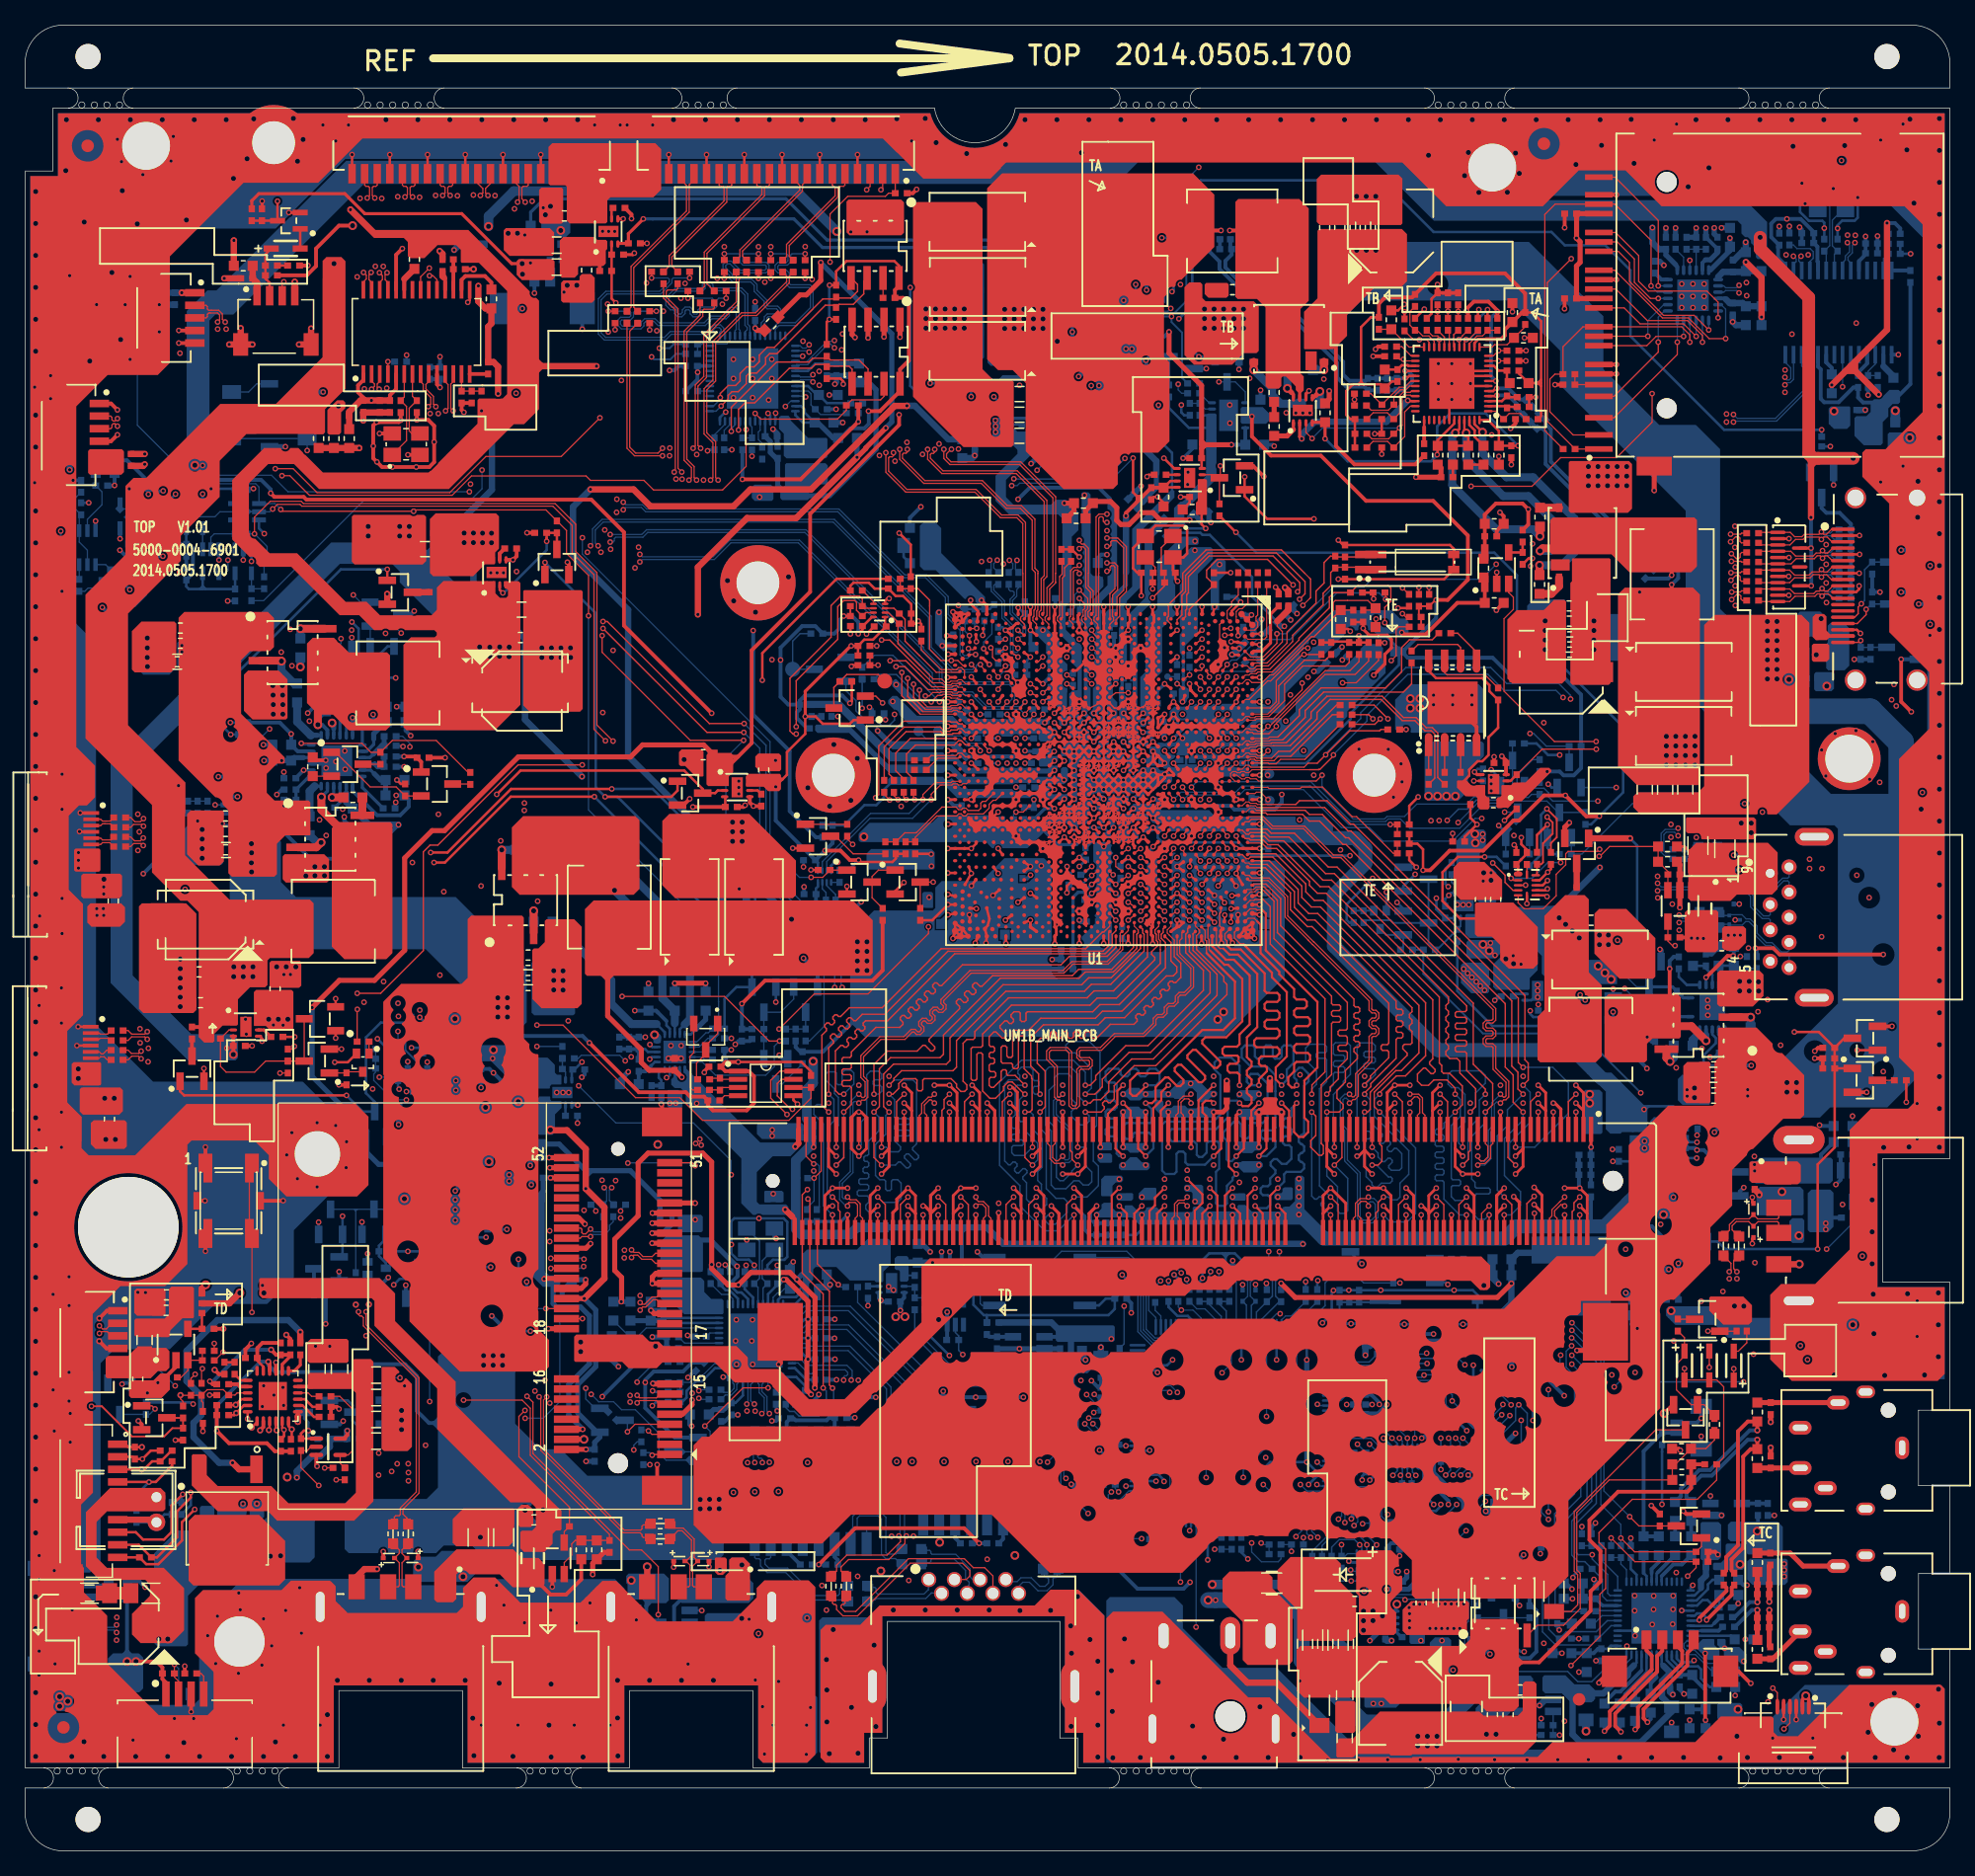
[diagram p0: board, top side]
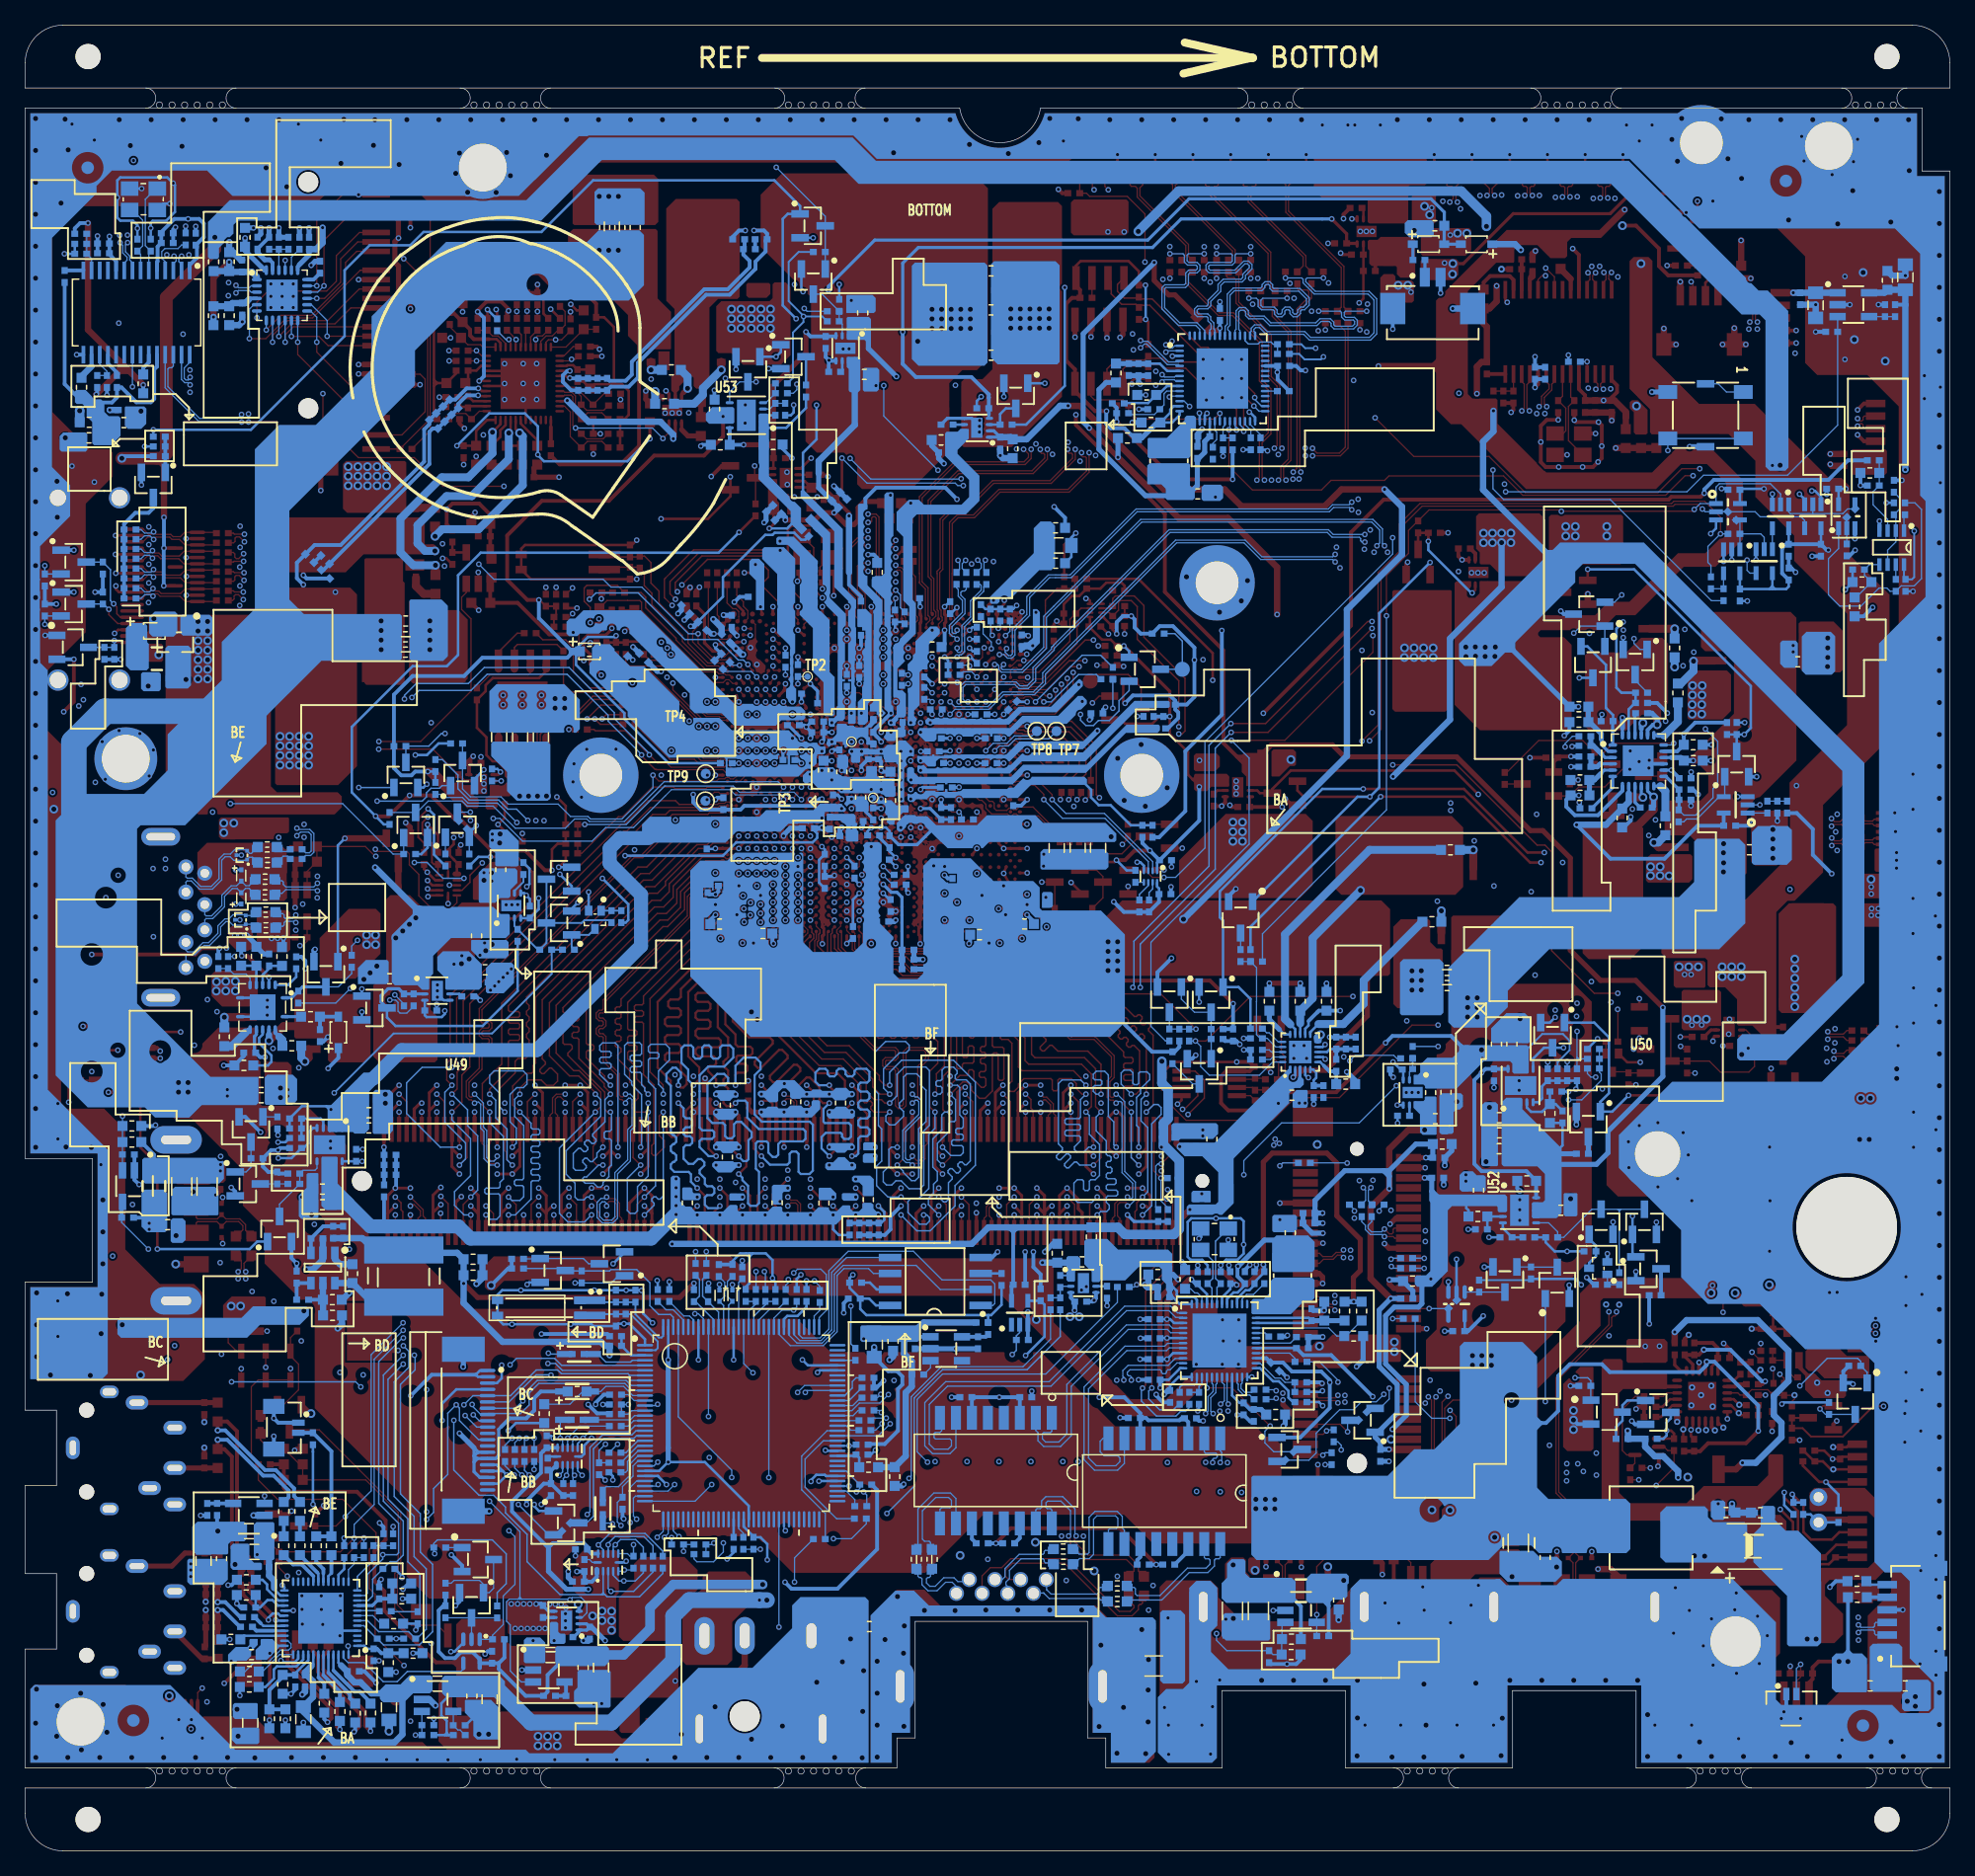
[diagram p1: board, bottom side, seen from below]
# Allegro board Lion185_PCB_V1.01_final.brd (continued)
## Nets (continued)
COMPA: U25.18(COMP)
CORE_PWROK: R387.2 U1.B7(PMC_CORE_PWROK)
CS_WAKE: R85.2 R326.1 R652.1 U1.L1(GPIO_S5_33) U27.4(A3)
CS_WAKE_EC: R652.2 U27.8(B3) U28.119(CRX0/GPC0)
DBG_UART3_RXD: Q103.2(S) U1.BC16(GPIO_S0_SC_61)
DBG_UART3_TXD: Q102.2(S) U1.BD14(GPIO_S0_SC_57)
DDI0_HPD: Q1.3(D) R12.1 U1.D27(DDI0_HPD)
DDI1_DATA: R13.2 R16.2 U1.P30(DDI1_DDCDATA)
DDI1_HPD: Q2.3(D) R11.1 U1.K30(DDI1_HPD)
DDR3_DRAM_PWROK: Q39.3(D) R439.2 R449.2 R450.2 U1.AD42(DRAM_VDD_S4_PWROK)
DDR3_VCCA_PWROK: Q47.3(D) R7.2 U1.AB42(DRAM_CORE_PWROK)
DDR3_VCCA_PWROK_3P3: Q46.1(G) R10.1 U40.4(Y)
DDR3L_DRAMRST#: CN3.30(RESET#) U1.P41(D\R\A\M\0\_\D\R\A\M\R\S\T\)
DDR3L_EVENT: R581.1 U28.68(ADC2/GPI2)
DDR3L_VREF: C1.1 R6.1 R9.2 U1.AF44(DRAM_VREF)
DDR_STBY: R384.2 R433.1 R434.1 R435.1 U43.17(S3)
DELAY_ALL_SYS_PWRGD: R8.2 R388.2 U37.4(Y) U39.1(A) U40.2(B)
DP_HPD: C617.2 CN18.1 Q2.1(G) R15.2 U10.11(HPD)
DRVH1: Q35.8 R429.1
DRVH2: Q34.8 R430.2
DRVL1: Q35.3 R432.1
DRVL2: Q34.3 R431.2
EC_BLEN: R749.1 U28.35(RTS1/GPE5)
EC_DELAY_ALL_SYS_PWRGD: R388.1 R713.1 U28.88(PS2DAT1/RTS0#/GPF3)
EC_MUTE#: R269.2 U24.1(A) U28.28(PWM2/GPA2)
EDID_SCL: R170.1 U10.29(DDC_SCL) U12.6(SCL)
EDID_SDA: R171.1 U10.30(DDC_SDA) U12.5(SDA)
EDP_AUXN: C523.2 C524.2 U1.AK2(DDI1_AUXN)
EDP_AUXN_CONN: C523.1 CN18.17 R615.2
EDP_AUXP: C525.2 C526.2 U1.AK3(DDI1_AUXP)
EDP_AUXP_CONN: C525.1 CN18.18 R162.2
EDP_BKLCTL: Q7.1(G) R178.1 U1.M30(DDI1_BKLTCTL)
EDP_BKLCTL_3P3: Q90.3(D) R152.1 R710.2 R751.2
EDP_BKLEN: Q16.1(G) R164.1 U1.J30(DDI1_BKLTEN)
EDP_BKLEN_3P3: Q17.3(D) R661.2 R748.1 U63.1(A)
EDP_BKLEN_OUT: R308.1 R639.2 R749.2 U63.4(Y)
EDP_TXN0: C138.1 C140.1 U1.AG1(DDI1_TXN_0)
EDP_TXN0_CONN: C138.2 CN18.5 R607.2
EDP_TXN1: C143.1 C144.1 U1.AF2(DDI1_TXN_1)
EDP_TXN1_CONN: C143.2 CN18.8 R609.2
EDP_TXN2: C155.2 U1.AD2(DDI1_TXN_2)
EDP_TXN2_CONN: C155.1 CN18.11 R611.2
EDP_TXN3: C520.2 U1.AC1(DDI1_TXN_3)
EDP_TXN3_CONN: C520.1 CN18.14 R613.2
EDP_TXP0: C141.1 C142.1 U1.AG3(DDI1_TXP_0)
EDP_TXP0_CONN: C141.2 CN18.6 R608.2
EDP_TXP1: C153.2 C154.2 U1.AF3(DDI1_TXP_1)
EDP_TXP1_CONN: C153.1 CN18.9 R610.2
EDP_TXP2: C157.2 U1.AD3(DDI1_TXP_2)
EDP_TXP2_CONN: C157.1 CN18.12 R612.2
EDP_TXP3: C522.2 U1.AC3(DDI1_TXP_3)
EDP_TXP3_CONN: C522.1 CN18.15 R614.2
EDP_VDDEN: R136.1 R137.1 U1.N30(DDI1_VDDEN) U8.3(ON)
EECS: R213.2 U17.30(EECS)
EEDI: R210.2 U17.32(EEDI)
EEDO: U17.31(LED3/EEDO)
EESK: U17.37(LED1/EESK)
EMC_THERM#: R132.1 U7.4(T\H\E\R\M\)
ENBLT: R639.1 U10.23(ENBLT)
ENLDO: Q98.2(S) R465.2 R491.1 R665.2 U42.13(EN0)
ENPVCC/I2C_ADDR: R184.1 U10.33(ENPVCC/I2C_ADDR)
ENSWREG: R214.2 R215.1 U17.33(ENSWREG)
ENTRIP1: Q42.2(S) R425.2 U42.1(ENTRIP1)
ENTRIP2: R426.1 U42.6(ENTRIP2)
EVDD10: C210.2 C211.1 R220.1 U17.21(EVDD10)
FAN_BACK: CN4.2 D3.P R134.2 R135.2
FAN_PWMIN: CN4.3 R320.1 U28.24(PWM0/GPA0)
FAN_VCC: C131.2 CN4.1 FB1.1
FLASH_TXE: Q100.1(G) R712.2
FMISO: U28.103(FMISO) U30.2(SO/SIO1)
FMOSI: U28.102(FMOSI) U30.5(SI/SIO0)
FSCE#: U28.101(FSCE#) U30.1(CS#)
FSCK: U28.105(FSCK) U30.6(SCLK)
GA20_EC: Q63.3(D) R81.2 R317.2 U28.126(GA20/GPB5)
GF_IMAX: R544.2 R551.1 U56.24(GF-IMAX)
GFX_PWM: U56.34(GPWM) U57.2(PWM)
GFX_PWRGD: R458.1 R531.2 U56.23(GPGOOD)
GL834L_3V3: C700.1 C701.1 C705.1 C710.2 FB4.1 FB20.2 R801.1 U95.1(DVDD) U95.19(DVDD33_1) U95.23(DVDD33)
GL850_AVDD: C573.2 C574.2 C575.2 C576.2 C577.2 C582.2 FB15.1 U77.1(AVDD) U77.5(AVDD_1) U77.10(AVDD_2)
GL850_AVDD1: C609.2 C610.2 C611.2 C612.2 C613.2 C614.2 FB18.1 U83.1(AVDD) U83.5(AVDD_1) U83.10(AVDD_2)
GL850G_RST#: C578.2 R692.2 R698.2 U77.13(RESET#)
GL850G_RST#_1: C606.2 R721.2 R735.2 U83.13(RESET#)
GL850G_X1: C579.2 U77.6(X1) X7.1
GL850G_X2: C580.2 U77.7(X2) X7.3
GPO: R226.2 U17.38(GPO/SMBALERT)
H_PROCHOT#: C294.1 Q62.2(S) R578.1 R580.2 U1.C24(P\R\O\C\H\O\T\) U29.4(Y)
H_RCIN#: D11.P R321.1 R653.2 U26.9(B2)
HD: R72.1 U3.7(NC(DQ3)) U75.7(RESET#/SIO3)
HDA_BITCLK: C257.2 R49.2 U23.6(BCLK)
HDA_RST#: R47.2 R272.1 R275.2 U23.11(RESETB)
HDA_SDATAIN0: C260.2 R262.2 U1.BG19(HDA_SDI0)
HDA_SDATAOUT: C261.2 R50.2 U23.5(SDATA-OUT)
HDA_SYNC: C259.2 R48.2 U23.10(SYNC)
HDMI_CTRLCLK: Q9.2(S) R202.2 U1.C28(DDI0_DDCCLK)
HDMI_CTRLDATA: Q10.2(S) R14.1 R203.2 U1.C26(DDI0_DDCDATA)
HDMI_HPD: C185.2 CN8.19 D6.3(D3) Q1.1(G) R199.2
HOME#: CN13.2 CN19.2 R437.2 U28.83(EGCS#/GPE2)
HP_OUT_L: C583.1 R241.1 R680.2 R711.1
HP_OUT_R: C584.1 R238.1 R699.2 R719.1
HSON: C208.2 U17.23(HSON)
HSOP: C209.2 U17.22(HSOP)
HUB2_USB_PN1: FIL12.4(GND) R381.1 U83.27(DM1)
HUB2_USB_PN2: U83.2(DM2) U95.2(DM)
HUB2_USB_PN3: CN22.2 U83.8(DM3)
HUB2_USB_PP1: FIL12.1(UNB) R568.1 U83.28(DP1)
HUB2_USB_PP2: U83.3(DP2) U95.3(DP)
HUB2_USB_PP3: CN22.3 U83.9(DP3)
HUB_USB_PN1: FIL14.4(GND) R564.1 U77.27(DM1)
HUB_USB_PN2: FIL13.2(DUMMY2) R382.1 U77.8(DM3)
HUB_USB_PN3: J3.2 U77.2(DM2)
HUB_USB_PN4: CN17.3 U77.11(DM4)
HUB_USB_PP1: FIL14.1(UNB) R566.1 U77.28(DP1)
HUB_USB_PP2: FIL13.3(DUMMY3) R575.1 U77.9(DP3)
HUB_USB_PP3: J3.3 U77.3(DP2)
HUB_USB_PP4: CN17.2 U77.12(DP4)
I2C_CLK0: R190.2 R299.2 U28.110(SMCLK0/GPB3)
I2C_CLK1: D27.N R296.2 U28.115(SMCLK1/GPC1)
I2C_CLK2: R302.2 R672.2 U28.117(SMCLK2/PECI/GPF6)
I2C_CLK2_LVDS: R187.2 R190.1 U10.25(CSCL/MSCL) U13.6(SCL)
I2C_CLK2_THEM: R672.1 U7.8(SMCLK)
I2C_DATA0: R191.2 R300.2 U28.111(SMDAT0/GPB4)
I2C_DATA1: D28.N R297.2 U28.116(SMDAT1/GPC2)
I2C_DATA2: R315.2 R673.2 U28.118(SMDAT2/PECIRQT#/GPF7)
I2C_DATA2_LVDS: R188.2 R191.1 U10.24(CSDA/MSDA) U13.5(SDA)
I2C_DATA2_THEM: R673.1 U7.7(SMDATA)
IINA0: J5.1 R342.1 R641.2 U25.22(ISEN1)
IINA1: J5.2 R342.2 R359.2 R643.2 U25.23(ISEN2)
IINA2: J5.3 R349.1 R359.1 U25.24(ISEN3)
IINA3: J5.4 R349.2 R355.2 U25.1(ISEN4)
IINA4: CN6.2 J5.7 R336.1 R355.1 U25.3(ISEN5)
IINA5: J5.8 R336.2 R350.2 U25.4(ISEN6)
IINA6: J5.9 R341.1 R350.1 R681.2 U25.5(ISEN7)
IINA7: J5.10 R341.2 R642.2 U25.6(ISEN8)
ISETA: R626.2 U25.8(ISET)
ISOLATEB: R217.1 R219.1 U17.26(ISOLATEB)
IT8928_VSS: R331.1 U28.104(DSR0#/GPG6/FIOO3)
KBC_FAN_SPEED: C130.2 Q5.3(OUT) R133.2 R323.1
L_OUT+: CN20.4(P4) R285.1
L_OUT-: CN20.3(P3) R286.1
LAN_CMT: R408.2 U61.11(CMT)
LAN_CMT1: R596.2 U62.11(CMT)
LAN_CT: R409.2 U61.14(CT3)
LAN_CT1: R577.2 U62.14(CT3)
LAN_N1: C271.1 C272.2 C338.2 C461.1 R408.1 R409.1 R577.1 R596.1
LAN_TX0N: FIL1.4(GND) R604.2 U61.9(TX-)
LAN_TX0P: FIL1.1(UNB) R603.2 U61.10(TX+)
LAN_TX1N: FIL2.1(UNB) R618.2 U61.15(RX-)
LAN_TX1P: FIL2.4(GND) R617.2 U61.16(RX+)
LAN_TX2N: FIL3.4(GND) R622.2 U62.9(TX-)
LAN_TX2P: FIL3.1(UNB) R620.2 U62.10(TX+)
LAN_TX3N: FIL4.1(UNB) R624.2 U62.15(RX-)
LAN_TX3P: FIL4.4(GND) R623.2 U62.16(RX+)
LAN_VDDEN_EC: R593.1 U28.29(PWM3/GPA3)
LAN_VDDEN_SOC: R208.1 U1.M2(GPIO_S5_36)
LANWAKEB: R216.1 U17.28(LANWAKEB)
LAO_CLKN: CN16.18 R615.1 U10.47(TCK0N)
LAO_CLKP: CN16.19 R162.1 U10.46(TCK0P)
LAO_DATAN0: CN16.6 R607.1 U10.54(TA0N)
LAO_DATAN1: CN16.9 R609.1 U10.52(TB0N)
LAO_DATAN2: CN16.12 R611.1 U10.49(TC0N)
LAO_DATAN3: CN16.15 R613.1 U10.44(TD0N)
LAO_DATAP0: CN16.7 R608.1 U10.53(TA0P)
LAO_DATAP1: CN16.10 R610.1 U10.51(TB0P)
LAO_DATAP2: CN16.13 R612.1 U10.48(TC0P)
LAO_DATAP3: CN16.16 R614.1 U10.43(TD0P)
LCD_VCC: C136.2 C137.1 C942.2 CN16.1 CN16.2 CN16.3 CN16.4 CN18.20 U8.7(VOUT2) U8.8(VOUT1)
LDO2-CAP: C246.2 U23.39(LDO2-CAP)
LED_ON: CN18.2 U28.34(PWM7/GPA7/RIG1)
LHF: CN13.4 R163.1
LL1: C369.2 L6.2 Q35.5 Q35.6 Q35.7 U42.20(LL1)
LL2: C370.1 L7.1 Q34.5 Q34.6 Q34.7 U42.11(LL2)
LPC_AD0: CN14.8 U1.BH16(ILB_LPC_AD_00) U28.10(LAD0/GPM0)
LPC_AD1: CN14.7 U1.BJ17(ILB_LPC_AD_11) U28.9(LAD1/GPM1)
LPC_AD2: CN14.6 U1.BJ13(ILB_LPC_AD_22) U28.8(LAD2/GPM2)
LPC_AD3: CN14.5 U1.BG14(ILB_LPC_AD_33) U28.7(LAD3/GPM3)
LPC_CLK_EC: CN14.10 R101.1 R102.1 U28.13(LPCCLK/GPM4)
LPC_CLKRUN#: R307.2 U1.BG16(I\L\B\_\L\P\C\_\C\L\K\R\U\N\)
LPC_FRAME#: CN14.9 U1.BG17(I\L\B\_\L\P\C\_\F\R\A\M\E\) U28.6(LFRAME#/GPM5)
LPC_SERIRQ: R648.1 U1.BG13(ILB_LPC_SERIRQ) U26.2(A1)
LPC_SERIRQ_EC: CN14.12 R648.2 U26.10(B1) U28.5(SERIRQ/GPM6)
LPCPD#: R656.2 U27.7(B4) U28.17(LPCPD#/GPE6)
M_A_A0: CN3.98(A0) U1.K45(DRAM0_MA_00)
M_A_A1: CN3.97(A1) U1.H47(DRAM0_MA_11)
M_A_A2: CN3.96(A2) U1.L41(DRAM0_MA_22)
M_A_A3: CN3.95(A3) U1.H44(DRAM0_MA_33)
M_A_A4: CN3.92(A4) U1.H50(DRAM0_MA_44)
M_A_A5: CN3.91(A5) U1.G53(DRAM0_MA_55)
M_A_A6: CN3.90(A6) U1.H49(DRAM0_MA_66)
M_A_A7: CN3.86(A7) U1.D50(DRAM0_MA_77)
M_A_A8: CN3.89(A8) U1.G52(DRAM0_MA_88)
M_A_A9: CN3.85(A9) U1.E52(DRAM0_MA_99)
M_A_A10: CN3.107(A10/AP) U1.K48(DRAM0_MA_1010)
M_A_A11: CN3.84(A11) U1.E51(DRAM0_MA_1111)
M_A_A12: CN3.83(A12/BC#) U1.F47(DRAM0_MA_1212)
M_A_A13: CN3.119(A13) U1.J51(DRAM0_MA_1313)
M_A_A14: CN3.80(A14) U1.B49(DRAM0_MA_1414)
M_A_A15: CN3.78(A15) U1.B50(DRAM0_MA_1515)
M_A_BS0: CN3.109(BA0) U1.K47(DRAM0_BS_00)
M_A_BS1: CN3.108(BA1) U1.K44(DRAM0_BS_11)
M_A_BS2: CN3.79(BA2) U1.D52(DRAM0_BS_22)
M_A_CAS#: CN3.115(CAS#) U1.M44(D\R\A\M\0\_\C\A\S\)
M_A_DM0: CN3.11(DM0) U1.G36(DRAM0_DM_00)
M_A_DM1: CN3.28(DM1) U1.B36(DRAM0_DM_11)
M_A_DM2: CN3.46(DM2) U1.F38(DRAM0_DM_22)
M_A_DM3: CN3.63(DM3) U1.B42(DRAM0_DM_33)
M_A_DM4: CN3.136(DM4) U1.P51(DRAM0_DM_44)
M_A_DM5: CN3.153(DM5) U1.V42(DRAM0_DM_55)
M_A_DM6: CN3.170(DM6) U1.Y50(DRAM0_DM_66)
M_A_DM7: CN3.187(DM7) U1.Y52(DRAM0_DM_77)
M_A_DQ0: CN3.5(DQ0) U1.M36(DRAM0_DQ_00)
M_A_DQ1: CN3.7(DQ1) U1.J36(DRAM0_DQ_11)
M_A_DQ2: CN3.15(DQ2) U1.P40(DRAM0_DQ_22)
M_A_DQ3: CN3.17(DQ3) U1.M40(DRAM0_DQ_33)
M_A_DQ4: CN3.4(DQ4) U1.P36(DRAM0_DQ_44)
M_A_DQ5: CN3.6(DQ5) U1.N36(DRAM0_DQ_55)
M_A_DQ6: CN3.16(DQ6) U1.K40(DRAM0_DQ_66)
M_A_DQ7: CN3.18(DQ7) U1.K42(DRAM0_DQ_77)
M_A_DQ8: CN3.21(DQ8) U1.B32(DRAM0_DQ_88)
M_A_DQ9: CN3.23(DQ9) U1.C32(DRAM0_DQ09_C32)
M_A_DQ10: CN3.33(DQ10) U1.C36(DRAM0_DQ_1010)
M_A_DQ11: CN3.35(DQ11) U1.A37(DRAM0_DQ_1111)
M_A_DQ12: CN3.22(DQ12) U1.C33(DRAM0_DQ_1212)
M_A_DQ13: CN3.24(DQ13) U1.A33(DRAM0_DQ_1313)
M_A_DQ14: CN3.34(DQ14) U1.C37(DRAM0_DQ_1414)
M_A_DQ15: CN3.36(DQ15) U1.B38(DRAM0_DQ_1515)
M_A_DQ16: CN3.39(DQ16) U1.F36(DRAM0_DQ_1616)
M_A_DQ17: CN3.41(DQ17) U1.G38(DRAM0_DQ_1717)
M_A_DQ18: CN3.51(DQ18) U1.F42(DRAM0_DQ_1818)
M_A_DQ19: CN3.53(DQ19) U1.J42(DRAM0_DQ_1919)
M_A_DQ20: CN3.40(DQ20) U1.G40(DRAM0_DQ_2020)
M_A_DQ21: CN3.42(DQ21) U1.C38(DRAM0_DQ_2121)
M_A_DQ22: CN3.50(DQ22) U1.G44(DRAM0_DQ_2222)
M_A_DQ23: CN3.52(DQ23) U1.D42(DRAM0_DQ_2323)
M_A_DQ24: CN3.57(DQ24) U1.A41(DRAM0_DQ_2424)
M_A_DQ25: CN3.59(DQ25) U1.C41(DRAM0_DQ_2525)
M_A_DQ26: CN3.67(DQ26) U1.A45(DRAM0_DQ_2626)
M_A_DQ27: CN3.69(DQ27) U1.B46(DRAM0_DQ_2727)
M_A_DQ28: CN3.56(DQ28) U1.C40(DRAM0_DQ_2828)
M_A_DQ29: CN3.58(DQ29) U1.B40(DRAM0_DQ_2929)
M_A_DQ30: CN3.68(DQ30) U1.B48(DRAM0_DQ_3030)
M_A_DQ31: CN3.70(DQ31) U1.B47(DRAM0_DQ_3131)
M_A_DQ32: CN3.129(DQ32) U1.K52(DRAM0_DQ_3232)
M_A_DQ33: CN3.131(DQ33) U1.K51(DRAM0_DQ_3333)
M_A_DQ34: CN3.141(DQ34) U1.T52(DRAM0_DQ_3434)
M_A_DQ35: CN3.143(DQ35) U1.T51(DRAM0_DQ_3535)
M_A_DQ36: CN3.130(DQ36) U1.L51(DRAM0_DQ_3636)
M_A_DQ37: CN3.132(DQ37) U1.L53(DRAM0_DQ_3737)
M_A_DQ38: CN3.140(DQ38) U1.R51(DRAM0_DQ_3838)
M_A_DQ39: CN3.142(DQ39) U1.R53(DRAM0_DQ_3939)
M_A_DQ40: CN3.147(DQ40) U1.T47(DRAM0_DQ_4040)
M_A_DQ41: CN3.149(DQ41) U1.T45(DRAM0_DQ_4141)
M_A_DQ42: CN3.157(DQ42) U1.Y40(DRAM0_DQ_4242)
M_A_DQ43: CN3.159(DQ43) U1.V41(DRAM0_DQ_4343)
M_A_DQ44: CN3.146(DQ44) U1.T48(DRAM0_DQ_4444)
M_A_DQ45: CN3.148(DQ45) U1.T50(DRAM0_DQ_4545)
M_A_DQ46: CN3.158(DQ46) U1.Y42(DRAM0_DQ_4646)
M_A_DQ47: CN3.160(DQ47) U1.AB40(DRAM0_DQ_4747)
M_A_DQ48: CN3.163(DQ48) U1.V45(DRAM0_DQ_4848)
M_A_DQ49: CN3.165(DQ49) U1.V47(DRAM0_DQ_4949)
M_A_DQ50: CN3.175(DQ50) U1.AD48(DRAM0_DQ_5050)
M_A_DQ51: CN3.177(DQ51) U1.AD50(DRAM0_DQ_5151)
M_A_DQ52: CN3.164(DQ52) U1.V48(DRAM0_DQ_5252)
M_A_DQ53: CN3.166(DQ53) U1.V50(DRAM0_DQ_5353)
M_A_DQ54: CN3.174(DQ54) U1.AB44(DRAM0_DQ_5454)
M_A_DQ55: CN3.176(DQ55) U1.Y45(DRAM0_DQ_5555)
M_A_DQ56: CN3.181(DQ56) U1.V52(DRAM0_DQ_5656)
M_A_DQ57: CN3.183(DQ57) U1.W51(DRAM0_DQ_5757)
M_A_DQ58: CN3.191(DQ58) U1.AC53(DRAM0_DQ_5858)
M_A_DQ59: CN3.193(DQ59) U1.AC51(DRAM0_DQ_5959)
M_A_DQ60: CN3.180(DQ60) U1.W53(DRAM0_DQ_6060)
M_A_DQ61: CN3.182(DQ61) U1.Y51(DRAM0_DQ_6161)
M_A_DQ62: CN3.192(DQ62) U1.AD52(DRAM0_DQ_6262)
M_A_DQ63: CN3.194(DQ63) U1.AD51(DRAM0_DQ_6363)
M_A_DQS0: CN3.12(DQS0) U1.J38(DRAM0_DQSP_00)
M_A_DQS1: CN3.29(DQS1) U1.C35(DRAM0_DQSP_11)
M_A_DQS2: CN3.47(DQS2) U1.D40(DRAM0_DQSP_22)
M_A_DQS3: CN3.64(DQS3) U1.B44(DRAM0_DQSP_33)
M_A_DQS4: CN3.137(DQS4) U1.N53(DRAM0_DQSP_44)
M_A_DQS5: CN3.154(DQS5) U1.T42(DRAM0_DQSP_55)
M_A_DQS6: CN3.171(DQS6) U1.Y47(DRAM0_DQSP_66)
M_A_DQS7: CN3.188(DQS7) U1.AB52(DRAM0_DQSP_77)
M_A_DQS#0: CN3.10(DQS#0) U1.K38(DRAM0_DQSN_00)
M_A_DQS#1: CN3.27(DQS#1) U1.B34(DRAM0_DQSN_11)
M_A_DQS#2: CN3.45(DQS#2) U1.F40(DRAM0_DQSN_22)
M_A_DQS#3: CN3.62(DQS#3) U1.C43(DRAM0_DQSN_33)
M_A_DQS#4: CN3.135(DQS#4) U1.M52(DRAM0_DQSN_44)
M_A_DQS#5: CN3.152(DQS#5) U1.T44(DRAM0_DQSN_55)
M_A_DQS#6: CN3.169(DQS#6) U1.Y48(DRAM0_DQSN_66)
M_A_DQS#7: CN3.186(DQS#7) U1.AA51(DRAM0_DQSN_77)
M_A_RAS#: CN3.110(RAS#) U1.M45(D\R\A\M\0\_\R\A\S\)
M_A_WE#: CN3.113(WE#) U1.H51(D\R\A\M\0\_\W\E\)
M_CKE0: CN3.73(CKE0) U1.C47(DRAM0_CKE_00)
M_CKE1: CN3.74(CKE1) U1.F44(DRAM0_CKE_22)
M_CLK_DDR0: CN3.101(CK0) U1.M50(DRAM0_CKP_0)
M_CLK_DDR1: CN3.102(CK1) U1.P50(DRAM0_CKP_2)
M_CLK_DDR#0: CN3.103(CK0#) U1.M48(DRAM0_CKN_0)
M_CLK_DDR#1: CN3.104(CK1#) U1.P48(DRAM0_CKN_2)
M_CS#0: CN3.114(S0#) U1.P44(D\R\A\M\0\_\C\S\_\0\)
M_CS#1: CN3.121(S1#) U1.P45(D\R\A\M\0\_\C\S\_\2\)
M_ODT0: CN3.116(ODT0) U1.T41(DRAM0_ODT_0)
M_ODT1: CN3.120(ODT1) U1.P42(DRAM0_ODT_2)
MDI0+: U17.1(MDIP0) U61.7(TD+)
MDI0-: U17.2(MDIN0) U61.8(TD-)
MDI1+: U17.4(MDIP1) U61.1(RD+)
MDI1-: U17.5(MDIN1) U61.2(RD-)
MDI2+: U17.7(MDIP2(NC)) U62.7(TD+)
MDI2-: U17.8(MDIN2(NC)) U62.8(TD-)
MDI3+: U17.10(MDIP3(NC)) U62.1(RD+)
MDI3-: U17.11(MDIN3(NC)) U62.2(RD-)
MDSI_DDCDATA: R31.1 R32.2 U1.A29(GPIO_S0_NC13)
MIC1L-VREFO: R246.2 U23.31(MIC1-VREFO-L)
MIC1R-VREFO: R244.2 U23.30(MIC1-VREFO-R)
MIC2-VREFO: R249.1 U23.29(MIC2-VREFO)
MIC_SEL_DET: J7.4 Q97.1(G) R256.1 R267.1 R322.2
MIC_SEL_SPDIF: Q97.3(D) R685.2 R717.2 U23.48(SPDIF-OUT/GPIO2)
MS_BS: CN30.M2(BS) U95.11(MS_BS)
MS_CLK: CN30.M8(SCLK) U95.6(SB0)
MS_D0: CN30.M4(DIO/D0) U95.9(SB4)
MS_D2: CN30.M5(DATA2) U95.8(SB3)
MS_D3: CN30.M7(DATA3) U95.7(SB1)
MS_INS: CN30.M6(INS) U95.5(MS_INS)
NFC_HRT: CN11.5 R20.2
OUT_CLK+: C181.2 CN8.10 R193.2 U14.10(D3+)
OUT_CLK-: C182.2 CN8.12 R192.2 U14.12(D3-)
OUT_D0+: C179.2 CN8.7 R195.2 U14.7(D2+)
OUT_D0-: C180.2 CN8.9 R194.2 U14.9(D2-)
OUT_D1+: C177.2 CN8.4 R197.2 U14.4(D1+)
OUT_D1-: C178.2 CN8.6 R196.2 U14.6(D1-)
OUT_D2+: C175.2 CN8.1 R200.2 U14.1(DO+)
OUT_D2-: C176.2 CN8.3 R198.2 U14.3(DO-)
OVPA: R351.2 R354.1 R619.2 R883.2 U25.7(OVP)
PCIE_LAN_WAKE#: R63.1 R216.2 U1.F26(P\M\C\_\W\A\K\E\_\P\C\I\E\_\0\)
PCIE_RXN0_LAN: C208.1 U1.AT13(PCIE_RXN_0)
PCIE_RXN1_WLAN: CN12.23(PER_N0) U1.AT9(PCIE_RXN_1)
PCIE_RXP0_LAN: C209.1 U1.AT14(PCIE_RXP_0)
PCIE_RXP1_WLAN: CN12.25(PER_P0) U1.AT10(PCIE_RXP_1)
PCIE_TXN0_LAN: C5.1 U17.18(HSIN)
PCIE_TXN1_WLAN: C3.1 CN12.31(PET_N0)
PCIE_TXP0_LAN: C4.1 U17.17(HSIP)
PCIE_TXP1_WLAN: C6.1 CN12.33(PET_P0)
PCIE_WIFI_WAKE#: R80.2 R636.1 U1.B16(GPIO_S5_1)
PD#: U23.47(PDB) U24.4(Y)
PERSTB: R218.1 U17.25(PERSTB)
PM_BATLOW#: R311.1 R335.1 R638.1 U1.K26(P\M\C\_\B\A\T\L\O\W\)
PM_RSMRST#: Q69.2(S) R67.1 R332.1 R714.2 U1.B10(P\M\C\_\R\S\M\R\S\T\)
PM_SLP_S0IX#: Q77.1(G) R329.1 R383.2 R385.2 R433.2 R502.2 U6.7(B4) U37.1(A) U38.2(B)
PM_SLP_S3#: Q48.1(G) R435.2 R497.2 R501.2 U6.9(B2) U28.70(ADC4/GPI4)
PM_SLP_S4#: Q38.1(G) R440.1 U6.8(B3) U28.69(ADC3/GPI3)
PMC_ACPRESENT: Q3.3(D) R83.2 U1.D20(PMC_ACPRESENT)
PMC_PLTRST: U1.F20(P\M\C\_\P\L\T\R\S\T\) U6.2(A1)
PMC_PWRBTN#: R654.1 R709.2 U1.J26(P\M\C\_\P\W\R\B\T\N\) U26.4(A3)
PMC_PWRBTN#_EC: R654.2 U26.8(B3) U28.18(RI1#/GPD0)
PMC_RSTBTN: R56.1 R57.1 R58.2 R653.1 U1.BG9(P\M\C\_\R\S\T\B\T\N\) U26.3(A2)
PMC_SLP_S0IX: U1.F18(P\M\C\_\S\L\P\_\S\0\I\X\) U6.5(A4)
PMC_SLP_S3: U1.D22(P\M\C\_\S\L\P\_\S\3\) U6.3(A2)
PMC_SLP_S4: U1.F22(P\M\C\_\S\L\P\_\S\4\) U6.4(A3)
PMC_SUS_STAT#: R656.1 U1.G18(P\M\C\_\S\U\S\_\S\T\A\T\) U27.5(A4)
PMC_SUSPWRDNACK: Q88.1(G) R76.1 R317.1 U1.D26(PMC_SUSPWRDNACK)
POWSW#: CN5.6 CN34.1 D33.N D34.N R903.1 SW4.3 SW4.4
PROCHOT#_EC: R340.2 R347.2 U28.76(TACH2/HDIO2/GPJ0) U29.2(A)
PS_LATCH#: D33.P Q78.1(G) R103.2 R898.1 R901.1
PSELF: R696.2 R697.1 U77.17(PSELF)
PSELF_1: R739.2 R740.1 U83.17(PSELF)
PSMS: R800.1 U95.20(GPIO0)
PWM IN: CN18.3 R165.1 R176.2 R182.1 R356.2 R751.1 U25.21(PWM)
PWR_LED_WHITE: CN5.4 CN34.3 U28.56(KSO16/SMOSI/GPC3)
PWR_SW: C704.1 C708.1 C709.1 CN30.M9(VCC) CN30.S4(VDD) U95.24(PMOS)
PWRONLATCHG: C585.1 C600.2 Q65.4(G) R103.1 R899.1 R901.2
R_OUT+: CN20.1(P1) R284.1
R_OUT-: CN20.2(P2) R283.1
REGOUT: L4.1 U17.36(REGOUT)
RESERVED_F1: U1.F1(RESERVED_F1)
REXT: R161.2 U10.26(REXT)
RLV_AMP: R159.2 U10.27(RLV_AMP)
RLV_CFG: R186.1 R189.2 U10.22(RLV_CFG)
RLV_LNK: R185.1 U10.21(RLV_LNK/GPIO0) U13.7(WP/WC#)
RSET: R209.2 U17.46(RSET)
RSMRST#_EC: Q69.3(D) R332.2 U28.19(L80HLAT/BAO/GPE0)
RSTZ: C707.1 R801.2 R802.2 U95.22(RSTZ)
RTA: R958.2 U25.9(RT)
RUNTIME_SCI#_EC: D10.P R319.1 R655.2 U26.7(B4)
S0IX#_DISCHARGE: Q76.1(G) Q77.3(D) Q80.1(G) R504.2
S3_DISCHARGE: C539.1 Q36.1(G) Q48.3(D) Q51.1(G) Q53.1(G) Q54.1(G) Q74.1(G) Q75.1(G) Q81.1(G) Q82.1(G) Q83.1(G) Q84.1(G) Q86.1(G) R562.1 R574.2
S4_DISCHARGE: Q38.3(D) Q39.1(G) Q61.1(G) R448.1 R451.2
SA0_DIM0: CN3.197(SA0) R121.1 R122.1
SA1_DIM0: CN3.201(SA1) R123.1
SATA_LED#: R36.1 U1.AY12(S\A\T\A\_\L\E\D\)
SATA_RXN0: R160.1 U1.AV16(SATA_RXN_0)
SATA_RXN1: C159.1 U1.BA16(SATA_RXN_1)
SATA_RXP0: R168.1 U1.AU16(SATA_RXP_0)
SATA_RXP1: C163.1 U1.AY16(SATA_RXP_1)
SATA_TXN0: C165.1 U1.BG7(SATA_TXN_0)
SATA_TXN1: C274.1 U1.BF10(SATA_TXN_1)
SATA_TXP0: C156.1 U1.BF6(SATA_TXP_0)
SATA_TXP1: C273.1 U1.BD10(SATA_TXP1)
SCL_CONN: CN8.15 Q9.3(D) R204.2
SD_CDZ: CN30.CD R803.2 U95.21(SD_CDZ)
SD_CLK: CN30.S5(CLK) U95.14(SD_CLK)
SD_CMD: CN30.S2(CMD) U95.15(SD_CMD)
SD_D0: CN30.S7(DAT0) U95.13(SB9)
SD_D1: CN30.S8(DAT1) U95.12(SB8)
SD_D2: CN30.S9(DAT2) U95.17(SB13)
SD_D3: CN30.S1(CD/DAT3) R803.1 U95.16(SB12)
SD_WP/MS_D1: CN30.M3(DATA1) CN30.WP1 R804.1 U95.10(SB5)
SDA_CONN: CN8.16 Q10.3(D) R205.2
SECURITY_FLASH: R52.1 R54.2 U1.BC30(LPE_I2S2_DATAOUT)
SEL: CN11.6 R18.2
SELA: R352.2 R353.2 U25.17(SEL)
SKIPSEL: R456.2 R486.2 U42.14(SKIPSEL)
SLEWA: R543.2 R550.1 U56.22(SLEWA)
SMB_CLK_S2: CN3.202(SCL) R280.2 R631.2 R632.2 U65.6(B2)
SMB_DATA_S2: CN3.200(SDA) R281.2 R630.2 R633.2 U65.7(B1)
SMBCLK: R632.1 U17.14(SMBCLK(NC))
SMBDATA: R223.1 R633.1 U17.15(SMBDATA(NC))
SMC_ONOFF#: D34.P R701.2 R704.2
SMC_SHUTDOWN#: Q89.1(G) R301.2 R900.2 U71.2(B)
SOC_EXTSMI#: R647.1 U1.C15(GPIO_S5_7) U27.2(A1)
SOC_EXTSMI#_EC: D9.P R318.1 R647.2 U27.10(B1)
SOC_FLASHEN: R79.1 R674.1 U5.3(ON)
SOC_ICS5_CLK_TOUCH: R684.2 U74.6(B2)
SOC_ICS5_DATA_TOUCH: R683.2 U74.7(B1)
SOC_RUNTIME_SCI: R655.1 U1.BA12(SATA_GP0) U26.5(A4)
SOC_SMB_CLK: R108.2 U1.BH10(PCU_SMB_CLK) U65.3(A2)
SOC_SMB_DATA: R106.2 U1.BG12(PCU_SMB_DATA) U65.2(A1)
SOC_WAKE_SCI: R314.1 R651.1 U1.B18(GPIO_S5_0) U27.3(A2)
SPI_CLK: R75.1 U3.6(CLK) U75.6(SCLK)
SPI_CS0#: R70.2 U3.1(CS#) U75.1(CS#)
SPI_SI: R74.2 U3.5(DI(DQ0)) U75.5(SI/SIO0)
SPI_SO: R73.1 U3.2(DO(DQ1)) U75.2(SO/SIO1)
SPK_L+: R285.2 U23.42(SPK-OUT-L+)
SPK_L-: R286.2 U23.43(SPK-OUT-L-)
SPK_R+: R284.2 U23.45(SPK-OUT-R+)
SPK_R-: R283.2 U23.44(SPK-OUT-R-)
SPKR: R600.2 U1.BH12(ILB_8254_SPKR)
SVID_ALERT#: R517.2 R523.1 R586.2
SVID_CLK: R518.2 R522.1 R588.2
SVID_DATA: R516.2 R525.1 R587.2
TBCLK: R310.2 U28.85(PS2CLK0/TMB0/GPF0/CEC)
TBDATA: R316.2 U28.86(PS2DAT0/TMB1/GPF1)
TEMP_ALERT#: R130.2 R337.1 U7.6(A\L\E\R\T\)
TLV3492_REF: R727.2 R728.1 U79.2(-INA) U79.6(-INB)
TMDS_CLKN: C182.1 U1.AP2(DDI0_TXN_3)
TMDS_CLKP: C181.1 U1.AP3(DDI0_TXP_3)
TMDS_DATAN0: C180.1 U1.AR1(DDI0_TXN_2)
TMDS_DATAN1: C178.1 U1.AT3(DDI0_TXN_1)
TMDS_DATAN2: C176.1 U1.AV2(DDI0_TXN_0)
TMDS_DATAP0: C179.1 U1.AR3(DDI0_TXP_2)
TMDS_DATAP1: C177.1 U1.AT2(DDI0_TXP_1)
TMDS_DATAP2: C175.1 U1.AV3(DDI0_TXP_0)
TONSEL: R427.2 R428.2 U42.4(TONSEL)
TOUCH_INT: R585.1 U1.AU32(SIO_PWM_00)
TOUCHEN_SOC: R149.1 U1.N3(GPIO_S5_37)
TP_EN_EC: R629.2 U28.57(KSO17/SMISO/GPC5)
TP_VCC: C301.1 C303.2 CN17.5 CN17.6 FB12.1 U9.1(VOUT)
TXN0_LVDS: C140.2 U10.5(DRX0N)
TXN1_LVDS: C144.2 U10.8(DRX1N)
TXP0_LVDS: C142.2 U10.4(DRX0P)
TXP1_LVDS: C154.1 U10.7(DRX1P)
USB3_PWRON: R366.2 U28.31(PWM5/GPA5) U31.4(EN)
USB3_RX0_N: FIL6.4(GND) R362.1 U1.E3(USB3_RXN0)
USB3_RX0_P: FIL6.1(UNB) R364.1 U1.D4(USB3_RXP0)
USB3_TX0_N: C314.2 U1.K7(USB3_TXN0)
USB3_TX0_P: C315.2 U1.K6(USB3_TXP0)
USB_BTN: CN12.36(USB_D-) R718.1
USB_BTP: CN12.38(USB_D+) R746.1
USB_NFCN: CN11.3 R745.1
USB_NFCP: CN11.2 R747.1
USB_OC0#: C313.1 R89.1 R363.1 R365.2 U1.C20(U\S\B\_\O\C\_\0\0\) U31.3(OCB)
USB_OC1#: R90.1 U1.B20(U\S\B\_\O\C\_\1\1\)
USB_OC1#_HUB: C318.1 R369.1 R370.2 U55.3(OCB) U77.21(OVCUR1#)
USB_OC1#_HUB 2: C330.1 R372.1 R374.2 U41.3(OCB) U83.21(OVCUR1#)
USB_OC2#_HUB: C325.1 R373.1 R379.2 U59.3(OCB) U77.19(OVCUR2#)
USB_P1ON: R371.2 R592.2 U55.4(EN)
USB_P2ON: R380.2 R606.2 U59.4(EN)
USB_P3ON: R375.2 R591.2 U41.4(EN)
USB_PLL_MON: R93.2 TP2.1 U1.M13(USB_PLL_MON)
USB_PN0: FIL5.1(UNB) R360.1 U1.K16(USB_DN0)
USB_PN1: R718.2 R745.2 U1.G14(USB_DN1)
USB_PN2: U1.J12(USB_DN2) U77.25(DM0)
USB_PN3: U1.H10(USB_DN3) U83.25(DM0)
USB_PP0: FIL5.4(GND) R361.1 U1.M16(USB_DP0)
USB_PP1: R746.2 R747.2 U1.J14(USB_DP1)
USB_PP2: U1.K12(USB_DP2) U77.26(DP0)
USB_PP3: U1.K10(USB_DP3) U83.26(DP0)
V_DAC: C494.2 C495.2 C496.2 C527.2 U61.3(CT1) U61.6(CT2) U62.3(CT1) U62.6(CT2)
VCLK: C377.1 C378.1 U42.18(VCLK)
VCORE_CIMON: C448.1 R505.1 U56.3(CIMON)
VCORE_COMP: C449.1 R507.2 U56.10(CCOMP)
VCORE_CSP1: C462.2 C463.1 C464.1 R511.2 R512.2 R515.2 U56.4(CCSP1)
VCORE_GIMON: C475.1 R534.1 U56.30(GIMON)
VCORE_GSNS: R509.1 U1.N28(CORE_VSS_SENSE_N28) U56.12(CGFB)
VCORE_OCP_I: R505.2 R506.1 U56.2(COCP-I)
VCORE_PWRGD: R493.1 R537.1 U56.17(CPGOOD)
VCORE_SKIP#: R548.2 R555.1 U56.35(CSKIP#)
VCORE_THERM: R545.2 R552.2 U56.1(CTHERM)
VCORE_VRON: C596.2 R450.1 R497.1 U56.16(VR_ON)
VCORE_VSNS: R508.1 U1.P28(CORE_VCC_SENSE_P28) U56.11(CVFB)
VFB1: R421.1 R423.2 U42.2(VFB1)
VFB2: R422.1 R424.1 U42.5(VFB2)
VGFX_COMP: C474.2 R533.1 U56.27(GCOMP)
VGFX_CSP: C476.1 C477.2 C478.1 R532.2 R535.2 R536.2 U56.29(GCSP)
VGFX_GSNS: R529.2 U56.25(GGFB)
VGFX_OCP_I: R534.2 R538.1 U56.31(GOCP-I)
VGFX_SKIP#: R547.2 R554.1 U56.33(GSKIP#_1) U57.3(SKIP#)
VGFX_THERM: R546.2 R553.2 U56.32(GTHERM)
VGFX_VSNS: R530.1 U1.BB8(UNCORE_VNN_SENSE) U56.26(GVFB)
VR_ALW_EN: Q85.1(G) R665.1 U71.4(Y)
VR_HOT#: Q62.3(D) R528.2 R578.2 U56.21(VR_HOT#)
VREF: C442.2 R486.1 U42.3(VREF)
VREF_CA0: C106.2 C107.2 CN3.126(VREF_CA) R125.1 R126.2
VREF_DQ0: C103.2 C104.2 CN3.1(VREF_DQ) R120.1 R124.2
VREFA: C992.2 R353.1 R616.2 U25.14(VREF)
VREG3: C368.2 C540.1 R427.1 U42.8(VREG3) U71.5(VCC)
VREG5: C375.1 C380.1 D24.1(X1) R428.1 R456.1 R662.2 U42.17(VREG5)
VSM_VTT_PWRGD: R439.1 R510.2 U43.20(PGOOD)
VSPI_KBC: C293.1 R334.1 R339.1 R345.2 R346.2 R658.1 U30.8(VCC)
VTT_PWRGD: R716.2 U79.1(OUTA)
WAKE_SCI_EC: R324.1 R651.2 U27.9(B2)
WIFI_3P3_RST#: Q67.3(D) R637.2 U58.1(A)
WIFI_PCIE_RST: Q68.1(G) R62.1 U1.J20(GPIO_S514_J20)
WIFI_PERST#: CN12.22(PERST#) R589.1 U58.4(Y)
WIFI_PWRON: R599.2 U28.112(RING#/PWRFAIL#/CK32KOUT/LPCRST#)
WIFI_VDDEN_SOC: R598.1 U1.P3(GPIO_S5_41)
WIRELESS_ON: R279.2 U28.33(GINT/CTS0#/GPD5)
WP2: CN30.WP2 R804.2 R805.2
WP#: R71.1 U3.3(WP#(DQ2)) U75.3(WP#/SIO2)
WRST#: C288.2 R333.1 SW1.3 SW1.4 SW2.1 SW2.3 U28.14(WRST#)
X1: C616.2 U83.6(X1) X8.1
X2: C615.2 U83.7(X2) X8.3
XTAL1: C187.1 U17.43(CKXTAL1) X4.1
XTAL2: C186.1 U17.44(CKXTAL2) X4.3
XTAL25M_IN: C8.2 R59.1 U1.AH12(ICLK_OSCIN) X1.1
XTAL25M_OUT: C7.2 R59.2 U1.AH10(ICLK_OSCOUT) X1.3
N320321985: CN12.7(CLKREQ#) Q66.3(D) R635.2
N320322150: CN12.20(W_DISABLE#) R279.1
N320322222: CN12.30(SMB_CLK) R280.1
N320322224: CN12.32(SMB_DATA) R281.1
N322237366: CN12.51(RSVD12) R282.2
N332287606: Q64.3(D) R634.2 U17.16(CLKREQB)
N332918772: CN12.5(RSVD2) R278.2
N333289105: Q40.8 R463.2
N333289487: C404.2 D26.N R459.2
N333289642: Q40.3 R467.2
N333289792: Q49.3(D) R457.2 R733.2 U47.1(EN_PSV)
N333289805: C404.1 L9.1 Q40.5 Q40.6 Q40.7 R460.2 U47.12(LL)
N333289822: R467.1 U47.9(DRVL)
N333289926: R468.1 R470.2 U47.5(VFB)
N333289950: R460.1 U47.2(TON)
N333290075: R463.1 U47.13(DRVH)
N333290111: R464.1 U47.11(TRIP)
N333290147: R462.1 R466.2 U47.6(PGOOD)
N339398220: R312.1 U28.22(LPCRST#/GPD2)
N339398632: D10.N R319.2 U28.23(ECSCI#/GPD3)
N339398739: D11.N R321.2 U28.4(KBRST#/GPB6)
N339399039: R337.2 U28.67(ADC1/GPI1)
N339399233: D7.N R304.1 R700.1 U28.11(VCC)
N339399553: C291.1 R344.1 U28.2(CK32KE/GPJ7) X5.2 X6.4
N339399628: R292.1 U28.122(VSS6)
N339399677: R325.1 U28.48(TACH1A/TMA1/GPD7)
N339399812: R346.1 U30.3(WP#/ACC)
N339399833: R345.1 U30.7(HOLD#)
N339399994: R323.2 U28.47(TACH0A/GPD6)
N339400152: R324.2 U28.16(PWUREQ#/GPC7/BBO)
N339400173: D9.N R318.2 U28.15(ECSMI#/GPD4)
N339400590: R301.1 U28.82(EGAD/GPE1)
N339579908: Q8.1(G) R201.2 R501.1 R502.1
N342323491: C314.1 FIL7.4(GND) R367.1
N342323527: FIL6.2(DUMMY2) J2.6(STDA_SSRX+) R364.2 U32.2(D-)
N342323548: FIL7.2(DUMMY2) J2.9(STDA_SSTX+) R368.2 U33.2(D-)
N342323565: D12.N FIL5.2(DUMMY2) J2.2(D_MINUS) R360.2
N342323571: FIL6.3(DUMMY3) J2.5(STDA_SSRX-) R362.2 U32.1(D+)
N342323607: C315.1 FIL7.1(UNB) R368.1
N342323609: D13.N FIL5.3(DUMMY3) J2.3(D_PLUS) R361.2
N342323907: FIL7.3(DUMMY3) J2.8(STDA_SSTX-) R367.2 U33.1(D+)
N344053358: R307.1 U28.93(CLKRUN#/GPH0/ID0)
N347061519: C289.1 R343.2 R344.2 U28.128(CK32K/GPJ6) X5.1 X6.1
N350298939: R441.1 U43.14(DRVH)
N350298979: R443.1 U43.11(DRVL)
N350299117: R436.1 U43.19(MODE)
N350299126: C393.1 R444.1 U43.5(VTTREF)
N350299527: R442.2 U43.15(VBST)
N350299529: C394.2 R445.1 R446.2 R447.2 U43.8(REFIN)
N350299649: R440.2 U43.16(S5)
N350299667: C386.2 R442.1
N350299694: C386.1 L8.1 Q37.5 Q37.6 Q37.7 U43.13(SW)
N350299721: C392.2 R445.2 U43.6(VREF)
N350299729: R438.2 U43.18(TRIP)
N350299756: Q36.3(D) R434.2
N350945194: Q8.3(D) R192.1 R193.1 R194.1 R195.1 R196.1 R197.1 R198.1 R200.1
N369066236: R701.1 R702.1 U28.107(DTR1#/SBUSY/GPG1/ID7/FDIO2)
N369071729: R322.1 U28.98(HMISO/GPH5/ID5)
N370323697: R1.2 U1.AH42(ICLK_DRAM_TERMN)
N370323746: R2.2 U1.AF42(ICLK_DRAM_TERMN_AF42)
N370323875: R4.1 U1.AD44(DRAM_RCOMP_00)
N370323891: R3.1 U1.AF45(DRAM_RCOMP_11)
N370323945: R5.1 U1.AD45(DRAM_RCOMP_22)
N370344518: R23.1 U1.AH3(VSS_AH3)
N370344521: R25.1 U1.AH2(VSS_AH2)
N370344943: R26.1 U1.AW1(VGA_IREF)
N370350025: R19.2 U1.AK12(DDI0_RCOMP_P)
N370350028: R19.1 U1.AK13(D\D\I\0\_\R\C\O\M\P\)
N370350254: R22.2 U1.AM3(VSS_AM3)
N370350257: R24.2 U1.AM2(VSS_AM2)
N370394982: R33.2 U1.BB10(ICLK_SATA_TERMP)
N370394985: R35.2 U1.BC10(ICLK_SATA_TERMN)
N370395195: R37.2 U1.AT18(SATA_RCOMP_N_AT18)
N370395197: R37.1 U1.AU18(SATA_RCOMP_P_AU18)
N370395763: R45.1 U1.AY18(MMC1_RCOMP)
N370395851: R55.1 U1.BF26(SD3_RCOMP)
N370396853: R46.2 U1.BF20(HDA_LPE_RCOMP)
N370397174: R47.1 U1.BG22(H\D\A\_\R\S\T\)
N370397581: Q13.3(D) R270.2 R272.2 U24.2(B)
N370397628: Q14.1(G) R275.1
N370397693: Q13.1(G) Q14.3(D) R271.2
N370398430: R48.1 U1.BH20(HDA_SYNC)
N370398495: R49.1 U1.BJ21(HDA_CLK)
N370398555: R50.1 U1.BG20(HDA_SDO)
N370398936: R44.2 U1.AP14(PCIE_RCOMP_P_AP14_AP14)
N370398938: R44.1 U1.AP13(PCIE_RCOMP_N_AP13_AP13)
N370399144: C4.2 U1.AY7(PCIE_TXP_0)
N370399202: C6.2 U1.AV6(PCIE_TXP_1)
N370399343: C5.2 U1.AY6(PCIE_TXN_0)
N370399448: C3.2 U1.AV4(PCIE_TXN_1)
N370401528: R38.1 U1.BB7(VSS_BB7)
N370401530: R40.1 U1.BB5(VSS_BB5)
N370482122: R43.1 U1.BE3(P\C\I\E\_\C\L\K\R\E\Q\_\3\)
N370482125: R42.1 U1.BG5(P\C\I\E\_\C\L\K\R\E\Q\_\2\)
N370489010: D3.N Q5.1(IN)
N370489012: C132.1 R135.1
N370495932: R86.1 U1.M12(USB3_REXT0)
N370496363: R91.1 R94.2 U1.BC12(GPIO_S0_SC_56)
N370535741: R87.1 U1.D10(ICLK_USB_TERMN_D10)
N370535744: R88.1 U1.F10(ICLK_USB_TERMN)
N370535989: R92.2 U1.C7(USB_RCOMPI) U1.D6(USB_RCOMPO)
N370536167: R95.2 U1.B4(USB_HSIC0_DATA)
N370536170: R96.2 U1.B5(USB_HSIC0_STROBE)
N370536206: R97.2 U1.E2(USB_HSIC1_DATA)
N370536208: R98.2 U1.D2(USB_HSIC1_STROBE)
N370536412: R99.2 U1.A7(USB_HSIC_RCOMP)
N370536484: R100.1 U1.BF18(LPC_RCOMP)
N370539794: TP3.1 U1.AF30(TP_CORE_V1P05_S4)
N370539817: TP4.1 U1.AA22(TP2_CORE_VCC_S0IX)
N370571694: R118.2 U1.AC32(CORE_V1P0_S3_AC32) U1.Y32(CORE_V1P0_S3_Y32)
N370574162: C56.1 R111.2 R112.2 U1.AM32(HDA_LPE_V1P5V1P8_S3_AM32)
N370574202: C57.1 R649.1 R650.1 U1.AM27(LPC_V1P8V3P3_S3_AM27)
N370574265: C73.1 D31.N R731.2 U1.N20(USB_V1P8_G3_N20) U1.U24(UNCORE_V1P8_G3_U24) U1.U25(PMU_V1P8_G3_U25) U1.V25(PCU_V1P8_G3_V25)
N370574283: C64.2 R114.1 R115.2 U1.AD16(VSS_AD16) U1.AD18(VSS_AD18)
N370574303: C74.1 R293.2 R671.2 U1.V18(USB_HSIC_V1P2_G3_V18)
N370668728: R329.2 U28.124(TMRI1/GPC6)
N370706058: C290.1 U28.12(VCORE)
N370732942: R101.2 U1.BG15(ILB_LPC_CLK_00)
N370732965: R102.2 U1.BH14(ILB_LPC_CLK_11)
N370733760: R298.2 U26.12(OE)
N370758959: R313.2 U27.12(OE)
N370761700: Q4.1(B) Q4.3(C) R127.2
N370761781: C129.2 R128.1 U7.3(DN)
N370761791: Q4.2(E) R128.2
N370761793: C129.1 R127.1 U7.2(DP)
N370766504: R109.2 U1.BG11(P\C\U\_\S\M\B\_\A\L\E\R\T\)
N370820727: R520.1 U56.47(CDH1)
N370827950: C468.1 L14.1 Q41.7(S1/D2) R511.1 R524.2 U56.45(CSW1)
N370828403: R521.2 U56.46(CBST1)
N370828574: C468.2 R521.1
N370828861: Q41.1(GATE1) R520.2
N370828884: Q41.6(G2) R526.2
N370829798: R526.1 U56.44(CDL1)
N370832810: C473.2 R524.1
N370840080: R512.1 R519.2
N370843819: R527.2 U56.37(VBAT)
N370879306: R522.2 U56.18(VCLK)
N370879343: R523.2 U56.19(ALERT#)
N370879346: R525.2 U56.20(VDIO)
N370880811: C465.2 R513.2 U56.15(V3R3)
N370904548: Q37.3 R443.2
N370904936: Q37.8 R441.2
N370908739: C428.2 U51.6(CT)
N370911201: C440.2 U54.6(CT)
N370914127: Q74.3(D) R474.2 R476.1 U49.6(ENB)
N370985600: Q100.3(D) R54.1
N371005282: TP1.1 U1.B30(GPIO_S0_NC12)
N371025596: R262.1 U23.8(SDA TA-IN)
N371025625: C254.1 C255.2 FB10.2 U23.1(DVDD)
N371025642: C237.1 R245.1
N371025675: C236.2 U23.20(MIC1-R(PORT-B-R))
N371025681: C253.2 U23.7(LDO3-CAP)
N371025772: C237.2 U23.19(MIC1-L(PORT-B-L))
N371025837: R251.2 R256.2 U23.13(SENSE A)
N371025969: C242.2 R243.1 U22.4(SS)
N371026280: C225.2 U20.6(CT)
N371026303: R252.1 U23.15(JDREF)
N371026305: C245.1 U23.37(CBP)
N371026324: C231.1 U23.34(CPVEE)
N371026326: C245.2 U23.35(CBN)
N371026438: C227.2 R236.1 U19.4(SS)
N371026457: C235.1 U23.27(LDO1-CAP)
N371026615: R238.2 U23.33(HPOUT-R(PORT-I-R))
N371026619: R241.2 U23.32(HPOUT-L(PORT-I-L))
N371026698: C228.2 R235.1 U21.4(SS)
N371027408: C236.1 R242.1
N371074716: Q62.1(G) R579.2
N371076465: CN3.198(EVENT#) R581.2
N371123920: C511.2 U16.6(CT)
N371123996: R208.2 R212.1 R593.2 U16.3(ON)
N371156292: C514.2 U60.6(CT)
N371156339: R595.1 R598.2 R599.1 U60.3(ON)
N371163469: C517.2 U23.12(PCBEEP)
N371163479: C517.1 R600.1 R601.2
N371165243: R105.2 U1.BG24(SIO_I2C1_DATA)
N371165245: R107.2 U1.BH24(SIO_I2C1_CLK)
N371165394: U1.BH28(SIO_I2C5_DATA) U74.2(A1)
N371165399: U1.BG28(SIO_I2C5_CLK) U74.3(A2)
N371193330: D5.P F2.1
N371340666: R17.1 U65.5(OE)
N371377879: CN12.1(WAKE#) R636.2
N371395696: Q67.1(G) Q68.3(D) R590.2
N371414444: Q52.3(D) R479.1 U53.6(ENB)
N371416452: R494.2 R496.1 U53.4(FB)
N371417145: R484.1 R495.2 U53.5(POK)
N371418676: R487.1 R489.1 U52.4(FB)
N371418689: R488.2 R490.1 U52.5(POK)
N371440242: R387.1 R713.2 U39.4(Y)
N371449799: C409.2 U46.6(CT)
N371449990: C416.2 U48.6(CT)
N371450050: Q79.3(D) Q80.3(D) R471.2 R561.2 R645.1 U48.3(ON)
N371541226: C369.1 U42.22(VBST1)
N371541419: R432.2 U42.19(DRVL1)
N371543859: R429.2 U42.21(DRVH1)
N371546994: R430.1 U42.10(DRVH2)
N371547056: R431.1 U42.12(DRVL2)
N371548461: C370.2 U42.9(VBST2)
N371555765: C378.2 D25.3(D3)
N371555769: C381.1 D24.2(X2) D25.1(X1)
N371555881: C377.2 D24.3(D3)
N371592399: C413.1 R461.1 U47.4(V5FILT)
N371594383: R459.1 U47.14(VBST)
N371598766: C400.2 U45.6(CT)
N371598824: Q75.3(D) R472.2 U45.3(ON)
N371600351: Q70.3(DRAIN) Q71.1(G) R376.1
N371600404: Q70.1(GATE) R247.2 R378.1
N371602762: Q72.3(D) Q73.1(G) R500.1
N371602779: Q72.1(G) R377.1
N371622208: Q25.3(DRAIN) Q79.1(G) R469.1
N371622225: Q25.1(GATE) R561.1 R644.1
N371631055: C398.2 U44.6(CT)
N371631113: Q76.3(D) R453.1 R454.2 R510.1 U44.3(ON)
N371631654: C447.2 U68.6(CT)
N371634130: Q44.3(DRAIN) Q45.1(G) R558.1
N371634202: Q44.1(GATE) R557.1
N371637080: C535.2 U69.6(CT)
N371637134: Q54.3(D) R383.1 R559.1 U69.3(ON)
N371697900: R328.1 U28.20(L80LLAT/GPE7)
N371698348: R335.2 U28.21(RI2#/GPD1)
N371705444: R657.1 U70.3(S\H\D\N\)
N371706163: R658.2 R712.1 U28.106(GPG0/FSCE1#/SSCE1#)
N371707559: R659.1 U28.113(VSS5)
N371729099: R717.1 U28.109(TXD/SOUT0/GPB1)
N371748554: Q53.3(D) R567.1
N371748828: Q51.3(D) R565.1
N371749875: Q57.3(D) R571.1
N371749956: Q56.3(D) R570.1
N371750028: Q58.3(D) R572.1
N371750040: Q55.3(D) R569.1
N371750942: Q59.3(D) R573.1
N371751422: R664.2 U71.1(A)
N371776174: Q61.3(D) R576.1
N371829343: C484.2 R541.1
N371829347: C480.1 L15.1 Q87.7(S1/D2) R532.1 R541.2 U57.7(SW)
N371829553: R535.1 R539.2
N371829623: R540.2 U57.1(BST)
N371829625: C480.2 R540.1
N371829670: Q87.1(GATE1) R667.2
N371829672: R667.1 U57.8(DRVH)
N371829674: Q87.6(G2) R666.2
N371829676: R666.1 U57.5(DRVL)
N371898761: R248.1 U28.84(EGCLK/GPE3)
N371988566: R129.2 U1.D14(TAP_TCK)
N371988594: R82.2 U6.12(OE)
N371988759: R131.2 U1.G12(T\A\P\_\T\R\S\T\)
N371988761: R582.2 U1.F14(TAP_TMS)
N371988880: R602.2 U1.A17(GPIO_S5_3)
N371988894: R583.2 U1.F12(TAP_TDI)
N371988916: R584.2 U1.G16(TAP_TDO)
N371989057: R64.1 U1.J24(GPIO_S517_J24)
N371989083: R586.1 U1.B24(S\V\I\D\_\A\L\E\R\T\)
N371989085: R587.1 U1.A25(SVID_DATA)
N371989087: R588.1 U1.C25(SVID_CLK)
N371989209: CN2.1 R66.2
N371989219: D2.P R66.1
N371989286: R78.1 U1.N26(GPIO_RCOMP)
N371989315: R70.1 U1.C23(P\C\U\_\S\P\I\_\C\S\_\0\0\)
N371989320: R73.2 U1.B22(PCU_SPI_MISO)
N371989334: R74.1 U1.A21(PCU_SPI_MOSI)
N371989349: R75.2 U1.C22(PCU_SPI_CLK)
N371989367: C14.2 R69.1 U1.A9(ILB_RTC_X2) X2.2 X3.4
N371989481: C11.2 R69.2 U1.C9(ILB_RTC_X1) X2.1 X3.1
N371989608: C13.2 U1.B8(ILB_RTC_EXTPAD)
N371989658: C10.1 R65.1 U1.C11(I\L\B\_\R\T\C\_\T\E\S\T\)
N371989798: R61.2 U1.AD14(ICLK_ICOMP)
N371989857: R60.2 U1.AD13(ICLK_RCOMP)
N371989882: C12.2 R68.2 U1.C12(I\L\B\_\R\T\C\_\R\S\T\)
N371989956: C18.2 U5.6(CT)
N371989976: R110.2 U1.C18(GPIO_S5_2)
N372041038: Q46.3(D) Q47.1(G) R34.1
N372057452: R674.2 U28.77(HDIO3/GPJ1)
N372200006: C549.2 R358.2 U73.4(SS)
N372204615: Q43.3(D) R675.1
N372317662: R682.1 U74.5(OE)
N372349941: Q63.1(G) Q88.3(D) R327.2
N372453757: C249.2 U23.17(MIC2-L(PORT-F-L))
N372453760: C250.2 U23.18(MIC2-R(PORT-F-R))
N372521203: C568.1 R686.2 R708.2 U76.5(IN)
N372521362: R686.1 R687.1 U76.4(EN)
N372521718: C569.1 L16.1 L17.1 U76.6(LX)
N372521761: C569.2 U76.1(BS)
N372522371: C570.2 R688.1 R689.1 U76.3(FB)
N372575543: R690.2 U77.4(RREF)
N372575558: R691.2 U77.14(TEST/SCL)
N372575569: R693.1 U77.23(V5)
N372575577: R694.1 U77.18(PGANG)
N372575582: FB14.2 U77.16(DVDD)
N372638863: R704.1 U28.125(PWRSW/GPE4)
N373120965: TP7.1 U1.BF22(SD3_1P8EN)
N373120968: TP8.1 U1.BD22(S\D\3\_\P\W\R\E\N\)
N373145543: TP9.1 U1.G24(PMC_SUSCLK0_G24)
N373255127: C765.2 R725.1 R726.2 U79.5(+INB)
N373255137: C764.2 R722.2 R723.1 U79.3(+INA)
N373255139: R724.1 U79.7(OUTB)
N373290376: Q102.3(D) R729.1 TP5.1
N373290440: Q103.3(D) R730.1 TP6.1
N373510936: R737.2 U83.4(RREF)
N373510985: R736.2 U83.14(TEST/SCL)
N373510994: R742.1 U83.23(V5)
N373510998: R741.1 U83.18(PGANG)
N373511003: FB17.2 U83.16(DVDD)
N373511700: R664.1 R959.1 R960.2
N373512216: C620.2 R743.1 U84.4(SS)
N373528412: C390.1 J7.6 R668.1
N373528416: C389.1 J7.5 R669.1
N373529044: C509.1 J4.5 R680.1
N373529046: C508.1 J4.6 R699.1
N373530772: C159.2 CN24.5
N373530781: C273.2 CN24.2
N373530783: C274.2 CN24.3
N373530802: C163.2 CN24.6
N373530908: CN26.5 R160.2
N373530914: C156.2 CN26.2
N373530916: C165.2 CN26.3
N373530977: CN26.6 R168.2
N373531475: SW4.1 SW4.5
N373532752: C605.2 D14.N F1.1 FB23.2 FB24.2 FB25.2 FB34.1 FB35.1 FB36.2
N373532763: F1.2 FB36.1 J13.4
N373533145: Q89.3(D) R898.2
N373533207: Q78.3(D) R902.1
N373533422: D15.N R904.2
N373533528: C845.2 R744.1
N373549786: Q95.2(S) R478.2 R481.2 R485.2 R499.2 R646.2 R707.2 U25.11(ISW)
N373549823: D38.P D41.P L31.2 Q95.3(D)
N373549839: R616.1 U25.20(STATUS)
N373549953: R308.2 U25.10(ENA)
N373550017: Q95.1(G) R605.2
N373550037: R455.1 U25.19(SSTCMP)
N373550058: R605.1 U25.13(LDR)
N373550150: C296.1 C297.2 R621.2
N373550502: C727.2 R455.2
N373557456: CN27.2 D49.N FIL14.3(DUMMY3) R564.2
N373557462: CN27.3 D48.N FIL14.2(DUMMY2) R566.2
N373557631: CN15.2 D44.N FIL12.3(DUMMY3) R381.2
N373557637: CN15.3 D45.N FIL12.2(DUMMY2) R568.2
N373557823: CN28.3 D46.N FIL13.4(GND) R575.2
N373557825: CN28.2 D47.N FIL13.1(UNB) R382.2
N373561034: R169.1 U12.7(WP/WC#)
N373561252: R152.2 R153.2 U10.45(PWMI)
N373561265: R166.1 U10.20(TESTMODE)
N373561472: L3.2 U10.15(SW_OUT) U10.16(SW_OUT-1)
N373564935: R591.1 U28.81(DAC5/RIG0#/GPJ5)
N373564955: R592.1 U28.79(DAC3/GPJ3/TACH1B)
N373564977: R606.1 U28.80(DAC4/DCD0#/GPJ4)
N373748142: CN9.2 FIL4.3(DUMMY3) R623.1
N373748155: CN9.4 FIL3.3(DUMMY3) R622.1
N373748171: CN9.3 FIL2.2(DUMMY2) R618.1
N373748197: CN9.8 FIL1.2(DUMMY2) R603.1
N373748211: CN9.7 FIL1.3(DUMMY3) R604.1
N373748290: CN9.6 FIL2.3(DUMMY3) R617.1
N373748367: CN9.5 FIL3.2(DUMMY2) R620.1
N373748377: CN9.1 FIL4.2(DUMMY2) R624.1
N373765744: CN22.5 CN22.6 R625.1 R627.1
N373783458: C275.1 C304.1 FB12.2 R389.2 R628.1 R660.1 U9.5(VIN)
N373783506: R149.2 R629.1 R1114.2 U9.3(EN/ENB)
N373783519: C305.2 R389.1 U9.4(SS)
N373800615: CN11.1 R391.1 R392.1
N373937554: C133.1 R136.2 R761.1 R762.1 U8.1(VIN1) U8.2(VIN2)
N373937575: C135.2 U8.6(CT)
N374034613: Q16.3(D) Q17.1(G) R703.2
N374035248: Q7.3(D) Q90.1(G) R750.2

Pads without a net: CN3 77 122 125; CN8 13 14; CN12 3 8 10 12 14 16 17 19 42 44 45 46 47 49; CN14 11 13 20; J4 2; J7 2; MARK1 1; MARK2 1; MARK3 1; MARK4 1; MARK5 1; MARK6 1; MARK7 1; MARK8 1; R95 1; R96 1; R97 1; R98 1; R105 1; R107 1; R166 2; R444 2; R585 2; U1 A13 AB2 AB3 AB7 AB9 AB12 AB13 AB14 AD4 AD6 AD9 AD10 AD12 AD40 AD41 AF13 AF14 AF40 AF41 AF48 AF50 AF51 AF52 AG51 AG53 AH13 AH14 AH40 AH44 AH52 AJ51 AK4 AK6 AK7 AK9 AK40 AK42 AK45 AK47 AK48 AK50 AK51 AK52 AL1 AL3 AL51 AL53 AM4 AM6 AM9 AM10 AM13 AM14 AM41 AM42 AM45 AM47 AM48 AM50 AM52 AP4 AP6 AP7 AP9 AP10 AP12 AP41 AP42 AP44 AP45 AP47 AP48 AP50 AP51 AP52 AR51 AR53 AT6 AT7 AT20 AT22 AT26 AT28 AT32 AT34 AT36 AT40 AT41 AT42 AT44 AT45 AT48 AT50 AT51 AU20 AU22 AU26 AU28 AU34 AU36 AU53 AV9 AV10 AV20 AV22 AV26 AV28 AV32 AV34 AV36 AV40 AV44 AV45 AV48 AV50 AV52 AW41 AW51 AW53 AY2 AY14 AY20 AY24 AY26 AY28 AY30 AY34 AY38 AY40 AY42 AY44 AY45 AY47 AY48 AY51 AY52 B12 B14 B26 B28 BA1 BA3 BA18 BA20 BA24 BA26 BA28 BA34 BA36 BA38 BA42 BA51 BB3 BB4 BB44 BB47 BB49 BB50 BB51 BC1 BC2 BC14 BC18 BC24 BC36 BC38 BC40 BC44 BC52 BC53 BD2 BD5 BD12 BD16 BD18 BD20 BD26 BD28 BD32 BD34 BD36 BD38 BD40 BD42 BD44 BD47 BE46 BE51 BE52 BF2 BF14 BF27 BF28 BF32 BF34 BF40 BF42 BF48 BF50 BF52 BG18 BG21 BG23 BG25 BG26 BG27 BG29 BG30 BG32 BG33 BG35 BG36 BG37 BG38 BG40 BG41 BG43 BG47 BH4 BH5 BH6 BH7 BH8 BH18 BH22 BH26 BH30 BH32 BH34 BH36 BH38 BH40 BH42 BH44 BH46 BH47 BH48 BH49 BH50 BJ9 BJ25 BJ29 BJ33 BJ37 BJ41 BJ45 C13 C16 C17 C19 C21 C27 C29 C30 D18 D28 D32 D34 D48 E46 F16 F28 F32 F34 G2 G30 H3 H4 H5 H7 H8 J3 J18 J28 J34 K2 K3 K18 K20 K24 K28 K34 L3 M3 M4 M6 M7 M9 M10 M18 M20 M22 M24 M32 N24 N32 N34 P2 P6 P7 P10 P12 P14 P34 R1 R3 T2 T3 T4 T6 T7 T9 T10 T12 T13 T14 V2 V3 V4 V6 V9 V10 V13 V14 W1 W3 Y2 Y3 Y4 Y6 Y12 Y13; U10 31 32 34 35 36 37 39 40 41 42 55 56; U14 14; U17 40; U23 2 3 14 16 21 22 23 24; U25 12; U28 36 37 38 39 40 41 42 43 44 45 46 51 52 53 54 55 58 59 60 61 62 63 64 65 66 72 73 89 90 94 95 96 99 100 108 123; U29 1; U56 36 38 39 40 41; U61 4 5 12 13; U62 4 5 12 13; U70 4; U77 20 22; U83 11 12 19 20 22

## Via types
v1: diameter 0.7, hole 0.4, TOP to BOTTOM, 679 vias
v2: diameter 0.45, hole 0.25, TOP to BOTTOM, 2712 vias
v3: diameter 0.5, hole 0.25, TOP to BOTTOM, 39 vias
v4: diameter 0.55, hole 0.25, TOP to BOTTOM, 1 via

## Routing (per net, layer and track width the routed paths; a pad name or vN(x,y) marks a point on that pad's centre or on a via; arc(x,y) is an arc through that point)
3.3V_IN: length 40.2
  TOP w0.305: U77.24 29.49,126.94 v2(29.98,127.43)
  TOP w0.508: v2(26.56,111.57) 26.56,111.57 FB15.2 C581.2 R695.1 ; R694.2 33.18,127.01 v2(32.94,127.24) ; v2(36.03,124.46) 36.03,123.23 36.59,122.67 FB14.1 37.06,121.47 36.81,121.21 R691.1 37.23,118.41 37.6,118.04 v2(37.6,115.89)
  LAY3 w0.305: v2(29.98,127.43) 32.75,127.43 v2(32.94,127.24)
  LAY3 w0.508: v2(26.56,111.57) 26.56,111.05 28.16,109.45 32.14,109.45 37.6,114.91 v2(37.6,115.89) ; v2(36.03,124.46) 33.25,127.24 v2(32.94,127.24)
3.3V_IN_1: length 21
  BOTTOM w0.305: U83.24 142.52,118.04 142.74,117.82 142.74,115.48 143.01,115.21 144.16,115.21 145.34,116.39 R741.2 145.71,115.58 146.1,115.19 148.06,115.19 FB17.1 148.86,115.65 149.86,116.65 R736.1
+V1.0A: length 84.1
  TOP w0.203: U1.U22 v2(89.66,88.2) U1.V22 ; U1.C3 v2(96.42,96.65) ; U1.Y19 v2(88.87,88.96) ; v2(95.86,96.17) U1.C5 U1.B6
  TOP w0.305: v2(133.62,69.47) 135.33,71.18 v2(135.78,71.18)
  LAY3 w0.508: v2(125.18,78.21) 125.81,78.84 125.81,89.77 122.48,93.1 120.9,93.1 117.49,96.51 110.99,96.51 109.95,97.54 109.35,97.54 108.13,98.76 104.75,98.76 103.82,97.84 101.42,97.84 100.82,97.23 100.26,97.23 v2(100.1,97.39)
  LAY4 w0.305: v1(123.54,72.61) 123.68,72.61 125.55,70.73 132.36,70.73 v2(133.62,69.47)
  BOTTOM w0.203: 99.48,97.76 99.48,97.8 97.53,99.75 97.53,101.29 94.16,104.66 93.59,104.66 93.42,104.83 91.86,104.83 91.31,104.28 90.98,104.28 R293.1 ; v2(133.62,69.47) U47.3
  BOTTOM w0.254: C65.1 C68.1 ; C65.1 89.52,88.35 v2(89.66,88.2) ; C65.1 88.87,88.96 v2(88.87,88.96)
  BOTTOM w0.305: v2(135.78,71.18) 135.83,71.23 R468.2
  BOTTOM w0.406: C88.1 96.83,97.06 v2(96.42,96.65) ; C87.1 100.16,98.33 v2(100.6,97.89) ; 99.48,97.76 C86.1 99.85,97.39 v2(100.1,97.39)
  BOTTOM w0.508: 121.95,74.97 v1(121.95,74.2) ; 121.95,74.97 v2(125.18,78.21) ; 121.95,74.97 121.91,74.94 121.63,74.94
  vias: v1(122.46,73.69) v1(122.99,73.16)
+V1.0S: length 106.1
  TOP w0.203: U1.M14 v2(92,91.38) ; U1.AM18 v2(82.6,89.72) U1.AK18 ; v2(94.55,98.94) U1.G1 ; v2(81.82,88.96) U1.AN19 ; v2(81.82,88.96) U1.AN21 ; v2(81.82,88.96) U1.AM21 ; U1.Y18 v2(88.88,90.48) ; 115.36,74.15 114.07,74.15 112.67,75.54 112.67,77.83 113.89,79.05 v2(116.02,79.05) ; U1.V32 v2(89.66,83.65) ; U1.AF16 v2(84.96,90.48) U1.AF18 ; U1.AN18 v2(81.05,89.72) ; R516.1 111.8,123.43 111.8,122.26 R528.1 ; U1.AN25 v2(81.82,86.69) ; v2(90.58,90.39) U1.U18 U1.U19 90.45,89.82 v2(90.58,90.39)
  TOP w0.254: U1.BJ6 v2(72.9,95.84)
  TOP w0.305: R518.1 R517.1 R516.1 112.28,124.57 v2(112.27,124.57)
  LAY3 w0.305: v2(80.9,97.08) 80.9,98.65 80.06,99.49 77.59,99.49 76.89,98.79 75.14,98.79 74.37,99.56 73.7,99.56 v2(72.65,98.5)
  LAY4 w0.305: v2(132.9,56.92) 132.76,57.06 119.87,57.06 118.47,58.46 118.47,70.41 ; v2(112.27,124.57) v2(91.84,124.57)
  BOTTOM w0.203: R580.1 116.97,79.05 v2(116.02,79.05)
  BOTTOM w0.305: v2(132.9,56.92) 132.95,56.96 R377.2 ; v2(89.66,83.65) 89.86,83.65 90.4,83.11 95.83,83.11 96.13,82.81 C49.2 99.31,82.81 99.89,83.39 v2(99.89,84.01) ; 86.21,106.86 86.21,107.56 85.35,108.41 79.85,108.41 v2(78.93,107.49)
  vias: v1(117.71,70.94) v1(118.32,70.56) v2(67.77,89.07) v2(68.97,91.41) v2(69.24,92.75) v2(92.98,103.43) v2(93,104.16) v2(94.95,102.3) v2(100.21,89.85) v2(118.29,71.19) v2(118.91,70.52)
+V1.0SX: length 151.5
  TOP w0.203: U1.AG21 v2(84.96,88.2) U1.AF21 ; U1.AF36 v2(84.96,81.39) ; U1.AD35 v2(85.74,81.38) U1.AF35 ; v2(88.88,87.45) U1.Y24 ; v2(88.88,87.45) U1.V24 ; v2(88.88,87.45) U1.Y22 ; U1.AK21 v2(82.6,88.96) U1.AK19 ; U1.AJ18 v2(84.17,90.48) ; U1.AN30 v2(81.82,84.41) U1.AN29 ; U1.AM16 v2(81.82,90.48)
  TOP w0.229: v2(88.09,81.38) 87.72,81 U1.AA36 ; v2(88.09,81.38) 88.32,81.16 88.48,81 U1.Y36 ; v2(88.09,81.38) 88.32,81.6 88.48,81.76 U1.Y35
  TOP w0.254: 83.38,81.38 U1.AK35 ; 83.38,81.38 v2(83.39,81.38) 83.77,81 U1.AJ36 ; 83.38,81.38 U1.AK36
  LAY3 w0.305: v2(35.4,108.7) 26.76,108.7 25.49,109.96 20.66,109.96 20.04,110.58 17.86,110.58 16.86,109.57 16.86,108.92 11.64,103.71 10.95,103.71 v2(6.14,98.89)
  LAY4 w0.089: 83.14,85.55 83.69,85.55
  LAY4 w0.127: 83,86.37 83,87.61 83,87.74 ; 82.21,86.37 82.21,87.74
  LAY4 w0.305: 84.11,109.47 84.35,109.22 ; 84.11,109.47 84.11,109.47 ; 84.11,109.47 84.11,109.01 ; v2(82.6,88.96) 83.32,89.68 83.32,90.78 82.62,91.48 ; 84.11,109.47 84.64,109.47 ; 84.11,109.47 76.3,117.28 71.78,117.28 71.03,116.53 71.03,115.08 68.5,112.55 64.22,112.55 60.15,116.61 49.37,116.61 48.47,117.51 47.24,117.51 38.43,108.7 v2(35.4,108.7)
  LAY4 w0.508: v2(88.09,81.38) 88.09,81.38 88.09,81.11 87.57,80.59 84.7,80.59 83.93,81.37 83.4,81.37 v2(83.39,81.38) ; 110.02,81.14 110.02,80.75 ; 110.02,81.14 110.02,81.18 ; 110.02,81.14 109.44,80.56 ; 110.02,81.18 110.61,80.59 ; 110.02,81.18 110.02,84.3 110.57,84.85 110.57,87.54 109.78,88.33 106.77,88.33 105.94,89.16 ; 105.94,89.16 105.05,89.16 ; 105.94,89.16 105.52,89.58 ; 105.94,89.16 105.94,90.06
  BOTTOM w0.203: C62.1 86.03,81.09 v2(85.74,81.38) 84.97,81.38 v2(84.96,81.39) 84.58,81.39 84.29,81.1 C58.1
  BOTTOM w0.254: C79.1 81.66,84.57 v2(81.82,84.41) ; 80.9,81.22 82.09,80.02 83.58,80.02 C58.1
  BOTTOM w0.305: v2(6.14,98.89) 6.84,98.18 R725.2 ; C80.1 88.76,87.56 v2(88.88,87.45) ; v2(84.96,88.2) 84.96,88.28 85.57,88.9 C67.1 85.57,89.08 v2(84.17,90.48)
  BOTTOM w0.406: v2(88.09,81.38) 88.24,81.24 C60.1 ; v2(68.39,89.96) 68.27,90.08 C69.1
  vias: v1(66.67,80.65) v1(115.94,77.79) v1(116.53,77.19) v2(84.21,107.82) v2(115.9,77.13) v2(116.53,77.79)
+V1.2A: length 9.6
  TOP w0.203: C553.1 93.52,105.5 v2(93.85,105.17)
  BOTTOM w0.203: U53.1 92.51,113.17 90.93,114.75 R573.2 ; v2(93.85,105.17) 92.43,105.17 91.97,105.63 ; U53.3 R494.1
+V1.2S: length 108.4
  TOP w0.102: R557.2 26.39,66.91 v2(26.41,66.93)
  TOP w0.203: U54.7 91.57,108.94 91.03,108.94 90.53,108.44 ; 88.37,107.75 88.07,108.04 v2(88.07,110.77) ; 88.37,107.75 88.61,107.51 ; 88.37,107.75 88.37,107.27 ; 88.37,107.75 88.78,107.75 88.81,107.71 ; C552.1 90.53,108.44 ; 90.53,108.44 91.57,108.44 U54.8
  TOP w0.305: C552.1 C434.2 87.51,106.41 v2(87.51,106.17)
  LAY3 w0.102: v2(26.41,66.93) 27.09,66.93 27.5,67.33 27.5,68.83 28.78,70.12 30.75,70.12 39.68,79.05 v2(39.68,82.75)
  LAY4 w0.102: v2(39.68,82.75) 40.12,83.19 40.12,89.89 55.87,105.64 55.87,107.34 56.44,107.91 57.97,107.91 58.63,108.58 v2(78.43,108.58)
  BOTTOM w0.102: v2(88.07,110.77) 86.08,108.78 79.06,108.78 78.87,108.58 78.42,108.58 v2(78.43,108.58)
  BOTTOM w0.305: 87.51,101.68 87.51,100.7 86.55,99.75 R114.2
  BOTTOM w0.508: 87.51,101.68 v2(87.51,106.17)
+V1.05S: length 69.5
  TOP w0.203: U1.AF33 v2(84.96,82.14) ; v2(84.96,82.14) U1.AG33 ; v2(84.96,82.14) U1.AG35 ; v2(89.66,82.14) U1.V33 ; v2(89.66,82.14) U1.U33 ; v2(89.66,82.14) U1.U35 ; U1.AA33 v2(88.09,82.9) ; R567.2 v2(149.54,59.54)
  LAY4 w0.203: v2(128.69,58.96) 148.96,58.96 v2(149.54,59.54)
  BOTTOM w0.203: 129.06,59.22 131,59.22 C563.1 R473.1 ; 129.06,59.22 128.73,58.88 ; 129.06,59.22 128.68,59.22
  BOTTOM w1.118: 125.33,61.42 123.07,63.69 112.32,63.69 104.04,71.96 104.04,76.04 106.54,78.54 106.54,79.73 105.72,80.54 103.44,80.54
+V1.5S: length 259.1
  TOP w0.406: CN12.48 v2(41.76,53.53) ; CN12.6 v2(44.32,33.53) ; v2(41.26,45.48) 41.3,45.53 CN12.28
  LAY3 w0.406: v2(41.26,45.48) 37.3,41.53 35.33,41.53 33.81,40.02 25.78,40.02 v2(23.89,41.91)
  LAY4 w0.203: v2(57.87,97.05) 51.44,97.05 42.76,88.37 42.76,73.32 43.49,72.58 43.49,67.28 42.58,66.36 42.58,61.77 41.81,61 41.81,58.48 42.58,57.72 42.58,52.26 41.13,50.81 41.13,45.61 v2(41.26,45.48)
  LAY4 w0.406: v2(23.89,41.91) 23.65,41.67 23.65,39.2 23.06,38.61 23.06,32.94 20.01,29.89 20.01,27.56 32.79,14.78 48.99,14.78 53.19,18.98 53.19,22.17 57.93,26.92 63.39,26.92 65.65,29.18 80.82,29.18 82.98,27.01 82.98,25 89.14,18.85 92.94,18.85 93.92,17.86 93.92,15.55 95.02,14.44 104.62,14.44 v2(106.9,16.72)
  BOTTOM w0.203: R487.2 38.26,50.94 38.44,51.12 38.44,51.5
  BOTTOM w0.254: R240.2 109.46,16.93 108.97,17.43 U20.1 108.97,17.56 108.36,17.56 C229.2 108.38,18.06 108.97,18.06 U20.2
  BOTTOM w0.305: R565.2 23.9,41.92 v2(23.89,41.91) ; v2(57.87,97.05) 57.87,90.36 60.77,87.46 60.77,82.69 62.85,80.61 R111.1
  BOTTOM w0.406: v2(44.32,33.53) 43.21,34.64 43.21,37.09 44.85,38.73 44.85,42.56 44.16,43.25 42.24,43.25 41.97,43.52 C266.1 ; v2(41.76,53.53) C267.2 41.19,52.46 ; 41.19,51.75 41.19,52.46 ; 41.19,52.46 41.17,52.46 40.64,51.93 ; v2(106.9,16.72) 107.98,17.8 C229.2
+V1.5S_AUDIO: length 35.6
  LAY3 w0.305: v2(122.37,10.31) 120.73,11.96 v2(120.73,16.51) 120.73,18.58 v2(122.96,20.82)
  LAY4 w0.305: v2(120.73,16.51) 118.93,18.3 111.54,18.3 110.95,17.72 v2(110.95,16.72) ; v2(122.37,10.31) 122.81,10.75 131.97,10.75 v2(132.32,10.4)
  BOTTOM w0.305: v2(132.32,10.4) 132.31,10.4 FB9.2 ; v2(122.96,20.82) 122.51,21.27 R260.2
+V1.8A: length 397.6
  TOP w0.152: v2(112.16,99.49) 112.11,99.49 R583.1 R582.1 110.79,98.3 R584.1 R62.2
  TOP w0.203: R89.2 R110.1 105.18,96.18 103.89,96.18 R602.1 R80.1 ; R89.2 v2(106.03,96.64) ; R89.2 R90.2 ; U6.1 118.68,78.31 C20.1 118.9,78.81 118.9,78.82 119.38,79.3 R82.1 119.38,79.61 118.93,80.06 v2(118.93,80.59) ; U1.AA18 v2(87.32,90.48)
  TOP w0.305: v2(69.47,114.21) 69.47,113.4 62.4,106.33 62.4,100.13 57.75,95.47 57.75,88.1 56.67,87.02 ; v2(97.52,114.08) 97.52,112.49 99.04,110.97 102.99,110.97 106.6,107.37 111.93,107.37 114.68,104.61 114.68,101.09 113.08,99.49 v2(112.16,99.49) ; 56.67,87.02 56.27,87.02 ; 56.67,87.02 56.11,86.46
  TOP w0.406: 54.56,86.91 54.56,87.33 53.94,87.96 49.08,87.96 48.12,87 39.2,87 33.34,81.14 32.35,81.14 30.17,78.96 30.17,71.63 27.77,69.23 24.97,69.23 v2(22.81,67.07)
  LAY3 w0.305: v2(146.58,75.81) 146.58,63.16 145.86,62.44 145.86,58.07 144.66,56.87 144.66,52.68 143.86,51.88 143.86,42.92 v2(141.12,40.18) 130.59,29.64 129.39,29.64 125.15,25.41 125.15,23.32 124.68,22.85 109.77,22.85 v2(109.14,22.21)
  LAY4 w0.305: v2(113.14,27.55) 113.14,27.45 114.07,26.52 118.75,26.52 132.41,40.18 v2(141.12,40.18) ; v2(146.58,75.81) 146.58,81.5 144.3,83.79 129.82,83.79 126.61,80.59 v2(118.93,80.59) 119.69,81.35 119.69,84.54 v2(120.99,85.84) ; v2(69.47,114.21) 69.47,116.74 70.48,117.75 81.09,117.75 83.86,114.98 v2(90.09,114.98) 90.99,114.08 v2(97.52,114.08)
  BOTTOM w0.203: v2(106.03,96.64) 106.13,96.54 108.26,96.54 D31.P ; v2(120.99,85.84) R638.2 R63.2 ; 109.44,95.35 109.21,95.11 109.21,94.32 105.37,90.49 105.37,90.02 101.85,86.5 R76.2 ; R480.1 C564.1 30.79,56.11 31.04,55.85 ; v2(90.09,114.98) 90.09,112.26 91.17,111.18 91.17,107.89
  BOTTOM w0.305: C286.1 111.2,30.24 ; C286.1 110.25,28.26 R314.2 R326.2 ; C286.1 111.77,29.21 113.14,27.84 v2(113.14,27.55) ; 111.2,30.24 U27.1 ; 111.2,30.24 111.25,30.28 R313.1 ; 109.44,95.35 108.94,95.35 R731.1 ; 109.44,95.35 109.91,94.89 116.66,94.89 118.11,93.44 122.2,93.44 123.69,91.95 R83.1 123.69,86.11 123.11,85.54 122.29,85.54 121.99,85.84 v2(120.99,85.84) ; 109.44,95.35 D31.P 109.52,95.39 112.16,98.04 v2(112.16,99.49) ; v2(109.14,22.21) R298.1 108.54,21.41 C284.1 107.94,21.41 107.55,21.8 U26.1
  BOTTOM w0.406: v2(22.81,67.07) 22.81,61.59 27.18,57.23 27.18,55.52 28.09,54.6 30.97,54.6 ; R572.2 30.95,55.44
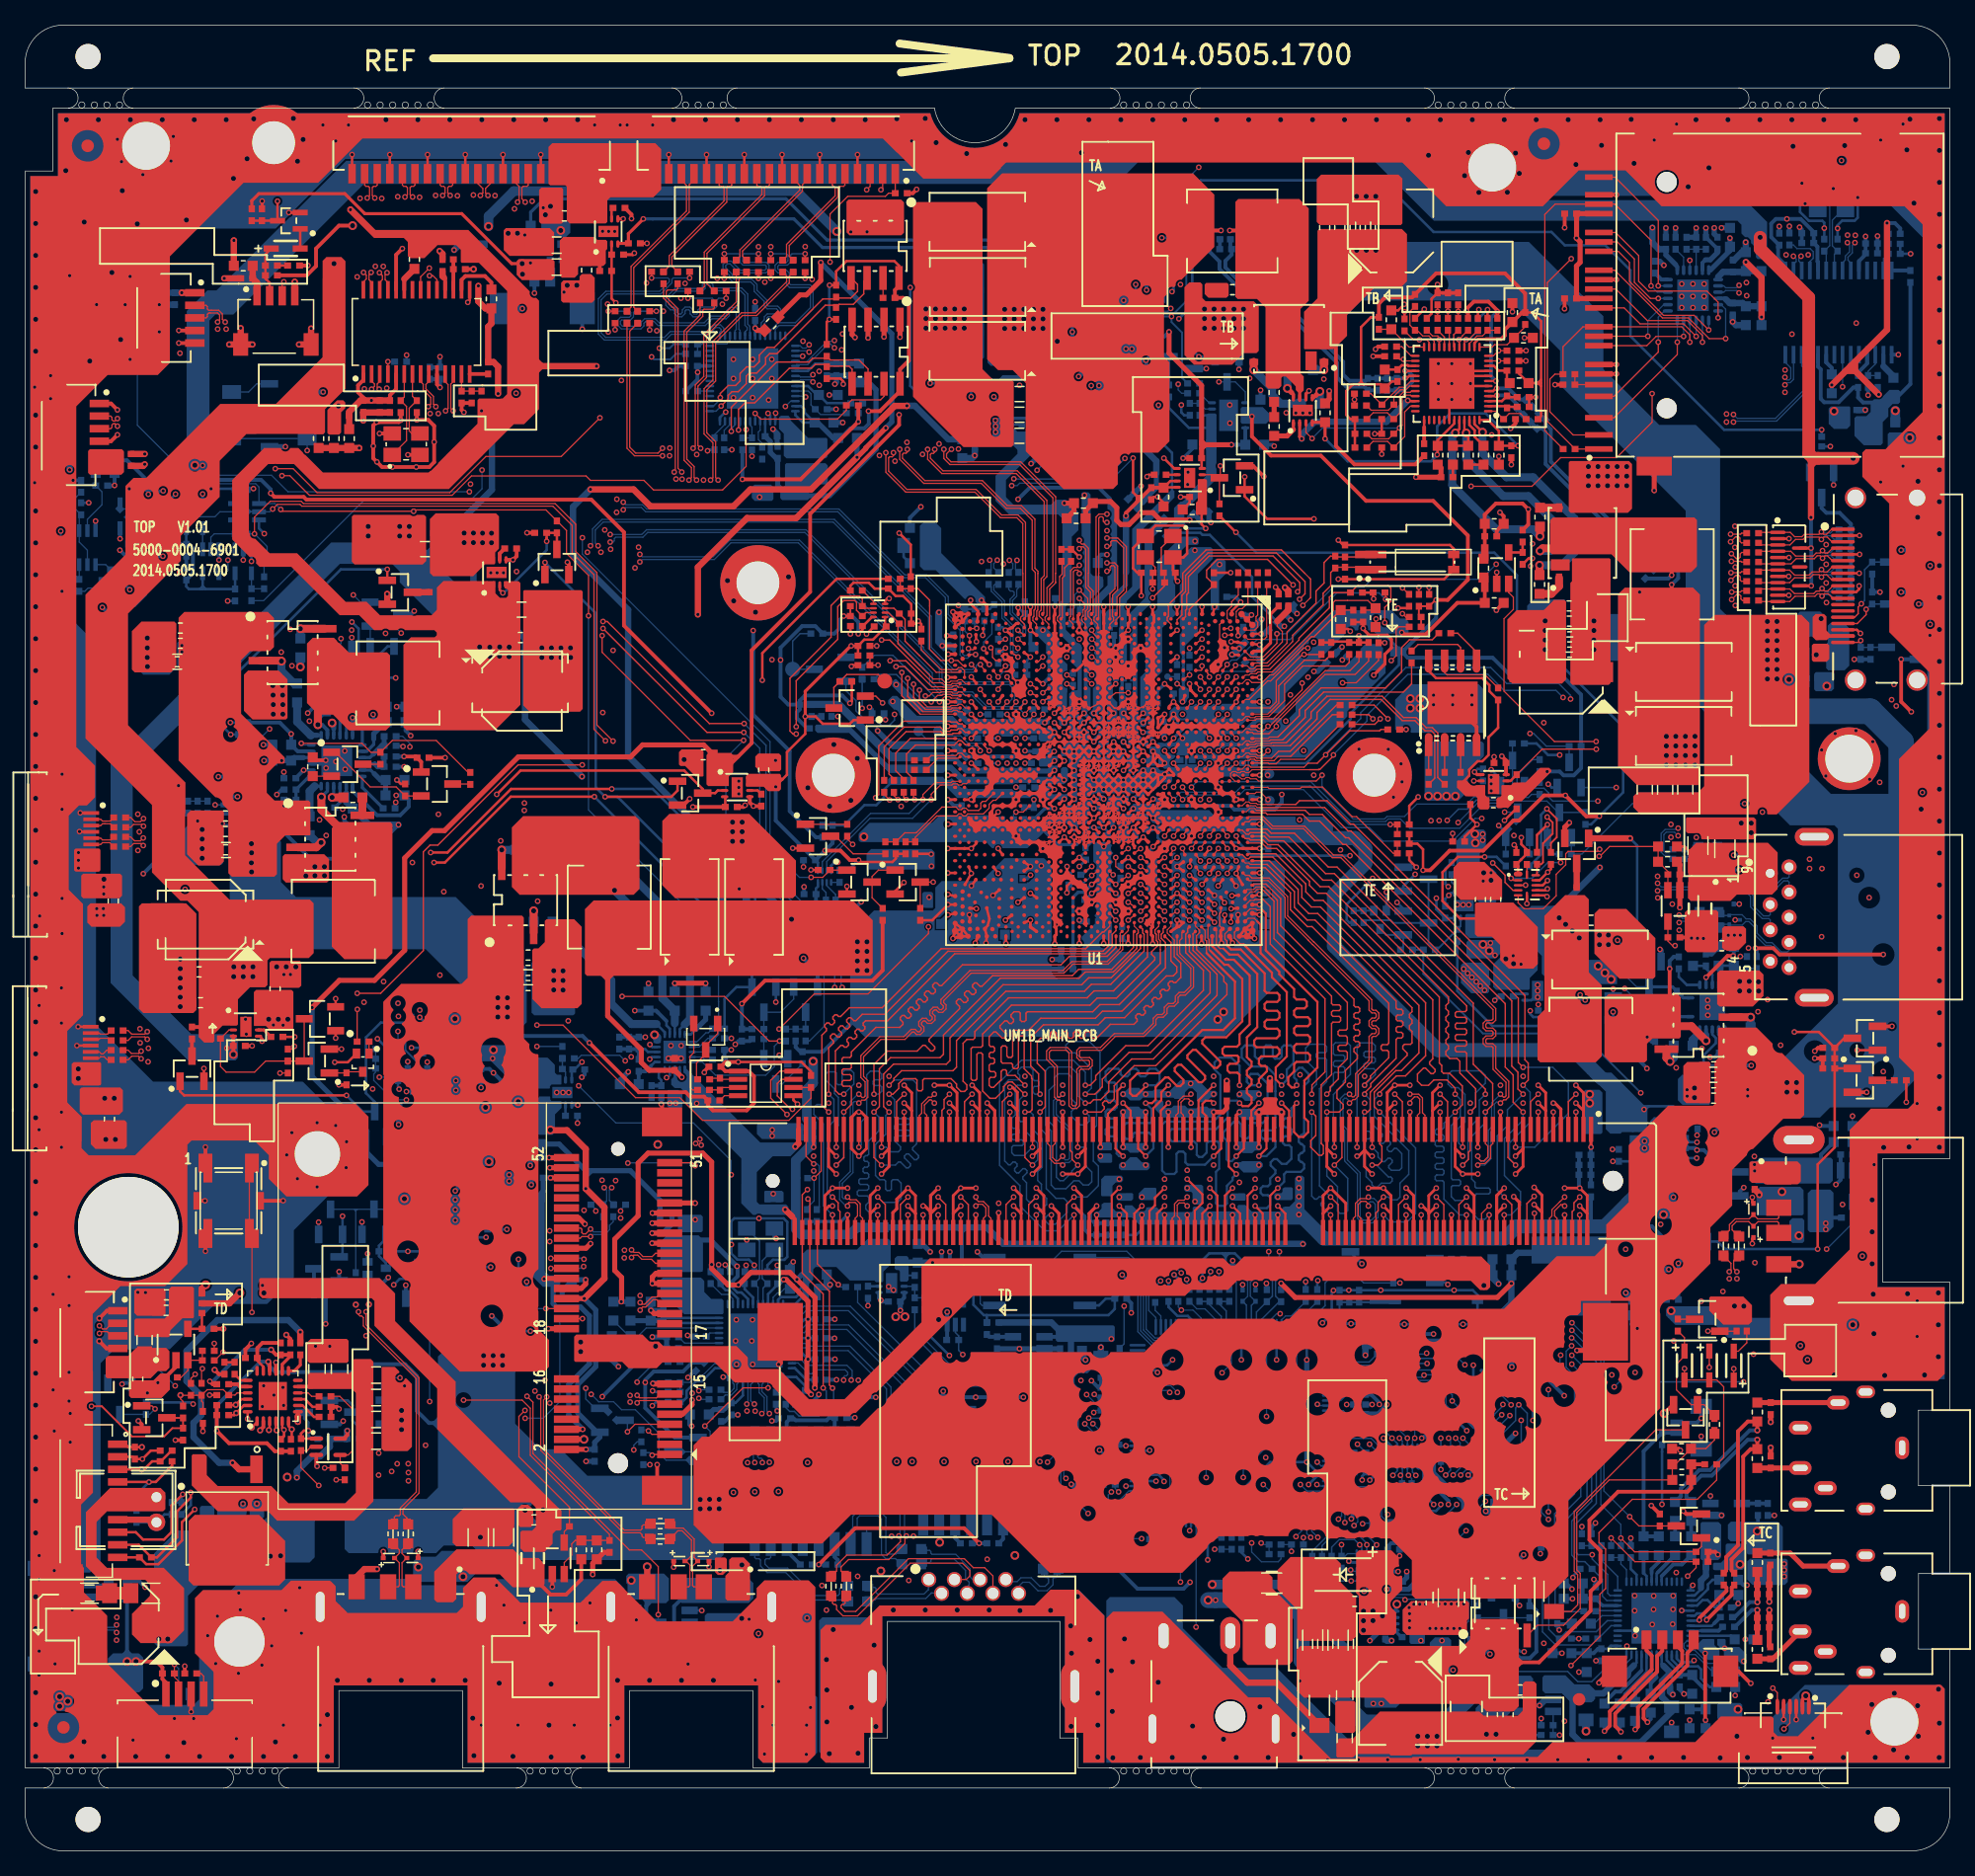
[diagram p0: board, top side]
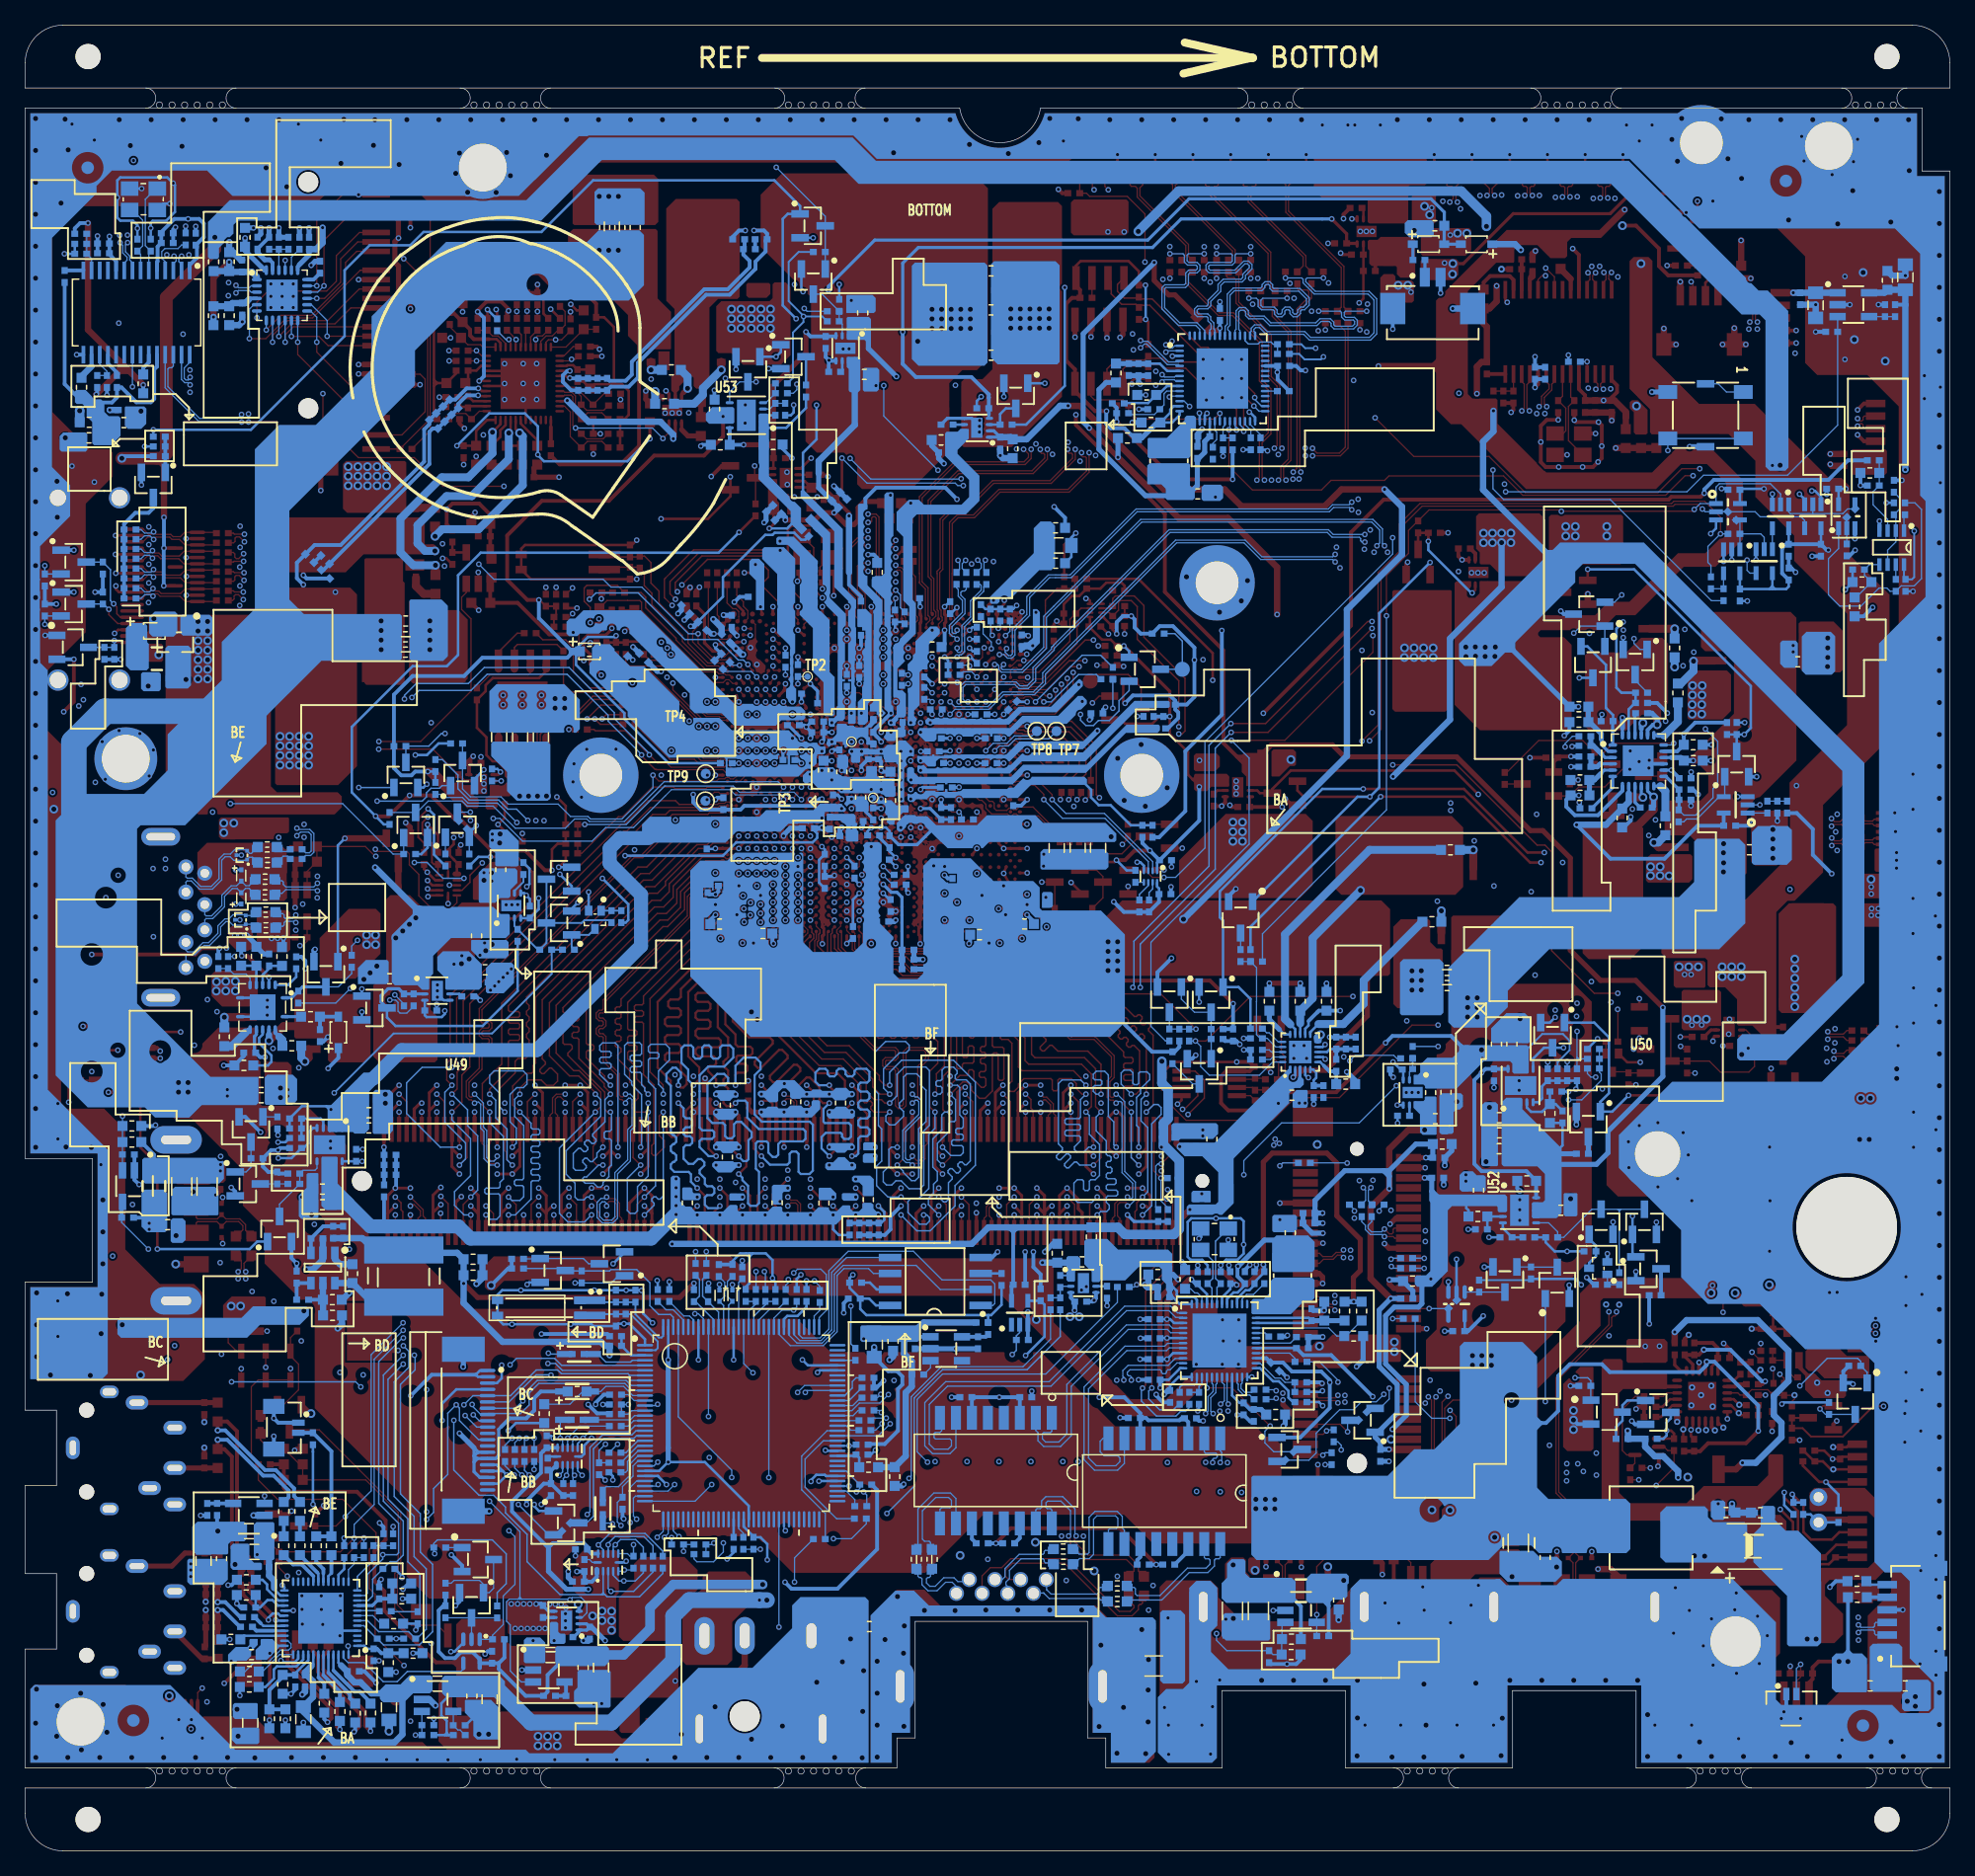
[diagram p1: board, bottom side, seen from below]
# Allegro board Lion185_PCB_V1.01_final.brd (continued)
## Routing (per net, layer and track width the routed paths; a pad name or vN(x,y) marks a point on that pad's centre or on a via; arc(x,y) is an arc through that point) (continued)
+V1.8A_SPI: length 15.8
  TOP w0.203: R71.2 114.79,85.51 114.79,85.98 115.46,86.66 115.83,86.66 116.33,87.16 116.33,88.56 117.09,89.32 R72.2 116.39,92.23 116.39,92.7 115.83,93.27 112.15,93.27 111.57,93.85 U3.8
+V1.8A_SPI_KBC: length 2.2
  BOTTOM w0.305: U70.5 C521.2 76.64,40.88 R339.2
+V1.8S: length 332.3
  TOP w0.203: R51.2 R52.2 69.21,78.91 68.94,78.64 66.4,78.64 v2(66.25,78.79) ; v2(81.82,82.9) U1.AN32 U1.AM30 ; v2(111.12,77.99) 111.12,79.65 110.67,80.1 R31.2 R13.1 ; 60.14,85.21 59.97,85.38 ; 60.14,85.21 60.19,85.21 ; 60.14,85.21 C422.2 ; R36.2 66.7,96.33 67.39,96.33 C302.1 68.35,97.46 U65.1 ; R36.2 v2(65.66,95.83) ; R36.2 R91.2 ; 60.19,85.21 60.19,85.21 60.56,85.58 60.56,87.38 62.01,88.83 v2(62.01,90.22) 62.82,90.22 63.4,89.64 65.57,89.64 65.86,89.94 Q102.1 ; 60.19,85.21 59.96,84.98 ; R17.2 65.6,100.61 65.85,100.86 67.06,100.86 67.53,100.39 R57.2 69.2,99.8 69.79,99.8 70.44,99.15 R108.1 R106.1 70.79,97.6 v2(71,97.81) 71.24,97.57 R109.1 ; U1.U38 v2(89.66,79.86) ; v2(96.25,104.86) R492.2
  TOP w0.254: v2(62.01,90.22) 62.01,92.22 65.62,95.83 v2(65.66,95.83)
  TOP w0.305: v2(63.59,79.55) 64.81,79.55 65.57,78.79 v2(66.25,78.79) ; v2(125.14,82.29) 125.13,82.28 124.1,82.28 v2(122.44,83.94) 120.74,83.94 118.74,81.94 118.3,81.94 115.91,79.54 113.24,79.54 111.68,77.99 v2(111.12,77.99)
  LAY3 w0.203: v2(146.04,47.3) 146.03,47.31 146.03,55.47 148.84,58.28 148.84,82.2 v2(150.82,84.17) 151.46,84.82 151.46,93.94 150.52,94.88 v2(150.52,99.16)
  LAY3 w0.254: v2(71,97.81) 69.94,96.75 67.5,96.75 66.58,95.83 v2(65.66,95.83) ; v2(81.82,82.9) 82.67,82.9 84.75,80.82 85.55,80.82 86.2,80.17 89.36,80.17 v2(89.66,79.86)
  LAY3 w0.305: v2(104.56,79.61) 104.57,79.62 105.74,79.62 106.48,78.88 110.66,78.88 111.12,78.42 v2(111.12,77.99)
  LAY4 w0.203: v2(146.04,47.3) 140.15,47.3 137.89,45.04 133.94,45.04 128.83,39.93 126.8,39.93 119.65,32.78 115.23,32.78 v2(114.6,33.42) ; v2(125.14,82.29) 127.31,82.29 129.2,84.17 v2(150.82,84.17) ; v2(121.99,87.16) 122.44,86.7 v2(122.44,83.94)
  LAY4 w0.254: v2(81.82,82.9) 77.71,78.79 v2(66.25,78.79) ; v2(71,97.81) 72.24,99.05 v2(74.19,99.05)
  LAY4 w0.305: v2(89.66,79.86) 89.66,80.59 90.87,81.79 94.96,81.79 95.82,82.65 102.19,82.65 104.56,80.28 v2(104.56,79.61)
  BOTTOM w0.203: v2(74.19,99.05) 74.47,98.76 R42.2 R41.2 R43.2 76.67,98.76 R39.2 ; v2(96.25,104.86) 97.87,103.24 116.79,103.24 118.59,101.44 118.59,95.11 119.48,94.22 122.19,94.22 127.03,89.38 127.03,84.18 v2(125.14,82.29) 124.49,81.64 R11.2 ; C51.1 89.89,77 89.89,78.81 C52.1 89.43,79.63 v2(89.66,79.86) ; v2(66.25,78.79) 65.44,77.98 R682.2 ; Q103.1 65.24,95.41 v2(65.66,95.83) ; R12.2 120.14,88.07 121.06,87.16 v2(121.99,87.16) ; R700.2 113.99,34.02 v2(114.6,33.42) ; U74.1 63.02,78.59 C566.1
  BOTTOM w0.254: v2(81.82,82.9) 81.05,82.9 C53.1 C54.1
  BOTTOM w0.305: R112.1 64.19,80.15 v2(63.59,79.55) C566.1 59.67,81.94 v2(59.67,84.62) ; R202.1 R203.1 v2(150.52,99.16) ; R650.2 R117.2 v2(62.01,90.22)
+V1.35_CRT: length 1.3
  TOP w0.254: U1.BD1 76.45,99.04 v2(76.02,99.46)
+V1.35S: length 120.2
  TOP w0.203: U1.AG18 v2(84.17,89.72) U1.AJ19
  TOP w0.406: R452.1 83.38,106.56 R676.1 v2(82.6,107.19)
  LAY3 w0.305: v2(46.74,95.47) 45.01,93.75 36.23,93.75 32.27,97.71 29.53,97.71 v2(28.65,96.83) ; v2(82.6,107.19) 82.34,106.92 71.23,106.92 v2(71.2,106.89)
  LAY4 w0.305: v2(71.2,106.89) 58.15,106.89 v2(46.74,95.47) ; v2(28.87,45.6) 28.68,45.79 28.68,58.78 29.04,59.14 29.04,62.08 28.5,62.62 28.5,68.4 29,68.89 29,70.08 28.17,70.91 28.17,96.35 v2(28.65,96.83)
  BOTTOM w0.305: R119.1 70.33,106.02 v2(71.2,106.89) ; R378.2 28.3,45.03 v2(28.87,45.6)
+V3.3A: length 852.7
  TOP w0.152: U6.11 120.18,77.7 C21.1 120.51,78.46 120.66,78.61 120.66,80.13 121.42,80.89 121.42,81.79 v2(120.99,82.22) ; U56.7 v2(116.91,116.9)
  TOP w0.203: v2(58.6,93.1) 58.6,95.25 64.51,101.16 R56.2 ; v2(56.69,62.74) 61.71,62.74 62.47,61.98 R130.1 ; R531.1 v2(109.65,122.41)
  TOP w0.254: CN34.5 141.29,12.07 v1(141.55,12.33) 141.79,12.09 CN34.6
  TOP w0.305: R34.2 68.16,70.03 67.35,69.21 58.81,69.21 v2(56.98,67.37) ; R570.2 13.96,65.52 ; v2(44.86,64.26) 48.79,60.33 52.52,60.33 52.86,59.99 53.96,59.99 R132.2 54.27,59.29 54.67,58.89 57.36,58.89 57.93,59.46 57.93,61.6 57.52,62.01 U7.1 55.66,62.01 C128.1 55.68,62.74 v2(56.69,62.74) ; R558.2 24.96,60.92 v2(24.96,60.92) ; R358.1 119.49,105.49 v2(119.49,106.7) 119.03,107.15 116.91,107.15 116.03,106.27 C560.2 C561.1 U73.5 ; v2(137.55,71.79) 138.97,71.79 139.47,71.29 v2(147.71,71.29) ; R537.2 114.7,122.36 v2(114.57,122.48) 114.57,122.63 115.16,123.21 116.33,123.21 117.03,122.5 v2(117.03,122.4) R513.1
  LAY3 w0.203: v2(2.83,104.96) 5.06,107.19 v2(5.06,107.21) 7.16,107.21 v2(8.27,108.33)
  LAY3 w0.305: v2(56.69,62.74) 56.98,63.03 v2(56.98,67.37) ; 104.05,18.44 100.21,22.28 93.52,22.28 v2(92.6,21.36) ; v2(9.66,103.46) 10.63,104.43 11.58,104.43 14.78,107.62 v2(14.78,108.33) ; v2(12.19,84.72) 13.36,84.72 18.41,89.77 21.74,89.77 v2(22.46,90.49) ; v2(29.5,83.94) 28.49,84.95 14.73,84.95 12.22,82.44 12.22,74.67 v1(16.58,70.31) ; v2(24.96,60.92) 23.49,60.92 16.58,67.83 v1(16.58,69.53)
  LAY3 w0.406: v2(108.23,20.8) 107.44,20.01 105.63,20.01 104.05,18.44 ; v2(147.71,71.29) 147.71,82.31 149.34,83.94 149.34,91.99 v2(148.56,92.77)
  LAY3 w0.508: v1(141.55,12.33) 140.36,12.33 138.23,10.2 134.99,10.2 133.15,8.36 114.14,8.36 104.05,18.44 ; v1(72.62,42.25) 83.31,42.25 v2(85.51,40.05) ; v2(147.71,71.29) v2(147.71,61.98) 147.71,58 145.58,55.87 145.58,50.97 145.29,50.68 v1(145.29,41.84) ; v2(34.1,127.32) 33.18,128.24 23.81,128.24 22.89,127.32 15.01,127.32 11.33,123.64 11.33,111.21 8.45,108.33 v2(8.27,108.33)
  LAY3 w0.762: v1(141.55,12.33) 144.52,15.3 144.52,19.04 142.68,20.88 142.68,25.49 144.64,27.45 144.64,30.8 142.56,32.89 142.56,39.12 v1(145.29,41.84)
  LAY4 w0.305: 120.2,88.56 120.55,88.56 ; v2(114.57,122.48) 114.57,122.66 114.07,123.16 110.56,123.16 109.81,122.41 v2(109.65,122.41) 98.35,122.41 97.51,123.25 92.35,123.25 v2(91.13,122.03) ; v2(120.99,82.22) 120.74,82.22 120.41,82.54 120.41,83.49 121.7,84.78 121.7,86.18 120.2,87.68 120.2,88.2 ; v2(132.9,55.73) 133.09,55.73 133.38,56.03 133.38,57.12 132.78,57.73 129.05,57.73 128.21,58.56 128.21,60.07 v2(128.43,60.28) ; v2(116.91,116.9) 117.07,116.9 119.49,114.48 v2(119.49,106.7) ; v2(58.6,93.1) 54.86,89.36 54.86,73.82 56.98,71.71 v2(56.98,67.37)
  LAY4 w0.406: v2(128.43,60.28) 129.53,61.38 134.45,61.38 136.08,63.01 141.28,63.01 142.31,61.98 v2(147.71,61.98) ; 120.55,88.56 121.11,88.56 123.3,90.75 146.54,90.75 v2(148.56,92.77) ; 120.55,88.56 120.2,88.91 ; 120.55,88.56 120.2,88.2 120.2,88.91 ; 120.2,88.91 120.16,88.95 120.16,93.46 122.03,95.33 122.03,104.95 120.28,106.7 v2(119.49,106.7)
  LAY4 w1.016: v1(24.55,126.23) 24.55,131.67 26.41,133.54 62.52,133.54 65.12,130.94 93.35,130.94 95.31,132.89 108.23,132.89 111.04,130.08 120.47,130.08 121.16,130.78 134.98,130.78 137.7,133.5 145.26,133.5 148.95,129.8 148.95,121.53 149.81,120.67 v1(149.81,112.38)
  BOTTOM w0.152: C424.1 32.4,64.96 30.76,64.96 30.22,64.43 30.22,63.68 31.18,62.72 R483.1 ; v2(91.13,122.03) 91.13,122.08 92.3,123.25 92.3,126.37 91.51,127.16 R504.1 ; v2(91.13,122.03) 91.13,121.59 91.96,120.75 91.96,117.15 R495.1 ; v2(91.13,122.03) 89.63,122.03 89.25,121.65 R454.1 ; v2(5.06,107.21) 5.06,107.21 5.05,107.21 ; R469.2 R471.1 111.14,69.75 115.89,65 123.71,65 v2(128.43,60.28) ; U79.8 3.65,101.25 C726.2 3.01,101.12 2.83,101.3 v2(2.83,104.96) ; R212.2 70.07,45.76
  BOTTOM w0.203: U39.5 C331.1 14.34,100.35 ; U40.5 14.11,100.58 ; 14.11,100.58 14.11,100.56 ; 14.11,100.58 14.34,100.35 ; R488.1 R498.1 32.13,48.39 31.41,47.68 v2(30.43,47.68) R376.2 ; 14.11,100.35 14.11,100.56 ; 14.11,100.35 13.9,100.35 ; 14.11,100.35 14.34,100.35 ; 14.11,100.56 13.9,100.35 ; v2(5.06,107.21) 5.05,107.21 R728.2 ; 13.9,100.35 13.01,100.35 12.81,100.56 C332.1 ; v2(8.27,108.33) 8.28,108.33 C324.1 U34.5 ; U38.5 C329.1 ; U36.5 10.24,103.92 C321.1 ; U58.5 C505.1 ; U37.5 C326.1 16.61,108.33 v2(14.78,108.33)
  BOTTOM w0.305: U27.11 C287.1 111.81,31.79 111.82,31.79 112,31.61 112,30.08 114.3,27.78 114.3,27 111.4,24.09 111.4,24.13 111.05,24.47 108.59,24.47 108.31,24.19 C285.1 107.97,23.64 U26.11 ; v2(29.5,83.94) R424.2 30.49,83.61 30.49,83.04 29.81,82.36 27.97,82.36 26.03,84.31 U42.7 ; v2(22.46,90.49) 23.27,91.29 R390.2 ; 38.32,63.94 38.78,63.94 ; 38.78,63.94 38.52,63.68 ; 38.78,63.94 38.87,64.03 ; R474.1 132.84,53.87 R503.1 133.67,53.99 134.1,54.42 R500.2 133.44,55.73 v2(132.9,55.73) 132.74,55.89 R477.1 ; v2(9.66,103.46) 9.79,103.46 C321.1 C329.1 13.02,103.92 13.33,103.6 13.33,101.6 C332.1 ; v2(117.03,122.4) 117.01,122.4 116.53,121.93 116.53,117.28 v2(116.91,116.9) ; R670.1 84.39,38.15 83.69,38.15 83.27,37.73 83.27,37.08 83.62,36.74 83.62,33.41 84.68,32.35 85.95,32.35 R340.1 ; v1(115.96,44.97) 114.61,46.32 R81.1 R327.1 ; R448.2 C767.1 v2(56.98,67.37) ; R338.1 85.28,28.7 85.28,23.99 88.43,20.84 92.08,20.84 v2(92.6,21.36) ; R462.2 137.64,71.7 v2(137.55,71.79) ; 38.87,64.03 38.87,63.56 ; 38.87,64.03 39.65,64.81 44.31,64.81 v2(44.86,64.26) ; v2(37.1,42.54) 38.3,41.33 C505.1
  BOTTOM w0.406: v2(108.23,20.8) 109.97,20.8 111.4,22.23 111.4,24.09
  BOTTOM w0.508: v2(72.13,46.78) C188.1 69.79,46.78 ; D1.P 34.57,127.78 v2(34.1,127.32) ; R670.1 85.51,39.27 v2(85.51,40.05)
  vias: v1(17.34,70.31) v1(17.34,69.53) v1(18.11,70.31) v1(18.1,69.53) v1(37.23,63.7) v1(44.16,40.47) v1(44.16,39.7) v1(50.12,40.13) v1(130.84,42.95) v2(37.16,63.02)
+V3.3A_KBC: length 155.5
  TOP w0.406: v2(118.15,45.13) 117.03,44.01 100.96,44.01 v2(99.84,45.14)
  LAY3 w0.508: v2(106.54,39.42) 106.54,39.45 106.14,39.05 v2(101.88,39.05) v2(99.48,39.05) v2(96.68,39.05) v2(91.22,39.05) 88.01,39.05 v2(86.34,40.72)
  LAY4 w0.203: v2(101.88,30.92) 105.15,27.65 110.85,27.65 111.38,27.12 112.22,27.12 112.53,27.44 v2(112.53,27.55)
  LAY4 w0.305: v2(106.54,39.42) 107.08,38.89 v2(107.08,35.5) ; v2(98.67,45.14) v2(99.84,45.14)
  LAY4 w0.33: v2(93.59,45.54) 94.61,44.53 98.06,44.53 v2(98.67,45.14)
  BOTTOM w0.203: 95.43,47.26 95.43,47.26 95.69,47.52 ; 95.43,47.26 95.43,47.52 ; 95.43,47.26 95.43,45.14 95.72,44.84 R300.1 ; 95.43,47.26 95.17,47.52 ; 95.43,47.52 95.17,47.52 ; 95.43,47.52 95.69,47.52 ; v2(96.68,39.05) U28.114 ; v2(99.48,39.05) U28.121 ; v2(91.22,39.05) 90.78,38.61 U28.92 ; R299.1 93.36,45.26 93.59,45.49 v2(93.59,45.54) 93.59,46.98 94.12,47.52 95.17,47.52 ; U28.26 102.6,30.21 101.89,30.93 v2(101.88,30.92) 98.96,30.92 95.48,27.44 U28.50 ; 95.69,47.52 96.16,47.52 96.78,46.9 R296.1 ; Q69.1 112.15,27.03 112.53,27.41 v2(112.53,27.55) ; U28.127 v2(101.88,39.05)
  BOTTOM w0.305: R302.1 98.71,45.1 v2(98.67,45.14) ; R333.2 v2(107.08,35.5) ; R315.1 v2(99.84,45.14) ; U70.1 82.26,40.88 ; R297.1 97.85,46.63 R296.1
  BOTTOM w0.406: v2(101.88,30.92) 101.88,32.04 101.88,32.04 v2(101.88,39.05)
  BOTTOM w0.508: C570.1 R689.2 126.21,48.72 125.27,47.79 L17.2 L16.2 118.66,47.56 C572.2 C571.2 v2(118.15,45.13) 118.15,43.57 115.06,40.49 107.23,40.49 106.91,40.16 R290.1 v2(106.54,39.42) ; FB13.1 83.89,30.51 C282.2 83,31.4 83,36.45 82.52,36.93 R657.2 82.52,38.92 83.13,39.53 83.13,40.67 ; R334.2 81.58,42.02 82.28,41.32
+V3.3A_RTC: length 240.5
  TOP w0.203: U1.P22 v2(91.29,88.48) ; v2(106.36,97.23) R65.2 R68.1
  TOP w0.254: v2(107.2,93.51) 108.09,94.4 108.09,95.16 108.61,95.68 108.61,96.35 108.28,96.68 106.85,96.68 106.36,97.17 v2(106.36,97.23)
  LAY3 w0.254: v2(130.01,49.83) 129.63,50.22 129.63,51.11 130.56,52.04 130.56,60.48 129.65,61.39 129.65,68.26 127.39,70.52 127.39,72.7 124.89,75.2 120.84,75.2 120.47,75.57 120.47,88.8 120.72,89.06 v2(120.72,89.72) 120.73,89.72 116.94,93.51 v2(107.2,93.51)
  LAY4 w0.254: v2(91.29,88.48) 91.29,88.5 92.43,89.63 96.52,89.63 96.92,90.04 98.95,90.04 99.68,90.76 99.68,94.06 102.2,96.58 103.94,96.58 104.87,97.51 106.08,97.51 v2(106.36,97.23)
  LAY4 w0.305: v2(89.14,124.13) 89.82,123.45 91.81,123.45 92.03,123.68 114.37,123.68 115.07,122.99 115.07,122.28 118.32,119.02 118.32,118.3 122.61,114.02 122.61,94.87 120.72,92.99 v2(120.72,89.72) ; v2(130.01,49.83) 126.01,45.83 115.69,45.83 111.96,42.09 v2(111.96,41.1)
  BOTTOM w0.254: D1.N 40.19,127.78 D2.N 40.2,129.24 C9.2 40.19,130.32 41.25,131.39 60.48,131.39 63.76,128.11 85.46,128.11 89.14,124.42 v2(89.14,124.13) ; C597.2 92.34,89.53 v2(91.29,88.48)
  BOTTOM w0.305: v2(111.96,41.1) 106.71,41.1 R291.1
+V3.3A_SOC: length 11
  TOP w0.203: U1.P18 v2(91.29,90.39) U1.N18 ; U1.N22 v2(91.29,87.49)
  TOP w0.305: v2(109.43,96.9) 109.59,96.75 111.34,96.75 113.85,99.25 C548.2 U73.1
+V3.3A_WIFI: length 57.1
  TOP w0.406: CN12.2 v2(44.58,31.93) ; CN12.52 41.66,55.13 v2(41.66,55.13) ; v2(44.45,43.93) CN12.24 ; CN12.39 v2(49.85,49.93) ; CN12.41 v2(49.86,50.73)
  TOP w0.508: v2(44.45,43.93) 46.05,45.53 46.05,51.18 v2(44.56,52.67) 44.56,52.67 44.56,55.81 43.07,57.31 41.78,57.31 v1(41.75,57.34)
  BOTTOM w0.406: 44.56,53.65 44.56,54.09 ; 44.56,53.65 45,54.09 ; 44.56,53.65 44.56,52.67 v2(44.56,52.67) ; 44.56,54.09 45,54.09 ; 44.56,54.09 42.45,56.21 C263.1 C264.2 v2(41.66,55.13) ; 45,54.09 48.11,54.09 50.47,51.73 C269.2 49.87,50.72 v2(49.86,50.73) ; C268.2 v2(44.45,43.93) 45.36,43.01 45.36,38.51 43.94,37.09 43.94,34.81 45.46,33.29 Q66.1 45.68,32.9 45.27,32.49 C265.2 v2(44.58,31.93) ; v2(49.85,49.93) C270.2
  BOTTOM w0.508: C270.2 50.47,49.93 C269.2
+V3.3AVCC: length 2.6
  BOTTOM w0.203: U28.74 87.05,31.41 C283.1 86.7,31.26 FB13.2
+V3.3S: length 561.3
  TOP w0.152: v2(120.97,82.87) 121.75,82.09 121.75,80.61 121.29,80.14 R84.2 ; v2(65.07,98.21) R630.1 R631.1
  TOP w0.203: v2(65.56,91.27) 65.71,91.41 R729.2 ; v2(66.23,96.79) 66.55,97.12 C519.1 66.6,97.41 67.32,98.13 U65.8 ; U1.AN24 v2(81.8,87.44)
  TOP w0.254: U14.13 v2(141.98,100.61) ; U14.15 v2(141.97,103.61) ; v2(62.68,55.96) CN3.199 ; v1(39.51,126.24) 38.68,126.24 34.71,130.21 27,130.21 25.4,131.8 18.58,131.8 18.01,131.23 R133.1
  TOP w0.305: v2(25.61,33.41) 25.61,33.07 25.33,32.79 U63.5 ; v1(8.81,15.06) 10.44,15.06 10.91,14.59 R437.1 10.91,13.66 11.19,13.38 CN13.1 ; v2(11.94,32.66) 11.94,32.67 R710.1 ; v2(149.93,90.59) 149.13,91.4 v2(149.13,94.77) ; v2(39.89,104.83) 39.89,104.82 R559.2
  TOP w0.406: v2(63.25,126.33) 63.25,124.89 62.1,123.74 61.59,123.74 FB16.1 ; v2(68.41,113.16) 66.83,111.58 66.83,111.53 v2(66.13,110.83)
  TOP w0.508: R625.2 9.38,110.15 v2(9.5,110.28) ; v2(66.13,110.83) 61.3,106 57.39,106 53.48,102.09 v2(53.48,98.33) ; 141.97,110.18 142.53,110.75 ; 141.97,110.18 v2(141.97,106.05) ; 141.97,110.18 141.97,110.56 142.15,110.75 ; v1(17.06,44.37) 16.24,43.54 R628.2
  TOP w1.016: v1(137.92,128.33) 137.92,127.4 141.78,123.54 141.78,111.12 142.15,110.75 v1(145.31,110.75)
  LAY3 w0.203: v2(81.8,87.44) 80.47,87.44 80.05,87.02 69.22,87.02 67.31,88.93 67.31,89.98 67.68,90.35 67.68,91.16 67.4,91.44 65.73,91.44 v2(65.56,91.27)
  LAY3 w0.305: v2(41.7,48.46) 39.81,48.46 32.31,40.96 v2(27.09,40.96)
  LAY3 w0.406: v2(122.35,36.2) 122.35,35.96 119.6,33.21 v2(118.47,33.21) ; v2(149.13,103.45) v2(149.13,100.11) v2(149.13,94.77)
  LAY3 w0.508: v2(101.57,48.26) 102.55,49.24 119.22,49.24 124.45,44.01 124.45,38.3 v2(122.35,36.2)
  LAY4 w0.305: v2(120.97,82.87) 122.54,82.87 129.29,89.62 148.96,89.62 v2(149.93,90.59) ; v2(49.87,36.59) 49.73,36.73 45.61,36.73 43.29,39.04 43.29,46.87 v2(41.7,48.46)
  LAY4 w0.406: v2(141.97,106.05) 146.53,106.05 v2(149.13,103.45)
  LAY4 w0.762: v1(20.83,29.72) 20.83,29.72 20.83,27.92 31.35,17.41 49.99,17.41 52.4,19.82 52.4,22.36 57.9,27.85 63.26,27.85 65.36,29.95 81.02,29.95 83.69,27.28 83.69,25.41 88.98,20.12 92.75,20.12 93.81,21.18 v1(94.37,21.18)
  BOTTOM w0.152: R590.1 33.4,45.39 R637.1
  BOTTOM w0.203: R750.1 13.23,35.66 v2(13.35,35.53) ; v2(120.97,82.87) 120.5,82.4 120.5,79.24 R579.1 ; U74.8 63.02,76.69 62.86,76.53 62.86,76.09 C567.1 ; v2(49.87,36.59) 49.96,36.5 R217.2 ; R590.1 29.77,45.49 v2(29.3,45.02) ; 117.16,37.86 117.16,37.89 116.85,38.2 CN14.1 ; CN14.2 117,37.7 117.16,37.86
  BOTTOM w0.254: 115.16,33.72 115.36,33.52 115.36,31.44 115.6,31.2 CN14.15 117.04,31.2 ; 117.04,31.2 117.11,31.2 117.32,31.41 ; 117.04,31.2 117.32,30.92 ; CN14.18 116.86,29.7 117.32,30.16 117.32,30.92 ; 116.97,31.7 117.32,32.05 117.32,31.41 ; 116.97,31.7 CN14.14 ; 116.97,31.7 117.03,31.7 117.32,31.41 ; 117.32,31.41 117.32,30.92 ; C506.1 v2(81.8,87.44)
  BOTTOM w0.305: v2(141.97,106.05) 141.97,106.05 v2(141.97,103.61) 141.98,103.59 v2(141.98,100.61) ; v2(62.68,55.96) 62.52,56.12 62.52,56.17 ; 8.1,15.87 R20.1 ; 8.1,15.87 v1(8.1,15.06) ; 8.1,15.87 7.64,15.4 ; 8.1,15.87 8.11,15.87 8.48,15.5 ; R116.2 61.57,90.77 61.34,90.54 61.34,90.1 62.17,89.27 R649.2 ; R116.2 61.57,91.47 61.99,91.89 64.94,91.89 v2(65.56,91.27) ; R116.2 60.66,91.16 60.05,91.78 v2(60.05,94.71) 60.05,95.69 61.76,97.4 62.81,97.4 R730.2 64.32,96.81 64.8,97.29 64.8,97.93 v2(65.07,98.21) 65.74,98.21 66.23,97.72 v2(66.23,96.79) ; 74.46,49.21 74.46,49.21 74.84,49.58 ; 74.46,49.21 74.46,49.54 74.42,49.58 ; 74.46,49.21 74.08,49.58 ; 74.46,49.21 C292.2 74.59,44.89 U29.5 ; v1(145.31,110.75) 145.14,110.92 R201.1 ; U22.5 111.47,13.99 111.47,12.65 R243.2 113.21,12.33 115.35,14.46 115.35,14.92 ; D7.P 112.01,36.53 112.54,36 112.54,35.02 113.16,34.4 114.48,34.4 115.16,33.72 ; R271.1 119.59,19.49 R270.1 119.75,19.49 120.13,19.11 120.13,15.84 119.62,15.33 118.84,15.33 118.38,15.79 117.42,15.79 116.87,15.24 U24.5 116.87,14.92 C262.2 115.88,14.92 115.35,14.92 ; 117.16,37.86 117.16,37.86 120.68,37.86 v2(122.35,36.2) ; D6.2 v2(149.13,94.77) ; R269.1 114.9,15.37 115.35,14.92 ; v2(66.46,75.48) 65.66,74.67 R684.1 R683.1 62.87,75.46 C567.1 ; Q9.1 v2(149.13,103.45) ; Q10.1 v2(149.13,100.11)
  BOTTOM w0.406: FB3.2 66.13,112.36 v2(66.13,110.83) ; v2(68.41,113.16) 68.89,113.64 68.89,120.65 63.25,126.3 v2(63.25,126.33) ; 117.32,32.05 v2(118.47,33.21)
  BOTTOM w0.508: v2(21.6,29.68) 21.6,30.2 22.78,31.38 23.46,31.38 24.22,32.15 R661.1 25.58,32.77 R703.1 25.58,33.39 v2(25.61,33.41) ; R207.1 76.43,49.58 77.74,48.27 101.56,48.27 v2(101.57,48.26)
  BOTTOM w0.762: R207.1 66.14,49.58 65.57,49.02 61.68,49.02 61.25,49.45 R121.2 61.25,54.9 62.52,56.17 C102.2 C101.2 62.52,57.86 62.14,58.23 62.14,60.56 62.64,61.06 v1(62.64,62.8) ; v1(94.37,21.18) 101.47,21.18 103.33,19.32 103.33,17.68 105.43,15.58 C238.2
  vias: v1(13.49,110.2) v1(19.36,66.14) v1(20.12,66.14) v1(20.88,66.14) v1(39.54,125.39) v2(14.11,110.18) v2(19.73,65.68) v2(20.5,65.67) v2(40.17,126.29)
+V3.3S_AUDIO: length 46.5
  TOP w0.305: R685.1 129.94,26.79 v2(129.27,27.46) ; v2(133.55,15.71) 133.55,10.43 v2(133.58,10.4)
  LAY3 w0.305: v2(123,20.05) 123,16.56 v2(122.16,15.72)
  LAY4 w0.203: v2(123,20.05) 123.9,20.94 123.9,23.7 127.66,27.46 v2(129.27,27.46)
  LAY4 w0.406: v2(133.55,15.71) 133.54,15.72 122.21,15.72
  LAY4 w0.508: v2(112.62,16.72) 112.62,16.72 114.32,15.02 121.47,15.02 v2(122.16,15.72) 122.21,15.72
  BOTTOM w0.203: 133.03,16.31 U23.36
  BOTTOM w0.305: FB8.2 133.59,10.39 v2(133.58,10.4) ; v2(122.16,15.72) FB10.1 ; R258.2 v2(123,20.05)
+V5_AVDD: length 5.5
  TOP w0.305: R268.2 R267.2 134.34,23.78 v2(134.56,23.56)
  BOTTOM w0.102: U23.26 132.44,20.31
  BOTTOM w0.203: 133.21,20.91 133.21,20.81 132.71,20.31 132.44,20.31
  BOTTOM w0.508: 133.61,23.44 C239.2 133.61,21.89 133.21,21.49 133.21,20.91
+V5_PVDD: length 23.1
  BOTTOM w0.203: 130.23,14.71 130.09,14.85 U23.41 ; U23.46 128.09,14.96 127.89,14.76
  BOTTOM w0.508: 127.89,14.76 127.41,14.28 C251.2 127.39,13.97 126.82,13.41 126.34,13.41 125.46,12.53 124.19,12.53 ; 130.23,14.71 130.75,14.2 C247.2 130.62,13.99 130.12,13.48 130.12,12.24 C252.1 130.88,11.08 128.44,8.63 123.64,8.63 123.01,9.25 123.01,12.05
+V5A: length 448.6
  TOP w0.203: C429.2 55.65,83.78 U51.4 ; C441.2 93.52,109.99 93.57,109.94 U54.4
  TOP w0.254: v2(49.14,129.79) 47.95,128.61 C134.2 47.95,127.84 47.17,127.84 U8.4
  TOP w0.305: R562.2 142.52,63.87 v2(142.26,63.6) ; v2(118.14,110.25) 118.14,110.8 R514.2 ; R366.1 132.05,72.65 ; v1(16.55,63.33) C500.2 16.55,64.79 U68.4 ; C429.2 v2(53.08,83.02) ; v2(117.38,87.06) 117.72,86.72 C19.2 117.72,85.61 U5.4
  TOP w0.406: 93.52,112.08 93.52,116.53 90.93,119.12 v2(90.93,120.8) ; 93.52,112.08 93.77,111.83 ; 93.52,112.08 93.52,111.85 ; v2(95.89,111.83) 93.77,111.83 ; 93.77,111.83 93.77,111.79 93.52,111.54 ; 93.77,111.83 93.54,111.83 93.52,111.85 ; 93.52,111.54 C441.2 ; 93.52,111.54 93.52,111.85
  TOP w0.508: 145.47,118.44 145.1,118.07 ; 145.47,118.44 145.47,117.7 ; 145.47,118.44 148.01,120.98 v2(148.01,129.46) ; 145.1,118.07 145.26,117.91 145.26,117.91 145.47,117.7 ; 145.1,118.07 144.74,117.7 ; 145.47,117.7 v2(147.35,115.82) ; 145.47,117.7 144.74,117.7 ; 40.57,118.55 41.04,118.08 ; 41.04,118.08 v2(45.42,118.08) ; 41.04,118.08 41,118.08 40.45,117.52 ; 144.74,117.7 v2(143.61,116.58)
  LAY3 w0.305: v2(95.89,111.83) 97.47,110.25 v2(118.14,110.25)
  LAY3 w0.406: v2(29.53,91) 26.9,91 v2(26.03,90.12)
  LAY4 w0.203: 117.66,74.78 117.66,74.78 117.42,74.78 ; 117.66,74.78 117.66,75.04 ; 117.66,74.78 117.66,74.54 ; v2(117.38,87.06) 117.38,83.68 116.42,82.72 116.42,79.78 117.66,78.54 117.66,75.04 ; 120.87,66.81 120.87,71.33 117.66,74.54 ; v2(112.18,75.77) 113.16,74.78 117.4,74.78 ; 117.66,75.04 117.4,74.78 ; 117.42,74.78 117.4,74.78 ; 117.42,74.78 117.66,74.54
  LAY4 w0.305: v2(48.18,63.15) 48.46,63.43 v2(48.46,66.82) ; v2(119.64,66.81) 120.87,66.81 125.46,62.23 v2(128.92,62.23) ; v2(133.93,63.13) 135.44,64.63 141.23,64.63 v2(142.26,63.6)
  LAY4 w0.406: v2(128.92,62.23) 130.34,63.65 131.73,63.65 132.25,63.13 v2(133.93,63.13) ; v2(90.93,120.8) v2(83.24,120.8)
  LAY4 w0.508: v2(45.42,118.08) 47.6,120.26 59.58,120.26 60.31,120.99 64.03,120.99 64.7,121.66 69.89,121.66 71.55,120 80.89,120 81.7,120.8 v2(83.24,120.8) ; v2(25.86,130.52) 25.85,130.52 25.85,131.61 26.52,132.27 61.26,132.27 63.94,129.6 67.97,129.6 68.38,129.19 93.52,129.19 93.96,129.64 109.26,129.64 109.85,129.05 120.93,129.05 121.61,129.72 136.08,129.72 137.96,131.6 144.56,131.6 146.7,129.46 v2(148.01,129.46)
  LAY4 w1.016: v1(48.19,21.51) 47.51,22.18 46.1,22.18 v1(41.17,27.11)
  BOTTOM w0.203: U45.4 76.4,113.98 76.4,114.21 ; U48.4 112.89,74.18 C417.2 112.18,74.89 v2(112.18,75.77) ; v2(126.21,54.84) 126.69,54.84 C562.1 U49.10 ; v2(119.64,66.81) 119.64,66.56 119.89,66.31 121.09,66.31 121.23,66.46 C410.2 121.23,66.83 U46.4 ; U43.12 51.24,65.38 50.98,65.64 50.98,65.99
  BOTTOM w0.254: C411.1 134.77,63.57 134.77,64.77 134.62,64.93 U47.10 ; U42.24 26.03,89.31 ; v2(83.24,120.8) 83.24,126.27 82,127.52 63.38,127.52 61.11,129.79 49.9,129.79 v2(49.14,129.79)
  BOTTOM w0.305: v2(147.35,115.82) 147.27,115.9 R739.1 ; v2(128.92,62.23) 128.92,62.25 128.1,63.07 D26.P ; C510.2 69.88,43.99 U16.4 ; 49.38,19.82 49.38,19.48 ; 49.38,19.48 49.64,19.74 ; 49.38,19.48 R375.1 ; R371.1 143.54,50.36 ; v2(95.89,111.83) 95.89,111.83 C436.1 U53.10 ; v2(133.93,63.13) 134.33,63.13 C411.1 ; R461.2 132.47,71.99 132.47,72.59 v2(132.47,72.59) ; v2(90.93,120.8) 90.57,120.45 C401.2 89.36,120.45 88.6,120.45 U44.4 ; v2(48.46,66.82) 48.56,66.82 48.57,66.82 C388.2 50.16,66.82 50.3,66.68 50.3,66.68 50.98,65.99 ; R721.1 149.06,129.03 148.63,129.46 v2(148.01,129.46) ; 76.4,114.21 C402.2 76.4,115.58 76.4,115.83 77.78,117.21 82.2,117.21 83.24,118.25 v2(83.24,120.8) ; R742.2 v2(143.61,116.58) ; U50.10 C565.1 36.91,62.19 v2(37.23,61.88) 37.8,61.3 37.8,54.64 37.22,54.06 33.66,54.06 C431.1 32.89,51.95 U52.10
  BOTTOM w0.406: 32.12,103.26 31.88,103.03 ; 32.12,103.26 31.46,103.26 ; 32.12,103.26 32.12,102.61 ; v2(29.53,91) 29.53,91 R423.1 34.75,95.51 ; 34.98,95.74 34.75,95.51 ; 34.75,95.51 35.76,95.51 ; 34.75,95.51 34.75,96.24 34.75,96.24 ; 26.03,89.31 v2(26.03,90.12) ; C510.2 69.57,42.98 v2(69.57,42.97)
  BOTTOM w0.508: v2(36.28,114.53) 36.28,112.9 37.11,112.07 37.11,108.25 32.12,103.26
  vias: v1(18.98,44.37) v1(36.13,95.74) v1(36.17,95) v1(36.94,95.73) v1(36.94,94.99) v1(37.72,95.75) v1(37.71,95.01) v1(38.48,95.74) v1(38.47,94.98) v1(50.29,56.18) v1(69.21,42.47) v1(69.94,42.48) v2(16.03,63.84) v2(18.87,44.97) v2(53.3,56.26) v2(53.63,56.6) v2(53.74,56.13) v2(132.94,72.58) v2(133.41,72.56) v2(143.14,49.91) v2(143.14,49.42)
+V5S: length 422.2
  TOP w0.305: v1(26.03,129.26) 24.95,129.26 23.12,127.43 23.12,126.03 22.39,125.3 R134.1
  TOP w0.508: v2(16.6,128.08) 16.59,128.07 FB1.2 ; R627.2 v2(9.5,111.1) ; v1(14.35,45.02) 14.05,44.71 R660.2
  LAY3 w0.305: v2(56.14,64.62) 56.25,64.73 56.25,69.1 57.89,70.74 57.89,81.81 56.25,83.45 56.25,91.62 v2(59.37,94.73)
  LAY3 w0.508: v2(16.6,128.08) 16.68,128.16 22.28,128.16 23.37,129.26 v1(26.03,129.26) ; v1(137.69,25.43) 129.15,25.43 126.05,22.33 111.19,22.33 109.04,20.18 v1(109.04,19.62)
  LAY3 w0.635: 138.78,115.42 138.78,100.25 140.21,98.82 v1(140.21,93.16)
  LAY3 w0.762: 138.78,115.42 135.89,118.31 128.76,118.31 119.97,127.1 110.68,127.1 108.94,128.84 97.27,128.84 95.77,127.34 65.97,127.34 v1(64.52,128.8)
  LAY4 w0.305: v2(44.27,85.44) 43.68,86.02 43.68,87.09 51.33,94.73 v2(59.37,94.73) ; v2(84.76,37.39) 84.76,37.83 83.84,38.75 68.24,38.75 67.04,39.95 52.95,39.95 51.61,41.29 51.61,42.12 47.11,46.62 45.91,46.62 43.28,49.25 43.28,57.96 44.86,59.55 44.86,62.14 v2(44.26,62.74)
  LAY4 w0.406: v2(44.27,85.44) 44.26,85.44 v2(44.26,62.74)
  LAY4 w0.635: v1(109.04,19.62) 107.82,19.62 107.5,19.94 v2(94.63,19.94)
  BOTTOM w0.203: 119.49,9.37 119.49,10.34 119.92,10.77 119.92,11.73 119.22,12.43 ; 119.49,9.37 119.49,9.36 ; 119.49,9.37 119.33,9.21 ; R237.2 119.65,9.21 ; 119.65,9.21 119.49,9.36 ; 119.65,9.21 119.49,9.21 ; 119.49,9.36 119.49,9.21 ; 119.33,9.21 118.97,9.21 R236.2 ; 119.33,9.21 119.49,9.21 ; v2(44.26,62.74) 43.67,62.14 C513.2 43.45,62.06 U60.4
  BOTTOM w0.305: R384.1 v2(56.14,64.62) ; R743.2 3.54,122.97 3.54,122.96 ; v2(7.53,103.44) 7.98,102.99 R386.1 ; v1(109.04,19.62) 108.97,19.54 U20.4 ; R235.2 137.74,25.89 ; v2(84.76,37.39) 85.31,36.84 R310.1 R316.1
  BOTTOM w0.508: U84.5 5.19,123.92 C619.1 C618.2 3.54,122.96 3.54,109.84 v2(3.54,109.84) ; v2(44.27,85.44) 39.73,89.97 39.73,96.41 35.63,100.51 v1(35.63,104.05)
  BOTTOM w0.762: v1(64.52,128.8) 61.31,132 38.84,132 36.84,130 v1(36.84,129.2)
  BOTTOM w1.27: v1(94.04,19.94) v2(94.63,19.94) 100.21,19.94 101.48,18.67 101.48,15.12 106.39,10.2 112.81,10.2 115.66,13.05
  BOTTOM w1.524: 115.66,13.05 C222.2
  vias: v1(2.74,12.26) v1(2.74,11.5) v1(3.39,11.9) v1(6.26,77.28) v1(6.32,59.85) v1(7.08,59.85) v1(34.89,104.8) v1(34.89,104.04) v1(35.63,104.81) v1(36.36,104.8) v1(36.36,104.04) v1(37.07,104.8) v1(37.07,104.03) v1(38.39,128.64) v1(39.14,128.65) v2(6.25,76.66) v2(6.25,76.1) v2(39.72,128.51)
+V5S_CAM: length 4.6
  TOP w0.508: J3.1 12.45,123.92 v2(12.45,123.92)
  BOTTOM w0.508: U84.1 C622.2 C621.2 v2(12.45,123.92)
+V5S_HDMI: length 7.6
  LAY4 w0.305: v2(147.44,100.11) 144.88,100.11 v1(142.77,98)
  BOTTOM w0.305: v2(147.44,100.11) 147.44,100.11 R205.1 R204.1
+V15A: length 1.5
  TOP w0.102: D25.2 22.86,85.47 C379.1
AGND: length 19.1
  TOP w0.305: v2(131.82,27.02) 132.05,26.79 Q97.2
  TOP w0.406: v3(138.65,19.16) R719.2 C584.2 138.65,16.3 C508.2 ; C509.2 138.65,22.65 C583.2 R711.2 v3(138.65,19.81) ; C389.2 v3(138.76,34.1) ; C390.2 v3(138.76,32.07)
  BOTTOM w0.203: U23.38 131.29,15.28 131.57,15 132.53,15 v2(132.67,15.15) ; U23.25 132.39,20.95 v2(132.57,21.12) ; C246.1 v2(135.93,12.36)
  BOTTOM w0.305: C230.2 v2(136.17,19.67) 136.17,19.67 135.86,19.36 C232.1 ; CN21.1 132.88,34.05 v2(133.23,34.4) CN21.E1 ; CN21.E2 v2(133.23,32.97) ; C243.1 131.52,12.83 v2(131.87,12.48) 131.88,12.49 C244.2 ; R252.2 v2(127.64,24.88)
  vias: v1(136.16,11.26) v1(136.32,22.78) v2(131.25,22.13)
AVDD2: length 7.5
  BOTTOM w0.203: U23.40 130.49,15.16 131.52,14.13 C243.2
  BOTTOM w0.305: FB9.1 FB8.1 133.59,12.79 132.52,13.85 C244.1 132.52,14 131.53,14 C243.2
AVDD33: length 3.7
  BOTTOM w0.305: 135.21,123.39 135.13,123.47 U95.4
  BOTTOM w0.508: FB20.1 138.03,122.84 C703.1 136.53,123.1 C702.2 135.5,123.1 135.21,123.39
AVDD33_REG: length 11.6
  BOTTOM w0.203: U17.35 50.96,42.38 C198.1 50.92,41.98 U17.34
  BOTTOM w0.406: R211.1 48.13,42.17 49.73,42.17 ; 49.73,42.17 C198.1 ; 49.73,42.17 C197.2
GND: length 1287.5
  TOP w0.089: 94.95,96.21 U1.F5 ; v2(81.82,81.38) 81.71,81.47 ; v2(81.82,81.38) 81.71,81.29 ; v2(81.82,81.38) 81.93,81.47 ; v2(81.82,81.38) 81.93,81.29 ; 84.25,91.1 U1.AG16 ; U1.AG16 84.25,90.92 ; U1.AG16 84.34,91.19
  TOP w0.102: U1.AN16 81.43,91.27 ; U1.AN16 81.82,91 ; U1.AN16 81.28,91.25 ; U1.AN16 81.67,91.1 ; U1.AG36 84.32,80.76 ; U1.AG36 84.32,81.24 ; U1.AG36 84.56,80.59 ; U1.AG36 84.15,81 ; 87.16,89.86 U1.AC18 ; U1.AC18 86.92,89.68 ; U1.AC18 86.53,89.96 ; U1.AC18 86.67,89.86 ; U1.AC19 86.67,89.1 ; U1.AC19 87.33,89.34 ; U1.AC19 U1.AC21 ; U1.AC19 86.5,89.34 ; U1.V16 U1.U16 ; U1.V16 89.51,91.1 ; U1.V16 89.27,91.27 ; U1.V16 89.03,91.1 ; U1.U16 89.81,90.61 ; U1.U16 90.06,91.27 ; 86.13,83.28 U1.AD32 86.13,82.86 ; 86.13,83.28 86.38,83.52 ; 86.13,83.28 85.89,83.03 ; 86.13,83.28 86.55,83.28 ; U1.AC35 87.33,81.76 ; U1.AC35 87.16,82 ; U1.AC35 86.92,82.1 ; U1.AC35 86.67,82 ; U1.AG25 84.56,86.72 U1.AG25 ; U1.AG25 84.56,85.89 ; U1.AG25 84.32,86.07 ; U1.AG25 84.15,86.31 ; U1.V19 89.51,89.58 ; U1.V19 89.69,89.34 U1.V19 ; U1.V19 89.66,89.48 ; U1.V19 89.51,89.1 ; 87.7,89 87.7,88.93 ; 87.7,88.93 U1.AA19 ; 87.7,88.93 U1.AA21 ; U1.AD21 85.72,88.58 ; U1.AD21 85.89,88.34 ; U1.AD21 86.38,88.83 ; U1.AD21 86.13,88.93 ; 89.81,88.83 U1.U21 ; U1.U21 89.67,88.73 ; U1.U21 90.06,89 ; U1.U21 90.3,88.83 ; U1.AC25 86.92,86.72 ; U1.AC25 86.67,86.07 ; U1.AC25 87.16,86.55 ; U1.AC25 86.5,86.31 ; U1.V21 88.88,88.44 U1.V21 ; U1.V21 89.51,88.83 ; U1.V21 89.66,88.73 ; U1.V21 89.03,88.34 ; 88.24,86.07 U1.Y25 ; U1.Y25 88.24,86.55 ; U1.Y25 88.1,86.16 ; U1.Y25 88.07,86.31 ; U1.AC36 87.33,81 ; U1.AC36 86.67,80.76 ; U1.AC36 86.92,80.59 ; U1.AC36 87.16,81.24 ; 89.03,81.52 U1.V35 ; U1.V35 88.88,81.62 ; U1.V35 88.86,81.76 ; U1.V35 89.03,82 ; U1.AA16 87.46,91.1 ; U1.AA16 88.12,90.86 ; U1.AA16 87.94,91.1 ; U1.AA16 87.7,91.27 ; 83.54,82 U1.AJ35 ; U1.AJ35 U1.AJ33 ; U1.AJ35 84.02,82 ; U1.AJ35 84.2,81.76 ; 86.92,82.1 U1.AC33 ; 86.92,82.1 U1.AC33 ; U1.AC33 86.5,82.52 ; U1.AC33 86.67,82.27 ; U1.AC33 86.67,82.76 ; 88.12,80.24 U1.AA38 ; U1.AA38 87.29,80.24 ; U1.AA38 87.7,80.66 ; U1.AA38 87.94,80.49 ; U1.AD33 86.13,82.1 ; U1.AD33 85.89,82.27 ; U1.AD33 85.72,82.52 ; U1.AD33 86.38,82.76 ; 85.59,83.03 U1.AF32 85.35,83.28 ; 84.02,83.79 U1.AJ30 ; U1.AJ30 84.2,84.03 ; U1.AJ30 84.02,84.28 ; U1.AJ30 84.17,84.18 ; U1.AN35 81.43,81.34 ; U1.AN35 81.01,81.76 ; U1.AN35 U1.AM35 ; U1.AN35 81.18,81.52 ; 84.02,84.55 U1.AJ29 ; U1.AJ29 84.02,85.03 ; U1.AJ29 84.17,84.94 ; U1.AJ29 84.2,84.79 ; U1.AJ16 83.37,90.86 ; U1.AJ16 83.54,90.61 ; U1.AJ16 83.54,91.1 ; U1.AJ16 84.02,91.1 ; U1.AJ33 83.54,82.27 ; U1.AJ33 84.2,82.52 ; U1.AJ33 83.37,82.52 ; 81.01,87.82 U1.AN22 ; U1.AN22 81.59,87.99 81.67,88.07 ; U1.AN22 81.26,87.65 81.18,87.58 ; U1.AN22 81.43,88.24 ; U1.AN22 81.43,87.82 ; U1.U30 90.47,84.03 ; U1.U30 90.3,83.79 ; U1.U30 90.44,84.18 ; U1.U30 90.44,83.89 ; 84.02,86.07 U1.AJ25 ; U1.AJ25 84.2,86.31 ; U1.AJ25 84.17,86.45 ; U1.AJ25 84.02,86.55 ; 83.78,82.86 U1.AJ32 83.78,83.28 ; U1.AK33 83,82.1 ; U1.AK33 83,82.93 ; U1.AK33 82.58,82.52 ; U1.AK33 83.41,82.52 ; U1.Y21 88.07,88.58 ; U1.Y21 88.24,88.83 ; U1.Y21 88.24,88.34 ; U1.Y21 88.49,88.17 ; 94.95,96.21 94.95,97.54 U1.F2 ; 86.13,86.31 85.72,86.31 ; 86.13,86.31 86.13,86.72 ; 86.13,86.31 86.13,85.89 ; 86.13,86.31 85.89,86.07 ; U1.AA19 88.12,89.34 ; U1.AA19 87.46,89.1 ; U1.AA19 87.7,89.76 ; 83.54,83.03 83.78,83.28 ; 83.78,83.28 84.02,83.52 ; 83.78,83.28 84.2,83.28 ; U1.AF25 84.93,86.31 ; U1.AF25 85.11,86.07 ; U1.AF25 85.35,86.72 ; U1.AF25 85.35,85.89 ; 86.13,89.34 86.13,88.93 86.13,88.93 ; 86.13,89.34 86.13,89.76 ; 86.13,89.34 85.89,89.1 ; 86.13,89.34 85.72,89.34 ; U1.AM35 82.63,81.76 ; U1.AM35 81.97,81.52 ; U1.AM35 82.21,81.34 ; U1.AM36 81.8,81 ; U1.AM36 81.97,81.24 ; U1.AM36 82.45,81.24 ; U1.AM36 81.97,80.76 ; 88.9,82.52 U1.Y33 ; U1.Y33 88.73,82.76 ; U1.Y33 88.49,82.1 ; U1.Y33 88.24,82.27 ; 87.46,81.52 U1.AA35 ; U1.AA35 87.46,82 ; U1.AA35 87.7,82.17 ; U1.AA35 87.94,82 ; 81.84,80.24 U1.AN38 ; U1.AN38 81.43,79.83 ; U1.AN38 81.01,80.24 ; U1.AN38 81.18,80 ; 84.2,88.58 U1.AJ21 ; U1.AJ21 83.78,88.17 ; U1.AJ21 83.37,88.58 ; U1.AJ21 83.78,89 ; U1.AC21 86.92,89 ; U1.AC21 87.16,88.83 ; U1.AC21 86.67,88.83 ; U1.AC21 87.31,88.73 ; 84.98,80.24 U1.AG38 ; U1.AG38 84.15,80.24 ; U1.AG38 84.56,80.66 ; U1.AG38 84.32,80 ; U1.Y16 88.24,91.1 U1.Y16 ; U1.Y16 88.1,90.71 ; U1.Y16 88.88,91 ; U1.Y16 88.24,90.61 ; U1.AK16 82.58,90.86 ; U1.AK16 83.24,91.1 ; U1.AK16 82.75,90.61 ; U1.AK16 83,90.44 ; 86.13,88.93 U1.AD19 ; U1.AJ38 83.37,80.24 ; U1.AJ38 84.02,80.49 ; U1.AJ38 83.54,80.49 ; U1.AJ38 83.78,80.66 ; U1.AM33 81.97,82.27 ; U1.AM33 82.63,82.52 ; U1.AM33 82.45,82.76 ; U1.AM33 82.21,82.1 ; 87.46,88.83 U1.AA21 ; U1.AA21 87.94,88.83 ; U1.AA21 88.12,88.58 ; U1.AG16 85.3,91.22 ; U1.AD25 86.13,85.89 ; U1.AJ27 84.17,85.69 ; U1.AJ27 84.2,85.55 ; U1.AJ27 84.02,85.31 ; U1.AJ27 84.02,85.79 ; 81.18,82.27 U1.AN33 ; U1.AN33 81.82,82.37 ; U1.AN33 81.67,82.27 ; U1.AN33 81.43,82.1 ; U1.U32 90.47,83.28 ; U1.U32 90.06,82.86 ; U1.U32 90.3,83.52 ; U1.U32 89.81,83.03 ; 85.35,83.28 84.96,83.42 ; 85.35,83.28 85.11,83.52 ; 85.35,83.28 85.74,83.13 ; 86.67,80.49 U1.AC38 ; U1.AC38 86.92,80.66 ; U1.AC38 87.16,80.49 ; U1.AC38 86.5,80.24 ; U1.AN36 81.18,81.24 ; U1.AN36 81.84,81 ; U1.AN36 81.43,80.59 ; U1.AN36 81.67,81.24
  TOP w0.127: U1.AN51 82,73.48 U1.AM51 81.86,74.3 ; 81.86,74.3 81.85,74.3 ; 81.86,74.3 81.85,74.31 ; U1.AC16 86.58,90.9 85.74,91.73 U1.AE14 ; U1.U51 U1.V51 89.63,74.31
  TOP w0.203: CN26.1 v2(4.21,65.54) ; U1.C45 v2(96.27,77.74) U1.C42 ; C440.1 89.33,109.44 v2(89.18,109.3) ; v2(109.14,98.84) 109.87,98.84 R129.1 ; v2(82.81,76.19) 82.81,76.73 U1.AK44 ; v2(73.35,89.44) 73.67,89.44 U1.BJ19 ; CN17.E1 v2(3.49,43.37) ; CN17.E1 v2(3.49,45.66) ; CN17.E1 v2(2.22,44.26) ; U77.15 35.34,123.31 v2(35.19,123.16) ; v2(97.73,72.56) U1.B53 ; v2(97.73,72.56) U1.B53 ; v2(97.73,72.56) U1.A52 ; v2(97.73,72.56) U1.A52 ; U1.B53 U1.A52 ; U1.B53 U1.B52 ; U1.B53 U1.C53 U1.B52 ; v2(61.02,79.74) Q100.2 ; v2(107.28,112.7) R554.2 R553.1 ; U1.J16 v2(94.14,91.38) ; U56.6 113.61,116.5 v2(113.41,116.7) ; v2(108.07,96.08) 108.07,96.08 R64.2 ; CN24.1 4.39,82.54 v2(4.38,82.55) ; U1.AJ53 v2(83.8,72.16) ; U1.G34 v2(94.85,82.62) ; v2(137.3,48.29) 137.3,48.68 D45.P ; CN26.4 v2(4.12,64.04) ; C441.1 v2(92.05,110.76) ; J5.E1 v2(3.58,34.79) ; J5.E1 v2(3.58,32.5) ; J5.E1 v2(2.31,33.39) ; U68.5 18.64,64.79 18.83,64.6 v2(18.83,64.39) ; U1.BC34 76.99,82.26 v2(77.34,82.62) ; v2(47.3,137.26) CN16.E1 v2(45.27,137.26) ; v2(61.4,59.39) 61.07,59.71 U7.5 ; 115.41,81.63 v2(115.41,81.63) ; 115.41,81.63 114.88,82.16 C16.1 ; 115.41,81.63 114.43,80.65 R709.1 ; U1.AT47 v2(79.91,76.15) ; U1.BJ2 U1.BJ3 74.03,97.4 U1.BH2 ; U1.BJ2 U1.BH1 ; U1.BJ2 U1.BH2 ; CN16.11 v2(34.99,134.91) ; CN26.E2 v2(1.11,57.35) ; CN26.E2 v2(2.89,55.95) ; CN26.E2 v2(2.89,58.75) ; R10.2 62.47,78.01 v2(62.47,78.01) ; R550.2 110.5,121.88 v2(111.22,122.61) ; U1.BH53 U1.BJ52 ; U1.BH53 U1.BH52 ; U1.BH53 U1.BG53 U1.BH52 ; U1.BJ52 U1.BH52 ; U1.BJ52 U1.BJ51 U1.BH52 ; v2(119.18,120.33) 119.31,120.33 119.31,120.33 R549.2 ; CN24.4 4.34,81.04 v2(4.32,81.06) ; CN26.E1 v2(2.89,68.63) ; CN26.E1 v2(2.89,65.83) ; CN26.E1 v2(1.11,67.23) ; U1.U5 U1.U3 ; U1.BG45 v2(75.21,77.74) U1.BG42 ; U1.B52 U1.A51 U1.A52 ; U1.B52 U1.A52 ; U1.G28 v2(94.85,84.6) ; 91.57,73.48 U1.N51 91.72,73.48 U1.M51 ; C549.1 119.52,102.79 v2(119.81,102.79) ; v2(14.66,36.25) R356.1 ; U14.2 v2(140.21,104.36) ; v2(75.16,99.46) 75.16,99.18 75.75,98.59 U1.BE1 U1.BE2 ; U1.AD47 v2(86.69,75.44) ; v2(66.88,96.78) 67.48,97.37 C302.2 ; v2(145.79,100.6) 145.79,100.35 145.55,100.11 CN8.11 ; U1.AV47 v2(78.92,75.44) ; v2(107.2,99.57) 107.15,99.62 R88.2 R67.2 ; v2(29.55,85.17) 29.87,84.85 C381.2 ; C20.2 118.54,79.84 v2(118.37,80.01) ; v2(2.93,85.63) CN24.E1 v2(2.93,82.83) ; v2(83.8,102.91) 83.2,103.51 R24.1 R22.1 ; C475.2 v2(105.67,115.42) 105.67,114.95 R538.2 ; v2(98.25,96.79) 97.63,96.79 U1.A5 ; v2(137.3,51.97) 137.3,51.59 D44.P ; U1.BF4 v2(75.62,96.17) ; Q84.2 v2(24.68,67.77) ; Q46.2 v2(65.32,76.71) ; v2(97.49,98.3) U1.B2 ; U1.B2 U1.C1 ; U1.B2 U1.A3 ; U1.AA32 v2(87.31,83.65) ; U1.E1 95.91,98.6 v2(96.63,99.31) ; U1.AV7 v2(79.91,94.95) ; C467.1 v2(117.15,110.9) ; U1.Y44 v2(87.68,76.86) ; U1.BF24 v2(75.21,87.49) ; U1.K50 v2(93.55,74.02) ; CN24.E2 v2(2.93,75.75) ; CN24.E2 v2(1.15,74.35) ; CN24.E2 v2(2.93,72.95) ; v2(75.21,79.72) 75.6,80.11 U1.BF38 ; v2(113.41,116.7) 114.01,117.3 ; v2(113.41,116.7) 113.21,116.5 U56.42 ; 114.01,117.3 U56.8 ; 114.01,117.3 114.41,117.7 U56.9 ; C10.2 107.35,97.94 v2(107.39,97.98) ; U1.AY22 v2(78.77,87.49) ; R58.1 70.4,103.88 v2(69.48,104.8) ; v2(68.68,99.6) 68.53,99.6 68.35,99.42 U65.4 ; U1.AH9 83.58,93.88 U1.AK10 ; J5.E2 v2(2.31,22.29) ; U1.P4 v2(91.57,97.08) ; v2(92.56,75.44) U1.M47 v2(91.57,76.15) U1.P47 ; U1.BH1 U1.BH2 ; U1.BH1 U1.BG1 U1.BH2 ; v2(88.72,99.82) C7.1 88.42,101.65 88.07,102 88.07,103.61 X1.2 89.86,105.39 92.06,105.39 92.37,105.09 92.37,103.17 92.07,102.87 X1.4 91.24,101.85 C8.1 91.44,101.15 v2(91.61,100.98) ; CN18.4 v2(66.17,134.91) ; U1.AM7 v2(82.81,95.66) ; R53.1 72,79.29 v2(72.02,79.27) ; U1.AF10 84.79,94.24 ; U1.BJ43 v2(73.35,77.78) ; v2(69.86,77.01) 69.15,76.31 Q47.2 ; v2(95.83,101.65) R85.1 ; Q44.2 25.65,62.72 v2(24.61,62.72) ; U1.V44 v2(88.68,77.58) ; U1.K22 v2(92.72,87.49) ; v2(109.63,123) 109.14,122.51 R551.2 ; CN17.E2 v2(3.49,38.06) ; CN17.E2 v2(3.49,35.77) ; CN17.E2 v2(2.22,36.66) ; C434.1 89.73,107.68 v2(90.03,107.68) 90.5,107.21 C552.2 ; U1.BA40 v2(77.34,79.72) ; U1.N16 91.65,91.02 v2(91.29,91.38) 90.94,91.03 U1.P16 ; R16.1 110.03,83.11 v2(110.73,83.82) ; v2(121.01,81.62) 120.18,80.79 C21.2 ; CN16.20 v2(25.99,134.91) ; v2(82.6,86.69) 82.59,86.69 U1.AM25 ; U1.BH2 74.55,97.82 ; v2(116.98,101.68) U73.2 ; CN16.8 v2(37.99,134.91) ; CN18.16 v2(54.17,134.91) ; U1.AY9 v2(77.93,94.95) ; CN8.5 v2(145.83,103.11) ; Q45.2 v2(25.14,63.76) ; CN16.E2 v2(25.7,137.26) ; CN16.E2 v2(24.69,135.99) ; CN16.E2 v2(23.67,137.26) ; U1.AE51 U1.AE50 ; U1.AV18 v2(78.77,90.39) ; v2(91.85,107.67) C439.1 92.57,107.23 C553.2 ; v2(117.6,81.95) 118.51,82.86 C17.1 ; U1.K4 v2(93.55,97.08) ; U1.BC20 76.63,88.48 ; C519.2 v2(65.6,96.78) ; U1.AM19 v2(81.82,89.72) ; CN18.7 v2(63.17,134.91) ; U1.BC42 v2(77.34,77.74) ; Q56.2 v2(14.21,62.23) ; CN18.E1 v2(70.47,135.99) ; v2(49.88,137.26) CN18.E2 v2(47.85,137.26) ; CN8.8 v2(145.79,101.61) ; U14.5 v2(140.21,102.86) ; R32.1 110.03,78.79 v2(110.59,78.23) ; U1.AT4 v2(79.91,97.08) ; v2(119.38,75.33) 119.38,75.34 U6.6 ; U1.A47 v2(98.13,76.07) ; U54.5 91.34,109.94 v2(90.52,110.76) ; U1.BJ49 v2(73.36,74.44) ; 78.83,92.37 U1.AW13 78.83,92.28 78.9,92.87 v2(78.91,92.92) ; v2(104.39,104.24) 104.77,103.86 C14.1 113.26,103.86 113.56,103.55 X3.3 X3.2 112.8,101.14 C11.1 v2(104.39,101.14) ; U1.AA1 87.81,98.24 87.81,97.74 U1.AA3 ; v2(145.89,96.83) 145.61,97.11 CN8.17 ; v2(120.08,115.61) C448.2 R506.2 ; U1.D12 v2(96.27,93.36) ; v2(98.14,93.32) U1.A11 ; R14.2 v2(109.78,89.18) ; U14.8 v2(140.19,101.36) ; v2(105.34,96.99) 105.15,97.18 C12.1 ; U1.BF12 v2(75.21,93.36) ; R555.2 v2(107.84,111.08) ; U1.BJ47 v2(73.36,76.07) ; CN16.5 v2(40.99,134.91) ; CN8.2 v2(145.82,104.61) ; CN16.17 v2(28.99,134.91) ; R509.2 v2(119.31,119.31) ; CN16.14 v2(31.99,134.91) ; U1.BF16 v2(75.21,91.38) ; CN34.2 v2(139.79,10.44) ; U1.K9 v2(93.55,94.95) ; U1.G26 v2(94.85,86.5) ; U1.AD7 v2(86.69,95.66) ; CN18.19 v2(51.17,134.91) ; U1.D30 v2(96.27,83.61) ; U1.AT12 v2(80.9,92.81) ; U1.AK14 v2(83.8,91.39) ; CN18.10 v2(60.17,134.91) ; U1.AT16 v2(80.19,91.38) ; C447.1 v2(21.43,64.74) ; U1.D24 v2(96.27,87.49) ; U14.11 v2(140.2,99.86) ; CN34.4 v2(140.79,10.44) ; U1.AF47 v2(84.79,75.44) ; C465.1 v2(116.25,122.58) ; CN18.13 v2(57.17,134.91) ; U1.J40 v2(94.14,79.72) ; R94.1 65.77,94.3 65.68,94.22 v2(65.68,94.2) ; U1.A6 v2(98.13,95.92) ; U1.P24 v2(90.58,87.49) ; U1.P13 v2(90.58,92.81)
  TOP w0.229: v2(73.35,79.72) U1.BJ39 U1.BG39 v2(75.21,79.72) ; CN3.139 80.68,55.85 ; 80.68,55.85 80.68,54.43 v2(80.08,53.83) ; 80.68,55.85 v2(80.08,55.25) ; 115.18,50.69 CN3.32 ; 115.18,50.69 v2(114.58,51.29) ; 115.18,50.69 115.18,52.11 v2(114.58,52.71) ; v2(72.28,60.89) v2(73.48,60.89) 74.08,60.29 74.08,58.87 ; U1.A43 97.56,77.78 97.74,77.78 v2(98.14,77.78) ; v2(122.38,52.71) v2(123.58,52.71) 124.18,52.11 124.18,50.69 ; U1.A35 v2(98.14,81.66) ; 111.58,50.69 CN3.44 ; 111.58,50.69 v2(112.18,51.29) ; 111.58,50.69 111.58,50.8 ; U1.A31 v2(98.14,83.61) ; U1.AE4 U1.AE3 ; v2(98.14,91.38) 97.78,91.38 U1.A15 ; 111.58,50.8 111.58,52.11 v2(112.18,52.71) ; 111.58,50.8 111.09,51.29 v2(110.98,51.29) ; v2(89.63,72.14) U1.U53 89.51,72.85 89.51,73.36 U1.U51 U1.U49 ; v2(110.08,60.89) v2(108.88,60.89) 108.85,60.89 108.28,60.31 108.28,58.87 ; v2(74.38,51.29) 73.78,50.69 ; 73.78,50.69 CN3.162 ; 73.78,50.69 73.78,52.11 v2(74.38,52.71) v2(75.58,52.71) ; U1.U3 89.73,97.72 89.73,98.26 U1.U1 v2(89.63,98.94) ; U1.AU38 U1.AV38 v2(78.77,80.71) ; v2(93.56,98.94) 93.56,98.61 U1.J1 ; U1.AN53 v2(81.85,72.14) U1.AN53 ; U1.AN53 81.97,72.85 81.97,73.37 U1.AN51 U1.AN49 ; v2(123.58,51.29) 124.18,50.69 ; 124.18,50.69 CN3.2 ; U1.A27 v2(98.14,85.55) ; 103.48,55.85 CN3.71 ; 103.48,55.85 103.48,54.43 v2(104.08,53.83) ; 103.48,55.85 v2(104.08,55.25) ; U1.AB4 v2(87.68,97.08) U1.AA3 ; U1.A23 v2(98.14,87.49) ; v2(123.28,60.89) 123.88,60.29 123.88,58.87 ; CN3.14 120.58,50.77 ; 120.58,50.77 v2(119.96,51.39) ; 120.58,50.77 120.58,52.15 119.96,52.77 v2(119.96,52.77) ; U1.D16 v2(96.27,91.38) U1.C14 ; 108.28,58.87 CN3.55 ; 108.28,58.87 108.5,59.09 108.5,59.09 v2(108.88,59.47) ; v2(103.78,51.29) 103.18,50.69 ; 103.18,50.69 CN3.72 ; 103.18,50.69 103.18,51.49 103.18,52.11 v2(103.78,52.71) 104.98,51.51 CN3.66 ; v2(64.48,53.83) 63.88,54.43 63.88,55.85 ; U1.BJ27 v2(73.35,85.55) ; v2(106.78,52.71) v2(107.98,52.71) 108.58,52.11 108.58,50.69 ; v2(112.48,60.89) 111.88,60.29 111.88,58.87 ; U1.BJ11 v2(73.3,93.32) ; 87.45,91.39 U1.AC16 87.45,91.39 ; 87.45,91.39 v2(87.68,91.39) ; U1.K32 v2(92.72,83.61) ; v2(75.28,60.89) 75.88,60.29 75.88,58.87 ; U1.AH51 84.28,74.4 U1.AH50 v2(83.8,74.73) ; U1.AM24 v2(82.6,86.69) ; v2(91.57,94.95) U1.P9 ; 92.61,92.54 U1.L13 ; 92.61,92.54 U1.L13 ; 92.61,92.54 v2(92.56,92.81) ; U1.L13 U1.K14 ; 70.78,50.69 CN3.172 ; 70.78,50.69 70.78,52.11 v2(70.18,52.71) ; 70.78,50.69 v2(70.18,51.29) ; U1.AB41 v2(87.68,79) U1.Y41 ; 75.88,58.87 CN3.155 ; 75.88,58.87 v2(75.28,59.47) ; U1.D38 v2(96.27,79.72) U1.C39 ; CN3.3 123.88,58.87 ; 123.88,58.87 v2(123.28,59.47) ; U1.C31 v2(96.27,83.61) ; v2(77.93,74.02) U1.AY50 ; U1.BA53 v2(77.97,72.16) ; v2(78.28,60.73) 78.47,60.73 78.88,60.33 78.88,58.87 ; 78.88,58.87 v2(78.28,59.47) ; 78.88,58.87 CN3.145 ; v2(115.48,53.83) v2(114.28,53.83) 113.68,54.43 113.68,55.85 ; v2(78.77,83.61) U1.AY32 ; U1.P52 91.57,73.48 v2(91.57,74.02) U1.M51 ; U1.BC28 76.84,84.87 ; v2(67.78,52.71) 67.18,52.11 67.18,50.69 ; v2(69.88,59.47) 70.48,58.87 ; 70.48,58.87 CN3.173 ; 70.48,58.87 70.48,60.29 v2(69.88,60.89) ; U1.BF30 v2(75.21,83.61) U1.BG31 ; CN3.43 111.88,58.87 ; 111.88,58.87 v2(112.48,59.47) ; 110.38,50.69 110.38,52.11 v2(109.78,52.71) ; 110.38,50.69 CN3.48 ; 110.38,50.69 v2(109.78,51.29) ; v2(80.38,52.71) 80.98,52.11 80.98,50.69 ; 106.48,55.73 CN3.61 ; 106.48,55.73 106.48,54.43 v2(107.08,53.83) ; 106.48,55.73 106.96,55.25 v2(107.08,55.25) ; 106.48,55.73 106,55.25 v2(105.88,55.25) ; 68.68,55.85 68.68,54.43 v2(68.08,53.83) ; 68.68,55.85 68.68,56.23 CN3.179 ; 68.68,55.85 v2(68.08,55.25) ; v2(83.68,55.25) 83.97,55.55 84.28,55.85 ; U1.BJ31 v2(73.35,83.61) ; v2(78.58,52.71) 79.18,52.11 79.18,50.69 ; CN3.60 v2(106.78,50.58) ; U1.AH4 v2(83.8,97.08) U1.AJ3 83.7,97.72 83.7,98.26 U1.AJ1 ; v2(105.28,58.76) CN3.65 ; v2(67.78,51.29) 67.18,50.69 ; 67.18,50.69 CN3.184 ; v2(79.91,98.94) U1.AU1 79.81,98.26 79.81,97.72 U1.AU3 v2(79.91,97.08) ; 80.98,50.69 v2(80.38,51.29) ; 80.98,50.69 CN3.138 ; CN3.144 79.18,50.69 ; 79.18,50.69 v2(78.58,51.29) ; 120.88,58.87 120.88,60.29 v2(120.28,60.89) ; 120.88,58.87 CN3.13 ; 120.88,58.87 v2(120.28,59.47) ; U1.AU51 v2(79.91,74.02) U1.AV51 ; v2(83.38,52.71) 83.98,52.11 83.98,50.69 ; U1.AY4 v2(77.93,97.08) U1.AY3 78.79,97.62 U1.AW3 ; v2(64.18,51.29) 63.9,51.29 63.58,50.96 ; 83.98,50.69 v2(83.38,51.29) ; 83.98,50.69 CN3.128 ; v2(82.48,53.83) v2(83.68,53.83) 84.28,54.43 84.28,55.85 ; U1.AM44 82.5,77.35 82.82,77.59 v2(82.82,78.29) ; U1.BJ23 73.68,87.49 v2(73.35,87.49) ; 108.58,50.69 CN3.54 ; 108.58,50.69 v2(107.98,51.29) ; U1.F7 95.04,94.56 v2(94.84,94.35) U1.G10 ; 119.08,55.85 119.08,54.43 v2(118.48,53.83) ; 119.08,55.85 v2(118.48,55.25) ; 119.08,55.85 CN3.19 ; U1.C49 95.92,74.93 v2(95.86,74.93) ; U1.N1 v2(91.57,98.94) ; 89.15,79.35 U1.U40 ; 84.28,55.85 CN3.127 ; U1.BE8 76.13,94.87 v2(76.65,94.35) ; U1.AN5 U1.AN3 81.85,97.67 81.78,97.75 81.78,98.21 81.85,98.28 U1.AN1 v2(81.85,98.94) ; 63.58,50.96 CN3.196 ; 63.58,50.96 63.58,52.11 v2(64.18,52.71) v2(65.38,52.71) ; 113.68,55.85 v2(114.28,55.25) ; 113.68,55.85 CN3.37 ; U1.BA14 v2(77.34,91.38) ; v2(75.62,74.93) U1.BG49 ; U1.A19 v2(98.14,89.44) ; 63.88,55.85 CN3.195 ; 63.88,55.85 v2(64.48,55.25) ; 74.08,58.87 v2(73.48,59.47) ; 74.08,58.87 CN3.161 ; U1.V7 v2(88.68,95.66) ; U1.BJ35 v2(73.37,81.65) ; U1.AE53 v2(85.74,72.16) ; U1.AK41 v2(83.8,79) U1.AH41 ; v2(94.14,77.74) U1.G42 ; U1.AA53 v2(87.68,72.16) ; CN3.190 v2(65.38,50.58) ; v2(94.85,88.48) 94.49,88.96 U1.G20 ; CN3.167 v2(72.28,58.76) ; U1.J53 v2(93.52,72.15) ; U1.BJ15 v2(73.35,91.38) ; U1.AM29 v2(82.6,84.41) ; 66.88,58.34 CN3.185 66.88,55.85 v2(66.28,55.25) 65.68,55.85 CN3.189 65.68,58.34 66.1,58.76 v2(66.28,58.76) 66.46,58.76 66.88,58.34
  TOP w0.254: U1.BH1 v2(73.75,98.54) U1.BJ2 ; v2(75.53,72.2) U1.BE53 ; U1.BJ52 v2(73.75,72.56) U1.BH53 ; v2(76.48,59.47) 77.08,58.87 CN3.151 ; U1.C39 97.56,79.72 U1.A39 v2(98.14,79.72) ; v2(48.43,127.07) 48.31,126.95 R137.2 ; U5.5 115.43,85.59 v2(115.22,85.8) ; v2(72.58,52.71) 71.98,52.11 71.98,50.69 ; v2(81.58,51.29) 82.18,50.69 CN3.134 ; v2(102.06,116.12) 101.82,115.88 U57.6 ; CN3.9 122.08,58.99 121.6,59.47 v2(121.48,59.47) ; v2(117.58,51.29) 116.98,50.69 ; 116.98,50.69 116.98,52.11 v2(117.58,52.71) ; 116.98,50.69 CN3.26 ; U1.AA1 87.68,98.69 v2(87.68,98.94) ; CN3.8 v2(122.38,50.58) ; U8.5 v2(47.54,129.79) ; CN3.25 v2(117.28,58.76) ; U1.A49 v2(98.13,74.44) ; CN3.178 68.98,50.75 69.29,51.07 69.29,51.82 v2(70.18,52.71) ; CN3.156 v2(75.58,50.58) ; U1.E53 95.75,72.74 v2(95.97,72.2) ; v2(118.33,52.03) 118.78,51.58 CN3.20 ; v2(71.38,51.29) 71.51,51.29 71.98,50.82 71.98,50.69 ; 71.98,50.69 CN3.168 ; 71.98,50.69 v2(72.58,51.29) ; v2(82.48,55.96) CN3.133 v2(82.48,58.76) ; v2(73.26,96.64) 73.27,96.64 U1.BJ5 ; C130.1 18.84,130.61 v2(18.84,131.21) ; Q5.2 v2(20.96,130.3) ; C134.1 v2(49.43,127.85) ; v2(85.74,98.94) 85.74,98.6 U1.AE1 U1.AE3 ; CN3.49 v2(110.08,58.76) ; CN3.150 77.38,50.73 v2(77.39,50.74) ; U1.F5 v2(95.34,95.69) ; CN3.38 v2(113.38,50.58) ; CN3.31 v2(115.48,55.96) ; U1.AT52 U1.AU51 ; U1.BJ7 v2(73.38,95.17)
  TOP w0.305: R1114.1 11.99,38.49 U9.2 ; v2(7.34,114.6) 6.83,115.11 CN22.1 ; v2(23.21,30.59) 23.14,30.65 U63.3 ; J3.E1 v2(8.34,125.22) ; v2(20.53,10) CN28.E1 v2(23.45,10) ; CN22.E1 v2(0.75,116.41) ; CN22.E1 v2(2.02,117.32) ; CN22.E1 v2(2.02,115.49) ; v2(62.12,10) CN27.E2 v2(59.46,10) ; v2(36.27,10) CN28.E2 39.17,10 v2(39.17,10) ; C128.2 53.99,62 v2(53.99,61.91) ; U25.2 18.93,33.71 18.68,33.45 v3(18.68,33.44) ; U75.E1 115.38,89.39 U3.4 ; R805.1 v2(121.61,116.61) ; C580.1 v2(31.13,113.81) 32.04,113.81 32.52,113.33 v2(32.52,112.05) 32.52,110.44 32.13,110.06 v2(31.09,110.06) v2(29.19,110.06) 28.37,110.06 v2(27.96,110.46) 27.67,110.76 v2(27.67,111.72) 27.67,113.37 v2(27.93,113.63) 28.1,113.63 28.1,113.63 29.7,113.63 v2(29.85,113.78) C579.1 ; C992.1 21.08,40.72 v3(20.76,41.04) ; v2(8.99,34.19) 9.27,33.92 Q90.2 ; v2(17.98,40.36) 17.5,39.88 R352.1 ; v4(35.64,125.79) 34.99,125.79 R697.2 ; v2(50.24,30.71) 50.24,29.07 CN12.E1 ; v2(150.4,40.91) CN15.E1 150.4,43.73 v2(150.41,43.74) ; R626.1 R958.1 24.78,35.31 v2(24.95,35.14) ; v2(46.49,10) CN27.E1 v2(43.65,10) ; C429.1 57.09,83.02 v2(57.23,83.16) ; v2(98.46,109.3) 97.61,110.15 Q83.2 ; J3.5 v2(12.22,119.92) ; v3(15.06,38.25) 15.4,37.91 C727.1 ; v2(30.43,111.03) 30.43,111.02 X7.2 ; CN30.M1 v2(126.5,118.21) ; v2(150.4,56.62) CN15.E2 v2(150.4,59.44) ; v2(137.18,13.33) 137.18,13.3 136.2,14.28 CN20.E2 ; CN17.4 6.47,39.96 v3(5.89,40.54) ; v2(50.56,59.39) 50.63,59.32 CN12.E2 ; v2(131.58,31.85) 131.45,31.98 C600.1 ; U59.2 v2(41.9,20.99) ; SW1.5 v2(14.3,51.7) ; v2(142.26,63.03) R574.1 C539.2 ; R529.1 107.55,119.63 v2(107.34,119.43) ; v2(52.83,83.67) 52.33,83.17 Q82.2 ; C428.1 v2(57.88,83.09) 57.6,83.37 U51.5 ; v2(7.34,112.62) 6.83,112.11 CN22.4 ; C617.1 70.56,131.83 v2(70.87,132.14) ; v2(23.9,86.73) 23.1,86.73 C379.2 ; Q78.2 130.98,35.48 v1(130.28,34.78) ; J3.4 v2(12.22,120.92) ; v3(5.9,42.35) 6.51,42.96 CN17.1 ; v2(122.37,122.64) 122.37,123.46 C708.2 ; v2(28.17,112.72) 28.17,112.72 X7.4 ; D47.P v2(31.24,23.82) ; v2(34.88,114.41) 34.7,114.59 C578.1 R698.1 ; C466.1 v2(118.23,122.4) ; CN13.E1 8.59,8.83 v2(8.57,8.81) ; R163.2 v2(12.69,14.69) ; D46.P v2(28.47,23.8) ; v2(43.1,102.49) 43.22,102.37 Q54.2 ; v2(48.2,129.81) 48.2,130.14 C135.1 ; C19.1 116.77,87.01 v2(116.77,87.01) ; v2(20.51,51.71) 20.51,51.7 SW1.6 ; SW2.4 14.33,49.57 SW1.2 v2(14.33,47.69) ; C380.2 v2(33.38,86.94) ; R99.1 99.65,100.25 v2(99.4,100.5) ; Q48.2 v2(148.4,65.58) ; C500.1 v2(18.04,64.02) ; CN30.S6 v2(126.5,117.46) ; C709.2 v2(122.38,129.09) ; D48.P v2(51.55,22.56) ; v2(22.48,126.08) 22.48,126.08 C132.2 ; v2(117.24,106.44) 117.53,106.15 C560.1 116.98,104.99 C561.2 ; C305.1 v3(15.75,41.52) ; R182.2 v2(14.13,33.37) ; R552.1 118.47,113.52 v2(118.08,113.13) ; v2(14.33,55.97) SW1.1 14.52,54.51 SW2.2 ; CN22.E2 v2(0.75,108.81) ; Q53.2 v2(146.39,60.33) ; C548.1 116.95,98.67 v2(116.95,98.67) ; CN13.3 v2(13.19,11.06) ; U25.15 v2(19.93,38.84) ; J3.E2 v2(8.34,118.62) ; CN13.E2 v2(16.79,8.92) ; CN5.E1 v2(138.92,8.97) ; U69.5 38.78,102.67 v2(38.78,102.67) 39.07,102.97 C535.1 ; D49.P v2(54.36,22.59) ; CN30.M10 v2(126.5,131.71) ; CN30.S3 v2(126.5,124.96) ; CN5.E2 v2(142.11,8.97)
  TOP w0.406: v2(51.13,63.03) C385.1 v2(52.15,63.03) ; v2(147.5,108.86) CN30.E2 v2(149.28,110.13) ; CN12.34 44.58,47.93 v2(44.95,48.29) ; v2(131.54,75.02) 131.54,75.03 U31.2 131.54,77.65 C313.2 131.54,78.44 R365.1 ; Q57.2 122.39,81.41 v2(122.75,81.77) ; CN12.27 v2(49.86,45.13) 49.86,45.64 50.14,45.93 CN12.29 ; CN12.21 50,42.73 v2(49.74,42.98) ; U13.1 v2(69.54,120.39) ; C469.2 112.55,109.99 C473.1 v2(110.56,109.25) ; v2(65.97,120.36) 65.73,120.6 U13.4 ; v2(149.28,137.33) CN30.E3 v2(147.5,136.06) ; v2(59.9,38.69) 60.03,38.81 CN3.E1 ; CN12.26 44.2,44.73 44.56,45.08 v2(44.56,45.42) ; v2(123.36,39.8) 124.15,39.8 CN3.E2 ; v2(103.66,116.11) 103.66,115.45 C479.1 ; v2(44.5,49.85) 44.02,50.33 CN12.40 ; v2(53.01,35.86) 53.01,35.49 52.25,34.73 CN12.9 ; C325.2 45.99,23.74 R379.1 45.12,22.87 v2(45.12,21.98) ; v2(125.11,13.37) 126.02,14.28 CN20.E1 ; CN12.15 49.95,37.13 v2(49.9,37.18) ; CN12.4 v1(44.42,32.73) ; CN30.E1 v2(129.5,108.19) ; CN12.43 53.25,51.53 v2(53.26,51.51) ; v2(129.5,136.06) CN30.E4 v2(131.28,137.33) ; CN12.35 v2(49.84,48.33) ; CN12.18 v2(41.6,41.53) ; U13.2 v2(68.27,120.4) ; CN12.50 v2(41.71,54.33) ; v2(49.84,49.13) CN12.37 ; U13.3 v2(67,120.33)
  TOP w0.508: v2(17.13,121.1) CN4.E1 ; CN4.E1 v2(18.07,119.81) ; CN4.E1 v2(16.22,119.81) ; Q55.2 28.79,99.15 28.79,99.95 v2(28.78,99.96) ; v2(27.97,22.41) 26.97,22.41 26.35,21.79 CN28.4 ; C13.1 100.41,100.21 v2(100.14,100.48) ; v2(98.95,61.44) 98.95,61.24 C120.1 ; C125.1 v2(95.52,61.24) ; CN15.4 141.02,46.65 v1(141.03,46.67) ; v2(21.77,119.81) CN4.E2 v2(22.73,121.08) ; v2(26.88,113.76) C577.1 26.89,114.39 C573.1 C574.1 ; C131.1 v2(15.82,125.06) ; v2(137.86,52.16) 137.86,52.24 C317.2 ; v2(21.43,124.79) 21.43,124.79 CN4.4 ; CN27.4 v1(49.45,22.6)
  BOTTOM w0.203: v2(59.66,114.34) 59.63,114.32 U10.17 ; U27.6 108.77,31.36 108.56,31.57 108.56,32.23 v2(107.97,32.82) ; v2(77.01,115.65) 77.35,115.31 C402.1 ; v2(106.26,46.69) 105.35,47.6 Q88.2 ; v2(123.04,21.74) 123.04,21.85 C259.1 ; v2(97.81,45.05) D28.P ; v2(1.11,15.88) 1.11,14.88 CN11.E1 ; v2(79.91,98.94) 79.51,99.35 R26.2 ; v2(89.39,31.86) 89.34,31.81 U28.75 ; v2(111.97,27.55) 111.26,28.26 C286.2 ; CN11.E1 v2(1.1,13.98) ; CN11.E1 v2(2.37,14.87) ; Q71.2 v2(26.77,50.02) ; R292.2 v2(101.79,45.26) ; CN14.19 115.4,29.2 v2(114.71,29.89) 115.02,30.2 ; U26.6 105.33,22.94 v2(105.22,23.04) ; U28.27 102.7,29.81 102.7,29.81 v2(102.03,29.13) ; v2(55.69,114.42) 55.65,114.42 55.23,114 U10.28 ; v2(132.9,56.36) 132.31,56.36 R475.1 ; v2(115.22,85.8) 115.46,86.04 C18.1 ; v2(120.28,67.31) C410.1 ; U71.3 v2(16.88,83.84) ; v2(29.45,93.29) 29.45,93.29 Q42.3 ; R55.2 v2(77.34,86.5) ; v2(94.01,23.14) 94.01,23.14 94.01,24.4 94.55,24.94 R330.2 95.1,25.01 95.88,25.78 U28.49 ; Q3.2 121.34,84.57 v2(121.07,84.83) ; v2(126.18,55.79) 126.69,55.79 C562.2 ; v2(116.54,85.98) 117.28,85.24 Q1.2 ; R1.1 82.82,77.77 v2(82.82,78.29) ; U47.8 134.87,66.34 U47.E1 134.87,67.84 U47.7 ; v2(61.8,118.87) 61.78,118.9 U10.3 ; C57.2 v2(64.61,90.22) ; v2(54.24,111.35) 54.33,111.43 R159.1 ; Q67.2 37,46.44 v2(37.01,46.43) ; v2(28,64.58) 28.81,63.78 C766.2 ; v2(119.16,15.84) 118.87,15.84 118.17,16.55 U24.3 ; v2(113.13,76.68) 112.91,76.9 112.91,78.12 C416.1 ; R239.2 v2(120.51,10.53) ; 115.02,30.2 CN14.17 ; 115.02,30.2 115.52,30.7 CN14.16 ; v2(149.88,127.02) C606.1 R735.1 ; 118.17,38.63 118.17,38.5 ; v2(30.32,118.96) 30.32,118.88 30.32,118.88 R690.1 ; v2(141.49,131) 141.99,131 X8.4 ; v2(121.01,81.62) Q2.2 121.01,79.78 121.51,79.27 R15.1 ; Q77.2 v2(90.36,128.29) ; Q76.2 91.3,124.14 v2(91.16,124.01) ; v2(53.79,19.11) 53.78,19.12 U41.2 ; v2(106.89,29.49) 107.32,29.92 R311.2 ; C616.1 v2(143.02,129.06) 143.02,129.48 142.86,129.64 141.79,129.64 141.09,130.34 141.09,132.48 v2(141.24,132.63) 141.7,133.09 145.44,133.09 145.68,132.85 v2(145.68,131.49) 145.68,129.89 145.43,129.65 144.44,129.65 144.08,129.29 v2(144.08,129.04) C615.1 ; R161.1 v2(56.18,111.43) ; v2(1.1,21.58) CN11.E2 1.11,22.48 v2(1.11,23.48) ; R189.1 v2(57.78,110.91) ; U74.4 64.07,78.35 64.35,78.63 v2(64.6,78.63) ; R425.1 27.72,90.31 v2(27.66,90.38) ; v2(18.15,108.34) 17.73,108.34 C326.2 ; U10.18 59.23,114.15 v2(59.05,114.33) ; U40.3 v2(15.41,102.67) ; U37.3 18.59,105.18 v2(19.01,104.76) ; v2(31.37,66.29) 31.8,65.87 Q50.2 ; Q80.2 v2(110.59,78.23) ; Q79.2 109.56,74.93 v2(109.06,75.43) ; R46.1 v2(77.34,88.48) ; v2(96.78,45.03) D27.P ; v2(8.31,100.3) 7.73,100.88 R726.1 C765.1 ; U23.4 128.49,17.51 U23.E1 ; v2(77.93,94.95) 77.85,94.95 R38.2 ; R422.2 v2(29.55,85.17) ; C505.2 v2(40.16,41.33) ; C331.2 v2(16.1,99.4) ; C81.2 98.17,79.68 v2(98.14,79.72) ; 117.48,10.5 117.99,9.98 C227.1 ; C565.2 v2(36.24,60.7) ; v2(9.8,107.89) 9.79,107.89 C324.2 ; Q38.2 59.68,67.51 v2(59.67,67.5) ; v2(2.93,100.17) C726.1 ; U39.3 v2(17.99,102.55) ; U46.E1 120.23,68.15 119.73,67.65 U46.5 ; D13.P v2(136.26,75.3) ; v2(83.8,97.08) 83.85,97.14 R23.2 83.24,97.74 R25.2 ; v2(59.78,34.99) 59.69,35.08 R223.2 ; Q86.2 v2(23.33,50) ; v2(83.8,79) 84.29,79.49 C58.2 ; U28.91 89.85,38.21 v2(90.01,38.05) ; v2(49.65,62.97) 49.82,63.13 U43.7 ; Q63.2 112.93,45.21 v2(113.09,45.04) ; v2(75.92,90.39) 76.54,90.39 R45.2 ; C566.2 v2(61.87,78.25) ; C596.1 115.51,121.84 v2(116.25,122.58) ; C257.1 123.42,16.88 123.43,16.88 v2(123.5,16.88) 124.06,16.88 C261.1 ; Q43.2 v2(25.96,96.49) ; R659.2 v2(95.99,46.94) ; C417.1 112.88,75.71 v2(113.17,75.99) 113.35,76.18 U48.5 ; R86.2 92.56,95.09 v2(92.56,95.66) ; U38.3 v2(14.11,107.91) ; v2(103.13,41.99) 103.87,42.73 103.87,44.44 v2(104,44.57) 104.02,44.59 R343.1 v2(105.22,44.59) C289.2 v2(107.76,44.59) v2(113.59,44.59) 115.08,44.59 115.45,44.22 X6.2 X6.3 115.45,42.33 115,41.88 v2(114.3,41.88) v2(109.64,41.88) 107.98,41.88 107.84,41.74 C291.2 105.85,41.92 v2(105.4,41.92) 104.96,41.92 103.73,40.69 U28.1 ; R663.1 v2(16.31,89.74) ; D12.P v2(136.27,78.02) ; R482.2 v2(30.31,60.39) ; v2(79.91,94.95) 79.63,94.67 R33.1 R35.1 ; v2(91.91,114.99) 91.91,114.4 92.14,114.17 R496.2 ; Q25.2 v2(108.21,76.26) ; U17.24 v2(55.49,37.68) ; v2(82.81,76.19) 82.97,76.35 R2.1 ; U33.3 v2(135.81,79.19) ; R489.2 v2(38.29,49.43) ; C253.1 C260.1 121.8,17.72 v2(121.95,17.57) ; R60.1 v2(86.69,94.95) ; C187.2 57.96,46.57 v2(57.96,46.57) 57.96,46.59 57.53,47.02 56.62,47.02 56.14,47.5 v2(56.14,48.22) 56.14,50.08 56.37,50.3 v2(58.33,50.3) 60.3,50.3 60.59,50.02 60.59,47.24 60.35,47.01 59.44,47.01 59,46.58 C186.2 ; C151.1 v2(63.92,115.79) ; Q81.2 126.24,66.72 v2(126.23,66.72) ; C283.2 85.77,31.51 v2(85.41,31.87) ; C99.1 69.84,102.91 C100.2 69.84,104.45 v2(69.48,104.8) ; U36.3 11.54,107.49 v2(11.95,107.9) ; R40.2 77.69,97.32 v2(77.93,97.08) ; R100.2 74.13,91.38 v2(73.35,91.38) ; R331.2 v2(90.89,45.33) ; 50.24,64.51 U43.10 ; v2(30.03,87.83) 29.98,87.88 C442.1 ; v2(111.02,32.82) 111.21,33.01 C287.2 ; CN14.3 115.5,37.2 115.12,37.58 v2(115.12,38.63) ; v2(87.68,72.16) 87.28,72.56 R5.2 ; v2(83.8,78.29) 84.31,78.8 C30.1 ; C85.2 79.49,86.52 v2(79.48,86.5) ; R4.2 87.07,78.38 v2(87.68,79) ; v2(50.99,61.5) 51.04,61.5 51.24,61.69 U43.4 ; U32.3 v2(135.93,74.04) ; Q75.2 v2(75.2,115.65) ; R93.1 v2(91.57,94.95) ; U60.5 v2(43.93,59.31) ; R61.1 v2(87.68,94.24) ; C285.2 v2(109.26,23.46) ; U58.3 v2(39.87,45.26) ; C514.1 v2(43.9,57.88) ; X8.2 v2(143.74,132.2)
  BOTTOM w0.254: R131.1 97.66,95.2 R87.2 98.13,95.67 v2(98.13,95.92) ; R122.2 R123.2 64.85,50.05 v2(65.38,50.58) ; v2(92.05,110.76) 92.79,111.5 C438.2 ; C79.2 78.79,84.57 v2(78.77,84.6) ; v2(79.48,87.49) 79.53,87.44 C506.2 ; U20.5 110.97,19.06 111.39,19.06 C225.1 ; C597.1 91.05,89.53 v2(90.91,89.38) ; C62.2 85.08,80.58 C58.2 ; C50.1 85.59,82.05 C41.1 ; U45.E1 77.35,113.52 77.76,113.93 U45.5 79.69,113.93 C400.1 ; v2(88.68,77.58) 88.75,77.5 C51.2 C52.2 ; v2(92.72,87.49) 92.76,87.45 R78.2 ; C83.2 91.28,91.39 v2(91.29,91.38) ; v2(90.58,88.48) 90.47,88.6 C65.2 90.48,88.96 v2(90.91,89.38) ; C68.2 90.48,89.81 v2(90.91,89.38) ; C75.1 v2(79.48,88.48) ; v2(90.58,92.81) 90.01,92.24 C84.2
  BOTTOM w0.305: v2(86.53,85.93) 86.53,86.29 85.99,86.83 C43.1 85.97,86.82 C44.1 84.96,86.62 v2(84.96,85.93) 84.85,85.82 C39.2 ; v2(112.38,19.64) 112.36,19.65 111.99,19.65 C225.1 ; v2(104.7,94.71) 105.01,95.01 C73.2 ; CN19.E1 v2(13.4,10.52) ; v2(65.96,34.45) 65.94,34.43 C496.1 ; C152.1 v2(64.46,114.65) ; Q59.2 v2(93.9,117.88) ; R447.1 R446.1 48.01,64.72 C394.1 v2(49.3,64.72) ; R601.1 124.51,25.76 124.83,26.08 v2(124.83,26.08) ; v2(5.68,122.98) 5.62,122.98 5.62,122.97 C620.1 ; R18.1 9.06,21.45 v2(9.54,20.97) ; v2(56.13,63.7) 56.13,63.7 R438.1 R436.2 ; R164.2 v2(30.16,36.98) ; C54.2 C53.2 80.18,83.6 v2(80.19,83.61) ; C401.1 89.36,118.81 v2(89.1,118.55) ; v2(13.19,11.06) 13,11.25 CN19.1 ; R740.2 146.5,115.79 146.5,115.79 v2(146.5,115.77) ; v2(24.96,46.06) 24.96,46.06 Q51.2 ; C164.1 51.96,118.1 51.61,117.74 v2(51.23,117.74) ; Q72.2 135.5,58.37 v2(134.28,57.16) ; C330.2 54.01,14.86 52.69,14.86 v2(52.69,14.86) 51.96,14.86 51.62,15.2 R374.1 ; v2(98.21,116.16) 98.21,115.43 C435.2 ; C56.2 73.83,83.13 v2(73.35,83.61) ; v2(52.66,40.99) 52.75,40.9 R210.1 ; C27.1 79.66,77.34 v2(79.92,77.6) ; CN2.2 v2(40.49,123.89) ; v2(137.21,62.46) 137.21,62.46 R464.2 135.63,63.2 C411.2 ; C28.1 97.89,76.3 v2(98.13,76.07) 98.6,76.07 C26.1 ; Q85.2 v2(15.36,85.43) ; v2(20.01,84.01) 20.4,84.4 R491.2 ; v2(98.14,83.61) 97.98,83.76 C49.1 ; v2(7.7,37.12) 7.79,37.21 Q7.2 8.47,38.13 R178.2 ; v2(32.98,118.83) 32.98,118.83 C576.1 C575.1 ; v2(63.09,36.3) 63.09,36.21 62.55,35.67 C202.2 ; R115.1 86.56,95.8 v2(86.69,95.66) ; CN2.E1 v2(44.29,121.02) ; v2(64.5,37.46) C193.2 ; C96.2 79.91,95.98 v2(79.91,97.08) ; v2(86,103.09) 85.54,103.09 85.27,102.82 C66.2 ; v2(12.26,101.69) 12.6,102.02 C332.2 C329.2 ; C97.2 83.24,88.93 C32.1 ; v2(61.87,70.99) 62.99,69.87 Q39.2 ; v2(123.58,52.71) 123.51,52.77 R124.1 123.52,53.78 C103.1 C104.1 ; C510.1 68.13,43.68 v2(68.02,43.79) 67.88,43.94 U16.5 ; v2(80.9,92.81) 81.45,93.36 C518.2 ; C262.1 116.22,15.87 v2(116.44,15.65) ; v2(73.29,42.85) U29.3 73.29,40.67 R347.1 ; U79.4 v2(5.6,105.76) ; v2(124.7,21.59) 124.86,21.43 C256.1 ; Q14.2 118.26,22.69 v2(119.12,23.54) ; v2(61.06,46.84) 60.79,46.58 R209.1 ; R687.2 131.42,46.72 v2(131.42,46.72) 131.83,47.14 Q74.2 ; v2(30.65,88.69) 30.24,89.1 R421.2 ; C206.2 v2(59.79,46.56) ; U84.2 v2(7.95,122.97) ; v2(75.7,47.64) 76.15,47.19 U30.4 ; C203.2 v2(64.38,39.1) ; Q17.2 24.19,33.92 25.02,33.92 v2(25.28,34.18) ; C290.2 107.01,36.28 107.65,35.64 v2(107.65,35.51) ; Q52.2 96.49,117.82 v2(96.49,117.82) ; C22.1 98.54,74.03 v2(98.13,74.44) ; C204.2 v2(64.36,42.28) ; v2(56.45,64.14) 56.45,64.15 56.71,64.41 C767.2 57.62,64.41 R451.1 ; R370.1 142.71,57.65 v2(142.64,57.72) ; v2(147.25,128.43) C614.1 C613.1 ; R320.2 105.51,26.46 105.42,26.36 v2(105.42,26.4) ; v2(81.85,98.94) 81.89,98.98 C98.2 ; C611.1 C612.1 141.23,128.95 v2(141.05,129.13) ; C196.2 53.2,38.16 v2(52.69,37.65) ; v2(15.67,81.7) 15.83,81.53 C540.2 ; v2(96.63,99.31) 96.21,99.73 C72.1 ; C293.2 87.93,43.56 v2(87.93,42.79) ; C231.2 v2(136.74,16.82) ; v2(59.36,34.2) 59.69,34.2 C527.1 ; v2(30.93,98.6) 30.68,98.36 Q98.3 ; R722.1 v2(7.11,108.59) 7.1,108.58 C764.1 ; C375.2 18.94,87.97 v2(18.94,87.97) ; R426.2 29.4,83.34 v2(29.46,83.39) ; v2(124.87,15.12) C255.1 ; v2(55.65,46.6) 56.04,46.21 C201.2 ; v2(83.38,51.29) 84.21,50.45 84.21,49.42 84.66,48.98 C106.1 C107.1 R126.1 ; U42.15 24.53,86.45 U42.E1 ; C185.1 R199.1 145.48,94.76 145.48,94.76 v2(145.4,94.76) ; C24.1 77.88,72.24 v2(77.97,72.16) ; v2(59.95,63.28) 60.23,63 Q61.2 ; C495.1 v2(72.98,36.56) ; R737.1 v2(140.24,129.21) ; C69.2 67.32,90.75 v2(67.12,90.95) ; Q73.2 136.3,52.43 v2(136.62,52.75) ; v2(89.1,118.55) 89.12,118.53 C398.1 ; v2(89.1,118.55) 89.05,118.5 U44.5 ; C150.1 v2(58.03,123.2) ; v2(93.52,72.15) 93.6,72.24 C23.1 ; D6.1 151.42,96.67 v2(151.42,96.67) ; U83.15 v2(148.91,118.99) ; U22.2 v2(113.51,14.38) ; CN19.E2 10.9,10.52 v2(11.86,10.52) ; Q13.2 118.47,19.84 v2(118.79,19.51) ; C294.2 72.28,45.85 72.85,46.43 v2(72.85,47.64) ; Q68.2 v2(30.26,44.99) ; C321.2 v2(10.95,102.97) ; v2(108.24,35.5) 107.54,34.79 106.61,34.79 C288.1 ; C567.2 v2(61.92,76.67) ; v2(44.25,61.53) 44.48,61.76 C513.1 ; v2(83.8,74.73) 83.82,74.71 R3.2 ; R597.2 10.66,120.81 v2(10.66,120.81) ; CN11.4 v2(3.74,19.17) ; v2(88.88,86.69) 88.89,86.7 C38.1 ; v2(99.29,111.72) 99.18,111.83 C436.2 ; C431.2 34.39,52.68 v2(34.19,52.49) ; C210.1 55.62,34.15 C211.2 v2(56.65,34.68) ; C318.2 144.31,55.38 U55.2 144.31,53.37 v2(143.94,53) ; Q70.2 v2(27.22,47.49) ; R960.1 v2(13.71,81.9) ; C494.1 v2(79.35,36.08) ; v2(73.26,96.64) 73.32,96.7 C55.1 ; v2(56.76,76.5) 57.33,75.94 Q36.2 ; X4.2 59.56,48.83 v2(59.69,48.7) ; v1(29.92,34.26) 29.6,33.94 Q16.2 ; C235.2 136.59,21.14 v2(136.87,21.14) ; v2(55.13,46.62) 55.13,46.21 C192.2 ; C191.2 57.31,46.17 v2(57.31,46.57) ; C251.1 126.02,14.28 v2(125.11,13.37) ; C368.1 25.91,81.4 25.37,81.94 v2(25.37,82.23) ; U34.3 v2(7.54,104.35) ; C207.2 v2(64.34,40.77) ; C254.2 v2(123.51,14.22) ; v2(50.56,59.39) 50.57,59.39 C393.2 ; v2(139.05,26.68) C228.1 ; v2(67,43.36) 67,43.48 67,43.49 C511.1 ; v2(49.9,37.18) 49.98,37.26 R219.2 ; X4.4 v2(57.36,48.59) ; C409.1 117.14,67.96 v2(116.83,67.65) ; C610.1 v2(139.44,129.19) ; v2(73.36,74.44) 72.81,73.9 C25.1 ; Q8.2 v2(143.76,108.63) ; C292.1 v2(73.51,47.64) ; R727.1 v2(3.81,109) ; C376.1 v2(18.99,86.71)
  BOTTOM w0.406: SW4.2 v2(23.69,116.02) ; C710.1 v2(130.43,129.07) ; v2(44.56,45.42) 43.57,45.42 C266.2 42.69,44.54 C268.1 ; CN14.E1 118.17,38.5 v2(118.18,38.49) ; C91.2 92.18,81.33 92.72,80.79 v2(92.72,80.71) ; v2(81.64,70.89) R9.1 82.35,70.89 C1.2 ; v2(83.8,74.02) 83.91,73.91 C31.1 ; v2(109.83,22.21) 109.83,21.74 C284.2 ; C269.1 51.42,49.93 C270.1 51.42,49.85 50.69,49.13 v2(49.84,49.13) ; C205.2 50.99,39.98 R213.1 49.86,40.86 v2(49.85,40.87) ; C705.2 134.27,128.59 v2(134.27,129.08) ; v2(49.55,68.99) 49.55,68.96 49.55,68.96 C388.1 ; v2(64.36,116.65) 64.49,116.79 C161.1 ; C704.2 v2(134.85,129.08) ; C92.2 C95.2 v2(88.71,108.54) ; v2(130.27,126.1) 129.94,126.42 C706.1 ; C557.2 80.94,111.76 C396.1 80.39,110.75 v2(79.96,110.33) ; C265.1 v2(44.59,30.98) ; C521.1 v2(79.04,39.93) U70.2 81.03,39.93 C507.1 ; C188.2 71.3,48.28 v2(71.94,47.64) ; R802.1 C707.2 v2(132.83,129.07) ; C63.1 v2(104.68,95.75) ; C161.1 65.26,117.33 C160.1 ; C161.1 63.73,117.33 C162.1 ; v2(102.45,93.81) 102.75,93.81 C59.1 ; v2(97.49,98.3) 97.45,98.26 C88.2 ; R800.2 v2(131.2,129.07) ; R215.2 46.64,39.03 v2(47.16,38.51) ; v2(59.45,113.07) 59.78,112.74 C172.1 59.78,111.74 C171.1 ; v2(40.15,54.51) 40.15,54.51 C264.1 39.6,55.68 C263.2 ; C413.2 134.05,71.33 R470.1 134.62,72.05 v2(135.39,72.82) ; SW4.6 v2(20.69,111.67) ; v2(83.16,29.16) 83.3,29.02 C282.1 ; C86.2 98.75,97.07 98.47,96.79 v2(98.25,96.79) ; v2(64.99,113.59) 64.95,113.59 64.95,113.6 C166.2 ; v2(94.26,105.64) 94.1,105.8 94.1,106.46 C94.2 C93.2 ; C197.1 49.73,43 v2(49.74,42.98) 50.61,42.98 C198.2 ; C87.2 100.83,98.67 v2(101.1,98.4) ; v2(47.94,61.95) 47.28,61.29 C392.1 ; v2(130.88,10.21) 130.88,10.2 C252.2 ; Q58.2 v2(29.69,57.76) ; v2(129.96,71.7) 130.04,71.61 Q49.2 ; C267.1 v2(40.24,52.97)
  BOTTOM w0.508: 63.85,44.9 63.72,45.04 C190.2 ; 63.85,44.9 v2(63.98,45.03) ; 63.85,44.9 63.78,44.83 C195.2 62.98,44.82 C194.2 ; C334.2 v2(48.59,18.36) ; C229.1 108.25,16.72 v2(108.62,16.72) ; R688.2 U76.2 129.33,47.03 130.12,46.24 v2(130.65,46.24) ; C572.1 C571.1 116.65,45.57 v2(117.13,45.09) ; v2(39.52,122.66) CN2.E2 ; v2(136.77,127.93) 136.78,127.92 C700.2 136.47,127.14 135.85,126.52 C701.2 ; 3.54,125.28 v2(3.54,125.28) ; 3.54,125.28 C618.1 ; 3.54,125.28 4.59,125.28 C619.2 ; C281.1 84.01,39.33 v2(84.29,39.04) ; v2(98.3,97.95) 97.64,97.29 R92.1 ; C703.2 136,121.34 v2(135.74,121.6) 135.74,121.61 C702.1 ; C556.2 75.28,110.76 v2(75.49,110.97) 75.49,111.48 C399.1 ; v2(146.27,114.59) 146.27,114.59 C609.1 ; C247.1 130.75,12.66 v2(130.98,12.43) ; v2(127.24,44.38) 127.79,43.83 C568.2 ; v2(120.38,11.56) 120.86,12.04 U19.2 ; C622.1 10.67,122.97 v2(10.67,122.97) C621.1 ; CN14.E2 v2(116.11,27.01) ; U21.2 v2(134.85,26.68)
  BOTTOM w0.635: v1(50.03,64.9) 50.24,64.7 50.24,64.51 ; C248.2 v1(124.08,9.52)
  BOTTOM w0.762: C608.1 148.66,114.53 v1(148.67,114.53)
  vias: v1(0.84,131.96) v1(0.84,129.42) v1(0.84,126.88) v1(0.84,124.34) v1(0.84,121.8) v1(0.84,119.26) v1(0.84,114.18) v1(0.84,111.64) v1(0.84,106.56) v1(0.84,104.02) v1(0.84,101.48) v1(0.84,98.94) v1(0.84,96.4) v1(0.84,93.86) v1(0.84,91.32) v1(0.84,88.78) v1(0.84,86.24) v1(0.84,83.7) v1(0.84,81.16) v1(0.84,78.62) v1(0.84,76.08) v1(0.84,73.54) v1(0.84,71) v1(0.84,68.46) v1(0.84,65.92) v1(0.84,63.38) v1(0.84,60.84) v1(0.84,58.3) v1(0.84,55.76) v1(0.84,53.22) v1(0.84,50.68) v1(0.84,48.14) v1(0.84,45.6) v1(0.84,43.06) v1(0.84,40.52) v1(0.84,37.98) v1(0.84,35.44) v1(0.84,32.9) v1(0.84,30.36) v1(0.84,27.82) v1(0.84,25.28) v1(0.84,20.2) v1(0.84,17.66) v1(0.84,12.58) v1(0.84,10.04) v1(0.84,7.5) v1(3.28,137.68) v1(3.23,133.63) v1(3.71,7.5) v1(4.22,62.19) v1(4.22,61.43) v1(4.67,8.68) v1(4.69,129.54) v1(5.13,118.49) v1(5.82,137.68) v1(6.25,7.5) v1(6.41,56.58) v1(6.9,125.53) v1(7.17,56.58) v1(7.59,120.19) v1(7.72,132.03) v1(8.36,137.68) v1(8.79,7.5) v1(8.91,129.39) v1(9.71,96.46) v1(9.71,95.67) v1(9.71,94.91) v1(9.72,94.18) v1(10.9,137.68) v1(11.33,7.5) v1(12.33,70.92) v1(12.33,70.16) v1(12.33,69.4) v1(12.33,68.65) v1(12.33,67.89) v1(12.33,67.14) v1(12.61,8.61) v1(12.82,129.71) v1(13.44,137.68) v1(13.87,7.5) v1(14.07,81.23) v1(14.07,80.47) v1(14.07,79.7) v1(14.07,78.94) v1(15.98,137.68) v1(16.41,7.5) v1(16.56,133.01) v1(17.64,134.58) v1(18.17,137.74) v1(18.95,7.5) v1(19.69,92.68) v1(19.71,91.92) v1(19.72,91.16) v1(19.72,90.4) v1(19.89,8.66) v1(19.99,70.31) v1(20.45,92.68) v1(20.47,91.92) v1(20.49,91.16) v1(20.49,90.4) v1(20.76,70.31) v1(21.32,137.78) v1(21.49,7.5) v1(21.52,70.31) v1(21.65,134.38) v1(22.1,136.11) v1(22.31,77.54) v1(23.03,78.27) v1(23.03,77.56) v1(23.79,78.27) v1(23.8,77.56) v1(24.03,10.83) v1(24.03,7.5) v1(24.82,13.56) v1(24.91,114.91) v1(27.27,105.33) v1(27.27,104.57) v1(27.36,13.56) v1(28.68,137.68) v1(29.77,105.33) v1(29.77,104.57) v1(29.92,35.03) v1(29.92,33.5) v1(29.9,13.56) v1(30.15,51.86) v1(30.53,105.33) v1(30.53,104.57) v1(31.22,137.68) v1(31.26,22.57) v1(32.44,13.56) v1(33.76,137.68) v1(34.16,66.18) v1(34.8,21.81) v1(34.98,13.56) v1(35.58,10.55) v1(35.67,7.57) v1(36.19,24.94) v1(36.3,137.68) v1(36.6,59.13) v1(36.87,54.81) v1(37.68,13.34) v1(38.78,7.51) v1(38.84,137.68) v1(39.2,59.58) v1(39.74,27.09) v1(41.07,95.67) v1(41.07,94.91) v1(41.38,137.68) v1(41.36,130.12) v1(41.64,10) v1(41.76,130.79) v1(41.83,95.67) v1(41.83,94.91) v1(41.81,13.26) v1(41.81,7.46) v1(42.02,70) v1(42.02,69.23) v1(42.02,68.47) v1(42.58,128.87) v1(42.59,95.67) v1(42.59,94.91) v1(42.76,69.98) v1(42.76,69.22) v1(42.76,68.46) v1(43.09,124.51) v1(43.35,95.67) v1(43.36,94.91) v1(43.85,124.51) v1(43.92,137.68) v1(44.35,7.46) v1(47.09,13.56) v1(47.09,10.57) v1(47.12,7.55) v1(49.63,13.56) v1(51.54,137.68) v1(52.17,13.56) v1(52.38,86.79) v1(54.08,137.68) v1(54.71,13.56) v1(55.23,22.31) v1(55.83,101.02) v1(56.23,81.81) v1(56.23,81.05) v1(56.23,80.29) v1(56.32,99.41) v1(56.62,137.68) v1(56.96,18.48) v1(57,81.81) v1(57,81.05) v1(57,80.29) v1(58.06,98.51) v1(59.16,137.68) v1(60.68,101.32) v1(61.7,137.68) v1(62.22,84.54) v1(63.95,83.08) v1(64.24,137.68) v1(64.29,87.99) v1(65.63,83.54) v1(66.15,86.89) v1(66.78,137.68) v1(69.29,137.75) v1(71.55,137.78) v1(71.61,122.62) v1(71.61,121.86) v1(71.61,121.1) v1(72.37,122.62) v1(72.37,121.86) v1(72.37,121.1) v1(72.42,135.86) v1(73.13,122.62) v1(73.13,121.86) v1(73.13,121.1) v1(73.89,122.62) v1(73.89,121.86) v1(73.89,121.1) v1(74.65,122.62) v1(74.65,121.86) v1(74.65,121.1) v1(74.85,134.99) v1(77.94,135.71) v1(79.48,137.68) v1(82.02,137.68) v1(83.97,135.05) v1(84.56,137.68) v1(86.35,14.33) v1(86.42,11.09) v1(86.46,7.4) v1(87.1,137.68) v1(87.39,16.85) v1(88.04,15.03) v1(88.65,7.43) v1(89.64,137.68) v1(90.07,13.41) v1(91.19,7.43) v1(92.18,137.68) v1(92.8,9.92) v1(93.75,122.62) v1(93.75,121.86) v1(93.76,121.09) v1(93.73,7.43) v1(94.51,122.62) v1(94.51,121.86) v1(94.52,121.09) v1(94.72,137.68) v1(95.27,122.62) v1(95.27,121.86) v1(95.28,121.09) v1(95.26,8.88) v1(96.09,122.61) v1(96.09,121.85) v1(96.09,121.09) v1(96.27,7.43) v1(96.85,122.61) v1(96.85,121.85) v1(96.85,121.09) v1(97.26,137.68) v1(98.16,11.46) v1(98.81,7.43) v1(99.8,137.68) v1(100.84,9.26) v1(101.35,7.43) v1(102.34,137.68) v1(104.88,137.68) v1(105.84,131.58) v1(106.39,19.06) v1(106.39,18.3) v1(106.39,17.54) v1(106.6,131.58) v1(107.14,19.07) v1(107.14,18.31) v1(107.37,131.58) v1(107.42,137.68) v1(107.9,18.68) v1(109.96,137.68) v1(110.71,9.11) v1(110.71,8.35) v1(111.47,9.11) v1(111.47,8.35) v1(111.56,134.85) v1(111.56,83.89) v1(112.27,83.88) v1(112.23,9.11) v1(112.23,8.35) v1(112.5,137.68) v1(112.98,83.88) v1(113.69,83.88) v1(114.43,133.23) v1(114.73,135.07) v1(115.04,137.68) v1(115.25,80.87) v1(115.28,80.16) v1(115.56,131.89) v1(115.89,72.09) v1(116.16,9.28) v1(116.39,71.59) v1(116.92,9.28) v1(117.58,137.68) v1(117.83,131.91) v1(118.47,135.02) v1(118.77,133.41) v1(120.12,137.68) v1(120.83,97.82) v1(120.83,97.06) v1(120.83,96.29) v1(120.83,95.53) v1(122.66,137.68) v1(123.28,134.12) v1(124.27,110.09) v1(124.27,109.33) v1(124.27,108.57) v1(124.37,60.17) v1(124.37,59.46) v1(125.03,110.09) v1(125.03,109.33) v1(125.03,108.57) v1(125.04,70.37) v1(125.15,72.83) v1(125.15,72.07) v1(125.2,137.68) v1(125.31,135.64) v1(125.58,69.83) v1(125.79,110.09) v1(125.79,109.33) v1(125.79,108.57) v1(125.86,72.83) v1(125.86,72.07) v1(126.07,69.31) v1(126.55,110.09) v1(126.55,109.33) v1(126.55,108.57) v1(126.75,7.43) v1(127.31,110.09) v1(127.31,109.33) v1(127.31,108.57) v1(127.67,137.71) v1(127.9,134.21) v1(129.29,7.43) v1(130.24,50.6) v1(131.83,7.43) v1(132.2,132.34) v1(132.7,60.67) v1(132.7,59.9) v1(132.82,137.68) v1(133.85,133.85) v1(134.74,7.39) v1(135.36,137.68) v1(135.88,43.33) v1(136.07,9.12) v1(136.29,69.15) v1(136.29,68.39) v1(136.42,81.74) v1(136.62,43.32) v1(136.91,7.43) v1(137.05,69.15) v1(137.05,68.39) v1(137.21,81.74) v1(137.21,80.97) v1(137.79,69.12) v1(137.81,68.38) v1(137.9,137.68) v1(138.5,97.77) v1(138.5,97.01) v1(138.5,96.25) v1(138.5,95.49) v1(138.5,94.73) v1(138.5,93.96) v1(138.5,93.2) v1(139.26,97.77) v1(139.26,97.01) v1(139.26,96.25) v1(139.26,95.49) v1(139.26,94.73) v1(139.26,93.96) v1(139.26,93.2) v1(139.45,7.43) v1(139.65,52.42) v1(140.44,137.68) v1(140.53,135.57) v1(141,48.93) v1(141.99,7.43) v1(142.38,95.12) v1(142.98,137.68) v1(143.22,92.64) v1(143.82,37.84) v1(144.53,7.43) v1(144.64,135.62) v1(145.52,137.68) v1(146.5,9.43) v1(146.82,51.77) v1(146.82,49.23) v1(146.82,46.69) v1(146.8,11.64) v1(146.91,44.27) v1(146.96,41.13) v1(147.07,7.43) v1(147.74,55.94) v1(147.82,37.81) v1(148.59,12.53) v1(148.53,8.03) v1(149.58,135.28) v1(149.64,44.31) v1(149.61,7.43) v1(149.75,55.98) v1(149.83,137.72) v1(150.15,131.05) v1(150.47,108.92) v1(150.44,106.06) v1(150.44,11.54) v1(150.49,9.11) v1(150.72,82.85) v1(150.99,37.84) v1(152.09,44.38) v1(152.09,41.84) v1(152.09,39.3) v1(152.17,137.78) v1(152.17,135.24) v1(152.17,132.7) v1(152.17,130.16) v1(152.17,127.62) v1(152.17,125.08) v1(152.17,122.54) v1(152.17,120) v1(152.17,117.46) v1(152.17,114.92) v1(152.17,112.38) v1(152.17,109.84) v1(152.17,107.3) v1(152.17,104.76) v1(152.17,102.22) v1(152.17,99.68) v1(152.17,97.14) v1(152.17,94.6) v1(152.17,92.06) v1(152.17,89.52) v1(152.17,86.98) v1(152.17,84.44) v1(152.17,81.9) v1(152.17,79.36) v1(152.17,76.82) v1(152.17,74.28) v1(152.17,71.74) v1(152.17,69.2) v1(152.17,66.66) v1(152.17,64.12) v1(152.17,61.58) v1(152.17,59.04) v1(152.17,55.96) v1(152.1,12.86) v1(152.17,10.15) v1(152.15,7.43) v2(4.24,79.39) v2(4.24,78.78) v2(4.24,78.16) v2(5.69,74.93) v2(5.71,74.4) v2(6.22,74.94) v2(6.24,74.4) v2(7.28,18.57) v2(7.26,16.76) v2(7.33,136.12) v2(7.66,134.34) v2(8.96,82.45) v2(8.96,79.56) v2(9.08,81.04) v2(9.13,65.38) v2(9.14,64.26) v2(9.36,133.31) v2(9.77,62.75) v2(9.8,63.83) v2(11.6,134.39) v2(11.78,136.35) v2(14.51,17.11) v2(15.14,14.89) v2(15.29,18.66) v2(15.3,121.03) v2(15.98,121.03) v2(16.96,14.12) v2(17.1,19.17) v2(17.52,66.14) v2(17.58,64.95) v2(18.82,14.77) v2(18.95,18.45) v2(19.6,16.3) v2(20.35,95.33) v2(20.57,69.69) v2(20.71,19.12) v2(20.79,55.35) v2(21.07,97.15) v2(21.09,69.7) v2(21.21,94.25) v2(21.2,57.12) v2(21.64,53.46) v2(21.82,20.93) v2(21.96,17.31) v2(22.6,89.85) v2(23.08,40.14) v2(23.21,57.91) v2(23.21,52.8) v2(23.4,81.99) v2(23.92,86.12) v2(23.93,80.76) v2(24.21,40.13) v2(24.69,57.68) v2(24.7,86.63) v2(25.24,82.85) v2(25.41,87.48) v2(25.44,86.02) v2(25.55,56.4) v2(25.52,54.34) v2(26.39,125.18) v2(26.62,131.43) v2(26.96,116.28) v2(27.84,126.02) v2(28.35,131.42) v2(28.47,126.01) v2(28.74,116.33) v2(29.62,131.55) v2(31.35,131.51) v2(32.19,114.31) v2(32.63,131.66) v2(32.84,114.31) v2(34.24,61.25) v2(34.24,60.49) v2(34.19,51.78) v2(34.19,50.99) v2(34.19,50.15) v2(34.36,131.63) v2(35.63,131.69) v2(37.01,101.65) v2(37.35,131.64) v2(37.48,21.11) v2(37.51,101.65) v2(37.81,80.33) v2(38.02,101.65) v2(38.06,19.54) v2(38.47,53.77) v2(38.47,53.26) v2(38.9,130.59) v2(39.69,18.14) v2(40.3,131.2) v2(40.52,36.57) v2(40.74,75.53) v2(41.19,130.68) v2(41.7,35.61) v2(41.79,19.14) v2(42.25,60.31) v2(42.75,60.32) v2(42.84,123.97) v2(43.21,60.31) v2(43.81,18.12) v2(44.43,50.95) v2(44.7,103.28) v2(44.9,19.71) v2(45.77,103.28) v2(45.86,53.33) v2(45.91,128.8) v2(46.08,105.06) v2(46.39,128.8) v2(46.3,123.02) v2(46.35,120.8) v2(46.54,103.52) v2(46.87,128.8) v2(46.94,53.31) v2(47.03,107.5) v2(47.02,106.45) v2(47.34,50.33) v2(47.64,47.77) v2(47.63,47.16) v2(48.09,36.22) v2(48.09,35.69) v2(48.48,102.04) v2(48.76,103.68) v2(48.89,44.16) v2(49.39,124.7) v2(50.21,120.89) v2(50.74,122.45) v2(51.24,111.57) v2(51.22,110.95) v2(51.25,59.47) v2(51.33,64.04) v2(51.74,109.1) v2(51.72,59.47) v2(52.13,123.48) v2(52.15,64.04) v2(52.22,109.09) v2(52.46,124.66) v2(53.02,36.4) v2(53.26,50.2) v2(53.38,111.05) v2(53.93,109.02) v2(55.02,125.07) v2(55.42,123.01) v2(55.58,127.58) v2(56.3,118.62) v2(56.3,117.1) v2(56.3,115.57) v2(56.3,28.51) v2(56.48,40.55) v2(56.53,42.23) v2(56.55,38.7) v2(56.73,85.08) v2(56.73,84.57) v2(56.73,84.06) v2(57.38,34.98) v2(57.43,30.88) v2(57.55,18.42) v2(57.76,40.55) v2(57.83,118.62) v2(57.83,117.1) v2(57.83,115.57) v2(57.82,42.23) v2(57.84,38.7) v2(58.03,34.97) v2(58,28.56) v2(58.04,13.58) v2(58.29,127.58) v2(58.38,107.67) v2(58.62,11.47) v2(58.77,7.7) v2(58.8,124.77) v2(59.1,115.39) v2(59.16,30.9) v2(59.27,127.58) v2(59.35,118.62) v2(59.35,117.1) v2(59.39,57.33) v2(59.39,56.85) v2(59.47,52.26) v2(59.65,86.72) v2(59.88,28.58) v2(59.9,13.47) v2(61.83,120.07) v2(62.01,127.59) v2(62.1,7.67) v2(62.2,30.89) v2(62.43,11.4) v2(62.56,124.98) v2(62.68,55.25) v2(62.69,54.08) v2(63.12,117.67) v2(63.13,116.56) v2(63.88,59.47) v2(64.97,120.64) v2(64.9,119.37) v2(65.08,59.47) v2(65.63,128.76) v2(66.28,60.89) v2(66.23,37.43) v2(66.92,128.76) v2(67.48,59.47) v2(67.91,110.98) v2(68.68,61.6) v2(68.68,59.47) v2(68.64,44.87) v2(69.03,44.6) v2(69.14,110.52) v2(69.28,30.96) v2(69.64,83.07) v2(70.09,112.02) v2(70.51,30.96) v2(71.33,111.07) v2(71.86,75.83) v2(72.05,78.32) v2(72.65,111.9) v2(73.05,30.96) v2(74.19,111.49) v2(75.59,30.96) v2(76.03,102.54) v2(77.13,113.77) v2(77.14,113.3) v2(77.15,112.84) v2(77.39,51.51) v2(77.76,102.35) v2(78.06,86.5) v2(78.13,30.96) v2(78.77,88.48) v2(78.77,86.5) v2(79.48,61.6) v2(79.48,59.47) v2(80.68,59.47) v2(80.67,30.96) v2(80.9,83.61) v2(80.9,79.71) v2(82.48,60.89) v2(82.6,81.38) v2(82.81,94.95) v2(83.39,80.62) v2(83.8,100.93) v2(83.8,96.37) v2(84.17,88.96) v2(84.96,83.65) v2(85.36,116.53) v2(85.48,55.25) v2(86,104.99) v2(86.98,53.42) v2(86.98,52) v2(87.28,60.18) v2(87.28,54.54) v2(87.33,123.31) v2(87.31,81.38) v2(87.51,119.46) v2(87.68,96.37) v2(87.68,74.73) v2(87.98,119.44) v2(88.09,85.93) v2(88.78,52) v2(88.88,88.2) v2(89.08,60.18) v2(89.08,54.54) v2(90.58,83.61) v2(90.58,79.71) v2(90.58,53.42) v2(90.58,52) v2(90.88,60.18) v2(92,90.39) v2(92.38,54.13) v2(92.38,52.71) v2(92.44,109.65) v2(92.41,108.67) v2(92.65,61.02) v2(92.99,51.64) v2(94.14,83.61) v2(94.18,53.42) v2(94.18,52) v2(94.48,61.6) v2(94.48,60.18) v2(94.48,54.54) v2(95.76,115) v2(95.77,113.55) v2(95.98,52) v2(96.28,54.54) v2(96.54,60.18) v2(96.52,53.16) v2(97.34,117.12) v2(97.78,53.42) v2(97.78,52) v2(98.08,60.18) v2(98.08,54.54) v2(98.8,91.38) v2(99.58,53.42) v2(99.58,52) v2(99.88,61.6) v2(99.88,60.18) v2(100.25,114.37) v2(100.58,91.94) v2(101.01,114.35) v2(101.08,60.18) v2(101.31,82) v2(101.34,61.72) v2(101.57,114.35) v2(101.63,87.5) v2(101.98,93.34) v2(102.13,114.35) v2(102.28,59.47) v2(102.43,96.13) v2(102.43,85.55) v2(103.24,117.05) v2(103.48,59.47) v2(103.53,7.24) v2(105.28,60.89) v2(105.98,7.25) v2(106.03,87.62) v2(106.48,61.6) v2(106.48,59.47) v2(107.17,11.71) v2(107.68,59.47) v2(107.81,11.71) v2(108.36,87.61) v2(108.31,7.25) v2(108.77,83.8) v2(109.37,86.45) v2(109.45,85.02) v2(110.02,19.35) v2(110.05,18.86) v2(110.05,18.3) v2(110.05,17.74) v2(110.4,19.62) v2(110.86,19.61) v2(110.9,7.25) v2(111.32,19.61) v2(111.67,17.69) v2(111.96,91.91) v2(111.96,91.15) v2(112.14,17.69) v2(112.34,118.28) v2(112.34,116.7) v2(112.34,115.43) v2(112.6,17.69) v2(112.88,19.64) v2(113.07,17.69) v2(113.37,19.64) v2(113.41,118.28) v2(113.41,115.43) v2(113.48,91.91) v2(113.48,91.15) v2(113.58,17.69) v2(113.68,59.47) v2(113.85,75.25) v2(113.85,19.64) v2(113.93,7.29) v2(114.05,17.69) v2(114.31,75.24) v2(114.35,70.14) v2(114.36,19.64) v2(114.66,69.8) v2(114.76,75.24) v2(114.88,59.47) v2(114.89,118.28) v2(114.89,116.7) v2(114.89,115.43) v2(115.01,91.91) v2(115.01,91.15) v2(115,69.47) v2(115.36,69.12) v2(115.68,68.78) v2(115.87,80.87) v2(115.87,80.38) v2(116.01,68.45) v2(116.08,59.47) v2(116.48,72.21) v2(116.58,112.61) v2(116.54,85.37) v2(116.54,84.86) v2(116.54,84.3) v2(116.84,71.23) v2(116.81,7.25) v2(117.28,60.89) v2(119.08,61.6) v2(119.08,59.47) v2(119.39,7.24) v2(119.67,102.18) v2(119.82,103.95) v2(120.23,68.87) v2(120.23,68.4) v2(120.23,67.89) v2(121.83,7.25) v2(124.27,7.26) v2(127.94,20.29) v2(127.94,19.1) v2(127.98,17.11) v2(128.73,56.44) v2(128.73,55.89) v2(129.34,18) v2(129.46,20.28) v2(129.45,19.2) v2(129.77,77.51) v2(129.78,75.8) v2(130.83,81.64) v2(130.83,80.61) v2(130.97,18.03) v2(131.02,51.99) v2(131,20.29) v2(130.99,19.21) v2(131.25,62.28) v2(131.49,73.23) v2(131.69,124.62) v2(131.69,123.63) v2(131.69,122.74) v2(132.11,60.53) v2(132.12,60.02) v2(132.58,124.62) v2(132.58,123.63) v2(132.58,122.74) v2(133.3,63.82) v2(133.47,124.62) v2(133.47,123.63) v2(133.47,122.74) v2(133.75,67.65) v2(133.76,67.1) v2(133.76,66.46) v2(135.1,16.11) v2(135.25,114.27) v2(135.24,113.64) v2(135.47,45.5) v2(135.88,72.82) v2(135.91,105.35) v2(135.91,103.67) v2(135.94,102.1) v2(135.93,100.6) v2(135.94,99.04) v2(136.07,45.5) v2(136.35,72.82) v2(136.62,15.08) v2(136.83,124.72) v2(136.85,123.68) v2(137.75,66.74) v2(139.83,22.82) v2(139.83,22.33) v2(139.84,21.82) v2(139.98,126.93) v2(139.9,117.78) v2(139.89,116) v2(141.74,126.93) v2(142.81,87.55) v2(142.83,78.12) v2(143.17,105.3) v2(143.17,103.89) v2(143.17,102.32) v2(143.17,100.84) v2(143.14,85.48) v2(143.19,99.28) v2(143.88,88.86) v2(144.87,128.5) v2(145.48,128.49) v2(145.54,89.09) v2(146.63,85.22) v2(146.88,88.21) v2(146.98,54.58) v3(8.96,44.42) v3(9.56,44.4) v3(9.72,36.41) v3(10.55,37.23) v3(16.98,20.51) v3(18.42,27.61) v3(18.86,35.34) v3(18.96,36.99) v3(19.77,36.25) v3(20.49,36.86) v3(20.55,35.43) v3(26.28,43.44) v3(27.32,43.46)
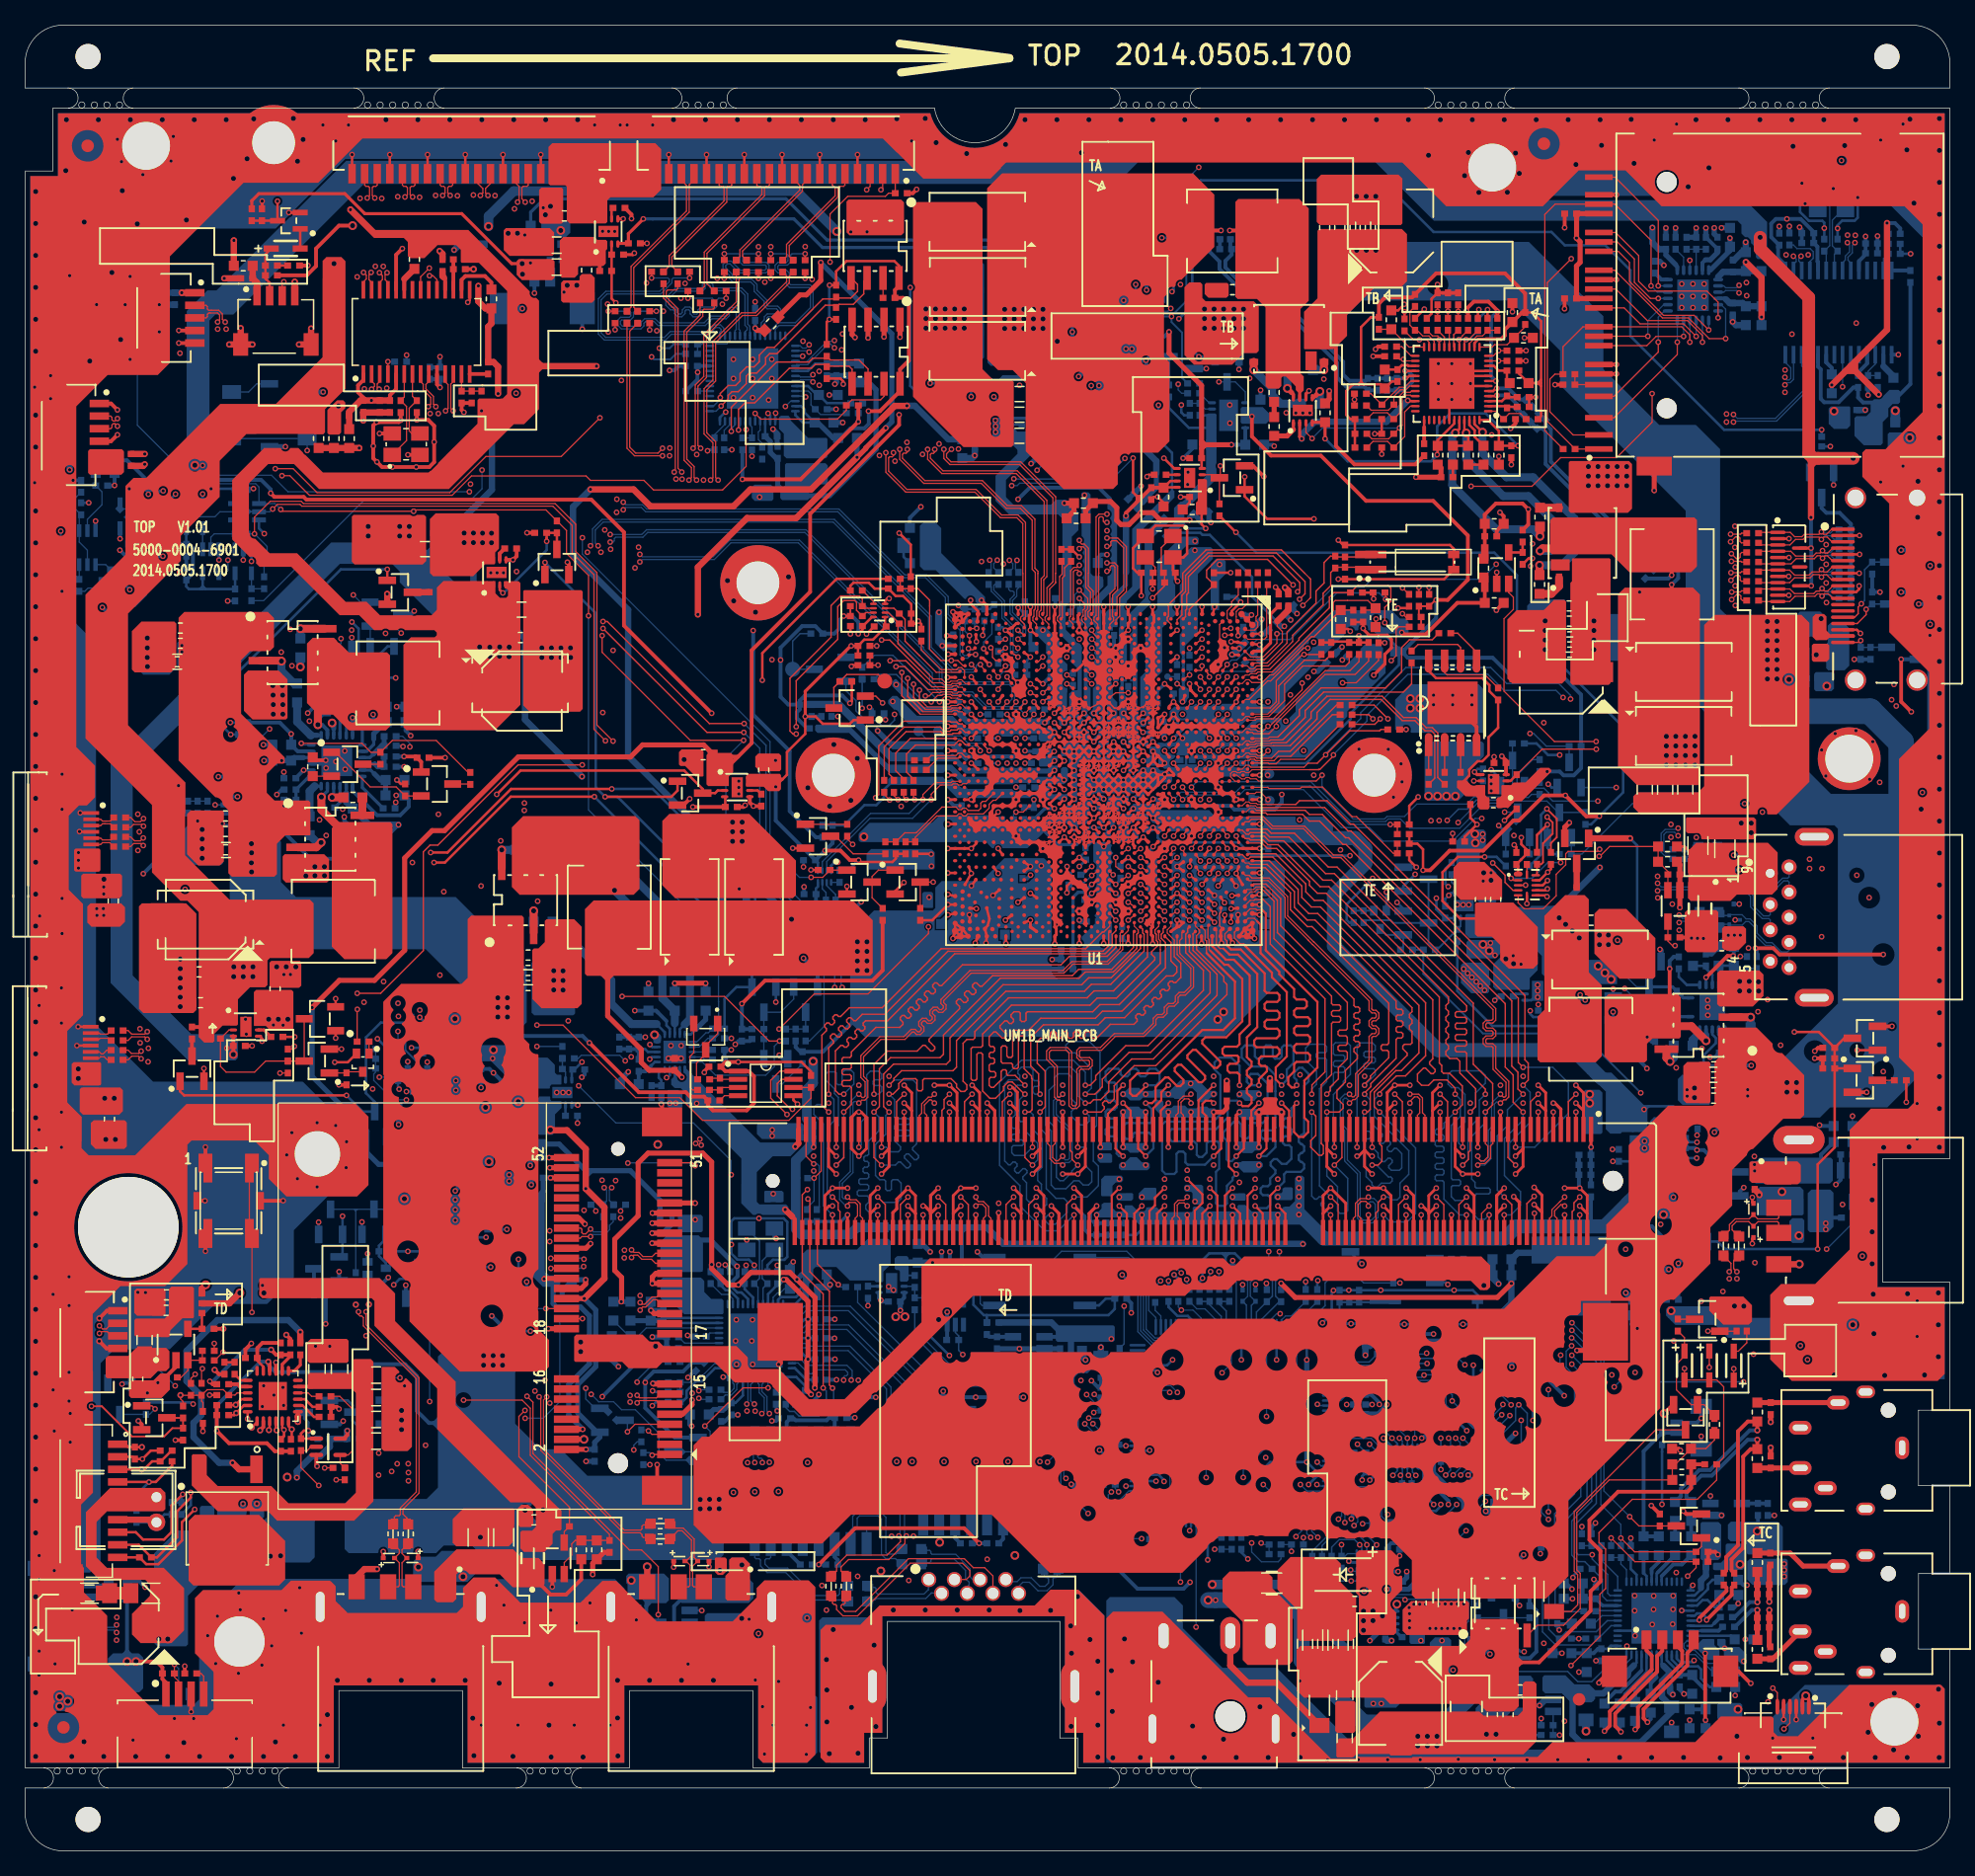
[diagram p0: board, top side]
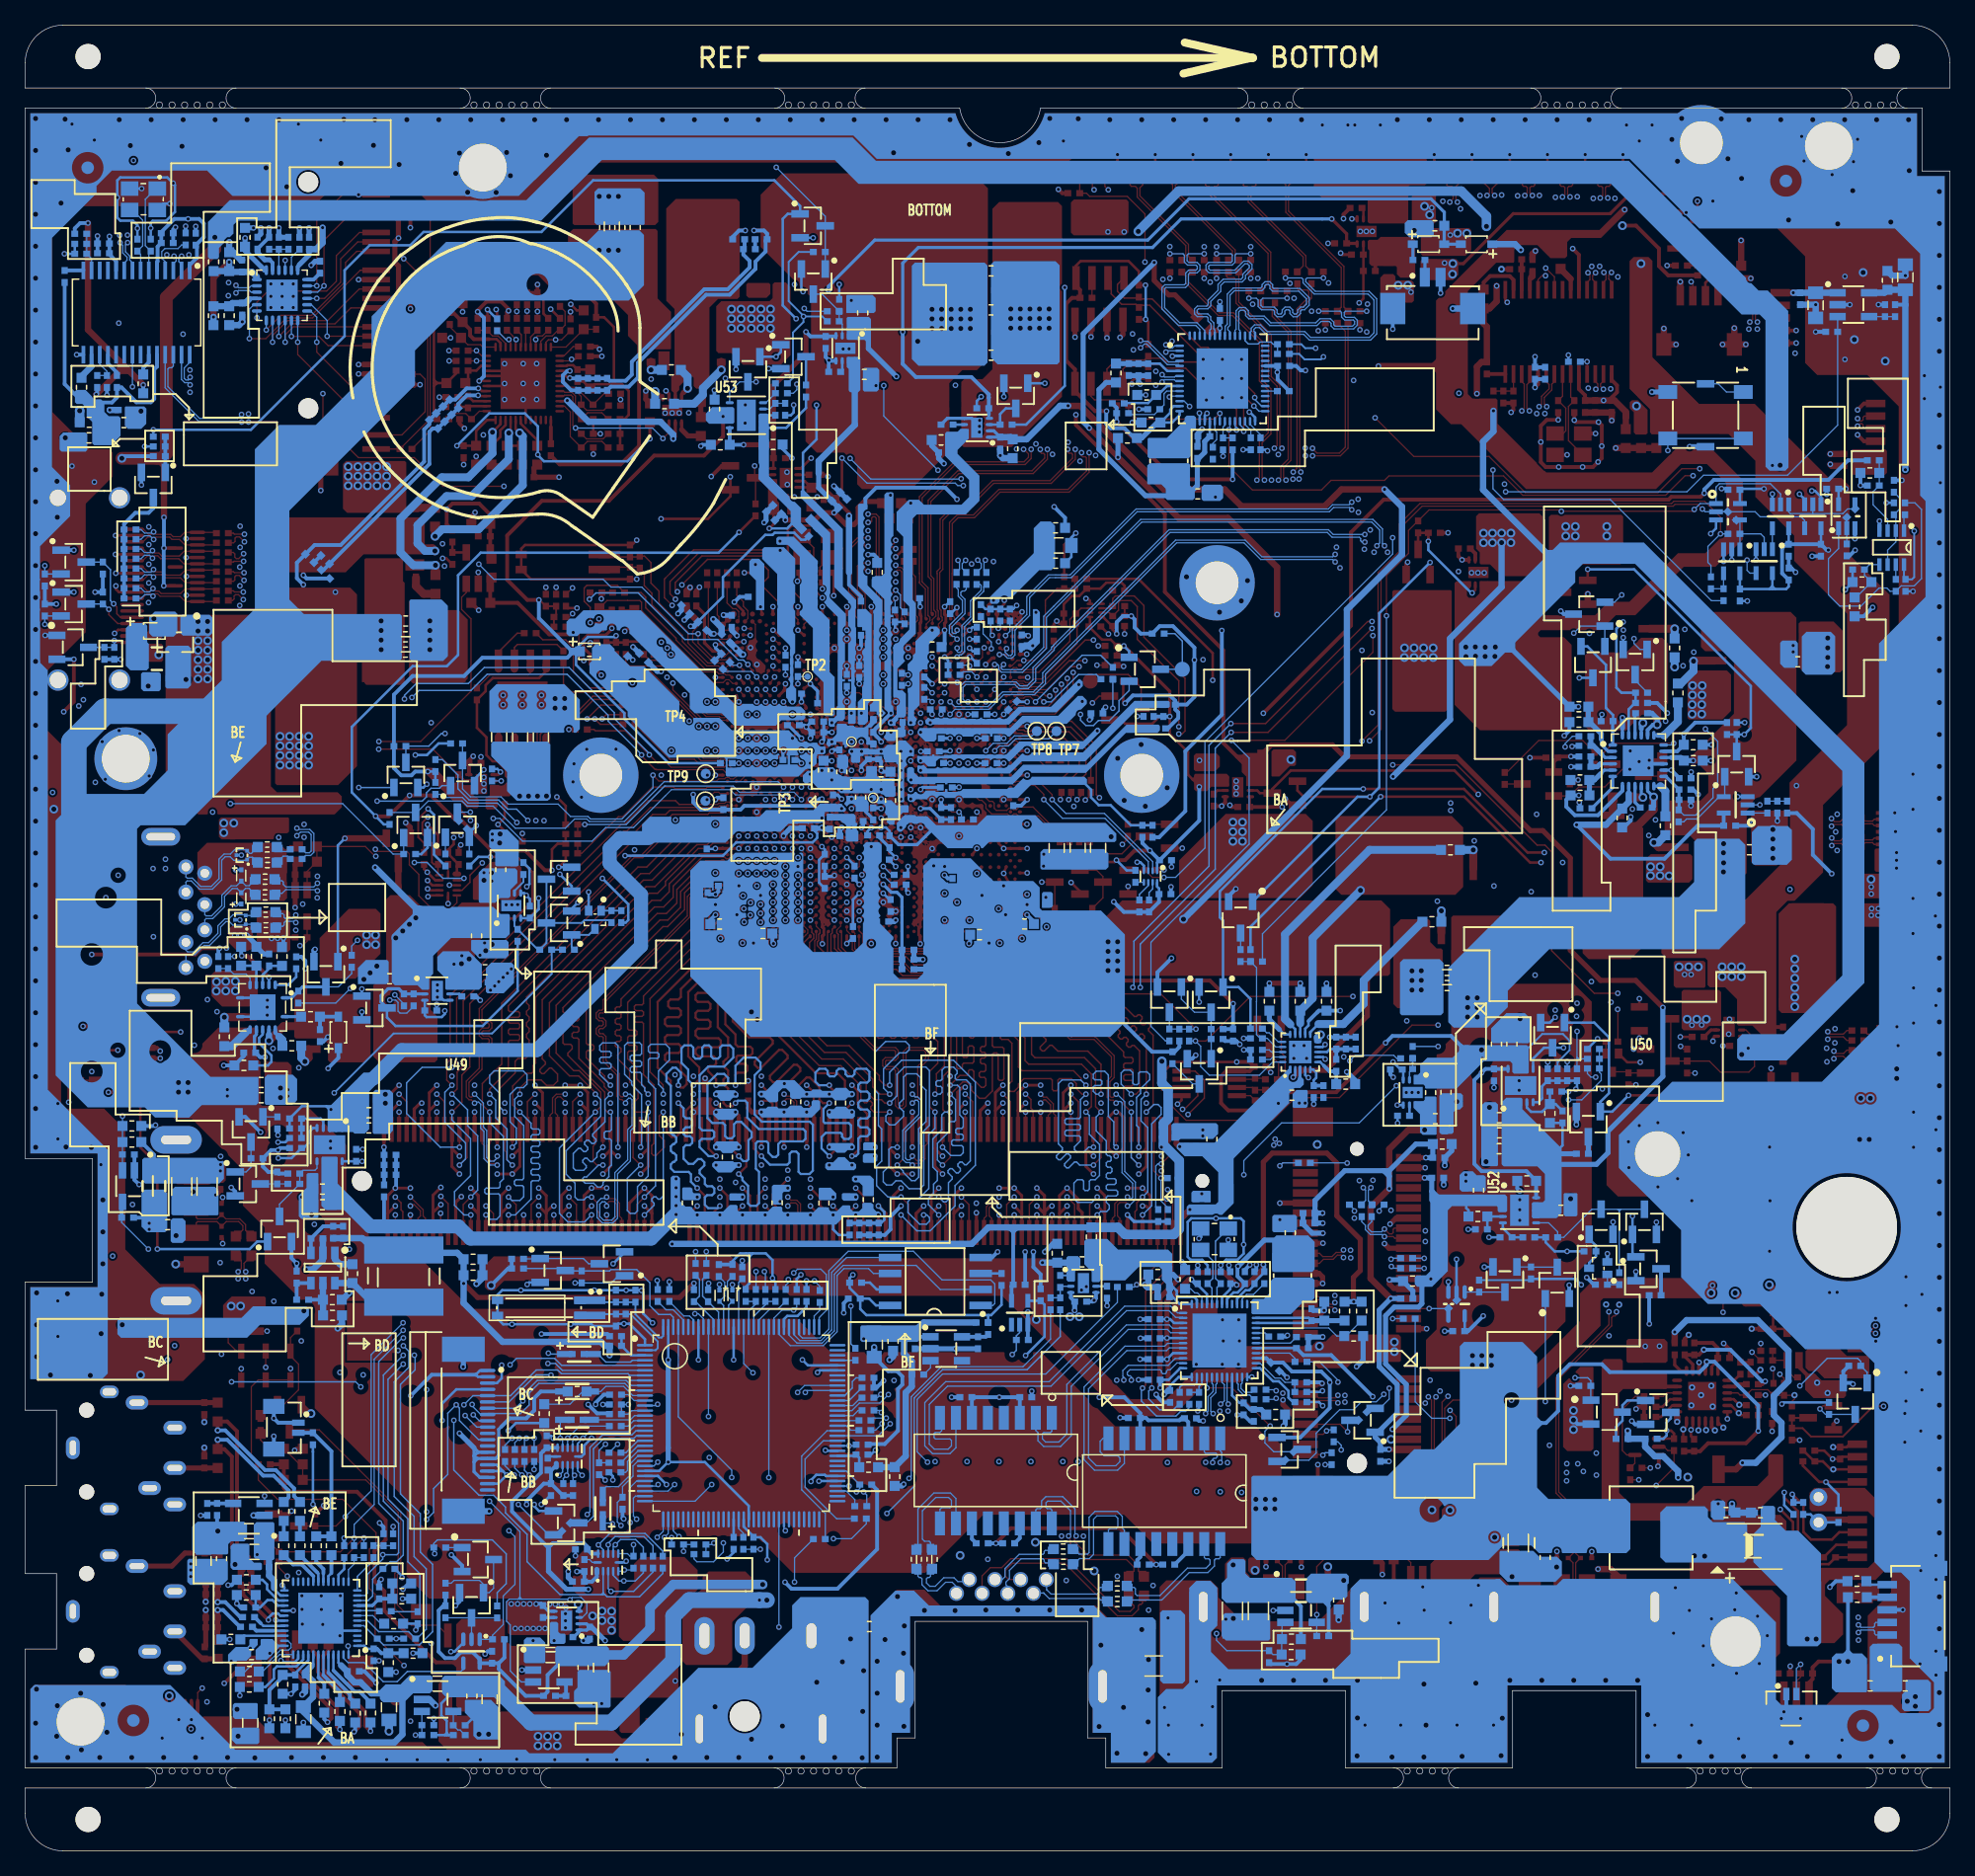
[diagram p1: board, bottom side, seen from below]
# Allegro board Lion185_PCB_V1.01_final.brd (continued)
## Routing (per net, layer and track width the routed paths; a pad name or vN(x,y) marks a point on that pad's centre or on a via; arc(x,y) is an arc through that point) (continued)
GND_EARTH:
  vias: v1(63.7,15.21) v1(63.73,12.79) v1(63.73,10.25) v1(63.92,7.73) v1(64.24,17.6) v1(65.69,11.41) v1(66.21,7.76) v1(67.49,16.36) v1(67.63,9.89) v1(68.02,22.26) v1(69.01,19.15) v1(71.55,19.15) v1(72.7,24.54) v1(74.09,19.15) v1(76.63,19.15) v1(78.68,23.5) v1(79.08,19.11) v1(81.52,19.12) v1(83.11,17.89) v1(83.18,15.72) v1(83.14,9.9) v1(83.66,20.22) v1(84.65,16.81) v1(85.27,15.08) v1(85.27,12.54) v1(85.27,10) v1(85.27,7.46) v2(63.34,21.1) v2(63.7,19.15) v2(66.18,21.83) v2(68.88,25.03) v2(70.24,21.51) v2(70.61,25.03) v2(76.48,23.19)
V1P0A_VR_PWRGD: length 198.1
  LAY3 w0.102: v2(30.47,29.43) 30.47,29.31 36.28,23.5 59.61,23.5 65.58,29.47 79.68,29.47 83.05,26.1 102.67,26.1 103.55,26.98 107.17,26.98 108.06,26.1 119.53,26.1 121.13,27.69 124.49,27.69 133.13,36.33 133.13,42.4 133.77,43.04 133.77,49.08 138,53.31 138,64 135.57,66.43 135.57,70.36 v2(136.35,71.14)
  LAY4 w0.102: v2(30.71,63.87) 30.03,63.19 30.03,61.85 30.75,61.14 30.75,60.17 v2(30.31,59.73) 31.37,58.66 31.37,30.33 v2(30.47,29.43)
  BOTTOM w0.102: v2(136.35,71.14) 136.36,71.12 R466.1 ; v2(30.31,59.73) 29.26,59.73 27.71,61.27 27.71,61.79 27.86,61.93 R732.2 R734.2 C766.1
  BOTTOM w0.203: v2(30.71,63.87) Q50.3 32.26,63.87 33.13,63.01 U50.6
V1P0S_EN: length 21.7
  BOTTOM w0.102: U46.3 121.18,68.15 121.18,68.15
  BOTTOM w0.203: R645.2 113.85,68.38 116.63,65.6 123.56,65.6 124.24,66.28 Q81.3
  BOTTOM w0.254: 121.18,68.15 R458.2 R493.2 123.3,68.56 124.16,68.56 124.71,68.01 124.71,67.51 Q81.3
V1P0SX_PWRGD: length 21.5
  BOTTOM w0.102: R716.1 2.78,107.21 2.26,106.69 2.26,101.18 2.83,100.61 3.87,100.61 R724.2 4.74,100.17 5,100.43 5.63,100.43 7.07,99 8.75,99 9.65,99.89 9.65,102.77 8.84,103.57 U34.1
V1P2A_VR_PWRGD: length 197.9
  LAY3 w0.102: v2(29.63,65.17) 30.31,65.17 31.11,64.37 40.83,64.37 44,61.2 v2(44,60.85)
  LAY4 w0.102: v2(29.63,65.17) 29.29,65.52 29.29,66.53 30.67,67.91 30.67,73.23 31.42,73.98 31.42,79.95 32.22,80.75 32.22,106.75 36.33,110.87 39.47,110.87 46.95,118.35 49.07,118.35 49.33,118.09 50.63,118.09 51.02,118.48 54.3,118.48 54.64,118.14 61.9,118.14 62.46,118.7 88,118.7 90.06,116.65 v2(91.66,116.65) ; v2(99.76,42.72) 99.09,43.39 88.82,43.39 86.32,45.89 70.97,45.89 69.22,47.64 58.85,47.64 56.12,50.36 v2(56.12,53.77)
  BOTTOM w0.102: 29.64,63.12 29.64,65.17 v2(29.63,65.17) ; 29.64,63.12 29.53,63.01 29.53,62.99 ; 29.64,63.12 29.64,63 ; 29.54,62.99 29.63,62.99 29.64,63 ; 29.54,62.99 29.53,62.99 ; 29.54,62.99 29.64,62.89 ; v2(44,60.85) 46.95,57.89 53.12,57.89 56.12,54.89 v2(56.12,53.77) ; 29.53,62.99 R734.1 ; 29.64,63 29.64,62.89 ; 29.64,62.89 R715.1 ; v2(91.66,116.65) 91.66,116.2 91.93,115.92 R484.2 ; U28.120 99.08,42.32 99.48,42.72 v2(99.76,42.72)
V1P2S_EN: length 108.8
  TOP w0.102: R560.1 21.18,63.76 v2(21.4,63.98) ; U54.3 93.57,109.44 94.34,109.44 94.58,109.2 Q83.3 ; Q83.3 95.01,109.28 v2(95.01,110.15) ; Q83.3 94.94,107.13 R492.1
  LAY3 w0.102: v2(39.69,83.33) 40.3,82.71 40.3,76.34 33.04,69.07 29.6,69.07 26.2,65.68 23.09,65.68 v2(21.4,63.98)
  LAY4 w0.102: v2(78.6,109.12) 58.89,109.12 58.44,108.67 56.4,108.67 55.55,107.83 55.55,105.78 39.69,89.92 v2(39.69,83.33) ; v2(87.42,110.74) 87.87,111.19 93.97,111.19 v2(95.01,110.15)
  BOTTOM w0.102: v2(78.6,109.12) 78.62,109.1 85.78,109.1 v2(87.42,110.74)
V1P05S_EN: length 2.2
  BOTTOM w0.102: R476.2 R503.2 Q73.3
V1P5S_VR_PWRGD: length 59.9
  TOP w0.203: v2(37.49,84.02) 39.38,85.91 52.39,85.91 53.86,84.45 Q82.3 54.85,84.12 55.06,84.33 U51.3
  LAY4 w0.203: v2(36.64,48.79) 37.48,49.63 37.48,60.58 39.98,63.08 39.98,71.72 35.71,75.99 35.71,82.24 v2(37.49,84.02)
  BOTTOM w0.203: R490.2 v2(36.64,48.79)
V1P05S_VR_PWRGD: length 157.6
  LAY3 w0.203: v2(137.46,55.23) 137.46,55.24 137.75,55.52 137.75,63.89 135.3,66.34 135.3,69.41 134.37,70.34 134.37,81.62 137.68,84.92 137.68,114.51 134.96,117.23 128.54,117.23 122.27,123.49 89.07,123.49 88.29,124.28 v2(88.29,124.58)
  LAY4 w0.203: v2(137.46,55.23) 137.46,55.24 137.32,55.1 v2(132.88,55.1) ; v2(70.36,124.34) 70.61,124.58 v2(88.29,124.58)
  BOTTOM w0.203: v2(132.88,55.1) 131.83,55.1 R477.2 130.86,55.89 130.48,56.27 130.48,57.13 130.12,57.49 U49.5 ; v2(70.36,124.34) 70.36,116.51 73.44,113.43 R472.1 ; v2(88.29,124.58) 88.29,124.58 R453.2
V1P8A_VR_PWRGD: length 205.7
  LAY3 w0.102: v2(136.99,71.8) 136.99,70.86 135.78,69.65 135.78,68.16 136.08,67.86 137.53,67.86 138.28,67.11 138.28,51.86 134.28,47.85 134.28,37.04 124.72,27.49 123.01,27.49 121.36,25.84 107.69,25.84 106.74,26.78 103.95,26.78 103.05,25.88 82.96,25.88 79.59,29.25 65.65,29.25 59.64,23.24 35.07,23.24 30,28.32 30,29.61 v2(30.47,30.08)
  LAY4 w0.102: v2(30.47,30.08) 31.17,30.78 31.17,58.24 29.73,59.67 v2(29.73,60.58) ; v2(126.59,72.42) 127.68,71.32 134.9,71.32 135.37,71.8 v2(136.99,71.8)
  BOTTOM w0.102: R733.1 127.04,71.96 v2(126.59,72.42)
  BOTTOM w0.203: U50.5 32.71,59.54 32.42,59.83 32.42,60.8 R479.2 R483.2 R714.1 R715.2 29.64,60.67 v2(29.73,60.58)
V1P35S_PWRGD: length 15.7
  BOTTOM w0.102: 26.28,50.9 26.28,51.02 26.28,51.02 ; 26.28,50.9 R247.1 ; 26.28,50.9 26.15,51.02 ; 26.28,50.9 26.41,51.02 ; 26.15,51.02 26.28,51.02 ; 26.15,51.02 Q86.3 ; 26.28,51.02 26.41,51.02 ; U52.6 31.89,49.95 31.18,49.24 R498.2 30.69,48.79 28.46,51.03 27.73,51.03 Q71.3 27.72,51.02 26.41,51.02
V3P3S_EN: length 14.1
  TOP w0.102: Q84.3 22.18,62.82 Q45.3 22.18,62.81 R560.2 19.12,62.81 18.24,61.93 15.98,61.93 15.53,62.38 R556.2 16.21,65.29 U68.3
V5_CORE: length 30.4
  TOP w0.203: U56.48 116.28,113.8 117.15,112.93 C467.2 R514.1 v2(118.68,111.75) ; U56.43 113.61,113.52 112.29,112.2 C469.1 112.29,111.08 v2(112.25,111.04)
  TOP w0.254: U57.4 102.37,113.62 103.33,113.62 C479.2 103.33,112.31 v2(103.33,112.31)
  BOTTOM w0.203: v2(103.33,112.31) 105.13,110.52 111.76,110.52 112.25,111 v2(112.25,111.04) 112.25,113.29 113.27,114.32 116.11,114.32 v2(118.68,111.75)
VBAT: length 2.9
  BOTTOM w0.203: U28.3 104.84,39.41 R290.2 R291.2
VCC1_USB3.0: length 1.6
  TOP w0.203: R363.2 131.91,79.88 132.61,79.18
VCC_8625: length 51
  TOP w0.203: v2(63.94,124.52) R171.2 64.47,125.61 65.28,126.43 69.1,126.43 69.46,126.07 U12.8 ; v2(65.03,116.65) 65.03,116.87 64.81,117.09 R188.1 ; R187.1 63.72,121.6 v2(63.93,121.8) R170.2
  TOP w0.305: v2(67.04,114.5) 67.95,114.5 69.54,116.09 U13.8 69.54,117.82 70.25,118.52 70.25,123.05 69.78,123.51 R169.2 69.14,124.14 69.46,124.46 U12.8
  LAY3 w0.203: v2(63.94,124.52) 64.07,124.64 66.12,124.64 67.6,123.16 67.6,119.21 v2(65.03,116.65)
  BOTTOM w0.203: U10.14 61.23,114.18 61.82,113.6 C166.1 61.97,114.38 61.97,114.63 61.7,114.9 U10.13 ; v2(63.93,121.8) 63.93,124.5 v2(63.94,124.52)
  BOTTOM w0.305: v2(67.04,114.5) 67.06,114.48 67.06,113.49 66.71,113.14 65.61,113.14 64.83,112.36 FB3.1
  BOTTOM w0.406: C166.1 63.01,113.6 64.24,112.36 FB3.1
VCC_USB1: length 2.5
  BOTTOM w0.305: R369.2 142.76,55.37 F4.2
  vias: v2(137.47,54.58) v2(137.48,54.07)
VCC_USB2: length 5.6
  TOP w0.305: 41.03,21.12 41.77,20.38 43,20.38 44.21,21.59 R373.2
VCC_USB3: length 3.4
  BOTTOM w0.305: 52.11,19.97 51.59,19.45 R372.2
  vias: v1(56.98,22.74)
VCCAPWROK_AND: length 1.7
  BOTTOM w0.102: U40.1 U38.4
VDD10: length 66.5
  TOP w0.406: v2(60.29,45.44) 60.5,45.44 62.23,43.71 v2(62.23,42.28) v2(62.23,40.78) v2(62.23,39.1) 62.14,39.01 62.14,36.63 v2(62.48,36.3)
  LAY3 w0.406: v2(60.29,45.44) 57.62,45.44 56.59,46.46 v2(56.59,46.49) ; v2(45.88,36.12) 45.88,34.36 47.64,32.59 51.8,32.59 v2(52.99,33.78) 53.6,33.17 59.35,33.17 v2(62.48,36.3)
  BOTTOM w0.203: U17.29 51.95,39.98 C205.1 ; U17.13 61.3,37.68 61.99,37 C202.1 ; U17.3 61.67,41.98 61.97,42.28 v2(62.23,42.28) C204.1 ; U17.9 61.75,39.58 v2(62.23,39.1) C203.1 ; C206.1 59.79,45.01 59.06,44.28 U17.45 ; U17.41 57.46,43.89 56.94,44.41 56.61,44.41 56.04,44.98 C201.1 ; U17.6 v2(62.23,40.78) 62.76,40.78 C207.1
  BOTTOM w0.305: v2(45.88,36.12) 49.18,39.43 51.39,39.43 C205.1 ; C201.1 56.63,45.7 56.63,46.46 v2(56.59,46.49) ; v2(60.29,45.44) 59.96,45.11 C206.1
  BOTTOM w0.406: v2(62.48,36.3) 62.16,36.62 C202.1 ; R220.2 52.83,34.69 52.83,33.94 v2(52.99,33.78) ; v2(56.59,46.49) 56.57,46.49 54.49,48.58 53.76,48.58
VDD12: length 20.1
  BOTTOM w0.203: U10.19 C172.2
  BOTTOM w0.406: 60.5,107.91 59.82,108.59 C171.2 59.71,110.75 59.23,111.22 59.23,112.09 C172.2 ; FB2.2 67.07,116.78 67.64,116.21 67.64,111.47 63.95,107.78 61.99,107.78
VDD18: length 1.2
  BOTTOM w0.305: C706.2 130.07,124.97 U95.18
VDD33: length 83.2
  TOP w0.406: v2(62.78,36.82) 62.78,36.92 62.79,36.94 62.79,44.01 v2(61.35,45.44) 60.8,46 57.68,46 v2(56.69,45.01) 55.87,45.01 54.57,46.31 v2(54.57,46.63) 54.57,54.78 53.86,55.49 49.52,55.49 48.73,54.7 48.73,50.5 46.87,48.64 46.87,46.15 47.41,45.6 47.41,43.7 v2(47.39,43.68)
  LAY3 w0.406: v2(49.29,37.25) 49.29,37.42 47.39,39.33 v2(47.39,43.68)
  BOTTOM w0.203: U17.12 61.18,38.38 62.1,37.46 C193.1 ; R226.1 54.5,46.01 55.28,45.23 C192.1 55.28,45 55.68,44.59 55.99,44.59 56.66,43.92 U17.39 ; U17.47 59.86,43.84 60.06,44.04 61.29,44.04 61.46,44.21 61.46,44.54 61.75,44.83 C195.1 ; C191.1 57.2,44.67 57.86,44.01 U17.42 ; U17.48 61.21,43.48 61.77,44.04 C194.1 ; U17.27 54.64,39.18
  BOTTOM w0.305: C193.1 62.77,36.94 62.78,36.94 v2(62.78,36.82) ; Q64.1 51.64,32.88 49.29,35.23 v2(49.29,37.25) 49.29,37.44 49.97,38.12 52.3,38.12 53.01,38.83 C196.1 54.34,39.18 54.64,39.18 ; R226.1 54.5,46.56 v2(54.57,46.63) ; v2(56.69,45.01) 56.78,45.09 57.18,45.09 C191.1
  BOTTOM w0.406: R211.2 v2(47.39,43.68) R214.1 ; C194.1 62.03,44.04 C195.1 ; v2(61.35,45.44) 61.74,45.84 C190.1
VDDIO_8625: length 40.1
  TOP w0.305: R185.2 66.23,113.66 v2(66.23,113.66) 61.65,109.08 v2(57.01,109.08)
  TOP w0.406: FB16.2 58.2,120.93 v2(58.03,121.1)
  LAY3 w0.305: v2(53.46,117.59) 56.97,121.1 v2(58.03,121.1) 59.18,121.1 61.3,118.98 61.3,117.28 63.35,115.22 64.67,115.22 v2(66.23,113.66)
  BOTTOM w0.203: U10.50 v2(58.03,121.1)
  BOTTOM w0.305: C150.2 58.03,121.1 v2(58.03,121.1) ; R154.2 66.24,114.78 66.24,114.34 R155.2 66.23,113.72 66.23,113.71 v2(66.23,113.66) ; 53.44,117.57 53.44,117.02 R184.2 ; 53.44,117.57 v2(53.46,117.59) ; 53.44,117.57 C164.2 U10.38 ; R186.2 v2(57.01,109.08)
VDDRX: length 5.3
  BOTTOM w0.203: C162.2 62.8,118.28 62.22,117.7 U10.6
  BOTTOM w0.406: FB2.1 C160.2 65.26,118.28 C161.2 C162.2
1P0A_ONOFF: length 141.4
  LAY3 w0.102: v2(25.11,96.41) 32.85,88.67 v2(32.85,82.44)
  LAY4 w0.102: v2(98.43,29.13) 96.69,30.87 85.2,30.87 81.86,34.21 68.05,34.21 66.81,32.97 63.22,32.97 62.37,32.12 55.51,32.12 55.08,31.69 52.32,31.69 49.5,28.86 44.38,28.86 34.65,38.6 34.65,64.79 33.45,66 33.45,75.47 32.88,76.04 32.88,82.41 v2(32.85,82.44)
  BOTTOM w0.102: v2(25.11,96.41) 25.11,96.03 24.63,95.55 Q43.1 ; v2(98.43,29.13) 99.75,27.81 103.73,27.81 U28.32
1P05_FB: length 3.9
  BOTTOM w0.203: R475.2 R473.2 C563.2 129.51,58.24 129.3,58.03 U49.4
1P8A_FB: length 4.9
  BOTTOM w0.203: R480.2 31.34,59.39 C564.2 ; R480.2 R482.1 ; R480.2 32.41,58.78 33.29,58.78 33.63,59.11 U50.4
3.3ASOC_ONOFF: length 147.1
  TOP w0.102: v2(124.88,88.23) 121.56,88.23 117.56,92.23 117.56,97.99 118.3,98.73 118.3,99.7 117.93,100.08 U73.3
  LAY3 w0.102: v2(144.47,51.4) 144.97,51.9 144.97,56.36 147.06,58.46 147.06,83.2 148.28,84.42 148.28,91.46 v2(148.37,91.55)
  LAY4 w0.102: v2(144.47,51.4) 125.62,51.4 122.45,48.24 103.87,48.24 101.16,45.53 94.15,45.53 93.72,45.96 v2(91.9,45.96) ; v2(148.37,91.55) 147.19,90.37 127.03,90.37 v2(124.88,88.23)
  BOTTOM w0.102: v2(91.9,45.96) 91.6,46.26 89.75,46.26 89.32,45.83 89.32,42.97 89.88,42.41 U28.97
3A5A_PWRGD: length 249.9
  LAY3 w0.102: v2(29.58,30.79) 29.58,28.23 34.9,22.91 48.3,22.91 49.48,21.73 58.42,21.73 65.73,29.04 79.46,29.04 82.86,25.64 89.84,25.64 90.51,24.98 93.73,24.98 94.19,25.44 103.56,25.44 103.91,25.08 121.02,25.08 123.22,27.28 125.01,27.28 134.5,36.78 134.5,47.77 138.51,51.78 v2(138.51,67.7)
  LAY4 w0.102: v2(138.51,67.7) 135.16,67.7 134.27,68.59 v2(127.15,68.59) ; v2(25.97,97.73) 26.49,97.22 26.49,69.42 27.61,68.3 27.61,65.81 27.3,65.51 27.3,62.39 v2(28.15,61.53) 28.3,61.39 28.3,59.85 27.98,59.53 27.98,41.73 28.81,40.9 28.81,31.55 v2(29.58,30.79)
  BOTTOM w0.102: R732.1 28.81,61.81 28.54,61.53 v2(28.15,61.53) ; R457.1 128.31,67.43 v2(127.15,68.59)
  BOTTOM w0.203: U42.23 25.53,90.79 25.03,91.29 R390.1 R675.2 26.1,92.11 26.51,92.51 26.51,97.2 v2(25.97,97.73)
5A_ONOFF: length 163.4
  LAY3 w0.102: v2(28.1,29.88) 28.1,28.56 34.18,22.48 48,22.48 49.25,21.23 58.49,21.23 65.87,28.61 79.3,28.61 82.71,25.21 89.26,25.21 89.97,24.49 v2(97.5,24.49) ; v2(29.89,96.85) 36.62,90.12 36.62,76.43 30.66,70.47 28.69,70.47 26.94,68.71 v2(26.94,67.49)
  LAY4 w0.102: v2(26.94,67.49) 26.81,67.36 26.81,50.71 25.34,49.24 25.34,41.45 26.51,40.28 26.51,32.34 28.1,30.76 v2(28.1,29.88)
  BOTTOM w0.102: Q42.1 27.43,95.8 27.43,97.4 Q98.1 29.34,97.41 v2(29.89,96.85) ; R702.2 99.83,23.22 99.6,22.99 98.28,22.99 97.5,23.77 v2(97.5,24.49)
8625_PD#: length 5.4
  BOTTOM w0.102: R155.1 65.17,114.23 63.23,114.23 C152.2 62.47,115 62.47,115.88 62.25,116.1 U10.10
8625_PWMO: length 122
  TOP w0.102: v2(45.69,113.97) 42.61,110.9 36.63,110.9 33.75,108.02 23.21,108.02 21.3,109.93 v2(19.88,109.93) ; v2(14.08,38.35) 14.02,38.29 R165.2
  LAY4 w0.102: v2(60.44,114.88) 57.3,114.88 56.4,113.97 v2(45.69,113.97) ; v2(19.88,109.93) 18.78,108.82 18.78,106.09 19.62,105.25 19.62,100.67 14.15,95.21 14.15,82.19 14.82,81.53 14.82,62.74 15.37,62.19 15.37,44.45 14.53,43.6 14.53,38.79 v2(14.08,38.35)
  BOTTOM w0.102: U10.12 60.86,115.3 v2(60.44,114.88)
8625_RST#: length 5
  BOTTOM w0.203: U10.9 62.23,116.5 62.94,115.79 C151.2 63.74,115.15 65.6,115.15 R154.1
+V_ADP_IN: length 225.6
  TOP w0.305: 118.92,14.99 118.52,15.39 ; 118.93,14.99 120.34,14.99 124.44,19.09 124.44,20.65 125.23,21.44 125.23,23.85 124.35,24.74 124.35,26.29 126.63,28.56 132.14,28.56 132.44,28.86 R899.2 C585.2 R903.2 ; 118.93,14.99 118.62,14.68 ; 118.92,14.99 118.39,14.99
  LAY3 w0.305: v2(9.39,77.71) 8.22,76.54 8.22,61.07 13.11,56.17 13.11,44.68 6.08,37.65 6.08,21.28 4.66,19.85 4.66,16.29 1.61,13.24 1.61,10.45 2.28,9.78 19.38,9.78 23.88,14.28 61.84,14.28 62.7,15.14 62.7,21.7 66.86,25.85 77.66,25.85 81.48,22.03 83.28,22.03 91.8,13.51 v2(101.32,13.51)
  BOTTOM w0.305: R959.2 12.17,82.54 10.89,81.26 10.89,79.22 v2(9.39,77.71)
+V_DC: length 74.6
  TOP w0.305: U25.16 19.43,38.79 v3(19.33,38.9) ; R642.1 R681.1 19.85,31.78 19.22,32.42 16.21,32.42 v2(15.23,33.39) R643.1 R641.1 ; R527.1 110.52,110.27 105.66,110.27 104.2,111.73 104.2,120.86
  BOTTOM w0.254: U42.16 22.13,86.95
  BOTTOM w0.305: 32.53,34.03 32.94,34.03 ; 32.53,34.03 32.48,34.03 ; 32.53,34.03 33.03,34.52 ; 32.48,34.03 32.1,34.03 31.14,34.99 31.14,37.77 30.21,38.7 27.66,38.7 27.03,38.07 19.9,38.07 19.33,38.64 v3(19.33,38.9) 18.71,38.9 15.23,35.42 v2(15.23,33.39) ; 32.48,34.03 32.96,33.54 ; R465.1 v2(20.58,83.11)
  BOTTOM w0.406: v2(20.4,86.71) C376.2 21.39,86.95 22.13,86.95
  BOTTOM w0.508: R708.1 127.82,41.89 v2(128.16,41.55)
  BOTTOM w2.032: 138.56,90.64 146.65,90.64 149.13,88.16 149.13,82.55
  vias: v1(17.98,80.1) v1(17.98,78.58) v1(18,79.38) v1(18,77.85) v1(36.44,39.38) v1(36.44,38.62) v1(37.2,39.38) v1(37.2,38.62) v1(37.57,67.84) v1(37.57,67.08) v1(37.57,66.32) v1(37.95,39.38) v1(37.95,38.62) v1(38.34,67.84) v1(38.34,67.08) v1(38.34,66.32) v1(53.66,27.94) v1(53.66,27.2) v1(54.41,27.96) v1(54.41,27.21) v1(55.17,27.96) v1(55.17,27.21) v1(105.85,127.3) v1(106.61,127.3) v1(107.37,127.3) v1(124.7,97.82) v1(124.7,97.06) v1(124.7,96.29) v1(124.7,95.53) v1(140.05,61.1) v1(140.05,60.34) v1(140.81,61.1) v1(140.81,60.34) v2(12.46,95.86) v2(12.46,95.35) v2(136.93,60.54) v2(136.93,60.03)
+V_LED:
  vias: v1(10.63,16.85) v1(11.34,16.85)
+VCORE: length 90
  TOP w0.203: 85.73,85.18 U1.AF27 ; 85.73,85.18 86.13,84.79 ; 85.73,85.18 U1.AF29 ; 85.73,85.18 U1.AD27 86.53,85.16 ; U1.AF27 84.97,85.17 v2(84.96,85.17) ; U1.AF27 v2(84.96,85.17) ; v2(90.59,85.62) 90.66,85.55 U1.P27 91.29,85.67 U1.P26 90.59,85.68 v2(90.59,85.62) ; v2(90.59,85.62) U1.U27 ; v2(90.59,85.62) 90.59,85.33 ; U1.Y29 88.47,84.79 v2(88.09,84.41) ; U1.Y29 v2(88.88,85.17) ; U1.Y29 88.88,84.41 ; U1.Y29 89.24,84.03 U1.V30 ; U1.Y29 88.09,85.17 ; U1.Y29 v2(88.09,84.41) ; U1.V27 89.66,85.17 ; U1.V27 v2(88.88,85.17) ; U1.V27 v2(89.66,85.93) U1.U27 ; U1.V27 v2(88.88,85.93) ; 89.66,85.17 U1.V29 ; 89.66,85.17 U1.U27 ; v2(88.88,85.17) U1.Y27 ; v2(88.88,85.17) U1.V29 ; 87.3,85.17 v2(87.3,85.17) ; 87.3,85.17 U1.AC29 ; 87.3,85.17 87.29,85.17 U1.AC27 ; v2(87.3,85.17) 86.92,84.79 U1.AC29 ; v2(87.3,85.17) 86.93,85.55 U1.AC27 ; v2(87.3,85.17) 87.68,84.79 87.69,84.79 ; v2(87.3,85.17) 87.32,85.17 U1.AA27 88.08,85.17 88.09,85.17 ; 86.53,85.16 U1.AC29 ; 86.53,85.16 U1.AC27 ; 86.53,85.16 86.13,84.79 ; 86.13,84.03 U1.AD30 ; 86.13,84.03 86.52,84.41 ; 86.13,84.03 86.12,84.03 v2(85.74,84.41) ; U1.Y27 88.09,85.17 ; U1.Y27 v2(88.88,85.93) ; U1.Y27 88.5,85.55 v2(88.88,85.93) ; 88.09,85.17 U1.AA29 ; 84.94,84.41 U1.AG29 ; 84.94,84.41 U1.AG30 ; 84.94,84.41 v2(84.96,84.41) U1.AF29 ; 88.88,84.41 89.27,84.03 89.65,84.4 ; 88.88,84.41 U1.V29 ; 88.88,84.41 U1.Y30 v2(88.09,84.41) ; 89.65,84.4 U1.U29 ; 89.65,84.4 U1.V29 ; U1.U27 U1.U29 ; 86.52,84.41 U1.AC29 ; 86.52,84.41 86.13,84.79 ; 86.52,84.41 U1.AC30 v2(87.31,84.41) ; 87.69,84.79 v2(87.31,84.41) ; 87.69,84.79 U1.AA29 ; v2(87.31,84.41) U1.AC29 ; v2(87.31,84.41) 87.69,84.03 U1.AA30 ; U1.AD29 86.12,84.79 v2(85.74,84.41) ; 86.13,84.79 v2(85.74,84.41) ; v2(85.74,84.41) 85.69,84.46 U1.AF29 ; v2(85.74,84.41) 85.36,84.79 U1.AF29 ; U1.AF29 v2(84.96,85.17) ; v2(116.98,116.31) 116.91,116.31 116.69,116.1 U56.5 ; v2(88.09,84.41) U1.AA29 ; R508.2 v2(119.3,118.5) ; 90.59,85.33 U1.U29 ; 90.59,85.33 U1.U29 ; v2(84.96,85.17) U1.AG27
  TOP w0.305: L14.2 v2(130.89,100.7)
  LAY4 w0.305: v2(119.3,118.5) 121.09,118.5 128.34,111.25 128.34,101.11 128.34,101.11 v2(128.34,100.11)
  BOTTOM w0.305: v2(130.89,100.7) 131.4,101.21 131.4,102.44 R519.1 129.99,103.85 127.91,103.85 121.28,110.48 121.28,113.05 120.87,113.46 C464.2 C463.2 C462.1 R515.1 118.8,115.42 117.91,116.31 v2(116.98,116.31)
  vias: v1(110.11,91.64) v1(110.11,90.88) v1(110.87,91.64) v1(110.87,90.88) v1(130.46,88.64) v1(130.46,87.87) v1(130.46,87.11) v1(130.46,86.35) v1(131.22,88.64) v1(131.22,87.87) v1(131.22,87.11) v1(131.22,86.35) v1(131.98,88.64) v1(131.98,87.87) v1(131.98,87.11) v1(131.98,86.35) v1(132.74,88.64) v1(132.74,87.87) v1(132.74,87.11) v1(132.74,86.35)
+VCORE_VREF: length 50.3
  TOP w0.203: 120.25,116.73 120.51,116.99 ; 120.25,116.73 120.27,116.73 ; 120.25,116.73 R507.1 118.74,117.5 C449.2 ; 120.51,116.99 120.51,121.66 119.82,122.35 R542.1 ; 120.51,116.99 120.51,116.75 ; 120.51,116.5 120.51,114.11 R545.1 ; 120.51,116.5 120.51,116.75 ; 120.51,116.5 120.27,116.73 ; C474.1 108.63,116.86 R533.2 107.75,116.64 106.38,116.64 ; 106,116.64 105.55,116.64 105.02,116.11 105.02,114.2 105.35,113.87 R546.1 R547.1 R548.1 ; 106,116.64 106.38,116.64 ; 106,116.64 106.2,116.84 ; 120.51,116.75 120.49,116.73 120.27,116.73 ; 106.38,116.64 106.2,116.82 106.2,116.84 ; U56.14 115.21,119.91 115.52,120.23 116.14,120.23 ; 106.2,116.84 106.2,121.19 106.97,121.96 R544.1
  TOP w0.305: 116.14,120.23 117.34,120.23 117.63,120.52 117.63,120.99 C466.2 118.99,122.35 R542.1 119.24,123.85 117.63,125.46 112.16,125.46 R543.1 110.25,123.55 108.11,123.55 107.61,123.05 R544.1
+VGFX: length 75.1
  TOP w0.203: U56.28 v2(109.7,117.7)
  TOP w0.229: 84.96,87.44 U1.AF22 ; 84.96,87.44 84.98,87.44 U1.AF24 ; 84.96,87.44 v2(84.96,87.44) 84.95,87.44 ; v2(83.39,86.68) 83,87.07 ; v2(83.39,86.68) 83.01,86.31 U1.AK25 ; v2(83.39,86.68) 83,86.3 v2(83.39,85.92) 83.01,85.55 U1.AK27 83.38,85.17 v2(83.39,85.17) 83.01,84.79 ; v2(83.39,86.68) 83.4,86.68 U1.AJ24 ; 83,87.07 U1.AK24 82.98,87.07 v2(82.6,87.44) ; 83,87.07 83.01,87.07 v2(83.39,87.44) ; v2(82.6,87.44) 82.61,87.44 U1.AK22 83,87.82 v2(83.39,87.44) ; v2(82.6,87.44) 82.6,87.44 U1.AM22 ; v2(83.39,87.44) 83.76,87.07 U1.AJ24 ; v2(83.39,87.44) 83.77,87.82 U1.AJ22 83.81,87.82 U1.AG24 84.94,87.44 84.95,87.44 ; U1.AJ24 84.54,87.82 U1.AG22 84.95,87.44 ; U1.AA24 87.68,87.07 U1.AC22 ; U1.AC22 86.91,87.82 v2(86.53,88.2) 86.15,87.82 U1.AD22 86.51,87.45 v2(86.51,87.44) ; U1.AC22 86.53,87.44 ; 86.53,87.44 86.54,87.44 U1.AC24 86.92,87.07 v2(87.3,87.44) ; 86.53,87.44 v2(86.51,87.44) ; 83.01,84.79 83.01,84.79 v2(83.39,84.41) 83.01,84.03 U1.AK30 83.38,83.65 ; 83.01,84.79 U1.AK29 ; U1.AD24 86.14,87.07 v2(86.51,87.44) ; 83.38,83.65 83.38,83.65 83.16,83.44 U1.AK32 ; 83.38,83.65 v2(83.39,83.65)
  TOP w0.305: R530.2 v2(107.16,118.87) ; L15.2 v2(95.06,128.87)
  LAY4 w0.305: v2(107.16,118.87) 105.97,120.06 v1(82.05,120.06)
  BOTTOM w0.305: v2(109.7,117.7) 109.91,117.7 110.25,117.36 110.25,116.81 109.6,116.16 109.04,116.16 R536.1 C477.1 C478.2 C476.2 106.45,116.45 105.02,116.45 104.3,117.17 104.3,118.33 98.87,123.76 97,123.76 94.94,125.82 94.94,126.4 94.14,127.2 94.14,128.05 R539.1 94.02,128.62 94.27,128.87 v2(95.06,128.87)
  vias: v1(77.86,122.6) v1(77.86,121.84) v1(77.86,121.08) v1(78.63,122.6) v1(78.63,121.84) v1(78.63,121.08) v1(79.39,122.6) v1(79.39,121.84) v1(79.39,121.08) v1(80.15,122.6) v1(80.15,121.84) v1(80.15,121.08) v1(80.91,122.6) v1(80.91,121.84) v1(80.91,121.08)
+VSDIO: length 0.5
  TOP w0.203: U1.AN27 v2(81.82,85.93)
+VSFR: length 55
  TOP w0.203: U1.AG19 v2(84.96,88.96) U1.AF19 ; U1.V36 v2(89.66,81.38) U1.U36 ; U1.AG32 v2(84.96,82.9) ; U1.AA25 v2(87.31,85.93) ; U1.AD36 v2(86.53,81.38)
  TOP w0.406: v2(92.57,105.84) 90.23,105.84 89.65,106.43 v2(88.69,106.43) 87.75,105.49 87.1,105.49 86.78,105.81 86.78,106.82 86.28,107.31 85.01,107.31 R676.2 84.3,106.6 R452.2
  LAY3 w0.203: v2(105.31,79.14) 105.31,79.14 v2(107.11,77.34)
  BOTTOM w0.203: v2(107.11,77.34) 105.06,75.28 105.06,74.03 105.26,73.82 R644.2 ; v2(105.31,79.14) 97.53,79.14 96.47,80.2 90.4,80.2 90.04,80.57 90.04,80.91 90.26,81.14 C91.1
  BOTTOM w0.305: v2(84.96,82.9) 85.01,82.95 C50.2 ; C90.1 86.39,81.52 v2(86.53,81.38)
  BOTTOM w0.406: C94.1 C93.1 92.57,106.04 v2(92.57,105.84) ; C89.1 89.54,81.26 v2(89.66,81.38) 89.71,81.33 C91.1 ; v2(88.69,106.43) 88.33,106.78 C92.1 89.92,108.41 89.92,109.56
  BOTTOM w0.508: 89.92,109.56 89.92,110.53 87.05,113.4 C395.2
+VSM: length 234.6
  TOP w0.107: U1.F49 95.04,74.64 94.95,74.55 94.95,73.56 U1.F52
  TOP w0.203: U1.M41 v2(91.57,78.29) U1.M42 ; U1.BB46 v2(76.94,75.99) ; U1.AM38 v2(82.6,80.62) U1.AK38 ; U1.BJ48 v2(73.36,75.26) 72.11,74.01 R7.1 ; U1.AF38 v2(85.74,79.86) U1.AD38 ; U1.D44 v2(96.26,76.75) ; U1.AV41 v2(79.91,78.29) U1.AV42 ; U1.BD49 76.66,74.12 76.51,73.58 U1.BD52 U1.BD53 v2(76.38,72.19) ; U1.BF44 v2(75.22,76.75) ; U1.H46 v2(94.54,75.99) ; U1.BG51 v2(75.06,74.45) ; v2(98.13,75.26) U1.A48 ; U1.C51 v2(96.42,74.45) ; U1.F53 v2(95.1,72.19) U1.F53
  TOP w0.229: U1.F52 95.03,73.18 U1.F53
  TOP w0.254: CN3.88 v2(95.98,50.58) ; CN3.100 v2(92.38,50.58) ; U1.Y38 v2(88.88,80.62) U1.V38 ; v2(87.28,58.76) CN3.117 v2(87.28,55.96) ; v2(96.54,58.76) 96.28,58.5 CN3.87 v2(96.28,55.96) ; v2(90.87,55.97) 90.88,55.97 CN3.105 v2(90.88,58.76) ; CN3.94 v2(94.18,50.58) ; v2(94.48,58.76) CN3.93 v2(94.48,55.96) ; CN3.76 v2(99.58,50.58) ; CN3.118 v2(86.98,50.58) ; CN3.123 v2(85.48,55.96) ; v2(98.08,55.96) CN3.81 v2(98.08,58.76) ; CN3.124 v2(85.18,50.58) ; v2(92.68,58.76) CN3.99 v2(92.68,55.96) ; CN3.106 v2(90.58,50.58) ; v2(89.08,55.96) CN3.111 v2(89.08,58.76) ; CN3.82 v2(97.78,50.58) ; v2(88.78,50.58) CN3.112 ; CN3.75 v2(99.88,58.76)
  TOP w0.381: C125.2 95.52,59.06 95.21,58.76 v2(94.48,58.76) ; 98.95,59.7 98.95,59.09 99.28,58.76 v2(99.88,58.76)
  TOP w0.406: 46.31,69.34 45.89,69.76 ; 46.31,69.34 46.31,69.41 ; 46.31,69.34 46.31,66.4 48.98,63.73 48.98,62.71 49.61,62.08 C385.2 51.65,62.08 v2(52.2,61.52) ; 46.31,69.41 46.73,69.84 ; 46.31,69.41 46.31,70.08
  TOP w0.508: v2(44.94,108.28) 48.36,108.28 49.7,106.94 56.31,106.94 57.65,108.28 62.48,108.28 69.12,114.92 70.08,114.92 v2(70.09,114.93)
  LAY3 w0.406: v2(70.09,114.93) 70.09,116.19 71.16,117.26 v2(83.74,117.26)
  LAY4 w0.305: v2(49.66,64.13) 50.47,64.13 52.35,66 57.06,66 60.92,69.86 v1(60.92,74.09)
  BOTTOM w0.203: v2(49.66,64.13) 49.86,63.93 U43.9 ; R125.2 88.32,48.98 88.78,49.43 v2(88.78,50.58) ; U43.2 52.04,61.68 v2(52.2,61.52)
  BOTTOM w0.254: U45.1 C399.2 75.99,112.93 U45.2
  BOTTOM w0.305: 65.91,66.04 63.42,63.55 R576.2 61.62,63.55 61.25,63.93 R449.1 ; R120.2 124.47,49.74 124.4,49.67 ; C24.2 v2(76.38,72.19) ; C29.2 v2(73.36,75.26) ; C27.2 v2(79.91,78.29) ; C23.2 v2(95.1,72.19) ; C28.2 v2(96.26,76.75)
  BOTTOM w0.406: 85.97,121.54 85.97,119.48 v2(83.74,117.26) ; 81.39,70.12 R6.2
  BOTTOM w0.508: C399.2 74.67,112.43 C556.1 73.39,112.26 70.73,114.93 v2(70.09,114.93) ; v1(60.92,74.09) 47.93,87.08 47.93,98.71 43.55,103.09 43.55,106.89 v2(44.94,108.28)
  BOTTOM w1.118: 127.5,51.61 125.55,49.67 118.57,49.67 117.6,48.7 103.24,48.7 101.26,50.68
  vias: v1(66.16,72.3) v1(66.16,71.54) v1(66.16,70.77) v1(66.16,70.01) v1(66.92,72.3) v1(66.92,71.54) v1(66.92,70.77) v1(66.92,70.01) v1(94.8,66.12) v1(95.27,66.72) v2(80.78,78.34) v2(101.26,53.45) v2(101.26,52.74) v2(101.26,52.03) v2(101.26,51.32) v2(101.26,50.6)
+VSM_VTT: length 96
  TOP w0.305: v2(19.52,107.97) 19.81,107.68 22.14,107.68 22.36,107.46 45.01,107.46 47.6,104.87 47.6,97.44 v2(54.57,90.47) ; CN3.204 61.18,50.24 60.98,50.44
  TOP w0.406: 61.48,56.26 CN3.203
  TOP w0.508: v2(61.22,56.01) 61.48,56.26 ; v2(60.41,51) 60.98,50.44
  LAY3 w0.305: v2(54.57,90.47) 54.57,60.64 v2(53.38,59.45)
  BOTTOM w0.305: R723.2 8.1,110.59 9.65,109.03 18.76,109.03 19.52,108.27 v2(19.52,107.97)
A_EARPHONE_SEL: length 23.8
  TOP w0.102: v2(126.07,24.89) 127.96,23 R268.1 132.83,22.52 v2(132.16,21.85)
  LAY3 w0.102: v2(132.16,21.85) 132.63,21.85 135.74,18.74 141.58,18.74 143.11,17.22 J4.3
  BOTTOM w0.102: R251.1 126.07,24.89 v2(126.07,24.89)
AC_DETECT: length 11.4
  TOP w0.508: R348.1 99.48,13.38 97.16,13.38 95.8,14.74 J13.3
AC_PRESENT: length 84.6
  LAY3 w0.127: v2(126.48,84.57) 126.48,75.95 129.44,73 129.44,70.83 132.21,68.06 132.21,67.39 134.93,64.66 134.93,52.17 131.99,49.23 131.99,41.5 v2(131.05,40.55)
  LAY4 w0.127: v2(105.91,32.34) 105.91,32.06 109.25,28.71 119.21,28.71 v2(131.05,40.55)
  BOTTOM w0.114: v2(105.91,32.34) R328.2 ; Q3.1 v2(126.48,84.57)
AC_VREF: length 3.7
  BOTTOM w0.203: C230.1 C232.2 134.33,19.36 133.74,19.94 133.34,19.94 132.91,19.51 U23.28
ADP_IN#: length 62.7
  TOP w0.102: v2(135.82,38.34) 135.82,38.34 D15.P
  LAY4 w0.102: v2(86.92,28.55) 92.74,28.55 97.86,23.42 108.68,23.42 109.03,23.07 119.19,23.07 123.76,27.65 123.76,30 131.39,37.62 135.1,37.62 v2(135.82,38.34)
  BOTTOM w0.102: U28.71 87.74,30.21 R338.2 86.65,28.82 v2(86.92,28.55)
ALL_S_PWRGD: length 2.1
  BOTTOM w0.102: R679.1 U34.2 R386.2
ALL_SX_S_PWRGD: length 6.8
  BOTTOM w0.102: 10.89,106.35 U36.2 ; 10.89,106.35 12.67,106.35 12.81,106.49 U38.1 ; 10.89,106.35 8.5,106.35 8.13,106.73 R679.2
ALL_SYS_PWRGD: length 146
  TOP w0.102: v2(46.13,88.28) 45.22,89.2 45.22,101.49 43.48,103.23 43.48,105.4 41.94,106.94 21.99,106.94 21.85,107.09 20.05,107.09 v2(19.68,106.72)
  LAY4 w0.102: v2(46.13,88.28) 44.73,86.88 44.73,65.37 45.89,64.22 45.89,58.64 45.48,58.23 45.48,51.78 46.88,50.38 46.88,47.38 53.09,41.16 64.73,41.16 65.44,40.44 83.84,40.44 87.83,36.46 v2(90.99,36.46)
  BOTTOM w0.102: v2(90.99,36.46) 90.83,36.61 U28.87 ; v2(19.68,106.72) 19.46,106.5 U37.2 R8.1 15.48,106.5 15.08,106.1 11.83,106.1 11.54,105.81 U36.4
ALW_DISCHARGE: length 264.1
  TOP w0.203: v2(28.79,101.92) 28.79,101.05 Q55.1 ; Q56.1 12.31,60.41 12.63,60.08 v2(25.54,60.08)
  TOP w0.508: Q57.1 v2(127.58,80.53)
  LAY3 w0.203: v2(132.85,80.6) 137.33,85.08 137.33,114.1 134.75,116.68 128.66,116.68 124.46,120.87 117.09,120.87 115.47,119.25 109.31,119.25 108.27,120.29 94.77,120.29 v2(93.31,118.83)
  LAY4 w0.203: v2(28.79,101.92) 31.43,104.56 31.43,106.41 36.17,111.15 39.35,111.15 46.82,118.62 49.2,118.62 49.42,118.39 50.46,118.39 51.14,119.06 59.77,119.06 61.24,120.53 64.24,120.53 64.8,121.1 69.79,121.1 71.9,118.98 93.15,118.98 v2(93.31,118.83) ; v2(127.58,80.53) 127.93,80.17 132.42,80.17 v2(132.85,80.6) ; v2(25.54,60.08) 25.62,60.16 25.62,67.84 16.34,77.12 v2(16.34,88.79)
  BOTTOM w0.203: v2(127.58,80.53) 128.14,79.97 Q49.1 ; Q52.1 v2(93.31,118.83) 92.93,119.21 Q59.1 ; R662.1 17.71,88.79 R663.2 ; v2(25.54,60.08) 26.83,58.79 Q58.1 27.79,59.57 27.09,60.26 27.09,64.7 28.27,65.87 Q50.1 ; R663.2 Q85.3 ; R663.2 v2(16.34,88.79) 15.82,89.31 15.82,92.64 25.1,101.92 v2(28.79,101.92)
AUD_MIC1_IN_L: length 23.6
  TOP w0.305: R246.1 135.22,22.28 135.22,23.37 136.16,24.31 136.16,33.37 136.94,34.15 R669.2 v3(137.7,33.44)
  BOTTOM w0.305: v3(137.7,33.44) 137.09,33.44 133.93,30.28 133.08,30.28 131.62,28.83 131.62,28.21 R245.2
AUD_MIC1_IN_R: length 20.2
  TOP w0.305: R244.1 135.65,22.3 135.65,23.18 136.57,24.1 136.57,31.36 137.16,31.95 R668.2 v3(137.7,32.69)
  BOTTOM w0.305: R242.2 132.06,28.13 132.06,28.66 133.24,29.84 134.08,29.84 136.93,32.69 v3(137.7,32.69)
AUD_MIC2_IN_L: length 11.2
  BOTTOM w0.305: CN21.2 130.13,33.25 R249.2 128.66,31.78 C249.1 128.66,25.01 129.86,25.01 C250.1
AUDIO_DVDD_IO: length 4.2
  BOTTOM w0.254: C256.2 125.4,19.51 U23.9
  BOTTOM w0.305: R260.1 R258.1 C256.2
AUDIO_POWER_ON: length 118.6
  LAY3 w0.102: v2(109.69,19.97) 109.63,19.91 109.63,17.35 117.78,9.21 v2(121.97,9.21) 124.62,11.85 v2(138.55,11.85)
  LAY4 w0.102: v2(116.09,27.8) 115.73,28.16 106.96,28.16 102.78,32.34 99.05,32.34 97.6,33.78 87.51,33.78 v2(84.98,36.3) ; v2(138.55,11.85) 139.35,12.65 139.35,22.85 v2(133.97,28.23)
  BOTTOM w0.102: 113.67,20.17 113.52,20.02 ; 113.67,20.17 113.67,20.02 113.66,20.02 ; 113.67,20.17 113.67,25.38 v2(116.09,27.8) ; 113.67,20.17 113.68,20.17 113.83,20.02 ; 113.52,20.02 113.66,20.02 ; 113.52,20.02 109.74,20.02 v2(109.69,19.97) 109.51,20.15 108.8,20.15 108.35,19.69 108.35,18.93 108.72,18.56 U20.3 ; v2(121.97,9.21) 121.92,9.21 R237.1 121.46,9.21 R239.1 121.47,9.99 U19.3 ; R248.2 85.25,36.04 v2(84.98,36.3) ; 113.66,20.02 113.83,20.02 ; U22.3 113.56,13.43 114.43,14.31 114.43,17.97 114.74,18.27 114.74,19.81 114.53,20.02 113.83,20.02 ; U21.3 v2(133.97,28.23)
AUXN_LVDS: length 21
  TOP w0.101: C524.1 v2(49.64,120.96)
  LAY3 w0.101: v2(49.64,120.96) 48.18,120.96 48.05,121.1 48.05,121.63 48.15,121.73 61.33,121.73 62.95,120.11 62.95,119.56 62.79,119.4 62.66,119.4 62.32,119.74 v2(62.32,119.78)
  BOTTOM w0.101: v2(62.32,119.78) 62.06,119.51 61.8,119.51 61.61,119.7 U10.1
AUXP_LVDS: length 21.1
  TOP w0.101: C526.1 46.89,120.97 v2(46.9,120.97)
  LAY3 w0.101: v2(62.32,119.2) 62.88,119.2 63.15,119.47 63.15,120.2 61.41,121.94 48.07,121.94 47.84,121.71 47.84,121.11 47.7,120.97 v2(46.9,120.97)
  BOTTOM w0.101: U10.2 62.22,119.3 v2(62.32,119.2)
BIOS_BOOT_SELECT: length 9.8
  TOP w0.102: U1.BA30 77.15,83.55 76.95,83.55 76.63,83.23 76.63,82.93 76.17,82.47 74.92,82.47 74.75,82.3 74.58,82.3 74.41,82.47 74.21,82.47 74.04,82.3 72.46,82.3 70.75,80.6 R53.2 R51.1
BL_ADJ: length 235.1
  TOP w0.114: v2(13.51,37.91) 13.18,37.58 R176.1
  LAY3 w0.152: v2(13.51,37.91) 13.51,39.74 14.82,41.05 19.1,41.05 21.41,38.74 22.95,38.74 28.92,32.77 32.23,32.77 39.89,25.12 58.87,25.12 65.12,31.36 81.84,31.36 82.72,30.48 102.27,30.48 v2(102.71,30.92)
  LAY3 w0.203: v2(50.42,119.51) 41.85,119.51 37.79,123.56 35.41,123.56 32.43,126.54 29.85,126.54 29.18,127.22 26.55,127.22 23.63,124.3 15.49,124.3 13.4,122.21 13.4,120.2 v2(12.3,119.11)
  LAY4 w0.203: v2(12.3,119.11) 10.39,117.19 10.39,112.68 10.38,112.68 10.38,93.19 9.91,92.72 9.91,84.97 13.39,81.5 13.39,38.03 v2(13.51,37.91)
  BOTTOM w0.114: v2(102.71,30.92) 103.02,30.61 U28.25
  BOTTOM w0.152: R153.1 51.56,119.82 51.24,119.51 v2(50.42,119.51)
BLCTL_EC: length 84.3
  TOP w0.102: v2(23.34,29.06) 21.93,30.47 R748.2 22.42,31.84 22.72,32.14 U63.2
  LAY4 w0.102: v2(23.34,29.06) 25.61,26.79 34.53,26.79 35.53,27.79 41.55,27.79 43.38,25.96 50.24,25.96 53.28,29 63.65,29 65.14,30.48 81.29,30.48 83.4,28.38 83.6,28.38 85.17,26.81 85.17,26.28 87.46,23.99 v2(94.56,23.99)
  BOTTOM w0.102: R325.2 R330.1 v2(94.56,23.99)
BT_ON: length 89.8
  LAY3 w0.102: v2(48.38,31.89) 47.64,31.89 45.37,34.16 45.37,36.74 44.96,37.15 44.96,45.81 48.53,49.38 48.53,54.08 v2(47.91,54.7)
  LAY4 w0.102: v2(101.37,29.13) 97.35,33.16 84.22,33.16 82.28,35.1 67.68,35.1 66.45,33.87 63.17,33.87 63.16,33.86 62.13,33.86 61.28,33.01 55.14,33.01 54.75,32.61 51.22,32.61 50.49,31.89 v2(48.38,31.89)
  BOTTOM w0.102: R282.1 47.93,54.72 v2(47.91,54.7) ; R278.1 48.65,32.53 48.38,32.26 v2(48.38,31.89) ; v2(101.37,29.13) 101.89,28.61 U28.30
BUF_PLT_RST#: length 305
  TOP w0.203: U6.10 120.39,77.19 v2(121.04,77.83) 121.29,78.09 R84.1
  LAY3 w0.203: v2(17.34,102.66) 18.32,103.64 33.15,103.64 33.79,103 37.81,103 v2(39.06,101.75) ; v2(134.96,44.49) 134.96,47.8 138.94,51.78 138.94,68.87 137.73,70.08 137.73,71.16 138.05,71.49 138.05,72.52 137.25,73.32 137.25,78.86 138.1,79.71 v2(138.1,82.61)
  LAY4 w0.203: 97.88,35.07 97.89,35.06 97.89,34.9 ; 97.88,35.07 97.72,35.07 ; 97.88,35.07 98.07,35.07 ; 97.89,34.9 97.89,34.89 ; 97.89,34.9 97.72,35.07 ; 97.72,35.07 87.9,35.07 86.24,36.73 80.84,36.73 79.61,37.96 67.28,37.96 66.83,38.41 61.27,38.41 60.71,37.85 56.53,37.85 54.08,35.4 v2(49.86,35.4) 49.61,35.15 45.11,35.15 40.71,39.55 40.71,43.77 39.22,45.27 v2(39.22,47.05) 39.22,54.85 40.3,55.94 40.3,61 41.23,61.93 41.23,65.83 40.8,66.27 40.8,72.58 39.06,74.31 v2(39.06,101.75) ; 98.07,35.07 99.07,35.07 100.36,33.78 113.5,33.78 114.27,34.55 115.59,34.55 116.44,33.7 119.32,33.7 v2(119.86,34.23) ; 98.07,35.07 97.89,34.89 ; v2(10.97,108.16) 15.76,103.38 16.62,103.38 v2(17.34,102.66) ; 97.89,34.89 97.89,34.09 99.11,32.88 102.9,32.88 v2(106.28,29.49) 106.28,29.47 107.34,28.42 119.57,28.42 134.96,43.81 v2(134.96,44.49) ; v2(121.04,77.83) 121.58,77.83 122.1,77.32 126.41,77.32 128.05,78.96 132.21,78.96 135.99,82.74 137.97,82.74 v2(138.1,82.61)
  BOTTOM w0.203: CN14.4 118.73,36.7 119.86,35.57 v2(119.86,34.23) ; v2(10.97,108.16) 10.72,108.16 10.24,107.69 U36.1 ; U39.2 v2(17.34,102.66) ; v2(106.28,29.49) 106.28,29.8 R312.2 ; v2(39.22,47.05) U58.2 39.22,43.82 R589.2 ; v2(49.86,35.4) 50.15,35.69 R218.2
CAM_ON: length 165.5
  LAY4 w0.102: v2(35.31,108.09) 32.62,105.4 32.62,83.7 35.06,81.26 35.06,46.84 39.39,42.51 39.39,36.05 41.31,34.13 47.82,34.13 48.93,33.02 54.58,33.02 54.97,33.41 60.74,33.41 61.62,34.29 64.86,34.29 66.08,35.51 82.69,35.51 v2(84.24,33.96)
  BOTTOM w0.102: U28.78 85.19,33.01 v2(84.24,33.96) ; v2(35.31,108.09) 20.9,108.09 19.58,109.41 12.9,109.41 8.92,113.38 R597.1 U84.3
CF_IMAX: length 4.5
  TOP w0.102: R542.2 119.24,121.22 R549.1 117.81,119.79 116.81,119.79 116.62,119.6 U56.13
CLK_LAN_OE#: length 109.4
  TOP w0.102: U1.BG3 v2(75.64,97.23)
  LAY4 w0.089: v2(75.64,97.23) 71.1,97.23
  LAY4 w0.102: v2(44.99,36.31) 44.46,36.31 42.46,38.32 42.46,43.24 39.59,46.11 39.59,54.56 40.78,55.75 40.78,60.99 41.52,61.73 41.52,65.97 41.13,66.37 41.13,72.52 41.68,73.07 41.68,88.5 51.13,97.95 60.07,97.95 63.03,100.92 66.14,100.92 69.83,97.23 71.1,97.23
  BOTTOM w0.102: R41.1 75.48,97.39 v2(75.64,97.23) ; v2(44.99,36.31) 45.59,35.72 46.78,35.72 47.41,35.08 48.51,35.08 50.37,33.21 50.37,31.65 50.95,31.07 53.39,31.07 Q64.2
CLK_PCIE_LAN_N: length 115.8
  TOP w0.101: v2(84.79,96.37) U1.AF6
  LAY3 w0.101: v2(84.79,96.37) 85.61,96.37 85.93,96.69 85.93,97.78 85.27,98.45 84.32,98.45 81.55,101.22 73.05,101.22 72.59,101.68 63.37,101.68 53.09,91.41 53.09,84.57 53.47,84.19 53.47,62.24 52.56,61.33 52.56,58.83 51.06,57.32 51.06,47.46 49.33,45.73 48.19,45.73 46.41,43.95 46.41,37.76 47.46,36.71 47.46,35.19 48.02,34.63 50.75,34.63 51.27,35.16 55.35,35.16 56.54,36.35 57.12,36.35 57.36,36.11 v2(57.36,35.54)
  BOTTOM w0.101: U17.20 57.46,35.63 v2(57.36,35.54)
CLK_PCIE_LAN_P: length 115.8
  TOP w0.101: v2(84.79,97.08) 84.79,96.97 85.18,96.54 U1.AF4
  LAY3 w0.101: v2(57.97,35.54) 57.9,35.54 57.57,35.87 57.57,36.19 57.21,36.55 56.46,36.55 55.26,35.36 51.18,35.36 50.66,34.84 48.1,34.84 47.66,35.28 47.66,36.8 46.61,37.85 46.61,43.87 48.27,45.53 49.42,45.53 51.26,47.37 51.26,57.24 52.76,58.75 52.76,61.25 53.67,62.15 53.67,84.28 53.3,84.65 53.3,91.32 63.45,101.48 72.51,101.48 72.7,101.28 72.72,101.28 72.97,101.03 81.48,101.03 84.24,98.26 85.19,98.26 85.74,97.7 85.74,96.77 85.54,96.56 85.22,96.56 85.12,96.66 85.12,96.98 85.02,97.08 v2(84.79,97.08)
  BOTTOM w0.101: U17.19 57.86,37.26 57.67,37.08 57.67,35.79 57.93,35.54 v2(57.97,35.54)
CLK_PCIE_WLAN_N: length 103.3
  TOP w0.101: CN12.11 50.48,35.53 50.19,35.81 48.83,35.81 v2(48.65,35.63) ; U1.AF9 84.91,94.95 v2(84.79,94.95)
  LAY3 w0.089: v2(84.79,94.95) 84.52,95.21 84.05,95.21 82.89,96.38 82.89,98.48 80.82,100.55 72.47,100.55 72.37,100.65 71.1,100.65
  LAY3 w0.101: 71.1,100.65 64.07,100.65 55.53,92.11 55.53,60.31 52.07,56.84 52.07,46.51 50.11,44.54 48.64,44.54 48.37,44.27 48.37,39.71 51.06,37.02 51.06,36.18 50.69,35.82 48.84,35.82 v2(48.65,35.63)
CLK_PCIE_WLAN_P: length 103.3
  TOP w0.101: U1.AF7 v2(84.79,95.66) ; CN12.13 50.48,36.33 50.18,36.03 48.85,36.03 v2(48.65,36.23)
  LAY3 w0.089: v2(84.79,95.66) 84.52,95.39 84.12,95.39 83.06,96.45 83.06,98.56 80.9,100.73 72.54,100.73 72.41,100.85 71.1,100.85
  LAY3 w0.101: 71.1,100.85 63.99,100.85 55.33,92.19 55.33,60.39 51.87,56.93 51.87,46.59 50.02,44.74 48.56,44.74 48.17,44.35 48.17,39.62 50.85,36.94 50.85,36.27 50.61,36.02 48.86,36.02 v2(48.65,36.23)
CLK_WLAN_OE#: length 102.5
  TOP w0.102: U1.BD7 76.14,95.69 v2(76.2,95.61)
  LAY4 w0.089: v2(76.2,95.61) 75.63,95.61 75.2,96.04 74.79,96.04 73.82,97.01 71.1,97.01
  LAY4 w0.102: 71.1,97.01 69.49,97.01 65.98,100.52 63.2,100.52 60.23,97.56 51.3,97.56 42.13,88.4 42.13,72.8 41.5,72.17 41.5,66.34 41.74,66.09 41.74,61.57 41.11,60.93 41.11,54.83 39.8,53.52 39.8,46.28 42.7,43.38 42.7,38.52 44.42,36.79 v2(44.56,36.79)
  BOTTOM w0.102: v2(44.56,36.79) 44.56,35.94 45.31,35.19 Q66.2 46.06,35.19 R635.1 ; R39.1 77.02,97.76 76.85,97.58 76.85,96.8 76.2,96.14 v2(76.2,95.61)
CORE_PWROK: length 139.2
  TOP w0.102: U1.B7 97.42,94.96 98.42,94.96 99.51,96.04 v2(99.51,96.8)
  LAY4 w0.102: v2(116.94,102.33) 116.94,103.54 110.74,109.74 102.85,109.74 97.1,115.49 87.56,115.49 84.82,118.23 62.87,118.23 62.12,117.48 54.48,117.48 54.13,117.14 49.36,117.14 48.59,117.91 47.15,117.91 39.06,109.82 v2(36.32,109.82)
  BOTTOM w0.102: v2(36.32,109.82) 36.32,108.33 35.46,107.47 26.99,107.47 18.95,99.43 R387.2 ; v2(99.51,96.8) 100.27,96.8 103.98,100.51 106.43,100.51 107.05,101.13 115.74,101.13 v2(116.94,102.33)
CS_WAKE: length 135
  TOP w0.114: U1.L1 92.54,98.74 R85.2 93.92,101.28 93.92,101.86 94.78,102.71 98.76,102.71 100.79,100.68 v2(100.79,100.68)
  LAY3 w0.127: v2(133.23,43.71) 133.09,43.85 133.09,48.79 136.16,51.85 136.16,65.07 135,66.22 135,69.11 128.23,75.89 128.23,90.02 123.14,95.1 123.14,97.16 121.93,98.38 119.36,98.38 119.08,98.1 112.4,98.1 110.34,100.16 110.34,100.84 109.83,101.35 106.16,101.35 105.49,100.68 v2(100.79,100.68)
  LAY4 w0.127: v2(113.52,29.89) 112.85,29.22 109.98,29.22 v2(109.33,29.87) 110.39,30.92 119.78,30.92 128.36,39.51 129.03,39.51 v2(133.23,43.71)
  BOTTOM w0.114: R326.1 109.45,29.75 v2(109.33,29.87) 109.48,30.02 U27.4 ; R652.1 114.08,30.45 v2(113.52,29.89)
CS_WAKE_EC: length 25.3
  LAY4 w0.102: v2(98.68,34.54) 99.98,33.25 108.82,33.25 v2(109.24,32.82) 109.84,32.23 113.12,32.23 v2(113.72,32.82)
  BOTTOM w0.102: R652.2 114.08,32.46 v2(113.72,32.82) ; v2(98.68,34.54) U28.119 ; v2(109.24,32.82) 109.48,32.59 U27.8
DBG_UART3_RXD: length 15.4
  TOP w0.102: U1.BC16 v2(76.63,91.38)
  LAY3 w0.127: v2(69.11,90.38) 74.64,90.38 75.04,90.78 76.03,90.78 v2(76.63,91.38)
  BOTTOM w0.114: Q103.2 65.24,92.27 66.04,91.47 66.04,90.67 66.81,89.9 67.68,89.9 68.08,89.5 68.68,89.5 69.11,89.93 v2(69.11,90.38)
DBG_UART3_TXD: length 10.7
  TOP w0.102: U1.BD14 v2(75.92,92.37)
  TOP w0.114: Q102.2 67.62,91.84 v2(68.16,91.3)
  LAY3 w0.127: v2(68.16,91.3) 68.54,90.91 73.88,90.91 75.34,92.37 v2(75.92,92.37)
DDI0_HPD: length 29.2
  TOP w0.089: 98.41,85.08 98.03,85.08 97.86,85.26 97.39,85.26 97.29,85.36 97.05,85.36 96.94,85.25 96.71,85.25 96.31,85.55 U1.D27
  TOP w0.102: 98.41,85.08 102.63,85.08 v2(103.09,85.55)
  BOTTOM w0.102: v2(103.09,85.55) 103.09,84.54 105.56,82.07 108.06,82.07 108.26,82.27 109.65,82.27 110.63,83.25 114.6,83.25 115.18,83.83 117.61,83.83 118.23,84.45 Q1.3 R12.1
DDI1_DATA: length 20.9
  TOP w0.102: U1.P30 v2(91.29,83.61)
  TOP w0.114: R13.2 R16.2 v2(108.52,81.63)
  BOTTOM w0.089: 96.39,84.36 96.22,84.2 91.88,84.2 v2(91.29,83.61)
  BOTTOM w0.102: 102.1,84.68 96.71,84.68 96.39,84.36
  BOTTOM w0.114: v2(108.52,81.63) 105.22,81.63 102.17,84.68 102.1,84.68
DDI1_HPD: length 35.1
  TOP w0.102: v2(92.72,84.6) U1.K30
  BOTTOM w0.102: v2(92.72,84.6) 93.15,85.03 102.21,85.03 105.37,81.86 108.14,81.86 108.34,82.06 109.33,82.06 110.06,81.33 114.03,81.33 115.79,83.09 117.87,83.09 118.27,83.49 120.96,83.49 121.87,82.59 Q2.3 R11.1
DDR3_DRAM_PWROK: length 36.6
  TOP w0.102: v2(59.93,65.36) 62.72,68.15 67,68.15 71.81,72.96 v2(71.81,73.49) ; v2(86.49,77.63) 86.22,77.9 U1.AD42
  LAY3 w0.102: v2(86.49,77.63) 85.85,76.99 85.85,75.81 85.07,75.03 84.43,75.03 84.27,75.19 82.79,75.19 81.09,73.49 v2(71.81,73.49)
  BOTTOM w0.102: v2(59.93,65.36) R439.2 R449.2 61.25,65.36 R450.2 Q39.3
DDR3_VCCA_PWROK: length 20.2
  TOP w0.102: v2(86.69,79) 86.69,78.29 U1.AB42 ; R7.2 Q47.3 v2(72.18,77.05)
  LAY3 w0.102: v2(86.69,79) 84.55,79 84.31,78.76 84.31,78.03 83.49,77.21 72.35,77.21 v2(72.18,77.05)
DDR3_VCCA_PWROK_3P3: length 69.3
  TOP w0.102: v2(62.48,77.42) 63.4,77.42 R10.1 64,78 Q46.1
  LAY3 w0.102: v2(44.29,104.43) 43.24,104.43 42.19,103.38 33.81,103.38 33.14,104.04 17.5,104.04 v2(16.12,102.66)
  BOTTOM w0.102: v2(62.48,77.42) 61.55,77.42 59.21,79.76 59.21,88.22 44.29,103.14 v2(44.29,104.43) ; U40.4 15.89,101.62 16.12,101.84 v2(16.12,102.66)
DDR3L_DRAMRST#: length 44.6
  TOP w0.102: v2(116.38,51.29) 115.78,50.69 CN3.30 ; U1.P41 v2(91.57,79)
  LAY3 w0.102: v2(91.57,79) 91.81,78.76 92.8,78.76 93.01,78.54 93.01,77.5 93.19,77.32 95.16,77.32 95.88,76.6 95.88,76.59 96.1,76.37 96.11,76.37 97.64,74.85 98.39,74.85 98.76,74.47 98.76,72.62 107.3,64.09 107.3,58.44 112.44,53.3 114.88,53.3 116.38,51.8 v2(116.38,51.29)
DDR3L_EVENT: length 34.2
  LAY3 w0.102: v2(87.51,29.01) 84.96,29.01 84.68,28.74 82.88,28.74 81.98,29.64 81.27,30.35 v2(81.27,30.91)
  BOTTOM w0.102: R581.1 66.18,43.62 71.87,37.92 80.07,37.92 82.09,35.9 82.09,31.74 v2(81.27,30.91) ; v2(87.51,29.01) 87.51,29.01 U28.68
DDR3L_VREF: length 8.2
  TOP w0.203: U1.AF44 v2(84.79,76.86)
  BOTTOM w0.254: C1.1 83.3,75.84 83.7,76.23 84.16,76.23 v2(84.79,76.86)
  BOTTOM w0.406: C1.1 83.3,70.89 R9.2 83.3,70.12 R6.1
DDR_STBY: length 9.3
  BOTTOM w0.102: R434.1 56.38,70.73 55.59,70.73 R435.1 55.11,70.25 55.11,67.53 55.12,67.52 55.12,64.92 54.82,64.62 R384.2 54.26,64.62 53.58,63.93 U43.17
DELAY_ALL_SYS_PWRGD: length 5.3
  BOTTOM w0.102: U40.2 14.76,104.47 15.04,104.74 R388.2 ; R388.2 16.69,105.85 U37.4 ; R388.2 U39.1
DP_HPD: length 161.5
  TOP w0.102: CN18.1 C617.2 68.63,131.83 68.38,131.58 65.39,131.58 63.98,130.18 v2(63.98,126.36)
  LAY3 w0.102: v2(62.04,115.63) 64.52,113.15 66.38,113.15 67.89,114.66 67.89,123.62 66.45,125.06 64.6,125.06 63.98,125.67 v2(63.98,126.36) 64.04,126.3 119.83,126.3 128.37,117.76 134.98,117.76 137.98,114.75 137.98,84.58 v2(136.68,83.29)
  BOTTOM w0.102: U10.11 61.97,115.7 v2(62.04,115.63) ; v2(136.68,83.29) 127.76,83.29 123.75,79.27 R15.2 Q2.1
DRVH1: length 2.7
  TOP w0.635: v1(21.88,97.2) Q35.8
  BOTTOM w0.635: R429.1 v1(21.88,97.2)
DRVH2: length 1.4
  TOP w0.635: Q34.8 R430.2
DRVL1: length 4.1
  TOP w0.635: v1(20.38,94.62) 20.34,94.66 Q35.3
  BOTTOM w0.635: R432.1 21.38,92.84 20.38,93.84 v1(20.38,94.62)
DRVL2: length 3.1
  TOP w0.635: Q34.3 23.14,79.81 v1(23.53,80.2)
  BOTTOM w0.635: v1(23.53,80.2) 23.19,80.2 R431.2
EC_BLEN: length 88.4
  TOP w0.102: R749.1 v2(24.73,29.51)
  LAY3 w0.102: v2(101.02,24.99) 94.66,24.99 94.38,24.71 90.04,24.71 89.33,25.42 82.78,25.42 79.37,28.83 65.81,28.83 58.5,21.53 49.31,21.53 48.13,22.71 34.42,22.71 28.97,28.16 28.97,29.64 28.09,30.52 25.74,30.52 v2(24.73,29.51)
  BOTTOM w0.102: v2(101.02,24.99) 101.48,25.45 U28.35
EC_DELAY_ALL_SYS_PWRGD: length 144.9
  TOP w0.102: v2(18.23,104.74) 18.23,106.08 19.48,107.33 21.94,107.33 22.12,107.15 42.13,107.15 43.77,105.51 43.77,103.34 45.45,101.66 45.45,89.54 v2(46.73,88.26)
  LAY4 w0.102: v2(46.73,88.26) 45.66,87.18 45.66,65.63 46.62,64.67 46.62,57.64 48.71,55.55 48.71,46.81 54.16,41.36 64.89,41.36 65.61,40.65 84.02,40.65 87.45,37.22 90.83,37.22 v2(91.6,36.46)
  BOTTOM w0.102: R713.1 18.99,102.23 19.23,102.47 19.23,103.74 v2(18.23,104.74) R388.1 ; U28.88 91.04,37.01 v2(91.6,36.46)
EC_MUTE#: length 25.8
  LAY4 w0.102: v2(114.54,25.46) 110.15,25.46 108.47,27.13 105.54,27.13 104.91,26.5 v2(104.91,26.11)
  BOTTOM w0.102: v2(114.54,25.46) 114.07,24.98 114.07,21.2 115,20.26 115,18 115.85,17.14 R269.2 116.87,16.82 U24.1 ; v2(104.91,26.11) 104.91,28.9 104.39,29.41 U28.28
EDID_SCL: length 18.4
  TOP w0.114: v2(55.33,114.91) 55.89,115.47 55.89,115.76 56.17,116.04 56.68,116.04 56.95,116.32 57.03,116.4 57.33,116.7 57.33,117.29 57.56,117.53 58.15,117.53 58.86,118.23 58.86,118.75 59.18,119.07 59.76,119.07 63.61,122.93 64.29,122.93 R170.1 64.71,123 65.84,123 66.66,123.83 66.66,124.83 U12.6
  BOTTOM w0.114: U10.29 54.92,114.5 v2(55.33,114.91)
EDID_SDA: length 17.8
  TOP w0.114: U12.5 66.17,124.58 66.17,124.03 65.63,123.49 64.54,123.49 R171.1 64.32,123.42 63.41,123.42 59.55,119.57 58.97,119.57 58.36,118.96 58.36,118.44 57.94,118.02 57.36,118.02 56.83,117.5 56.83,116.9 56.47,116.54 55.89,116.54 55.26,115.91 v2(55.26,115.58)
  BOTTOM w0.114: U10.30 54.72,114.9 55.26,115.44 v2(55.26,115.58)
EDP_AUXN: length 62.3
  TOP w0.101: C523.2 48.06,120.87 48.06,111.64 48.53,111.16 50.31,111.16 50.67,111.52 v2(50.67,111.55) ; v2(83.8,101.59) 83.8,101.74 83.68,101.86 83.45,101.86 83.32,101.73 83.32,97.99 U1.AK2
  LAY3 w0.101: v2(83.8,101.59) 83.8,101.71 83.55,101.95 81.6,101.95 79.6,103.95 62.96,103.95 61.93,104.98 60.62,104.98 60.4,105.2 60.4,106.1 60.3,106.2 58.53,106.2 58.43,106.1 58.43,105.89 58.53,105.79 59.77,105.79 59.99,105.57 59.99,105.2 59.77,104.98 55.01,104.98 49.61,110.38 49.61,110.82 49.95,111.15 50.27,111.15 v2(50.67,111.55)
EDP_AUXN_CONN: length 13
  TOP w0.101: CN18.17 53.17,132.89 52.79,132.51 52.79,130.32 48.38,125.92 48.38,122.76 R615.2
EDP_AUXP: length 62.2
  TOP w0.101: v2(83.8,102.25) 83.63,102.07 83.36,102.07 83.11,101.82 83.11,98.19 83.02,98.1 83.02,97.86 83.31,97.57 U1.AK3 ; C526.2 47.84,111.55 48.44,110.95 v2(50.67,110.95)
  LAY3 w0.101: v2(83.8,102.25) 83.71,102.15 81.68,102.15 79.68,104.15 63.05,104.15 62.02,105.18 60.7,105.18 60.6,105.29 60.6,106.18 60.38,106.4 58.45,106.4 58.23,106.18 58.23,105.81 58.45,105.59 59.69,105.59 59.79,105.49 59.79,105.29 59.69,105.18 55.09,105.18 49.82,110.46 49.82,110.73 50.03,110.95 v2(50.67,110.95)
EDP_AUXP_CONN: length 13.1
  TOP w0.101: CN18.18 52.17,132.86 52.57,132.45 52.57,130.41 48.17,126.01 48.17,122.78 47.84,122.45 R162.2
EDP_BKLCTL: length 219.1
  TOP w0.102: U1.M30 v2(92,84.6)
  LAY3 w0.102: v2(92,84.6) 92.5,85.09 95.34,85.09 95.46,84.97 97.2,84.97 98.15,84.02 99.22,84.02 100.15,83.09 102.1,83.09
  LAY3 w0.127: 102.1,83.09 102.9,83.09 104.86,81.13 106.11,81.13 106.69,80.56 111.02,80.56 112.63,78.95 112.63,74.55 117.27,69.91 120.89,69.91 126.62,64.17 126.62,57.23 127.21,56.65 127.21,52.41 125.67,50.87 125.67,37.12 120.39,31.85 117.28,31.85 115.16,33.97 114.47,33.97 113.97,33.47 90.5,33.47 83.15,40.82 73.88,40.82 66.82,33.76 65.68,33.76 60,28.08 57.81,28.08 56.12,29.77 53.85,29.77 51.4,27.32 43.86,27.32 41.64,29.54 38.99,29.54 32.2,36.33 26.69,36.33 23.48,39.54 21.59,39.54 19.36,41.77 17.21,41.77 16.99,41.99 14.38,41.99 11.93,39.54 v2(11.93,36.98)
  BOTTOM w0.114: v2(11.93,36.98) 9.74,39.17 7.32,39.17 7.08,38.93 R178.1 6.58,38.06 6.58,37.22 Q7.1
EDP_BKLCTL_3P3: length 148.5
  TOP w0.152: Q90.3 11.28,34.43 R751.2 R710.2 11.71,33.62 11.04,32.95 8.5,32.95 6.09,35.36 v2(5.27,35.36)
  LAY3 w0.152: v2(49.8,118.82) 41.54,118.82 37.68,122.68 34.08,122.68 31.01,125.74 29.6,125.74 28.85,126.5 26.97,126.5 24.07,123.61 15.89,123.61 14.35,122.07 14.35,120.16 12.49,118.3 12.49,109.05 10.29,106.86 9.22,106.86 3.62,101.26 3.62,88.35 2.25,86.99 2.25,77.66 3.62,76.29 3.62,55.47 2.68,54.53 2.68,41.04 5.27,38.44 v2(5.27,35.36)
  BOTTOM w0.152: R152.1 51.73,119.05 51.29,118.62 50,118.62 v2(49.8,118.82)
EDP_BKLEN: length 186.2
  TOP w0.102: U1.J30 v2(93.43,83.61)
  LAY3 w0.127: v2(29.8,37.62) 31.85,37.62 39.18,30.3 42.01,30.3 43.58,28.72 51.37,28.72 53.28,30.63 56.19,30.63 57.83,28.98 59.71,28.98 67.29,36.57 68.66,36.57 73.67,41.57 83.36,41.57 90.83,34.1 113.45,34.1 113.96,34.62 115.41,34.62 117.51,32.52 119.79,32.52 125.03,37.76 125.03,54.96 125.55,55.48 125.55,57.91 125.99,58.35 125.99,63.89 120.62,69.26 116.29,69.26 111.51,74.04 111.51,78.65 110.47,79.69 106.19,79.69 105.66,80.22 104.55,80.22 103.38,81.4 102.47,81.4 101.45,82.42 98.17,82.42 96.55,84.03 95.63,84.03 94.66,83.06 93.98,83.06 v2(93.43,83.61)
  BOTTOM w0.114: Q16.1 28.54,35.86 R164.1 28.54,37.38 28.78,37.62 v2(29.8,37.62)
EDP_BKLEN_3P3: length 5.1
  TOP w0.203: U63.1 R748.1 21.93,33.19 22.16,33.42 v2(22.52,33.42)
  BOTTOM w0.203: R661.2 22.78,32.77 22.52,33.04 v2(22.52,33.42) 22.52,34.07 22.18,34.4 Q17.3
EDP_BKLEN_OUT: length 7.7
  TOP w0.102: R308.1 25.01,36.15 26.04,35.12 26.04,31.84 25.68,31.49 U63.4 25.04,30.83 R749.2
EDP_TXN0: length 62.8
  TOP w0.101: C140.1 60.75,125.25 60.75,124.7 58.15,122.11 57.03,122.11 54.89,119.96 54.89,116.89 54.18,116.19 54.18,112.78 54.89,112.07 54.89,109.22 v2(55.09,109.02) ; v2(83.8,104.23) 83.8,104.12 83.99,103.93 84.19,103.93 84.53,103.6 84.53,101.61 84.51,101.59 84.51,100.58 84.9,100.2 84.9,98.49 U1.AG1
  LAY3 w0.101: v2(83.8,104.23) 83.61,104.23 83.52,104.14 83.52,103.87 83.43,103.77 81.36,103.77 80.21,104.92 70.37,104.92 69.84,105.44 62.74,105.44 61.04,107.14 57.8,107.14 57.7,107.24 57.7,108.14 57.48,108.36 56.32,108.36 56.1,108.14 56.1,107.77 56.32,107.55 56.79,107.55 56.89,107.44 56.89,107.24 56.79,107.14 55.23,107.14 54.89,107.49 54.89,108.82 v2(55.09,109.02)
EDP_TXN0_CONN: length 9
  TOP w0.101: CN18.5 65.17,132.48 65.07,132.38 64.75,132.38 64.6,132.24 64.6,131.53 60.74,127.67 60.74,126.82 C138.2
EDP_TXN1: length 62.2
  TOP w0.101: U1.AF2 85.33,98.06 85.33,101.58 85.35,101.59 85.35,106 85.44,106.1 85.62,106.1 85.71,106.01 85.71,105.74 85.79,105.65 v2(86,105.65) ; v2(53.7,111.55) 53.48,111.76 53.48,116.49 54.16,117.17 54.16,120.51 56.74,123.09 56.74,124.97 56.9,125.12 57.41,125.12 57.49,125.21 57.49,125.42 C143.1
  LAY3 w0.101: v2(86,105.65) 86,105.78 85.66,106.11 85.1,106.11 83.21,107.99 63.34,107.99 61.44,109.9 61.44,110.94 60.73,111.64 59.49,111.64 58.82,112.31 53.43,112.31 53.3,112.18 53.3,111.88 53.63,111.55 v2(53.7,111.55)
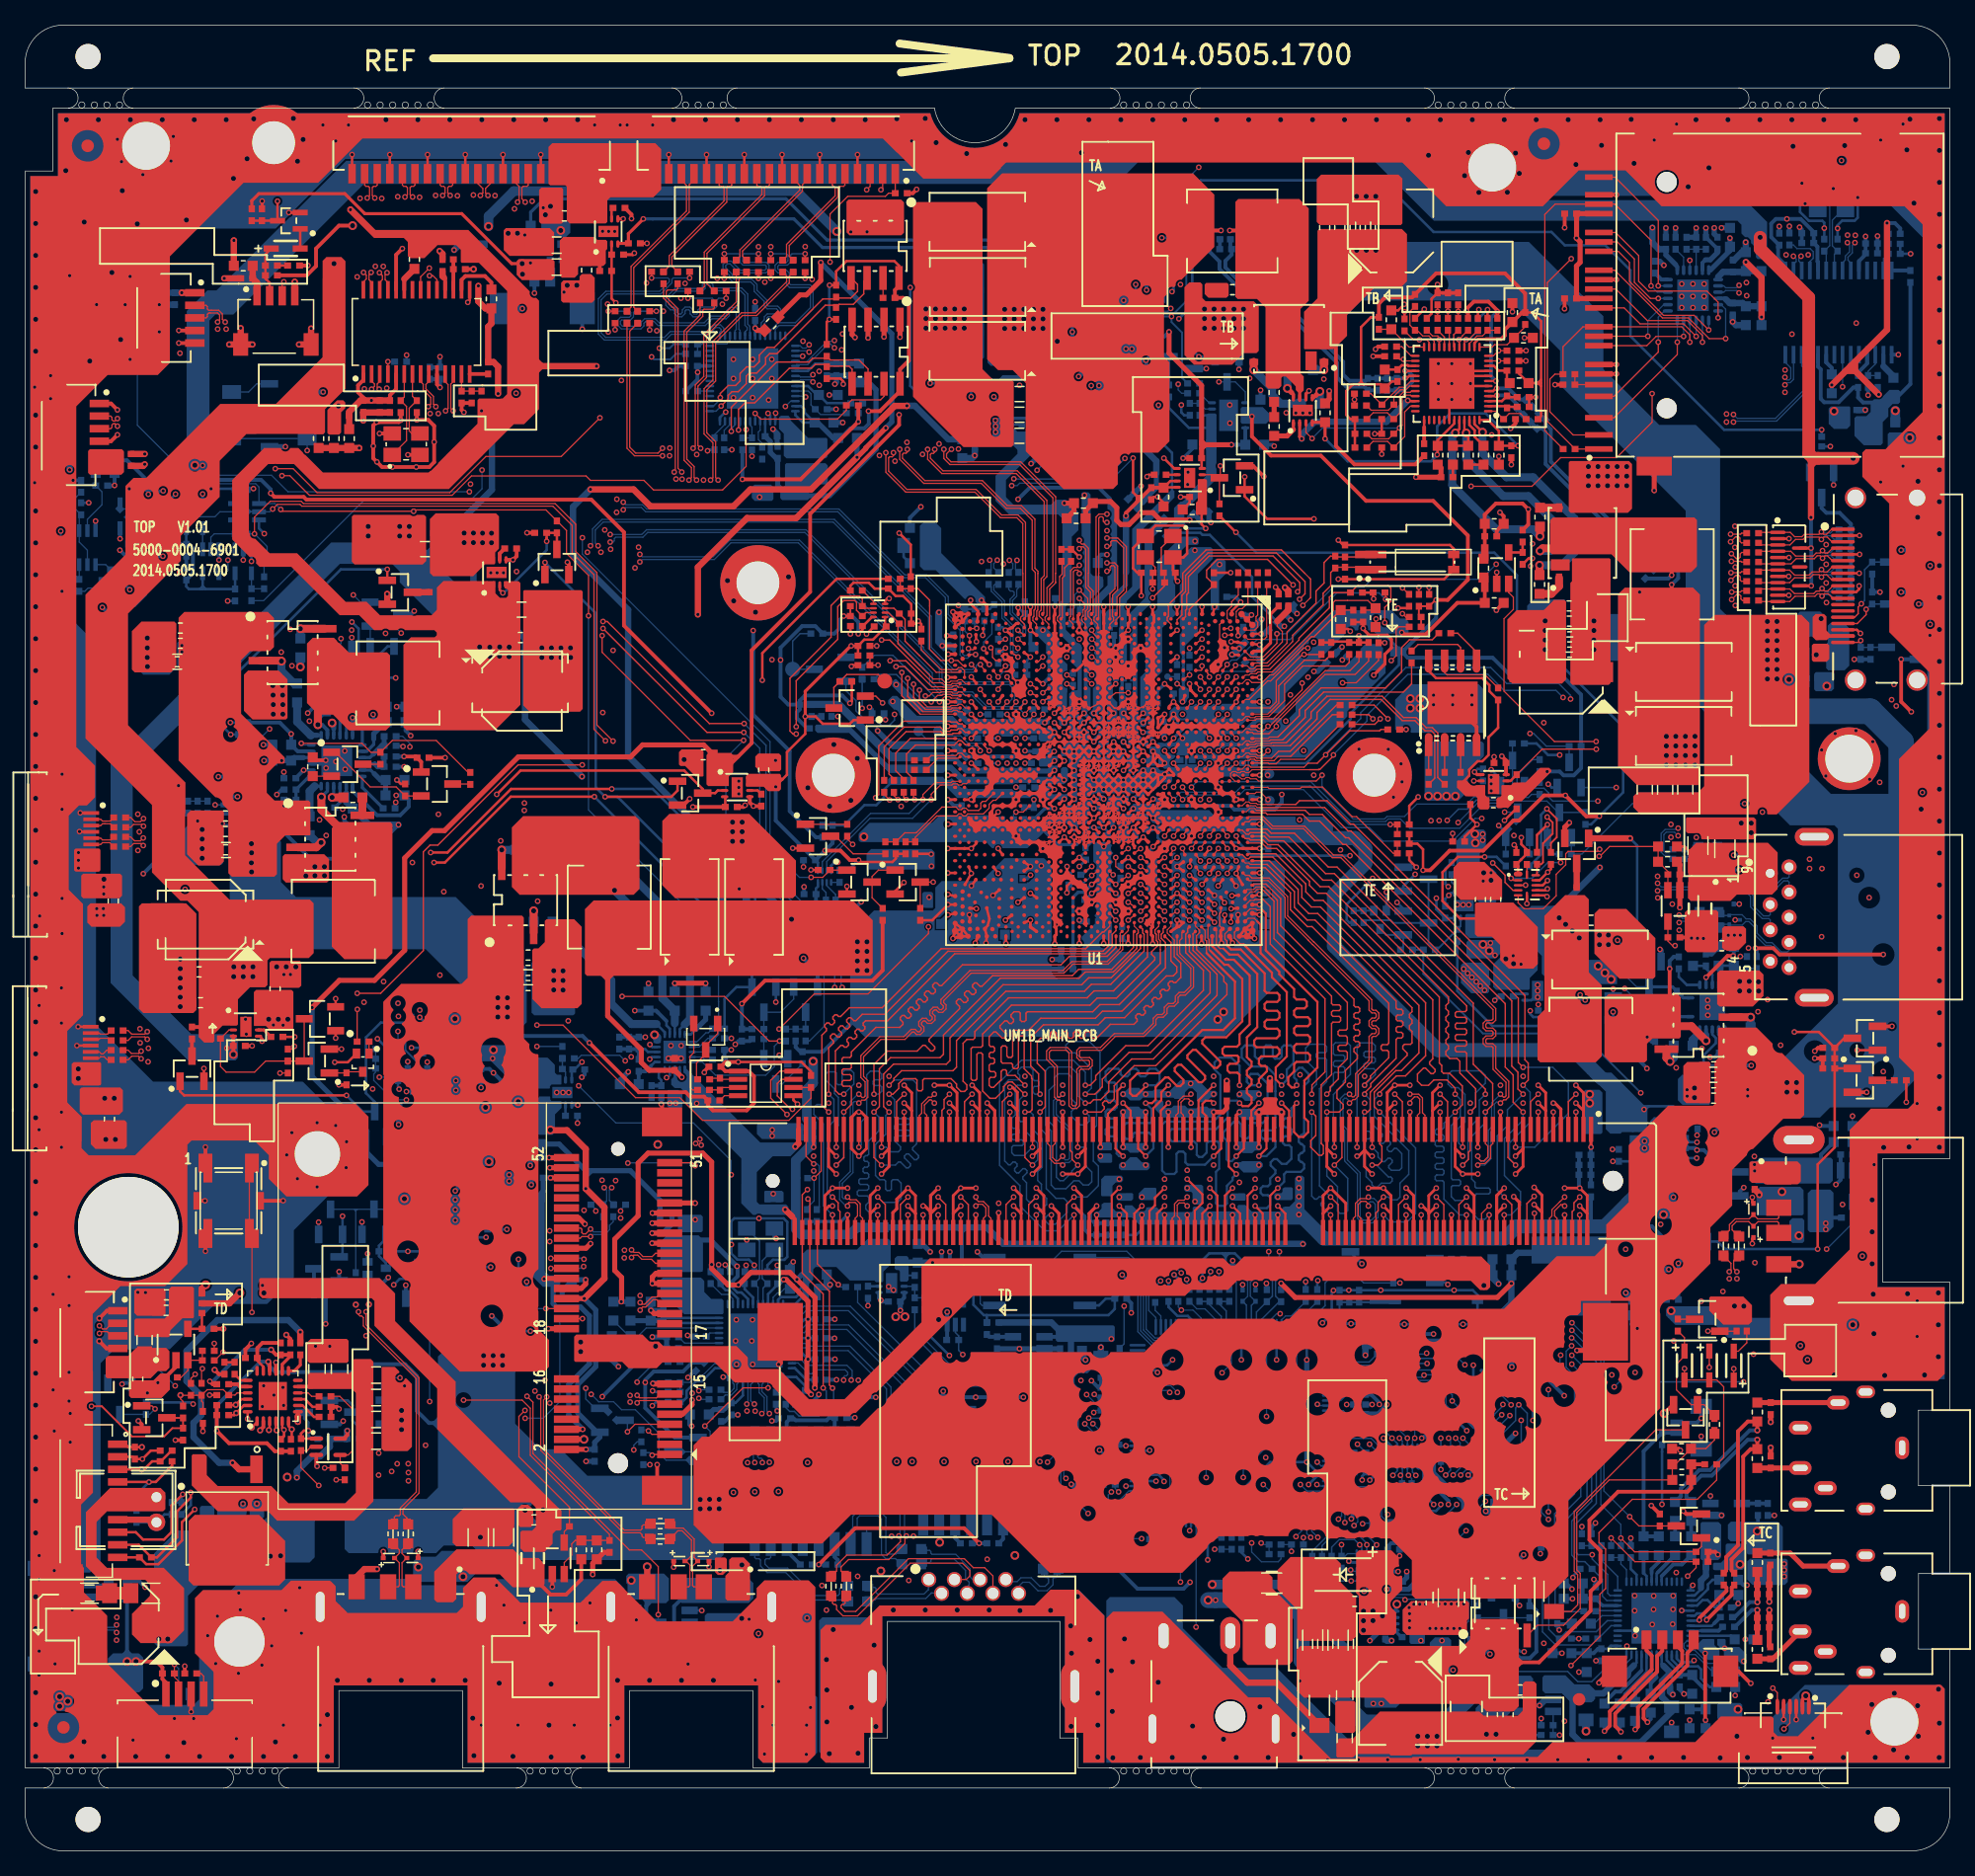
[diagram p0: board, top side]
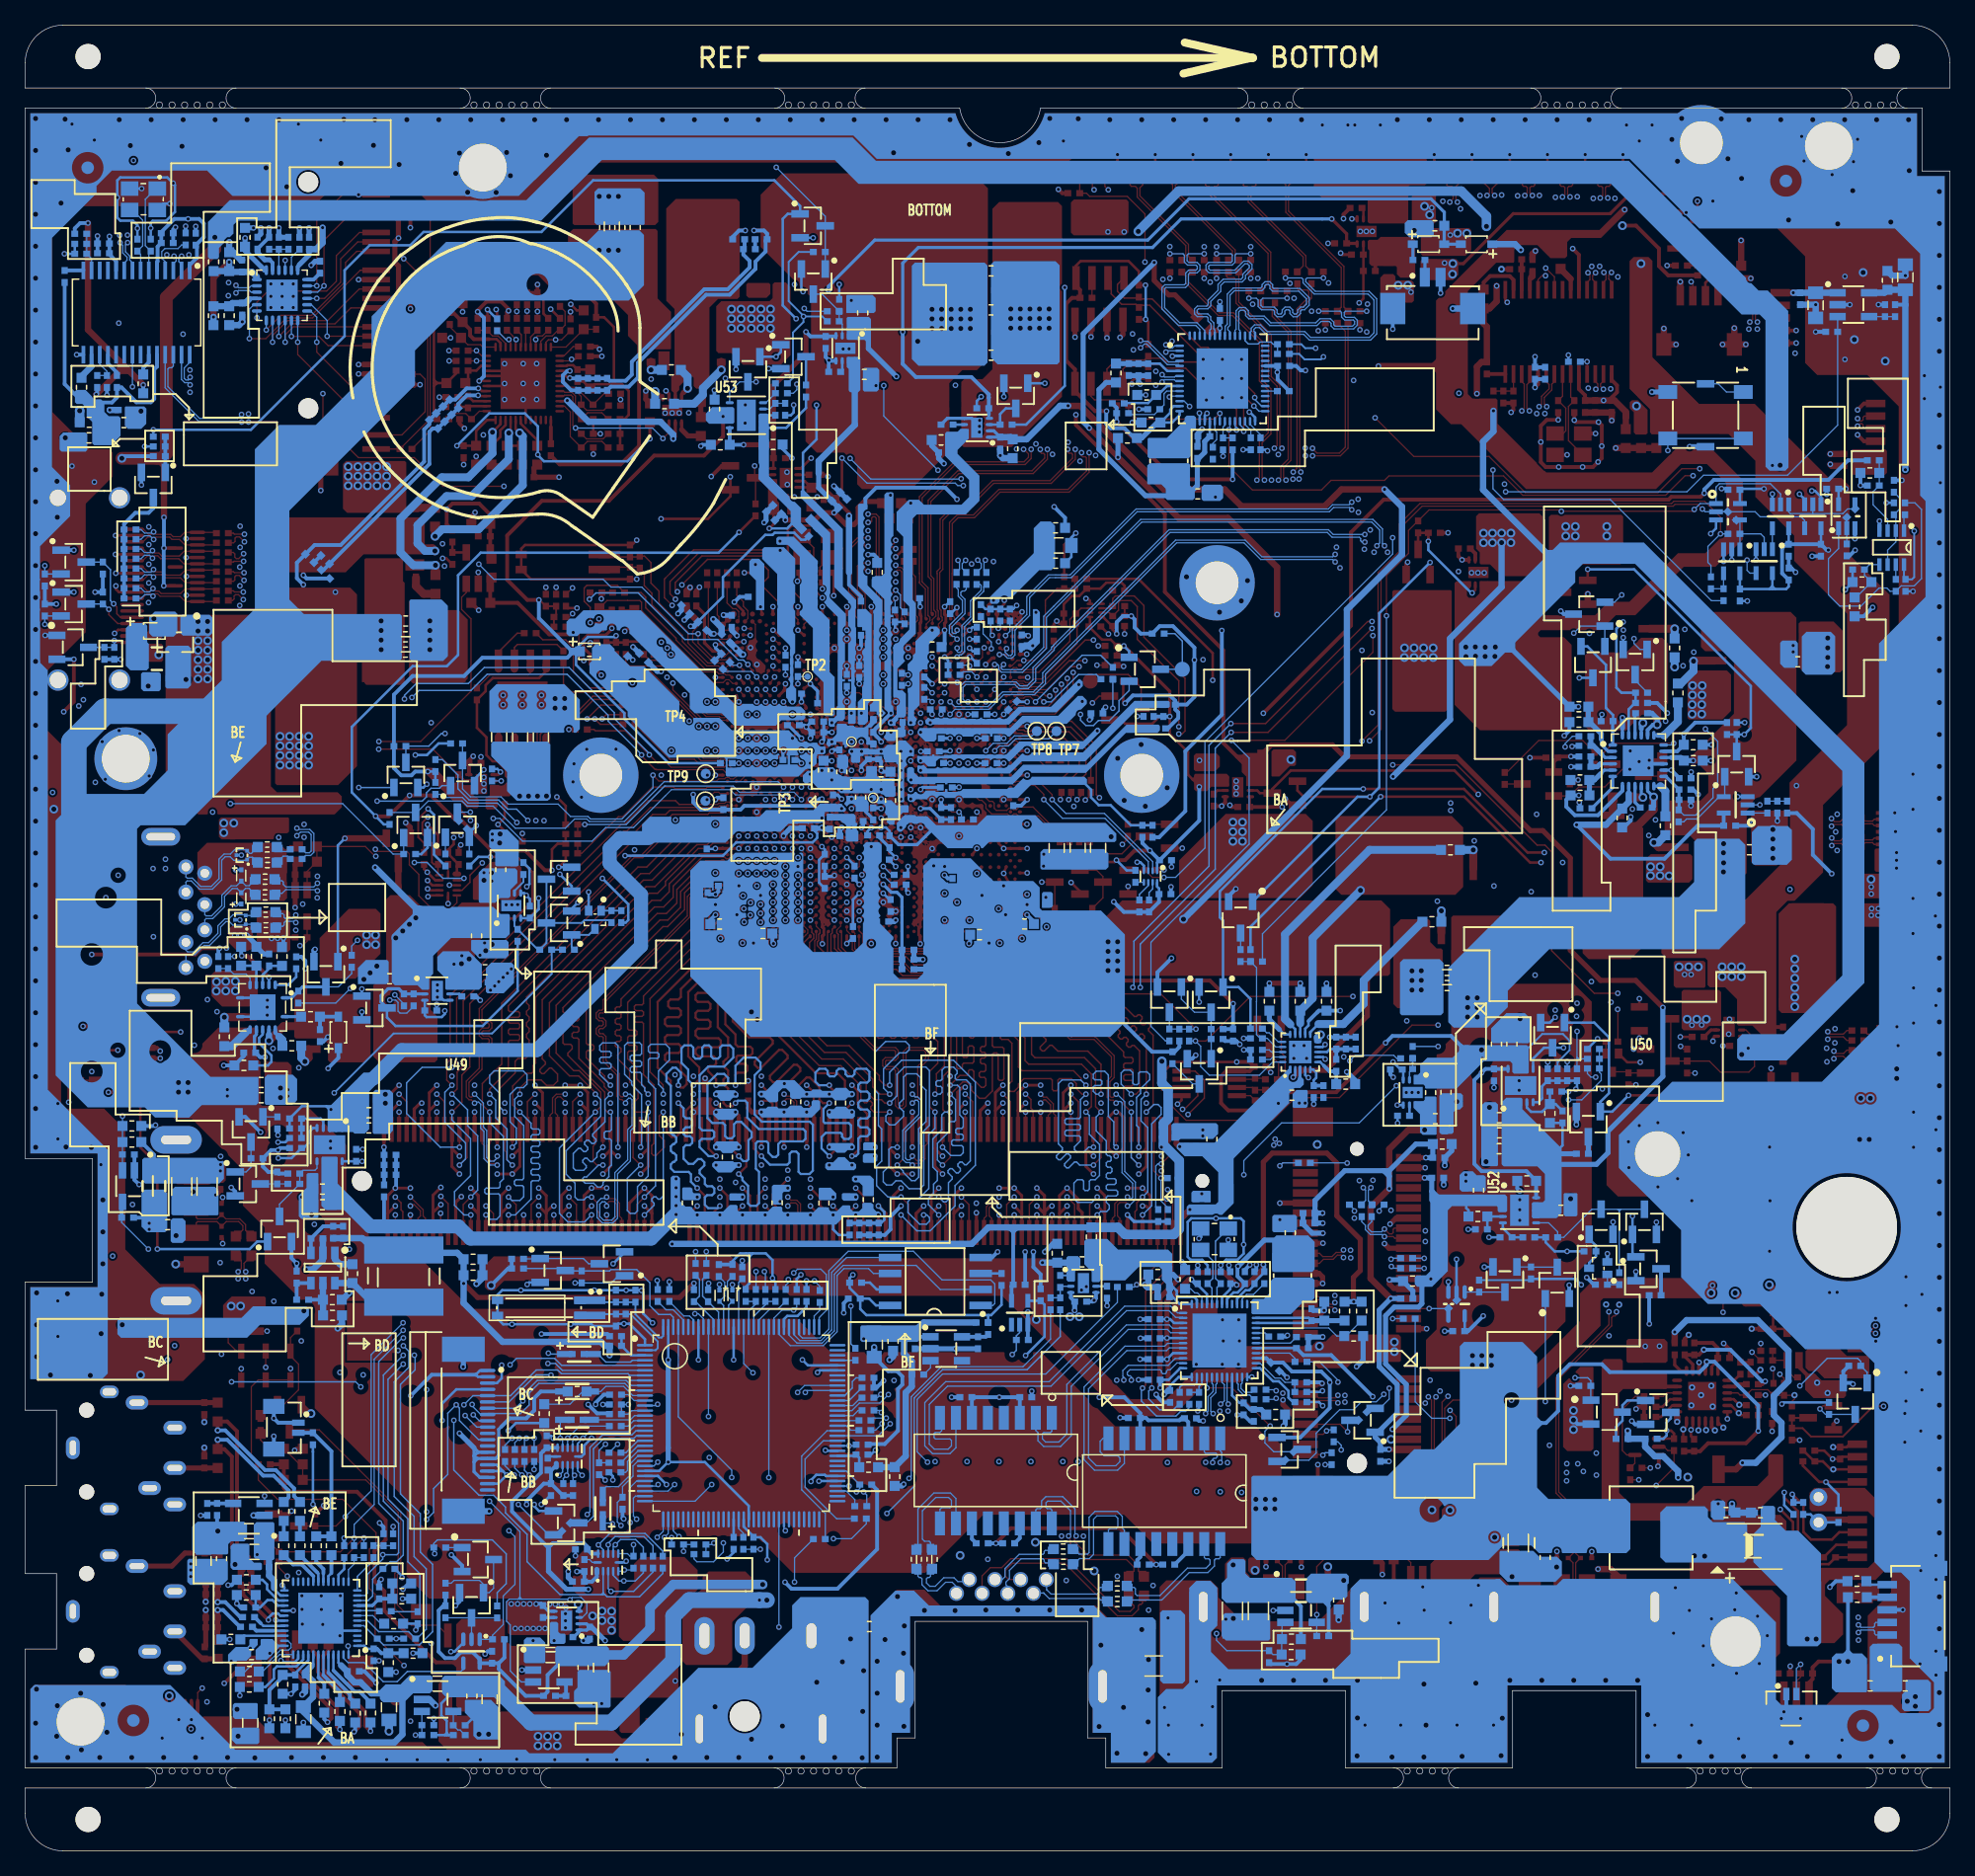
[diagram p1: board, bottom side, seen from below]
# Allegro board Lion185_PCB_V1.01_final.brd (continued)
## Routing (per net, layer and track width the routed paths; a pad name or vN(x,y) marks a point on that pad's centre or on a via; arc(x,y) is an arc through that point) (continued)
EDP_TXN1_CONN: length 9.1
  TOP w0.101: CN18.8 62.17,132.89 61.79,132.5 61.79,132 57.03,127.24 57.03,126.84 R609.2
EDP_TXN2: length 62.1
  TOP w0.101: C155.2 54.78,122.71 54.67,122.61 53.97,122.61 53.87,122.51 53.87,122.04 52.6,120.77 52.6,110.68 53.18,110.1 53.18,109.21 v2(53.37,109.02) ; v2(86,101.77) 86.17,101.77 86.24,101.85 86.24,102.11 86.35,102.21 86.52,102.21 86.63,102.1 86.63,100.37 86.23,99.97 U1.AD2
  LAY3 w0.101: v2(53.37,109.02) 53.16,109.23 53.16,109.33 53.52,109.69 55.57,109.69 55.67,109.59 55.67,109.09 55.89,108.87 56.26,108.87 56.48,109.09 56.48,109.59 56.58,109.69 57.57,109.69 57.67,109.59 57.67,109.05 57.89,108.83 58.26,108.83 58.48,109.05 58.48,109.59 58.58,109.69 59.23,109.69 59.71,109.21 59.71,108.51 60.32,107.9 61.02,107.9 62.81,106.11 69.88,106.11 70.58,105.42 83.49,105.42 84.42,104.49 84.42,102.45 84.65,102.23 85.62,102.23 85.71,102.14 85.71,101.85 85.8,101.77 v2(86,101.77)
EDP_TXN2_CONN: length 11.7
  TOP w0.101: C155.1 54.2,124.64 54.2,127.05 58.77,131.63 58.77,132.28 58.88,132.38 59.07,132.38 59.17,132.48 CN18.11
EDP_TXN3: length 62.2
  TOP w0.101: U1.AC1 86.79,98.44 86.79,99.72 87.32,100.25 87.32,103.63 86.76,104.2 86.4,104.2 86.31,104.1 86.31,103.83 86.23,103.75 v2(86,103.75) ; C520.2 51.87,124.24 51.77,124.14 51.08,124.14 50.96,124.02 50.96,123.58 51.9,122.65 51.9,109.96 v2(52.2,109.66)
  LAY3 w0.101: v2(86,103.75) 85.77,103.75 85.67,103.85 85.67,104.11 85.58,104.21 85.42,104.21 85.18,104.45 85.18,104.78 83.84,106.12 70.87,106.12 69.76,107.22 62.87,107.22 58.8,111.3 57.14,111.3 56.22,110.38 52.25,110.38 51.98,110.11 51.98,109.87 v2(52.2,109.66)
EDP_TXN3_CONN: length 10.1
  TOP w0.101: CN18.14 56.17,132.48 56.07,132.38 55.88,132.38 55.77,132.28 55.77,131.13 51.41,126.77 51.41,126.04 C520.1
EDP_TXP0: length 63.2
  TOP w0.101: C142.1 60.53,125.24 60.53,124.79 58.06,122.32 56.94,122.32 54.67,120.05 54.67,116.98 53.97,116.28 53.97,112.69 54.67,111.98 54.67,109.2 v2(54.48,109.02) ; v2(83.8,103.57) 83.94,103.71 84.1,103.71 84.31,103.51 84.31,100.48 84.68,100.11 84.68,98.71 84.49,98.52 84.49,98.2 84.77,97.92 U1.AG3
  LAY3 w0.101: v2(54.48,109.02) 54.68,108.82 54.68,107.4 55.15,106.94 56.87,106.94 57.09,107.16 57.09,107.53 56.87,107.75 56.4,107.75 56.3,107.85 56.3,108.05 56.4,108.15 57.4,108.15 57.5,108.05 57.5,107.16 57.72,106.94 60.96,106.94 62.66,105.24 69.76,105.24 70.29,104.72 80.13,104.72 81.28,103.57 v2(83.8,103.57)
EDP_TXP0_CONN: length 8.7
  TOP w0.101: CN18.6 64.17,132.48 64.38,132.27 64.38,131.62 60.52,127.76 60.52,126.81 C141.2
EDP_TXP1: length 62.3
  TOP w0.101: v2(86,106.31) 85.36,106.31 85.13,106.09 85.13,98.27 84.96,98.1 84.96,97.85 85.26,97.55 U1.AF3 ; v2(53.09,111.55) 53.27,111.72 53.27,116.58 53.95,117.26 53.95,120.6 56.53,123.18 C154.2
  LAY3 w0.101: v2(86,106.31) 85.18,106.31 83.3,108.2 63.43,108.2 61.64,109.98 61.64,111.02 60.82,111.85 59.57,111.85 58.91,112.51 53.35,112.51 53.09,112.26 v2(53.09,111.55)
EDP_TXP1_CONN: length 9.1
  TOP w0.101: C153.1 56.81,126.8 56.81,127.33 61.57,132.09 61.57,132.46 61.17,132.86 CN18.9
EDP_TXP2: length 62.1
  TOP w0.101: v2(86,102.43) 86.6,102.43 86.84,102.19 86.84,100.28 86.44,99.88 86.44,98.53 86.43,98.52 86.43,98.19 86.52,98.1 86.52,97.85 86.22,97.55 U1.AD3 ; C157.2 53.65,122.13 52.38,120.86 52.38,110.59 52.96,110.01 52.96,109.21 v2(52.77,109.02)
  LAY3 w0.101: v2(52.77,109.02) 52.96,109.2 52.96,109.42 53.43,109.89 55.65,109.89 55.87,109.67 55.87,109.18 55.98,109.07 56.18,109.07 56.28,109.18 56.28,109.67 56.5,109.89 57.65,109.89 57.87,109.67 57.87,109.14 57.97,109.04 58.17,109.04 58.27,109.14 58.27,109.67 58.49,109.89 59.32,109.89 59.92,109.29 59.92,108.59 60.41,108.1 61.11,108.1 62.89,106.32 69.97,106.32 70.67,105.62 83.58,105.62 84.63,104.57 84.63,102.54 84.73,102.43 85.99,102.43 v2(86,102.43)
EDP_TXP2_CONN: length 11.6
  TOP w0.101: CN18.12 58.17,132.48 58.27,132.38 58.46,132.38 58.56,132.28 58.56,131.72 53.98,127.14 53.98,124.4 R612.2
EDP_TXP3: length 62.2
  TOP w0.101: C522.2 50.75,123.49 51.68,122.56 51.68,109.74 v2(51.6,109.66) ; v2(86,104.41) 86.85,104.41 87.54,103.72 87.54,100.16 87.01,99.63 87.01,98.2 86.71,97.91 U1.AC3
  LAY3 w0.101: v2(86,104.41) 85.5,104.41 85.38,104.54 85.38,104.86 83.92,106.32 70.95,106.32 69.84,107.43 62.96,107.43 58.88,111.5 57.06,111.5 56.14,110.58 52.17,110.58 51.78,110.2 51.78,109.84 v2(51.6,109.66)
EDP_TXP3_CONN: length 10.1
  TOP w0.101: R614.2 51.2,126.04 51.2,126.86 55.56,131.22 55.56,132.28 55.46,132.38 55.27,132.38 55.17,132.48 CN18.15
EDP_VDDEN: length 166.9
  TOP w0.102: U1.N30 v2(92,83.61) ; v2(114.94,108.53) 119.79,108.53 122.07,110.81 126.51,110.81 129.33,113.63 v2(129.33,115.9)
  TOP w0.203: v2(46.96,123.12) 46.62,123.45 R136.1 46.62,125.65 R137.1 46.62,126.95 46.62,127.79 U8.3
  LAY4 w0.102: v2(114.94,108.53) 114.94,108.14 118.55,104.54 118.55,91.93 116.15,89.53 116.15,82.46 v2(115.79,82.11) ; v2(46.96,123.12) 48.09,124.25 61.38,124.25 61.68,124.56 62.85,124.56 63.48,125.2 118.23,125.2 127.53,115.9 v2(129.33,115.9)
  BOTTOM w0.089: v2(92,83.61) 92.09,83.61 92.46,83.98 96.54,83.98 96.95,84.39 101.62,84.39 102.1,83.92
  BOTTOM w0.102: 102.1,83.92 104.63,81.39 106.85,81.39 107.93,80.3 113.46,80.3 115.26,82.11 v2(115.79,82.11)
EECS: length 3.4
  BOTTOM w0.102: U17.30 52.42,40.38 R213.2
EEDI: length 1.1
  BOTTOM w0.102: U17.32 54.43,41.18 R210.2
EMC_THERM#: length 1.6
  TOP w0.102: R132.1 55.59,60.06 U7.4
ENBLT: length 131.2
  TOP w0.102: v2(20.42,109.37) 21.05,109.37 22.44,107.97 22.6,107.81 33.94,107.81 35.48,109.35 44.59,109.35 44.94,109 49.19,109 49.95,108.23 55.44,108.23 57.31,110.1 v2(57.31,113.03) ; R639.1 23.82,30.46 v2(23.81,30.45)
  LAY4 w0.102: v2(23.81,30.45) 23.81,36.77 24.75,37.71 24.75,40.48 24.51,40.72 24.51,44.27 19.91,48.87 19.91,60.5 22.38,62.97 22.38,70.39 16.05,76.72 16.05,88.14 15.78,88.41 15.78,94.64 21.07,99.93 21.07,106.55 20.42,107.2 v2(20.42,109.37)
  BOTTOM w0.102: U10.23 57.23,113.11 v2(57.31,113.03)
ENLDO: length 30.1
  LAY4 w0.102: v2(19.43,89.22) 19.17,89.48 19.17,96.59 22.46,99.88 v2(26.08,99.88)
  BOTTOM w0.102: R665.2 21.14,82.37 20.21,82.37 18.83,83.75 18.83,84.47 18.45,84.84 18.45,88.25 v2(19.43,89.22) ; Q98.2 26.66,99.31 v2(26.08,99.88)
  BOTTOM w0.254: R665.2 21.53,82.82 R465.2 21.53,83.6 R491.1 22.58,85.45 U42.13
ENPVCC/I2C_ADDR: length 1
  BOTTOM w0.102: R184.1 53.47,116.1 U10.33
ENSWREG: length 9.2
  BOTTOM w0.102: U17.33 49.37,41.58 48.73,40.94 R215.1 48,40.94 R214.2
ENTRIP1: length 9.2
  BOTTOM w0.203: Q42.2 28.81,95.79 27.33,94.32 27.33,90.9 26.77,90.33 R425.2
  BOTTOM w0.254: R425.2 26.8,89.82 U42.1
ENTRIP2: length 3.2
  BOTTOM w0.254: R426.1 26.8,84.57 U42.6
EVDD10: length 4.8
  BOTTOM w0.203: U17.21 57.06,36.22 56.46,35.63 C211.1
  BOTTOM w0.305: C211.1 55.62,35.11 55.34,35.11 C210.2
  BOTTOM w0.406: C210.2 54.75,35.1 R220.1
FAN_BACK: length 4.1
  TOP w0.203: D3.P 19.1,126.98 R135.2 R134.2 19.1,125.05 19.43,124.71 CN4.2
FAN_PWMIN: length 185.2
  TOP w0.102: v2(20.57,124.79) 20.43,124.66 CN4.3
  LAY3 w0.102: v2(32.97,69.65) 32.96,69.66 29.03,69.66 v2(28.49,69.13)
  LAY4 w0.102: v2(105.64,25.87) 105.57,25.87 104.11,24.41 99.87,24.41 93.63,30.66 85.13,30.66 81.77,34.01 68.13,34.01 66.89,32.77 63.35,32.77 62.49,31.91 55.6,31.91 55.16,31.48 52.49,31.48 49.58,28.57 44.39,28.57 33.81,39.15 33.81,65.11 32.97,65.95 v2(32.97,69.65) ; v2(20.57,124.79) 21.33,124.02 21.33,107.78 27.27,101.84 27.27,70.35 v2(28.49,69.13)
  BOTTOM w0.102: v2(105.64,25.87) 105.93,26.17 105.93,27.71 R320.1 105.51,28.97 104.68,29.8 104.68,30.61 104.28,31.01 U28.24
FAN_VCC: length 2.5
  TOP w0.508: FB1.1 C131.2 18.43,124.71 CN4.1
FLASH_TXE: length 3.3
  TOP w0.102: R712.2 Q100.1
FMISO: length 22.1
  BOTTOM w0.102: U28.103 92.28,41.02 91.64,40.38 89.64,40.38 88.67,41.35 88.67,45.86 87.98,46.56 82.17,46.56 80.26,44.65 U30.2
FMOSI: length 13.9
  BOTTOM w0.102: U28.102 91.88,41.04 91.43,40.59 89.73,40.59 88.89,41.42 88.89,46 87.7,47.19 U30.5
FSCE#: length 25.7
  BOTTOM w0.102: U30.1 76.07,43.38 75.92,43.52 75.92,45.09 76.25,45.41 80.11,45.41 82.39,47.69 87.57,47.69 89.11,46.14 89.11,41.49 89.81,40.79 91.22,40.79 91.48,41.05 U28.101
FSCK: length 15.1
  BOTTOM w0.102: U30.6 85.57,45.92 85.96,46.31 87.92,46.31 88.46,45.77 88.46,41.28 89.56,40.18 92.17,40.18 93.08,41.09 U28.105
GA20_EC: length 15.4
  BOTTOM w0.114: U28.126 101.48,42.44 101.7,42.66 102.64,42.66 103.34,43.36 103.34,45.18 104.39,46.23 106.43,46.23 106.54,46.12 R317.2 110.02,46.12 Q63.3 110.22,46.32 R81.2
GF_IMAX: length 4.2
  TOP w0.102: U56.24 110.02,119.6 R551.1 R544.2
GFX_PWM: length 11.8
  TOP w0.203: U56.34 109.96,115.3 v2(109.91,115.35)
  TOP w0.254: U57.2 101.32,112.47 v2(101.48,112.31)
  BOTTOM w0.508: v2(109.91,115.35) 108.21,113.65 102.5,113.65 101.48,112.63 v2(101.48,112.31)
GFX_PWRGD: length 65.7
  TOP w0.102: R531.2 110.36,120.18 v2(110.83,120.18) 111.4,120.18 111.61,119.97 U56.23
  LAY4 w0.102: v2(110.83,120.18) 111.54,119.47 111.54,112.8 118.82,105.52 118.82,91.67 118.04,90.89 118.04,83.7 116.75,82.41 116.75,80.01 119.84,76.92 119.84,72.92 123.03,69.72 123.03,68.08 123.45,67.67 v2(124.01,67.67)
  BOTTOM w0.102: v2(124.01,67.67) 123.56,67.67 123.36,67.47 123.36,66.78 123.2,66.63 122.66,66.63 122.12,67.17 R458.1
GL834L_3V3: length 30.3
  TOP w0.508: v2(136.78,126.35) 138.03,125.11 v2(138.03,121.99)
  LAY3 w0.508: v2(136.78,126.35) 136.13,127.01 136.13,129.04 135.37,129.8 133.99,129.8 133.61,129.42 v2(133.61,129.07)
  LAY4 w0.508: v2(129.36,129.09) 129.97,128.48 133.25,128.48 133.61,128.84 v2(133.61,129.07)
  BOTTOM w0.254: U95.1 134.58,125.19
  BOTTOM w0.305: R801.1 134.53,127.41 C705.1 ; 133.58,126.54 133.33,126.3 U95.23 ; U95.19 131.33,125.99 131.21,126.11 131.21,126.15
  BOTTOM w0.406: C705.1 134.53,127.11 133.95,126.54 133.58,126.54 ; C710.2 130.43,126.93 131.21,126.15 ; v2(133.61,129.07) R801.1
  BOTTOM w0.508: C700.1 136.78,126.35 v2(136.78,126.35) ; C700.1 FB4.1 ; C700.1 136.72,125.57 C701.1 134.97,125.57 134.58,125.19 ; FB20.2 v2(138.03,121.98) ; C710.2 129.87,127.38 129.36,127.89 v2(129.36,129.09)
GL850_AVDD: length 18.3
  TOP w0.305: U77.1 26.89,116.98 26.46,116.55 26.46,116.01 26.88,115.59 C577.2 ; U77.5 29.49,116.26 29,115.77 C574.2 ; v2(32.98,116.38) 32.74,116.63 U77.10
  TOP w0.508: 28.18,115.35 C573.2 ; 28.18,115.35 28.99,115.35 C574.2 ; 28.18,115.35 v2(27.53,115.35) C577.2 26.66,115.35 25.75,114.44 C582.2 25.76,114.11 FB15.1
  LAY3 w0.305: v2(27.53,115.35) 28.94,115.35 29.98,116.38 v2(32.98,116.38)
  BOTTOM w0.305: C575.2 C576.2 v2(32.98,116.39)
GL850_AVDD1: length 36.5
  LAY4 w0.508: v2(140.05,129.79) 140.25,129.99 145.03,129.99 146.3,128.72 v2(146.3,128.4) 146.3,117.01 145.72,116.43 v1(143.79,114.5)
  BOTTOM w0.305: U83.1 139.92,126.12 139.35,126.7 139.35,127.61 C610.2 138.8,128.34 138.8,129.42 139.17,129.79 v2(140.05,129.79) 141.13,129.79 142.18,128.74 C612.2 C611.2 142.47,127.58 142.47,126.41 142.52,126.36 U83.5 ; U83.10 145.77,126.43 146.3,126.96 C613.2 C614.2 v2(146.3,128.4)
GL850G_RST#: length 2.9
  TOP w0.102: U77.13 34.69,116.11 C578.2 R698.2 R692.2
GL850G_RST#_1: length 3.1
  BOTTOM w0.102: R721.2 R735.2 C606.2 147.72,126.63 U83.13
GL850G_X1: length 7.2
  TOP w0.102: X7.1 30.32,112.16 30.32,114.87 C579.2 30.14,115.62 U77.6
GL850G_X2: length 5.9
  TOP w0.102: U77.7 30.79,115.69 C580.2 30.53,114.73 30.53,112.93 30.74,112.72 X7.3
GPO: length 2.7
  BOTTOM w0.102: R226.2 55.36,44.25 55.9,44.25 56.26,43.9 U17.38
H_PROCHOT#: length 149.4
  TOP w0.089: 98.49,87.18 98.4,87.1 98,87.1 97.89,87.21 97.39,87.21 97.29,87.31 97.05,87.31 96.75,87.01 U1.C24
  TOP w0.102: 98.49,87.18 v2(98.8,87.49)
  LAY3 w0.203: v2(98.8,87.49) 98.8,87.47 99.51,88.19 101.43,88.19 103.87,90.63 108.96,90.63 111.16,88.43 113.46,88.43 115.87,86.02 115.87,82.81 v2(117.14,81.54) 117.41,81.27 117.41,76.63 120.93,73.11 122.22,73.11 124.31,71.02 125.7,71.02 128.47,68.25 128.47,61.18 129.67,59.98 129.67,52.27 128,50.6 128,44.2 127.26,43.46 127.26,36.47 121.51,30.72 116.57,30.72 115.82,31.48 103.97,31.48 103.33,32.12 89.78,32.12 86.24,35.66 82.51,35.66 78.17,40 74.08,40 v2(73.47,39.4)
  BOTTOM w0.114: R580.2 Q62.2
  BOTTOM w0.203: U29.4 72.28,43.75 C294.1 71.97,43.44 71.97,40.9 v2(73.47,39.4) ; v2(117.14,81.54) 117.43,81.25 R578.1
H_RCIN#: length 45.1
  LAY4 w0.127: v2(121.09,26.96) 119.05,24.92 107.23,24.92 v2(106.65,24.34) ; v2(121.09,36.68) 119.5,35.08 117.32,35.08 116.09,36.32 114.67,36.32 v2(111.41,39.58)
  BOTTOM w0.114: R321.1 D11.P 111.33,39.51 111.4,39.58 v2(111.41,39.58) ; v2(121.09,36.68) v2(121.09,26.96) ; R653.2 103.09,24.27 103.82,25 106.1,25 106.65,24.45 v2(106.65,24.34) U26.9
HD: length 5.8
  TOP w0.102: R72.1 116.05,93.52 113.03,93.52 112.84,93.72 U3.7
HDA_BITCLK: length 133.6
  TOP w0.114: R49.2 69.84,83.81 v2(70.04,83.61)
  LAY3 w0.127: v2(122.94,40.17) 122.7,40.17 122.38,40.49 116.25,40.49 113.03,43.71 90.6,43.71 86.28,48.03 70.69,48.03 69.06,49.66 63.08,49.66 61.03,51.71 61.03,55 61.67,55.64 61.67,56.76 62.96,58.05 62.96,60.53 65.34,62.91 65.34,64.41 68.88,67.95 68.88,81.1 70.04,82.26 v2(70.04,83.61)
  BOTTOM w0.114: U23.6 125.77,18.31 124.9,17.43 122.52,17.43 C257.2 121.86,16.88 121.12,17.62 121.12,22.44 122.08,23.4 122.08,26.61 123.66,28.19 123.66,37.3 122.5,38.46 122.5,39.73 v2(122.94,40.17)
HDA_RST#: length 142.8
  TOP w0.114: v2(70.7,83.61) 70.62,83.69 R47.2
  LAY3 w0.127: v2(120.45,23.63) 124.49,23.63 v2(124.57,23.55) ; v2(122.94,40.8) 122.73,41 116.46,41 113.06,44.4 109.2,44.4 108.57,45.03 103.09,45.03 102.29,44.23 90.79,44.23 86.48,48.55 70.89,48.55 69.27,50.16 63.3,50.16 61.65,51.81 61.65,54.18 62.18,54.7 62.18,56.38 63.47,57.67 63.47,60.32 65.88,62.74 65.88,64.2 69.38,67.7 69.38,80.89 70.7,82.21 v2(70.7,83.61)
  BOTTOM w0.114: v2(120.45,23.63) 120.52,23.71 R275.2 120.52,24.44 120.23,24.73 115.86,24.73 114.76,23.63 114.76,21.25 115.48,20.53 R272.1 ; U23.11 125.98,20.31 125.8,20.49 125.8,21.98 124.57,23.21 v2(124.57,23.55) 123.46,23.55 123.31,23.7 123.31,26.05 124.89,27.63 124.89,38.91 123.01,40.8 v2(122.94,40.8)
HDA_SDATAIN0: length 142.4
  TOP w0.114: v2(67.61,83.76) 67.85,84.01 67.85,87.88 69.81,89.84 73.51,89.84 73.57,89.78 74.03,89.78 74.19,89.62 74.48,89.62 U1.BG19
  LAY3 w0.127: v2(122.95,38.71) 122.78,38.88 115.42,38.88 111.99,42.31 104.04,42.31 103.1,41.37 90.55,41.37 86.17,45.75 70.77,45.75 68.22,48.31 61.98,48.31 57.85,52.44 57.85,56.87 61.66,60.67 61.66,61.03 63.49,62.86 63.49,65.28 67.61,69.4 v2(67.61,83.76)
  BOTTOM w0.114: R262.2 123.86,19.02 C260.2 121.62,19.19 121.62,22.04 122.58,22.99 122.58,26.4 124.16,27.98 124.16,37.5 v2(122.95,38.71)
HDA_SDATAOUT: length 136.7
  TOP w0.114: v2(68.72,83.58) 68.29,84.01 R50.2
  LAY3 w0.127: v2(122.06,39.42) 115.57,39.42 112.3,42.69 103.28,42.69 102.34,41.75 90.71,41.75 86.28,46.18 71.09,46.18 68.58,48.69 62.14,48.69 58.33,52.5 58.33,54.86 62.05,58.57 62.05,60.88 63.93,62.76 63.93,65.05 67.99,69.11 67.99,82.84 v2(68.72,83.58)
  BOTTOM w0.114: U23.5 126.07,17.91 125.04,16.88 C261.2 124.51,16.38 121.66,16.38 120.61,17.42 120.61,22.79 121.59,23.76 121.59,26.81 123.17,28.39 123.17,37.09 122,38.25 122,39.36 v2(122.06,39.42)
HDA_SYNC: length 128
  TOP w0.114: v2(69.38,83.61) 69.06,83.93 R48.2
  LAY3 w0.127: v2(122.95,39.41) 122.73,39.41 122.16,39.98 115.55,39.98 112.39,43.14 103.19,43.14 102.18,42.13 91.46,42.13 86.4,47.19 70.81,47.19 68.85,49.15 62.86,49.15 60.46,51.55 60.46,56.38 62.45,58.38 62.45,60.74 64.61,62.91 64.61,64.64 68.37,68.4 68.37,82.59 v2(69.38,83.61)
  BOTTOM w0.114: U23.10 125.74,19.91 125.38,20.26 125.38,21.6 C259.2 123.98,23 123.46,23 122.95,23.52 122.95,26.23 124.53,27.81 124.53,37.84 v2(122.95,39.41)
HDMI_CTRLCLK: length 71.3
  TOP w0.089: 102.1,85.98 97.52,85.98 97.29,85.75 97.02,85.75 96.93,85.84 96.67,85.84 96.58,85.74 96.34,85.74 96.25,85.84 95.99,85.84 95.82,85.67 95.82,85.42 96.18,85.07 U1.C28
  TOP w0.114: 102.1,85.98 102.82,85.98 102.84,86.01 102.92,86.01 104,87.09 v2(104,87.16)
  LAY4 w0.127: v2(122.25,91.73) 122.53,92 145.91,92 147.34,93.43 147.34,96.56 148.86,98.08 150.66,98.08 151.44,98.86 v2(151.44,102.21)
  BOTTOM w0.114: Q9.2 R202.2 v2(151.44,102.21) ; v2(104,87.16) 104,87.19 106.67,89.86 106.67,90.32 109.92,93.57 116.28,93.57 117.56,92.29 121.69,92.29 v2(122.25,91.73)
HDMI_CTRLDATA: length 72.2
  TOP w0.089: U1.C26 96.74,86.03 97.05,86.34 97.29,86.34 97.39,86.24
  TOP w0.102: 101.98,86.5 101.67,86.18 97.44,86.18 97.39,86.24
  TOP w0.114: 101.98,86.5 102.72,86.5 v2(103.38,87.17) 105.3,89.08 107.67,89.08 107.77,89.18 R14.1
  LAY4 w0.127: v2(151.44,97.54) 149.04,97.54 147.87,96.38 147.87,93.11 146.26,91.49 122.97,91.49 v2(122.85,91.61)
  BOTTOM w0.114: v2(103.38,87.17) 103.38,87.28 106.17,90.06 106.17,90.52 109.76,94.11 116.5,94.11 117.77,92.84 121.91,92.84 122.85,91.9 v2(122.85,91.61) ; Q10.2 R203.2 v2(151.44,97.54)
HDMI_HPD: length 45.5
  TOP w0.114: CN8.19 145.77,96.11 v2(145.92,96.26)
  LAY3 w0.127: v2(145.92,96.26) 147.42,94.75 v2(147.42,84.98)
  LAY4 w0.127: v2(147.42,84.98) 146.91,84.47 128.74,84.47 127.77,83.49 v2(125.02,83.49)
  BOTTOM w0.114: v2(125.02,83.49) 121.44,83.49 121.1,83.82 121.1,84.14 120.73,84.51 120.06,84.51 119.86,84.72 Q1.1 ; v2(145.92,96.26) 145.92,96.26 R199.2 C185.2 146.7,95.72 D6.3
HOME#: length 116.8
  TOP w0.102: CN13.2 12.19,13.49 11.86,13.82 R437.2 v2(11.86,14.84)
  LAY3 w0.102: v2(11.86,14.84) 8.45,18.24 8.45,37.01 14.12,42.68 17.23,42.68 17.5,42.41 22.61,42.41 25.85,39.17 34.23,39.17 35.96,37.44 v2(41.32,37.44)
  LAY4 w0.102: v2(84.38,36.29) 84.33,36.34 80.3,36.34 79.03,37.61 67.12,37.61 66.6,38.13 61.55,38.13 60.97,37.56 56.6,37.56 53.91,34.87 43.88,34.87 v2(41.32,37.44)
  BOTTOM w0.102: CN19.2 12.2,14.5 v2(11.86,14.84) ; v2(84.38,36.29) 85.06,35.61 86.68,35.61 87.28,35.01 U28.83
HP_OUT_L: length 4.9
  TOP w0.406: v3(137.7,19.78) 137.7,19.78 R711.1 C583.1 R680.2
  BOTTOM w0.305: R241.1 135.9,18.59 137.09,19.78 v3(137.7,19.78)
HP_OUT_R: length 4.8
  TOP w0.406: R699.2 C584.1 R719.1 v3(137.7,19.16)
  BOTTOM w0.305: v3(137.7,19.16) 137.27,19.16 135.92,17.81 R238.1
HSON: length 2.2
  BOTTOM w0.101: C208.2 55.52,36.47 56.05,36.47 56.35,36.77 56.35,37.11 56.26,37.2 U17.23
HSOP: length 2.6
  BOTTOM w0.101: C209.2 55.65,36.25 56.13,36.25 56.57,36.68 56.57,37.11 56.66,37.2 U17.22
HUB2_USB_PN1: length 82.2
  TOP w0.101: R381.1 135.01,47.32 FIL12.4 135.6,46.73 135.6,46.19 v2(135.47,46.06)
  LAY3 w0.101: v2(139.89,116.6) 140.05,116.76 140.59,116.76 141.2,116.14 141.2,103.08 141.4,102.88 141.4,90.96 139.56,89.12 139.56,79.91 140.98,78.5 140.98,69.18 140.19,68.4 140.19,67.53 143.04,64.68 143.04,54.91 135.66,47.53 135.66,46.26 v2(135.47,46.06)
  BOTTOM w0.101: U83.27 140.57,117.02 140.32,116.77 140.06,116.77 v2(139.89,116.6)
HUB2_USB_PN2: length 9.6
  LAY3 w0.101: v2(140.56,126.82) 140.56,126.61 140.67,126.5 140.86,126.5 140.96,126.4 140.96,126.18 139.09,124.31 136.44,124.31 v2(136.24,124.51)
  BOTTOM w0.101: U83.2 140.57,126.18 140.79,126.4 140.79,126.6 v2(140.56,126.82) ; U95.2 135.03,124.47 135.18,124.31 136.05,124.31 v2(136.24,124.51)
HUB2_USB_PN3: length 161.1
  TOP w0.101: v2(7.34,113.91) 7.14,113.72 7,113.72 6.9,113.82 6.9,114.01 6.8,114.11 CN22.2
  LAY3 w0.101: v2(144.85,127.9) 144.85,127.72 145.02,127.55 145.14,127.55 145.25,127.44 145.25,127.21 145.09,127.05 143.48,127.05 142.85,127.68 139.71,127.68 137.5,125.47 135.2,125.47 134.94,125.72 123.19,125.72 120.6,128.32 111.41,128.32 109.46,130.27 64.42,130.27 61.82,132.87 24.23,132.87 20.66,129.3 15.3,129.3 9.32,123.32 9.32,113.93 8.96,113.58 7.67,113.58 v2(7.34,113.91)
  BOTTOM w0.101: v2(144.85,127.9) 145.03,127.73 145.03,127.18 144.69,126.84 144.69,126.53 144.47,126.31 U83.8
HUB2_USB_PP1: length 82.5
  TOP w0.101: v2(136.07,46.06) 135.82,46.31 135.82,46.94 FIL12.1 136.23,47.35 R568.1
  LAY3 w0.101: v2(139.89,117.2) 140.13,116.96 140.67,116.96 141.41,116.23 141.41,103.16 141.6,102.96 141.6,90.88 139.76,89.04 139.76,80 141.18,78.58 141.18,69.1 140.39,68.31 140.39,67.61 143.24,64.76 143.24,54.82 135.87,47.45 135.87,46.26 v2(136.07,46.06)
  BOTTOM w0.101: v2(139.89,117.2) 139.89,117.12 140.03,116.98 140.23,116.98 140.36,117.11 140.36,117.94 139.92,118.37 U83.28
HUB2_USB_PP2: length 9.6
  LAY3 w0.101: v2(141.17,126.82) 141.17,126.09 139.18,124.1 136.44,124.1 v2(136.24,123.91)
  BOTTOM w0.101: v2(136.24,123.91) 136.05,124.1 135.17,124.1 135.04,123.97 U95.3 ; v2(141.17,126.82) 141,126.66 141,126.43 141.22,126.21 U83.3
HUB2_USB_PP3: length 161.1
  TOP w0.101: CN22.3 6.8,113.11 6.9,113.21 6.9,113.4 7,113.5 7.14,113.5 v2(7.34,113.31)
  LAY3 w0.101: v2(145.46,127.9) 145.46,127.13 145.18,126.84 143.4,126.84 142.77,127.48 139.79,127.48 137.58,125.26 135.12,125.26 134.86,125.52 123.11,125.52 120.51,128.11 111.32,128.11 109.37,130.06 64.34,130.06 61.73,132.67 24.31,132.67 20.75,129.1 15.38,129.1 9.52,123.24 9.52,113.85 9.05,113.38 7.4,113.38 v2(7.34,113.31)
  BOTTOM w0.101: U83.9 145.12,126.29 144.9,126.51 144.9,126.75 145.25,127.09 145.25,127.69 v2(145.46,127.9)
HUB_USB_PN1: length 134.7
  TOP w0.101: U77.27 27.54,124.75 27.33,124.96 27.33,125.36 v2(27.5,125.53) ; R564.1 49.71,26.02 FIL14.4 49.14,25.92 49.04,25.82 49.04,25.61 48.93,25.51 47.63,25.51 41.21,31.94 41.21,35.86 v2(41.46,36.11)
  LAY3 w0.101: v2(27.5,125.53) 27.5,125.29 27.4,125.2 27.2,125.2 27.1,125.09 27.1,124.65 25.61,123.15 25.61,118.79 26.41,117.99 40.04,117.99 51.35,106.68 51.35,101.83 49.04,99.53 49.04,66.41 46.36,63.72 46.36,58.12 45.15,56.91 45.15,52.87 45.82,52.2 47.21,52.2 47.92,51.49 47.92,49.63 45.96,47.67 44.15,47.67 42.24,45.75 42.24,37.46 41.24,36.47 41.24,36.32 v2(41.46,36.11)
HUB_USB_PN2: length 123.9
  TOP w0.101: v2(27.1,42.87) 27.1,41.84 31.31,37.64 31.31,28.45 30.03,27.18 30.03,26.79 30.35,26.47 FIL13.2 ; FIL13.2 30.35,26.08 ; FIL13.2 30.45,25.98 R382.1 ; U77.8 31.44,116.85 31.64,116.64 31.64,116.19 32.24,115.59 32.24,115.05 v2(32.05,114.86)
  LAY3 w0.101: v2(32.05,114.86) 32.05,115.43 32.28,115.67 34.16,115.67 35.44,116.95 39.92,116.95 50.54,106.33 50.54,102.17 48.23,99.86 48.23,67.19 45.5,64.46 45.5,58.59 44.33,57.42 44.33,55.19 40.59,51.45 36.86,51.45 33.6,48.19 30.35,48.19 26.92,44.76 26.92,43.06 v2(27.1,42.87)
HUB_USB_PN3: length 20.7
  TOP w0.101: v2(15.9,121.59) 15.68,121.81 15.68,122.24 15.39,122.52 14.8,122.52 14.8,122.52 14.59,122.52 14.48,122.63 14.48,122.81 14.38,122.92 J3.2 ; U77.2 27.54,116.89 27.77,116.66 27.77,116.47 v2(27.54,116.24)
  LAY3 w0.101: v2(27.54,116.24) 27.6,116.24 27.94,116.58 27.94,116.73 27.76,116.91 25.72,116.91 20.29,122.34 15.85,122.34 15.68,122.17 15.68,121.81 v2(15.9,121.59)
HUB_USB_PN4: length 104
  TOP w0.101: U77.11 33.39,116.84 33.62,116.61 33.62,114.72 v2(33.42,114.52) ; CN17.3 6.87,40.96 6.53,41.29 6.04,41.29 v2(5.9,41.16)
  LAY3 w0.101: v2(5.9,41.16) 4.85,41.16 4.15,41.86 4.15,45.75 3.34,46.56 3.34,52.99 5.08,54.73 5.08,61.04 6.21,62.17 6.21,71.89 4.47,73.62 4.47,76.54 3.48,77.54 3.48,82.72 5.08,84.32 5.08,100.4 18.63,113.96 25.45,113.96 26.01,114.52 31.41,114.52 32.09,113.84 33.44,113.84 33.6,114 33.6,114.34 v2(33.42,114.52)
HUB_USB_PP1: length 134.7
  TOP w0.101: U77.28 26.89,124.78 27.12,125.02 27.12,125.31 v2(26.9,125.53) ; v2(40.85,36.11) 40.99,35.97 40.99,31.85 47.54,25.3 48.89,25.3 49.04,25.15 49.04,25.02 49.14,24.92 FIL14.1 49.72,24.81 R566.1
  LAY3 w0.101: v2(26.9,125.53) 26.9,124.73 25.41,123.24 25.41,118.7 26.32,117.79 39.96,117.79 51.15,106.6 51.15,101.92 48.84,99.61 48.84,66.49 46.15,63.8 46.15,58.2 44.94,56.99 44.94,52.79 45.73,52 47.12,52 47.72,51.4 47.72,49.71 45.87,47.87 44.07,47.87 42.04,45.84 42.04,37.55 41.04,36.55 41.04,36.29 v2(40.85,36.11)
HUB_USB_PP2: length 123.9
  TOP w0.101: R575.1 29.25,25.98 FIL13.3 29.35,26.55 29.46,26.65 29.72,26.65 29.82,26.75 29.82,27.27 31.09,28.54 31.09,37.55 26.89,41.75 26.89,42.4 26.75,42.54 26.61,42.54 26.5,42.66 v2(26.5,42.87) ; v2(32.65,114.86) 32.46,115.05 32.46,115.68 31.86,116.28 31.86,116.62 32.09,116.85 U77.9
  LAY3 w0.101: v2(32.65,114.86) 32.58,114.86 32.25,115.2 32.25,115.35 32.37,115.47 34.24,115.47 35.52,116.75 39.83,116.75 50.33,106.25 50.33,102.25 48.03,99.95 48.03,67.28 45.3,64.55 45.3,58.67 44.13,57.51 44.13,55.27 40.51,51.65 36.77,51.65 33.52,48.4 30.26,48.4 26.71,44.85 26.71,43.09 v2(26.5,42.87)
HUB_USB_PP3: length 20.8
  TOP w0.101: v2(28.14,116.24) 27.99,116.4 27.99,116.66 28.19,116.86 U77.3 ; v2(15.3,121.59) 15.46,121.75 15.46,122.15 15.3,122.31 14.71,122.31 14.59,122.31 14.48,122.21 14.48,122.02 14.38,121.92 J3.3
  LAY3 w0.101: v2(15.3,121.59) 15.47,121.76 15.47,122.25 15.76,122.54 20.37,122.54 25.8,117.11 27.85,117.11 28.14,116.81 v2(28.14,116.24)
HUB_USB_PP4: length 104
  TOP w0.101: v2(34.02,114.52) 33.84,114.71 33.84,116.66 34.04,116.86 U77.12 ; CN17.2 6.9,41.96 6.45,41.51 6.15,41.51 v2(5.9,41.76)
  LAY3 w0.101: v2(5.9,41.76) 5.68,41.76 5.57,41.66 5.57,41.48 5.46,41.36 4.93,41.36 4.35,41.94 4.35,45.84 3.54,46.65 3.54,52.91 5.28,54.65 5.28,60.95 6.41,62.08 6.41,71.97 4.68,73.71 4.68,76.63 3.68,77.63 3.68,82.63 5.28,84.23 5.28,100.32 18.71,113.75 25.53,113.75 26.09,114.31 31.33,114.31 32.01,113.63 33.52,113.63 33.8,113.92 33.8,114.3 v2(34.02,114.52)
I2C_CLK0: length 3.2
  BOTTOM w0.114: U28.110 95.08,42.51 94.16,43.43 R190.2 R299.2
I2C_CLK1: length 4.5
  BOTTOM w0.102: R296.2 97.18,45.28 97.18,44.1 D27.N
  BOTTOM w0.114: U28.115 97.08,43.41 D27.N
I2C_CLK2: length 4.7
  BOTTOM w0.114: R672.2 99.15,45.47 99.15,44.12 R302.2 97.88,42.85 U28.117
I2C_CLK2_LVDS: length 146.2
  TOP w0.114: v2(57.13,88.95) 54.2,88.95 v2(45.93,97.22) ; v2(56.13,112.9) 56.13,114.8 59.74,118.41 62.3,118.41 62.6,118.71 63.57,118.71 R187.2 64.01,118.57 66.28,118.57 67,117.85 U13.6
  LAY4 w0.127: v2(94.24,46.07) 94.24,46.2 93.87,46.57 91.81,46.57 91.63,46.39 71.17,46.39 69.42,48.14 59.42,48.14 56.79,50.77 56.79,56.21 61.46,60.89 62.33,60.89 64.35,62.92 v2(64.35,68.67) ; v2(56.13,112.9) 55.91,112.68 47.69,112.68 42.1,107.09 42.1,99.57 44.45,97.22 v2(45.93,97.22)
  BOTTOM w0.114: R190.1 94.16,45.99 v2(94.24,46.07) ; v2(56.13,112.9) 56.13,113.12 56.43,113.41 U10.25 ; v2(64.35,68.67) 64.35,72.12 58.4,78.07 58.4,87.69 v2(57.13,88.95)
I2C_CLK2_THEM: length 53.4
  TOP w0.114: v2(60.56,58.57) 59.27,59.86 59.27,61.28 60,62.01 U7.8
  LAY4 w0.127: v2(98.85,47.66) 98.19,48.32 77.91,48.32 77.46,48.77 70.23,48.77 69.6,49.4 62.92,49.4 60.2,52.12 60.2,56.45 60.56,56.81 v2(60.56,58.57)
  BOTTOM w0.114: R672.1 v2(98.85,47.66)
I2C_DATA0: length 3.1
  BOTTOM w0.114: R300.2 R191.2 94.92,43.5 95.48,42.94 U28.111
I2C_DATA1: length 4.5
  BOTTOM w0.102: R297.2 97.39,45.22 97.39,44.12 D28.N
  BOTTOM w0.114: U28.116 97.48,43.38 D28.N
I2C_DATA2: length 5.1
  BOTTOM w0.114: U28.118 98.28,42.26 99.69,43.68 R315.2 99.4,44.12 99.4,45.46 R673.2
I2C_DATA2_LVDS: length 142.6
  TOP w0.114: U13.5 65.73,117.84 65.5,118.08 63.76,118.08 R188.2 63.55,118.21 62.81,118.21 62.51,117.91 60.75,117.91 58,115.16 57.22,115.16 56.71,114.64 v2(56.71,113) ; v2(45.93,97.77) 46.28,97.77 54.39,89.66 v2(57.15,89.66)
  LAY4 w0.127: v2(64.95,68.67) 64.95,62.79 62.48,60.32 61.64,60.32 57.29,55.97 57.29,52.65 61.07,48.87 69.4,48.87 70.04,48.23 76.83,48.23 77.98,47.08 94.1,47.08 94.9,46.28 v2(94.9,46.07) ; v2(56.71,113) 56.71,112.7 56.1,112.09 47.86,112.09 42.61,106.84 42.61,99.78 44.62,97.77 v2(45.93,97.77)
  BOTTOM w0.114: U10.24 56.83,113.31 56.71,113.19 v2(56.71,113) ; v2(57.15,89.66) 58.89,87.92 58.89,78.31 64.86,72.34 64.86,68.76 v2(64.95,68.67) ; R191.1 94.9,44.67 v2(94.9,46.07)
I2C_DATA2_THEM: length 52.7
  TOP w0.114: U7.7 60.12,61.36 59.79,61.02 59.79,60.05 60.86,58.98 v2(61,58.98)
  LAY4 w0.127: v2(61,58.98) 61.09,58.88 61.09,56.62 60.77,56.3 60.77,52.34 63.16,49.95 69.77,49.95 70.44,49.28 77.75,49.28 78.16,48.87 98.49,48.87 v2(99.7,47.65)
  BOTTOM w0.114: R673.1 v2(99.7,47.65)
IINA0: length 13.7
  TOP w0.203: J5.1 7.98,32.34 8.21,32.11 R342.1 9.28,32.11 v3(9.28,32.11) ; U25.22 17.18,35.92 17.07,35.8 17.07,35.8 v3(16.74,35.48) 16.71,35.44 R641.2
  LAY3 w0.203: v3(9.28,32.11) 15.23,32.11 16.21,33.09 16.21,34.95 v3(16.74,35.48)
IINA1: length 15.6
  TOP w0.203: R643.2 16.62,34.65 v3(16.78,34.82) 17.38,35.42 U25.23 ; J5.2 8.54,31.34 R342.2 9.32,31.16 v2(9.32,31.16) 9.99,31.83 R359.2
  LAY3 w0.203: v2(9.32,31.16) 15.03,31.16 16.78,32.91 v3(16.78,34.82)
IINA2: length 16.3
  TOP w0.203: R359.1 11.63,31.83 10.78,30.98 R349.1 10.09,30.98 9.45,30.34 v3(9.27,30.34) J5.3 ; v2(17.68,34.36) U25.24
  LAY3 w0.203: v2(17.68,34.36) 17.33,34 17.33,32.85 14.83,30.34 v3(9.27,30.34)
IINA3: length 19.7
  TOP w0.203: R349.2 11.68,30.63 10.39,29.34 9.84,29.34 ; v3(18.01,33.66) 18.43,34.09 U25.1 ; J5.4 9.84,29.34 ; 9.84,29.34 v2(9.85,29.33)
  LAY3 w0.203: v2(9.85,29.33) 10.42,29.9 16.16,29.9 18.01,31.74 v3(18.01,33.66)
  BOTTOM w0.203: R355.2 8.85,28.33 v2(9.85,29.33)
IINA4: length 20
  TOP w0.203: v3(19.38,33.46) 19.43,33.52 U25.3
  TOP w0.508: J5.7 10.23,26.34 CN6.2
  LAY3 w0.203: CN6.2 10.44,26.93 12.87,29.36 16.22,29.36 19.38,32.52 v3(19.38,33.46)
  BOTTOM w0.203: R355.1 10.44,26.12 CN6.2 11.07,26.76 R336.1
IINA5: length 20.5
  TOP w0.203: J5.8 8.79,25.34 9.37,24.76 11.04,24.76 11.64,25.36 11.64,27.47 v2(12.53,28.36) ; U25.4 19.93,33.52 19.99,33.46 v3(19.99,33.45)
  LAY3 w0.203: v3(19.99,33.45) 19.99,32.62 16.38,29.01 13,29.01 12.53,28.54 v2(12.53,28.36)
  BOTTOM w0.203: R336.2 R350.2 12.43,28.26 v2(12.53,28.36)
IINA6: length 23.4
  TOP w0.203: v2(13.16,28.51) 13.16,28.1 12.07,27 12.07,24.93 10.48,23.34 R341.1 9.04,24.34 J5.9 ; U25.5 20.43,33.63 v2(20.58,33.48) 20.58,32.98 R681.2
  LAY3 w0.203: v2(13.16,28.51) 16.47,28.51 20.58,32.62 v2(20.58,33.48)
  BOTTOM w0.203: R350.1 13.17,27.5 13.17,28.5 v2(13.16,28.51)
IINA7: length 21.4
  TOP w0.203: v2(13.48,27.16) 12.47,26.14 12.47,24.69 10.58,22.8 9.62,22.8 R341.2 J5.10 ; R642.2 21.19,32.8 21.19,33.52 ; U25.6 20.93,33.78 21.19,33.52 ; 21.19,33.52 v3(21.19,33.52)
  LAY3 w0.203: v2(13.48,27.16) 13.89,27.56 16.07,27.56 21.19,32.69 v3(21.19,33.52)
ISETA: length 2.1
  TOP w0.203: R626.2 22.97,34.51 22.06,35.42 U25.8
ISOLATEB: length 4.5
  BOTTOM w0.102: U17.26 54.84,38.78 53.66,37.6 53.19,37.6 52.85,37.26 R219.1 R217.1
IT8928_VSS: length 3.3
  BOTTOM w0.203: R331.1 90.89,43.25 91.6,42.54 92.42,42.54 92.68,42.28 U28.104
KBC_FAN_SPEED: length 185.7
  TOP w0.203: R133.2 C130.2 Q5.3 v2(20.06,131.2)
  LAY4 w0.203: v2(20.06,131.2) 20.06,111.53 20.89,110.7 20.89,107.3 27,101.19 27,69.67 27.89,68.78 27.89,65.65 27.56,65.32 27.56,62.78 28.62,61.73 28.62,59.52 28.27,59.17 28.27,42.03 29.24,41.06 29.24,33.07 30.01,32.3 30.01,29.12 30.26,28.86 41.99,28.86 43.79,27.06 49.87,27.06 52.82,30.02 62.86,30.02 64.33,31.48 67.4,31.48 68.66,32.74 81.24,32.74 84.51,29.48 86.5,27.48 92.93,27.48 v2(97.2,23.22)
  BOTTOM w0.203: v2(97.2,23.22) 96.68,23.73 R323.1
L_OUT+: length 9.2
  TOP w0.305: CN20.4 132.64,16.24 132.13,15.73 132.13,14.75 128.65,11.27 128.65,10.55 v2(128.97,10.23)
  BOTTOM w0.305: v2(128.97,10.23) 129.22,10.49 R285.1
L_OUT-: length 9.5
  TOP w0.305: CN20.3 131.39,16.23 131.72,15.89 131.72,14.93 128.21,11.41 128.21,9.87 v2(127.98,9.65)
  BOTTOM w0.305: R286.1 v2(127.98,9.65)
LAN_CMT: length 1.7
  BOTTOM w0.305: U61.11 77.74,24.8 R408.2
LAN_CMT1: length 1.7
  BOTTOM w0.305: U62.11 64.35,23.38 64.6,23.13 R596.2
LAN_CT: length 1.8
  BOTTOM w0.305: U61.14 73.93,24.87 R409.2
LAN_CT1: length 2.1
  BOTTOM w0.305: R577.2 60.54,23.85 U62.14
LAN_N1: length 21.3
  TOP w0.305: v2(75.84,24.46) 74.64,25.66 65.98,25.66 v2(63.09,22.77)
  LAY4 w0.305: v2(63.09,22.77) 62.15,21.83 v2(62.15,18.52)
  BOTTOM w0.305: R596.1 v2(63.09,22.77) R577.1 ; R409.1 v2(75.84,24.46) R408.1
LAN_TX0N: length 9.1
  BOTTOM w0.101: R604.2 80.9,23.94 FIL1.4 81.03,24.52 81.14,24.62 81.51,24.62 81.68,24.79 81.68,27.05 80.62,28.1 79.59,28.1 79.36,27.88 79.36,27.41 79.48,27.29 80.15,27.29 80.28,27.16 U61.9
LAN_TX0P: length 9
  BOTTOM w0.101: U61.10 79.01,28.02 79.45,28.46 80.76,28.46 82.03,27.19 FIL1.1 82.15,23.94 R603.2
LAN_TX1N: length 15
  TOP w0.101: v2(69.45,25.04) 69.58,24.91 69.58,24.59 68.51,23.52 65.31,23.52 64.5,22.72 64.5,22.25 FIL2.1 64.06,21.8 R618.2
  BOTTOM w0.101: v2(69.45,25.04) 69.55,25.14 69.55,27.2 70.52,28.17 71.86,28.17 72.2,27.83 72.2,27.32 72.3,27.22 72.56,27.22 72.66,27.12 U61.15
LAN_TX1P: length 13.8
  TOP w0.101: v2(70.05,25.04) 69.94,24.92 69.94,24.45 68.66,23.17 65.46,23.17 64.86,22.57 64.86,22.25 FIL2.4 65.28,21.83 R617.2
  BOTTOM w0.101: v2(70.05,25.04) 69.9,25.19 69.9,27.05 70.66,27.81 71.72,27.81 71.85,27.68 71.85,27.32 71.75,27.22 71.49,27.22 71.39,27.12 U61.16
LAN_TX2N: length 9.6
  BOTTOM w0.101: U62.9 66.89,25.52 66.78,25.63 66.26,25.63 66.14,25.75 66.14,26.45 66.33,26.64 67.81,26.64 68.07,26.38 68.07,23.57 68.4,23.24 69.18,23.24 69.53,22.9 FIL3.4 69.71,22.79 R622.2
LAN_TX2P: length 9.6
  BOTTOM w0.101: R620.2 69.71,24 FIL3.1 69.52,23.9 69.22,23.6 68.55,23.6 68.43,23.72 68.43,26.52 67.95,27 66.18,27 65.78,26.6 65.78,25.68 65.62,25.51 U62.10
LAN_TX3N: length 10.2
  BOTTOM w0.101: R624.2 65.43,21.06 FIL4.1 64.84,20.95 64.74,20.85 64.74,20.44 64.61,20.31 62.79,20.31 60.61,22.49 59.13,22.49 58.81,22.8 58.81,23.13 58.91,23.23 59.17,23.23 59.27,23.33 U62.15
LAN_TX3P: length 10.2
  BOTTOM w0.101: R623.2 65.43,19.84 FIL4.4 62.64,19.95 60.46,22.13 58.98,22.13 58.46,22.65 58.46,23.13 58.36,23.23 58.1,23.23 58,23.33 U62.16
LAN_VDDEN_EC: length 43.4
  LAY3 w0.102: v2(102.68,29.13) 102.29,28.74 88.82,28.74 87.93,29.62 v2(82.74,29.62)
  BOTTOM w0.102: v2(82.74,29.62) 82.56,29.8 82.56,36.11 80.17,38.51 73.68,38.51 71.49,40.7 R593.1 ; U28.29 102.8,29.01 v2(102.68,29.13)
LAN_VDDEN_SOC: length 182.9
  TOP w0.114: v2(101.15,100.14) 101.32,100.31 101.32,100.86 99.2,102.98 94.12,102.98 92.47,101.34 92.47,100.05 92.34,99.92 92.34,98.76 92.24,98.67 92.24,98.16 U1.M2
  LAY3 w0.127: v2(101.15,100.14) 105.49,100.14 106.36,101.01 109.59,101.01 110.03,100.57 110.03,100.05 112.34,97.74 117.88,97.74 121,94.61 123.01,94.61 127.97,89.65 127.97,75.78 134.74,69.01 134.74,65.93 135.89,64.78 135.89,51.97 132.81,48.9 132.81,40.19 131.01,38.39 131.01,36.24 122.97,28.2 115.92,28.2 114.3,26.57 109.68,26.57 108.41,27.84 103.49,27.84 102.49,26.84 v2(84.5,26.84)
  BOTTOM w0.114: v2(84.5,26.84) 82.33,29.01 82.33,36.01 80.07,38.27 73.35,38.27 70.72,40.9 R208.1
LANWAKEB: length 3.5
  BOTTOM w0.102: U17.28 52.47,39.58 52.06,39.17 R216.1
LAO_CLKN: length 50
  TOP w0.101: CN16.18 27.99,132.48 27.89,132.38 27.7,132.38 27.6,132.28 27.6,131.65 v2(27.79,131.46) ; R615.1 v2(50.18,122.45)
  LAY3 w0.101: v2(27.79,131.46) 27.58,131.24 27.58,129.72 28.14,129.16 29.38,129.16 29.48,129.26 29.48,129.8 29.7,130.02 30.07,130.02 30.29,129.8 30.29,129.26 30.39,129.16 30.6,129.16 30.7,129.26 30.7,129.82 30.93,130.05 31.3,130.05 31.51,129.83 31.51,129.26 31.61,129.16 33.52,129.16 39.22,123.46 42.93,123.46 43.19,123.72 47.83,123.72 48.4,123.16 48.4,122.55 48.5,122.45 v2(50.18,122.45)
  BOTTOM w0.101: U10.47 56.83,120.93 56.74,121.02 56.74,122.49 56.49,122.74 56.01,122.74 55.76,122.5 55.76,122.19 55.64,122.06 54.51,122.06 53.97,121.53 50.41,121.53 50.08,121.85 49.24,121.85 48.97,121.58 48.97,121.37 48.86,121.26 47.49,121.26 47.32,121.42 47.32,121.65 47.42,121.75 48.11,121.75 48.36,121.99 48.36,122.35 48.46,122.45 v2(50.18,122.45)
LAO_CLKP: length 50
  TOP w0.101: R162.1 v2(46.36,122.45) ; CN16.19 26.99,132.48 27.09,132.38 27.28,132.38 27.38,132.28 27.38,131.64 v2(27.19,131.46)
  LAY3 w0.101: v2(46.36,122.45) 48.09,122.45 48.19,122.55 48.19,123.07 47.74,123.52 43.28,123.52 43.02,123.26 39.13,123.26 33.44,128.96 31.53,128.96 31.31,129.18 31.31,129.75 31.21,129.84 31.01,129.84 30.9,129.74 30.9,129.18 30.68,128.96 30.31,128.96 30.09,129.18 30.09,129.72 29.99,129.82 29.79,129.82 29.68,129.72 29.68,129.18 29.46,128.96 28.06,128.96 27.38,129.64 27.38,131.27 v2(27.19,131.46)
  BOTTOM w0.101: U10.46 56.43,120.9 56.52,120.99 56.52,122.4 56.4,122.53 56.1,122.53 55.98,122.41 55.98,122.1 55.73,121.85 54.6,121.85 54.06,121.31 50.32,121.31 49.99,121.63 49.33,121.63 49.19,121.49 49.19,121.28 48.95,121.04 47.4,121.04 47.1,121.33 47.1,121.74 47.33,121.96 48.03,121.96 48.14,122.08 48.14,122.35 48.04,122.45 v2(46.36,122.45)
LAO_DATAN0: length 50.1
  TOP w0.101: CN16.6 39.99,132.48 39.89,132.38 39.6,132.38 39.48,132.27 39.48,131.39 v2(39.75,131.13) ; R607.1 v2(62,127.02)
  LAY3 w0.101: v2(62,127.02) 60.84,127.02 60.74,127.12 60.74,127.49 59.15,129.08 58.83,129.08 58.2,128.45 58.03,128.45 56.98,129.5 56.98,129.65 57.12,129.79 57.26,129.79 57.94,129.11 58.28,129.11 58.55,129.37 58.55,129.68 56.48,131.75 54.83,131.75 54.61,131.53 54.61,130.63 54.51,130.53 53.4,130.53 53.3,130.63 53.3,130.83 53.4,130.93 53.98,130.93 54.2,131.15 54.2,131.53 53.98,131.75 41.43,131.75 40.13,130.45 39.72,130.45 39.55,130.62 39.55,130.93 v2(39.75,131.13)
  BOTTOM w0.101: U10.54 59.63,121 59.94,121.32 61.31,121.32 62.63,122.64 62.63,124.32 62.41,124.55 60.85,124.55 60.75,124.65 60.75,125.48 60.52,125.71 59.93,125.71 59.83,125.81 59.83,126.02 59.93,126.12 60.6,126.12 60.85,126.37 60.85,126.91 60.96,127.02 v2(62,127.02)
LAO_DATAN1: length 49.8
  TOP w0.101: v2(36.79,131.66) 36.6,131.85 36.6,132.22 36.99,132.6 CN16.9 ; R609.1 v2(58.29,127.02)
  LAY3 w0.101: v2(58.29,127.02) 57.14,127.02 57.04,127.12 57.04,127.7 55.83,128.91 55.22,128.91 55.11,129.02 55.11,129.6 54.89,129.82 54.52,129.82 54.3,129.6 54.3,129.02 54.2,128.91 54,128.91 53.9,129.02 53.9,129.6 53.68,129.82 53.31,129.82 53.09,129.6 53.09,129.02 52.98,128.91 52.78,128.91 52.68,129.02 52.68,129.6 52.46,129.82 52.09,129.82 51.87,129.6 51.87,129.02 51.77,128.91 51.29,128.91 49.66,130.54 47.09,130.54 46.15,129.6 38.16,129.6 36.54,131.23 36.54,131.41 v2(36.79,131.66)
  BOTTOM w0.101: v2(58.29,127.02) 57.14,127.02 57.04,126.92 57.04,126.43 57.14,126.33 58.92,126.33 59.13,126.12 59.13,125.74 58.89,125.5 56.76,125.5 56.04,126.22 55.84,126.22 55.69,126.07 55.69,125.91 56.21,125.39 56.21,125.13 56.35,124.99 57.77,124.99 58.17,124.58 58.17,124.11 58.96,123.33 58.96,122.97 59.08,122.85 59.82,122.85 60.05,122.63 60.05,122.24 59.82,122.02 59.08,122.02 58.97,121.92 58.97,121.68 58.73,121.43 58.73,121.06 58.83,120.95 U10.52
LAO_DATAN2: length 50
  TOP w0.101: CN16.12 33.99,132.48 33.89,132.38 33.7,132.38 33.6,132.28 33.6,131.85 v2(33.79,131.65) ; R611.1 v2(55.72,123.48)
  LAY3 w0.101: v2(55.72,123.48) 54.41,123.48 54.31,123.58 54.31,125.61 52.58,127.34 49.3,127.34 48.77,127.87 45.56,127.87 45.34,127.65 45.34,127.39 45.24,127.29 45.04,127.29 44.94,127.39 44.94,127.65 44.72,127.87 44.35,127.87 44.13,127.65 44.13,127.39 44.03,127.29 43.82,127.29 43.72,127.39 43.72,127.65 43.5,127.87 36.89,127.87 33.54,131.22 33.54,131.41 v2(33.79,131.65)
  BOTTOM w0.101: U10.49 57.61,120.52 57.61,121.25 57.44,121.42 57.44,123.81 56.96,124.29 54.79,124.29 54.67,124.41 54.67,124.57 54.44,124.79 54.06,124.79 53.84,124.57 53.84,124.35 53.75,124.26 51.66,124.26 50.93,123.53 50.93,122.92 51.29,122.56 51.52,122.56 51.62,122.46 51.62,122.26 51.87,122.01 52.2,122.01 52.46,122.26 52.46,122.46 52.56,122.56 52.76,122.56 52.86,122.46 52.86,122.24 53.1,122.01 53.48,122.01 53.7,122.23 53.7,122.46 53.8,122.56 54.72,122.56 54.98,122.82 54.98,123.33 55.13,123.48 v2(55.72,123.48)
LAO_DATAN3: length 50
  TOP w0.101: v2(30.79,131.54) 30.6,131.73 30.6,132.29 30.7,132.38 30.89,132.38 30.99,132.48 CN16.15 ; R613.1 v2(52.82,125.09)
  LAY3 w0.101: v2(30.79,131.54) 30.59,131.33 30.59,131.01 30.87,130.73 33.04,130.73 36.79,126.98 42.34,126.98 42.72,126.6 50.63,126.6 51.41,125.82 51.41,125.19 51.51,125.09 v2(52.82,125.09)
  BOTTOM w0.101: U10.44 55.63,120.76 55.53,120.86 55.53,121.1 55.27,121.36 54.8,121.36 54.26,120.83 51.28,120.83 50.82,120.37 46.14,120.37 45.78,120.73 45.78,123.35 46.25,123.82 50.53,123.82 51.42,124.7 51.42,124.99 51.52,125.09 v2(52.82,125.09)
LAO_DATAP0: length 50.1
  TOP w0.101: v2(39.15,131.13) 39.27,131.25 39.27,132.37 38.99,132.65 CN16.7 ; R608.1 v2(59.27,127.02)
  LAY3 w0.101: v2(59.27,127.02) 60.43,127.02 60.54,127.12 60.54,127.41 59.06,128.88 58.92,128.88 58.28,128.25 57.94,128.25 56.78,129.41 56.78,129.73 57.04,129.99 57.35,129.99 58.03,129.31 58.2,129.31 58.34,129.45 58.34,129.6 56.4,131.54 54.91,131.54 54.81,131.44 54.81,130.55 54.59,130.33 53.32,130.33 53.1,130.55 53.1,130.92 53.32,131.14 53.9,131.14 54,131.24 54,131.44 53.9,131.54 41.51,131.54 40.22,130.25 39.64,130.25 39.35,130.54 39.35,130.93 v2(39.15,131.13)
  BOTTOM w0.101: U10.53 59.23,120.91 59.85,121.53 61.22,121.53 62.42,122.73 62.42,124.23 62.32,124.33 60.76,124.33 60.53,124.56 60.53,125.4 60.43,125.5 59.84,125.5 59.61,125.72 59.61,126.11 59.84,126.33 60.51,126.33 60.64,126.46 60.64,126.91 60.53,127.02 v2(59.27,127.02)
LAO_DATAP1: length 49.8
  TOP w0.101: v2(36.19,131.66) 36.38,131.85 36.38,132.21 35.99,132.6 CN16.10 ; R610.1 v2(55.58,127.02)
  LAY3 w0.101: v2(36.19,131.66) 36.34,131.51 36.34,131.14 38.08,129.4 46.24,129.4 47.17,130.33 49.58,130.33 51.2,128.71 51.85,128.71 52.07,128.93 52.07,129.51 52.17,129.61 52.38,129.61 52.48,129.51 52.48,128.93 52.7,128.71 53.07,128.71 53.29,128.93 53.29,129.51 53.39,129.61 53.59,129.61 53.69,129.51 53.69,128.93 53.91,128.71 54.29,128.71 54.51,128.93 54.51,129.51 54.61,129.61 54.81,129.61 54.91,129.51 54.91,128.93 55.13,128.71 55.74,128.71 56.83,127.62 56.83,127.12 56.73,127.02 v2(55.58,127.02)
  BOTTOM w0.101: v2(55.58,127.02) 56.73,127.02 56.83,126.92 56.83,126.35 57.06,126.12 58.83,126.12 58.91,126.03 58.91,125.83 58.8,125.71 56.85,125.71 56.13,126.43 55.75,126.43 55.48,126.16 55.48,125.82 55.99,125.3 55.99,125.04 56.26,124.78 57.68,124.78 57.96,124.49 57.96,124.02 58.75,123.24 58.75,122.88 58.99,122.64 59.73,122.64 59.83,122.54 59.83,122.33 59.73,122.23 58.99,122.23 58.76,122.01 58.76,121.77 58.51,121.52 58.51,121.04 58.43,120.96 U10.51
LAO_DATAP2: length 50
  TOP w0.101: CN16.13 32.99,132.48 33.09,132.38 33.28,132.38 33.38,132.28 33.38,131.85 v2(33.19,131.65) ; R612.1 v2(52.69,123.48)
  LAY3 w0.101: v2(33.19,131.65) 33.34,131.5 33.34,131.13 36.8,127.67 43.42,127.67 43.52,127.57 43.52,127.31 43.74,127.09 44.11,127.09 44.33,127.31 44.33,127.57 44.43,127.67 44.63,127.67 44.74,127.57 44.74,127.31 44.96,127.09 45.33,127.09 45.55,127.31 45.55,127.57 45.65,127.67 48.69,127.67 49.22,127.14 52.49,127.14 54.1,125.53 54.1,123.58 54,123.48 v2(52.69,123.48)
  BOTTOM w0.101: v2(52.69,123.48) 54.61,123.48 54.77,123.33 54.77,122.91 54.63,122.78 53.71,122.78 53.48,122.55 53.48,122.32 53.39,122.22 53.18,122.22 53.08,122.33 53.08,122.55 52.85,122.78 52.47,122.78 52.24,122.55 52.24,122.35 52.11,122.22 51.96,122.22 51.83,122.35 51.83,122.55 51.61,122.78 51.38,122.78 51.15,123.01 51.15,123.44 51.75,124.04 53.84,124.04 54.05,124.26 54.05,124.48 54.15,124.58 54.36,124.58 54.46,124.48 54.46,124.32 54.7,124.08 56.87,124.08 57.22,123.72 57.22,121.33 57.39,121.16 57.39,120.98 57.23,120.81 U10.48
LAO_DATAP3: length 50
  TOP w0.101: R614.1 v2(49.8,125.09) ; CN16.16 29.99,132.48 30.09,132.38 30.28,132.38 30.39,132.27 30.39,131.73 v2(30.19,131.54)
  LAY3 w0.101: v2(49.8,125.09) 51.1,125.09 51.21,125.19 51.21,125.74 50.55,126.4 42.64,126.4 42.25,126.78 36.7,126.78 32.95,130.53 30.79,130.53 30.38,130.93 30.38,131.34 v2(30.19,131.54)
  BOTTOM w0.101: U10.43 55.23,120.76 55.32,120.85 55.32,121.01 55.18,121.15 54.89,121.15 54.35,120.61 51.37,120.61 50.91,120.15 46.05,120.15 45.56,120.64 45.56,123.44 46.16,124.03 50.44,124.03 51.2,124.79 51.2,124.99 51.1,125.09 v2(49.8,125.09)
LDO2-CAP: length 5.3
  BOTTOM w0.203: C246.2 133.9,13.03 133.23,13.7 133.23,14.43 132.99,14.67 131.44,14.67 130.89,15.21 U23.39
LED_ON: length 253.2
  TOP w0.102: CN18.2 68.17,132.24 v2(68.03,132.11)
  LAY3 w0.102: v2(12.71,76.47) 12.9,76.28 v2(33.28,76.28)
  LAY4 w0.102: v2(33.28,76.28) 34.85,74.71 34.85,38.72 44.38,29.2 49.54,29.2 52.24,31.89 54.99,31.89 55.43,32.32 61.94,32.32 62.8,33.18 66.72,33.18 67.96,34.42 81.94,34.42 85.26,31.1 97.12,31.1 102.19,26.03 v2(102.19,24.93) ; v2(68.03,132.11) 67.57,131.65 66.31,131.65 63.73,134.23 24.55,134.23 22.4,132.08 17.42,132.08 8.96,123.62 8.96,84.9 12.71,81.14 v2(12.71,76.47)
  BOTTOM w0.102: U28.34 101.88,25.24 v2(102.19,24.93)
LHF: length 2.1
  TOP w0.102: R163.1 13.98,14.11 14.19,13.89 CN13.4
LL1: length 4.5
  TOP w0.635: v1(23.27,89.56) 23.27,91.29
  BOTTOM w0.305: U42.20 24.03,89.14 23.61,89.56 v1(23.27,89.56) 23.26,89.55
  BOTTOM w0.406: 23.26,89.55 23.26,90.04 23.69,90.48 C369.2
LL2: length 4.8
  TOP w0.635: v1(23.55,83.81) 23.55,82.79 24.86,81.48
  BOTTOM w0.254: v1(23.55,83.81) 24.03,84.29 U42.11
  BOTTOM w0.406: C370.1 23.55,83.09 v1(23.55,83.81)
LPC_AD0: length 143.9
  TOP w0.089: 71.49,90.86 71.56,90.79 73.59,90.79 73.68,90.89 73.69,90.89 73.7,90.89 U1.BH16
  TOP w0.114: v2(70.62,92.78) 70.62,91.73 71.1,91.25 71.49,90.86
  LAY3 w0.127: v2(117.47,35.5) 116.32,36.65 115.03,36.65 110.94,40.73 89.16,40.73 85.05,44.85 70.42,44.85 68.17,47.1 61.54,47.1 60.75,47.89 59.95,47.89 56.54,51.3 56.54,56.99 60.34,60.79 60.34,61.94 61.57,63.17 61.57,68.57 63.97,70.97 63.97,78.74 64.43,79.2 64.43,80.67 60.96,84.14 60.96,87.23 60.33,87.85 60.33,90.36 62.3,92.33 70.18,92.33 v2(70.62,92.78)
  BOTTOM w0.114: U28.10 104.77,36.61 105.33,37.17 112.17,37.17 112.93,36.41 112.93,35.46 113.61,34.78 116.16,34.78 CN14.8 116.78,34.7 117.47,35.39 v2(117.47,35.5)
LPC_AD1: length 140.7
  TOP w0.089: U1.BJ17 71.15,90.41 71.1,90.45
  TOP w0.114: 71.1,90.45 69.69,91.87 v2(69.69,93.72)
  LAY3 w0.127: v2(113.44,35.79) 113.44,36.16 109.4,40.19 88.95,40.19 84.8,44.34 70.21,44.34 67.95,46.6 62.41,46.6 62,46.19 60.71,46.19 55.25,51.65 55.25,56.43 59.73,60.91 59.73,62.51 60.83,63.61 60.83,68.61 63.19,70.98 63.19,81.15 60.37,83.97 60.37,87.1 59.83,87.64 59.83,90.57 62.78,93.53 69.5,93.53 v2(69.69,93.72)
  BOTTOM w0.114: U28.9 104.82,37.01 105.23,37.41 112.29,37.41 113.44,36.27 113.44,35.92 113.44,35.91 v2(113.44,35.79) 114.02,35.2 CN14.7
LPC_AD2: length 136.9
  TOP w0.089: 72.77,92.35 U1.BJ13
  TOP w0.102: 71.13,92.99 71.77,92.35 72.77,92.35
  TOP w0.114: 71.13,92.99 69.94,94.18 v2(69.22,94.18)
  LAY3 w0.127: v2(111.2,37.83) 109.14,39.89 88.79,39.89 84.61,44.07 70.11,44.07 67.84,46.34 62.56,46.34 62.15,45.94 59.46,45.94 54.98,50.42 54.98,56.52 59.38,60.92 59.38,65.8 60.36,66.78 60.36,68.5 62.89,71.03 62.89,81.06 60.06,83.9 60.06,87.05 59.57,87.54 59.57,90.68 62.68,93.79 68.83,93.79 v2(69.22,94.18)
  BOTTOM w0.114: 111.2,37.86 111,37.66 105.13,37.66 104.88,37.41 U28.8 ; 111.2,37.86 v2(111.2,37.83) ; 111.2,37.86 112.38,37.86 114.54,35.7 CN14.6
LPC_AD3: length 141.7
  TOP w0.089: U1.BG14 74.73,91.87 74.44,92.17 74.19,92.17 74.09,92.07 73.75,92.07 73.64,92.17 72.83,92.17 72.78,92.12
  TOP w0.102: 72.78,92.12 72.15,92.12 71.87,91.85 v2(71.56,91.85)
  LAY3 w0.127: v2(118.12,35.47) 116.56,37.03 115.23,37.03 111.28,40.99 90.33,40.99 85.95,45.37 70.62,45.37 68.06,47.93 61.62,47.93 57.47,52.08 57.47,57.21 61.25,60.98 61.25,62.13 62.27,63.16 62.27,68.42 64.93,71.08 64.93,77.08 65.38,77.52 65.38,80.52 61.5,84.4 61.5,87.4 60.84,88.06 60.84,90.15 62.5,91.81 71.52,91.81 v2(71.56,91.85)
  BOTTOM w0.114: v2(118.12,35.47) 117.4,36.2 CN14.5 114.41,36.2 112.37,38.24 110.67,38.24 110.37,37.95 105.08,37.95 104.94,37.81 U28.7
LPC_CLK_EC: length 140.5
  LAY3 w0.127: v2(66.54,90.87) 66.54,88.93 70.26,85.2 72.64,85.2 73.81,84.03 73.81,82.75 71.52,80.46 71.52,76.41 71.29,76.19 71.29,67.38 67.55,63.64 67.55,61.33 66.89,60.67 66.89,53.78 67.39,53.28 68.11,53.28 68.95,52.44 68.95,51.2 70.56,49.59 78.08,49.59 78.51,49.16 99.54,49.16 101.19,47.51 102.37,47.51 103.26,48.4 111.31,48.4 117.19,42.53 123.08,42.53 123.75,41.87 123.75,38.66 119.9,34.81 118.21,34.81 v2(118.02,34.62) 117.69,34.29 117.05,34.29 115.93,35.41 113.72,35.41 113.35,35.05 106.68,35.05 105.58,36.14 103.35,36.14 v2(102.72,35.52)
  BOTTOM w0.114: CN14.10 117.11,33.7 v2(118.02,34.62) ; v2(102.72,35.52) 102.83,35.41 U28.13 ; v2(66.54,90.87) R101.1 66.54,93.18 R102.1
LPC_CLKRUN#: length 97.2
  TOP w0.089: 71.59,91.1 71.71,90.98 73.51,90.98 73.61,91.08 73.61,91.08 73.62,91.09 74.08,91.09 74.19,91.19 74.44,91.19 74.73,90.89 U1.BG16
  TOP w0.114: v2(71.09,92.32) 71.09,91.6 71.59,91.1
  LAY3 w0.127: v2(87.36,43.33) 85.59,45.1 70.53,45.1 68.18,47.45 61.74,47.45 57.03,52.16 57.03,57.12 60.79,60.88 60.79,62.03 61.89,63.13 61.89,68.5 64.37,70.99 64.37,77.16 65,77.79 65,80.49 61.24,84.25 61.24,87.3 60.59,87.96 60.59,90.26 62.41,92.08 70.86,92.08 v2(71.09,92.32)
  BOTTOM w0.114: R307.2 87.36,40.32 v2(87.36,43.33)
LPC_FRAME#: length 140.3
  TOP w0.089: U1.BG17 74.48,90.6 74.19,90.6 74.07,90.72 73.78,90.72 73.66,90.6 71.37,90.6 71.3,90.66
  TOP w0.114: v2(70.16,93.25) 70.16,91.81 71.1,90.86 71.3,90.66
  LAY3 w0.127: v2(70.16,93.25) 68.47,93.25 68.06,92.84 62.45,92.84 60.08,90.47 60.08,87.75 60.65,87.18 60.65,84.08 64.05,80.68 64.05,79.31 63.56,78.82 63.56,70.95 61.23,68.61 61.23,63.65 60.05,62.47 60.05,60.87 55.52,56.34 55.52,51.74 60.82,46.45 61.9,46.45 62.3,46.85 68.06,46.85 70.32,44.59 84.91,44.59 89.04,40.47 109.73,40.47 v2(111.44,38.76) 114.27,35.93 116.13,35.93 v2(117.38,34.68)
  BOTTOM w0.114: v2(111.44,38.76) 110.84,38.76 110.3,38.21 U28.6 ; CN14.9 116.9,34.2 v2(117.38,34.68)
LPC_SERIRQ: length 180.1
  TOP w0.089: 72.82,92.58 72.94,92.58 72.98,92.54 73.67,92.54 73.76,92.64 73.77,92.64 73.78,92.65 74.08,92.65 74.19,92.54 74.48,92.54 U1.BG13
  TOP w0.102: 71.2,93.45 72.07,92.58 72.82,92.58
  TOP w0.114: v2(68.76,94.65) 70,94.65 71.2,93.45
  LAY4 w0.127: v2(68.76,94.65) 68.61,94.8 67.64,94.8 66.65,93.81 52.19,93.81 48.6,90.22 48.6,70.26 46.87,68.52 46.87,57.74 48.95,55.65 48.95,47.04 54.39,41.61 65.16,41.61 65.79,40.98 85.16,40.98 88.52,37.62 97.74,37.62 100.5,34.85 103.14,34.85 104.19,35.9 105.27,35.9 106.36,34.81 113.6,34.81 113.86,35.06 115.75,35.06 116.82,34 118.68,34 v2(118.92,34.24)
  BOTTOM w0.114: 107.05,20.52 107.05,20.39 ; 107.05,20.52 107.05,20.52 ; 107.05,20.52 106.92,20.39 ; 107.05,20.39 107.06,20.38 107.19,20.38 ; 107.05,20.39 106.92,20.39 ; v2(118.92,34.24) 118.93,34.24 118.93,30.29 116.91,28.28 115.76,28.28 114.82,27.34 114.82,26.88 113.1,25.17 113.1,23 110.49,20.38 107.19,20.38 ; 107.19,20.38 107.05,20.52 ; 106.92,20.39 106.74,20.21 104.16,20.21 102.31,22.06 102.31,22.48 R648.1 ; 107.05,20.52 U26.2
LPC_SERIRQ_EC: length 52.9
  LAY3 w0.127: v2(118.73,35.48) 116.87,37.34 115.77,37.34 v2(114.45,38.65)
  LAY4 w0.127: v2(121.09,26.36) 119.07,24.33 v2(107.43,24.33)
  BOTTOM w0.114: v2(121.09,26.36) 120.53,26.91 120.53,28.81 119.41,29.94 119.41,34.8 v2(118.73,35.48) 118.48,35.22 118.48,34.22 116.96,32.7 CN14.12 ; U26.10 107.05,23.95 v2(107.43,24.33) 106.52,25.24 103.72,25.24 102.31,23.84 102.31,23.44 R648.2 ; v2(114.45,38.65) 113.94,39.17 110.91,39.17 110.35,38.61 U28.5
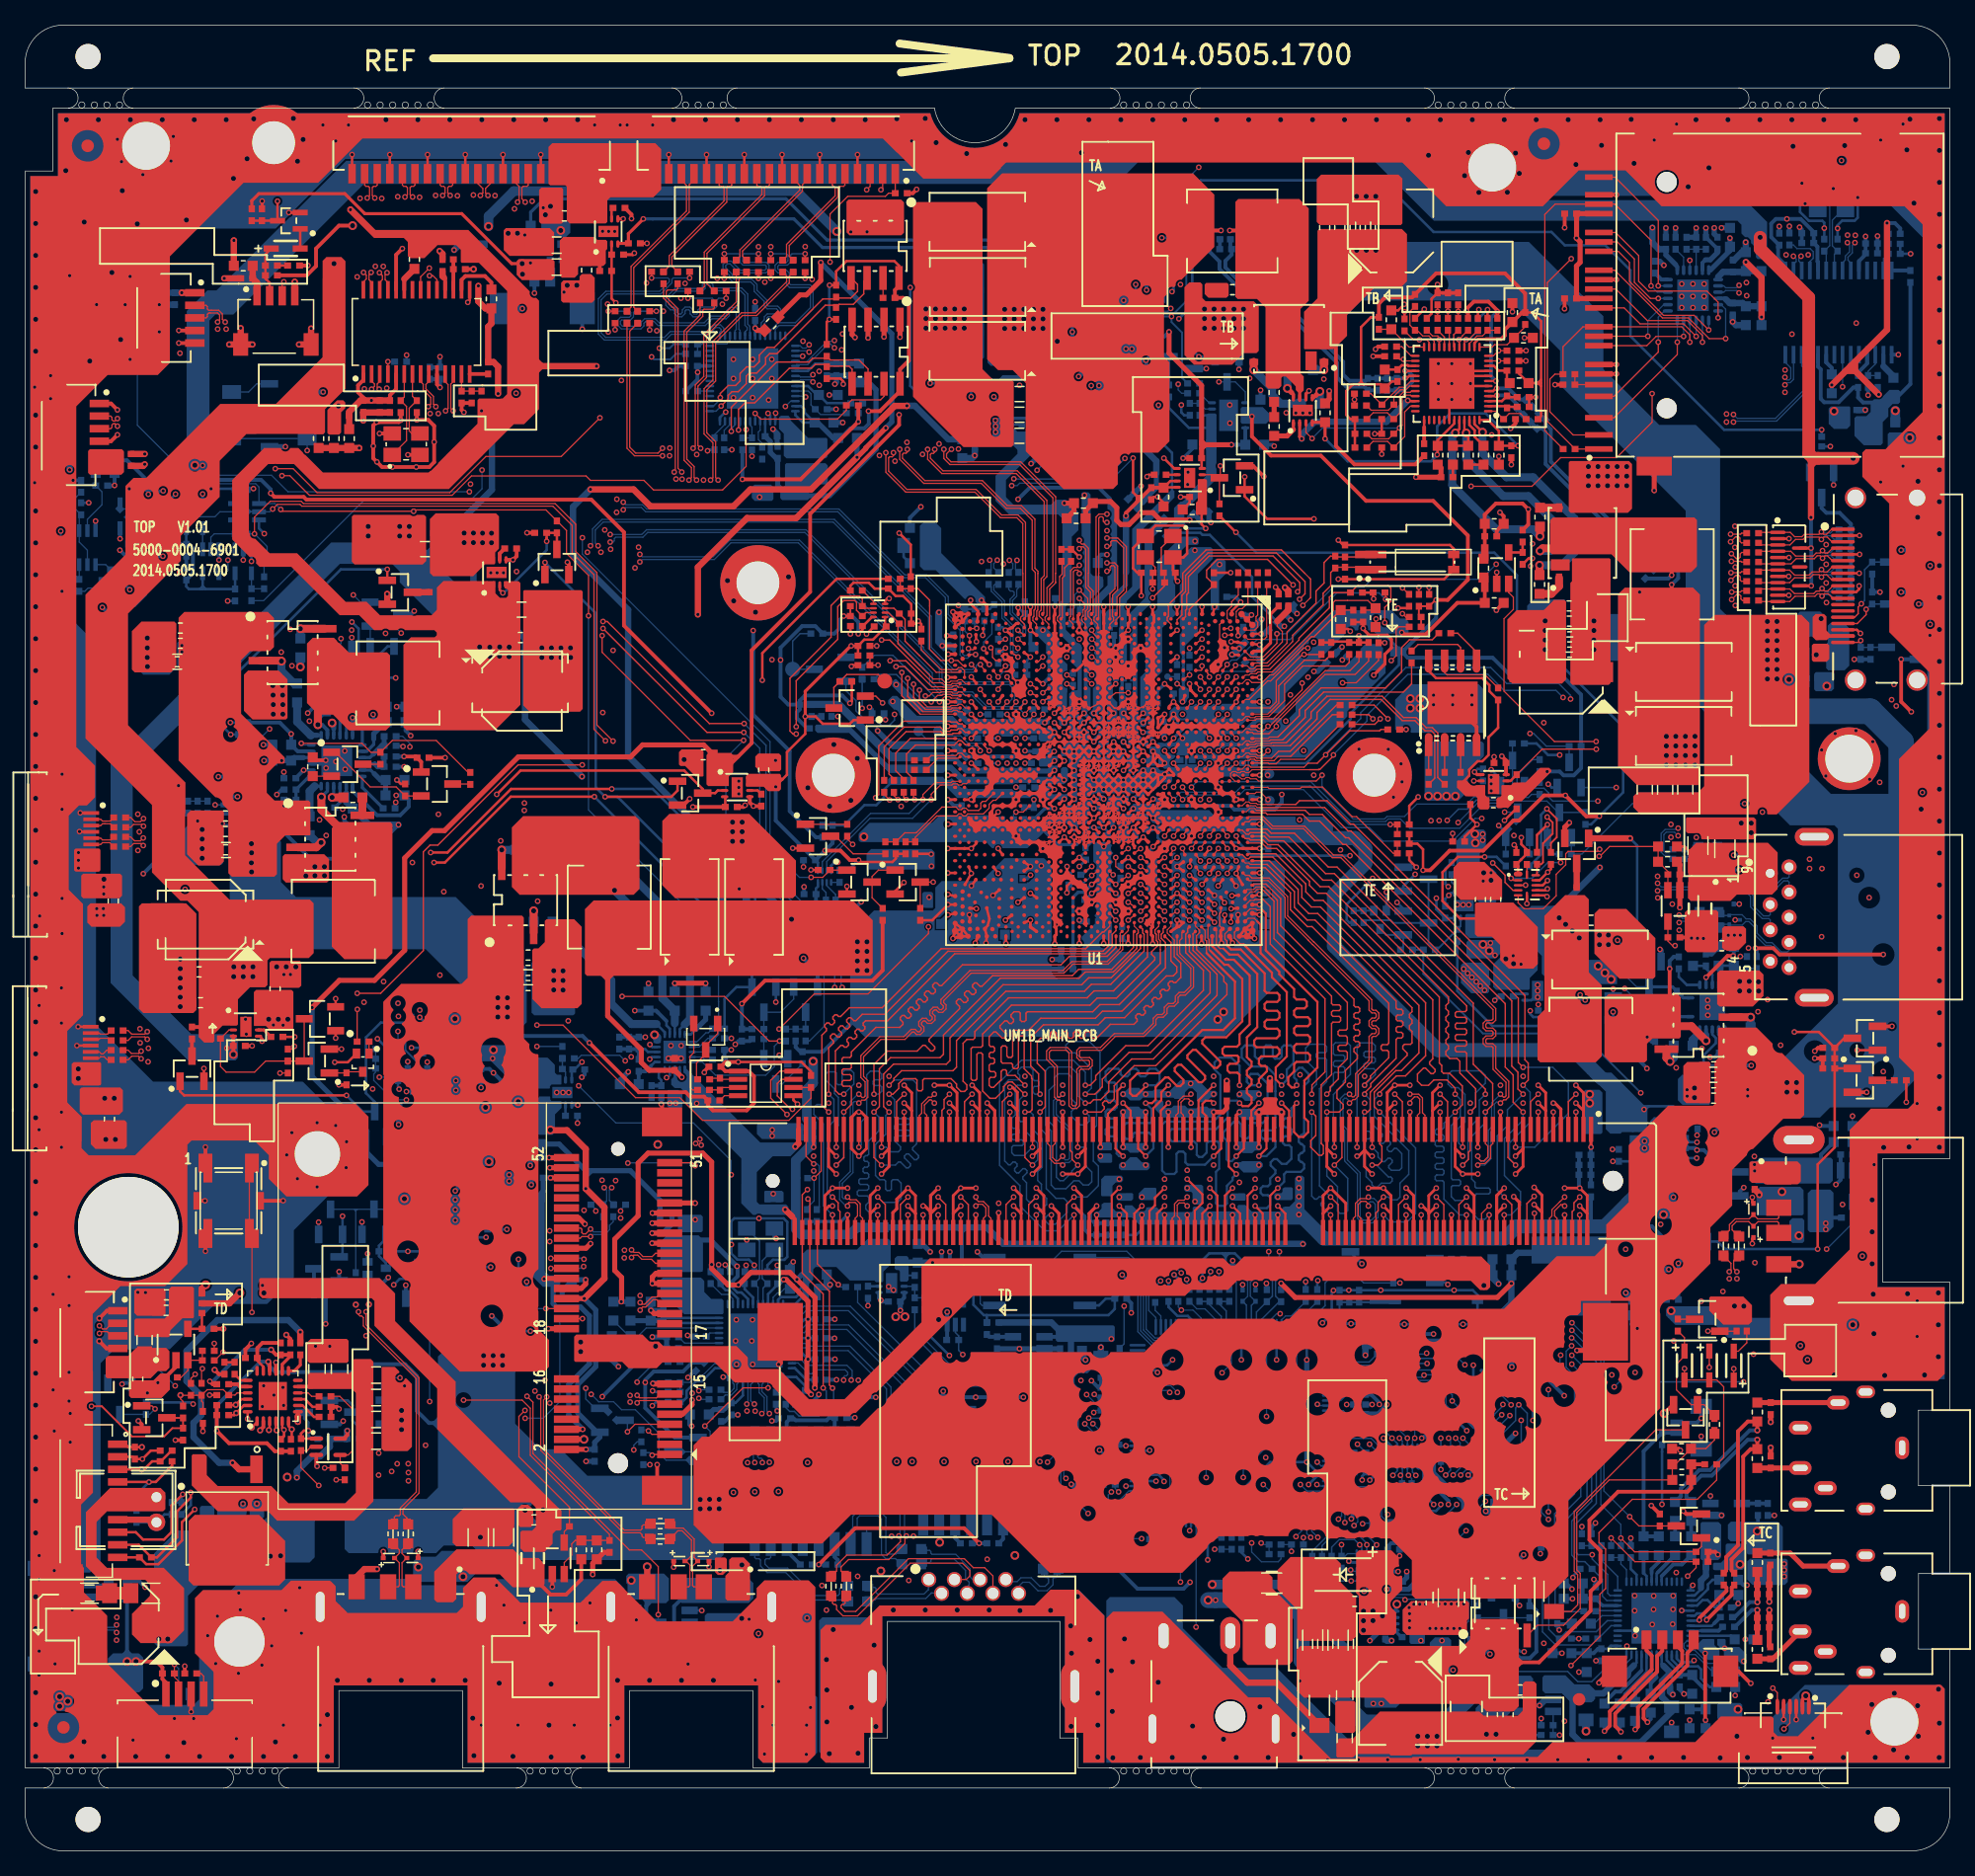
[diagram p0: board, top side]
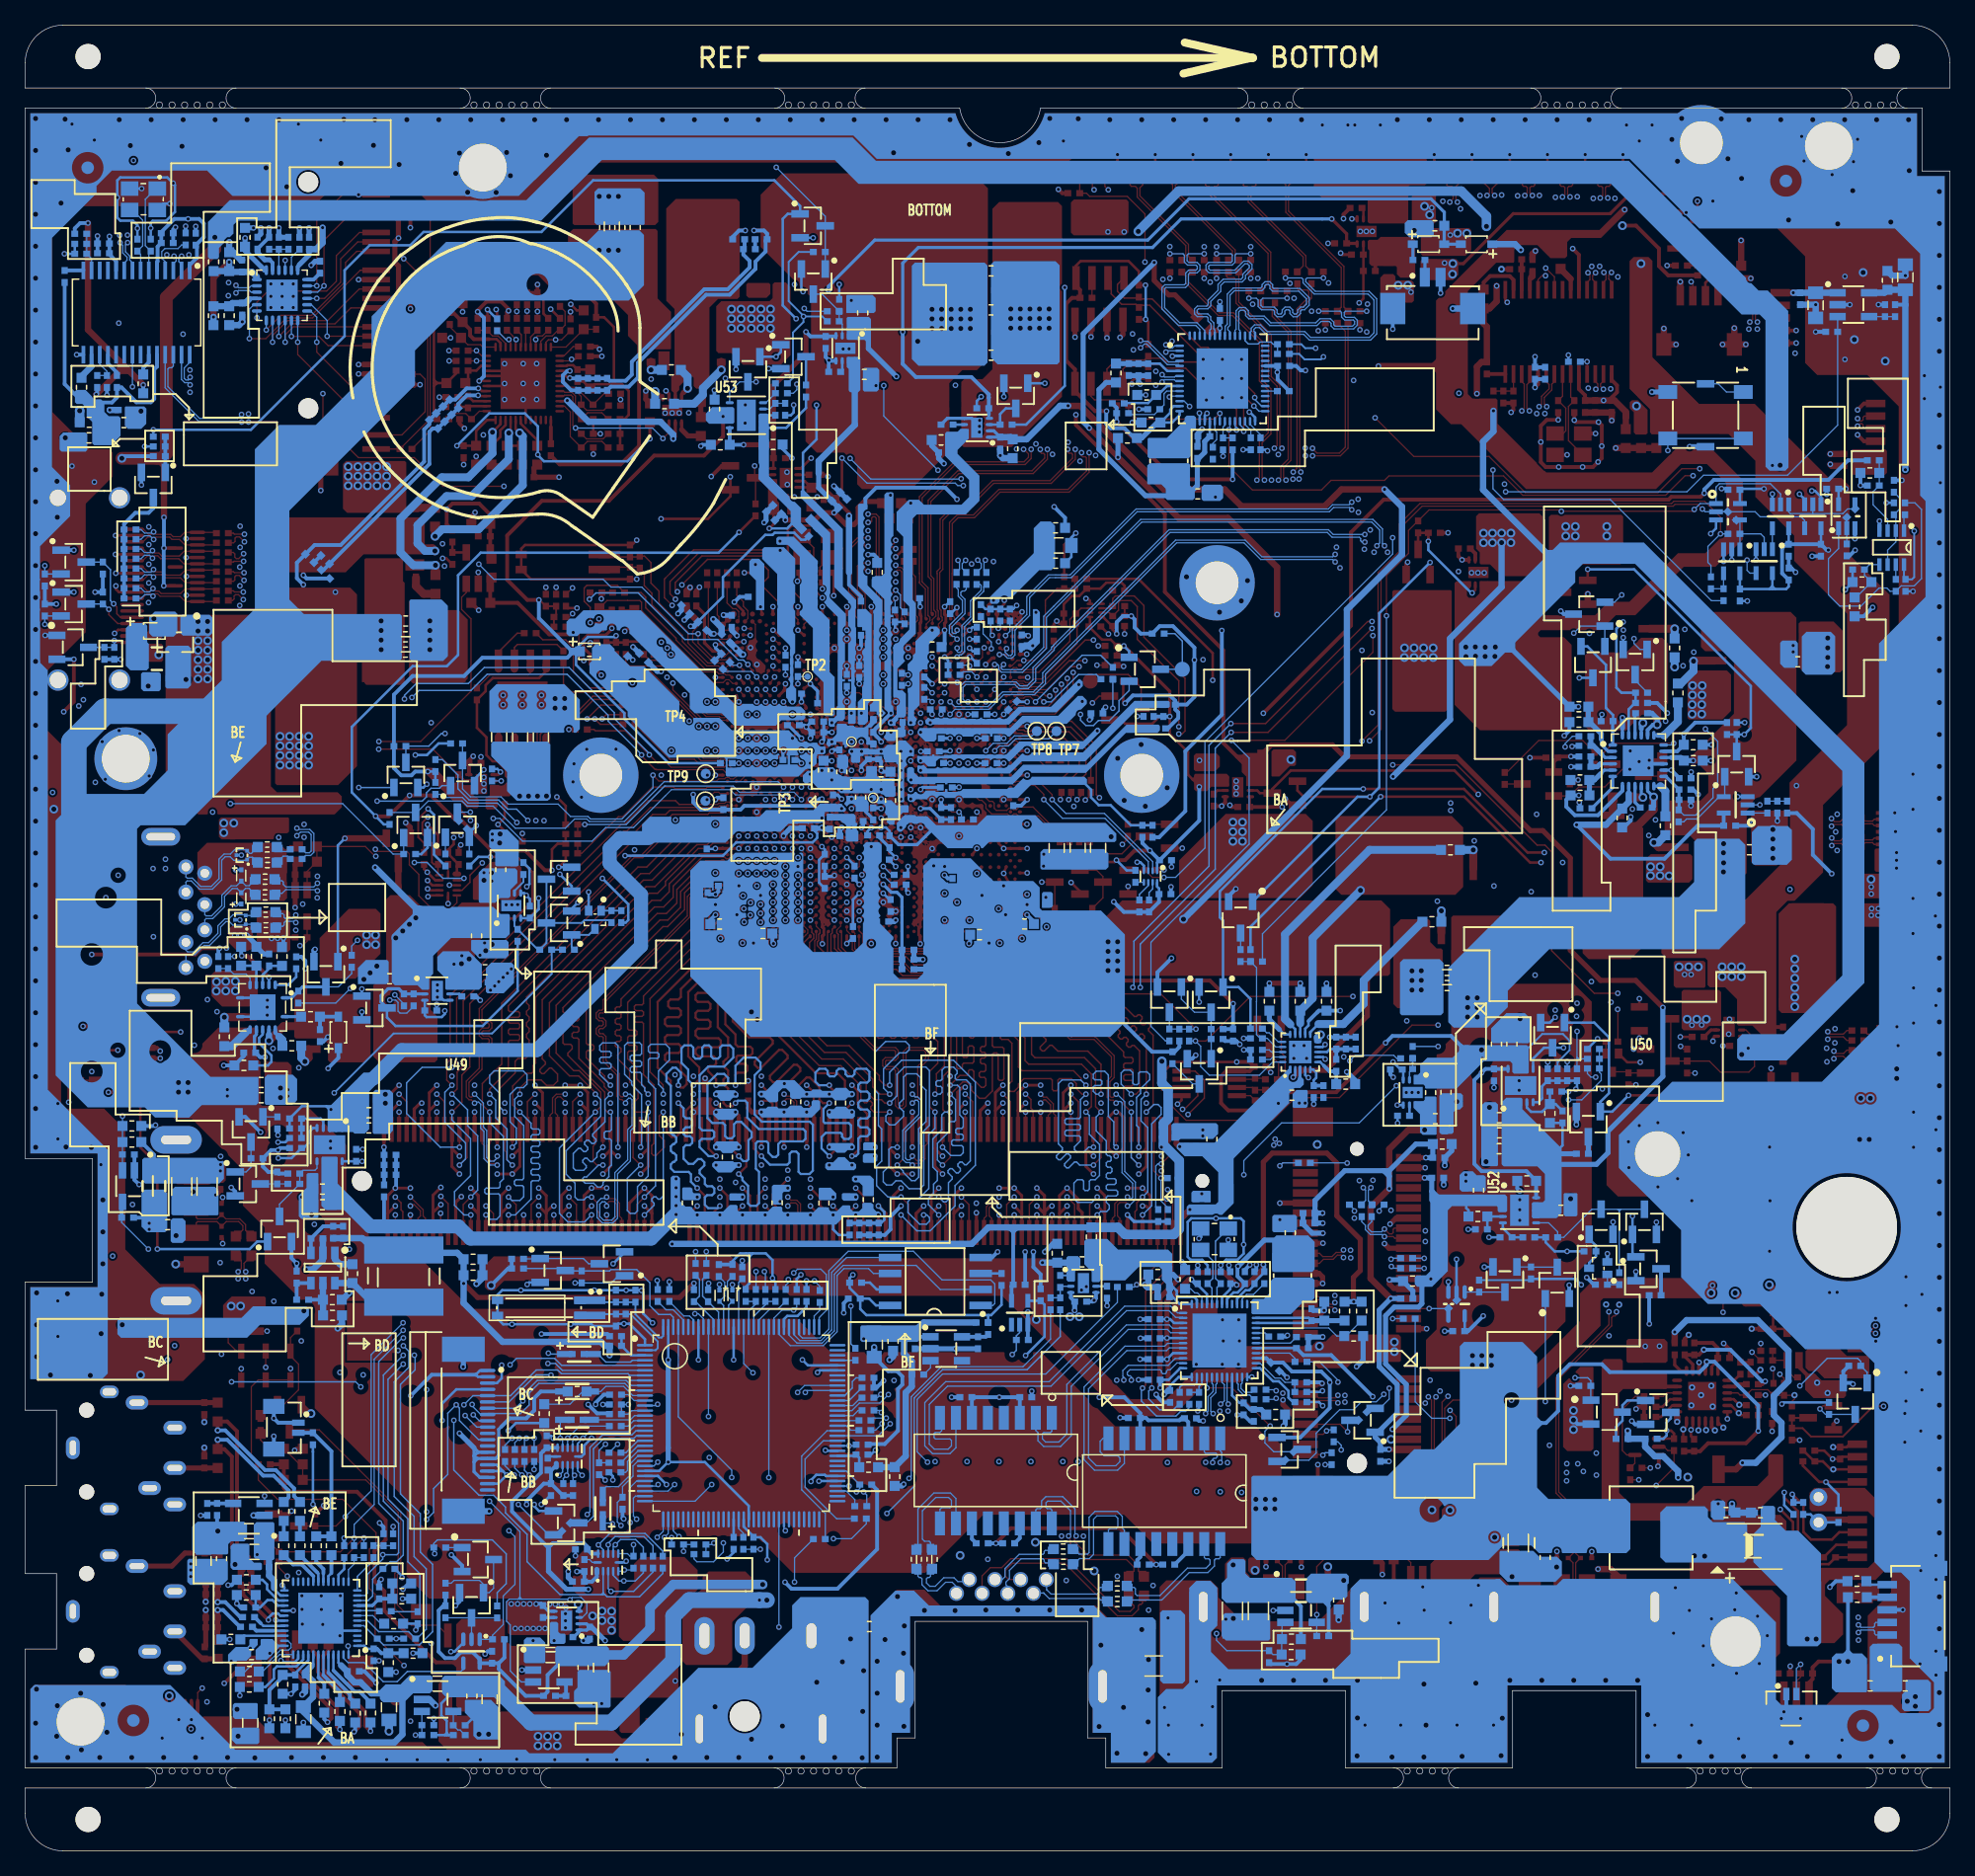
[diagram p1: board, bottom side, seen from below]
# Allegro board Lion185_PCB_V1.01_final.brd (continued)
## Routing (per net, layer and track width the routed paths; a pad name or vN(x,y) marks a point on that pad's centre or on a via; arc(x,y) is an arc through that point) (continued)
LPCPD#: length 13.9
  LAY4 w0.127: v2(114.29,32.82) 113.28,31.81 109.67,31.81 v2(108.65,32.82)
  BOTTOM w0.114: U28.17 104.53,33.81 105.01,33.33 108.14,33.33 v2(108.65,32.82) 108.98,32.49 108.98,32.49 109.08,32.39 U27.7 ; R656.2 114.86,32.26 v2(114.29,32.82)
M_A_A0: length 39.7
  TOP w0.178: v2(92.38,53.42) 93.58,52.21 93.58,51.53 92.98,50.92 CN3.98 ; v2(93.55,76.15) U1.K45
  LAY3 w0.089: 93.95,71.83 93.95,75.75 v2(93.55,76.15)
  LAY3 w0.203: v2(92.38,53.42) 92.67,53.13 93.06,53.13 93.39,53.46 93.39,54.3 93.08,54.61 92.81,54.61 92.6,54.81 92.6,55.21 92.81,55.42 93.08,55.42 93.39,55.72 93.39,56.92 93.18,57.12 92.81,57.12 92.61,57.32 92.61,57.73 92.81,57.93 93.18,57.93 93.39,58.13 93.39,61.15 93.07,61.47 90.57,61.47 90.42,61.32 90.42,60.62 90.19,60.39 89.74,60.39 89.51,60.63 89.51,61.15 88.78,61.88 88.78,62.95 93.93,68.09 93.93,68.12 93.95,68.15 93.95,71.83
M_A_A1: length 41.8
  TOP w0.178: v2(94.48,60.89) 93.28,59.69 CN3.97 ; U1.H47 v2(94.54,75.28)
  LAY4 w0.102: v2(94.54,75.28) 94.95,74.87 94.95,73.94 95.46,73.44 96.02,73.44 96.2,73.62 96.72,73.62
  LAY4 w0.203: 96.72,73.62 98.07,73.62 101.78,69.9 101.78,65.71 97.08,61.01 97.08,60.4 97.28,60.19 97.44,60.19 97.65,59.99 97.65,59.59 97.44,59.38 97.28,59.38 97.08,59.18 97.08,58.77 97.28,58.57 97.44,58.57 97.65,58.37 97.65,57.96 97.44,57.76 97.28,57.76 97.08,57.56 97.08,56.92 96.74,56.59 94.95,56.59 94.65,56.89 94.65,57.54 94.82,57.71 95.8,57.71 96,57.91 96,58.32 95.8,58.52 95.11,58.52 94.91,58.73 94.91,59.13 95.11,59.33 95.8,59.33 96,59.54 96,59.94 95.8,60.15 95.11,60.15 94.91,60.35 94.91,60.7 94.72,60.89 v2(94.48,60.89)
M_A_A2: length 39.6
  TOP w0.178: U1.L41 v2(92.56,78.29) ; v2(94.18,51.29) 93.58,50.69 CN3.96
  LAY4 w0.102: 96.97,73.24 96.97,73.24 94.63,73.24 94.12,73.74 94.12,76.83 93.66,77.29 93.34,77.29 92.99,77.64 92.99,77.86 v2(92.56,78.29)
  LAY4 w0.203: 96.97,73.24 97.18,73.03 97.92,73.03 100.14,70.8 100.14,64.94 97.24,62.03 94.3,62.03 93.75,61.48 93.75,51.72 v2(94.18,51.29)
M_A_A3: length 41.2
  TOP w0.178: v2(94.48,59.47) 94.29,59.66 93.84,59.66 93.59,59.41 93.59,58.74 93.88,58.45 CN3.95 ; U1.H44 v2(93.55,76.86)
  LAY3 w0.089: 94.56,73.06 94.14,73.48 94.14,73.59 94.14,76.27 v2(93.55,76.86)
  LAY3 w0.203: 94.56,73.06 94.56,70.46 94.77,70.25 95.63,70.25 95.84,70.05 95.84,69.64 95.63,69.44 94.77,69.44 94.56,69.24 94.56,67.87 93.28,66.59 93.28,66.3 94.92,64.67 94.92,64.38 94.63,64.1 94.34,64.1 92.71,65.73 92.42,65.73 92.14,65.44 92.14,65.16 93.65,63.64 93.65,63.35 93.37,63.06 93.08,63.06 91.56,64.58 91.28,64.58 90.99,64.3 90.99,64.01 91.48,63.52 91.48,63.23 91.19,62.95 90.9,62.95 90.41,63.43 90.13,63.43 89.51,62.82 89.51,62.38 89.78,62.11 93.41,62.11 94.01,61.51 94.01,59.93 v2(94.48,59.47)
M_A_A4: length 40.8
  TOP w0.178: U1.H50 v2(94.54,73.85) ; v2(94.18,52.71) 94.78,52.11 CN3.92
  LAY3 w0.102: 95.53,72.45 95.53,72.86 v2(94.54,73.85)
  LAY3 w0.203: 95.53,72.45 95.53,71.12 96.45,70.2 96.45,68.83 96.24,68.63 95.37,68.63 95.17,68.43 95.17,68.02 95.37,67.82 96.24,67.82 96.45,67.61 96.45,64.63 96.24,64.43 95.71,64.43 95.51,64.23 95.51,63.82 95.71,63.62 96.24,63.62 96.45,63.42 96.45,62.77 96.3,62.62 95.67,62.62 95.48,62.81 94.85,62.81 94.56,62.53 94.56,62.16 95.08,61.64 95.08,61.06 95.08,58.32 94.88,58.12 94.2,58.12 93.99,57.91 93.99,57.51 94.2,57.3 94.88,57.3 95.08,57.1 95.08,54.21 94.76,53.88 94.76,50.14 94.54,49.92 93.93,49.92 93.49,50.36 93.49,52.43 93.78,52.71 v2(94.18,52.71)
M_A_A5: length 43.6
  TOP w0.178: U1.G53 94.36,71.96 95.45,70.87 96.09,70.87 97.34,69.62 97.34,65.73 96.54,64.93 96.54,64.16 96.33,63.95 95.36,63.95 95.18,63.78 95.18,63.42 95.36,63.24 96.35,63.24 96.46,63.13 96.46,62.78 96.28,62.6 95.76,62.6 95.58,62.42 95.58,62.06 95.76,61.89 96.37,61.89 96.54,61.72 v2(96.54,60.89) ; CN3.91 95.08,55.85 v2(94.48,55.25)
  BOTTOM w0.178: v2(96.54,60.89) 96.54,62.44 95.89,63.09 94.93,63.09 94.54,62.7 94.54,62.15 95.01,61.68 95.01,58.56 94.44,57.99 90.63,57.99 90.38,57.75 90.38,54.1 90.65,53.83 91.35,53.83 91.52,54.01 91.52,55.43 91.7,55.61 92.06,55.61 92.23,55.43 92.23,54.75 92.41,54.57 93.79,54.57 v2(94.48,55.25)
M_A_A6: length 42.3
  TOP w0.178: CN3.90 95.38,52.11 v2(95.98,52.71) ; U1.H49 v2(94.54,74.56)
  LAY3 w0.102: v2(94.54,74.56) 95.77,73.34
  LAY3 w0.203: 95.77,73.34 96.4,72.71 96.4,71.09 97.06,70.44 97.06,69.55 97.26,69.35 98.17,69.35 98.37,69.14 98.37,68.74 98.17,68.54 97.26,68.54 97.06,68.33 97.06,67.82 97.27,67.6 99.01,67.6 99.21,67.4 99.21,67 99.01,66.79 97.27,66.79 97.07,66.59 97.07,66.18 97.27,65.98 98.95,65.98 99.15,65.78 99.15,65.37 98.95,65.17 97.27,65.17 97.07,64.97 97.07,64.56 97.27,64.36 98.95,64.36 99.15,64.15 99.15,63.75 98.95,63.54 97.27,63.54 97.06,63.33 97.06,62.52 96.11,61.57 96.11,60.8 95.9,60.6 95.9,60.6 95.69,60.4 95.69,59.99 95.9,59.79 95.9,59.79 96.11,59.59 96.11,59.18 95.9,58.98 95.9,58.98 95.69,58.78 95.69,58.37 95.9,58.17 96.14,58.17 96.35,57.95 96.35,56.95 95.8,56.4 95.8,52.88 v2(95.98,52.71)
M_A_A7: length 39.9
  TOP w0.178: v2(95.84,73.87) U1.D50 ; CN3.86 96.58,50.69 v2(95.98,51.29)
  LAY3 w0.203: v2(95.98,51.29) 95.37,50.68 95.37,50.23 95.62,49.98 96.34,49.98 96.96,50.61 96.96,53.71 97.17,53.91 97.45,53.91 97.65,54.11 97.65,54.52 97.45,54.72 97.17,54.72 96.96,54.92 96.96,55.33 97.17,55.53 97.44,55.53 97.65,55.74 97.65,56.15 97.45,56.35 97.17,56.35 96.96,56.55 96.96,61.33 98.57,62.94 99.35,62.94 100.05,63.64 100.71,63.64 100.91,63.84 100.91,64.25 100.71,64.45 99.95,64.45 99.75,64.65 99.75,65.06 99.95,65.26 100.71,65.26 100.91,65.46 100.91,65.87 100.71,66.07 99.95,66.07 99.76,66.26 99.76,66.74 99.95,66.93 100.71,66.93 100.91,67.13 100.91,67.54 100.71,67.74 99.98,67.74 99.76,67.96 99.76,68.57 97.11,71.22 97.11,72.6 v2(95.84,73.87)
M_A_A8: length 44.4
  TOP w0.102: 95.25,71.76 94.99,71.76 94.7,72.05 94.7,73.2 U1.G52
  TOP w0.178: 95.25,71.76 95.73,71.28 96.41,71.28 97.94,69.74 97.94,65.51 97.12,64.69 97.12,63.12 97.3,62.94 97.31,62.94 97.49,62.77 97.49,62.41 97.31,62.23 97.3,62.23 97.12,62.05 97.12,61.7 97.3,61.52 97.31,61.52 97.49,61.34 97.49,60.99 97.31,60.81 97.3,60.81 97.12,60.63 97.12,60.28 97.3,60.1 97.31,60.1 97.49,59.92 97.49,59.48 97.24,59.23 96.78,59.23 v2(96.54,59.47) ; CN3.89 95.68,54.43 v2(96.28,53.83)
  BOTTOM w0.178: v2(96.54,59.47) 96.34,59.66 95.77,59.66 95.6,59.49 95.6,58.32 94.68,57.41 91.16,57.41 90.97,57.22 90.97,56.63 91.17,56.42 92.92,56.42 93.13,56.21 93.13,55.37 93.31,55.19 93.58,55.19 93.92,55.53 93.92,56.28 94.06,56.42 94.76,56.42 94.92,56.27 94.92,54.26 94.66,54 94.66,51.51 94.87,51.3 95.35,51.3 95.53,51.49 95.53,52.89 95.98,53.34 95.98,53.54 v2(96.28,53.83)
M_A_A9: length 42.9
  TOP w0.102: 95.53,72.02 95.53,72.36 95.37,72.51 95.37,72.93 95.78,73.33 U1.E52
  TOP w0.178: v2(98.08,60.89) 98.08,61.37 98.71,62.01 98.71,62.29 98.58,62.43 98.25,62.43 98.08,62.6 98.08,63 98.26,63.19 99.47,63.19 99.71,63.43 99.71,63.72 99.51,63.91 97.88,63.91 97.7,64.09 97.7,64.45 97.88,64.63 99.48,64.63 99.71,64.85 99.71,65.21 99.53,65.39 98.71,65.39 98.53,65.57 98.53,65.92 98.71,66.1 99.53,66.1 99.71,66.28 99.71,66.63 99.53,66.81 98.71,66.81 98.53,66.99 98.53,67.34 98.71,67.52 99.53,67.52 99.71,67.7 99.71,68.05 99.53,68.23 98.71,68.23 98.53,68.41 98.53,69.79 96.62,71.69 95.85,71.69 95.53,72.02 ; v2(96.28,55.25) 96.88,55.85 CN3.85
  BOTTOM w0.178: v2(98.08,60.89) 97.38,60.89 97.12,61.15 97.12,61.47 97.43,61.79 97.99,61.79 98.76,61.02 98.76,58.28 98.37,57.89 97.53,57.89 97.36,57.72 97.36,56.85 97.18,56.67 96.82,56.67 96.65,56.85 96.65,57.79 96.46,57.98 96.08,57.98 95.25,57.15 95.25,56.76 95.5,56.51 95.5,55 95.64,54.86 95.92,54.86 96.28,55.21 v2(96.28,55.25)
M_A_A10: length 44.2
  TOP w0.178: U1.K48 v2(93.55,74.73) ; CN3.107 90.28,58.87 v2(90.88,59.47)
  LAY4 w0.102: 97.19,72.46 96.62,73.03 94.47,73.03 93.93,73.57 93.93,74.35 v2(93.55,74.73)
  LAY4 w0.203: 97.19,72.46 97.71,71.94 98.42,71.94 99.53,70.83 99.53,65.19 99.39,65.04 99.11,65.04 98.54,65.6 98.27,65.6 98.07,65.4 98.07,65.11 98.61,64.56 98.61,64.27 98.33,63.98 98.04,63.98 97.72,64.3 97.43,64.3 97.14,64.01 97.14,63.73 97.46,63.41 97.46,63.12 96.98,62.64 94.05,62.64 93.14,61.73 93.14,54.74 92.96,54.56 92.2,54.56 91.3,55.46 91.3,55.97 91.52,56.18 92.22,56.18 92.4,56.35 92.4,56.82 92.15,57.06 91.53,57.06 91.3,57.28 91.3,57.61 91.51,57.82 92.04,57.82 92.25,58.02 92.25,58.43 92.04,58.63 91.51,58.63 91.3,58.83 91.3,59.04 v2(90.88,59.47)
M_A_A11: length 42.3
  TOP w0.178: v2(97.78,52.71) 97.18,52.11 CN3.84 ; v2(95.36,74.43) U1.E51
  LAY3 w0.102: 96.97,74.02 96.27,74.02 95.87,74.43 v2(95.36,74.43)
  LAY3 w0.203: 96.97,74.02 98.19,72.81 98.19,71.16 101.52,67.83 101.52,63.59 100.26,62.33 98.82,62.33 97.57,61.08 97.57,57.23 99.11,55.69 99.11,55.4 98.71,55 98.71,54.71 99,54.43 99.29,54.43 99.68,54.83 99.97,54.83 100.6,54.2 100.6,50.31 100.02,49.74 98.74,49.74 98.35,50.13 98.35,52.14 v2(97.78,52.71)
M_A_A12: length 39.3
  TOP w0.178: v2(98.08,59.47) 97.48,58.87 CN3.83 ; U1.F47 v2(95.34,75.41)
  LAY3 w0.102: v2(95.34,75.41) 95.97,75.41 96.42,74.96 96.82,74.96
  LAY3 w0.165: 96.82,74.96 97.79,73.99 97.79,73.65
  LAY3 w0.203: 97.79,73.65 98.51,72.92 98.51,71.74 102.89,67.37 102.89,66.76 102.68,66.56 102.34,66.56 102.13,66.35 102.13,65.95 102.34,65.75 102.68,65.75 102.89,65.54 102.89,65.14 102.68,64.93 102.34,64.93 102.13,64.73 102.13,64.32 102.34,64.12 102.68,64.12 102.89,63.92 102.89,63.51 102.68,63.31 102.11,63.31 101.9,63.11 101.9,62.7 102.11,62.5 102.68,62.5 102.89,62.3 102.89,61.89 102.7,61.7 101.99,61.7 101.78,61.5 101.78,61.09 102,60.87 102.68,60.87 102.89,60.67 102.89,57.59 102.47,57.17 101.78,57.17 101.58,57.37 101.58,58.69 101.38,58.89 100.97,58.89 100.77,58.69 100.77,57.37 100.57,57.17 99.1,57.17 98.79,57.48 98.79,58.76 v2(98.08,59.47)
M_A_A13: length 43.7
  TOP w0.102: 93.91,71.4 93.91,72.37 93.8,72.47 93.8,73.19 U1.J51
  TOP w0.178: CN3.119 86.68,55.85 v2(87.28,55.25) ; v2(89.08,60.89) 89.08,60.8 88.32,60.05 88.04,60.05 87.83,60.26 87.83,61.26 88.42,61.84 90.13,61.84 93.58,65.28 95.24,65.28 96.17,66.22 96.17,69.14 93.91,71.4
  BOTTOM w0.178: v2(89.08,60.89) 89.9,60.89 90.18,61.18 90.18,61.89 89.88,62.2 89.39,62.2 89.21,62.02 89.21,61.77 89.03,61.6 88.67,61.6 88.5,61.77 88.5,62.02 88.32,62.2 87.96,62.2 87.79,62.02 87.79,61.77 87.61,61.6 87.25,61.6 87.07,61.77 87.07,62.02 86.9,62.2 86.13,62.2 85.89,61.96 85.89,61.27 86.07,61.1 86.59,61.1 86.77,60.92 86.77,60.56 86.59,60.39 86.07,60.39 85.89,60.21 85.89,59.85 86.07,59.67 86.59,59.67 86.77,59.5 86.77,59.14 86.59,58.96 86.07,58.96 85.89,58.79 85.89,58.43 86.07,58.25 86.59,58.25 86.77,58.07 86.77,57.72 86.59,57.54 86.07,57.54 85.89,57.36 85.89,57.01 86.07,56.83 86.59,56.83 86.77,56.65 86.77,55.45 86.97,55.25 v2(87.28,55.25)
M_A_A14: length 42.6
  TOP w0.102: U1.B49 97.37,74.92 97.82,74.92 97.92,74.82 98.36,74.82
  TOP w0.178: 98.36,74.82 98.62,74.56 98.62,71.62 102.72,67.52 102.72,62.29 101.69,61.26 101.69,58.31 101.99,58.01 101.99,57.15 101.61,56.78 101.25,56.78 100.87,57.16 100.87,59.26 v2(101.08,59.47) ; CN3.80 98.38,50.69 v2(97.78,51.29)
  BOTTOM w0.178: v2(101.08,59.47) 100.66,59.05 100.66,58.44 100.48,58.26 100.15,58.26 99.97,58.08 99.97,57.73 100.15,57.55 100.48,57.55 100.66,57.37 100.66,57.01 100.48,56.84 100.15,56.84 99.97,56.66 99.97,56.3 100.15,56.12 100.48,56.12 100.66,55.95 100.66,55.04 100.26,54.64 99.89,54.64 99.51,55.01 99.26,55.01 99.01,54.76 99.01,54.51 99.38,54.14 99.38,53.89 98.97,53.47 98.97,53.03 98.79,52.86 98.39,52.86 98.22,52.68 98.22,52.32 98.39,52.15 98.79,52.15 98.97,51.97 98.97,51.38 98.7,51.12 97.95,51.12 v2(97.78,51.29)
M_A_A15: length 42.3
  TOP w0.102: U1.B50 97.23,74.17 97.7,74.17 97.97,73.9
  TOP w0.178: 97.97,73.9 98.21,73.66 98.21,71.4 99.7,69.91 99.7,69.72 100.88,68.54 100.88,67.9 101.07,67.71 101.7,67.71 101.88,67.53 101.88,67.18 101.7,67 101.07,67 100.88,66.81 100.88,66.48 101.05,66.3 101.96,66.3 102.14,66.12 102.14,65.77 101.96,65.59 101.05,65.59 100.88,65.41 100.88,65.06 101.05,64.88 101.96,64.88 102.14,64.7 102.14,64.35 101.96,64.17 101.05,64.17 100.88,63.99 100.88,63.63 101.05,63.46 101.96,63.46 102.14,63.28 102.14,62.92 101.96,62.75 101.05,62.75 100.88,62.57 100.88,61.99 100.41,61.53 100.41,60.97 100.68,60.71 100.89,60.71 v2(101.08,60.89) ; v2(99.58,52.71) 98.98,52.11 CN3.78
  BOTTOM w0.178: v2(99.58,52.71) 100.08,53.21 100.08,53.82 100.26,54 101.4,54 101.67,54.27 101.67,54.6 101.49,54.78 101.42,54.78 101.24,54.96 101.24,55.32 101.42,55.49 101.49,55.49 101.67,55.67 101.67,56.03 101.49,56.2 101.42,56.2 101.24,56.38 101.24,56.74 101.42,56.92 101.49,56.92 101.67,57.09 101.67,60.85 102.03,61.2 102.03,61.79 101.53,62.28 101.27,62.28 100.88,61.89 100.88,61.51 101.08,61.31 v2(101.08,60.89)
M_A_BS0: length 44.8
  TOP w0.178: v2(90.88,60.89) 90.31,60.33 90.31,59.69 89.68,59.06 CN3.109 ; U1.K47 v2(93.55,75.44)
  LAY4 w0.102: 96.68,72.43 96.28,72.83 94.38,72.83 93.77,73.44 93.55,73.44 93.15,73.84 93.15,75.04 v2(93.55,75.44)
  LAY4 w0.203: v2(90.88,60.89) 91.3,60.46 91.3,59.9 91.6,59.61 91.95,59.61 92.22,59.88 92.22,61.06 91.9,61.37 91.9,61.92 92.34,62.36 92.91,62.36 94.65,64.1 94.93,64.1 95.79,63.25 96.07,63.25 96.36,63.54 96.36,63.82 95.51,64.68 95.51,64.96 95.79,65.25 96.08,65.25 96.67,64.66 96.93,64.66 97.22,64.95 97.22,65.26 96.66,65.82 96.66,66.11 96.93,66.38 98.72,66.38 98.92,66.59 98.92,66.99 98.72,67.19 97.12,67.19 96.92,67.4 96.92,67.8 97.12,68.01 98.72,68.01 98.92,68.21 98.92,68.61 98.72,68.82 97.2,68.82 97,69.02 97,69.43 97.2,69.63 98.72,69.63 99.13,70.03 99.13,70.82 98.56,71.39 98.29,71.39 97.34,70.44 96.95,70.44 96.68,70.71 96.68,72.43
M_A_BS1: length 44.7
  TOP w0.178: v2(92.56,77.58) U1.K44 ; v2(90.58,51.29) 89.98,50.69 CN3.108
  LAY4 w0.102: 96.39,71.94 96.39,72.38 96.14,72.63 94.3,72.63 93.72,73.21 93.36,73.21 92.96,73.61 92.96,74.31 92.96,77.18 v2(92.56,77.58)
  LAY4 w0.203: v2(90.58,51.29) 90.02,51.29 89.79,51.06 89.79,50.25 90.25,49.79 91.57,49.79 91.86,50.08 91.86,52.31 91.66,52.51 91.39,52.51 91.19,52.71 91.19,53.12 91.39,53.32 91.66,53.32 91.86,53.53 91.86,54.04 91.47,54.43 90.77,54.43 90.48,54.72 90.48,55 90.7,55.22 90.7,55.42 90.11,56.01 90.11,57.22 90.26,57.36 90.49,57.36 90.69,57.57 90.69,57.97 90.49,58.17 90.24,58.17 90.11,58.3 90.11,60.99 90.32,61.2 90.32,61.76 90.6,62.04 91.16,62.04 92.09,62.97 92.65,62.97 92.95,63.26 92.95,63.83 93.24,64.12 93.8,64.12 94.09,64.41 94.09,64.97 94.38,65.26 94.94,65.26 96.39,66.7 96.39,67.11 95.88,67.61 95.88,67.92 96.39,68.43 96.39,71.94
M_A_BS2: length 41.6
  TOP w0.102: 96.63,72.1 96.13,72.6 96.13,73.06 96.37,73.31 U1.D52
  TOP w0.178: 96.63,72.1 96.85,72.1 99.11,69.84 99.11,69.48 100.29,68.3 100.29,63.19 99.42,62.31 99.42,61.35 v2(99.88,60.89) ; v2(98.08,55.25) 98.68,55.85 CN3.79
  BOTTOM w0.178: v2(98.08,55.25) 98.67,55.25 99.39,55.97 99.39,56.45 99.22,56.62 98.41,56.62 98.23,56.8 98.23,57.15 98.38,57.3 99.18,57.3 99.39,57.52 99.39,60.4 99.39,60.4 99.39,61.69 98.7,62.37 97.43,62.37 96.71,63.09 96.71,63.8 96.97,64.06 97.58,64.06 97.75,63.88 97.75,63.18 97.93,63 98.29,63 98.47,63.18 98.47,63.88 98.64,64.06 99,64.06 99.18,63.88 99.18,63.18 99.35,63 99.71,63 99.89,63.18 99.89,63.88 100.07,64.06 100.6,64.06 100.82,63.84 100.82,62.66 100.29,62.13 100.29,61.31 v2(99.88,60.89)
M_A_CAS#: length 40.5
  TOP w0.178: U1.M44 v2(92.56,76.86) ; v2(87.28,59.47) 87.88,58.87 CN3.115
  LAY4 w0.102: v2(92.56,76.86) 91.97,76.27 91.97,73.71 93.1,72.59 93.7,72.59 94.24,72.06
  LAY4 w0.203: v2(87.28,59.47) 86.85,59.47 86.61,59.24 86.61,57.17 87.32,56.47 88.36,56.47 88.58,56.69 88.58,57.54 88.38,57.74 88.09,57.74 87.89,57.94 87.89,58.35 88.09,58.55 88.38,58.55 88.58,58.76 88.58,59.16 88.38,59.36 88.09,59.36 87.89,59.57 87.89,59.97 88.09,60.18 88.38,60.18 88.58,60.38 88.58,60.7 87.67,61.62 87.67,62.09 88.1,62.52 89.12,62.52 89.5,62.9 89.5,63.19 89.23,63.46 89.23,63.74 89.52,64.03 89.81,64.03 90.07,63.76 90.36,63.76 90.65,64.05 90.65,64.34 90.38,64.6 90.38,64.89 90.67,65.18 90.96,65.18 91.22,64.91 91.51,64.91 91.8,65.2 91.8,65.49 91.53,65.75 91.53,66.04 91.82,66.33 92.1,66.33 92.37,66.06 92.66,66.06 92.94,66.35 92.94,66.63 92.68,66.9 92.68,67.19 92.96,67.47 93.25,67.47 93.52,67.21 93.8,67.21 94.24,67.64 94.24,68.57 94.44,68.77 94.46,68.77 94.66,68.98 94.66,69.38 94.46,69.59 94.44,69.59 94.24,69.79 94.24,70.19 94.44,70.4 94.46,70.4 94.66,70.6 94.66,71.01 94.46,71.21 94.44,71.21 94.24,71.41 94.24,72.06
M_A_DM0: length 57.1
  TOP w0.114: U1.G36 v2(94.14,80.71) ; CN3.11 v2(121.48,58.76)
  LAY3 w0.127: v2(121.48,58.76) 121.91,59.19 121.91,61.71 119.82,63.8 114.55,63.8 114.1,64.25 114.1,64.35 113.97,64.48 113.72,64.48 113.59,64.35 113.59,64.25 113.46,64.12 113.04,64.12 112.79,64.37 112.79,64.55 113.59,65.35 113.59,65.53 113.41,65.71 113.23,65.71 112.43,64.91 112.25,64.91 112.07,65.09 112.07,65.27 112.87,66.07 112.87,66.25 112.69,66.43 112.51,66.43 111.71,65.63 111.53,65.63 111.35,65.81 111.35,65.99 112.15,66.79 112.15,66.97 111.97,67.15 111.79,67.15 110.99,66.35 110.81,66.35 110.63,66.53 110.63,66.71 111.43,67.51 111.43,67.69 111.25,67.87 111.07,67.87 110.28,67.07 110.1,67.07 109.92,67.25 109.92,67.43 110.71,68.23 110.71,68.41 110.53,68.59 110.35,68.59 109.56,67.79 109.38,67.79 109.2,67.97 109.2,68.15 109.99,68.95 109.99,69.13 109.81,69.3 109.64,69.3 108.84,68.51 108.66,68.51 102.49,74.68 102.49,75.92 98.26,80.15 97.41,80.15 96.37,81.19 94.62,81.19 v2(94.14,80.71)
M_A_DM1: length 47
  TOP w0.114: CN3.28 v2(116.38,50.58) ; v2(116.08,58.76) 116.66,59.34 116.66,61.02 115.12,62.56 115.12,67.41 104.29,78.24 103.59,78.24 100.9,80.94 99.05,80.94 98.73,81.26 97.25,81.26 U1.B36
  BOTTOM w0.114: v2(116.38,50.58) 116.03,50.23 115.52,50.23 115.25,50.49 115.25,52.14 115.37,52.25 116.35,52.25 116.47,52.37 116.47,52.6 116.35,52.71 115.37,52.71 115.25,52.82 115.25,53.17 114.99,53.43 114.99,56.83 116.08,57.91 v2(116.08,58.76)
M_A_DM2: length 40.9
  TOP w0.114: v2(95.56,79.72) U1.F38 ; v2(110.98,50.58) 110.98,50.58 CN3.46
  LAY4 w0.127: v2(95.56,79.72) 95.95,80.11 96.76,80.11 97.64,79.23 100.56,79.23 110.83,68.96 110.83,52.4 110.37,51.94 110.37,51.18 v2(110.98,50.58)
M_A_DM3: length 42.5
  TOP w0.114: v2(106.48,60.89) 106.48,60.98 106.94,61.45 106.94,61.62 108.4,63.07 108.4,63.55 108.28,63.66 107.9,63.66 107.79,63.77 107.79,64 107.9,64.12 108.28,64.12 108.4,64.23 108.4,67.41 102.3,73.51 101.93,73.51 100.58,74.85 100.58,76.19 98.58,78.19 97.24,78.19 U1.B42 ; CN3.63 v2(105.88,55.96)
  BOTTOM w0.114: v2(106.48,60.89) 107.32,61.74 107.32,62.09 107.21,62.2 106.54,62.2 106.42,62.32 106.42,62.55 106.54,62.66 107.21,62.66 107.32,62.78 107.32,63 107.21,63.12 106.54,63.12 106.42,63.23 106.42,63.46 106.54,63.58 107.21,63.58 107.32,63.69 107.32,64.03 107.1,64.26 106.09,64.26 105.88,64.05 v2(105.88,55.96)
M_A_DM4: length 43.8
  TOP w0.089: U1.P51 91.09,73.54 90.79,73.24 90.79,73 90.95,72.84
  TOP w0.102: 90.95,72.84 91.35,72.44 91.35,71.11
  TOP w0.114: v2(80.68,58.76) 81.09,59.17 81.09,62.01 80.46,62.64 80.46,64.37 80.71,64.63 81.39,64.63 81.5,64.74 81.5,65.05 81.62,65.16 81.85,65.16 81.96,65.05 81.96,64.74 82.08,64.63 82.3,64.63 82.42,64.74 82.42,65.05 82.53,65.16 82.76,65.16 82.88,65.05 82.88,64.74 82.99,64.63 83.22,64.63 83.33,64.74 83.33,65.05 83.45,65.16 83.68,65.16 83.79,65.05 83.79,64.74 83.9,64.63 84.13,64.63 84.25,64.74 84.25,65.05 84.36,65.16 84.59,65.16 84.7,65.05 84.7,64.74 84.82,64.63 85.16,64.63 86.27,65.74 88.15,65.74 88.39,65.98 88.39,66.14 88.29,66.25 88.29,66.41 88.45,66.57 88.61,66.57 88.72,66.47 88.88,66.47 89.04,66.63 89.04,66.79 88.93,66.9 88.93,67.06 89.1,67.22 89.26,67.22 89.36,67.11 89.52,67.11 89.69,67.27 89.69,67.44 89.58,67.54 89.58,67.7 89.74,67.87 89.9,67.87 90.01,67.76 90.17,67.76 90.33,67.92 90.33,68.08 90.23,68.19 90.23,68.35 90.39,68.51 90.55,68.51 90.66,68.41 90.82,68.41 90.98,68.57 90.98,68.73 90.87,68.84 90.87,69 91.04,69.16 91.2,69.16 91.3,69.05 91.46,69.05 91.87,69.45 91.87,70.59 91.35,71.11 ; CN3.136 v2(81.58,50.58)
  BOTTOM w0.114: v2(80.68,58.76) 80.68,57.46 81.17,56.97 81.17,52.67 81.95,51.9 82.58,51.9 82.82,51.65 82.82,50.77 81.89,49.84 81.36,49.84 81.11,50.09 81.11,50.36 81.32,50.58 v2(81.58,50.58)
M_A_DM5: length 40.9
  TOP w0.114: v2(88.68,78.29) U1.V42 ; CN3.153 v2(76.48,58.76)
  LAY3 w0.127: v2(88.68,78.29) 89.08,77.89 89.08,73.81 89.01,73.74 88.56,73.3 88.56,71.3 80.66,63.4 78.9,63.4 76.23,60.73 76.23,60.38 75.76,59.91 75.76,58.28 75.59,58.11 74.87,58.11 74.55,57.79 74.55,55 74.77,54.79 75.52,54.79 76.39,55.65 76.39,56.41 76.26,56.53 75.07,56.53 74.95,56.66 74.95,56.91 75.07,57.04 76.26,57.04 76.39,57.17 76.39,58.67 v2(76.48,58.76)
M_A_DM6: length 41.7
  TOP w0.114: U1.Y50 v2(87.68,74.02) ; v2(71.38,50.58) CN3.170
  LAY4 w0.127: v2(71.38,50.58) 71.6,50.58 71.83,50.34 71.83,49.97 71.67,49.81 71.05,49.81 70.78,50.08 70.78,51.85 71.32,52.39 71.32,58.96 71.15,59.14 71.15,63.28 72.52,64.65 72.7,64.65 72.96,64.39 73.14,64.39 73.32,64.57 73.32,64.75 73.06,65.01 73.06,65.19 73.73,65.86 80.34,65.86 83.98,69.5 83.98,69.68 83.87,69.8 83.87,69.98 84.05,70.15 84.23,70.15 84.34,70.04 84.52,70.04 84.7,70.22 84.7,70.4 84.59,70.51 84.59,70.69 84.77,70.87 84.95,70.87 85.06,70.76 85.24,70.76 85.42,70.94 85.42,71.12 85.31,71.23 85.31,71.41 85.49,71.59 85.67,71.59 85.78,71.48 85.96,71.48 87.68,73.21 v2(87.68,74.02)
M_A_DM7: length 44.4
  TOP w0.114: U1.Y52 88.1,73.05 88.1,71.85 86.36,70.11 83.74,70.11 83.24,69.6 76.91,69.6 76.06,68.76 75.91,68.76 75.64,69.03 75.48,69.03 75.32,68.87 75.32,68.7 75.58,68.44 75.58,68.28 75.42,68.11 75.26,68.11 74.99,68.38 74.83,68.38 74.67,68.22 74.67,68.06 74.93,67.8 74.93,67.63 74.77,67.47 74.61,67.47 74.35,67.73 74.18,67.73 74.02,67.57 74.02,67.41 74.28,67.15 74.28,66.98 71.85,64.55 71.85,64.39 72.31,63.94 72.31,63.78 72.15,63.61 71.98,63.61 71.53,64.07 71.37,64.07 70.91,63.61 68.53,63.61 67.48,62.55 v2(67.48,60.18) ; CN3.187 v2(66.28,55.96)
  BOTTOM w0.114: v2(67.48,60.18) 67.86,60.18 68.09,60.41 68.09,60.75 67.98,60.87 67.52,60.87 67.41,60.98 67.41,61.21 67.52,61.33 67.98,61.33 68.09,61.44 68.09,61.76 67.85,62.01 67.19,62.01 66.9,61.71 66.9,58.42 66.46,57.98 66.46,56.15 v2(66.28,55.96)
M_A_DQ0: length 56.7
  TOP w0.114: CN3.5 v2(123.28,58.76) ; U1.M36 v2(92,80.71)
  LAY3 w0.089: 96.84,81.4 96.57,81.67 93.97,81.67 93.44,81.14 92.43,81.14 v2(92,80.71)
  LAY3 w0.127: 96.84,81.4 97.55,80.69 99.94,80.69 104.72,75.91 104.72,75.73 103.95,74.97 103.95,74.79 104.13,74.61 104.31,74.61 105.07,75.38 105.25,75.38 105.43,75.2 105.43,75.02 104.67,74.25 104.67,74.07 104.85,73.89 105.03,73.89 105.79,74.66 105.97,74.66 115.62,65.01 120.12,65.01 123.68,61.45 123.68,57.2 122.99,56.51 122.15,56.51 121.77,56.9 121.77,58.08 122.45,58.76 v2(123.28,58.76)
M_A_DQ1: length 56.9
  TOP w0.114: U1.J36 v2(93.43,80.71) ; CN3.7 122.68,59.58 v2(123.28,60.18)
  LAY3 w0.089: 96.7,81.21 96.46,81.46 94.18,81.46 v2(93.43,80.71)
  LAY3 w0.127: 96.7,81.21 97.49,80.42 98.77,80.42 103.02,76.17 103.02,74.9 104.91,73.01 105.09,73.01 105.88,73.81 106.06,73.81 106.24,73.63 106.24,73.45 105.45,72.65 105.45,72.47 105.63,72.3 105.8,72.3 106.6,73.09 106.78,73.09 106.96,72.91 106.96,72.73 106.16,71.94 106.16,71.76 106.34,71.58 106.52,71.58 107.32,72.37 107.5,72.37 107.68,72.19 107.68,72.01 106.88,71.22 106.88,71.04 107.06,70.86 107.24,70.86 108.04,71.65 108.22,71.65 108.4,71.48 108.4,71.3 107.6,70.5 107.6,70.32 107.78,70.14 107.96,70.14 108.76,70.94 108.94,70.94 109.12,70.76 109.12,70.58 108.32,69.78 108.32,69.6 108.5,69.42 108.68,69.42 109.48,70.22 109.66,70.22 115.42,64.45 119.91,64.45 122.44,61.93 122.44,61.01 v2(123.28,60.18)
M_A_DQ2: length 57.2
  TOP w0.114: CN3.15 v2(120.28,58.76) ; U1.P40 v2(91.29,79.72)
  LAY3 w0.089: 96.57,79.04 96.48,79.13 92.01,79.13 91.42,79.72 v2(91.29,79.72)
  LAY3 w0.127: v2(120.28,58.76) 120.05,58.53 120.05,57.89 119.8,57.64 113.44,57.64 113.31,57.76 113.31,58.3 113.19,58.42 112.93,58.42 112.81,58.3 112.81,57.76 112.68,57.64 111.82,57.64 111.69,57.76 111.69,58.43 111.56,58.56 111.31,58.56 111.18,58.43 111.18,57.76 111.06,57.64 110.67,57.64 110.47,57.84 110.47,58.93 110.59,59.06 111.8,59.06 111.92,59.18 111.92,59.44 111.8,59.56 110.59,59.56 110.47,59.69 110.47,59.94 110.59,60.07 111.8,60.07 111.92,60.2 111.92,60.45 111.8,60.58 110.59,60.58 110.47,60.71 110.47,60.96 110.59,61.09 111.8,61.09 111.92,61.21 111.92,61.47 111.8,61.6 110.59,61.6 110.47,61.72 110.47,62.08 110.59,62.2 111,62.2 111.13,62.33 111.13,62.59 111,62.71 110.59,62.71 110.47,62.84 110.47,63.54 100.16,73.84 100.16,75.5 98.38,77.28 97.8,77.28 97.31,77.77 97.31,78.3 96.57,79.04
M_A_DQ3: length 56.4
  TOP w0.114: CN3.17 119.68,59.58 v2(120.28,60.18) ; U1.M40 v2(92,79.72)
  LAY3 w0.089: 96.61,79.32 92.4,79.32 v2(92,79.72)
  LAY3 w0.127: v2(120.28,60.18) 119.5,59.4 119.5,58.43 119.29,58.23 118.59,58.23 118.43,58.38 118.43,61.05 118.31,61.18 118.05,61.18 117.92,61.05 117.92,58.4 117.75,58.23 116.92,58.23 116.71,58.44 116.71,60.94 116.46,61.18 114.94,61.18 114.71,60.95 114.71,60.19 115.48,59.41 115.48,58.48 115.23,58.23 114.35,58.23 114.11,58.47 114.11,60.65 101.12,73.64 101.12,75.38 98.3,78.21 97.73,78.21 96.61,79.32
M_A_DQ4: length 57.4
  TOP w0.114: CN3.4 v2(123.58,50.58) ; U1.P36 v2(90.58,80.71)
  LAY3 w0.089: v2(90.58,80.71) 91.59,81.72 93.2,81.72 93.54,82.06 96.82,82.06 97.1,81.78
  LAY3 w0.127: 97.1,81.78 97.7,81.19 101.14,81.19 116.16,66.17 120.46,66.17 125.44,61.19 125.44,58.66 124.96,58.19 124.96,55.71 124.5,55.24 124.5,51.5 v2(123.58,50.58)
M_A_DQ5: length 57.2
  TOP w0.114: CN3.6 122.98,50.84 123.12,50.98 123.12,51.54 v2(123.58,52) ; U1.N36 v2(91.29,80.71)
  LAY3 w0.089: v2(91.29,80.71) 92.01,81.43 93.32,81.43 93.76,81.87 96.69,81.87 96.97,81.59
  LAY3 w0.127: v2(123.58,52) 123.97,52.39 123.97,54.06 123.84,54.18 123.63,54.18 123.5,54.31 123.5,54.56 123.63,54.69 123.84,54.69 123.97,54.82 123.97,55.07 123.84,55.2 123.63,55.2 123.5,55.33 123.5,55.58 123.63,55.71 123.84,55.71 123.97,55.83 123.97,56.24 124.29,56.57 124.29,58.28 124.89,58.88 124.89,60.98 120.27,65.61 115.97,65.61 100.61,80.96 97.6,80.96 96.97,81.59
M_A_DQ6: length 56.7
  TOP w0.114: CN3.16 v2(119.98,50.71) ; v2(93.43,78.73) U1.K40
  LAY3 w0.089: 96.75,78.33 93.83,78.33 v2(93.43,78.73)
  LAY3 w0.127: v2(119.98,50.71) 120.98,50.71 121.25,50.98 121.25,51.68 121.12,51.81 120.77,51.81 120.64,51.93 120.64,52.19 120.77,52.32 121.12,52.32 121.25,52.44 121.25,52.7 121.12,52.82 120.77,52.82 120.64,52.95 120.64,53.2 120.77,53.33 121.12,53.33 121.25,53.46 121.25,53.81 120.96,54.1 120.78,54.1 120.12,53.45 119.94,53.45 119.76,53.63 119.76,53.81 120.42,54.46 120.42,54.64 120.24,54.82 120.06,54.82 119.41,54.16 119.23,54.16 119.05,54.34 119.05,54.52 119.7,55.18 119.7,55.36 117.96,57.1 110.45,57.1 109.42,58.13 109.42,61.65 109.56,61.79 109.81,61.79 109.93,61.92 109.93,62.18 109.81,62.3 109.53,62.3 109.42,62.41 109.42,62.67 109.56,62.81 109.81,62.81 109.93,62.94 109.93,63.19 109.81,63.32 109.53,63.32 109.42,63.43 109.42,63.83 99.72,73.53 99.72,75.49 98.28,76.92 97.73,76.92 97.01,77.65 97.01,78.07 96.75,78.33
M_A_DQ7: length 56.7
  TOP w0.114: CN3.18 119.38,51.47 v2(119.96,52.05) ; v2(93.43,77.74) U1.K42
  LAY3 w0.089: v2(93.43,77.74) 93.83,78.14 96.48,78.14 96.57,78.05
  LAY3 w0.127: 96.57,78.05 96.7,77.92 96.7,77.52 97.58,76.64 98.16,76.64 99.25,75.55 99.25,73.24 108.18,64.32 108.18,63.37 108.31,63.24 108.76,63.24 108.89,63.12 108.89,62.86 108.76,62.73 108.31,62.73 108.18,62.61 108.18,62.35 108.31,62.23 108.76,62.23 108.89,62.1 108.89,61.85 108.76,61.72 108.31,61.72 108.18,61.59 108.18,58.62 110.23,56.57 115.42,56.57 116.03,55.96 116.21,55.96 116.65,56.39 116.83,56.39 117.01,56.21 117.01,56.01 116.15,55.16 116.15,54.98 116.33,54.8 116.51,54.8 117.38,55.67 117.54,55.67 117.72,55.49 117.72,55.31 116.83,54.41 116.83,54.15 117.09,53.88 117.27,53.88 117.55,54.15 117.73,54.15 117.91,53.97 117.91,53.79 117.63,53.52 117.63,53.34 118.23,52.75 118.41,52.75 119.05,53.39 119.23,53.39 119.41,53.21 119.41,53.03 118.77,52.39 118.77,52.21 119.21,51.77 119.67,51.77 v2(119.96,52.05)
M_A_DQ8: length 46.8
  TOP w0.089: 98.1,82.98 97.93,82.98 97.79,83.12 97.43,83.12 U1.B32
  TOP w0.114: 98.1,82.98 103.3,82.98 105.17,81.11 105.4,81.11 118.7,67.81 118.7,62.69 v2(119.08,62.31) ; CN3.21 v2(118.48,55.96)
  BOTTOM w0.114: v2(119.08,62.31) 121.44,62.31 122.68,61.08 122.68,58.64 120,55.96 v2(118.48,55.96)
M_A_DQ9: length 47.5
  TOP w0.089: U1.C32 96.75,83.12 97.05,83.42 97.29,83.42 97.4,83.31 97.87,83.31 97.96,83.22 98.31,83.22
  TOP w0.102: 98.31,83.22 98.31,83.22
  TOP w0.114: v2(118.48,54.54) 117.88,55.14 CN3.23 ; 98.31,83.22 101,83.22 101.3,83.52 103.49,83.52 105.35,81.66 105.59,81.66 119.22,68.03 119.22,62.92 119.48,62.65 119.48,61.3 v2(119.08,60.89)
  BOTTOM w0.114: v2(118.48,54.54) 117.99,55.02 117.99,56.3 119.64,57.94 119.64,60.33 v2(119.08,60.89)
M_A_DQ10: length 47.3
  TOP w0.102: 97.07,80.86 96.75,81.18 U1.C36
  TOP w0.114: CN3.33 114.88,55.7 114.73,55.56 114.73,55 v2(114.28,54.54) ; 97.07,80.86 97.27,80.86 97.4,80.98 98.58,80.98 98.93,80.63 100.46,80.63 103.37,77.72 104.07,77.72 114.59,67.2 114.59,66.86 114.47,66.75 113.8,66.75 113.68,66.63 113.68,66.4 113.8,66.29 114.47,66.29 114.59,66.18 114.59,65.95 114.47,65.83 113.8,65.83 113.68,65.72 113.68,65.49 113.8,65.38 114.47,65.38 114.59,65.26 114.59,65.03 114.47,64.92 113.8,64.92 113.68,64.8 113.68,64.58 113.8,64.46 114.47,64.46 114.59,64.35 114.59,64.12 114.47,64 113.8,64 113.68,63.89 113.68,63.66 113.8,63.55 114.47,63.55 114.59,63.43 114.59,62.07 116.08,60.58 v2(116.08,60.18)
  BOTTOM w0.114: v2(114.28,54.54) 114.69,54.96 114.69,57.41 115.59,58.3 115.59,59.69 v2(116.08,60.18)
M_A_DQ11: length 47.3
  TOP w0.114: CN3.35 v2(114.28,55.96) ; v2(114.88,58.76) 115.31,59.19 115.31,60.53 115.31,60.61 114.05,61.87 114.05,62.79 113.83,63.01 113.25,63.01 112.94,63.32 112.94,63.57 113.14,63.78 113.14,64.03 112.94,64.24 112.94,64.49 113.14,64.69 113.14,64.95 112.94,65.15 112.94,65.4 113.14,65.61 113.14,65.86 112.94,66.06 112.94,66.32 113.14,66.52 113.14,66.77 112.94,66.98 112.94,67.23 113.14,67.44 113.14,67.91 103.85,77.2 103.16,77.2 100.03,80.33 98.88,80.33 98.52,80.69 U1.A37
  BOTTOM w0.114: v2(114.88,58.76) 115.29,59.17 115.29,60.26 116.07,61.05 116.07,61.68 115.72,62.03 113.41,62.03 113.11,61.73 113.11,60.98 113.39,60.7 113.91,60.7 114.45,60.16 114.45,57.98 113.96,57.49 113.96,56.28 v2(114.28,55.96)
M_A_DQ12: length 47.9
  TOP w0.076: U1.C33 97.08,82.63 97.35,82.9 97.73,82.9 97.87,82.75
  TOP w0.114: CN3.22 118.18,51.4 v2(117.58,52) ; v2(119.08,60.18) 118.66,60.59 118.66,61.92 118.18,62.41 118.18,67.6 105.2,80.57 104.97,80.57 103.12,82.42 102.08,82.42 101.75,82.75 97.87,82.75
  BOTTOM w0.114: v2(119.08,60.18) 117.83,58.94 117.83,57.67 117.03,56.87 117.03,52.55 v2(117.58,52)
M_A_DQ13: length 47.2
  TOP w0.114: CN3.24 v2(117.58,50.58) ; U1.A33 97.64,82.55 97.78,82.55 98.61,82.55 98.73,82.43 101.55,82.43 102.08,81.9 102.91,81.9 104.77,80.04 105,80.04 117.66,67.38 117.66,62.34 118.28,61.71 118.28,59.55 v2(119.08,58.76)
  BOTTOM w0.114: v2(117.58,50.58) 118.11,50.58 118.87,51.34 118.87,52.43 117.6,53.7 117.6,56.65 119.08,58.13 v2(119.08,58.76)
M_A_DQ14: length 48
  TOP w0.114: U1.C37 97,80.5 97.29,80.5 97.4,80.4 97.46,80.4 98.41,80.4 98.78,80.02 99.6,80.02 102.94,76.68 103.64,76.68 112.42,67.9 112.42,62.66 112.61,62.46 112.61,61.98 112.74,61.84 113.23,61.84 114.25,60.83 114.25,59.33 v2(113.68,58.76) ; CN3.34 v2(114.58,50.58)
  BOTTOM w0.114: v2(113.68,58.76) 112.79,57.87 112.79,57.52 112.67,57.41 112.2,57.41 112.09,57.3 112.09,57.07 112.2,56.95 112.67,56.95 112.79,56.84 112.79,56.61 112.67,56.5 112.2,56.5 112.09,56.38 112.09,56.15 112.2,56.04 112.67,56.04 112.79,55.92 112.79,55.7 112.67,55.58 112.2,55.58 112.09,55.47 112.09,55.24 112.2,55.12 112.67,55.12 112.79,55.01 112.79,54.78 112.67,54.67 112.2,54.67 112.09,54.55 112.09,54.32 112.2,54.21 112.67,54.21 112.79,54.1 112.79,53.87 112.67,53.75 112.2,53.75 112.09,53.64 112.09,53.41 112.2,53.3 112.67,53.3 112.79,53.18 112.79,51.83 114.04,50.58 v2(114.58,50.58)
M_A_DQ15: length 46.9
  TOP w0.114: v2(113.68,60.18) 113.68,60.66 113.03,61.31 111.98,61.31 111.56,60.89 111,60.89 110.68,61.21 110.68,61.78 111.16,62.25 111.32,62.25 111.76,61.81 111.92,61.81 112.09,61.97 112.09,62.13 111.64,62.58 111.64,62.74 111.9,63 111.9,67.69 103.42,76.16 102.73,76.16 102.09,76.79 102.09,77.11 99.49,79.72 98.75,79.72 98.31,80.15 97.22,80.15 U1.B38 ; CN3.36 113.98,51.4 v2(114.58,52)
  BOTTOM w0.114: v2(113.68,60.18) 114.09,59.77 114.09,58.41 113.37,57.69 113.37,53.48 113.48,53.37 113.99,53.37 114.11,53.26 114.11,53.03 113.99,52.91 113.48,52.91 113.37,52.8 113.37,52.03 113.67,51.73 114.3,51.73 v2(114.58,52)
M_A_DQ16: length 40.5
  TOP w0.114: v2(112.48,60.18) 113.08,59.58 CN3.39 ; v2(95.56,80.71) U1.F36
  LAY4 w0.102: v2(95.56,80.71) 95.97,81.12 96.84,81.12 97.05,80.91
  LAY4 w0.127: v2(112.48,60.18) 112.48,60.32 112.99,60.83 112.99,61.63 112.86,61.75 112.6,61.75 112.47,61.88 112.47,62.13 112.6,62.26 112.86,62.26 112.99,62.39 112.99,62.64 112.86,62.77 112.6,62.77 112.47,62.9 112.47,63.15 112.6,63.28 112.86,63.28 112.99,63.4 112.99,63.66 112.86,63.79 112.6,63.79 112.47,63.91 112.47,64.17 112.6,64.29 112.86,64.29 112.99,64.42 112.99,64.67 112.86,64.8 112.6,64.8 112.47,64.93 112.47,65.18 112.6,65.31 112.86,65.31 112.99,65.44 112.99,65.69 112.86,65.82 112.6,65.82 112.47,65.94 112.47,66.2 112.6,66.33 112.86,66.33 112.99,66.45 112.99,66.71 112.86,66.83 112.6,66.83 112.47,66.96 112.47,67.21 112.6,67.34 112.86,67.34 112.99,67.47 112.99,67.72 112.86,67.85 112.6,67.85 112.47,67.98 112.47,68.23 112.6,68.36 112.86,68.36 112.99,68.48 112.99,69.07 101.15,80.91 97.05,80.91
M_A_DQ17: length 41.7
  TOP w0.114: U1.G38 v2(94.85,80.71) ; CN3.41 v2(112.48,58.76)
  LAY4 w0.102: 97.15,81.24 97.05,81.34 95.48,81.34 v2(94.85,80.71)
  LAY4 w0.127: v2(112.48,58.76) 113.18,59.46 113.18,60.26 113.99,61.07 113.99,61.61 113.86,61.73 113.65,61.73 113.52,61.86 113.52,62.12 113.65,62.24 113.86,62.24 113.99,62.37 113.99,62.62 113.86,62.75 113.65,62.75 113.52,62.88 113.52,63.13 113.65,63.26 113.86,63.26 113.99,63.39 113.99,63.64 113.86,63.77 113.65,63.77 113.52,63.89 113.52,64.15 113.65,64.27 113.86,64.27 113.99,64.4 113.99,64.66 113.86,64.78 113.65,64.78 113.52,64.91 113.52,65.16 113.65,65.29 113.86,65.29 113.99,65.42 113.99,65.67 113.86,65.8 113.65,65.8 113.52,65.93 113.52,66.18 113.65,66.31 113.86,66.31 113.99,66.43 113.99,66.69 113.86,66.81 113.65,66.81 113.52,66.94 113.52,67.2 113.65,67.32 113.86,67.32 113.99,67.45 113.99,67.7 113.86,67.83 113.65,67.83 113.52,67.96 113.52,68.21 113.65,68.34 113.86,68.34 113.99,68.47 113.99,68.82 101.57,81.24 97.15,81.24
M_A_DQ18: length 42.4
  TOP w0.114: U1.F42 v2(94.85,78.73) ; v2(108.88,60.18) 109.48,59.58 CN3.51
  LAY4 w0.089: v2(94.85,78.73) 95.25,78.33 96.83,78.33
  LAY4 w0.127: 96.83,78.33 97.82,77.34 99.62,77.34 100.04,77.34 107.5,69.89 107.5,69.44 107.37,69.31 106.73,69.31 106.61,69.18 106.61,68.93 106.73,68.8 107.37,68.8 107.5,68.67 107.5,68.42 107.37,68.29 106.73,68.29 106.61,68.17 106.61,67.91 106.73,67.78 107.37,67.78 107.5,67.66 107.5,67.4 107.37,67.28 106.73,67.28 106.61,67.15 106.61,66.9 106.73,66.77 107.37,66.77 107.5,66.64 107.5,66.39 107.37,66.26 106.73,66.26 106.61,66.13 106.61,65.88 106.73,65.75 107.37,65.75 107.5,65.63 107.5,65.37 107.37,65.24 106.73,65.24 106.61,65.12 106.61,64.86 106.73,64.74 107.37,64.74 107.5,64.61 107.5,64.36 107.37,64.23 106.73,64.23 106.61,64.1 106.61,63.85 106.73,63.72 107.37,63.72 107.5,63.59 107.5,63.34 107.37,63.21 106.73,63.21 106.61,63.09 106.61,62.83 106.73,62.7 107.37,62.7 107.5,62.58 107.5,62.22 107.62,62.1 108.22,62.1 108.35,61.97 108.35,61.71 108.22,61.59 107.62,61.59 107.5,61.46 107.5,60.97 108.28,60.18 v2(108.88,60.18)
M_A_DQ19: length 41.9
  TOP w0.114: U1.J42 v2(94.14,78.73) ; CN3.53 v2(108.88,58.76)
  LAY4 w0.089: 96.8,77.95 96.61,78.14 94.73,78.14 v2(94.14,78.73)
  LAY4 w0.127: v2(108.88,58.76) 109.29,58.76 109.61,58.44 109.61,57.99 108.98,57.37 108.65,57.37 108.53,57.49 108.53,58.43 108.4,58.56 108.15,58.56 108.02,58.43 108.02,57.49 107.89,57.37 107.15,57.37 106.9,57.62 106.9,57.8 106.95,57.84 106.95,58.02 106.77,58.2 106.59,58.2 106.54,58.16 106.36,58.16 106.02,58.5 106.02,58.86 105.89,58.99 105.79,58.99 105.67,59.11 105.67,59.37 105.79,59.49 105.89,59.49 106.02,59.62 106.02,59.88 105.89,60 105.79,60 105.67,60.13 105.67,60.38 105.79,60.51 105.89,60.51 106.02,60.64 106.02,60.89 105.89,61.02 105.79,61.02 105.67,61.15 105.67,61.4 105.79,61.53 105.89,61.53 106.02,61.65 106.02,61.91 105.89,62.03 105.79,62.03 105.67,62.16 105.67,62.42 105.79,62.54 105.89,62.54 106.02,62.67 106.02,62.92 105.89,63.05 105.79,63.05 105.67,63.18 105.67,63.43 105.79,63.56 105.89,63.56 106.02,63.69 106.02,63.94 105.89,64.07 105.79,64.07 105.67,64.19 105.67,64.45 105.79,64.57 105.89,64.57 106.02,64.7 106.02,64.96 105.89,65.08 105.79,65.08 105.67,65.21 105.67,65.46 105.79,65.59 105.89,65.59 106.02,65.72 106.02,65.97 105.89,66.1 105.79,66.1 105.67,66.23 105.67,66.48 105.79,66.61 105.89,66.61 106.02,66.73 106.02,66.99 105.89,67.11 105.79,67.11 105.67,67.24 105.67,67.5 105.79,67.62 105.89,67.62 106.02,67.75 106.02,68.2 105.89,68.33 105.78,68.33 105.65,68.45 105.65,68.71 105.78,68.83 105.89,68.83 106.02,68.96 106.02,69.21 105.89,69.34 105.78,69.34 105.65,69.47 105.65,69.72 105.78,69.85 105.89,69.85 106.02,69.98 106.02,70.61 99.57,77.06 99.18,77.06 97.81,77.06 97.69,77.06 96.8,77.95
M_A_DQ20: length 42.6
  TOP w0.114: v2(112.18,52) 112.78,51.4 CN3.40 ; U1.G40 v2(94.85,79.72)
  LAY4 w0.089: v2(94.85,79.72) 95.44,80.31 96.45,80.31 96.47,80.33
  LAY4 w0.102: 97.1,80.18 96.95,80.33 96.47,80.33
  LAY4 w0.127: v2(112.18,52) 111.37,52.8 111.37,69.17 100.37,80.18 97.1,80.18
M_A_DQ21: length 41.5
  TOP w0.114: CN3.42 v2(112.18,50.58) ; U1.C38 v2(96.27,80.71)
  LAY4 w0.102: 97.14,80.51 96.94,80.71 v2(96.27,80.71)
  LAY4 w0.127: v2(112.18,50.58) 112.6,51 112.6,53.7 111.94,54.36 111.94,58.24 111.94,61.13 111.94,69.36 100.79,80.51 97.14,80.51
M_A_DQ22: length 42.3
  TOP w0.114: U1.G44 v2(94.85,77.74) ; CN3.50 v2(109.78,50.58)
  LAY4 w0.089: v2(94.85,77.74) 95.44,77.15 96.55,77.15 96.73,76.97
  LAY4 w0.127: 96.73,76.97 97.19,76.5 98.62,76.5 104.3,70.82 104.3,57.98 105.37,56.91 105.37,56.36 105.25,56.23 104.84,56.23 104.72,56.1 104.72,55.85 104.84,55.72 105.25,55.72 105.37,55.6 105.37,55.34 105.25,55.22 104.84,55.22 104.72,55.09 104.72,54.83 104.84,54.71 105.25,54.71 105.37,54.58 105.37,54.33 105.25,54.2 104.84,54.2 104.72,54.07 104.72,53.82 104.84,53.69 105.25,53.69 105.37,53.56 105.37,51.38 106.58,50.17 109.37,50.17 v2(109.78,50.58)
M_A_DQ23: length 42.7
  TOP w0.114: v2(109.78,52) 109.18,51.4 CN3.52 ; v2(95.56,77.74) U1.D42
  LAY4 w0.089: 96.83,77.34 95.96,77.34 v2(95.56,77.74)
  LAY4 w0.127: 96.83,77.34 97.39,76.78 97.66,76.78 98.74,76.78 99.09,76.78 104.84,71.03 104.84,70.14 104.97,70.02 104.99,70.02 105.12,69.89 105.12,69.64 104.99,69.51 104.97,69.51 104.84,69.38 104.84,69.13 104.97,69 104.99,69 105.12,68.87 105.12,68.62 104.99,68.49 104.97,68.49 104.84,68.37 104.84,68.11 104.97,67.98 104.99,67.98 105.12,67.86 105.12,67.6 104.99,67.48 104.97,67.48 104.84,67.35 104.84,67.1 104.97,66.97 104.99,66.97 105.12,66.84 105.12,66.59 104.99,66.46 104.97,66.46 104.84,66.33 104.84,66.08 104.97,65.95 104.99,65.95 105.12,65.83 105.12,65.57 104.99,65.44 104.97,65.44 104.84,65.32 104.84,65.06 104.97,64.94 104.99,64.94 105.12,64.81 105.12,64.56 104.99,64.43 104.97,64.43 104.84,64.3 104.84,64.05 104.97,63.92 104.99,63.92 105.12,63.79 105.12,63.54 104.99,63.41 104.97,63.41 104.84,63.29 104.84,63.03 104.97,62.9 104.99,62.9 105.12,62.78 105.12,62.52 104.99,62.4 104.97,62.4 104.84,62.27 104.84,62.02 104.97,61.89 104.99,61.89 105.12,61.76 105.12,61.51 104.99,61.38 104.97,61.38 104.84,61.25 104.84,58.25 105.09,58 105.27,58 105.43,58.16 105.61,58.16 105.79,57.98 105.79,57.8 105.63,57.64 105.63,57.46 106.4,56.69 106.9,56.69 108.02,55.57 108.02,55.18 108.15,55.06 109.36,55.06 109.48,54.93 109.48,54.67 109.36,54.55 108.15,54.55 108.02,54.42 108.02,53.75 v2(109.78,52)
M_A_DQ24: length 43.6
  TOP w0.114: CN3.57 107.68,56.22 107.85,56.04 107.85,54.84 107.55,54.54 v2(107.08,54.54) ; U1.A41 98.91,78.75 101.2,76.46 101.2,75.38 102.03,74.55 102.75,74.55 110.25,67.06 110.25,66.74 110.04,66.54 110.04,66.28 110.25,66.08 110.25,65.82 110.04,65.62 110.04,65.37 110.25,65.16 110.25,64.26 110.13,64.14 109.65,64.14 109.52,64.01 109.52,63.78 109.86,63.44 109.86,63.27 106.93,60.33 106.93,58.97 106.71,58.76 v2(106.48,58.76)
  BOTTOM w0.114: v2(106.48,58.76) 106.39,58.67 106.39,57.36 106.52,57.23 106.84,57.23 106.97,57.11 106.97,56.75 106.84,56.62 106.52,56.62 106.39,56.5 106.39,54.54 106.6,54.33 106.6,53.62 107.07,53.15 107.07,52.96 107.24,52.79 107.5,52.79 107.81,53.1 108.49,53.1 108.67,53.27 108.67,53.48 108.56,53.59 108.37,53.59 107.42,54.54 v2(107.08,54.54)
M_A_DQ25: length 43.1
  TOP w0.089: U1.C41 97,78.56 97.29,78.56 97.4,78.46 97.53,78.46
  TOP w0.102: 97.53,78.46 98.73,78.46
  TOP w0.114: CN3.59 v2(107.08,55.96) ; v2(106.48,60.18) 106.48,60.28 106.97,60.78 106.97,61.02 108.17,62.22 108.17,62.22 108.98,63.03 108.98,64.53 109.1,64.64 109.41,64.64 109.52,64.76 109.52,64.99 109.41,65.1 109.1,65.1 108.98,65.21 108.98,65.44 109.1,65.56 109.41,65.56 109.52,65.67 109.52,65.9 109.41,66.01 109.1,66.01 108.98,66.13 108.98,66.36 109.1,66.47 109.41,66.47 109.52,66.59 109.52,66.81 109.41,66.93 109.1,66.93 108.98,67.04 108.98,67.58 102.54,74.03 101.92,74.03 100.9,75.04 100.9,76.29 98.73,78.46
  BOTTOM w0.114: v2(106.48,60.18) 106.91,59.75 106.91,57.98 107.88,57 107.88,56.84 107.63,56.58 107.63,56.42 107.79,56.26 107.95,56.26 108.21,56.52 108.37,56.52 108.53,56.36 108.53,56.19 108.27,55.94 108.27,55.78 108.43,55.61 108.6,55.61 108.85,55.87 109.01,55.87 109.43,55.46 109.43,54.31 109.24,54.12 108.61,54.12 108.4,54.33 108.4,54.49 108.67,54.76 108.67,54.92 108.51,55.08 108.35,55.08 108.08,54.82 107.92,54.82 107.55,55.18 107.55,55.49 v2(107.08,55.96)
M_A_DQ26: length 43.2
  TOP w0.114: v2(103.48,58.76) 104.45,58.76 104.77,59.08 104.77,59.36 104.28,59.85 104.28,60.48 104.95,61.15 104.95,62.06 105.9,63.01 105.9,63.29 105.63,63.56 105.63,63.8 105.75,63.92 105.97,63.92 106.09,64.03 106.09,64.26 105.97,64.37 105.75,64.37 105.63,64.49 105.63,64.72 105.75,64.83 105.97,64.83 106.09,64.94 106.09,65.17 105.97,65.29 105.75,65.29 105.63,65.4 105.63,65.63 105.75,65.74 105.97,65.74 106.09,65.86 106.09,66.09 105.97,66.2 105.75,66.2 105.63,66.32 105.63,66.54 105.75,66.66 105.97,66.66 106.09,66.77 106.09,67 105.97,67.12 105.75,67.12 105.63,67.23 105.63,67.74 99.81,73.57 99.81,75.73 98.65,76.89 97.64,76.89 U1.A45 ; v2(104.08,54.54) 104.68,55.14 CN3.67
  BOTTOM w0.114: v2(103.48,58.76) 103.48,53.67 104.32,52.83 104.32,50.9 104.53,50.7 104.9,50.7 105.13,50.93 105.13,53.48 v2(104.08,54.54)
M_A_DQ27: length 42.8
  TOP w0.089: 98.49,76.66 97.86,76.66 97.66,76.46 97.13,76.46 U1.B46
  TOP w0.114: v2(103.48,60.18) 103.75,60.45 103.75,60.75 104.39,61.39 104.39,62.28 105.1,62.99 105.1,63.5 104.99,63.61 104.48,63.61 104.37,63.73 104.37,63.96 104.48,64.07 104.99,64.07 105.1,64.18 105.1,64.7 104.99,64.82 104.48,64.82 104.37,64.93 104.37,65.16 104.48,65.27 104.99,65.27 105.1,65.39 105.1,67.47 99.54,73.03 99.54,75.61 98.49,76.66 ; CN3.69 v2(104.08,55.96)
  BOTTOM w0.114: v2(104.08,55.96) 104,56.04 104,60.15 104.79,60.94 104.79,61.2 105.35,61.76 105.35,64.04 105.12,64.28 104.16,64.28 104,64.11 104,63.4 104.11,63.28 104.79,63.28 104.9,63.17 104.9,62.94 104.79,62.83 104.11,62.83 104,62.71 104,62.48 104.11,62.37 104.79,62.37 104.9,62.25 104.9,62.03 104.79,61.91 104.11,61.91 104,61.8 104,60.93 103.75,60.68 103.75,60.45 v2(103.48,60.18)
M_A_DQ28: length 44
  TOP w0.114: v2(107.68,58.76) 107.24,59.19 107.24,60.34 108.96,62.05 109.39,62.05 110.79,63.45 110.79,67.25 102.97,75.07 102.24,75.07 101.48,75.83 101.48,76.73 99.18,79.04 97.4,79.04 97.27,78.91 97.07,78.91 96.75,79.23 U1.C40 ; CN3.56 v2(107.98,50.58)
  BOTTOM w0.114: v2(107.98,50.58) 108.53,50.02 109.85,50.02 110.53,50.69 110.53,55.9 108.5,57.93 107.68,58.75 v2(107.68,58.76)
M_A_DQ29: length 43
  TOP w0.114: CN3.58 107.38,50.73 107.56,50.92 107.56,51.58 v2(107.98,52) ; U1.B40 97.23,79.3 99.41,79.3 101.8,76.9 101.8,76.27 102.48,75.59 103.19,75.59 111.33,67.45 111.33,63.23 109.72,61.63 109,61.63 107.68,60.3 v2(107.68,60.18)
  BOTTOM w0.114: v2(107.98,52) 108.36,52 108.58,51.78 109.07,51.78 109.29,51.99 109.29,53.11 109.99,53.81 109.99,55.69 107.24,58.43 107.24,59.75 v2(107.68,60.18)
M_A_DQ30: length 42.7
  TOP w0.089: 97.76,75.66 97.69,75.59 97.38,75.59 96.96,75.17 U1.B48
  TOP w0.114: v2(102.28,60.18) 102.29,60.2 102.29,60.92 103.33,61.95 103.33,67.77 98.98,72.12 98.98,75.1 98.42,75.66 97.76,75.66 ; CN3.68 104.38,51.4 v2(103.78,52)
  BOTTOM w0.114: v2(102.28,60.18) 102.28,60.59 102.65,60.97 102.65,62.03 101.79,62.89 101.79,63.85 102.09,64.15 103.25,64.15 103.46,63.94 103.46,63.6 103.34,63.49 102.74,63.49 102.62,63.37 102.62,63.14 102.74,63.03 103.34,63.03 103.46,62.91 103.46,61.17 102.89,60.6 102.89,52.88 v2(103.78,52)
M_A_DQ31: length 43.1
  TOP w0.089: U1.B47 96.97,75.82 97.42,76.27 97.74,76.27 97.94,76.47 98.34,76.47
  TOP w0.114: v2(102.28,58.76) 102.6,58.44 102.6,56.89 102.19,56.49 102.19,55.96 102.83,55.32 103.06,55.32 103.2,55.46 103.2,56.09 103.03,56.26 103.03,60.92 103.85,61.74 103.85,65.8 103.96,65.91 104.46,65.91 104.57,66.02 104.57,66.25 104.46,66.37 103.96,66.37 103.85,66.48 103.85,66.71 103.96,66.82 104.46,66.82 104.57,66.94 104.57,67.17 104.46,67.28 103.96,67.28 103.85,67.4 103.85,67.98 99.27,72.56 99.27,75.54 98.34,76.47 ; CN3.70 v2(103.78,50.58)
  BOTTOM w0.114: v2(103.78,50.58) 103,51.35 103,51.51 103.18,51.69 103.18,51.85 103.02,52.01 102.86,52.01 102.68,51.83 102.52,51.83 102.28,52.08 v2(102.28,58.76)
M_A_DQ32: length 43.9
  TOP w0.114: CN3.129 v2(83.68,55.96) ; U1.K52 92.84,72.93 92.84,71.62 94.75,69.71 94.75,68.05 90.3,63.6 89.68,62.98 87.97,62.98 86.14,61.16 86.14,60.38 85.5,59.74 84.93,59.74 84.66,59.47 v2(84.28,59.47)
  BOTTOM w0.114: v2(83.68,55.96) 84.15,55.96 84.34,55.78 84.34,54.44 84.79,53.99 84.79,53.21 84.53,52.96 84.11,52.96 83.78,53.29 83.36,53.29 82.73,52.66 81.86,52.66 81.57,52.95 81.57,57.25 81.12,57.7 81.12,62.06 81.4,62.34 83.11,62.34 83.7,61.76 83.7,60.05 v2(84.28,59.47)
M_A_DQ33: length 44.7
  TOP w0.102: 93.13,72.8 93.36,73.03 93.36,73.22 93.03,73.55 U1.K51
  TOP w0.114: CN3.131 83.08,55.7 83.22,55.56 83.22,55 v2(83.68,54.54) ; 93.13,72.8 93.13,71.67 95.29,69.51 95.29,69.15 95.53,68.91 95.53,68.1 93.18,65.75 93.18,65.75 89.88,62.44 88.17,62.44 86.57,60.85 86.57,59.8 86.27,59.5 86.11,59.5 85.97,59.64 85.81,59.64 85.65,59.48 85.65,59.32 85.79,59.18 85.79,59.02 85.53,58.76 v2(84.28,58.76)
  BOTTOM w0.114: v2(84.28,58.76) 84.58,58.45 84.58,58.03 84.29,57.74 83.86,57.74 83.17,58.43 83.17,58.81 83.5,59.13 83.5,59.47 83.17,59.8 83.17,61.54 82.91,61.8 82.13,61.8 81.82,61.49 81.82,60.93 81.39,60.49 81.39,58 81.98,57.42 81.98,53.58 82.25,53.3 82.54,53.3 83.21,53.97 83.21,54.08 v2(83.68,54.54)
M_A_DQ34: length 44.7
  TOP w0.102: U1.T52 90.11,72.78 90.11,72.49 90.24,72.37 90.24,71.68
  TOP w0.114: 90.24,71.68 90.24,70.57 86.97,67.3 85.43,67.3 84.87,66.74 79.67,66.74 79.56,66.62 79.56,66.07 79.45,65.96 79.22,65.96 79.1,66.07 79.1,66.62 78.99,66.74 78.62,66.74 78.37,66.49 78.37,66.33 78.57,66.12 78.57,65.96 78.41,65.8 78.25,65.8 78.04,66 77.88,66 77.49,65.61 77.49,65.46 77.98,64.97 77.98,64.81 77.82,64.64 77.66,64.64 77.17,65.13 77.01,65.13 76.63,64.76 76.63,64.08 76.75,63.97 76.95,63.97 77.06,63.85 77.06,63.62 76.95,63.51 76.75,63.51 76.63,63.4 76.63,63.17 76.75,63.05 76.95,63.05 77.06,62.94 77.06,62.71 76.95,62.59 76.75,62.59 76.63,62.48 76.63,62.09 76.75,61.97 77.04,61.97 77.16,61.86 77.16,61.63 77.04,61.51 76.75,61.51 76.63,61.4 76.63,60.88 76.79,60.72 76.99,60.72 77.59,61.32 77.59,61.99 77.72,62.12 77.93,62.12 78.02,62.03 78.02,61.77 78.11,61.67 78.7,61.67 v2(79.48,60.89) ; CN3.141 v2(80.08,55.96)
  BOTTOM w0.114: v2(79.48,60.89) 78.88,60.89 78.7,60.71 78.7,58.53 78.43,58.26 78.43,57.57 78.55,57.46 78.91,57.46 79.02,57.34 79.02,57.12 78.91,57 78.55,57 78.43,56.89 78.43,56.66 78.55,56.54 79.24,56.54 79.35,56.43 79.35,56.2 79.24,56.09 78.55,56.09 78.43,55.97 78.43,55.52 78.65,55.3 79.42,55.3 v2(80.08,55.96)
M_A_DQ35: length 44.5
  TOP w0.102: 89.82,73.24 90.11,73.54 U1.T51
  TOP w0.114: 89.82,73.24 89.82,73 89.92,72.9 89.92,72.4 90.03,72.28 90.03,72 89.54,71.51 89.54,71.31 89.8,71.06 89.8,70.87 86.75,67.82 85.21,67.82 84.65,67.26 78.4,67.26 76.11,64.97 76.11,64.03 76,63.92 75.31,63.92 75.2,63.8 75.2,61.39 75.31,61.27 75.54,61.27 75.65,61.39 75.65,63.35 75.77,63.46 76,63.46 76.11,63.35 76.11,60.43 76.69,59.85 77.14,59.85 77.77,60.48 77.77,60.77 78.15,61.15 78.46,61.15 79.43,60.18 v2(79.48,60.18) ; v2(80.08,54.54) 79.48,55.14 CN3.143
  BOTTOM w0.114: v2(79.48,60.18) 79.04,59.75 79.04,58.1 79.14,58 79.44,58 79.55,57.88 79.55,57.2 80.49,56.27 80.49,54.95 v2(80.08,54.54)
M_A_DQ36: length 45
  TOP w0.114: CN3.130 v2(83.38,50.58) ; U1.L51 92.41,73.34 92.41,73.05 92.25,72.89 92.25,71.44 93.66,70.03 93.66,68.44 89.26,64.04 87.49,64.04 85.1,61.65 85.1,61.33 84.66,60.89 v2(84.28,60.89)
  BOTTOM w0.114: v2(83.38,50.58) 82.11,49.31 81.06,49.31 79.08,51.29 79.08,52.9 77.46,54.52 77.46,61.14 79.2,62.88 83.32,62.88 84.28,61.92 v2(84.28,60.89)
M_A_DQ37: length 43.6
  TOP w0.114: U1.L53 92.54,71.53 94.19,69.88 94.19,68.23 89.46,63.5 87.75,63.5 85.62,61.37 85.62,60.76 85.04,60.18 v2(84.28,60.18) ; CN3.132 82.78,51.4 v2(83.38,52)
  BOTTOM w0.114: v2(84.28,60.18) 84.76,60.67 84.76,62.2 83.5,63.46 82.98,63.46 82.73,63.71 82.73,64.07 83.02,64.36 84.6,64.36 85.44,63.52 85.44,60.48 85.17,60.21 85.17,57.68 84.91,57.42 84.91,54.86 85.32,54.46 85.32,52.9 84.41,52 v2(83.38,52)
M_A_DQ38: length 45.2
  TOP w0.114: v2(79.48,58.76) 79.86,58.76 80.04,58.94 80.04,61.4 80,61.44 80,61.62 79.41,62.21 79.41,64.69 79.3,64.81 79.07,64.81 78.96,64.69 78.96,62.32 78.84,62.21 78.61,62.21 78.5,62.32 78.5,62.53 78.38,62.64 77.7,62.64 77.58,62.76 77.58,63.9 77.7,64.02 77.93,64.02 78.04,63.9 78.04,63.22 78.16,63.1 78.38,63.1 78.5,63.22 78.5,65.15 78.61,65.27 79.78,65.27 80.73,66.22 85.08,66.22 85.64,66.78 87.18,66.78 90.64,70.24 90.64,72.24 90.31,72.57 90.31,72.9 90.47,73.05 90.47,73.35 U1.R51 ; CN3.140 v2(80.38,50.58)
  BOTTOM w0.114: v2(79.48,58.76) 79.91,58.76 80.13,58.54 80.13,57.34 80.85,56.62 80.85,54.38 80.49,54.02 80.49,53.32 80.79,53.02 80.79,52.3 81.2,51.88 81.2,51.4 v2(80.38,50.58)
M_A_DQ39: length 44.3
  TOP w0.114: U1.R53 91.08,72.25 91.08,70.77 91.55,70.31 91.55,69.87 91.26,69.59 90.73,69.59 87.4,66.26 85.86,66.26 85.3,65.7 80.94,65.7 79.93,64.69 79.93,62.42 80.56,61.79 80.56,60.29 v2(80.68,60.18) ; v2(80.38,52) 79.78,51.4 CN3.142
  BOTTOM w0.114: v2(80.38,52) 80,51.62 79.8,51.62 79.6,51.82 79.6,53.14 79.31,53.43 79.31,53.6 79.64,53.93 79.64,54.09 79.48,54.26 79.32,54.26 78.98,53.92 78.82,53.92 78.66,54.08 78.66,54.27 78.85,54.46 78.85,54.62 78.69,54.78 78.53,54.78 78.31,54.56 78.17,54.56 77.87,54.87 77.87,61 78.19,61.32 78.95,61.32 79.06,61.43 79.06,61.68 78.92,61.82 78.92,62.05 79.2,62.33 79.88,62.33 80.11,62.1 80.11,61.37 80.23,61.25 80.48,61.25 80.6,61.14 80.6,60.91 80.48,60.8 80.23,60.8 80.11,60.68 80.11,60.34 80.27,60.18 v2(80.68,60.18)
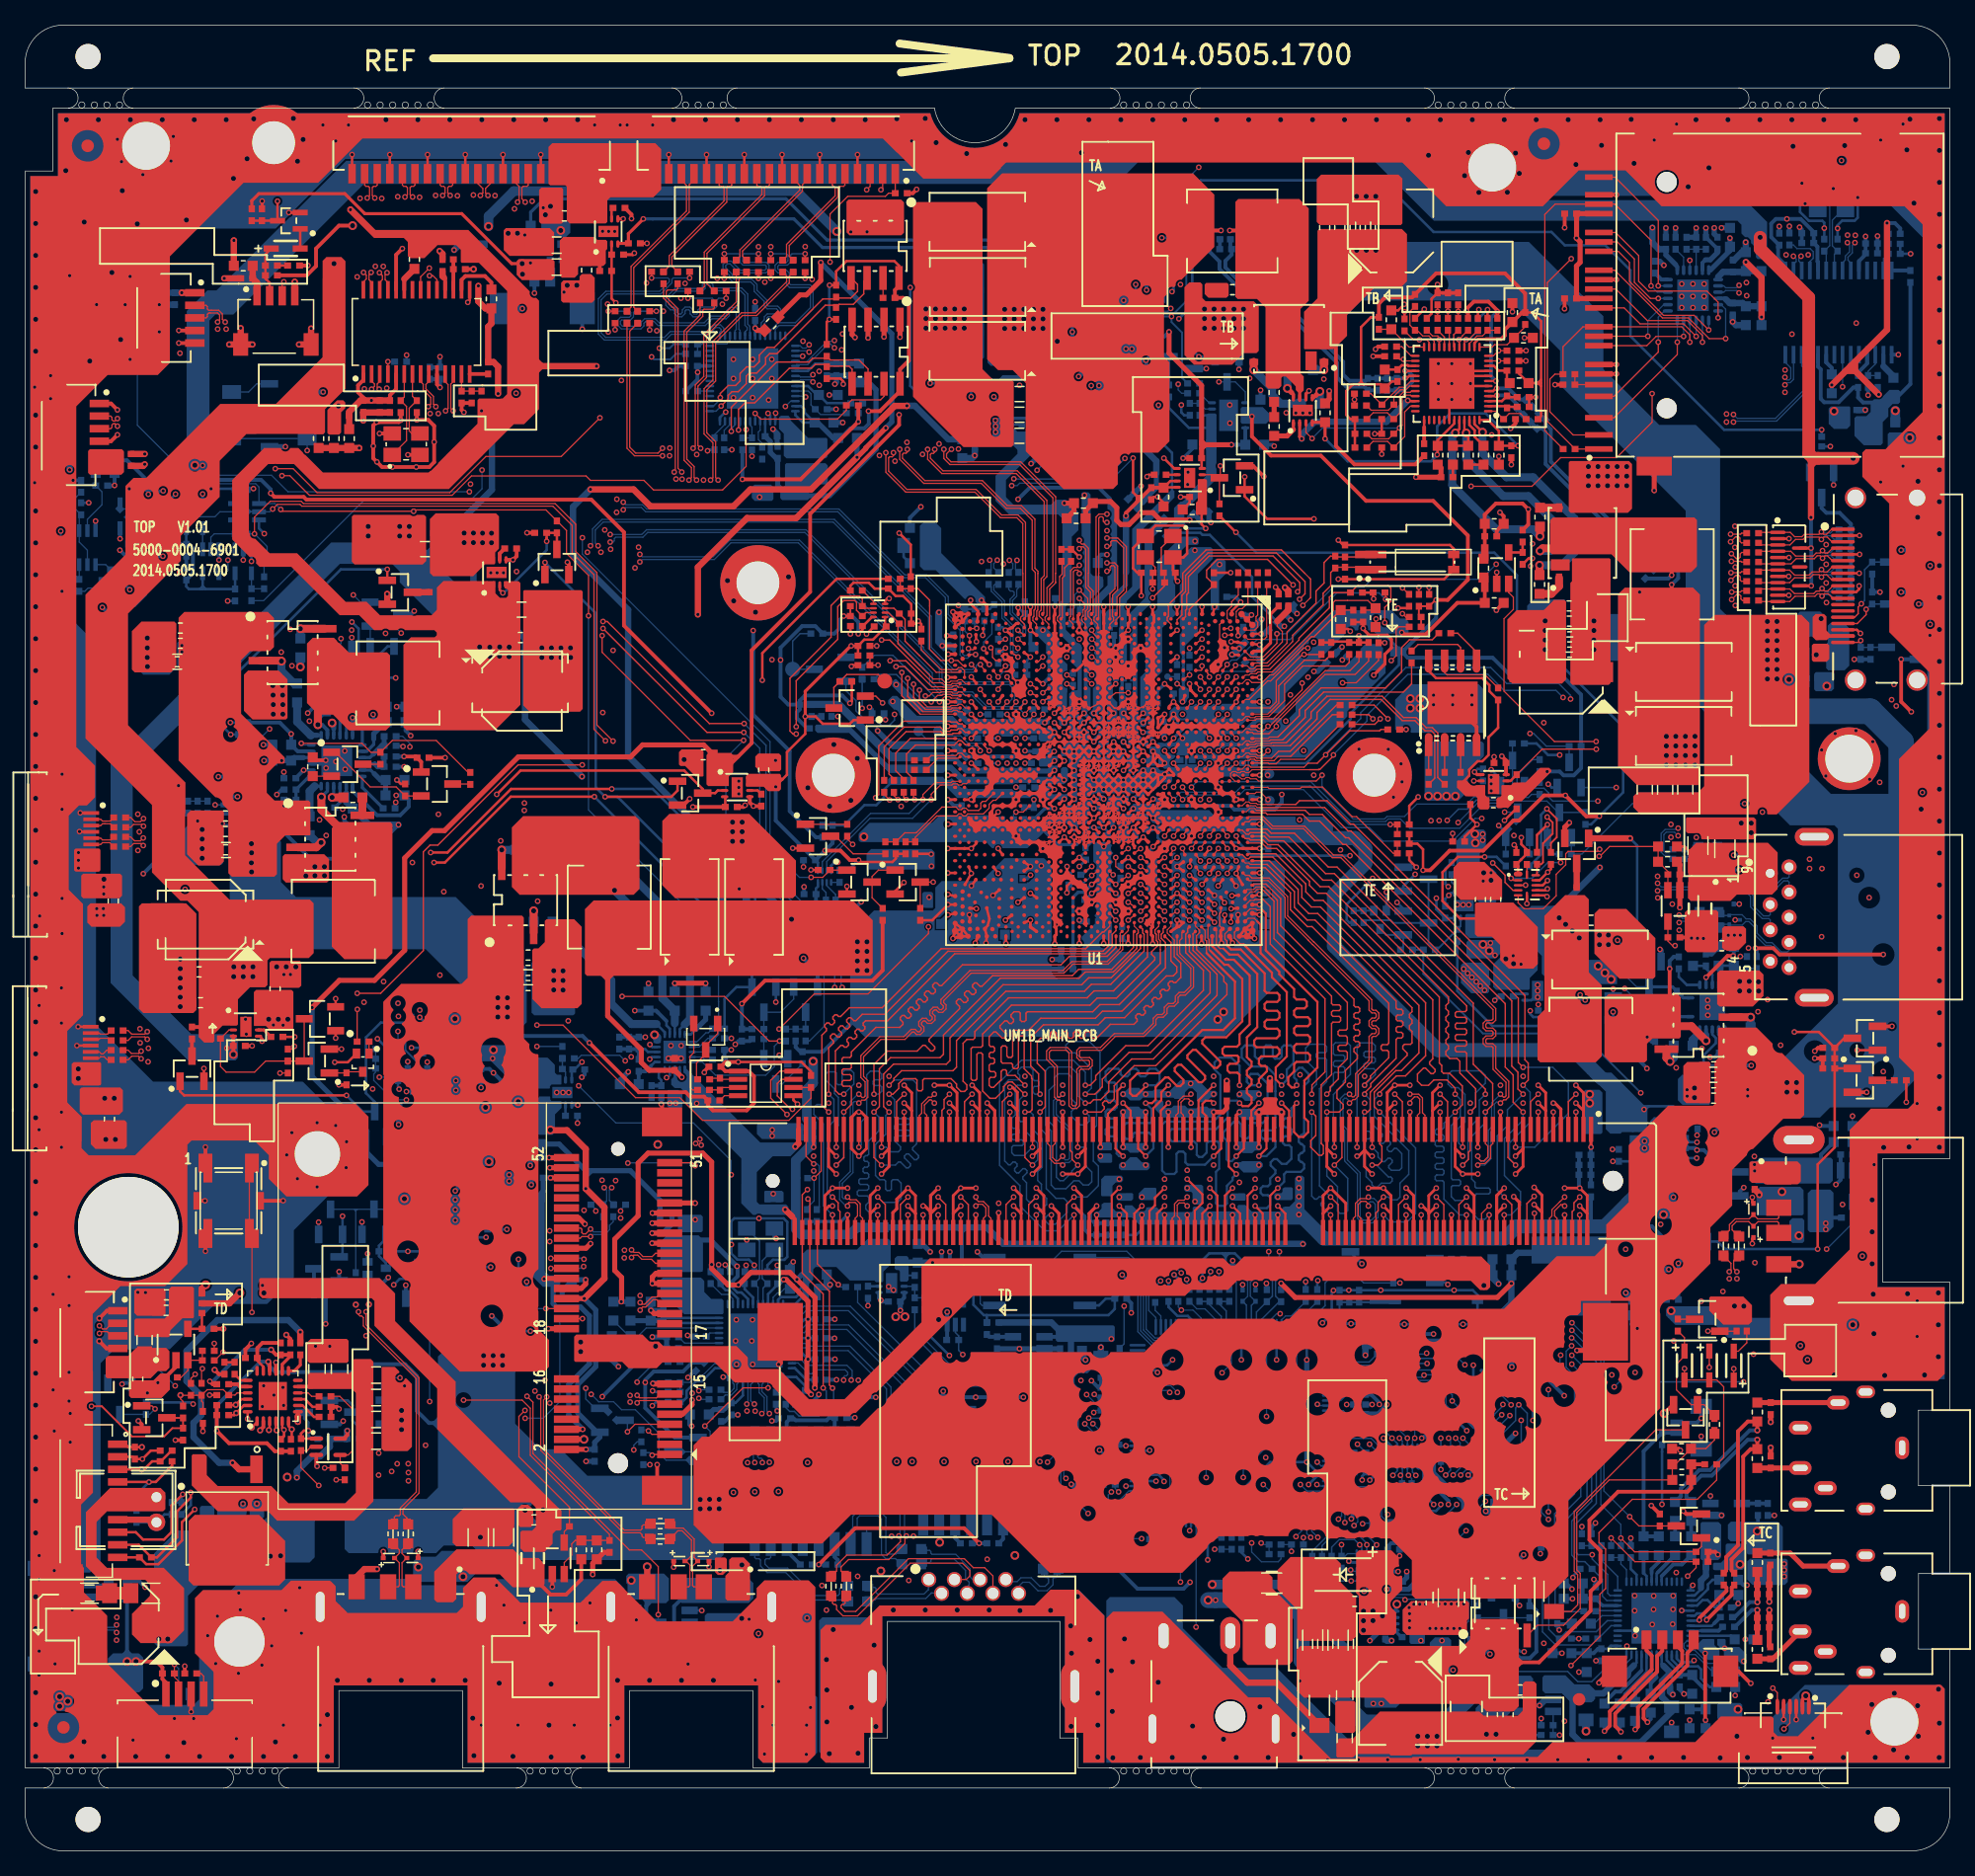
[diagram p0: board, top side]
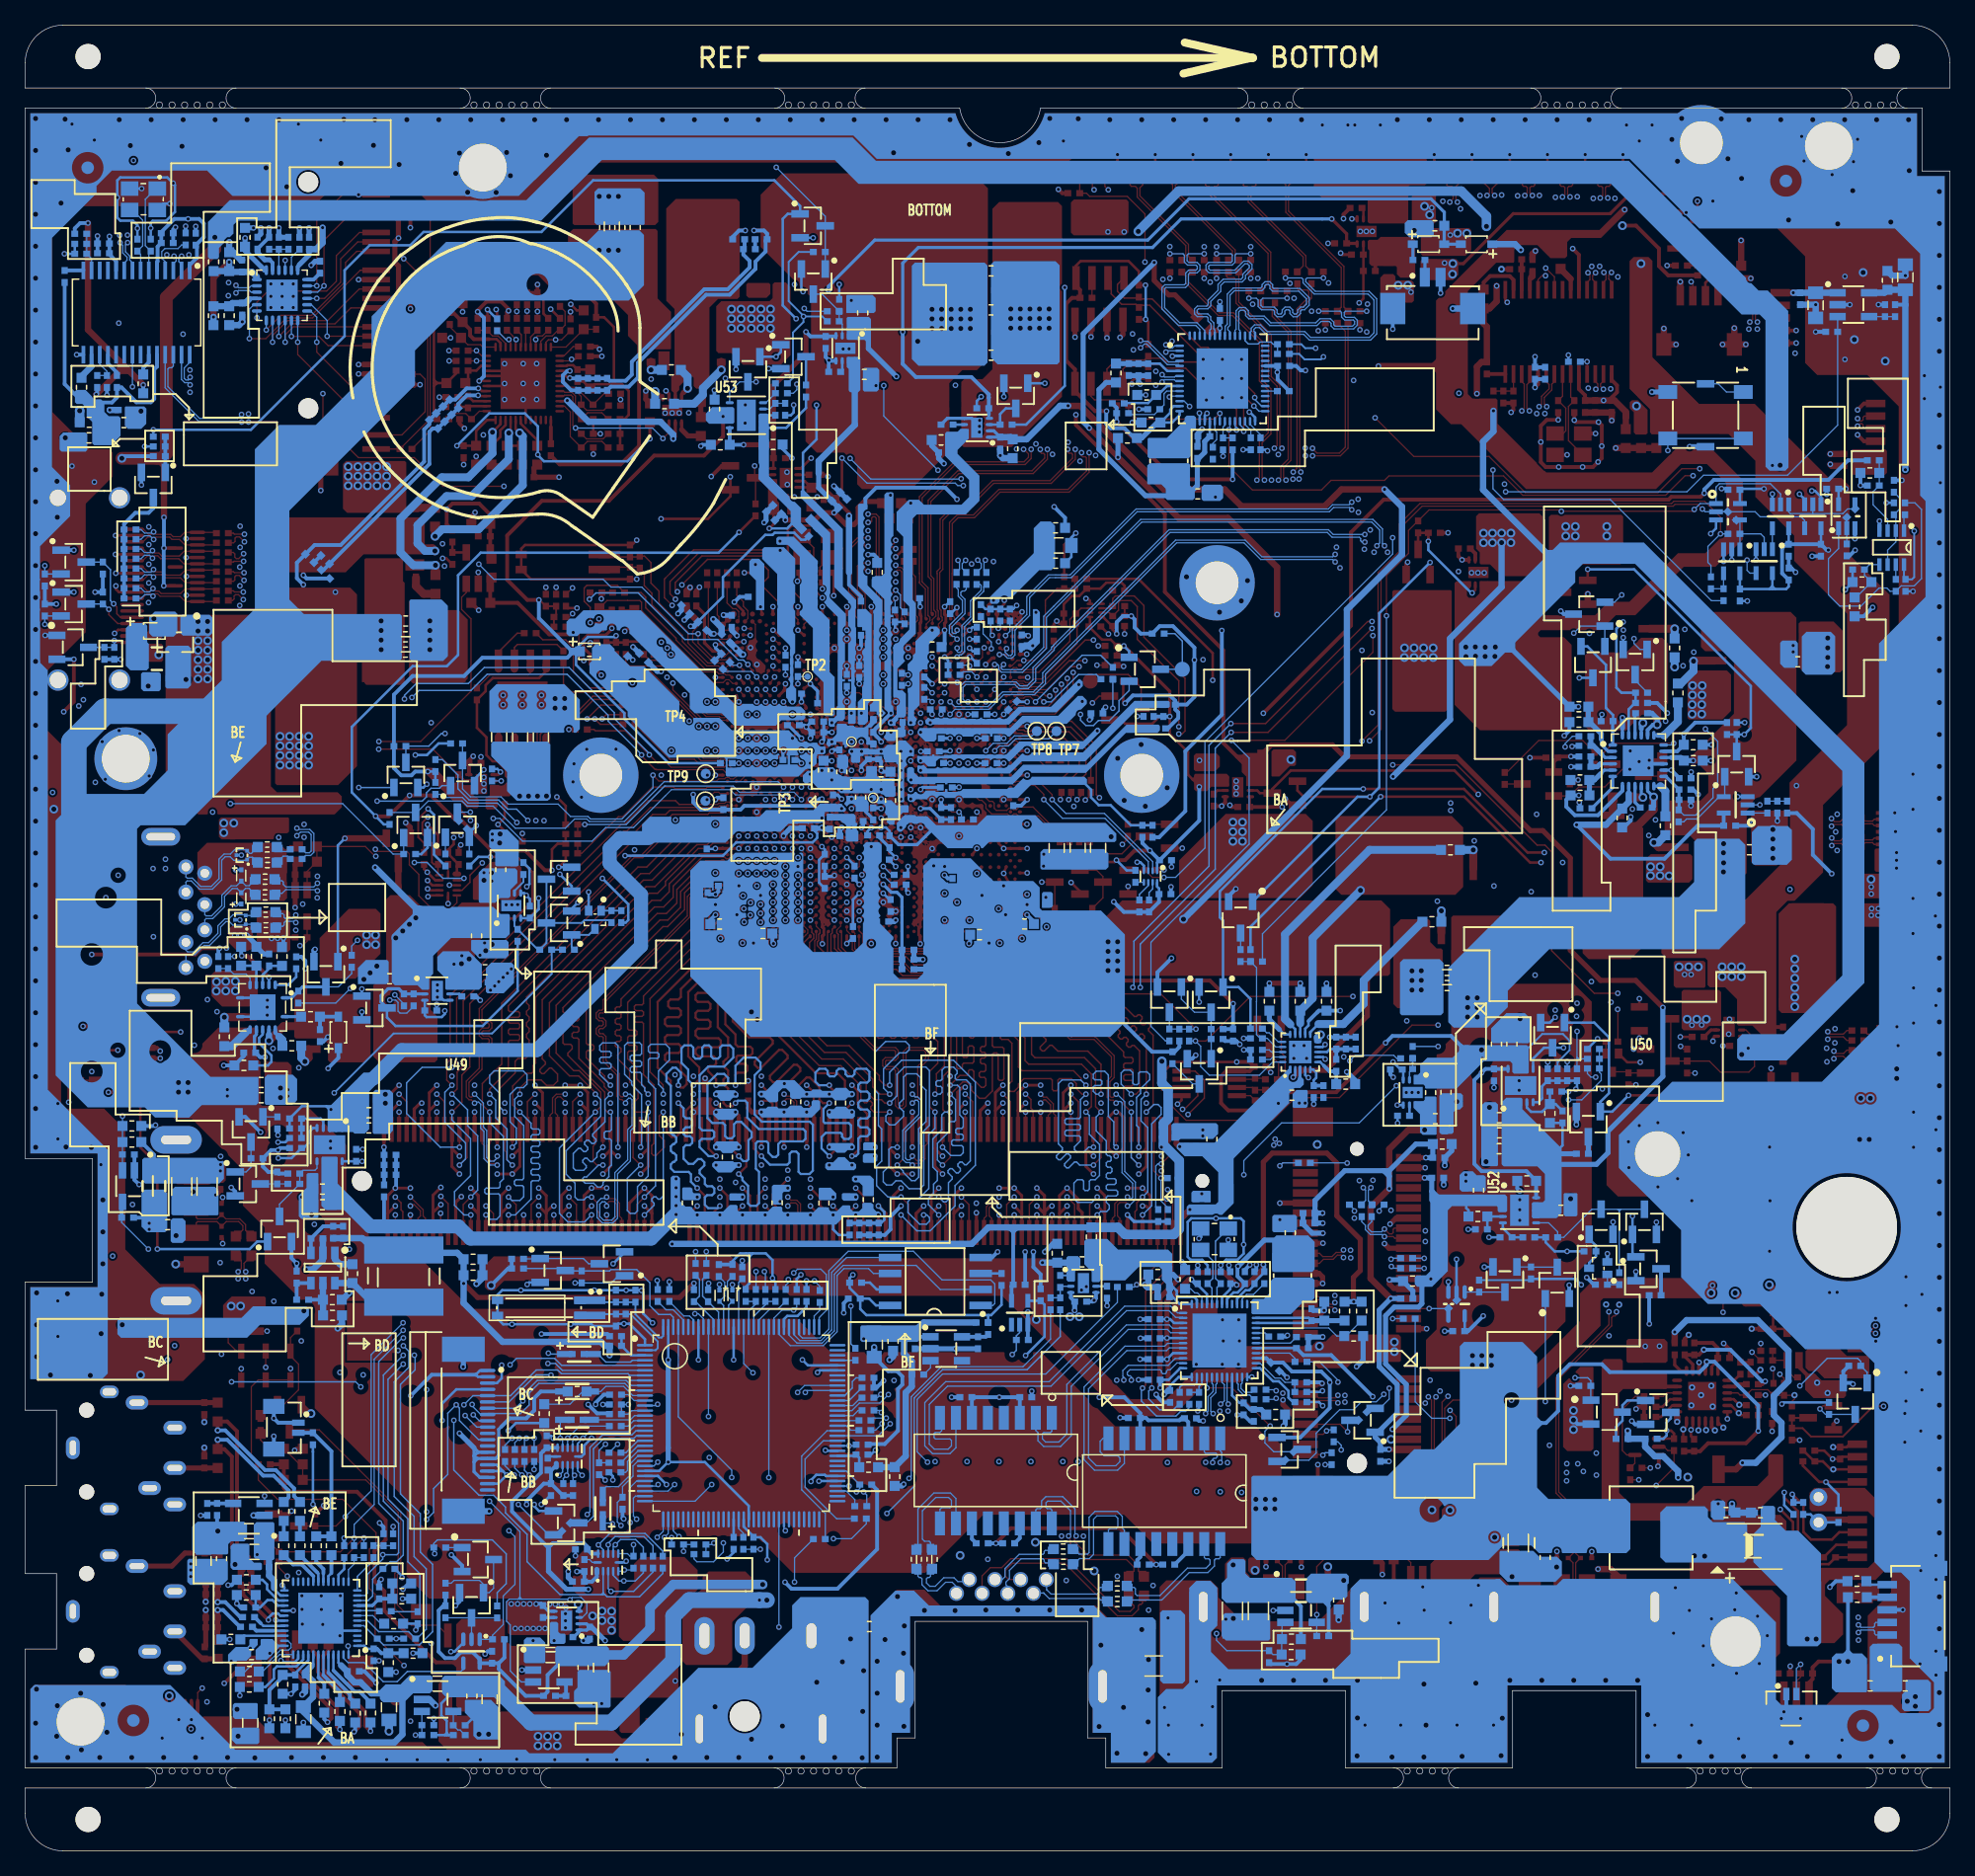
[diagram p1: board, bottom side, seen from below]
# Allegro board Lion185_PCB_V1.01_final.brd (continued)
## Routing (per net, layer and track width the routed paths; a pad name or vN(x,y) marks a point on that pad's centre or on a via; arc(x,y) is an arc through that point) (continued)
M_A_DQ40: length 40.9
  TOP w0.114: CN3.147 v2(78.28,58.76) ; v2(90.58,75.44) U1.T47
  LAY3 w0.127: v2(90.58,75.44) 90.15,75.01 90.15,73.35 90.48,73.02 90.48,71.07 89.69,70.28 89.69,69.15 84.18,63.64 84.18,63.03 84.05,62.9 83.33,62.9 83.2,62.78 83.2,62.52 83.33,62.4 84.05,62.4 84.18,62.27 84.18,62.07 84.01,61.9 82.61,61.9 82.48,61.78 82.48,61.52 82.61,61.4 83.75,61.4 83.85,61.3 83.85,60.79 83.69,60.63 82.99,60.63 82.87,60.51 82.87,60.25 82.99,60.13 83.75,60.13 83.85,60.03 83.85,59.77 83.69,59.62 82.99,59.62 82.87,59.49 82.87,59.24 82.99,59.11 83.75,59.11 83.85,59.01 83.85,58.76 83.69,58.6 82.99,58.6 82.87,58.47 82.87,58.22 82.99,58.09 83.75,58.09 83.96,57.88 83.96,57.38 83.67,57.08 83.17,57.08 83.05,57.2 83.05,57.55 82.92,57.68 82.67,57.68 82.54,57.55 82.54,57.22 82.41,57.08 78.34,57.08 78.1,57.33 78.1,58.58 v2(78.28,58.76)
M_A_DQ41: length 39.7
  TOP w0.114: CN3.149 77.68,59.58 v2(78.28,60.18) ; v2(90.58,76.15) U1.T45
  LAY3 w0.127: v2(78.28,60.18) 78.68,60.18 78.82,60.04 78.82,57.76 78.96,57.62 79.66,57.62 79.79,57.75 79.79,58.52 79.91,58.65 80.17,58.65 80.29,58.52 80.29,57.74 80.42,57.62 81.83,57.62 81.95,57.74 81.95,58.03 81.83,58.15 81.12,58.15 81,58.28 81,58.53 81.12,58.66 81.82,58.66 81.95,58.79 81.95,59.05 81.82,59.17 81.19,59.17 81.07,59.3 81.07,59.55 81.19,59.68 81.82,59.68 81.95,59.81 81.95,60.06 81.82,60.19 81.17,60.19 81.04,60.32 81.04,60.57 81.17,60.7 81.82,60.7 81.95,60.82 81.95,61.08 81.82,61.2 81.21,61.2 81.09,61.33 81.09,61.59 81.21,61.71 81.82,61.71 81.95,61.84 81.95,62.28 89.15,69.48 89.15,70.32 90.15,71.32 90.15,72.01 90.16,72.02 90.16,72.91 89.94,73.14 89.94,75.51 v2(90.58,76.15)
M_A_DQ42: length 39.7
  TOP w0.114: U1.Y40 v2(88.68,79.71) ; CN3.157 v2(75.28,58.76)
  LAY3 w0.089: 88.12,73.58 88.12,73.71 88.08,73.74 88.08,78.68 88.24,78.83 88.24,79.28 v2(88.68,79.71)
  LAY3 w0.102: 88.12,71.88 88.12,73.58
  LAY3 w0.127: v2(75.28,58.76) 74.86,58.76 74.66,58.96 74.66,61.2 74.78,61.33 74.97,61.33 75.1,61.45 75.1,61.71 74.97,61.83 74.78,61.83 74.66,61.96 74.66,63.38 74.93,63.65 75.11,63.65 75.3,63.47 75.48,63.47 75.65,63.65 75.65,63.83 75.47,64.01 75.47,64.19 75.65,64.37 75.83,64.37 76.01,64.19 76.19,64.19 76.37,64.37 76.37,64.55 76.19,64.73 76.19,64.91 76.88,65.6 77.06,65.6 77.97,64.69 78.15,64.69 78.33,64.87 78.33,65.05 77.42,65.96 77.42,66.14 77.67,66.39 78.06,66.39 78.18,66.26 78.18,65.91 78.31,65.79 78.56,65.79 78.69,65.91 78.69,66.26 78.82,66.39 79.07,66.39 79.2,66.26 79.2,65.91 79.33,65.79 79.58,65.79 79.71,65.91 79.71,66.26 79.83,66.39 80.09,66.39 80.22,66.26 80.22,65.91 80.34,65.79 80.6,65.79 80.72,65.91 80.72,66.26 80.85,66.39 82.04,66.39 87.25,71.61 87.84,71.61 88.12,71.88
M_A_DQ43: length 40.8
  TOP w0.114: U1.V41 v2(88.68,79) ; CN3.159 74.68,59.58 v2(75.28,60.18)
  LAY3 w0.089: v2(88.68,79) 88.28,78.6 88.28,73.82 88.35,73.75
  LAY3 w0.102: 88.35,73.75 88.35,71.55
  LAY3 w0.127: v2(75.28,60.18) 75.7,60.6 75.7,60.95 76.19,61.44 76.19,61.62 75.37,62.43 75.37,62.61 75.55,62.79 75.73,62.79 76.54,61.98 76.72,61.98 76.9,62.16 76.9,62.34 76.09,63.15 76.09,63.33 76.27,63.51 76.45,63.51 77.26,62.7 77.44,62.7 77.62,62.88 77.62,63.05 76.81,63.87 76.81,64.05 76.99,64.23 77.17,64.23 77.98,63.41 78.16,63.41 78.68,63.93 79.04,63.93 79.16,64.06 79.16,65.06 79.29,65.19 79.54,65.19 79.67,65.06 79.67,64.06 79.8,63.93 80.33,63.93 80.63,64.23 80.63,64.41 80.32,64.72 80.32,64.9 80.5,65.08 80.68,65.08 80.99,64.77 81.17,64.77 81.44,65.04 81.44,65.21 81.25,65.39 81.25,65.57 81.43,65.75 81.63,65.75 81.8,65.58 81.98,65.58 85.82,69.42 86.21,69.42 88.35,71.55
M_A_DQ44: length 40.8
  TOP w0.114: v2(90.58,74.73) U1.T48 ; CN3.146 v2(78.58,50.58)
  LAY3 w0.127: v2(78.58,50.58) 78.58,50.25 78.83,50 84.07,50 84.27,50.21 84.27,52.27 84.42,52.42 85.12,52.42 85.25,52.55 85.25,52.8 85.12,52.93 84.37,52.93 84.27,53.03 84.27,53.29 84.42,53.43 85.12,53.43 85.25,53.56 85.25,53.82 85.12,53.94 84.37,53.94 84.27,54.05 84.27,54.3 84.39,54.42 85.12,54.42 85.25,54.55 85.25,54.8 85.12,54.93 84.4,54.93 84.27,55.06 84.27,55.98 85.25,56.96 85.25,63.21 90.75,68.71 90.75,70.25 91.12,70.63 91.12,74.19 v2(90.58,74.73)
M_A_DQ45: length 41
  TOP w0.114: U1.T50 v2(90.58,74.02) ; CN3.148 77.98,51.4 v2(78.58,52)
  LAY3 w0.127: v2(78.58,52) 78.19,52.39 78.19,53.71 78.46,53.99 79.45,53.99 79.58,54.11 79.58,54.37 79.45,54.49 78.31,54.49 78.19,54.62 78.19,54.88 78.31,55 79.45,55 79.58,55.13 79.58,55.38 79.45,55.51 78.31,55.51 78.19,55.64 78.19,56.39 78.35,56.55 80.67,56.55 80.8,56.42 80.8,55.77 80.92,55.64 81.18,55.64 81.3,55.77 81.3,56.42 81.43,56.55 84.08,56.55 84.72,57.18 84.72,63.43 90.22,68.93 90.22,70.26 90.85,70.89 90.85,73.75 v2(90.58,74.02)
M_A_DQ46: length 40.9
  TOP w0.114: CN3.158 74.98,51.4 v2(74.38,52) ; U1.Y42 v2(87.68,78.29)
  LAY3 w0.089: 87.28,73.71 87.28,77.89 v2(87.68,78.29)
  LAY3 w0.127: v2(74.38,52) 73.96,52.41 73.96,52.77 73.83,52.9 73.68,52.9 73.56,53.02 73.56,53.28 73.68,53.41 73.83,53.41 73.96,53.53 73.96,53.79 73.83,53.91 73.68,53.91 73.56,54.04 73.56,54.29 73.68,54.42 73.83,54.42 73.96,54.55 73.96,54.8 73.83,54.93 73.68,54.93 73.56,55.06 73.56,55.31 73.68,55.44 73.83,55.44 73.96,55.56 73.96,55.82 73.83,55.95 73.68,55.95 73.56,56.07 73.56,56.33 73.68,56.45 73.83,56.45 73.96,56.58 73.96,56.98 73.83,57.11 73.7,57.11 73.57,57.24 73.57,57.49 73.7,57.62 73.83,57.62 73.96,57.75 73.96,63.43 77.45,66.92 81.81,66.92 87.28,72.39 87.28,73.71
M_A_DQ47: length 40.8
  TOP w0.114: v2(87.68,79.71) U1.AB40 ; CN3.160 v2(74.38,50.58)
  LAY3 w0.089: v2(87.68,79.71) 87.26,79.29 87.26,78.13 87.09,77.97 87.09,77.86 87.09,73.81 86.95,73.66
  LAY3 w0.127: 86.95,73.66 86.95,72.81 81.59,67.46 77.23,67.46 73.02,63.25 73.02,62.69 73.15,62.56 73.3,62.56 73.43,62.43 73.43,62.18 73.3,62.05 73.15,62.05 73.02,61.93 73.02,51.93 v2(74.38,50.58)
M_A_DQ48: length 40.2
  TOP w0.114: CN3.163 v2(73.48,58.76) ; U1.V45 v2(88.68,76.86)
  LAY4 w0.102: v2(88.68,76.86) 89.31,76.23 89.31,74.67 89.51,74.47 89.51,73.74 90.26,73
  LAY4 w0.127: 90.26,73 90.26,70.35 81.25,61.34 81.25,58.13 80.72,57.6 79.91,57.6 79.78,57.47 79.78,57.01 79.65,56.88 79.4,56.88 79.27,57.01 79.27,57.47 79.15,57.6 78.89,57.6 78.76,57.47 78.76,57.01 78.64,56.88 78.38,56.88 78.26,57.01 78.26,57.47 78.13,57.6 77.88,57.6 77.75,57.47 77.75,57.01 77.62,56.88 77.37,56.88 77.24,57.01 77.24,57.73 77.11,57.85 76.86,57.85 76.73,57.73 76.73,57.01 76.61,56.88 76.35,56.88 76.22,57.01 76.22,57.73 76.1,57.85 75.84,57.85 75.72,57.73 75.72,57.01 75.59,56.88 75.34,56.88 75.21,57.01 75.21,57.47 75.08,57.6 74.63,57.6 v2(73.48,58.76)
M_A_DQ49: length 41.5
  TOP w0.114: v2(73.48,60.18) 73.05,59.75 73.05,59.07 72.88,58.89 CN3.165 ; v2(88.68,76.15) U1.V47
  LAY4 w0.102: 90.02,72.36 90.02,72.95 89.31,73.66 89.31,74.38 89.11,74.59 89.11,75.72 v2(88.68,76.15)
  LAY4 w0.127: 90.02,72.36 90.02,70.91 80.18,61.07 80.18,60.91 80.06,60.78 79.99,60.78 79.87,60.65 79.87,60.4 79.99,60.27 80.06,60.27 80.18,60.15 80.18,59.89 80.06,59.77 79.99,59.77 79.87,59.64 79.87,59.38 79.99,59.26 80.06,59.26 80.18,59.13 80.18,58.49 79.85,58.16 79.26,58.16 79.02,58.39 78.75,58.39 78.51,58.16 77.66,58.16 77.47,58.35 77.47,59.25 77.14,59.58 77.14,59.76 77.76,60.38 77.76,60.56 77.58,60.74 77.4,60.74 76.78,60.12 76.6,60.12 76.42,60.3 76.42,60.48 77.04,61.1 77.04,61.28 76.86,61.46 76.68,61.46 76.06,60.84 75.88,60.84 75.18,61.55 74.84,61.55 74.36,61.06 74.36,60.88 74.8,60.44 74.8,60.26 74.62,60.08 74.44,60.08 74,60.52 73.82,60.52 v2(73.48,60.18)
M_A_DQ50: length 41.5
  TOP w0.114: CN3.175 v2(69.88,58.76) ; v2(86.69,74.73) U1.AD48
  LAY4 w0.127: v2(86.69,74.73) 85.19,74.73 83.87,73.41 82.86,73.41 82.73,73.28 82.73,72.57 82.61,72.44 82.35,72.44 82.22,72.57 82.22,73.28 82.1,73.41 81.74,73.41 81.18,72.85 81.18,72.67 81.42,72.44 81.42,72.26 81.24,72.08 81.06,72.08 80.82,72.31 80.64,72.31 76.48,68.15 72.5,68.15 67.9,63.55 67.9,63.2 68.03,63.07 68.61,63.07 68.74,62.94 68.74,62.69 68.61,62.56 68.03,62.56 67.9,62.43 67.9,62.08 68.03,61.95 68.16,61.95 68.29,61.82 68.29,61.57 68.16,61.44 68.03,61.44 67.9,61.32 67.9,61.06 68.03,60.94 68.16,60.94 68.29,60.81 68.29,60.55 68.16,60.43 68.03,60.43 67.9,60.3 67.9,60.05 68.03,59.92 68.16,59.92 68.29,59.79 68.29,59.54 68.16,59.41 68.03,59.41 67.9,59.28 67.9,59.03 68.03,58.9 68.16,58.9 68.29,58.78 68.29,58.52 68.16,58.4 67.63,58.4 67.3,58.07 67.3,57.29 67.62,56.97 68.41,56.97 69.6,58.16 69.6,58.48 v2(69.88,58.76)
M_A_DQ51: length 41.5
  TOP w0.114: v2(69.88,60.18) 69.28,59.58 CN3.177 ; v2(86.69,74.02) U1.AD50
  LAY4 w0.127: v2(86.69,74.02) 85.07,74.02 82.61,71.57 80.71,71.57 80.17,71.03 80.17,70.85 81.16,69.85 81.16,69.67 80.98,69.49 80.8,69.49 79.81,70.49 79.63,70.49 79.45,70.31 79.45,70.13 80.44,69.13 80.44,68.95 80.26,68.77 80.08,68.77 79.09,69.77 78.91,69.77 78.73,69.59 78.73,69.41 79.72,68.41 79.72,68.23 79.55,68.05 79.37,68.05 78.37,69.05 78.19,69.05 77.94,68.8 77.94,68.61 78.72,67.83 78.72,67.65 78.54,67.47 78.36,67.47 77.57,68.26 77.4,68.26 76.69,67.55 72.66,67.55 68.93,63.82 68.93,63.54 69.27,63.2 69.27,60.4 69.49,60.18 v2(69.88,60.18)
M_A_DQ52: length 39.5
  TOP w0.114: v2(88.68,74.73) U1.V48 ; CN3.164 73.18,51.4 v2(72.58,52)
  LAY4 w0.102: v2(88.68,74.73) 89.11,74.3 89.11,73.58
  LAY4 w0.127: v2(72.58,52) 73.07,52.49 73.83,53.25 73.83,53.89 73.7,54.01 73.49,54.01 73.36,54.14 73.36,54.4 73.49,54.52 73.7,54.52 73.83,54.65 73.83,54.9 73.7,55.03 73.49,55.03 73.36,55.16 73.36,55.41 73.49,55.54 73.7,55.54 73.83,55.67 73.83,55.92 73.7,56.05 73.49,56.05 73.36,56.17 73.36,56.43 73.49,56.55 73.7,56.55 73.83,56.68 73.83,57.26 73.07,58.02 73.07,61.05 74.19,62.18 80.34,62.18 89.11,70.94 89.11,73.58
M_A_DQ53: length 41.2
  TOP w0.114: U1.V50 v2(88.68,74.02) ; CN3.166 v2(72.58,50.58)
  LAY4 w0.127: v2(88.68,74.02) 88.68,71.27 80.14,62.73 73.96,62.73 72.69,61.46 72.69,58.51 72.02,57.84 72.02,57.27 72.14,57.14 72.67,57.14 72.79,57.01 72.79,56.76 72.67,56.63 72.14,56.63 72.02,56.5 72.02,56.25 72.14,56.12 72.67,56.12 72.79,56 72.79,55.74 72.67,55.61 72.14,55.61 72.02,55.49 72.02,55.23 72.14,55.11 72.67,55.11 72.79,54.98 72.79,54.73 72.67,54.6 72.14,54.6 72.02,54.47 72.02,54.22 72.14,54.09 72.67,54.09 72.79,53.96 72.79,53.71 72.67,53.58 72.17,53.58 72.02,53.43 72.02,51.14 v2(72.58,50.58)
M_A_DQ54: length 41.4
  TOP w0.114: U1.AB44 v2(87.68,77.58) ; CN3.174 v2(70.18,50.58)
  LAY4 w0.089: 86.79,73.58 87.09,73.89 87.09,76.99 v2(87.68,77.58)
  LAY4 w0.127: v2(70.18,50.58) 69.5,51.26 69.5,57.19 70.35,58.04 70.35,61.2 69.86,61.68 69.86,63.86 72.93,66.93 79.17,66.93 85.83,73.58 86.79,73.58
M_A_DQ55: length 42.2
  TOP w0.114: CN3.176 69.58,51.4 v2(70.18,52) ; v2(87.68,76.15) U1.Y45
  LAY4 w0.089: 87.28,73.75 87.28,75.75 v2(87.68,76.15)
  LAY4 w0.127: v2(70.18,52) 70.73,52.56 70.73,53.6 70.61,53.73 70.36,53.73 70.23,53.86 70.23,54.11 70.36,54.24 70.61,54.24 70.73,54.36 70.73,54.62 70.61,54.75 70.36,54.75 70.23,54.87 70.23,55.13 70.36,55.25 70.61,55.25 70.73,55.38 70.73,61.54 70.4,61.87 70.4,63.38 73.42,66.39 79.4,66.39 79.98,66.98 80.16,66.98 80.23,66.92 80.41,66.92 80.59,67.1 80.59,67.28 80.52,67.34 80.52,67.52 80.7,67.7 80.88,67.7 80.95,67.64 81.13,67.64 81.31,67.81 81.31,67.99 81.24,68.06 81.24,68.24 81.42,68.42 81.6,68.42 81.67,68.35 81.85,68.35 82.03,68.53 82.03,68.71 81.96,68.78 81.96,68.96 82.14,69.14 82.32,69.14 82.39,69.07 82.57,69.07 82.75,69.25 82.75,69.43 82.68,69.5 82.68,69.68 85.78,72.78 86.32,72.78 87.28,73.75
M_A_DQ56: length 45.2
  TOP w0.114: U1.V52 89.22,73.05 89.22,71.09 86.51,68.39 84.98,68.39 84.42,67.84 78.17,67.84 75.49,65.16 75.49,64.66 75.37,64.53 74.86,64.53 74.56,64.23 74.56,61.21 74.86,60.91 74.86,60.58 74.68,60.4 74.38,60.4 74.04,60.74 74.04,60.98 73.61,61.41 71.47,61.41 71.35,61.3 71.35,60.56 71.24,60.45 71.01,60.45 70.9,60.56 70.9,61.3 70.78,61.41 69.84,61.41 69.44,61.02 69.44,60.64 68.99,60.18 v2(68.68,60.18) ; CN3.181 v2(68.08,55.96)
  BOTTOM w0.114: v2(68.68,60.18) 69.11,59.75 69.11,58.35 69.22,58.23 70.23,58.23 70.34,58.12 70.34,57.89 70.23,57.78 69.22,57.78 69.11,57.66 69.11,57.43 69.22,57.32 70.23,57.32 70.34,57.21 70.34,56.98 70.23,56.86 69.22,56.86 69.11,56.75 69.11,56.47 69.59,55.99 69.59,55.77 69.41,55.59 68.83,55.59 68.46,55.96 v2(68.08,55.96)
M_A_DQ57: length 44.9
  TOP w0.114: U1.W51 88.84,73.29 88.84,73.18 88.84,73 88.95,72.89 88.95,71.56 86.3,68.91 84.76,68.91 84.21,68.36 77.96,68.36 74.04,64.44 74.04,62.33 73.75,62.04 69.67,62.04 69.06,61.44 69.06,61.27 v2(68.68,60.89) ; CN3.183 67.48,55.14 v2(68.08,54.54)
  BOTTOM w0.114: v2(68.68,60.89) 69.1,61.31 70.57,61.31 70.86,61.02 70.86,56.23 70.55,55.91 70.55,55.75 71.02,55.29 71.02,55.13 70.85,54.97 70.69,54.97 70.23,55.43 70.07,55.43 69.9,55.27 69.9,55.11 70.37,54.64 70.37,54.48 70.21,54.32 70.05,54.32 69.58,54.78 69.42,54.78 69.18,54.54 v2(68.08,54.54)
M_A_DQ58: length 45.7
  TOP w0.114: v2(64.48,54.54) 65.08,55.14 CN3.191 ; v2(65.08,58.76) 65.68,59.36 65.68,60.7 65.57,60.81 65.04,60.81 64.93,60.93 64.93,61.16 65.04,61.27 65.57,61.27 65.68,61.39 65.68,61.62 65.57,61.73 65.04,61.73 64.93,61.84 64.93,62.07 65.04,62.19 65.57,62.19 65.68,62.3 65.68,62.53 65.57,62.64 65.04,62.64 64.93,62.76 64.93,62.99 65.04,63.1 65.57,63.1 65.68,63.22 65.68,63.54 67.63,65.49 69.54,65.49 69.78,65.74 69.78,65.9 69.56,66.12 69.56,66.28 69.72,66.44 69.88,66.44 70.1,66.22 70.26,66.22 70.43,66.38 70.43,66.54 70.21,66.76 70.21,66.93 70.37,67.09 70.53,67.09 70.75,66.87 70.91,66.87 71.07,67.03 71.07,67.19 70.85,67.41 70.85,67.57 71.02,67.73 71.18,67.73 71.4,67.51 71.56,67.51 71.72,67.68 71.72,67.84 71.5,68.06 71.5,68.22 71.66,68.38 71.82,68.38 72.04,68.16 72.2,68.16 72.37,68.32 72.37,68.49 72.15,68.7 72.15,68.87 72.31,69.03 72.47,69.03 72.69,68.81 72.85,68.81 74.51,70.47 82.34,70.47 83.01,71.14 86.01,71.14 86.71,71.84 U1.AC53
  BOTTOM w0.114: v2(65.08,58.76) 65.08,55.14 v2(64.48,54.54)
M_A_DQ59: length 46.8
  TOP w0.114: v2(65.08,60.18) 64.69,60.18 64.41,60.46 64.41,63.62 64.84,64.05 65,64.05 65.14,63.92 65.3,63.92 65.46,64.08 65.46,64.24 65.33,64.38 65.33,64.54 65.49,64.7 65.65,64.7 65.78,64.57 65.94,64.57 66.11,64.73 66.11,64.89 65.97,65.02 65.97,65.19 66.13,65.35 66.3,65.35 66.43,65.21 66.59,65.21 66.75,65.38 66.75,65.54 66.62,65.67 66.62,65.83 66.8,66.01 68.56,66.01 73.89,71.35 85.85,71.35 86.42,71.92 86.42,72.89 86.71,73.18 U1.AC51 ; CN3.193 v2(64.48,55.96)
  BOTTOM w0.114: v2(65.08,60.18) 65.87,60.98 65.87,61.87 65.65,62.09 65.15,62.09 64.94,61.88 64.94,61.05 64.83,60.94 64.6,60.94 64.49,61.05 64.49,61.85 64.38,61.95 63.82,61.95 63.61,61.74 63.61,61.33 64.33,60.61 64.33,60.24 64.65,59.92 64.65,57.7 64.48,57.52 v2(64.48,55.96)
M_A_DQ60: length 45.5
  TOP w0.114: U1.W53 88.66,71.76 86.33,69.43 84.54,69.43 83.99,68.88 77.74,68.88 73.77,64.91 73.52,64.66 73.52,62.85 73.23,62.56 69.03,62.56 68.24,61.78 68.24,59.19 v2(68.68,58.76) ; v2(67.78,52) 68.38,51.4 CN3.180
  BOTTOM w0.114: v2(68.68,58.76) 68.4,58.49 68.4,56.99 67.6,56.18 67.6,53.71 67.93,53.38 68.29,53.38 68.4,53.26 68.4,52.63 68.52,52.52 68.75,52.52 68.86,52.63 68.86,53.26 68.97,53.38 69.36,53.38 69.63,53.11 69.63,51.87 69.34,51.58 68.2,51.58 v2(67.78,52)
M_A_DQ61: length 46
  TOP w0.089: U1.Y51 88.17,73.54 88.48,73.23
  TOP w0.114: v2(67.48,58.76) 67.91,59.19 67.91,62.2 68.79,63.08 72.73,63.08 73,63.35 73,64.87 77.52,69.4 83.77,69.4 84.26,69.89 86.5,69.89 88.36,71.76 88.36,72.89 88.48,73.01 88.48,73.23 ; v2(67.78,50.58) 67.78,50.58 CN3.182
  BOTTOM w0.114: v2(67.48,58.76) 67.86,58.37 67.86,57.27 67.06,56.46 67.06,55.4 66.94,55.29 66.8,55.29 66.68,55.17 66.68,54.93 66.77,54.83 66.94,54.83 67.06,54.71 67.06,54.49 66.94,54.37 66.72,54.37 66.61,54.26 66.61,54.03 66.72,53.91 66.94,53.91 67.06,53.8 67.06,53.57 66.94,53.46 66.39,53.46 66.28,53.34 66.28,53.11 66.39,53 66.94,53 67.06,52.89 67.06,52.66 66.94,52.54 66.27,52.54 66.15,52.43 66.15,52.2 66.27,52.09 66.94,52.09 67.06,51.97 67.06,51.59 66.82,51.35 66.82,51.05 67.03,50.85 67.5,50.85 v2(67.78,50.58)
M_A_DQ62: length 44.9
  TOP w0.089: 86.13,73.03 U1.AD52
  TOP w0.114: CN3.192 64.78,50.84 64.63,50.98 64.63,51.54 v2(64.18,52) ; 86.13,73.03 86.13,72 85.68,71.55 73.36,71.55 68.34,66.53 66.55,66.53 66.03,66.02 65.87,66.02 65.63,66.26 65.47,66.26 65.31,66.1 65.31,65.94 65.55,65.7 65.55,65.54 65.39,65.38 65.22,65.38 64.99,65.61 64.83,65.61 64.66,65.45 64.66,65.29 64.9,65.05 64.9,64.89 64.74,64.73 64.58,64.73 64.34,64.97 64.18,64.97 64.02,64.8 64.02,64.64 64.25,64.41 64.25,64.24 63.88,63.87 v2(63.88,60.18)
  BOTTOM w0.114: v2(64.18,52) 63.76,52.41 63.76,57.52 64.29,58.05 64.29,59.77 v2(63.88,60.18)
M_A_DQ63: length 46.3
  TOP w0.102: 85.88,73.21 86.22,73.55 U1.AD51
  TOP w0.114: v2(63.88,58.76) 63.33,59.3 63.33,64.87 63.7,65.23 63.7,65.39 63.57,65.52 63.57,65.68 63.73,65.84 63.89,65.84 64.02,65.71 64.18,65.71 64.34,65.87 64.34,66.04 64.21,66.17 64.21,66.33 64.37,66.49 64.54,66.49 64.67,66.36 64.83,66.36 65.52,67.06 68.13,67.06 72.82,71.75 84.31,71.75 85.63,73.07 85.75,73.07 85.88,73.21 ; CN3.194 v2(64.18,50.58)
  BOTTOM w0.114: v2(63.88,58.76) 63.28,59.36 62.94,59.36 62.7,59.11 62.7,58.57 63.45,57.82 63.45,51.3 v2(64.18,50.58)
M_A_DQS0: length 56.2
  TOP w0.101: U1.J38 v2(93.43,79.72) ; CN3.12 121.18,50.3 121.36,50.49 121.36,50.99 121.99,51.61 121.99,51.61 v2(122.38,52)
  LAY3 w0.101: v2(122.38,52) 122.38,51.83 122.72,51.49 122.86,51.49 122.97,51.6 122.97,53.24 120.82,55.39 120.82,61.32 119.32,62.82 118.36,62.82 118.26,62.72 118.26,62.15 118.04,61.93 117.67,61.93 117.45,62.15 117.45,62.72 117.35,62.82 117.14,62.82 117.04,62.72 117.04,62.15 116.82,61.93 116.45,61.93 116.23,62.15 116.23,62.72 116.13,62.82 115.93,62.82 115.83,62.72 115.83,62.15 115.61,61.93 113.89,61.93 101.71,74.11 101.71,75.24 96.85,80.1 93.21,80.1 93.09,79.98 93.09,79.8 93.17,79.72 v2(93.43,79.72)
M_A_DQS1: length 46.6
  TOP w0.101: CN3.29 116.08,56.26 116.27,56.06 116.27,55.19 115.95,54.87 115.72,54.87 115.48,55.11 v2(115.48,55.25) ; v2(117.28,60.18) 117.51,59.95 117.62,59.95 117.72,60.05 117.72,61.12 116.69,62.15 116.69,63.88 116.59,63.98 116.13,63.98 115.9,64.2 115.9,64.59 116.13,64.81 116.59,64.81 116.69,64.91 116.69,65.12 116.59,65.22 116.13,65.22 115.9,65.45 115.9,65.83 116.13,66.06 116.59,66.06 116.69,66.16 116.69,66.89 104.59,78.99 103.91,78.99 101.96,80.94 101.96,80.96 101.62,81.29 99.1,81.29 98.35,82.04 97.48,82.04 97.29,81.85 97,81.85 U1.C35
  BOTTOM w0.101: v2(117.28,60.18) 116.57,59.48 116.57,57.56 116.31,57.3 116.31,55.14 116.02,54.85 115.74,54.85 115.48,55.11 v2(115.48,55.25)
M_A_DQS2: length 41.5
  TOP w0.101: v2(110.08,59.47) 110.08,59.6 110.44,59.96 110.69,59.96 110.86,59.79 110.86,58.69 110.68,58.5 CN3.47 ; U1.D40 v2(96.27,78.73)
  LAY4 w0.101: v2(96.27,78.73) 96.05,78.73 95.91,78.86 95.91,78.97 96.09,79.14 96.66,79.14 97.33,78.47 99.98,78.47 109.43,69.01 109.43,68.28 109.33,68.17 108.47,68.17 108.25,67.95 108.25,67.58 108.47,67.36 109.33,67.36 109.43,67.26 109.43,67.06 109.33,66.96 108.47,66.96 108.25,66.74 108.25,66.37 108.47,66.15 109.33,66.15 109.43,66.05 109.43,65.84 109.33,65.74 108.47,65.74 108.25,65.52 108.25,65.15 108.47,64.93 109.33,64.93 109.43,64.83 109.43,64.63 109.33,64.52 108.47,64.52 108.25,64.3 108.25,63.93 108.47,63.71 109.33,63.71 109.43,63.61 109.43,63.41 109.35,63.32 108.89,63.32 108.67,63.1 108.67,62.73 108.89,62.51 109.31,62.51 109.43,62.4 109.43,60.09 110.05,59.47 v2(110.08,59.47)
M_A_DQS3: length 43.3
  TOP w0.101: v2(105.28,60.18) 105.49,59.97 105.62,59.97 105.76,60.11 105.76,61.81 106.83,62.88 106.83,64.76 107.06,64.99 107.29,64.99 107.4,65.09 107.4,65.3 107.29,65.4 107.06,65.4 106.83,65.62 106.83,66.01 107.06,66.23 107.29,66.23 107.4,66.33 107.4,66.54 107.29,66.64 107.06,66.64 106.83,66.87 106.83,67.6 102.35,72.08 102.33,72.08 102.01,72.41 102.01,72.42 100.16,74.27 100.16,75.81 98.8,77.17 97.29,77.17 U1.B44 ; v2(106.78,52) 106.65,51.87 106.12,51.87 105.75,51.5 105.75,50.48 105.58,50.3 CN3.64
  BOTTOM w0.101: v2(106.78,52) 106.89,51.89 107.23,51.89 107.47,51.65 107.54,51.58 107.54,50.37 107.11,49.94 106.29,49.94 105.91,50.32 105.91,53.85 104.89,54.86 104.89,57.27 104.54,57.61 104.54,59.82 104.9,60.18 v2(105.28,60.18)
M_A_DQS4: length 44.3
  TOP w0.101: v2(82.48,59.47) 82.23,59.72 82.05,59.72 81.83,59.93 81.83,62.31 81.2,62.95 81.2,63.62 81.47,63.89 82.85,63.89 83.2,63.54 83.2,59.35 83.3,59.25 83.5,59.25 83.6,59.35 83.6,62.15 83.83,62.38 84.47,62.38 84.61,62.52 84.61,62.79 84.53,62.87 83.81,62.87 83.6,63.08 83.6,63.67 83.82,63.89 85.47,63.89 86.58,65 88.86,65 89.67,65.81 89.67,66.21 89.97,66.51 90.38,66.51 90.55,66.68 90.55,67.09 90.85,67.39 91.26,67.39 91.43,67.56 91.43,67.97 91.73,68.27 92.14,68.27 92.66,68.79 92.66,70.2 91.57,71.28 U1.N53 ; CN3.137 81.28,56.26 81.47,56.06 81.47,55.04 81.84,54.67 82.34,54.67 v2(82.48,54.54)
  BOTTOM w0.101: v2(82.48,59.47) 82.25,59.69 82.09,59.69 81.96,59.57 81.96,58.57 83.24,57.3 83.24,54.99 82.98,54.74 82.67,54.74 v2(82.48,54.54)
M_A_DQS5: length 40.4
  TOP w0.101: CN3.154 76.18,50.3 76.37,50.49 76.37,51.15 76.09,51.42 75.72,51.42 75.69,51.39 75.68,51.39 v2(75.58,51.29) ; U1.T42 v2(90.58,77.58)
  LAY3 w0.101: v2(90.58,77.58) 90.33,77.32 89.84,77.32 89.35,76.82 89.35,73.34 88.81,72.79 88.81,71.03 88.2,70.42 88.2,69.88 80.97,62.65 79.21,62.65 77.14,60.58 77.14,55.34 76.35,54.56 76.35,54.26 77.03,53.59 77.03,53.44 76.88,53.3 76.74,53.3 76.08,53.96 75.76,53.96 74.81,53.01 74.81,51.71 75.05,51.47 75.4,51.47 v2(75.58,51.29)
M_A_DQS6: length 41
  TOP w0.101: U1.Y47 88.41,75.63 v2(88.68,75.44) ; CN3.171 71.08,58.47 71.27,58.67 71.27,59.41 71.8,59.94 72.04,59.94 v2(72.28,60.18)
  LAY4 w0.101: v2(72.28,60.18) 72.28,60.07 72.14,59.93 71.98,59.93 71.87,60.03 71.87,61.77 72.49,62.39 72.49,62.71 72.28,62.92 72.28,63.05 72.4,63.18 72.59,63.18 72.78,62.99 73.09,62.99 73.64,63.54 74.71,63.54 74.93,63.76 74.93,64.81 75.04,64.91 75.24,64.91 75.34,64.81 75.34,63.76 75.56,63.54 75.93,63.54 76.15,63.76 76.15,64.81 76.25,64.91 76.46,64.91 76.56,64.81 76.56,63.76 76.78,63.54 77.15,63.54 77.37,63.76 77.37,64.81 77.47,64.91 77.67,64.91 77.77,64.81 77.77,63.76 77.99,63.54 78.36,63.54 78.58,63.76 78.58,64.81 78.69,64.91 78.89,64.91 78.99,64.81 78.99,63.76 79.21,63.54 79.89,63.54 88.3,71.95 88.3,75.07 v2(88.68,75.44)
M_A_DQS7: length 45.3
  TOP w0.101: U1.AB52 87.05,72.97 87.05,71.76 86.01,70.72 83.21,70.72 82.49,70 75.1,70 72.8,67.7 72.8,67.38 72.99,67.19 72.99,67.04 72.85,66.9 72.7,66.9 72.51,67.09 72.19,67.09 71.92,66.82 71.92,66.5 72.11,66.31 72.11,66.16 71.97,66.02 71.82,66.02 71.63,66.21 71.31,66.21 71.04,65.94 71.04,65.62 71.23,65.43 71.23,65.29 71.09,65.14 70.94,65.14 70.75,65.33 70.43,65.33 69.84,64.75 67.94,64.75 66.43,63.24 66.43,61.5 66.77,61.16 66.77,60.03 66.66,59.92 66.54,59.92 v2(66.28,60.18) ; v2(65.38,51.29) 65.38,51.44 65.5,51.57 65.5,51.57 65.97,51.57 66.17,51.37 66.17,50.49 65.98,50.3 CN3.188
  BOTTOM w0.101: v2(65.38,51.29) 65.25,51.29 64.74,51.79 64.74,53.18 65.59,54.03 65.59,59.58 66.19,60.18 v2(66.28,60.18)
M_A_DQS#0: length 56.2
  TOP w0.101: U1.K38 v2(92.72,79.72) ; v2(122.38,51.29) 122.27,51.39 122.08,51.39 121.58,50.9 121.58,50.5 121.78,50.3 CN3.10
  LAY3 w0.101: v2(122.38,51.29) 122.94,51.29 123.17,51.52 123.17,53.32 121.02,55.48 121.02,61.41 119.4,63.02 118.28,63.02 118.06,62.8 118.06,62.23 117.95,62.13 117.75,62.13 117.65,62.23 117.65,62.8 117.43,63.02 117.06,63.02 116.84,62.8 116.84,62.23 116.74,62.13 116.53,62.13 116.43,62.23 116.43,62.8 116.21,63.02 115.84,63.02 115.62,62.8 115.62,62.23 115.52,62.13 113.97,62.13 101.91,74.19 101.91,75.32 96.93,80.3 93.13,80.3 92.89,80.06 92.89,79.89 v2(92.72,79.72)
M_A_DQS#1: length 46.7
  TOP w0.101: v2(115.48,54.54) 115.59,54.66 116.04,54.66 116.48,55.1 116.48,56.06 116.68,56.26 CN3.27 ; v2(117.28,59.47) 117.54,59.73 117.71,59.73 117.93,59.96 117.93,61.21 116.9,62.24 116.9,63.96 116.68,64.19 116.22,64.19 116.12,64.29 116.12,64.5 116.22,64.6 116.68,64.6 116.9,64.83 116.9,65.21 116.68,65.43 116.22,65.43 116.12,65.54 116.12,65.74 116.22,65.84 116.68,65.84 116.9,66.07 116.9,66.98 104.68,79.2 104,79.2 101.71,81.49 99.18,81.49 98.43,82.24 97.27,82.24 U1.B34
  BOTTOM w0.101: v2(117.28,59.47) 117.19,59.55 116.95,59.55 116.79,59.39 116.79,57.47 116.53,57.21 116.53,55.05 116.02,54.54 v2(115.48,54.54)
M_A_DQS#2: length 41.6
  TOP w0.101: U1.F40 v2(95.56,78.73) ; CN3.45 111.28,58.5 111.08,58.7 111.08,59.88 110.77,60.18 v2(110.08,60.18)
  LAY4 w0.101: v2(110.08,60.18) 109.95,60.06 109.75,60.06 109.63,60.17 109.63,62.48 109.4,62.72 108.98,62.72 108.87,62.82 108.87,63.02 108.98,63.12 109.43,63.12 109.63,63.33 109.63,63.7 109.41,63.92 108.55,63.92 108.45,64.02 108.45,64.22 108.55,64.32 109.41,64.32 109.63,64.54 109.63,64.91 109.41,65.13 108.55,65.13 108.45,65.23 108.45,65.44 108.55,65.54 109.41,65.54 109.63,65.76 109.63,66.13 109.41,66.35 108.55,66.35 108.45,66.45 108.45,66.65 108.55,66.76 109.41,66.76 109.63,66.98 109.63,67.35 109.41,67.57 108.55,67.57 108.45,67.67 108.45,67.87 108.55,67.97 109.41,67.97 109.63,68.19 109.63,69.1 100.06,78.67 97.42,78.67 96.74,79.34 96,79.34 95.71,79.05 95.71,78.88 v2(95.56,78.73)
M_A_DQS#3: length 43.3
  TOP w0.101: v2(105.28,59.47) 105.56,59.75 105.71,59.75 105.98,60.02 105.98,61.72 107.05,62.79 107.05,64.67 107.15,64.78 107.38,64.78 107.61,65 107.61,65.38 107.38,65.61 107.15,65.61 107.05,65.71 107.05,65.92 107.15,66.02 107.38,66.02 107.61,66.25 107.61,66.63 107.38,66.85 107.15,66.85 107.05,66.96 107.05,67.69 102.44,72.3 102.42,72.3 100.36,74.36 100.36,75.89 98.88,77.37 97.51,77.37 97.3,77.58 97,77.58 U1.C43 ; v2(106.78,51.29) 106.78,51.44 106.56,51.65 106.21,51.65 105.97,51.41 105.97,50.51 106.18,50.3 CN3.62
  BOTTOM w0.101: v2(105.28,59.47) 105.28,59.61 105.03,59.86 104.88,59.86 104.76,59.73 104.76,57.7 105.11,57.36 105.11,54.95 106.12,53.93 106.12,50.41 106.38,50.16 107.02,50.16 107.32,50.46 107.32,51.43 107.14,51.62 106.91,51.62 106.78,51.48 v2(106.78,51.29)
M_A_DQS#4: length 44.3
  TOP w0.101: CN3.135 81.88,56.26 81.68,56.06 81.68,55.13 81.93,54.89 82.11,54.89 v2(82.48,55.25) ; U1.M52 91.95,73.02 91.95,72.58 91.78,72.41 91.78,71.36 92.88,70.27 92.88,68.7 92.23,68.05 91.82,68.05 91.65,67.88 91.65,67.47 91.35,67.18 90.94,67.18 90.77,67 90.77,66.6 90.47,66.3 90.06,66.3 89.89,66.12 89.89,65.72 88.95,64.78 86.67,64.78 85.56,63.67 83.91,63.67 83.82,63.58 83.82,63.17 83.9,63.09 84.62,63.09 84.83,62.88 84.83,62.43 84.56,62.16 83.92,62.16 83.82,62.06 83.82,59.27 83.59,59.04 83.21,59.04 82.98,59.27 82.98,63.45 82.76,63.67 81.56,63.67 81.41,63.53 81.41,63.04 82.05,62.4 82.05,60.02 82.14,59.93 82.23,59.93 v2(82.48,60.18)
  BOTTOM w0.101: v2(82.48,60.18) 82.26,59.96 82.05,59.96 81.75,59.66 81.75,58.48 83.02,57.21 83.02,55.08 82.89,54.95 82.68,54.95 82.48,55.16 v2(82.48,55.25)
M_A_DQS#5: length 40.3
  TOP w0.101: CN3.152 76.78,50.3 76.58,50.49 76.58,51.24 76.18,51.64 75.79,51.64 75.58,51.85 v2(75.58,52) ; U1.T44 v2(90.58,76.86)
  LAY3 w0.101: v2(90.58,76.86) 90.33,77.12 89.93,77.12 89.55,76.74 89.55,73.25 89.01,72.71 89.01,70.94 88.4,70.33 88.4,69.79 81.05,62.45 79.3,62.45 77.34,60.49 77.34,55.26 76.56,54.47 76.56,54.35 77.23,53.67 77.23,53.36 76.97,53.1 76.66,53.1 76,53.76 75.84,53.76 75.01,52.93 75.01,51.79 75.13,51.67 75.25,51.67 v2(75.58,52)
M_A_DQS#6: length 40.9
  TOP w0.101: CN3.169 71.68,58.5 71.48,58.69 71.48,59.32 71.89,59.73 72.02,59.73 v2(72.28,59.47) ; U1.Y48 87.96,75.24 v2(87.68,75.44)
  LAY4 w0.101: v2(72.28,59.47) 72.02,59.72 71.89,59.72 71.67,59.95 71.67,61.86 72.29,62.48 72.29,62.62 72.07,62.83 72.07,63.14 72.32,63.38 72.68,63.38 72.86,63.2 73,63.2 73.55,63.75 74.63,63.75 74.73,63.85 74.73,64.89 74.95,65.11 75.32,65.11 75.54,64.89 75.54,63.85 75.64,63.75 75.85,63.75 75.95,63.85 75.95,64.89 76.17,65.11 76.54,65.11 76.76,64.89 76.76,63.85 76.86,63.75 77.06,63.75 77.17,63.85 77.17,64.89 77.39,65.11 77.76,65.11 77.98,64.89 77.98,63.85 78.08,63.75 78.28,63.75 78.38,63.85 78.38,64.89 78.6,65.11 78.97,65.11 79.19,64.89 79.19,63.85 79.29,63.75 79.81,63.75 88.1,72.03 88.1,75.03 v2(87.68,75.44)
M_A_DQS#7: length 45.4
  TOP w0.101: U1.AA51 87.68,73.19 87.25,72.75 87.25,71.68 86.09,70.52 83.29,70.52 82.57,69.8 75.2,69.8 73.01,67.61 73.01,67.47 73.2,67.28 73.2,66.95 72.93,66.69 72.61,66.69 72.42,66.88 72.28,66.88 72.13,66.73 72.13,66.59 72.33,66.4 72.33,66.08 72.06,65.81 71.73,65.81 71.54,66 71.4,66 71.25,65.85 71.25,65.71 71.45,65.52 71.45,65.2 71.18,64.93 70.85,64.93 70.66,65.12 70.52,65.12 69.93,64.53 68.03,64.53 66.65,63.15 66.65,61.59 66.99,61.25 66.99,59.94 66.75,59.7 66.51,59.7 v2(66.28,59.47) ; v2(65.38,52) 65.59,51.78 66.06,51.78 66.38,51.46 66.38,50.49 66.58,50.3 CN3.186
  BOTTOM w0.101: v2(66.28,59.47) 66.15,59.6 65.92,59.6 65.81,59.49 65.81,53.94 64.96,53.1 64.96,51.97 65.06,51.87 65.25,51.87 v2(65.38,52)
M_A_RAS#: length 38.8
  TOP w0.178: CN3.110 89.38,50.9 89.81,51.33 89.81,51.95 v2(90.58,52.71) ; v2(92.56,76.15) U1.M45
  LAY4 w0.102: 94.94,71.76 94.87,71.76 93.72,72.92 93.05,72.92 92.16,73.81 92.16,75.75 v2(92.56,76.15)
  LAY4 w0.203: 94.94,71.76 95.27,71.43 95.27,71.12 95.48,70.91 95.57,70.91 95.78,70.71 95.78,70.3 95.57,70.1 95.48,70.1 95.27,69.9 95.27,69.49 95.48,69.29 95.57,69.29 95.78,69.09 95.78,68.68 95.57,68.48 95.48,68.48 95.27,68.27 95.27,67.81 93.68,66.22 93.68,65.94 93.79,65.82 93.79,65.53 93.51,65.25 93.22,65.25 93.11,65.36 92.82,65.36 92.53,65.07 92.53,64.79 92.65,64.67 92.65,64.39 92.36,64.1 92.07,64.1 91.96,64.21 91.67,64.21 91.38,63.93 91.38,63.64 91.5,63.53 91.5,63.24 91.21,62.95 90.92,62.95 90.81,63.06 90.52,63.06 89.5,62.05 89.5,54.6 89.71,54.39 89.94,54.39 90.2,54.14 90.2,53.84 89.94,53.58 89.27,53.58 88.96,53.27 88.96,52.56 89.21,52.3 90.17,52.3 v2(90.58,52.71)
M_A_WE#: length 42.7
  TOP w0.102: U1.H51 94.03,73.56 94.03,72.55 94.12,72.46 94.12,71.68 94.21,71.59
  TOP w0.178: 94.21,71.59 95.33,70.47 95.63,70.47 96.75,69.35 96.75,65.98 95.48,64.7 93.82,64.7 93.57,64.45 93.57,64.2 95,62.77 95,62.52 94.75,62.27 94.5,62.27 93.07,63.7 92.82,63.7 92.39,63.27 92.39,63.03 93.79,61.63 93.79,61.38 93.54,61.13 93.29,61.13 91.9,62.51 91.64,62.51 91.39,62.26 91.39,62.01 92.08,61.32 92.08,61.07 91.82,60.82 91.57,60.82 90.88,61.51 90.63,61.51 89.86,60.74 89.86,59.75 89.58,59.47 v2(89.08,59.47) ; v2(89.08,55.25) 88.48,55.85 CN3.113
  BOTTOM w0.178: v2(89.08,55.25) 89.69,55.87 89.69,56.77 89.36,57.1 88.17,57.1 88.06,56.99 88.06,56.8 87.89,56.62 87.53,56.62 87.35,56.8 87.35,57.7 87.53,57.88 89.43,57.88 89.54,57.99 89.54,59.01 v2(89.08,59.47)
M_CKE0: length 38
  TOP w0.178: CN3.73 100.48,58.87 v2(99.88,59.47) ; U1.C47 v2(95.93,75.96)
  LAY4 w0.102: v2(95.93,75.96) 96.75,75.96 97.86,74.85 98.5,74.85
  LAY4 w0.203: v2(99.88,59.47) 99.39,58.98 99.39,55.91 99.83,55.46 101.54,55.46 101.82,55.75 101.82,57.82 101.62,58.03 100.77,58.03 100.56,58.23 100.56,58.63 100.77,58.84 101.62,58.84 101.82,59.04 101.82,61.97 101.62,62.17 100.78,62.17 100.57,62.38 100.57,62.78 100.78,62.99 101.62,62.99 101.82,63.19 101.82,64.03 103.08,65.29 103.08,70.27 98.5,74.85
M_CKE1: length 39.1
  TOP w0.178: U1.F44 v2(94.84,76.75) ; CN3.74 100.18,50.69 v2(99.58,51.29)
  LAY4 w0.102: 98.48,74.01 97.65,74.01 96.22,75.44 95.88,75.44 94.84,76.48 v2(94.84,76.75)
  LAY4 w0.203: 98.48,74.01 102.39,70.1 102.39,65.46 99.43,62.5 99.43,60.59 98.78,59.94 98.78,57.6 98.58,57.39 98.25,57.39 98.05,57.19 98.05,56.79 98.25,56.58 98.58,56.58 98.78,56.38 98.78,50.28 99.06,50.01 99.88,50.01 100.36,50.48 100.36,51.06 100.13,51.29 v2(99.58,51.29)
M_CLK_DDR0: length 41.2
  TOP w0.101: CN3.101 92.08,58.5 91.88,58.69 91.88,59.54 92.16,59.81 92.49,59.81 92.68,59.62 v2(92.68,59.47) ; v2(92.56,74.02) U1.M50
  LAY3 w0.101: v2(92.68,59.47) 92.68,59.56 92.43,59.81 92.12,59.81 91.82,59.51 91.82,57.9 91.6,57.68 89.42,57.68 89.32,57.58 89.32,57.38 89.42,57.27 91.6,57.27 91.82,57.05 91.82,55.33 90.39,53.89 88.6,53.89 87.75,54.74 87.75,63.32 92.94,68.5 92.94,74.16 92.84,74.26 92.69,74.26 92.56,74.12 v2(92.56,74.02)
M_CLK_DDR1: length 40.4
  TOP w0.101: v2(92.38,51.29) 92.13,51.53 91.75,51.53 91.58,51.36 91.58,50.49 91.78,50.3 CN3.102 ; U1.P50 v2(91.57,74.73)
  LAY3 w0.101: v2(91.57,74.73) 91.57,74.84 91.65,74.93 91.8,74.93 91.97,74.76 91.97,68.87 86,62.9 86,58.04 86.22,57.82 86.46,57.82 86.56,57.72 86.56,57.51 86.46,57.41 86.22,57.41 86,57.19 86,50.38 86.43,49.95 91.12,49.95 91.6,50.43 91.6,51.63 91.76,51.8 92.04,51.8 92.38,51.46 v2(92.38,51.29)
M_CLK_DDR#0: length 41.1
  TOP w0.101: CN3.103 91.48,58.5 91.67,58.69 91.67,59.62 92.07,60.02 92.52,60.02 v2(92.67,60.18) ; v2(92.56,74.73) U1.M48
  LAY3 w0.101: v2(92.56,74.73) 92.65,74.73 93.14,74.25 93.14,68.42 87.95,63.23 87.95,54.82 88.68,54.1 90.3,54.1 91.62,55.42 91.62,56.97 91.52,57.07 89.33,57.07 89.11,57.29 89.11,57.66 89.33,57.88 91.52,57.88 91.62,57.98 91.62,59.6 92.03,60.01 92.5,60.01 v2(92.67,60.18)
M_CLK_DDR#1: length 40.4
  TOP w0.101: U1.P48 v2(91.57,75.44) ; v2(92.38,52) 92.12,51.75 91.66,51.75 91.37,51.45 91.37,50.49 91.18,50.3 CN3.104
  LAY3 w0.101: v2(92.38,52) 91.68,52 91.39,51.72 91.39,50.51 91.04,50.15 86.51,50.15 86.2,50.46 86.2,57.11 86.3,57.21 86.54,57.21 86.76,57.43 86.76,57.8 86.54,58.02 86.3,58.02 86.2,58.12 86.2,62.81 92.17,68.79 92.17,74.84 v2(91.57,75.44)
M_CS#0: length 42.5
  TOP w0.178: CN3.114 88.18,50.69 v2(88.78,51.29) ; U1.P44 v2(91.57,77.58)
  LAY4 w0.102: v2(91.57,77.58) 90.98,76.99 90.98,73.71 91.94,72.75
  LAY4 w0.203: v2(88.78,51.29) 88.39,50.9 87.86,50.9 87.58,51.18 87.58,52.76 88.64,53.82 88.64,55.41 88.4,55.64 87.97,55.64 87.72,55.39 87.72,54.27 87.31,53.86 86.68,53.86 85.9,54.64 85.9,55.14 86.55,55.78 86.55,56.37 85.15,57.77 84.53,57.77 84.28,58.02 83.69,58.6 83.69,61.17 91.94,69.42 91.94,72.75
M_CS#1: length 42.5
  TOP w0.178: CN3.121 86.08,58.63 86.82,59.37 86.82,60.43 v2(87.28,60.89) ; U1.P45 v2(91.57,76.86)
  LAY4 w0.102: v2(91.57,76.86) 91.17,76.46 91.17,73.87 92.54,72.49
  LAY4 w0.203: 92.54,72.49 93.62,71.41 93.62,70.98 93.42,70.78 92.76,70.78 92.55,70.58 92.55,70.17 92.76,69.97 93.42,69.97 93.62,69.76 93.62,69 93.19,68.56 92.91,68.56 92.57,68.9 92.28,68.9 91.99,68.61 91.99,68.33 92.33,67.99 92.33,67.7 92.04,67.42 91.76,67.42 91.42,67.75 91.13,67.75 90.85,67.47 90.85,67.18 91.18,66.84 91.18,66.56 90.9,66.27 90.61,66.27 90.27,66.6 89.99,66.6 89.7,66.32 89.7,66.03 90.04,65.69 90.04,65.41 89.75,65.12 89.46,65.12 89.12,65.46 88.84,65.46 88.55,65.17 88.55,64.88 88.89,64.55 88.89,64.26 88.6,63.97 88.31,63.97 87.98,64.31 87.69,64.31 87.4,64.02 87.4,63.73 87.74,63.4 87.74,63.11 87.45,62.82 87.16,62.82 86.83,63.16 86.54,63.16 86.25,62.87 86.25,62.59 86.59,62.25 86.59,61.96 86.3,61.68 86.02,61.68 85.68,62.01 85.39,62.01 85.11,61.73 85.11,61.44 85.44,61.1 85.44,60.81 84.79,60.16 84.79,58.65 85.05,58.38 85.59,58.38 85.92,58.71 85.92,59.54 v2(87.28,60.89)
M_ODT0: length 42.5
  TOP w0.178: v2(86.98,51.29) 87.58,50.69 CN3.116 ; v2(90.58,79) U1.T41
  LAY4 w0.102: v2(90.58,79) 89.86,78.28 89.86,73.88 90.57,73.17
  LAY4 w0.203: v2(86.98,51.29) 85.55,49.86 82.5,49.86 82.05,50.32 82.05,51.49 82.25,51.69 82.59,51.69 82.79,51.89 82.79,52.3 82.59,52.5 82.25,52.5 82.05,52.71 82.05,61.25 90.57,69.77 90.57,73.17
M_ODT1: length 42.3
  TOP w0.178: CN3.120 86.38,52.11 v2(86.98,52.71) ; v2(90.58,78.29) U1.P42
  LAY4 w0.102: 91.58,72.66 90.65,73.59 90.44,73.59 90.07,73.96 90.07,77.77 v2(90.58,78.29)
  LAY4 w0.203: 91.58,72.66 91.58,72.36 91.43,72.21 91.06,72.21 90.86,72.01 90.86,71.61 91.06,71.4 91.43,71.4 91.58,71.25 91.58,69.92 83.08,61.42 83.08,58.35 83.51,57.92 83.51,57.64 83.2,57.33 83.2,57.04 83.49,56.75 83.78,56.75 84.08,57.06 84.56,57.06 84.86,56.76 84.86,56.2 84.23,55.56 84.23,54.41 84.45,54.19 85.49,54.19 85.79,53.9 85.79,53.62 84.91,52.75 84.91,52.46 85.2,52.17 85.49,52.17 86.35,53.04 86.65,53.04 v2(86.98,52.71)
MDI0+: length 32.7
  BOTTOM w0.101: U61.7 79.01,32.06 79.48,31.59 80.87,31.59 81.48,32.2 81.48,35.65 79.82,37.31 71.6,37.31 65.59,43.32 61.93,43.32 61.4,42.78 U17.1
MDI0-: length 32.7
  BOTTOM w0.101: U61.8 80.14,34.31 80.14,33.42 80.28,33.28 80.65,33.28 80.75,33.18 80.75,32.87 80.64,32.76 79.49,32.76 79.36,32.64 79.36,32.21 79.63,31.95 80.72,31.95 81.13,32.35 81.13,35.5 79.67,36.96 71.45,36.96 65.45,42.96 62.07,42.96 61.54,42.43 61,42.43 U17.2
MDI1+: length 19.9
  BOTTOM w0.101: U61.1 71.39,33.37 71.49,33.27 72.03,33.27 72.13,33.16 72.13,32.76 71.88,32.51 70.84,32.51 70.19,33.16 70.19,37.09 65.46,41.82 62.05,41.82 61.79,41.56 60.98,41.56 U17.4
MDI1-: length 19.9
  BOTTOM w0.101: U61.2 72.66,33.43 72.49,33.26 72.49,32.62 72.03,32.16 70.69,32.16 69.84,33.01 69.84,36.94 65.31,41.47 62.2,41.47 61.93,41.21 60.98,41.21 U17.5
MDI2+: length 20.9
  BOTTOM w0.101: U17.7 60.98,40.36 62.19,40.36 62.41,40.14 65.57,40.14 68.83,36.89 68.83,31.1 67.99,30.27 66.16,30.27 65.62,30.81 U62.7
MDI2-: length 20.9
  BOTTOM w0.101: U62.8 67.32,32.8 67.55,32.58 67.55,31.74 67.22,31.41 66.14,31.41 65.97,31.25 65.97,30.96 66.31,30.63 67.85,30.63 68.47,31.25 68.47,36.74 65.43,39.78 62.26,39.78 62.04,40.01 60.98,40.01 U17.8
MDI3+: length 21.4
  LAY3 w0.114: v2(65.67,37.44) 65.67,37.36 65.91,37.12 65.91,36.09 59.42,29.61 58.18,29.61 57.81,29.99 57.81,30.56 58,30.76 v2(58,30.88)
  BOTTOM w0.101: v2(65.67,37.44) 65.67,37.66 65.74,37.74 65.74,38.2 65.33,38.61 62.13,38.61 61.58,39.16 60.98,39.16 U17.10 ; U62.1 58,31.81 57.88,31.7 57.88,31 v2(58,30.88)
MDI3-: length 21.4
  LAY3 w0.114: v2(65.06,37.44) 65.06,37.18 65.18,37.06 65.37,37.06 65.49,36.95 65.49,36.27 59.25,30.03 58.35,30.03 58.22,30.16 58.22,30.39 58.35,30.51 58.49,30.51 58.6,30.62 v2(58.6,30.88)
  BOTTOM w0.101: U62.2 59.27,31.73 59.17,31.63 58.34,31.63 58.24,31.53 58.24,31.34 58.36,31.22 58.51,31.22 58.6,31.13 v2(58.6,30.88) ; v2(65.06,37.44) 65.06,37.69 65.16,37.78 65.28,37.78 65.39,37.89 65.39,38.05 65.18,38.26 62.77,38.26 62.67,38.16 62.67,38.05 62.57,37.95 62.37,37.95 62.27,38.05 62.27,38.16 62.17,38.26 61.98,38.26 61.43,38.81 60.98,38.81 U17.11
MDSI_DDCDATA: length 14.6
  TOP w0.089: 98.88,84.5 98.79,84.58 U1.A29
  TOP w0.102: R31.1 R32.2 108.76,79.33 105.84,82.25 105.49,82.25 103.14,84.6 101.47,84.6 101.36,84.5 98.88,84.5
MIC1L-VREFO: length 4.5
  TOP w0.305: v2(133.09,18.35) 133.09,18.51 135.24,20.67 135.24,20.93 R246.2
  BOTTOM w0.203: v2(133.09,18.35) 133.04,18.31 U23.31
MIC1R-VREFO: length 5.3
  TOP w0.305: R244.2 135.66,20.94 135.66,20.36 v2(133.67,18.36)
  BOTTOM w0.203: U23.30 132.73,18.71 132.9,18.88 133.32,18.88 133.67,18.53 v2(133.67,18.36)
MIC2-VREFO: length 14.5
  LAY4 w0.203: v2(131.69,19.11) 131.69,25.99 v2(130.12,27.56)
  BOTTOM w0.203: U23.29 131.69,19.11 v2(131.69,19.11) ; v2(130.12,27.56) 130.12,27.84 130.12,27.85 130.12,31.74 130.13,31.74 R249.1
MIC_SEL_DET: length 78.8
  TOP w0.102: v2(126.85,24.88) 127.94,23.78 R267.1 133.25,24.21 Q97.1
  LAY3 w0.102: v2(126.85,24.88) 127.09,24.88 128.33,26.12 139.67,26.12 J7.4 ; v2(90.26,45.33) 90.64,44.95 94.92,44.95 96.61,46.65 105.5,46.65 105.93,47.08 111.65,47.08 117.33,41.4 v2(122.95,41.4)
  BOTTOM w0.102: R256.1 126.85,24.87 v2(126.85,24.88) 126.85,25.95 125.26,27.54 125.26,39.1 v2(122.95,41.4) ; v2(90.26,45.33) 89.83,44.9 89.83,44.57 R322.2
MIC_SEL_SPDIF: length 68.9
  TOP w0.102: v2(127.55,26.57) 128.29,25.84 R685.2 129.95,25.84 Q97.3
  LAY3 w0.102: v2(92.33,45.44) 92.61,45.17 94.84,45.17 96.58,46.9 105.21,46.9 105.69,47.38 111.64,47.38 117.02,42 v2(122.96,42)
  LAY4 w0.102: v2(127.33,16.29) 125.49,18.13 125.49,24.93 127.14,26.57 v2(127.55,26.57)
  BOTTOM w0.102: v2(122.96,42) 125.5,39.46 125.5,28.63 v2(127.55,26.57) ; U23.48 127.29,16.25 v2(127.33,16.29) ; R717.2 92.55,44.99 92.33,45.2 v2(92.33,45.44)
MS_BS: length 8.3
  TOP w0.102: v2(131.83,120.45) 129.65,120.45 128.91,119.71 CN30.M2
  BOTTOM w0.102: U95.11 v2(131.83,120.45)
MS_CLK: length 14.7
  TOP w0.102: CN30.M8 126.42,128.71 128.26,126.87 128.26,124.83 129.04,124.05 133.69,124.05 134.58,123.16 v2(134.58,121.93)
  BOTTOM w0.102: v2(134.58,121.93) 134.58,121.94 U95.6
MS_D0: length 9.9
  TOP w0.102: CN30.M4 127.11,122.71 128.38,121.44 131.84,121.44 v2(132.83,120.45)
  BOTTOM w0.102: U95.9 v2(132.83,120.45)
MS_D2: length 12
  TOP w0.102: CN30.M5 126.45,124.21 128.95,121.7 132.15,121.7 133.33,120.52 v2(133.33,119.99)
  BOTTOM w0.102: U95.8 v2(133.33,119.99)
MS_D3: length 13
  TOP w0.102: v2(133.83,120.95) 132.67,122.12 130.24,122.12 127.53,124.83 127.53,126.32 126.64,127.21 CN30.M7
  BOTTOM w0.102: U95.7 v2(133.83,120.95)
MS_INS: length 15.4
  TOP w0.102: CN30.M6 126.36,125.71 130.15,121.92 132.22,121.92 133.87,120.27 v2(135.18,120.27)
  BOTTOM w0.102: U95.5 134.82,122.97 135.18,122.61 v2(135.18,120.27)
NFC_HRT: length 1.6
  BOTTOM w0.305: CN11.5 R20.2
OUT_CLK+: length 8.9
  TOP w0.101: CN8.10 143.71,100.61 143.29,100.2 143.03,100.2 v2(142.84,100.39) 142.64,100.19 142.38,100.19 142.19,99.99 140.65,99.99 140.28,100.36 U14.10 137.95,100.36 C181.2
  BOTTOM w0.101: R193.2 143.79,100.42 143.49,100.12 143.11,100.12 v2(142.84,100.39)
OUT_CLK-: length 8.8
  TOP w0.101: CN8.12 143.7,99.61 143.33,99.98 143.03,99.98 v2(142.84,99.79) 142.66,99.97 142.47,99.97 142.28,99.78 140.7,99.78 140.28,99.36 U14.12 137.88,99.36 C182.2
  BOTTOM w0.101: R192.2 143.79,99.61 143.49,99.91 142.96,99.91 v2(142.84,99.79)
OUT_D0+: length 8.9
  TOP w0.101: C179.2 137.92,101.86 U14.7 140.26,101.86 140.66,101.46 141.8,101.46 142.05,101.71 142.61,101.71 v2(142.8,101.9) 143,101.7 143.23,101.7 143.64,102.11 CN8.7
  BOTTOM w0.101: v2(142.8,101.9) 143,101.7 143.51,101.7 143.79,101.98 R195.2
OUT_D0-: length 8.9
  TOP w0.101: C180.2 137.91,100.86 U14.9 140.27,100.86 140.66,101.25 141.89,101.25 142.14,101.5 142.6,101.5 v2(142.8,101.3) 142.98,101.49 143.21,101.49 143.59,101.11 CN8.9
  BOTTOM w0.101: R194.2 143.79,101.2 143.51,101.49 142.98,101.49 v2(142.8,101.3)
OUT_D1+: length 8.8
  TOP w0.101: C177.2 137.89,103.36 U14.4 140.36,103.36 140.74,102.98 142.13,102.98 142.37,103.22 142.69,103.22 v2(142.88,103.41) 143.08,103.21 143.28,103.21 143.68,103.61 CN8.4
  BOTTOM w0.101: R197.2 143.79,103.54 143.51,103.26 143.03,103.26 v2(142.88,103.41)
OUT_D1-: length 8.9
  TOP w0.101: C178.2 137.94,102.36 U14.6 140.38,102.36 140.79,102.76 142.22,102.76 142.46,103 142.69,103 v2(142.88,102.81) 143.07,102.99 143.28,102.99 143.66,102.61 CN8.6
  BOTTOM w0.101: R196.2 143.79,102.76 143.51,103.04 143.12,103.04 v2(142.88,102.81)
OUT_D2+: length 8.8
  TOP w0.101: C175.2 137.86,104.86 U14.1 140.32,104.86 140.66,104.52 141.24,104.52 141.42,104.7 142.59,104.7 v2(142.79,104.9) 142.98,104.7 143.19,104.7 143.6,105.11 CN8.1
  BOTTOM w0.101: v2(142.79,104.9) 142.88,104.8 143.51,104.8 143.79,105.08 R200.2
OUT_D2-: length 9
  TOP w0.101: C176.2 137.96,103.86 U14.3 140.29,103.86 140.74,104.3 141.33,104.3 141.51,104.48 142.6,104.48 v2(142.79,104.3) 142.98,104.49 143.25,104.49 143.63,104.11 CN8.3
  BOTTOM w0.101: v2(142.79,104.3) 143.08,104.59 143.51,104.59 143.79,104.31 R198.2
OVPA: length 11.7
  TOP w0.305: U25.7 21.68,34.55
  TOP w0.508: 21.68,34.55 21.68,34.55 v3(21.68,34.13)
  LAY3 w0.508: v2(17.32,27.6) 17.32,28.06 21.84,32.58 21.84,33.96 v3(21.68,34.13)
  BOTTOM w0.508: v2(17.32,27.6) R354.1 17.31,26.9 R619.2 R351.2
PCIE_LAN_WAKE#: length 169.7
  TOP w0.102: U1.F26 v2(95.56,86.5)
  LAY3 w0.102: v2(95.56,86.5) 95.99,86.07 96.79,86.07 96.93,86.21 100.67,86.21 101.89,84.99 103.86,84.99 105.81,83.04 109.72,83.04 110.02,83.34 113.3,83.34 113.91,82.72 v2(113.91,81.78) 113.91,79.59 114.49,79.02 114.49,76.87 119.59,71.77 122.1,71.77 127.75,66.12 127.75,57.76 128.34,57.17 128.34,51.94 126.8,50.4 126.8,36.85 121.15,31.2 116.75,31.2 115.98,31.97 104.33,31.97 103.72,32.58 90.04,32.58 85.73,36.89 84.45,36.89 v2(83.93,37.41)
  LAY4 w0.102: v2(48.64,37.28) 49.59,38.22 60.5,38.22 61.01,38.72 67,38.72 67.47,38.25 83.09,38.25 v2(83.93,37.41)
  BOTTOM w0.102: v2(113.91,81.78) 115.46,83.33 117.79,83.33 118.24,83.77 119.5,83.77 119.75,84.02 R63.1 ; R216.2 50.1,38.89 48.64,37.44 v2(48.64,37.28)
PCIE_RXN0_LAN: length 96.3
  TOP w0.101: U1.AT13 v2(79.91,92.81)
  LAY3 w0.101: v2(53.55,36.59) 53.95,36.19 54.22,36.19 54.6,36.57 54.6,36.91 53.23,38.28 50.66,38.28 49,39.94 49,41.38 53.49,45.87 53.49,47.05 54.13,47.68 54.13,56.85 58.51,61.23 58.51,68.46 60.18,70.13 60.18,82.6 58.74,84.04 58.74,91.32 65.18,97.76 69.52,97.76 70.36,98.6 71.95,98.6 72.45,98.09 78.81,98.09 79.51,97.4 79.51,92.67 79.66,92.52 79.82,92.52 79.91,92.61 v2(79.91,92.81)
  BOTTOM w0.101: C208.1 53.63,36.67 v2(53.55,36.59)
PCIE_RXN1_WLAN: length 90.6
  TOP w0.101: U1.AT9 80.55,94.59 v2(80.9,94.95) ; v2(48.89,43.01) 48.89,43.06 49.08,43.25 49.34,43.25 49.92,43.83 50.21,43.83 50.52,43.53 CN12.23
  LAY3 w0.089: v2(80.9,94.95) 81.16,94.95 81.23,94.88 81.23,94.51 81.32,94.43 81.54,94.43 81.77,94.66 81.77,98.23 79.97,100.03 73.26,100.03 72.67,99.44 71.13,99.44 71.12,99.44 71.1,99.44
  LAY3 w0.101: 71.1,99.44 69.7,99.44 68.89,98.63 64.71,98.63 64.24,98.16 64.24,97.72 58.09,91.57 58.09,83.77 59.43,82.44 59.43,70.26 57.9,68.74 57.9,61.53 52.88,56.51 52.88,46.14 50.35,43.61 49.81,43.61 49.5,43.31 49.19,43.31 v2(48.89,43.01)
PCIE_RXP0_LAN: length 96
  TOP w0.101: U1.AT14 80.18,91.97 v2(79.91,92.1)
  LAY3 w0.101: v2(53.55,35.99) 54.31,35.99 54.8,36.49 54.8,37 53.31,38.49 50.74,38.49 49.2,40.03 49.2,41.29 53.69,45.79 53.69,46.96 54.33,47.6 54.33,56.76 58.72,61.15 58.72,68.38 60.38,70.04 60.38,82.69 58.95,84.13 58.95,91.24 65.27,97.56 69.61,97.56 70.45,98.4 71.86,98.4 72.37,97.89 78.73,97.89 79.3,97.32 79.3,92.59 79.57,92.32 79.69,92.32 v2(79.91,92.1)
  BOTTOM w0.101: v2(53.55,35.99) 53.63,35.91 C209.1
PCIE_RXP1_WLAN: length 90.6
  TOP w0.101: v2(48.89,43.61) 49.03,43.47 49.25,43.47 49.83,44.05 50.21,44.05 50.49,44.33 CN12.25 ; U1.AT10 80.54,93.88 v2(80.9,94.24)
  LAY3 w0.089: 71.1,99.64 71.12,99.64 71.13,99.63 72.59,99.63 73.18,100.22 80.05,100.22 81.96,98.31 81.96,94.58 81.62,94.24 v2(80.9,94.24)
  LAY3 w0.101: 71.1,99.64 69.62,99.64 68.81,98.83 64.63,98.83 64.04,98.24 64.04,97.8 57.89,91.65 57.89,83.69 59.22,82.35 59.22,70.35 57.7,68.82 57.7,61.61 52.68,56.59 52.68,46.23 50.27,43.82 49.72,43.82 49.42,43.51 48.99,43.51 v2(48.89,43.61)
PCIE_TXN0_LAN: length 115.5
  LAY3 w0.101: v2(58.56,34.78) 58.75,34.59 58.75,34.33 58.64,34.22 55.97,34.22 55.65,34.55 51.77,34.55 51.22,34 47.64,34 46.85,34.79 46.85,36.46 45.8,37.51 45.8,44.36 47.85,46.42 49.16,46.42 50.44,47.71 50.44,55.25 49.47,56.23 49.47,60.75 50.64,61.93 51.89,61.93 52.83,62.87 52.83,71.95 51.86,72.92 51.86,98.25 56.72,103.11 59.24,103.11 60.06,102.29 73.04,102.29 73.42,101.9 76.36,101.9 76.68,102.23 77.08,102.23 77.28,102.43 v2(77.28,102.65)
  BOTTOM w0.101: v2(58.56,34.78) 58.75,34.97 58.75,36.03 58.35,36.44 58.35,37.07 58.26,37.17 U17.18 ; C5.1 77,102.04 77,102.37 v2(77.28,102.65)
PCIE_TXN1_WLAN: length 89.2
  TOP w0.101: CN12.31 50.11,46.73 49.79,47.05 49.02,47.05 48.69,47.38 48.39,47.38 v2(48.2,47.19)
  LAY3 w0.101: v2(78.24,102.64) 78.32,102.64 78.53,102.84 78.53,103 78.4,103.13 60.52,103.13 59.58,104.06 56.5,104.06 50.94,98.5 50.94,63.42 48.23,60.71 48.23,55.53 49.34,54.42 49.34,47.77 49.05,47.48 48.42,47.48 48.2,47.26 v2(48.2,47.19)
  BOTTOM w0.101: v2(78.24,102.64) 78.51,102.37 78.51,102 C3.1
PCIE_TXP0_LAN: length 115.6
  LAY3 w0.101: v2(76.67,102.65) 76.67,102.51 76.27,102.11 73.51,102.11 73.12,102.49 60.14,102.49 59.32,103.31 56.64,103.31 51.66,98.33 51.66,72.84 52.62,71.87 52.62,62.95 51.8,62.13 50.56,62.13 49.26,60.84 49.26,56.15 50.24,55.17 50.24,47.79 49.07,46.62 47.77,46.62 45.59,44.45 45.59,37.43 46.64,36.38 46.64,34.71 47.56,33.79 51.3,33.79 51.85,34.34 55.56,34.34 55.89,34.02 58.73,34.02 58.95,34.24 58.95,34.56 v2(59.16,34.78)
  BOTTOM w0.101: C4.1 76.78,101.86 76.78,102.55 v2(76.67,102.65) ; U17.17 58.66,37.18 58.57,37.08 58.57,36.53 58.97,36.12 58.97,34.97 v2(59.16,34.78)
PCIE_TXP1_WLAN: length 89.1
  TOP w0.101: CN12.33 50.11,47.53 49.85,47.26 49.11,47.26 48.78,47.59 48.4,47.59 v2(48.2,47.79)
  LAY3 w0.101: v2(48.2,47.79) 48.31,47.68 48.97,47.68 49.14,47.86 49.14,54.34 48.03,55.44 48.03,60.8 50.74,63.51 50.74,98.58 56.42,104.26 59.67,104.26 60.6,103.33 78.48,103.33 78.73,103.08 78.73,102.75 v2(78.85,102.64)
  BOTTOM w0.101: v2(78.85,102.64) 78.73,102.52 78.73,101.91 C6.1
PCIE_WIFI_WAKE#: length 176.4
  TOP w0.102: U1.B16 98.97,90.89 99.46,91.38 99.46,93.06 101.54,95.15 v2(101.66,95.15) 101.85,95.15
  TOP w0.114: R80.2 101.85,95.15
  LAY3 w0.127: v2(101.66,95.15) 105.42,95.15 105.52,95.05 116.86,95.05 123.48,88.43 123.48,77.46 127.96,72.98 127.96,70.78 130.46,68.28 130.46,64.91 132.13,63.25 132.13,62.09 131.19,61.16 131.19,52.97 131.66,52.5 131.66,50.52 129.36,48.21 129.36,37.48 121.87,29.99 116.11,29.99 115.33,30.78 103.55,30.78 103.01,31.31 98.65,31.31 v2(98.62,31.28)
  LAY4 w0.127: v2(98.62,31.28) 97.12,32.78 84.26,32.78 82.18,34.86 67.78,34.86 66.54,33.62 62.35,33.62 61.49,32.76 55.24,32.76 54.85,32.37 51.32,32.37 v2(49.66,30.72)
  BOTTOM w0.114: R636.1 v2(49.66,30.72)
PD#: length 11.5
  BOTTOM w0.114: U24.4 118.17,14.46 118.36,14.27 122.62,14.27 123.42,13.46 124.54,13.46 126.05,14.97 127.33,14.97 127.69,15.34 U23.47
PERSTB: length 4.5
  BOTTOM w0.203: R218.1 52.22,35.69 52.58,36.05 52.58,36.58 53.34,37.35 53.8,37.35 54.84,38.38 U17.25
PM_BATLOW#: length 109.2
  TOP w0.102: v2(93.43,86.5) U1.K26
  LAY3 w0.127: v2(126.13,37.85) 126.3,38.03 126.3,50.61 127.84,52.15 127.84,56.97 127.26,57.55 127.26,65.03 121.42,70.87 119.7,70.87 113.81,76.76 113.81,78.68 113.04,79.45 v2(113.04,81.96) 112.23,82.77 110.53,82.77 110.14,82.37 105.48,82.37 103.54,84.32 101.44,84.32 100.64,85.12 97.95,85.12 97.46,85.61 95.81,85.61 95.57,85.84 94.09,85.84 v2(93.43,86.5)
  LAY4 w0.127: v2(106.87,32.34) 107.92,31.3 118.9,31.3 125.46,37.85 v2(126.13,37.85)
  BOTTOM w0.114: v2(106.87,32.34) 107.38,31.83 R311.1 107.38,30.87 R335.1 ; v2(113.04,81.96) 113.94,82.85 114.64,82.85 115.36,83.57 117.69,83.57 118.6,84.47 118.6,85.56 119.83,86.79 R638.1
PM_RSMRST#: length 241.7
  TOP w0.089: 97.84,93.9 97.75,93.81 U1.B10
  TOP w0.102: 101.26,96.3 98.94,93.98 97.93,93.98 97.84,93.9
  TOP w0.114: v2(108.08,97.68) 108.08,98.9 108.56,99.38 108.56,100.43 108.35,100.64 105.92,100.64 R67.1 104.04,100.07 103.68,99.71 103.68,98.86 101.26,96.44 101.26,96.3
  LAY3 w0.127: v2(31.83,32.25) 39.64,24.45 59.25,24.45 65.37,30.57 80.58,30.57 82.99,28.16 102.62,28.16 103.56,29.1 112.25,29.1 v2(113.8,27.55) 113.92,27.55 115.54,29.18 122.71,29.18 130.12,36.59 130.12,47.86 133.7,51.44 133.7,62.81 131.7,64.81 131.7,68.21 128.97,70.93 128.97,73.09 124.24,77.82 124.24,88.75 117.18,95.81 109.28,95.81 108.08,97.02 v2(108.08,97.68)
  LAY4 w0.127: v2(30.41,62.77) 31.77,61.42 31.77,32.32 v2(31.83,32.25)
  BOTTOM w0.114: R332.1 110.62,25.13 Q69.2 111.38,25.13 v2(113.8,27.55) ; R714.2 v2(30.41,62.77)
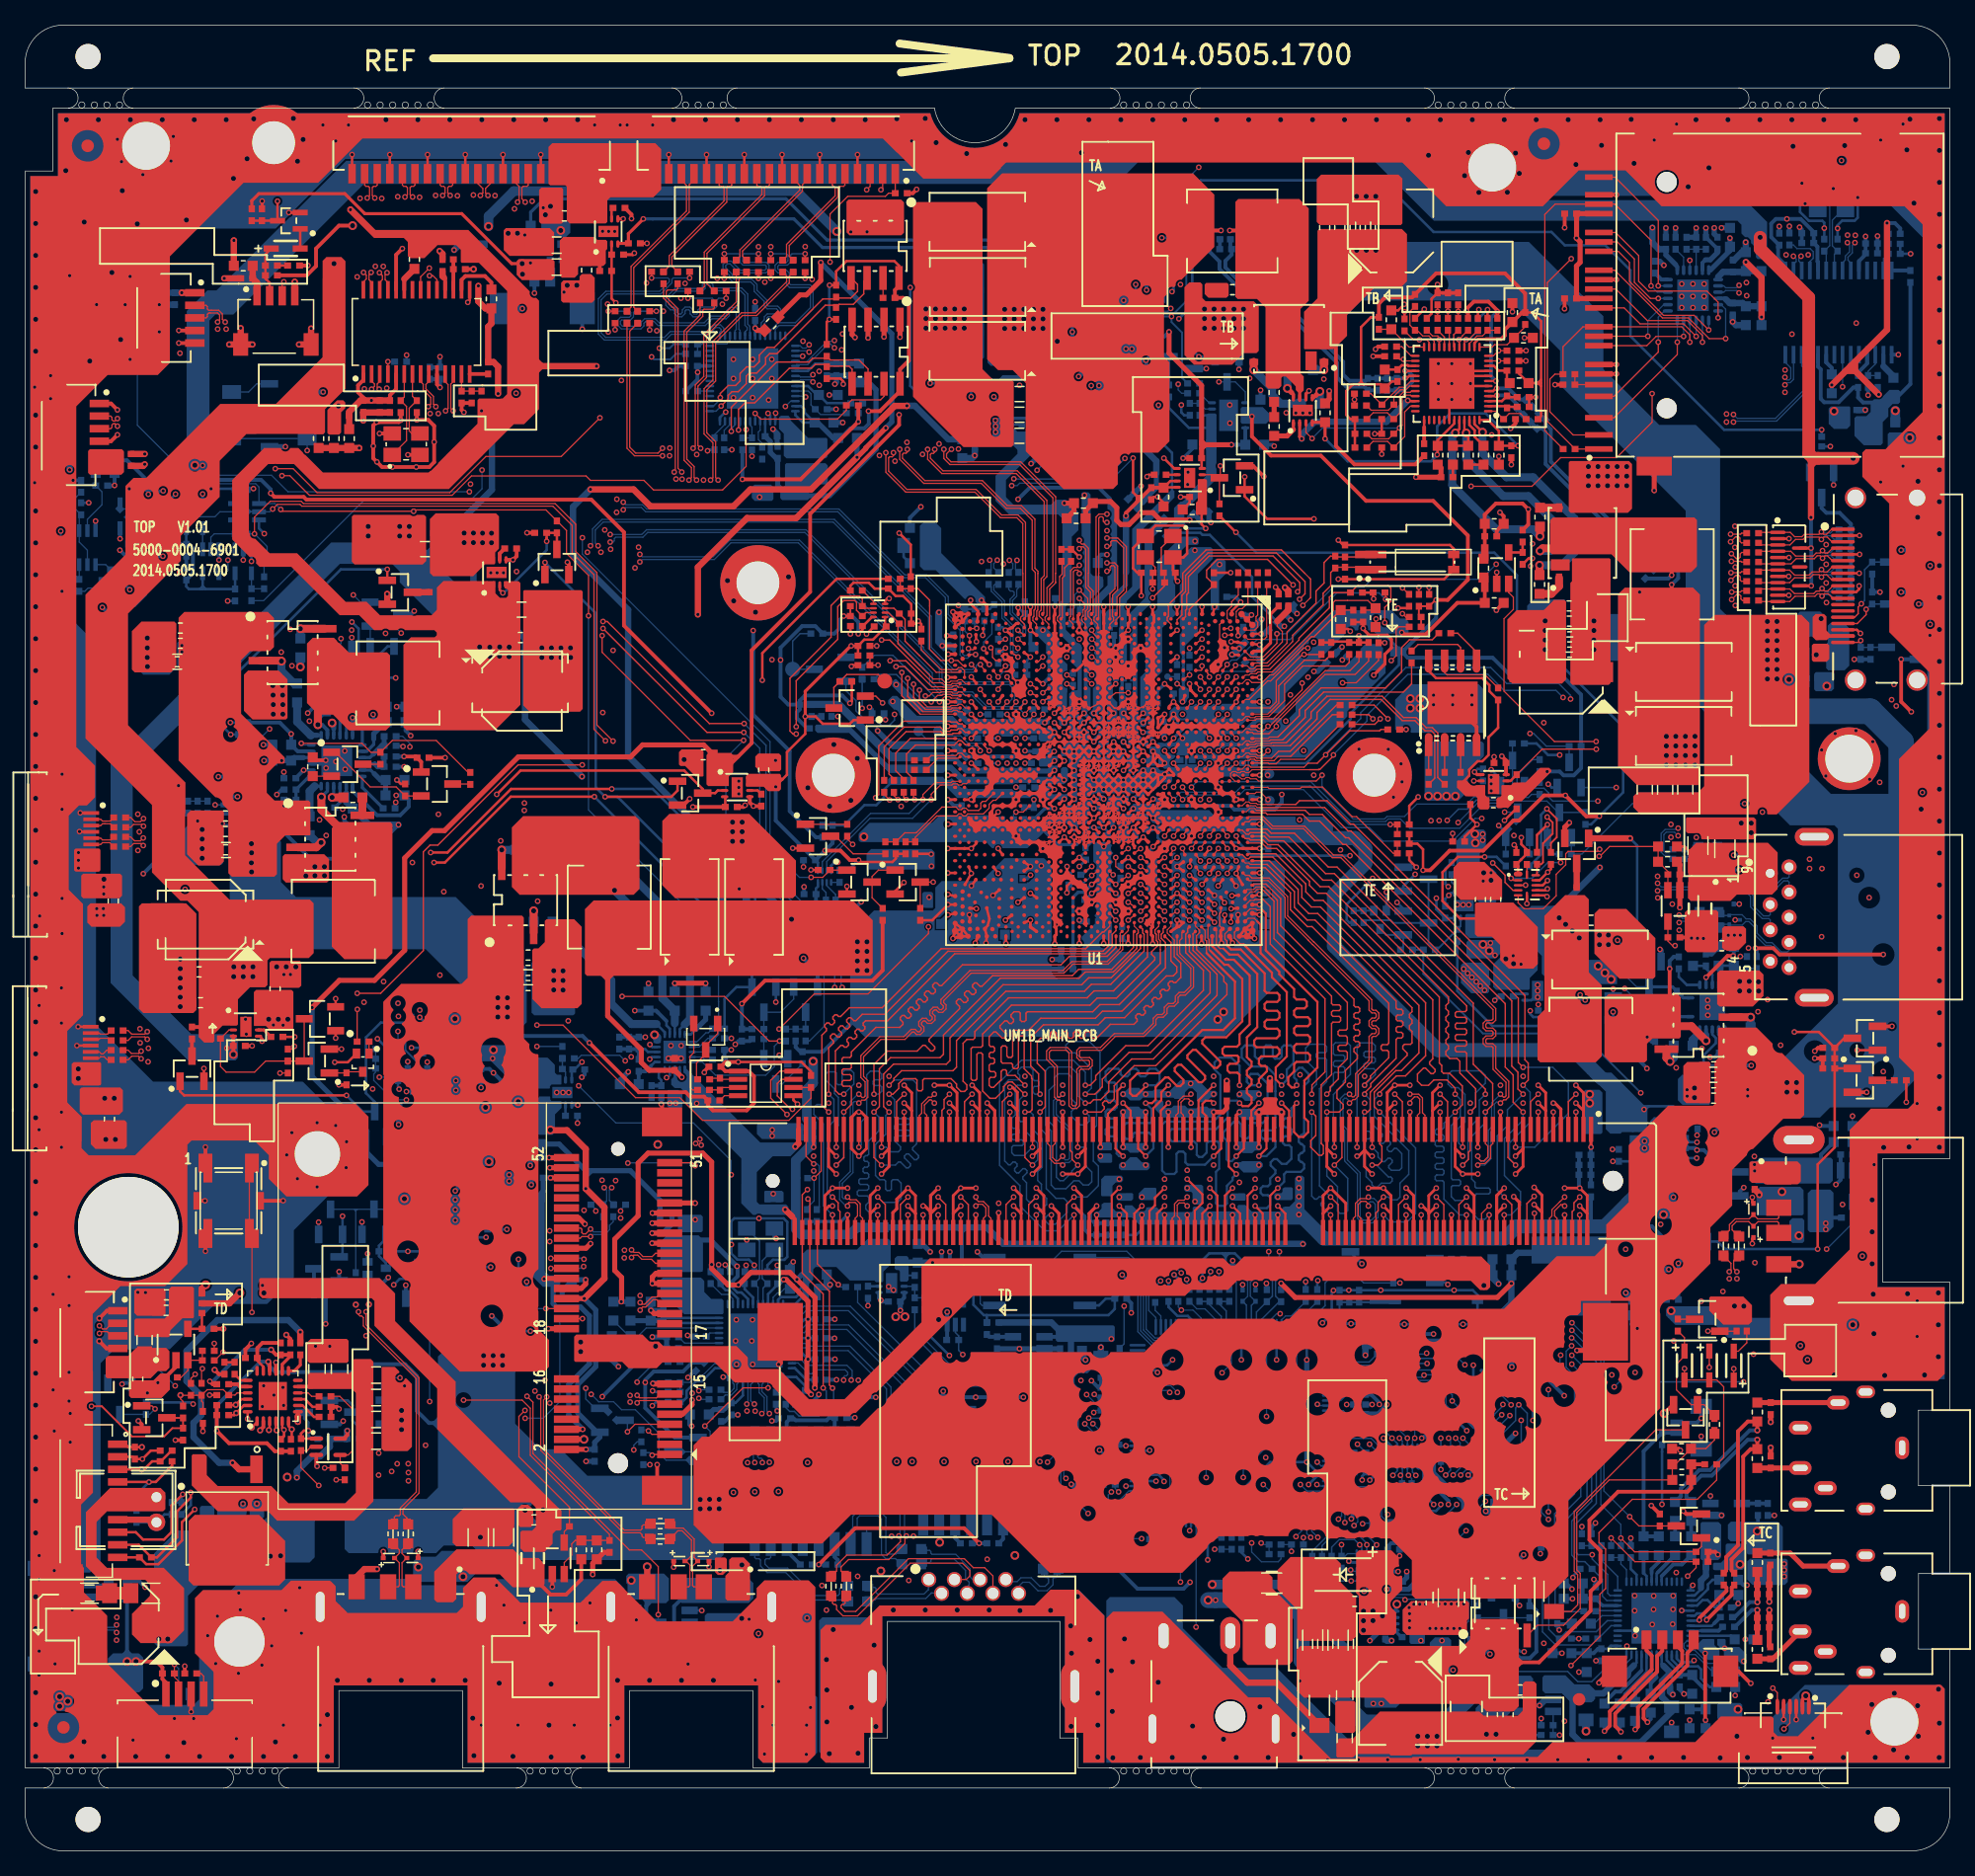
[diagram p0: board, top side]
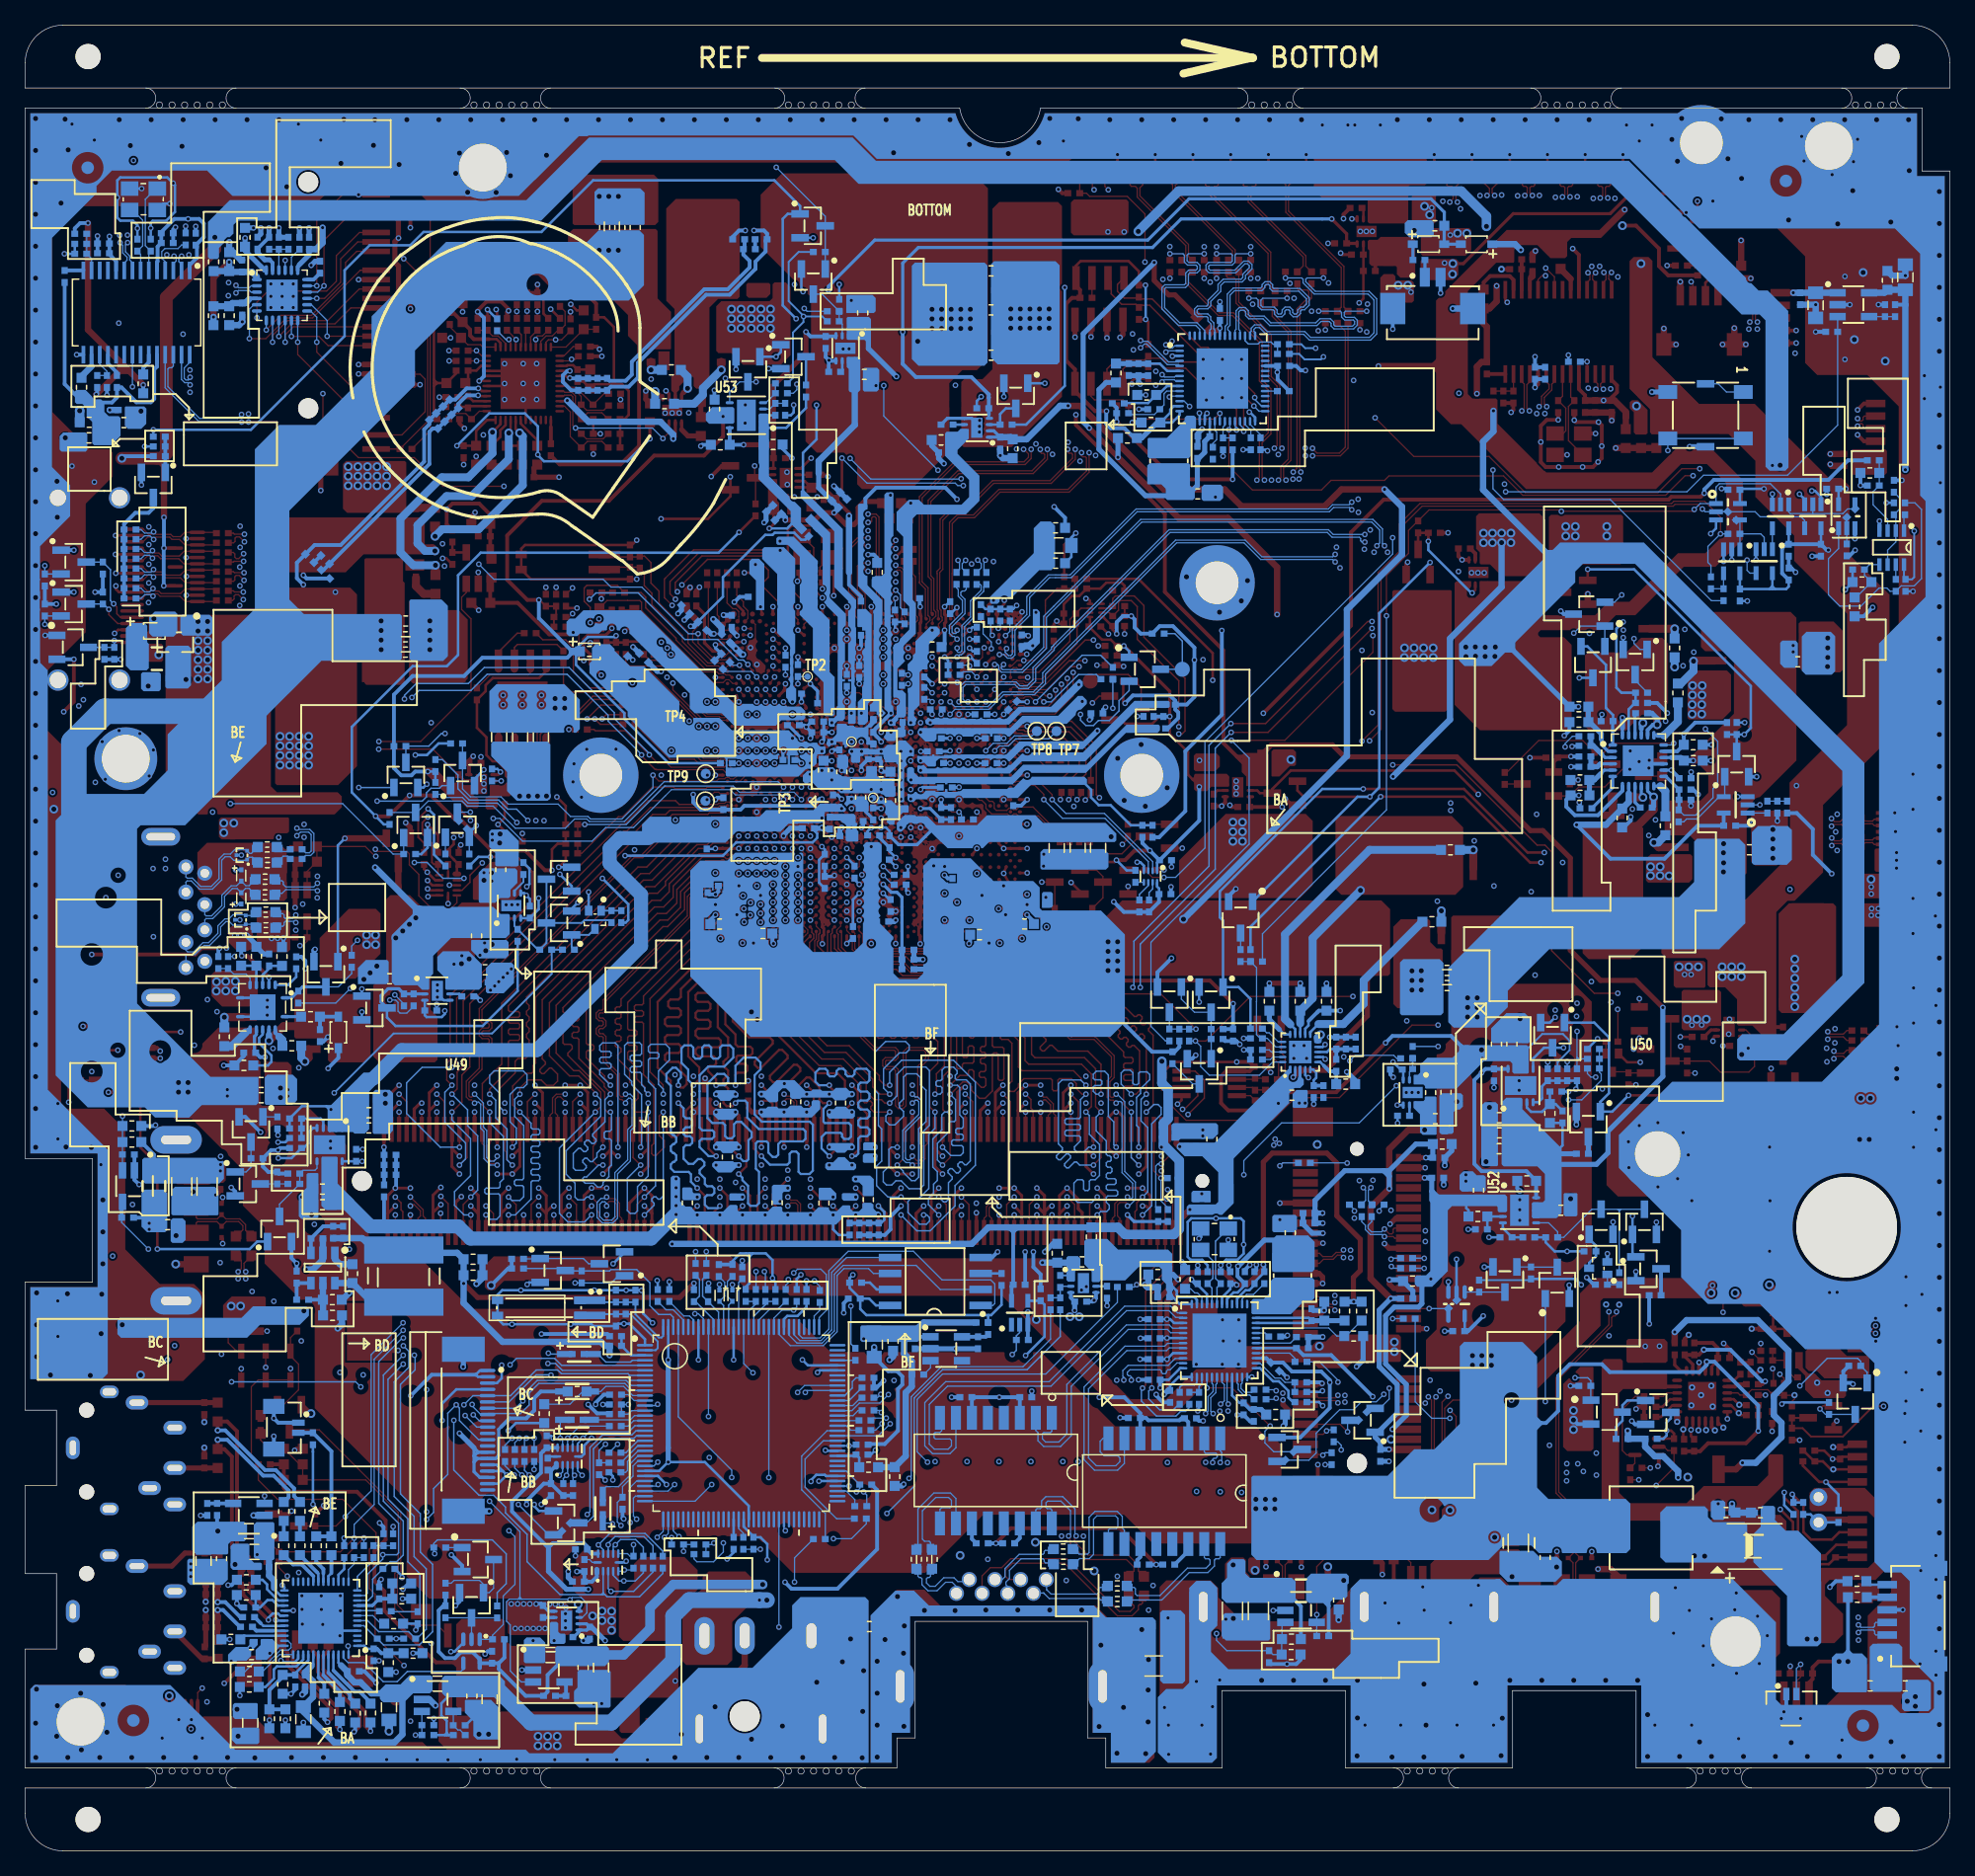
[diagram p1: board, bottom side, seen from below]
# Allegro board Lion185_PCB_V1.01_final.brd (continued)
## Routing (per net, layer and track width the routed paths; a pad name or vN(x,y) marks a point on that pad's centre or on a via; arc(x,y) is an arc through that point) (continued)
PM_SLP_S0IX#: length 403.6
  TOP w0.102: v2(20.26,61.86) R385.2 ; v2(20.32,106.68) 20.46,106.54 30.88,106.54 v2(30.88,106.53) 30.99,106.65 41.4,106.65 R383.2 43.03,105.01 43.03,103.19 44.78,101.44 v2(44.78,98.22)
  TOP w0.203: U6.7 120.88,75.99 v2(120.98,75.89)
  LAY3 w0.203: v2(142.81,113.02) 142.47,112.68 142.47,107.31 143.93,105.85 143.93,95.06 142.61,93.74 142.61,89.68 141.61,88.68 141.61,84.36 144,81.97 144,80.28 v2(141.85,78.12) 141.85,71.4 143.9,69.35 143.9,54.53 138.03,48.66 138.03,47.31 v2(137.5,46.78)
  LAY4 w0.102: v2(20.26,61.86) 19.57,61.86 15.2,66.23 15.2,81.58 14.58,82.19 14.58,94.52 20.32,100.26 v2(20.32,106.68)
  LAY4 w0.203: v2(120.98,75.89) 126.6,75.89 128.69,77.98 132.61,77.98 134.53,79.89 140.08,79.89 v2(141.85,78.12) ; v2(102.76,45.36) 105.25,47.85 123.01,47.85 126.31,51.15 133.13,51.15 v2(137.5,46.78) ; v2(91.71,121.85) 91.28,121.42 84.96,121.42 82.82,123.56 71.05,123.56 69.94,122.45 63.2,122.45 62.28,121.53 48.21,121.53 38.53,111.85 36.2,111.85 v2(30.88,106.53)
  BOTTOM w0.102: v2(20.32,106.68) 19.85,107.15 U37.1 18.59,108.46 18.32,108.73 14.27,108.73 13.46,107.92 U38.2 ; v2(44.78,98.22) 44.78,82.79 54.64,72.93 R433.2
  BOTTOM w0.203: R502.2 v2(142.81,113.02) 135.06,113.02 127.61,120.47 127.61,125.7 125.62,127.69 122.39,127.69 121.33,128.75 111.96,128.75 107.85,132.86 93.44,132.86 91.4,130.81 Q77.1 92.38,130.19 92.78,129.79 92.78,122.91 v2(91.71,121.85) ; v2(102.76,45.36) 102.71,45.31 R329.1
PM_SLP_S3#: length 384.4
  TOP w0.203: v2(121.01,77.17) 120.64,76.79 U6.9 ; Q48.1 v2(145.63,63.68) ; v2(32.5,78.6) 33.37,78.6 38.6,83.84 v2(45.25,83.84) ; R497.2 115.48,122.51 v2(115.56,122.58)
  LAY3 w0.203: v2(145.63,63.68) 145.61,63.7 v2(145.61,77.59) 145.61,81.68 142.32,84.97 142.32,88.38 144.32,90.38 144.32,93.82 144.84,94.33 144.84,106.46 144.24,107.05 144.24,110.95 v2(143.5,111.69) ; v2(30.78,78.6) v2(32.5,78.6)
  LAY4 w0.203: v2(121.01,77.17) 121.78,77.17 121.94,77.01 126.53,77.01 128.16,78.64 132.34,78.64 136.02,82.31 137.67,82.31 137.91,82.07 143.3,82.07 145.61,79.76 v2(145.61,77.59) ; v2(143.5,111.69) 129.55,111.69 119.34,121.91 116.23,121.91 v2(115.56,122.58) 115.56,123.19 114.67,124.08 91.71,124.08 91.15,124.64 88.96,124.64 88.43,124.11 70.8,124.11 69.66,122.96 61.36,122.96 60.33,124 48.55,124 37.65,113.1 36.69,113.1 31.63,108.03 31.2,108.03 28.11,104.94 28.11,100.02 31.51,96.61 31.51,80.96 30.78,80.22 v2(30.78,78.6) ; v2(32.5,78.6) 32.52,78.58 32.52,65.75 33.53,64.74 33.53,39.07 44.32,28.28 49.65,28.28 52.55,31.19 55.23,31.19 55.7,31.66 62.82,31.66 63.68,32.52 67,32.52 68.24,33.76 81.67,33.76 85.04,30.38 89.53,30.38 v2(90.53,29.38)
  BOTTOM w0.203: U28.70 89.34,29.81 89.43,29.9 90.11,29.9 90.53,29.48 v2(90.53,29.38) ; R435.2 55.59,73.49 v2(45.25,83.84) ; R501.2 v2(143.5,111.69)
PM_SLP_S4#: length 370.1
  TOP w0.203: U6.8 120.89,76.39 v2(121.01,76.51) ; v2(32.24,79.4) 33.57,79.4 38.63,84.46 v2(46.63,84.46)
  LAY3 w0.203: v2(140.45,120.62) 142.1,118.98 142.1,107.06 143.63,105.53 143.63,95.22 142.3,93.9 142.3,90.01 140.56,88.27 140.56,80.15 v2(141.85,78.86) ; v2(39.03,115.93) 39.71,115.93 49.56,106.08 49.56,102.43 47.22,100.09 47.22,85.04 v2(46.63,84.46)
  LAY4 w0.203: v2(141.85,78.86) 140.38,80.33 134.49,80.33 132.47,78.31 128.26,78.31 126.46,76.51 v2(121.01,76.51) ; v2(39.03,115.93) 39.03,117.71 47.45,126.13 49.34,126.13 51.23,128.02 63.1,128.02 64.97,126.15 121.87,126.15 123.61,124.4 127.67,124.4 128.54,125.27 133.77,125.27 136.09,122.96 139.51,122.96 140.45,122.02 v2(140.45,120.62) ; v2(89.9,29.4) 89.26,30.04 84.95,30.04 81.54,33.45 68.37,33.45 67.12,32.21 63.8,32.21 62.94,31.35 55.85,31.35 55.38,30.88 52.68,30.88 49.77,27.97 44.04,27.97 33.1,38.92 33.1,64.55 32.03,65.62 32.03,79.19 v2(32.24,79.4)
  BOTTOM w0.203: v2(89.9,29.4) 89.89,29.41 U28.69 ; R440.1 55.59,67.75 56.54,68.7 Q38.1 57.78,73.99 58.03,74.24 58.03,76.31 56.88,77.46 49.89,84.46 v2(46.63,84.46)
PMC_ACPRESENT: length 33
  TOP w0.102: U1.D20 v2(96.27,88.48)
  LAY3 w0.127: v2(119.62,88.87) 115.75,92.74 105.46,92.74 104.91,93.3 103.01,93.3 100.42,90.7 97.81,90.7 96.27,89.17 v2(96.27,88.48)
  BOTTOM w0.114: v2(119.62,88.87) 119.63,88.86 119.92,88.86 120.92,87.86 R83.2 Q3.3
PMC_PLTRST: length 47.7
  TOP w0.102: U1.F20 v2(95.56,88.48)
  TOP w0.114: v2(118.12,77.35) 118.28,77.19 U6.2
  LAY3 w0.127: v2(122.06,78.6) 121.59,79.08 121.59,89.55 117.17,93.97 102.92,93.97 102.68,94.22 101.96,94.22 99.89,92.15 99.89,91.59 99.3,90.99 97.65,90.99 95.56,88.9 v2(95.56,88.48)
  BOTTOM w0.114: v2(122.06,78.6) 121.04,78.6 119.79,77.35 v2(118.12,77.35)
PMC_PWRBTN#: length 131
  TOP w0.102: U1.J26 v2(94.14,86.5)
  TOP w0.114: R709.2 v2(113.48,80.91)
  LAY3 w0.127: v2(94.14,86.5) 94.57,86.07 95.67,86.07 95.9,85.84 96.88,85.84 97.02,85.98 100.32,85.98 101.61,84.69 103.65,84.69 105.63,82.71 109.97,82.71 110.33,83.07 112.85,83.07 113.48,82.45 v2(113.48,80.91) 113.48,79.55 114.13,78.91 114.13,76.8 119.6,71.33 122.2,71.33 127.51,66.02 127.51,57.66 128.1,57.07 128.1,52.04 126.56,50.5 126.56,37.14 v2(126.32,36.9)
  LAY4 w0.127: v2(136.59,37.3) 131.49,37.3 124.25,30.06 124.25,25.44 120.27,21.47 v2(105.41,21.47)
  BOTTOM w0.114: v2(126.32,36.9) 126.72,37.3 v2(136.59,37.3) ; R654.1 103.86,22.11 104.5,21.47 v2(105.41,21.47) 105.8,21.47 106.25,21.92 U26.4
PMC_PWRBTN#_EC: length 17.8
  LAY4 w0.127: v2(106.09,24.34) 106.09,24.52 v2(108.32,26.76)
  BOTTOM w0.114: v2(108.32,26.76) 108.1,26.97 108.1,32.08 107.11,33.08 104.77,33.08 104.43,33.41 U28.18 ; R654.2 103.86,24.15 104.47,24.76 105.67,24.76 v2(106.09,24.34) 106.25,24.17 U26.8
PMC_RSTBTN: length 209.4
  TOP w0.102: 71.9,98.99 71.9,95.58 72.81,94.67 v2(73.62,94.67) 74.15,94.67 74.57,94.25 U1.BG9
  TOP w0.114: v2(44.29,86.37) 39.19,86.37 32.8,79.98 32.18,79.98 31.65,79.46 31.65,71.6 28.26,68.2 v2(26.4,68.2) ; 71.9,98.99 71.9,99.47 70.98,100.39 R58.2 R57.1 R56.1
  LAY4 w0.127: v2(106.43,20.64) 98.46,20.64 94.71,24.38 88.54,24.38 81.12,31.8 69.24,31.8 68.17,30.73 65.04,30.73 63.55,29.24 53.1,29.24 50.07,26.2 43.55,26.2 41.71,28.04 31.33,28.04 30.43,27.14 29.13,27.14 26.17,30.1 26.17,40.17 24.96,41.38 24.96,45.11 24.55,45.52 24.55,49.12 26,50.57 26,67.81 v2(26.4,68.2) ; v2(44.29,86.37) 44.29,87.1 51.34,94.16 62.44,94.16 62.87,94.59 67.07,94.59 67.6,95.12 71.72,95.12 72.17,94.67 v2(73.62,94.67)
  BOTTOM w0.114: U26.3 106.65,20.86 v2(106.43,20.64) 104.63,20.64 103.09,22.17 R653.1
PMC_SLP_S0IX: length 58.1
  TOP w0.102: U1.F18 v2(95.56,90.39) ; v2(125.16,79.65) 124.99,79.49 122.65,79.49 122.47,79.3 122.47,78.42 121.71,77.66 121.71,75.96 120.68,74.93 119.15,74.93 118.68,75.4 U6.5
  LAY3 w0.102: v2(125.16,79.65) 124.48,80.33 124.48,88.85 117.28,96.05 109.43,96.05 108.51,96.97 108.51,97.79 107.95,98.36 106.64,98.36 106.23,97.95 104.75,97.95 104.05,97.25 101.51,97.25 98.74,94.48 98.74,93.32 96.25,90.83 96,90.83 v2(95.56,90.39)
PMC_SLP_S3: length 40.8
  TOP w0.102: v2(95.56,87.49) U1.D22
  TOP w0.114: U6.3 119.26,76.79 v2(119.28,76.81)
  LAY3 w0.127: v2(95.56,87.49) 95.95,87.89 96.66,87.89 97.2,88.42 97.2,89.11 98.38,90.29 101.07,90.29 102.1,91.33 103.22,92.44 115.32,92.44 119.46,88.31 119.46,76.99 v2(119.28,76.81)
PMC_SLP_S4: length 33.2
  TOP w0.102: U1.F22 v2(94.85,87.49)
  TOP w0.114: v2(116.66,78.57) 117.64,77.59 117.64,77.03 118.28,76.39 U6.4
  LAY3 w0.127: v2(94.85,87.49) 95.28,87.06 102.35,87.06 102.84,86.58 104.34,86.58 105.87,88.1 108.73,88.1 109.25,87.58 111.38,87.58 114.59,84.37 114.59,79.92 115.95,78.57 v2(116.66,78.57)
PMC_SUS_STAT#: length 121.2
  TOP w0.102: U1.G18 v2(94.85,90.39)
  LAY3 w0.127: v2(114.12,29.89) 114.58,29.43 122.48,29.43 129.86,36.81 129.86,47.97 132.2,50.31 132.2,52.78 131.7,53.29 131.7,60.95 132.63,61.88 132.63,63.46 131.25,64.84 131.25,68.28 128.67,70.86 128.67,73.01 123.99,77.7 123.99,88.65 117.07,95.56 105.9,95.56 104.67,96.79 101.83,96.79 100.89,95.85 100.89,95.08 95.71,89.9 95.19,89.9 94.85,90.24 v2(94.85,90.39)
  LAY4 w0.127: v2(108.73,29.87) 109.63,28.96 113.19,28.96 v2(114.12,29.89)
  BOTTOM w0.114: v2(114.12,29.89) 114.86,30.63 R656.1 ; U27.5 109.08,30.22 v2(108.73,29.87)
PMC_SUSPWRDNACK: length 89
  TOP w0.102: U1.D26 v2(96.27,86.5)
  LAY3 w0.127: v2(127.23,47.85) 127.23,50.49 129.14,52.4 129.14,57.29 128,58.43 128,66.23 121.9,72.33 120.14,72.33 114.81,77.65 114.81,79.24 114.33,79.73 114.33,84.15 113.68,84.8 110.87,84.8 109.37,83.3 105.97,83.3 103.09,86.18 102.45,86.18 102.12,86.5 v2(96.27,86.5)
  LAY4 w0.127: v2(127.23,47.85) 126.06,46.68 110.79,46.68 v2(109.28,45.17)
  BOTTOM w0.102: R76.1 v2(96.27,86.5)
  BOTTOM w0.114: v2(109.28,45.17) R317.1 106.4,45.17 105.83,45.74 Q88.1
POWSW#: length 263.2
  TOP w0.102: v2(122.88,14.74) 125.18,17.04 125.18,20.4 125.64,20.86 125.64,24 125.11,24.53 125.11,25.31 127.76,27.96 132.93,27.96 134.47,29.5 R903.1 135.02,31.3 135.02,36.91 134.48,37.45 D34.N 133.87,37.44 D33.N v2(131.91,38.36) ; CN34.1 139.29,12.58 v2(138.93,12.94)
  LAY3 w0.102: v2(122.88,14.74) 122.88,13.94 123.88,12.94 v2(138.93,12.94) ; v2(30.45,30.79) 30.47,30.79 35.52,25.74 35.52,24.78 36.58,23.72 59.55,23.72 65.54,29.72 79.77,29.72 83.19,26.31 102.54,26.31 103.5,27.27 108.55,27.27 109.53,26.3 119.45,26.3 121.04,27.89 124.21,27.89 131.91,35.59 v2(131.91,38.36)
  LAY4 w0.102: v2(30.45,30.79) 30.94,31.28 30.94,58.14 29.35,59.73 29.35,62.84 28.83,63.36 28.83,67.46 29.94,68.56 29.94,80.45 31.06,81.57 31.06,96.28 27.62,99.72 27.62,102.13 22.42,107.33 v2(22.42,111.37)
  BOTTOM w0.102: SW4.3 SW4.4 v2(22.42,111.37)
PROCHOT#_EC: length 20.1
  LAY3 w0.127: v2(74.54,39.48) 77.44,39.48 84.65,32.26 87.45,32.26 v2(87.5,32.21)
  BOTTOM w0.114: U28.76 v2(87.5,32.21) 87.04,32.21 R340.2 ; U29.2 73.94,41.23 74.21,40.96 R347.2 74.21,39.8 v2(74.54,39.48)
PS_LATCH#: length 9.3
  TOP w0.102: R898.1 131.91,40.81 D33.P 131.91,39.35 131.27,38.71 131.27,36.66 132.45,35.48 Q78.1 133.47,35.48 R103.2 R901.1
PSELF: length 2.4
  TOP w0.305: R696.2 34.04,126.57 R697.1 U77.17
PSELF_1: length 2.7
  BOTTOM w0.102: U83.17 147.07,118.24 146.5,117.67 R740.1 R739.2
PSMS: length 1.9
  BOTTOM w0.102: U95.20 131.83,126.74 R800.1
PWM IN: length 162.3
  TOP w0.102: R165.1 14.47,36.68 15.76,36.68 R356.2 16.68,36.25 16.85,36.42 U25.21 ; R165.1 R176.2 12.36,36.23 v3(12.35,36.24) 12.35,35.95 12.55,35.74 R751.1 ; R165.1 14.02,35.76 14.13,35.66 R182.1 ; v2(66.9,132.11) 67.17,132.38 CN18.3
  LAY4 w0.102: v2(66.9,132.11) 64.55,134.46 24.2,134.46 22.07,132.32 17.34,132.32 8.72,123.7 8.72,84.57 11.68,81.6 11.68,58.74 12.7,57.71 12.7,36.6 v3(12.35,36.24)
PWR_LED_WHITE: length 63.3
  TOP w0.102: v2(139.81,9.7) 140.29,10.17 CN34.3
  LAY4 w0.102: v2(93.08,17.8) 93.08,15.59 95.69,12.97 120.22,12.97 121.62,11.57 121.62,10.38 123.15,8.85 134.49,8.85 135.34,9.7 v2(139.81,9.7)
  BOTTOM w0.102: v2(93.08,17.8) U28.56
PWR_SW: length 26.6
  TOP w0.406: CN30.M9 C709.1 123.33,128.27 v2(123.32,128.27) 123.61,127.98 123.61,126.33 123.32,126.05 C708.1 CN30.S4
  LAY3 w0.406: v2(135.52,128.27) 134.94,127.69 123.9,127.69 v2(123.32,128.27)
  BOTTOM w0.102: 133.97,125.72 133.93,125.72
  BOTTOM w0.254: 133.93,125.72 U95.24
  BOTTOM w0.406: 133.97,125.72 135.52,127.27 C704.1 135.52,128.26 v2(135.52,128.27)
PWRONLATCHG: length 27.7
  TOP w0.102: R901.2 R103.1 134.29,32.67 133.61,31.99 132.44,31.99 C600.2 131.18,30.74 C585.1 R899.1 125.93,29.5 123.35,26.92 123.35,22.34 123.62,22.07 123.62,19.27 122.3,17.95 120.22,17.95 Q65.4
R_OUT+: length 9.7
  TOP w0.305: v2(125.55,9.52) 125.97,9.95 125.97,11.09 127.89,13.01 127.89,13.01 129.3,14.42 129.3,15.52 128.89,15.93 CN20.1
  BOTTOM w0.305: R284.1 v2(125.55,9.52)
R_OUT-: length 9.8
  TOP w0.305: CN20.2 130.14,15.9 129.73,15.5 129.73,14.25 126.4,10.92 126.4,9.93 v2(126.85,9.47)
  BOTTOM w0.305: v2(126.85,9.47) 126.76,9.56 R283.1
REXT: length 1.5
  BOTTOM w0.102: U10.26 56.03,113.44 55.57,112.98 R161.2
RLV_AMP: length 1.7
  BOTTOM w0.102: R159.2 54.8,112.62 55.63,113.45 U10.27
RLV_CFG: length 2.2
  BOTTOM w0.102: 57.78,112.37 57.78,113.24 57.63,113.38 U10.22 ; 57.78,112.37 R186.1 ; 57.78,112.37 R189.2
RLV_LNK: length 13
  TOP w0.102: U13.7 68.27,115.68 67.99,115.4 65.72,115.4 R185.1 65.28,114.58 64.57,113.87 58.48,113.87 v2(58.03,114.32)
  BOTTOM w0.102: U10.21 v2(58.03,114.32)
RSET: length 2.2
  BOTTOM w0.102: R209.2 60.35,44.7 60.02,44.37 59.81,44.37 59.46,44.02 U17.46
RSMRST#_EC: length 12
  BOTTOM w0.114: R332.2 Q69.3 108.35,26.08 107.82,26.61 107.82,31.98 107,32.81 104.61,32.81 104.41,33.01 U28.19
RSTZ: length 3.2
  BOTTOM w0.102: U95.22 C707.1 ; C707.1 R802.2 ; C707.1 R801.2
RTA: length 1.9
  TOP w0.203: U25.9 22.24,35.92 22.85,35.31 R958.2
RUNTIME_SCI#_EC: length 6
  LAY4 w0.102: v2(104.64,24.35) 104.66,24.35 v2(106.32,26.01)
  BOTTOM w0.102: R319.1 D10.P 106.37,26.07 v2(106.32,26.01) ; U26.7 105.12,23.64 104.91,23.44 R655.2
  BOTTOM w0.114: v2(104.64,24.35) R655.2
S0IX#_DISCHARGE: length 187
  LAY3 w0.102: v2(139.55,64.07) 139.32,64.3 139.32,68.98 138,70.29 138,71.06 138.46,71.51 138.46,72.5 137.69,73.27 137.69,78.26 138.82,79.39 138.82,89.44 140.75,91.38 140.75,100.17 139.39,101.53 139.39,120.17 141.4,122.18 144.71,122.18 146.87,124.33 146.87,131.95 v2(144.39,134.43)
  LAY4 w0.102: v2(139.55,64.07) 136.32,64.07 134.05,61.8 121.83,61.8 119.15,64.48 119.15,67.35 119.85,68.05 119.85,71.94 117.31,74.48 112.83,74.48 112.2,75.12 112.19,75.12 110.49,76.81 v2(110.49,77.66) ; v2(93.29,133.89) 108.84,133.89 111.48,131.26 119.99,131.26 121.14,132.41 127.49,132.41 129.84,134.76 144.07,134.76 v2(144.39,134.43)
  BOTTOM w0.102: v2(93.29,133.89) 89.4,130 Q77.3 R504.2 Q76.1
  BOTTOM w0.203: v2(110.49,77.66) 109.56,76.73 Q80.1
S3_DISCHARGE: length 300.8
  TOP w0.203: C539.1 R574.2 R562.1 ; C539.1 143.85,55.95 142.49,54.59 v2(142.49,47.86) ; C539.1 Q53.1 ; R562.1 144.61,64.63 Q48.3 ; R562.1 142.59,65.12 v2(140.64,65.12) ; v2(102.45,105.94) 98.73,105.94 96.94,107.73 Q83.1 96.94,109.22 96.95,109.23 v2(96.95,109.28) ; Q82.1 51.86,84.33 51.37,83.83 v2(46.1,83.83) ; v2(24.68,64.64) Q84.1 ; Q54.1 v2(41.32,102.47)
  LAY3 w0.203: v2(71.94,116.72) 78.89,116.72 v2(79.05,116.56) ; v2(130.94,75.3) 131.5,75.86 131.5,79.86 135.56,83.92 135.56,93.65 123.28,105.94 v2(102.45,105.94) ; v2(24.68,64.64) 25.67,64.64 29.71,68.68 36.31,68.68 46.1,78.48 v2(46.1,83.83)
  LAY4 w0.203: v2(41.32,102.47) 41,102.78 41,106.83 47.79,113.62 58.16,113.62 59.69,112.09 69.15,112.09 71.94,114.87 v2(71.94,116.72) ; v2(24.68,64.64) 20.29,60.25 20.29,54.11 23.92,50.48 v2(25.23,50.48) ; v2(140.64,65.12) 135.82,65.12 135.25,65.69 129.09,65.69 v2(126.24,68.55) 126.03,68.55 121.35,73.24 121.35,74.67 121.98,75.3 v2(130.94,75.3) ; v2(79.05,116.56) 83.18,112.43 93.79,112.43 v2(96.95,109.28)
  BOTTOM w0.203: v2(142.49,47.86) 135.15,47.86 134.55,48.46 Q74.1 ; Q81.1 v2(126.24,68.55) ; v2(71.94,116.72) Q75.1 ; v2(41.32,102.47) 45.36,98.43 45.36,84.58 v2(46.1,83.83) 47.09,83.83 Q36.1 ; Q51.1 25.23,47.51 Q86.1 v2(25.23,50.48)
S4_DISCHARGE: length 7.5
  BOTTOM w0.102: Q39.1 61.09,67.74 60.05,66.7 Q38.3 58.72,66.69 R448.1 58.73,65.35 R451.2 58.72,64.56 Q61.1
SA0_DIM0: length 7.3
  TOP w0.102: v2(62.71,53.5) 63.28,54.06 CN3.197
  BOTTOM w0.102: R122.1 62.16,51.14 62.71,51.7 v2(62.71,53.5) R121.1
SA1_DIM0: length 7.1
  TOP w0.102: CN3.201 62.08,55.24 v2(62.69,54.63)
  BOTTOM w0.102: R123.1 63.12,51.2 63.12,54.47 62.96,54.63 v2(62.69,54.63)
SATA_LED#: length 12.5
  TOP w0.102: U1.AY12 v2(78.06,93.36) ; v2(67.69,95.83) R36.1
  LAY3 w0.102: v2(78.06,93.36) 77.57,93.85 71.13,93.85 69.15,95.83 v2(67.69,95.83)
SATA_RXN0: length 112.6
  TOP w0.101: U1.AV16 v2(79.48,91.38) ; v2(9.22,63.6) 9.03,63.42 8.45,63.42 8.18,63.68 R160.1
  LAY3 w0.101: v2(48.86,103.11) 48.68,102.93 48.09,102.93 42.26,97.1 35.22,97.1 32.69,99.63 29.75,99.63 28.97,98.84 20.61,98.84 11.2,89.43 11.2,64.3 10.28,63.39 9.43,63.39 v2(9.22,63.6)
  BOTTOM w0.101: 66.81,98.98 66.83,98.97 72.11,93.68 72.11,92.91 72.86,92.17 75.3,92.17 76.47,91 79.1,91 v2(79.48,91.38)
  BOTTOM w0.102: 66.81,98.98 61.55,104.24 56.01,104.24 54.69,102.92 49.06,102.92 v2(48.86,103.11)
SATA_RXN1: length 108.4
  TOP w0.101: C159.1 8.39,80.64 8.7,80.33 9.16,80.33 v2(9.39,80.56) ; v2(78.06,91.38) U1.BA16
  LAY3 w0.101: v2(46.51,104.09) 46.3,104.09 46.19,104.2 46.19,104.34 46.08,104.45 45.6,104.45 43.75,106.3 34.54,106.3 33.3,107.53 23.5,107.53 21.64,105.67 15.08,105.67 6.97,97.56 6.97,79.44 7.09,79.32 7.87,79.32 8.71,80.16 8.94,80.16 9.05,80.26 9.05,80.47 9.14,80.56 v2(9.39,80.56)
  BOTTOM w0.101: v2(78.06,91.38) 78.23,91.38 78.45,91.6 78.45,92.53 78.23,92.76 74.32,92.76 74.01,92.44 73.26,92.44 72.67,93.03 72.67,94.02 71.2,95.49 71.2,95.64 61.98,104.85 49.48,104.85 49.11,104.48 46.94,104.48 46.84,104.37 46.84,104.2 46.73,104.09 v2(46.51,104.09)
SATA_RXP0: length 112.6
  TOP w0.101: v2(9.22,63) 9.02,63.2 8.47,63.2 8.18,62.91 R168.1 ; U1.AU16 v2(79.48,90.39)
  LAY3 w0.101: v2(48.86,102.51) 48.64,102.73 48.18,102.73 42.34,96.89 35.13,96.89 32.6,99.42 29.83,99.42 29.05,98.64 20.69,98.64 11.4,89.35 11.4,64.22 10.36,63.18 9.42,63.18 9.34,63.1 9.32,63.1 v2(9.22,63)
  BOTTOM w0.101: v2(79.48,90.39) 79.08,90.79 76.38,90.79 75.21,91.96 72.77,91.96 71.9,92.83 71.9,93.59 66.72,98.77 66.66,98.83
  BOTTOM w0.102: 66.66,98.83 61.46,104.03 56.1,104.03 54.78,102.7 49.06,102.7 v2(48.86,102.51)
SATA_RXP1: length 108.4
  TOP w0.101: v2(78.77,91.38) U1.AY16 ; v2(9.39,79.95) 9.23,80.11 8.63,80.11 8.39,79.87 C163.1
  LAY3 w0.101: v2(46.51,104.69) 46.47,104.65 45.68,104.65 43.83,106.5 34.62,106.5 33.39,107.74 23.42,107.74 21.55,105.87 14.99,105.87 6.76,97.64 6.76,79.36 7.01,79.11 7.95,79.11 8.79,79.95 v2(9.39,79.95)
  BOTTOM w0.101: v2(78.77,91.38) 78.65,91.5 78.65,92.64 78.32,92.97 74.23,92.97 73.92,92.66 73.35,92.66 72.89,93.12 72.89,94.11 71.41,95.58 71.41,95.73 71.36,95.78 71.34,95.78 71.26,95.87 71.26,95.89 62.07,105.07 49.39,105.07 49.02,104.69 v2(46.51,104.69)
SATA_TXN0: length 113.6
  TOP w0.101: C165.1 8.19,64.46 8.47,64.74 9.51,64.74 v2(9.71,64.55) ; U1.BG7 75.07,95.14 v2(75.55,95.14)
  LAY3 w0.101: v2(9.71,64.55) 9.9,64.74 10.22,64.74 10.58,65.1 10.58,89.79 21.6,100.81 32.52,100.81 35.44,97.88 42.16,97.88 47.67,103.4 47.67,104.86 46.49,106.04 46.49,106.5 46.86,106.87 47.33,106.87 v2(47.55,106.66)
  BOTTOM w0.089: 71.1,101.26 71.56,101.26
  BOTTOM w0.101: v2(75.55,95.14) 75.2,95.14 74.91,94.86 74.57,94.86 74.32,95.1 74.32,97.08 73.15,98.25 73.15,99.67 71.56,101.26 ; 71.1,101.26 69.84,101.26 64.6,106.5 49.32,106.5 48.98,106.84 47.73,106.84 v2(47.55,106.66)
SATA_TXN1: length 100.8
  TOP w0.101: U1.BF10 75.57,94 v2(75.22,94.35) ; C274.1 8.39,81.41 8.61,81.63 9.27,81.63 v2(9.41,81.49)
  LAY3 w0.101: v2(9.41,81.49) 9.26,81.64 8.58,81.64 8.18,82.03 8.18,96.56 12.44,100.82 18.93,100.82 21.05,102.94 32.14,102.94 35.87,99.21 41.68,99.21 45.1,102.64 45.1,103.63 v2(44.94,103.79)
  BOTTOM w0.101: v2(44.94,103.79) 44.94,103.79 45.1,103.95 45.1,105.13 45.87,105.89 64.32,105.89 68.45,101.77 71.26,98.96 71.26,98.96 72.03,98.19 72.03,95.72 73.81,93.94 75.3,93.94 75.4,94.04 75.4,94.18 v2(75.22,94.35)
SATA_TXP0: length 113.6
  TOP w0.101: v2(9.71,65.15) 9.51,64.96 8.47,64.96 8.18,65.24 C156.1 ; v2(74.98,95.62) 75.08,95.53 75.37,95.53 U1.BF6
  LAY3 w0.101: v2(9.71,65.15) 9.91,64.94 10.14,64.94 10.38,65.18 10.38,89.87 21.52,101.01 32.6,101.01 35.52,98.09 42.08,98.09 47.47,103.48 47.47,104.77 46.29,105.95 46.29,106.59 46.77,107.07 47.36,107.07 v2(47.55,107.26)
  BOTTOM w0.089: 71.1,101.48 71.65,101.48
  BOTTOM w0.101: v2(74.98,95.62) 75.1,95.51 75.1,95.33 74.83,95.06 74.65,95.06 74.52,95.19 74.52,97.18 73.38,98.33 73.38,99.75 71.65,101.48 ; 71.1,101.48 69.93,101.48 64.69,106.72 49.41,106.72 49.07,107.05 47.75,107.05 v2(47.55,107.26)
SATA_TXP1: length 100.8
  TOP w0.101: v2(9.41,82.1) 9.16,81.85 8.72,81.85 8.39,82.18 C273.1 ; U1.BD10 v2(75.93,94.35)
  LAY3 w0.101: v2(9.41,82.1) 9.16,81.84 8.66,81.84 8.38,82.12 8.38,96.48 12.52,100.62 19.01,100.62 21.14,102.74 32.05,102.74 35.78,99.01 41.76,99.01 45.31,102.56 45.31,103.56 v2(45.54,103.79)
  BOTTOM w0.101: v2(45.54,103.79) 45.32,104.02 45.32,105.04 45.95,105.68 64.24,105.68 71.81,98.1 71.81,95.63 73.7,93.74 75.39,93.74 75.6,93.96 75.6,94.25 75.7,94.35 v2(75.93,94.35)
SCL_CONN: length 7.2
  TOP w0.114: CN8.15 145.43,98.11 145.71,98.39 145.71,98.93 v2(145.96,99.18)
  BOTTOM w0.114: Q9.3 R204.2 146.22,101.89 146.22,99.44 v2(145.96,99.18)
SD_CDZ: length 29
  TOP w0.102: CN30.CD R803.2 121.01,113.69 121.01,124.72 v2(122.91,126.62)
  LAY3 w0.102: v2(132.33,126.5) 132.2,126.62 v2(122.91,126.62)
  BOTTOM w0.102: U95.21 132.33,126.49 v2(132.33,126.5)
SD_CLK: length 7.3
  TOP w0.102: CN30.S5 v2(128.99,120.46)
  BOTTOM w0.102: U95.14 130.25,122.97 128.99,121.71 v2(128.99,120.46)
SD_CMD: length 8.4
  TOP w0.102: CN30.S2 126.56,127.96 127.92,126.61 127.92,124.75 129.2,123.47 v2(129.82,123.47)
  BOTTOM w0.102: U95.15 v2(129.82,123.47)
SD_D0: length 9.9
  TOP w0.102: v2(129.82,119.99) 129.82,119.2 126.3,115.68 CN30.S7
  BOTTOM w0.102: U95.13 130.31,122.47 129.82,121.98 v2(129.82,119.99)
SD_D1: length 11
  TOP w0.102: v2(131.33,119.99) 131.33,119.01 126.3,113.98 CN30.S8
  BOTTOM w0.102: U95.12 v2(131.33,119.99)
SD_D2: length 12.1
  TOP w0.102: v2(129.82,124.47) 129.82,129.66 126.38,133.11 CN30.S9
  BOTTOM w0.102: U95.17 v2(129.82,124.47)
SD_D3: length 34.4
  TOP w0.102: R803.1 120.8,112.95 120.8,130.14 121.62,130.96 CN30.S1 126.38,130.96 129.25,128.09 v2(129.25,124.46)
  BOTTOM w0.102: U95.16 129.74,123.97 v2(129.25,124.46)
SD_WP/MS_D1: length 23.9
  TOP w0.102: CN30.WP1 123.06,112.61 121.21,114.46 121.21,117.05 121.6,117.44 R804.1 122.25,119.62 123.84,121.21 CN30.M3 131.68,121.21 132.33,120.56 v2(132.33,119.99)
  BOTTOM w0.102: U95.10 v2(132.33,119.99)
SDA_CONN: length 4.5
  TOP w0.114: v2(146.35,98.74) 146.35,98.32 145.64,97.61 CN8.16
  BOTTOM w0.114: v2(146.35,98.74) 146.77,99.16 R205.2 Q10.3
SECURITY_FLASH: length 10.8
  TOP w0.102: U1.BC30 76.35,83.47 76.11,83.47 75.97,83.33 75.97,82.92 75.8,82.75 74.97,82.75 74.79,82.93 74.55,82.93 74.43,82.81 74.21,82.81 74,83.01 72.88,83.01 70.83,80.97 69.93,80.97 R52.1 R54.2
SEL: length 1.8
  BOTTOM w0.203: R18.2 6.36,21.17 CN11.6
SELA: length 4.1
  TOP w0.203: U25.17 18.93,38.51 18.45,38.99 R352.2
  TOP w0.305: R352.2 18.45,39.99 18.86,40.4 R353.2
SKIPSEL: length 12.8
  LAY3 w0.102: v2(30.58,87.8) 30.58,87.94 30.3,88.22 24.41,88.22 v2(22.14,85.95)
  BOTTOM w0.102: v2(30.58,87.8) 30.58,88.06 30,88.64 R486.2
  BOTTOM w0.254: U42.14 v2(22.14,85.95)
  BOTTOM w0.305: v2(22.14,85.95) 21.52,85.33 R456.2
SLEWA: length 4.6
  TOP w0.102: U56.22 112.01,120.06 111.59,120.48 111.1,120.48 110.65,120.93 R550.1 110.08,121.34 110.08,122.43 R543.2
SMB_CLK_S2: length 126.7
  TOP w0.114: U65.6 66.72,98.83 R631.2 66.55,99.59 66.33,99.8 64.83,99.8 64.07,99.04 64.07,96.53 60.8,93.26 60.8,89.06 61.04,88.83 v2(61.29,88.83) ; v2(63.44,36.82) 63.44,44.29 61.78,45.95 CN3.202 61.78,52.18 v2(62.18,52.59)
  LAY3 w0.127: v2(44.4,46.48) 44.4,46.31 43.63,45.54 43.63,31.03 45.04,29.61 50.44,29.61 53.02,32.2 54.88,32.2 55.1,32.42 59.95,32.42 63.68,36.14 63.68,36.58 v2(63.44,36.82) ; v2(62.18,52.59) 62.68,52.59 63.87,53.78 63.87,56.39 64.65,57.17 64.65,60.54 66.39,62.28 66.39,63.96 70.16,67.73 70.16,76.55 70.54,76.93 70.54,81.32 72.44,83.22 72.44,83.87 72.17,84.14 69.89,84.14 65.14,88.89 61.36,88.89 v2(61.29,88.83)
  BOTTOM w0.114: R280.2 44.26,46.34 v2(44.4,46.48) ; v2(63.44,36.82) 63.69,36.57 63.69,35.95 62.81,35.08 61.73,35.08 61.29,35.52 R632.2
SMB_DATA_S2: length 131.4
  TOP w0.114: v2(61.29,89.4) 61.29,93.05 64.6,96.36 64.6,98.95 65.08,99.44 65.95,99.44 66.09,99.29 66.09,98.66 R630.2 66.82,98.48 U65.7 ; v2(64.18,36.8) 63.93,37.05 63.93,44.5 62.38,46.06 CN3.200 62.38,51.69 v2(62.23,51.84)
  LAY3 w0.127: v2(61.29,89.4) 65.35,89.4 70.1,84.65 72.37,84.65 72.95,84.07 72.95,83.01 71.05,81.11 71.05,76.72 70.67,76.35 70.67,67.52 66.9,63.75 66.9,62.07 65.87,61.04 65.87,54.12 64.98,53.23 64.04,53.23 62.66,51.84 v2(62.23,51.84) ; v2(44.42,47.06) 42.97,45.6 42.97,30.92 44.83,29.06 51.14,29.06 53.43,31.35 55.19,31.35 55.64,31.8 60.1,31.8 64.26,35.96 64.26,36.73 v2(64.18,36.8)
  BOTTOM w0.114: v2(64.18,36.8) 64.27,36.72 64.27,35.78 63.07,34.58 61.52,34.58 61.15,34.95 60.77,34.95 60.46,35.26 R633.2 ; v2(44.42,47.06) 44.34,47.14 R281.2
SMBCLK: length 2.4
  BOTTOM w0.114: U17.14 59.86,37.25 60.06,37.05 61.04,37.05 61.22,36.86 R632.1
SMBDATA: length 2.1
  BOTTOM w0.114: U17.15 59.46,37.16 59.69,36.93 R223.1 R633.1
SMC_ONOFF#: length 43.3
  TOP w0.102: v2(133.88,38.45) 133.88,38.7 133.88,38.7 D34.P
  LAY4 w0.102: v2(100.66,23.82) 108.71,23.82 108.91,24.02 119.57,24.02 123.56,28.01 123.56,30.25 131.17,37.85 133.28,37.85 v2(133.88,38.45)
  BOTTOM w0.102: R701.2 R704.2 v2(100.66,23.82)
SMC_SHUTDOWN#: length 176.6
  TOP w0.102: R900.2 136.04,41.33 Q89.1 133.82,41.33 133.82,41.33 v2(133.77,41.33)
  LAY3 w0.102: v2(36.24,76.73) 31.03,76.73 26.32,81.45 16.84,81.45 v2(15.1,83.19)
  LAY4 w0.102: v2(36.24,76.73) 40.28,72.7 40.28,62.67 37.85,60.24 37.85,44.6 39.69,42.76 39.69,38.41 43.48,34.62 53.94,34.62 56.63,37.3 61.32,37.3 61.88,37.86 66.45,37.86 66.92,37.39 78.96,37.39 80.27,36.09 83.72,36.09 v2(84.95,34.86) 86.39,33.42 97.54,33.42 99.07,31.89 102.7,31.89 106.63,27.96 114.05,27.96 114.6,27.4 119.06,27.4 132.99,41.33 v2(133.77,41.33)
  BOTTOM w0.102: v2(15.1,83.19) 15.1,83.19 U71.2 ; v2(84.95,34.86) 85.11,35.03 R301.2
SOC_EXTSMI#: length 112.9
  TOP w0.089: 97.4,91.68 97.29,91.57 97,91.57 U1.C15
  TOP w0.102: v2(101.96,95.66) 101.62,95.66 99,93.04 98.76,93.04 97.4,91.68
  LAY3 w0.127: v2(101.96,95.66) 102.89,95.66 103.45,96.22 104.84,96.22 105.76,95.31 116.97,95.31 123.73,88.54 123.73,77.57 128.41,72.9 128.41,70.72 130.78,68.35 130.78,64.96 132.38,63.36 132.38,61.99 131.44,61.05 131.44,53.12 131.94,52.62 131.94,50.44 129.61,48.11 129.61,37.02 122.28,29.68 115.73,29.68 115.15,30.26 115.15,30.28 112.59,30.28 v2(112.55,30.32)
  LAY4 w0.127: v2(110.55,29.86) 111.01,30.32 v2(112.55,30.32)
  BOTTOM w0.114: U27.2 110.28,30.13 v2(110.55,29.86) ; v2(112.55,30.32) 112.54,30.33 R647.1
SOC_EXTSMI#_EC: length 6.4
  LAY4 w0.102: v2(112.54,32.82) 112.12,33.24 110.88,33.24 v2(110.46,32.82)
  BOTTOM w0.102: R318.1 D9.P 110.46,34.09 v2(110.46,32.82) 110.28,32.64 U27.10
  BOTTOM w0.114: v2(112.54,32.82) R647.2
SOC_FLASHEN: length 156.7
  TOP w0.102: R79.1 120.59,87.62 v2(124.9,87.62)
  TOP w0.203: R79.1 118.07,85.09 U5.3
  LAY3 w0.102: v2(148.74,91.05) 148.74,84.15 147.26,82.68 147.26,58.37 145.17,56.28 145.17,51.23 144.37,50.42 144.37,41.74 v2(141.69,39.06)
  LAY4 w0.102: v2(141.69,39.06) 139.49,36.87 131.46,36.87 127.44,32.85 127.44,28.15 120.49,21.2 106.07,21.2 105.82,20.94 98.49,20.94 94.61,24.83 v2(88.75,24.83) ; v2(124.9,87.62) 127.36,90.08 147.77,90.08 v2(148.74,91.05)
  BOTTOM w0.102: R674.1 86.13,26.01 87.31,24.83 v2(88.75,24.83)
SOC_ICS5_CLK_TOUCH: length 1.7
  BOTTOM w0.114: U74.6 63.72,76.77 64.43,76.06 R684.2
SOC_ICS5_DATA_TOUCH: length 1.5
  BOTTOM w0.114: R683.2 63.66,76.22 63.37,76.51 U74.7
SOC_RUNTIME_SCI: length 192.2
  TOP w0.102: U1.BA12 v2(77.34,92.37)
  LAY3 w0.102: v2(29.67,66.37) 30.62,66.37 32.15,64.84 42,64.84 v2(43.17,66.01)
  LAY4 w0.102: v2(77.34,92.37) 76.96,92.76 75.08,92.76 74.29,93.54 74.3,93.56 74.3,95.05 73.06,96.3 68.9,96.3 68.24,95.64 68.24,95.63 68.06,95.45 67.48,95.45 66.88,94.85 61.21,94.85 60.78,95.28 51.24,95.28 43.06,87.1 43.06,73.72 43.87,72.91 43.87,66.71 v2(43.17,66.01) ; v2(105.37,22.34) 105.37,22.34 98.66,22.34 93.06,27.94 86.4,27.94 81.35,32.99 68.55,32.99 67.3,31.74 64.22,31.74 62.76,30.28 52.72,30.28 49.94,27.49 43.88,27.49 32.55,38.82 32.55,61.54 31.54,62.55 31.54,64.31 29.67,66.18 v2(29.67,66.37)
  BOTTOM w0.102: R655.1 104.79,22.34 v2(105.37,22.34) 105.48,22.24 U26.5
SOC_SMB_CLK: length 9.1
  TOP w0.102: 71.1,95.05 72.42,93.73 74.23,93.73 U1.BH10
  TOP w0.114: 71.1,95.05 69.95,96.21 69.95,97.94 R108.2 69.06,98.83 U65.3
SOC_SMB_DATA: length 10.2
  TOP w0.089: U1.BG12 74.73,92.84 74.44,93.14 74.19,93.14 74.08,93.03 73.59,93.03 73.48,92.92 73.14,92.92 72.87,93.2
  TOP w0.102: 71.11,94.28 72.19,93.2 72.87,93.2
  TOP w0.114: 71.11,94.28 69.38,96 69.38,97.5 R106.2 68.61,98.48 U65.2
SOC_WAKE_SCI: length 110.2
  TOP w0.089: U1.B18 97.79,89.92 97.8,89.93 97.89,90.03 99.06,90.03
  TOP w0.102: 99.06,90.03 99.2,90.03 101.51,92.34 v2(101.51,92.87)
  LAY3 w0.127: v2(101.51,92.87) 102.12,92.87 102.85,93.61 105.17,93.61 105.7,93.09 116.77,93.09 120.04,89.81 120.04,75.5 120.75,74.79 124.79,74.79 127.04,72.54 127.04,70.36 129.33,68.07 129.33,60.99 130.14,60.18 130.14,52.07 128.87,50.81 128.87,38.94 v2(127.98,38.05)
  LAY4 w0.127: v2(109.97,29.87) 110.36,29.47 112.51,29.47 v2(112.93,29.89) 113.47,30.43 120.57,30.43 127.98,37.85 v2(127.98,38.05)
  BOTTOM w0.114: U27.3 109.88,29.96 v2(109.97,29.87) 110.22,29.62 R314.1 ; R651.1 113.31,30.27 v2(112.93,29.89)
SPI_CLK: length 5.2
  TOP w0.114: U3.6 114.11,95.7 113.87,95.95 110.73,95.95 R75.1
SPI_CS0#: length 2.1
  TOP w0.114: U3.1 R70.2
SPI_SI: length 3.3
  TOP w0.114: R74.2 113.88,96.84 115.38,95.34 U3.5
SPI_SO: length 2.1
  TOP w0.114: U3.2 R73.1
SPK_L+: length 3.3
  BOTTOM w0.203: U23.42 129.69,13.79
  BOTTOM w0.305: 129.69,13.79 129.22,13.32 R285.2
SPK_L-: length 4.3
  BOTTOM w0.203: U23.43 129.29,13.97
  BOTTOM w0.305: R286.2 127.98,12.66 129.29,13.97
SPK_R+: length 5.4
  BOTTOM w0.203: U23.45 128.49,14.34
  BOTTOM w0.305: 128.49,14.34 126.81,12.66 126.4,12.66 125.55,11.8 R284.2
SPK_R-: length 4.8
  BOTTOM w0.203: U23.44 128.89,14.16
  BOTTOM w0.305: R283.2 127.19,12.13 127.19,12.46 128.89,14.16
SPKR: length 232.4
  TOP w0.089: U1.BH12 73.7,92.84 73.69,92.83 73.59,92.73 73.08,92.73 72.92,92.89 72.77,92.89
  TOP w0.102: 72.77,92.89 72.13,92.89 71.1,93.92
  TOP w0.114: v2(68.08,96.3) 68.73,96.3 71.1,93.92
  LAY3 w0.127: v2(25.96,97.09) 26.67,96.37 28.77,96.37 29.69,97.29 31.17,97.29 37.93,90.53 v2(45.92,90.53)
  LAY4 w0.127: v2(68.08,96.3) 67.48,96.3 66.62,95.43 61.47,95.43 61.11,95.79 51.18,95.79 v2(45.92,90.53) ; v2(123.75,25.79) 120.6,22.64 108.74,22.64 107.98,21.88 97.94,21.88 94.75,25.07 91.66,25.07 90.15,26.58 86.7,26.58 81.04,32.25 68.87,32.25 67.6,30.98 64.68,30.98 63.2,29.49 53,29.49 50,26.5 43.63,26.5 41.81,28.31 29.79,28.31 28.56,29.53 28.56,40.14 25.87,42.84 25.87,47.13 27.72,48.98 27.72,59.92 28.02,60.22 28.02,60.78 27.06,61.74 27.06,65.6 27.35,65.9 27.35,68 26.11,69.23 26.11,88.82 25.54,89.39 25.54,96.68 v2(25.96,97.09)
  BOTTOM w0.114: R600.2 v2(123.75,25.79)
SVID_ALERT#: length 50.2
  TOP w0.114: R586.2 107.23,91.12 v2(108.33,90.03) ; R517.2 v2(113.1,122.46) R523.1
  LAY4 w0.127: v2(108.33,90.03) 108.41,89.94 114.71,89.94 117.63,92.87 117.63,103.81 110.56,110.89 110.56,118.68 109.68,119.56 109.68,120.75 110.84,121.91 112.56,121.91 v2(113.1,122.46)
SVID_CLK: length 51.1
  TOP w0.114: R518.2 v2(113.92,122.43) R522.1 ; v2(107.14,90.03) 106.8,90.36 R588.2
  LAY4 w0.127: v2(107.14,90.03) 107.71,89.45 108.85,89.45 109.01,89.61 114.74,89.61 117.89,92.76 117.89,103.91 110.81,110.99 110.81,118.83 109.96,119.68 109.96,120.61 110.84,121.5 112.98,121.5 v2(113.92,122.43)
SVID_DATA: length 49.3
  TOP w0.114: R525.1 v2(112.28,122.43) R516.2 ; R587.2 107.29,89.6 v2(107.72,90.03)
  LAY4 w0.127: v2(112.28,122.43) 112.05,122.2 110.61,122.2 109.34,120.93 109.34,119.49 110.3,118.52 110.3,110.53 117.38,103.45 117.38,92.97 114.69,90.28 108.97,90.28 108.82,90.44 108.13,90.44 v2(107.72,90.03)
TBCLK: length 2.4
  BOTTOM w0.114: U28.85 87.51,35.81 R310.2
TBDATA: length 2.8
  BOTTOM w0.114: U28.86 87.84,36.21 87.25,36.8 87.25,37.32 86.95,37.62 R316.2
TEMP_ALERT#: length 130.3
  TOP w0.102: v2(40.68,65.67) 42.75,65.67 48.52,59.9 52.05,59.9 53.85,58.1 60.71,58.1 62.47,59.86 R130.2 62.47,60.71 U7.6
  LAY3 w0.102: v2(31.37,66.86) 34.59,66.86 36.26,65.2 40.21,65.2 v2(40.68,65.67)
  LAY4 w0.102: v2(86.35,28.55) 85.21,29.69 84.94,29.69 81.43,33.2 68.47,33.2 67.21,31.94 64.04,31.94 62.58,30.48 52.64,30.48 49.85,27.7 43.96,27.7 32.75,38.91 32.75,64.37 31.75,65.37 31.75,66.48 v2(31.37,66.86)
  BOTTOM w0.102: v2(86.35,28.55) 86.1,28.3 R337.1
TLV3492_REF: length 6.5
  BOTTOM w0.102: R727.2 3.99,107.59 3.99,107.56 3.99,107.56 3.99,106.71 R728.1 4.3,106.11 U79.2 4.3,104.09 4.95,103.44 U79.6
TMDS_CLKN: length 96.1
  TOP w0.101: U1.AP2 81.44,98.05 81.44,100.36 81.92,100.84 81.92,100.92 81.9,100.93 81.9,101.58 81.92,101.59 81.92,107.69 79.14,110.47 73.6,110.47 73.25,110.82 73.25,111.11 73.6,111.47 v2(73.63,111.47) ; v2(135.66,99.51) 136.05,99.9 136.28,99.9 136.39,99.79 136.39,99.56 136.51,99.44 C182.1
  LAY3 w0.101: v2(73.63,111.47) 73.63,111.7 73.52,111.81 73.32,111.81 73.23,111.9 73.23,112.29 73.66,112.71 75.21,112.71 76.42,111.51 77.82,111.51 79.18,112.86 88.86,112.86 89.51,112.21 99.66,112.21 100.41,111.46 116.85,111.46 117.68,112.3 126.18,112.3 128.58,109.89 128.58,105.47 134.13,99.91 135.21,99.91 135.31,99.81 135.31,99.63 135.43,99.51 v2(135.66,99.51)
TMDS_CLKP: length 96.1
  TOP w0.101: C181.1 136.45,100.21 136.36,100.12 v2(135.66,100.12) ; U1.AP3 81.37,97.57 81.08,97.86 81.08,98.1 81.23,98.25 81.23,100.45 81.7,100.93 81.7,107.61 79.05,110.26 73.51,110.26 73.03,110.73 v2(73.03,111.47)
  LAY3 w0.101: v2(135.66,100.12) 134.22,100.12 128.78,105.55 128.78,109.98 126.26,112.5 117.6,112.5 116.77,111.67 100.49,111.67 99.75,112.41 89.59,112.41 88.94,113.06 79.09,113.06 77.74,111.71 76.5,111.71 75.3,112.91 73.57,112.91 73.03,112.37 v2(73.03,111.47)
TMDS_DATAN0: length 97.7
  TOP w0.101: v2(72.31,111.46) 72.31,111.25 72.2,111.14 72.04,111.14 71.96,111.06 71.96,110.76 72.96,109.75 78.87,109.75 81.22,107.4 81.22,101.34 80.97,101.09 80.97,98.45 U1.AR1 ; C180.1 136.43,100.97 136.34,101.07 136.34,101.33 136.23,101.44 135.99,101.44 v2(135.6,101.05)
  LAY3 w0.101: v2(135.6,101.05) 135.34,101.05 135.24,101.16 135.24,101.33 135.12,101.45 133.92,101.45 131.51,103.86 131.51,108.47 126.12,113.87 116.06,113.87 115.79,114.13 112.82,114.13 112.26,113.57 100.23,113.57 99.56,112.9 90.07,112.9 89.42,113.55 78.77,113.55 77.47,112.25 76.66,112.25 75.49,113.42 73.2,113.42 71.94,112.16 71.94,111.87 72.04,111.77 72.2,111.77 72.31,111.66 v2(72.31,111.46)
TMDS_DATAN1: length 102.3
  TOP w0.101: C178.1 136.45,102.5 136.39,102.56 v2(135.64,102.56) ; v2(69.53,111.47) 69.53,110.67 71.43,108.76 76,108.76 77.99,106.77 79.1,106.77 80.05,105.82 80.05,101.92 80.3,101.68 80.3,98.77 80.19,98.67 80.19,98.19 80.1,98.1 80.1,97.86 80.4,97.57 U1.AT3
  LAY3 w0.101: v2(135.64,102.56) 134.01,102.56 132.51,104.05 132.51,108.66 126.26,114.91 116.24,114.91 115.22,115.93 111.39,115.93 110.22,114.77 96.79,114.77 96.37,114.35 72.15,114.35 70.86,113.06 70.86,110.8 70.46,110.41 69.77,110.41 69.53,110.65 v2(69.53,111.47)
TMDS_DATAN2: length 103.6
  TOP w0.101: v2(69.02,111.2) 69.02,110.97 68.93,110.87 68.72,110.87 68.64,110.79 68.64,109.73 70.09,108.28 75.59,108.28 77.63,106.24 78.92,106.24 79.52,105.65 79.52,98.07 U1.AV2 ; v2(135.57,104.11) 135.96,104.5 136.22,104.5 136.32,104.4 136.32,104.14 136.43,104.03 C176.1
  LAY3 w0.101: v2(135.57,104.11) 135.17,104.51 134.76,104.51 133.38,105.89 133.38,109.51 125.79,117.1 119.73,117.1 119.22,117.61 111,117.61 109.9,116.51 106.33,116.51 103.99,118.85 96.33,118.85 93.14,115.66 80.44,115.66 79.83,115.04 71.78,115.04 68.62,111.89 68.62,111.6 v2(69.02,111.2)
TMDS_DATAP0: length 97.7
  TOP w0.101: v2(135.6,101.65) 136.36,101.65 136.45,101.74 C179.1 ; U1.AR3 80.88,97.92 80.6,98.2 80.6,98.52 80.77,98.69 80.77,101.18 81,101.41 81,107.32 78.78,109.54 72.87,109.54 71.74,110.67 v2(71.74,111.46)
  LAY3 w0.101: v2(71.74,111.46) 71.74,112.25 73.12,113.63 75.57,113.63 76.74,112.45 77.39,112.45 78.68,113.75 89.5,113.75 90.15,113.1 99.48,113.1 100.15,113.78 112.17,113.78 112.73,114.33 115.88,114.33 116.14,114.07 126.2,114.07 131.72,108.56 131.72,103.94 134.01,101.65 v2(135.6,101.65)
TMDS_DATAP1: length 102.3
  TOP w0.101: U1.AT2 80.41,98 80.41,98.6 80.5,98.69 80.5,101.58 80.51,101.59 80.51,101.77 80.27,102.01 80.27,105.91 79.19,106.99 78.08,106.99 76.09,108.97 71.52,108.97 69.74,110.76 69.74,111.07 69.83,111.16 70.03,111.16 70.13,111.25 v2(70.13,111.47) ; C177.1 136.45,103.26 136.33,103.15 136.33,102.89 136.22,102.78 136.02,102.78 v2(135.64,103.16)
  LAY3 w0.101: v2(135.64,103.16) 135.24,102.76 134.09,102.76 132.72,104.14 132.72,108.75 126.35,115.12 116.32,115.12 115.3,116.14 111.3,116.14 110.14,114.97 96.71,114.97 96.29,114.55 72.07,114.55 70.65,113.14 70.65,110.88 70.38,110.61 69.85,110.61 69.73,110.73 69.73,110.99 69.85,111.1 70.01,111.1 70.13,111.22 v2(70.13,111.47)
TMDS_DATAP2: length 103.7
  TOP w0.101: v2(68.42,111.2) 68.42,109.65 70.01,108.06 75.5,108.06 77.54,106.03 78.83,106.03 79.3,105.56 79.3,101.59 79.32,101.58 79.32,98.28 79.13,98.1 79.13,97.86 79.42,97.57 U1.AV3 ; v2(135.57,104.72) 136.37,104.72 136.45,104.8 C175.1
  LAY3 w0.101: v2(68.42,111.2) 68.42,111.97 71.69,115.25 79.75,115.25 80.36,115.86 93.06,115.86 96.25,119.05 104.08,119.05 106.41,116.71 109.82,116.71 110.91,117.81 119.31,117.81 119.82,117.3 125.88,117.3 133.58,109.6 133.58,105.98 134.84,104.72 v2(135.57,104.72)
TONSEL: length 2.6
  BOTTOM w0.254: U42.4 27.79,86.45
  BOTTOM w0.406: 27.79,86.45 28.03,86.22 R427.2 R428.2
TOUCH_INT: length 1.9
  TOP w0.102: U1.AU32 79.34,82.62 v2(78.77,82.62)
  BOTTOM w0.102: R585.1 78.57,82.42 v2(78.77,82.62)
TOUCHEN_SOC: length 238.5
  TOP w0.102: R149.1 15.03,39.77 v2(15.03,40.35)
  TOP w0.114: U1.N3 91.57,97.92 91.96,98.3 91.96,99.86 92.24,100.15 92.24,101.45 94.02,103.23 99.46,103.23 101.74,100.95 101.74,99.97 v2(101.31,99.54)
  LAY3 w0.127: v2(15.03,40.35) 15.72,40.35 18.36,37.72 20.69,37.72 27.17,31.24 31.07,31.24 38.37,23.94 59.46,23.94 65.45,29.93 79.91,29.93 82.6,27.24 102.5,27.24 103.85,28.59 108.02,28.59 109.78,26.83 114.1,26.83 115.85,28.59 122.99,28.59 130.74,36.33 130.74,38.86 132.55,40.67 132.55,49 135.57,52.03 135.57,64.74 134.48,65.83 134.48,68.04 130.66,71.86 130.66,72.7 127.19,76.17 127.19,89.76 122.73,94.22 120.88,94.22 117.74,97.36 111.82,97.36 108.51,100.67 106.7,100.67 105.77,99.74 101.5,99.74 v2(101.31,99.54)
TP_EN_EC: length 89.8
  TOP w0.102: R629.2 15.07,39.01 v2(15.73,39.66)
  LAY3 w0.102: v2(29.13,30.17) 28.47,30.83 27.15,30.83 20.56,37.42 17.97,37.42 v2(15.73,39.66)
  LAY4 w0.102: v2(92.57,25.46) 91.02,27.02 86.6,27.02 81.14,32.49 68.77,32.49 67.5,31.23 64.59,31.23 63.1,29.73 52.9,29.73 49.94,26.77 43.72,26.77 41.94,28.56 30.08,28.56 29.13,29.5 v2(29.13,30.17)
  BOTTOM w0.102: U28.57 92.68,25.57 v2(92.57,25.46)
TXN0_LVDS: length 20.7
  TOP w0.101: v2(62,125.06) C140.2
  LAY3 w0.101: v2(62,125.06) 60.99,125.06 60.86,124.93 60.86,124.08 61.01,123.92 61.36,123.92 61.68,124.25 62.05,124.25 62.27,124.03 62.27,123.51 62.38,123.4 62.58,123.4 62.68,123.5 62.68,124.03 62.9,124.25 63.34,124.25 63.58,124 63.58,123.45 63.67,123.36 64.03,123.36 64.15,123.48 64.15,123.81 64.45,124.11 65.17,124.11 65.57,123.71 66.29,123.71 66.66,123.34 66.66,122.38 66.29,122 65.73,122 65.57,121.85 65.57,120.31 65.18,119.91 64.67,119.91 64.33,119.58 v2(64.33,119.54)
  BOTTOM w0.101: U10.5 61.33,118.2 62.2,118.2 63.84,119.84 64.03,119.84 v2(64.33,119.54)
TXN1_LVDS: length 20.9
  TOP w0.101: v2(58.29,125.06) C144.2
  LAY3 w0.101: v2(58.29,125.06) 57.26,125.06 57.16,124.96 57.16,122.82 57.34,122.64 58.62,122.64 58.72,122.75 58.72,123.6 58.94,123.82 59.31,123.82 59.53,123.6 59.53,122.75 59.64,122.64 61.68,122.64 62.2,122.12 62.34,122.12 62.73,122.51 63.05,122.51 63.31,122.25 63.31,121.94 62.92,121.55 62.92,121.4 63.84,120.48 63.84,117.32 63.48,116.96 62.76,116.96 v2(62.62,116.82)
  BOTTOM w0.101: v2(62.62,116.82) 62.45,117 61.63,117 61.53,116.9 U10.8
TXP0_LVDS: length 20.3
  TOP w0.101: v2(59.27,125.06) C142.2
  LAY3 w0.101: v2(59.27,125.06) 60.56,125.06 60.65,124.97 60.65,124 60.93,123.72 61.45,123.72 61.77,124.04 61.97,124.04 62.07,123.94 62.07,123.42 62.3,123.2 62.67,123.2 62.88,123.41 62.88,123.94 62.98,124.04 63.25,124.04 63.38,123.92 63.38,123.37 63.58,123.16 64.12,123.16 64.35,123.4 64.35,123.73 64.53,123.91 65.09,123.91 65.49,123.51 66.21,123.51 66.46,123.25 66.46,122.46 66.21,122.21 65.64,122.21 65.37,121.93 65.37,120.39 65.09,120.12 v2(64.33,120.12)
  BOTTOM w0.101: v2(64.33,120.12) 64.27,120.06 63.75,120.06 62.11,118.42 61.31,118.42 U10.4
TXP1_LVDS: length 20.9
  TOP w0.101: C154.1 v2(55.58,125.06)
  LAY3 w0.101: v2(55.58,125.06) 56.86,125.06 56.95,124.97 56.95,122.74 57.25,122.44 58.7,122.44 58.92,122.66 58.92,123.51 59.02,123.62 59.23,123.62 59.33,123.51 59.33,122.66 59.55,122.44 61.6,122.44 62.12,121.92 62.43,121.92 62.82,122.31 62.96,122.31 63.11,122.16 63.11,122.02 62.72,121.63 62.72,121.32 63.63,120.4 63.63,117.4 63.39,117.16 62.86,117.16 v2(62.62,117.4)
  BOTTOM w0.101: U10.7 61.54,117.3 61.63,117.21 62.44,117.21 v2(62.62,117.4)
USB3_PWRON: length 94.1
  TOP w0.102: v2(131.16,71.99) 130.95,71.99 130.59,72.35 R366.2 130.59,72.65 U31.4
  LAY3 w0.102: v2(137.39,39.5) 138.74,40.85 138.74,48.87 144.15,54.29 144.15,71.35 v2(142.81,72.7)
  LAY4 w0.102: v2(131.16,71.99) 132.39,73.23 137.11,73.23 137.98,72.35 139.24,72.35 139.85,72.95 142.55,72.95 v2(142.81,72.7) ; v2(137.39,39.5) 137.38,39.49 132.3,39.49 118.8,25.98 110.04,25.98 108.62,27.4 105.41,27.4 v2(104.4,26.38)
  BOTTOM w0.102: U28.31 104.49,28.21 104.65,28.05 104.65,26.63 v2(104.4,26.38)
USB3_RX0_N: length 71.2
  TOP w0.101: U1.E3 v2(95.84,97.23)
  LAY3 w0.101: v2(131.48,73.83) 131.24,74.08 130.95,74.08 130.21,74.81 130.21,82.28 133.86,85.92 133.86,92.56 126.23,100.19 114.77,100.19 111.32,103.64 100.52,103.64 98.18,101.31 98.18,99.86 96.96,98.63 96.19,98.63 95.18,97.62 95.18,97.32 95.47,97.04 95.65,97.04 v2(95.84,97.23)
  BOTTOM w0.101: v2(131.48,73.83) 131.59,73.93 132.31,73.93 132.42,73.83 132.42,73.64 132.52,73.54 FIL6.4 133.11,73.41 R362.1
USB3_RX0_P: length 71.5
  TOP w0.101: U1.D4 v2(95.36,96.67)
  LAY3 w0.101: v2(131.48,74.43) 131.33,74.28 131.04,74.28 130.42,74.9 130.42,82.2 134.06,85.84 134.06,92.64 126.31,100.39 114.85,100.39 111.4,103.84 100.43,103.84 97.98,101.39 97.98,99.94 96.87,98.84 96.11,98.84 94.98,97.71 94.98,97.24 95.36,96.86 v2(95.36,96.67)
  BOTTOM w0.101: R364.1 133.11,74.66 FIL6.1 132.52,74.54 132.42,74.43 132.42,74.25 132.32,74.15 131.76,74.15 v2(131.48,74.43)
USB3_TX0_N: length 69.3
  TOP w0.101: v2(93.55,95.66) 93.41,95.66 U1.K7
  LAY3 w0.101: v2(131.4,81.33) 131.72,81.33 134.67,84.29 134.67,92.9 126.57,101 119.05,101 115.4,104.66 100.07,104.66 97.41,101.99 97.41,100.72 94.41,97.72 94.41,96.28 94.13,96.01 93.79,96.01 93.55,95.77 v2(93.55,95.66)
  BOTTOM w0.101: v2(131.4,81.33) 131.3,81.24 130.37,81.24 130.05,80.92 130.05,79.42 130.31,79.16 130.71,79.16 C314.2
USB3_TX0_P: length 69.3
  TOP w0.101: U1.K6 93.25,96.15 v2(93.55,96.37)
  LAY3 w0.101: v2(131.4,80.73) 134.87,84.2 134.87,92.98 126.65,101.2 119.14,101.2 115.48,104.86 99.99,104.86 97.21,102.07 97.21,100.81 94.21,97.81 94.21,96.36 94.05,96.21 93.71,96.21 v2(93.55,96.37)
  BOTTOM w0.101: C315.2 130.71,79.38 130.4,79.38 130.27,79.51 130.27,80.83 130.46,81.02 131.11,81.02 v2(131.4,80.73)
USB_BTN: length 4.9
  TOP w0.102: v2(44.95,48.85) 44.25,48.85 44.13,48.73 CN12.36
  BOTTOM w0.101: R718.1 46.75,50.04 46.46,49.75 46.46,49.65 46.46,49.41 46.07,49.01 45.11,49.01 v2(44.95,48.85)
USB_BTP: length 5
  TOP w0.102: CN12.38 44.15,49.53 44.25,49.43 44.25,49.17 44.36,49.07 44.56,49.07 v2(44.95,49.45)
  BOTTOM w0.101: v2(44.95,49.45) 45.17,49.23 45.98,49.23 46.25,49.5 46.25,49.65 46.25,49.75 45.96,50.04 R746.1
USB_NFCN: length 72.1
  LAY3 w0.101: v2(47.33,50.89) 46.49,50.89 46.34,50.73 46.34,50.15 46,49.81 45.09,49.81 44.58,50.33 37.08,50.33 28.93,42.17 25.82,42.17 24.51,43.49 13.33,43.49 7.22,37.38 7.22,20.51 6.12,19.41 6.12,18.07 6.54,17.66 6.96,17.66 v2(7.27,17.97)
  BOTTOM w0.101: CN11.3 5.87,18.17 5.98,18.07 5.98,17.88 6.08,17.78 7.08,17.78 v2(7.27,17.97) ; R745.1 47.33,50.99 v2(47.33,50.89)
USB_NFCP: length 72.1
  LAY3 w0.101: v2(7.27,17.37) 7.18,17.45 6.46,17.45 5.92,17.99 5.92,19.5 7.02,20.6 7.02,37.46 13.25,43.69 24.59,43.69 25.91,42.38 28.85,42.38 37,50.53 44.67,50.53 45.18,50.02 45.92,50.02 46.13,50.23 46.13,50.73 45.98,50.89 v2(45.36,50.89)
  BOTTOM w0.101: v2(7.27,17.37) 7.08,17.56 6.08,17.56 5.98,17.46 5.98,17.27 5.87,17.17 CN11.2 ; R747.1 45.36,51 v2(45.36,50.89)
USB_OC0#: length 58.1
  TOP w0.089: U1.C20 96.75,88.95 97.05,89.25 97.31,89.25 97.4,89.16 97.85,89.16 97.97,89.04 98.4,89.04 98.49,89.13
  TOP w0.102: U31.3 130.59,77.65 C313.1 130.59,77.89 R365.2 129.81,78.67 R363.1 125.95,79.88 125.17,79.1 v2(125.13,79.1) ; R89.1 106.03,94.58 105.31,93.86 103.35,93.86 98.92,89.44 v2(98.8,89.44) 98.49,89.13
  LAY3 w0.102: v2(98.8,89.44) 99.45,88.78 101.27,88.78 103.67,91.19 109.09,91.19 111.32,88.95 116.87,88.95 118.35,87.47 v2(118.35,80.75)
  LAY4 w0.102: v2(125.13,79.1) 119.82,79.1 118.35,80.57 v2(118.35,80.75)
USB_OC1#: length 12.7
  TOP w0.102: U1.B20 97.56,88.95 97.66,88.85 98.87,88.85 v2(99.46,89.44) 99.46,89.68 103.33,93.56 105.73,93.56 106.8,94.63 R90.1
USB_OC1#_HUB: length 195.6
  TOP w0.102: U77.21 31.44,125.19 v2(32.13,125.88)
  LAY3 w0.102: v2(145.26,58.44) 145.26,62.65 146.06,63.44 146.06,82.89 147.97,84.8 147.97,119.09 v2(145.56,121.5)
  LAY4 w0.102: v2(145.56,121.5) 145.56,123.8 142.04,127.32 122.43,127.32 121.52,126.4 65.2,126.4 63.33,128.27 49.09,128.27 41.34,120.52 37.11,120.52 33.68,123.95 33.68,124.39 32.16,125.91 v2(32.13,125.88)
  BOTTOM w0.102: C318.1 145.26,55.38 ; 145.26,55.38 145.26,56.37 R369.1 R370.2 145.26,57.65 v2(145.26,58.44) ; 145.26,55.38 U55.3
USB_OC1#_HUB 2: length 189.7
  LAY3 w0.102: v2(144.47,116.44) 144.47,113.32 143.09,111.94 143.09,107.56 144.44,106.21 144.44,94.45 144.02,94.03 144.02,90.44 142.07,88.49 142.07,84.58 144.7,81.95 144.7,79.07 144.36,78.73 144.36,54.19 139.08,48.91 139.08,39.87 137.47,38.26 136.52,38.26 125.34,27.08 123.3,27.08 120.97,24.75 103.9,24.75 103.35,24.2 98.9,24.2 98.31,23.6 88.37,23.6 86.97,25 82.4,25 78.99,28.41 65.96,28.41 58.3,20.75 v2(58.3,17.28)
  BOTTOM w0.102: v2(144.47,116.44) U83.21 ; v2(58.3,17.28) 58.3,16.74 57.47,15.92 C330.1 53.81,15.61 R374.2 53.12,16.81 R372.1 53.09,17.91 U41.3
USB_OC2#_HUB: length 122.7
  TOP w0.102: 46.45,24.69 R379.2 R373.1 43.73,24.69 43.45,24.41 43.45,23.52 42.85,22.93 U59.3 ; 46.45,24.69 C325.1 ; 46.45,24.69 46.45,25.16 40.16,31.46 40.16,35.2 39.51,35.85 v2(34.85,35.85) ; v2(32.14,125.27) 32.42,125.27 32.74,124.95 U77.19
  LAY4 w0.102: v2(32.14,125.27) 31.53,124.66 31.53,109.25 27.84,105.56 27.84,99.87 31.26,96.44 31.26,81.15 30.21,80.1 30.21,68.54 29.05,67.38 29.05,64.71 29.34,64.43 30.74,64.43 31.31,63.86 31.31,62.44 32.34,61.41 32.34,38.35 v2(34.85,35.85)
USB_P1ON: length 73.7
  LAY3 w0.102: v2(143.2,47.86) 143.2,43.38 133.49,33.66 132.68,33.66 125.89,26.88 123.39,26.88 121.06,24.55 109.08,24.55 108.12,23.59 104.04,23.59 103.18,22.72 93.19,22.72 v2(91.84,21.38)
  BOTTOM w0.102: R592.2 91.84,23.3 v2(91.84,21.38) ; v2(143.2,47.86) 145.33,49.98 R371.2
  BOTTOM w0.305: R371.2 145.33,51.55 U55.4
USB_P2ON: length 61.6
  TOP w0.102: U59.4 42.85,25.39 R380.2 43.27,27.33 39.25,31.34 39.25,34.55 v2(39.73,35.03)
  LAY4 w0.102: v2(39.73,35.03) 40.84,33.92 46.74,33.92 47.85,32.82 54.67,32.82 55.06,33.21 61.15,33.21 62.02,34.07 66.11,34.07 67.34,35.31 82.36,35.31 84.08,33.59 84.5,33.59 v2(84.88,33.97)
  BOTTOM w0.102: v2(84.88,33.97) 85.4,33.45 R606.2
USB_P3ON: length 73.8
  TOP w0.102: v2(50.33,18.79) 50.33,22.61 49,23.93 48.03,23.93 40.37,31.59 40.37,35.68 v2(39.89,36.15)
  LAY4 w0.102: v2(39.89,36.15) 41.67,34.37 49.22,34.37 50.25,33.35 54.62,33.35 54.89,33.62 60.58,33.62 61.48,34.51 64.8,34.51 67.42,37.14 78.9,37.14 80.16,35.88 83.08,35.88 v2(84.55,34.42)
  BOTTOM w0.102: R591.2 85.59,34.42 v2(84.55,34.42) ; v2(50.33,18.79) U41.4 50.33,18.17 R375.2
USB_PLL_MON: length 2
  TOP w0.102: U1.M13 v2(91.57,92.81)
  BOTTOM w0.102: TP2.1 R93.2 v2(91.57,92.81)
USB_PN0: length 72.2
  TOP w0.101: v2(93.43,91.38) U1.K16
  LAY3 w0.101: v2(93.43,91.38) 93.26,91.21 93.26,90.92 93.46,90.71 94,90.71 94.29,91 95,91 95.97,91.97 96.49,91.97 97.51,92.99 97.51,94.71 98.74,95.94 98.74,100.82 100.1,102.18 110.76,102.18 113.36,99.58 125.29,99.58 129.05,95.82 129.05,76.69 129.19,76.55 129.37,76.55 v2(129.77,76.95)
  BOTTOM w0.101: v2(129.77,76.95) 130.06,76.66 132.28,76.66 132.48,76.86 132.48,77.05 132.58,77.15 FIL5.1 133.18,77.28 R360.1
USB_PN1: length 137.1
  TOP w0.101: U1.G14 94.67,92.12 v2(94.85,92.37)
  LAY3 w0.101: v2(94.85,92.37) 94.68,92.37 94.59,92.28 94.59,92 94.36,91.77 91.48,91.77 90.97,92.28 90.97,95.83 92.01,96.88 92.01,99.9 93.43,101.31 93.43,103.3 94.73,104.6 94.73,106.12 93.9,106.94 88.95,106.94 84.74,111.15 79.97,111.15 77.54,108.72 65.7,108.72 60.93,113.49 50.57,113.49 48.99,111.91 48.99,110.32 52.47,106.84 52.47,101.62 50.13,99.28 50.13,66.24 47.23,63.35 47.23,57.71 45.99,56.47 45.99,54.91 46.45,54.46 46.45,52.93 v2(46.63,52.75)
  BOTTOM w0.101: R745.2 46.44,51.73 46.44,52.56 v2(46.63,52.75)
USB_PN2: length 97.5
  TOP w0.101: U1.J12 v2(93.43,93.36) ; v2(28.77,125.51) 28.62,125.36 28.62,124.96 28.84,124.74 U77.25
  LAY3 w0.089: 94.5,101.16 94.5,101.09 94.38,100.97 94.37,100.97 92.72,99.32 92.72,96.59 92.16,96.03 92.16,92.59 92.31,92.44 92.71,92.44 93.43,93.15 v2(93.43,93.36)
  LAY3 w0.101: v2(28.77,125.51) 28.62,125.36 28.62,124.58 31.54,121.66 37.6,121.66 42.92,116.34 59.84,116.34 66.41,109.77 77.07,109.77 79.55,112.25 87.9,112.25 89.83,110.32 92.63,110.32 95.76,107.19 95.76,104.16 94.5,102.9 94.5,101.16
USB_PN3: length 83.5
  TOP w0.101: U1.H10 94.01,93.65 v2(94.14,93.36)
  LAY3 w0.101: v2(94.14,93.36) 93.76,93.74 93.12,93.74 92.85,94 92.85,94.82 92.97,94.94 92.97,99.21 95.23,101.47 95.23,102.01 100.53,107.3 123.16,107.3 132.17,98.29 135.93,98.29 136.37,98.73 136.37,113.37 136.11,113.63 v2(135.8,113.63)
  BOTTOM w0.101: U83.25 141.87,116.36 139.23,113.71 135.87,113.71 v2(135.8,113.63)
USB_PP0: length 72.3
  TOP w0.101: v2(92.72,91.38) U1.M16
  LAY3 w0.101: v2(129.77,76.35) 129.11,76.35 128.85,76.61 128.85,95.73 125.21,99.38 113.27,99.38 110.67,101.97 100.19,101.97 98.95,100.73 98.95,95.86 97.71,94.62 97.71,92.9 96.57,91.76 96.05,91.76 95.09,90.8 94.38,90.8 94.09,90.51 93.38,90.51 93.06,90.83 93.06,91.14 92.82,91.38 v2(92.72,91.38)
  BOTTOM w0.101: v2(129.77,76.35) 129.86,76.44 132.29,76.44 132.58,76.15 FIL5.4 133.18,76.03 R361.1
USB_PP1: length 137.1
  TOP w0.101: U1.J14 94.14,92.23 v2(94.14,92.37)
  LAY3 w0.101: v2(94.14,92.37) 94.21,92.37 94.38,92.2 94.38,92.08 94.27,91.97 91.56,91.97 91.17,92.36 91.17,95.75 92.22,96.8 92.22,99.82 93.63,101.23 93.63,103.21 94.93,104.51 94.93,106.2 93.99,107.15 89.03,107.15 84.83,111.35 79.89,111.35 77.46,108.92 65.78,108.92 61.01,113.69 50.48,113.69 48.79,111.99 48.79,110.23 52.27,106.76 52.27,101.7 49.93,99.36 49.93,66.33 47.03,63.43 47.03,57.79 45.79,56.55 45.79,54.82 46.24,54.37 46.24,52.96 v2(46.03,52.75)
  BOTTOM w0.101: R747.2 46.23,51.69 46.23,52.55 v2(46.03,52.75)
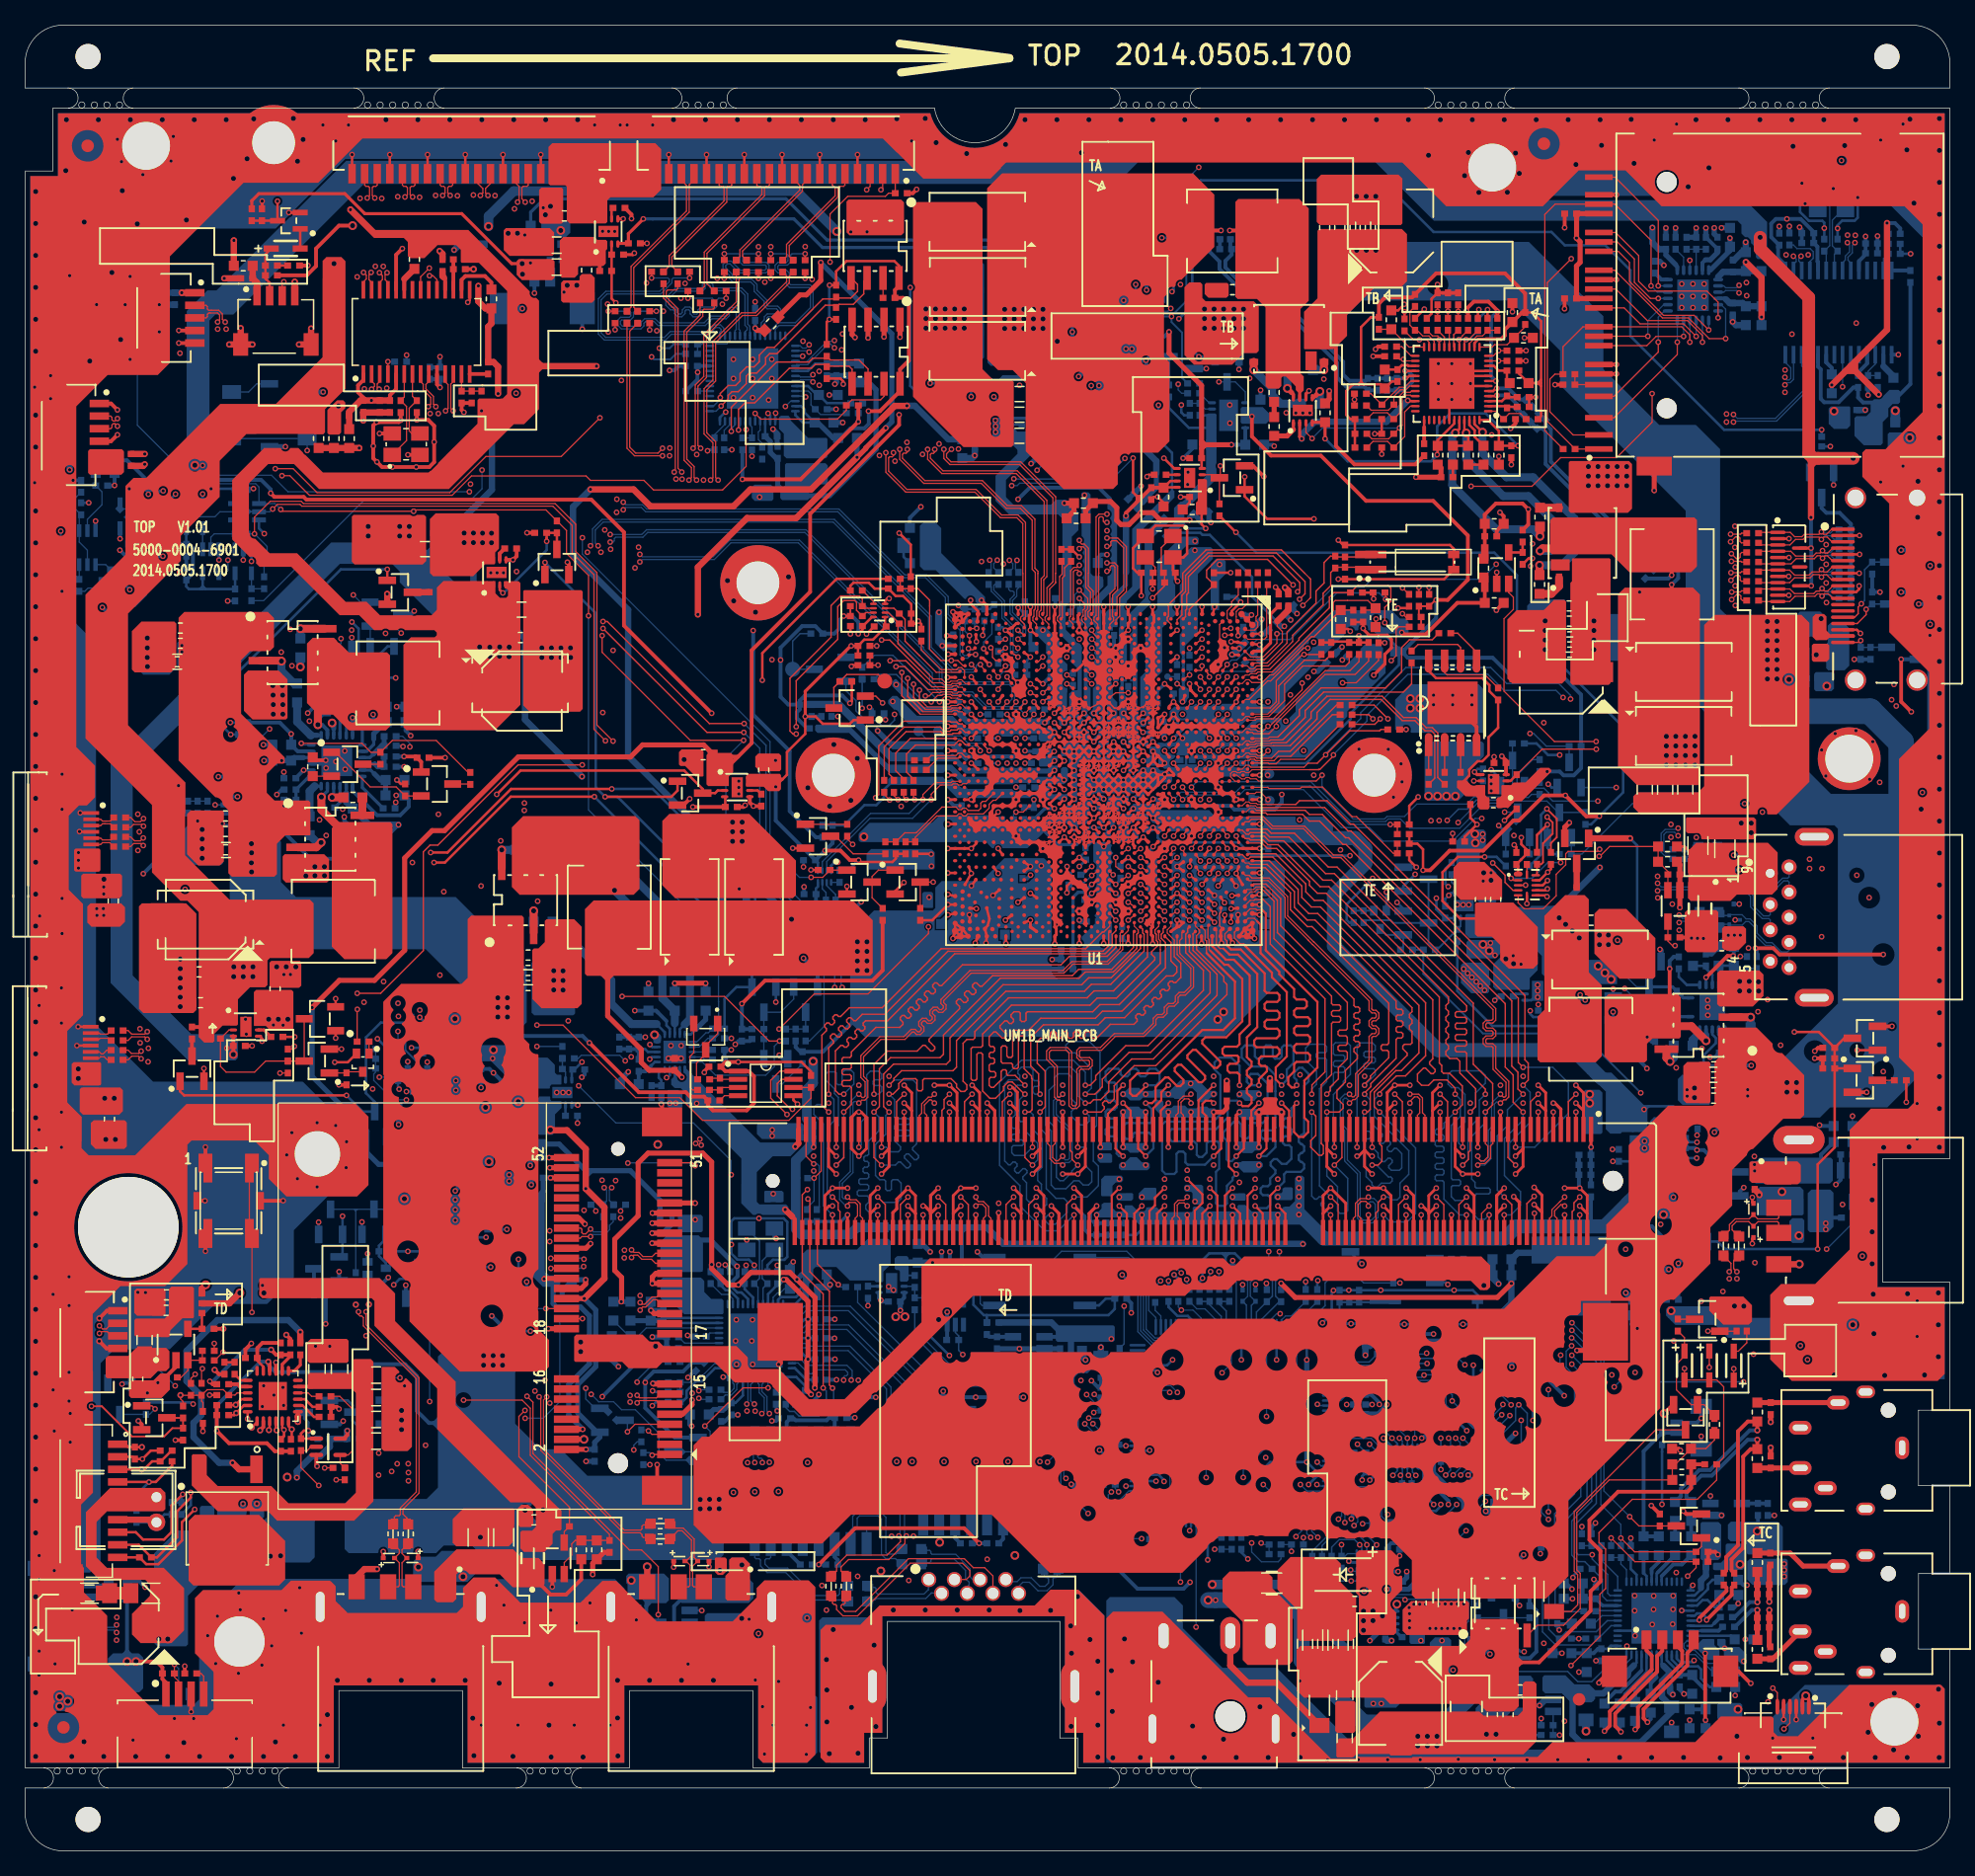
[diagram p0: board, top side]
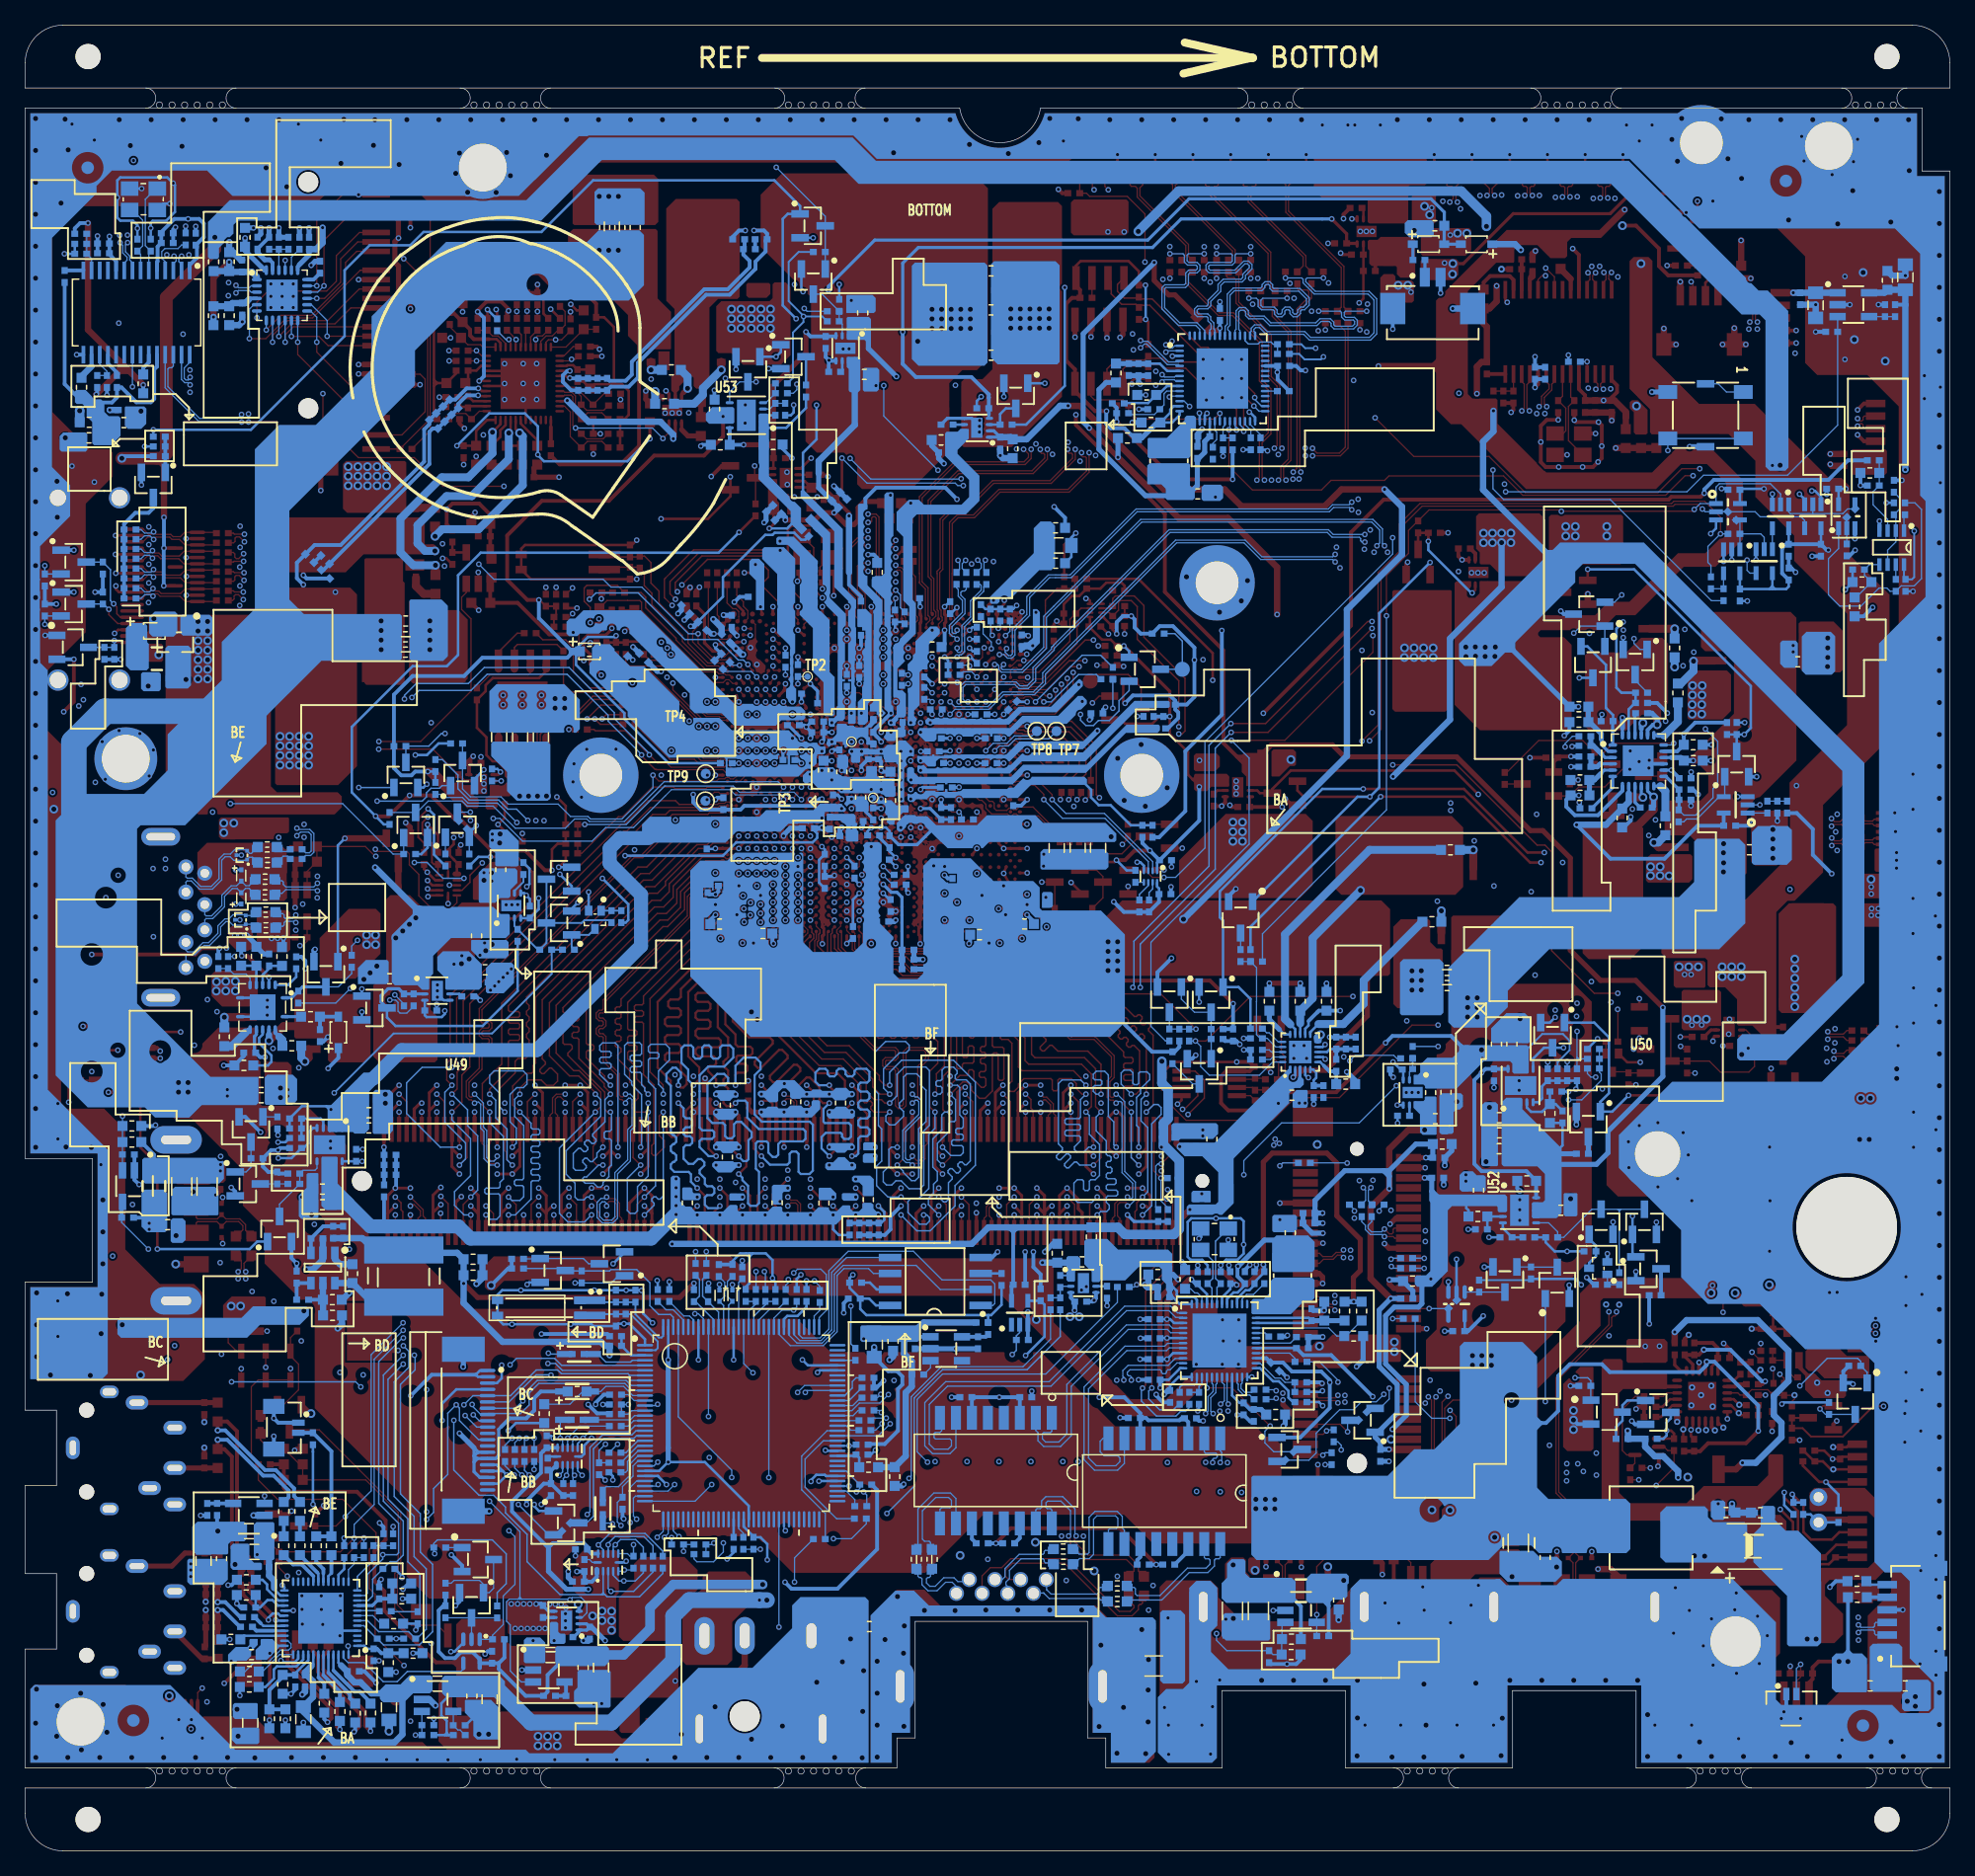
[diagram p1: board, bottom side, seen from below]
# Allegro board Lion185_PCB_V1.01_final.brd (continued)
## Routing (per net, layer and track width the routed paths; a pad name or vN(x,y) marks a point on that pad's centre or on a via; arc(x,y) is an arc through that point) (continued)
USB_PP2: length 97.5
  TOP w0.101: v2(93.43,92.37) U1.K12 ; U77.26 28.19,124.76 28.4,124.97 28.4,125.27 v2(28.17,125.51)
  LAY3 w0.089: 94.29,101.16 92.53,99.4 92.53,96.67 91.97,96.11 91.97,92.51 92.23,92.25 92.79,92.25 93.07,92.52 93.28,92.52 v2(93.43,92.37)
  LAY3 w0.101: 94.29,101.16 94.29,102.98 95.56,104.25 95.56,107.11 92.55,110.12 89.75,110.12 87.82,112.05 79.64,112.05 77.15,109.56 66.32,109.56 59.75,116.13 42.83,116.13 37.51,121.46 31.46,121.46 28.42,124.5 28.42,125.26 28.17,125.51 v2(28.17,125.51)
USB_PP3: length 83.5
  TOP w0.101: U1.K10 93.47,93.88 93.55,93.96 v2(93.55,94.24)
  LAY3 w0.101: v2(93.55,94.24) 93.55,94.03 93.46,93.94 93.2,93.94 93.05,94.09 93.05,94.74 93.18,94.86 93.18,99.13 95.44,101.39 95.44,101.92 100.61,107.1 123.07,107.1 132.09,98.09 136.02,98.09 136.58,98.65 136.58,113.46 v2(135.8,114.24)
  BOTTOM w0.101: U83.26 141.22,118.09 141.36,117.95 141.55,117.95 141.66,117.85 141.66,116.45 139.14,113.92 136.11,113.92 v2(135.8,114.24)
V_DAC: length 26.2
  LAY4 w0.305: v2(67.62,36.07) 67.62,36.08 v2(75.56,36.08)
  BOTTOM w0.305: C496.2 64.35,34.8 65.62,36.07 v2(67.62,36.07) ; C496.2 64.35,32.81 U62.6 ; C496.2 63.9,34.43 63.72,34.24 61.24,34.24 61.08,34.4 C527.2 60.54,34.1 U62.3 ; U61.3 73.93,36.08 C495.2 73.93,36.08 v2(75.56,36.08) C494.2 77.74,36.07 U61.6
VCLK: length 16
  TOP w0.102: v2(21.95,88.08) 26.77,88.08 27.49,87.37 C378.1 28.24,87.36 29.19,88.31 32.68,88.31 35.22,85.77 C377.1
  BOTTOM w0.102: v2(21.95,88.08) 22.08,87.95 U42.18
VCORE_CIMON: length 2.5
  TOP w0.203: U56.3 117.39,115.3 R505.1 117.9,115.61 C448.1
VCORE_COMP: length 2.7
  TOP w0.203: U56.10 116.75,118.1 117.13,117.72 C449.1 117.79,116.95 R507.2
VCORE_CSP1: length 20.6
  TOP w0.203: U56.4 116.94,115.7 v2(116.99,115.76)
  BOTTOM w0.305: R511.2 129.3,101.87 R512.2 120.87,110.29 120.87,112.86 120.62,113.11 C464.1 C462.2 R515.2 118.57,115.08 117.89,115.76 v2(116.99,115.76)
VCORE_GIMON: length 5
  TOP w0.102: C475.1 106.98,115.89 R534.1 107.86,115.03 109.23,116.4 109.67,116.4 110.16,116.9 U56.30
VCORE_GSNS: length 78.2
  TOP w0.102: R509.1 v2(117.12,119.31) 116.71,118.9 U56.12 ; U1.N28 v2(91.29,84.6)
  LAY3 w0.102: v2(111.75,81.93) 111,81.18 107.99,81.18 107.39,81.78 105.15,81.78 103.17,83.76 100.88,83.76 100.25,84.4 98.04,84.4 97.27,85.16 95.54,85.16 95.42,85.28 91.98,85.28 v2(91.29,84.6)
  LAY4 w0.102: v2(117.12,119.31) 116.92,119.1 116.73,119.1 114.81,121.03 110.76,121.03 110.22,120.49 110.22,119.8 111.07,118.95 111.07,111.25 118.13,104.19 118.13,92.66 114.77,89.3 114.77,83.77 114.1,83.1 112.92,83.1 v2(111.75,81.93)
VCORE_OCP_I: length 2.4
  TOP w0.203: U56.2 117.66,114.9 R505.2 117.88,114.84 R506.1
VCORE_PWRGD: length 61.3
  TOP w0.102: U56.17 114.01,120.16 v2(113.98,120.19) 114.24,120.46 114.24,120.48 114.69,120.93 R537.1
  LAY4 w0.102: v2(113.98,120.19) 112.75,118.97 112.75,112.17 119.29,105.63 119.29,91.2 119.06,90.97 119.06,82.49 117.6,81.04 117.6,79.46 120.27,76.79 120.27,72.91 123.61,69.57 v2(123.61,68.08)
  BOTTOM w0.102: v2(123.61,68.08) 122.89,67.35 R493.1
VCORE_SKIP#: length 6.8
  TOP w0.102: U56.35 110.13,114.9 109.67,114.44 109.67,112.48 R555.1 108.3,112.09 107.15,112.09 R548.2
VCORE_THERM: length 3.6
  TOP w0.102: U56.1 116.89,114.5 R552.2 117.97,114.31 118.87,114.31 R545.2
VCORE_VRON: length 146.6
  TOP w0.102: U56.16 114.41,120.06 v2(114.55,120.2) 114.75,120.2 R497.1 ; v2(45.86,96.65) 45.86,95.32 52.87,88.32 v2(57.11,88.32)
  LAY3 w0.102: v2(114.55,120.2) 114.18,120.57 93.33,120.57 90.79,118.03 71.39,118.03 68.77,115.42 68.77,114.74 66.9,112.87 64.19,112.87 59.41,117.65 55.57,117.65 54.86,116.95 v2(47.4,116.95)
  LAY4 w0.102: v2(45.86,96.65) 45.86,96.65 44.32,96.65 40.4,100.57 40.4,109.94 v2(47.4,116.95)
  BOTTOM w0.102: v2(57.11,88.32) 55.7,86.91 55.7,80.07 63.51,72.26 63.51,65.57 62.35,64.41 R450.1 ; v2(114.55,120.2) 114.79,120.2 C596.2
VCORE_VSNS: length 79
  TOP w0.102: U1.P28 90.94,85.08 v2(90.58,84.6) ; R508.1 v2(117.12,118.5) U56.11
  LAY3 w0.102: v2(90.58,84.6) 91.6,85.61 95.48,85.61 95.71,85.38 97.37,85.38 97.97,84.79 100.45,84.79 101.2,84.04 103.28,84.04 105.22,82.09 110.51,82.09 110.79,82.37 111.97,82.37 v2(112.4,81.94)
  LAY4 w0.102: v2(112.4,81.94) 113.36,82.9 115.03,82.9 115.6,83.47 115.6,89.74 118.33,92.47 118.33,104.37 111.34,111.36 111.34,119.07 110.43,119.97 110.43,120.32 110.87,120.76 114.69,120.76 116.6,118.85 116.77,118.85 v2(117.12,118.5)
VFB1: length 4.6
  BOTTOM w0.254: 27.71,88.42 27.71,87.99 27.17,87.45 U42.2
  BOTTOM w0.406: 27.71,88.42 27.71,88.85 28.63,89.77 R421.1 R423.2
VFB2: length 3.4
  BOTTOM w0.254: 27.75,85.67 27.47,85.95 U42.5
  BOTTOM w0.406: 27.75,85.67 28.25,85.17 R422.1 28.65,85.16 R424.1
VGFX_COMP: length 2.6
  TOP w0.203: R533.1 C474.2 109.44,118.15 109.91,118.15 109.96,118.1 U56.27
VGFX_CSP: length 22.1
  TOP w0.203: U56.29 110.02,117.3 109.83,117.11 109.73,117.11 v2(109.7,117.14)
  BOTTOM w0.305: v2(109.7,117.14) 109.68,117.11 R536.2 C477.2 C478.1 C476.1 ; 106.74,117.11 106.54,116.91 105.27,116.91 104.77,117.41 104.77,118.43 99.01,124.19 97.15,124.19 95.41,125.93 95.41,126.45 95.91,126.95 R535.2 95.81,127.48 R532.2 ; 106.74,117.11 C476.1 ; 106.74,117.11 C476.1
VGFX_GSNS: length 1.8
  TOP w0.102: R529.2 109.44,119.63 110.17,118.9 U56.25
VGFX_OCP_I: length 5.2
  TOP w0.102: U56.31 110.05,116.5 109.75,116.2 109.33,116.2 108.81,115.68 R534.2 108.37,114.58 107,114.58 R538.1
VGFX_SKIP#: length 15.6
  TOP w0.102: U56.33 110.2,115.7 110.13,115.77 109.6,115.77 109.46,115.63 109.46,113.37 v2(109.25,113.16) R554.1 108.39,112.3 107.06,112.3 R547.2 ; U57.3 101.82,112.81 v2(102.3,112.33)
  BOTTOM w0.102: v2(109.25,113.16) 109.25,113.16 103.13,113.16 v2(102.3,112.33)
VGFX_THERM: length 6
  TOP w0.102: U56.32 110.21,116.1 110.11,116 109.54,116 109.26,115.72 109.26,114.34 R553.2 108.29,114.37 107.16,114.37 R546.2
VGFX_VSNS: length 55
  TOP w0.102: U1.BB8 77.15,94.67 76.9,94.92 76.9,95.55 v2(76.76,95.68) ; U56.26 109.69,118.5 v2(109.57,118.63) 109.26,118.63 R530.1
  LAY3 w0.102: v2(109.57,118.63) 108.34,119.85 95.12,119.85 92.4,117.13 85.34,117.13 v2(84.75,116.53)
  LAY4 w0.102: v2(76.76,95.68) 76.76,100.25 75.51,101.5 75.51,104.88 v2(80.44,109.8)
  BOTTOM w0.102: v2(84.75,116.53) 84.75,114.11 v2(80.44,109.8)
VR_ALW_EN: length 6
  BOTTOM w0.102: R665.1 21.15,81.84 20.93,82.06 20.1,82.06 18.33,83.84 U71.4 17.9,83.92 Q85.1
VR_HOT#: length 44.5
  TOP w0.102: U56.21 v2(112.41,120.19) 112.41,120.36 112.29,120.48 111.88,120.48 R528.2
  LAY4 w0.102: v2(117.61,82.61) 118.69,83.69 118.69,90.97 119.04,91.33 119.04,105.59 111.79,112.84 111.79,119.57 v2(112.41,120.19)
  BOTTOM w0.102: v2(117.61,82.61) Q62.3
VREF: length 2.9
  BOTTOM w0.254: 27.67,87.22 27.4,86.95 U42.3
  BOTTOM w0.406: 27.67,87.22 28.34,87.88 C442.2 28.54,88.64 R486.1
VREF_CA0: length 6.5
  TOP w0.254: v2(85.18,51.29) 84.58,50.69 CN3.126
  BOTTOM w0.203: v2(85.18,51.29) 84.71,50.82 84.71,50.18 84.96,49.93 C106.2
  BOTTOM w0.305: C106.2 C107.2 R126.2 R125.1
VREF_DQ0: length 4.4
  TOP w0.254: CN3.1 v2(124.48,55.96)
  BOTTOM w0.305: R120.1 124.46,52.97 R124.2 124.47,53.78 C103.2 C104.2 124.47,55.96 v2(124.48,55.96)
VREFA: length 9.8
  TOP w0.254: U25.14 20.43,38.69 21.08,39.33 C992.2
  TOP w0.305: R616.2 14.91,37.11 v2(14.68,37.34) ; C992.2 R353.1 19.96,39.45 v3(19.55,39.85)
  BOTTOM w0.305: v2(14.68,37.34) 14.93,37.34 17.44,39.85 v3(19.55,39.85)
VREG3: length 26.5
  LAY4 w0.305: v2(29.67,81.6) 30.12,82.06 v2(30.12,86.22)
  BOTTOM w0.254: U42.8 25.53,84.08
  BOTTOM w0.305: v2(29.67,81.6) 26.97,78.9 22.68,78.9 20.06,81.53 C540.1 U71.5 ; R427.1 v2(30.12,86.22)
  BOTTOM w0.508: v2(29.67,81.6) 27.34,81.6 C368.2 25.53,83.41 25.53,84.08
VREG5: length 23.9
  TOP w0.305: v2(30.12,87.03) 31.06,87.03 C380.1 31.49,86.61 D24.1
  LAY3 w0.305: v2(20.57,85.81) 20.9,85.47 28.56,85.47 v2(30.12,87.03)
  LAY4 w0.305: v2(21.15,88.83) 21.33,88.64 21.33,86.26 20.88,85.81 v2(20.57,85.81)
  BOTTOM w0.305: R456.1 20.57,85.31 v2(20.57,85.81) ; R662.2 20.25,89.73 v2(21.15,88.83) 21.15,88.57 21.15,88.57 C375.1 21.67,87.45 U42.17 ; R428.1 v2(30.12,87.03)
VSM_VTT_PWRGD: length 158.3
  TOP w0.102: v2(47.45,67.95) 55.6,67.95 59.14,64.41 v2(59.97,64.41)
  LAY3 w0.102: v2(29.64,67.41) 29.26,67.04 29.26,66.15 29.65,65.76 30.38,65.76 31.55,64.59 42.83,64.59 46.2,67.95 v2(47.45,67.95)
  LAY4 w0.102: v2(29.64,67.41) 30.43,68.21 30.43,73.54 31.19,74.3 31.19,80.18 31.77,80.76 31.77,98.37 28.37,101.77 28.37,104.75 30.63,107.01 30.97,107.01 36.69,112.73 37.7,112.73 47.04,122.07 61.61,122.07 62.24,122.71 69.79,122.71 70.91,123.83 83.44,123.83 84.75,122.52 90.92,122.52 v2(91.07,122.67)
  BOTTOM w0.102: R439.1 v2(59.97,64.41) 59.55,63.99 59.55,62.38 58.87,61.69 54.88,61.69 53.83,62.73 U43.20 ; v2(91.07,122.67) 90.85,122.44 R510.2
VSPI_KBC: length 25.1
  LAY4 w0.203: v2(91.33,45.82) 91.33,45.81 v2(87.2,45.81)
  BOTTOM w0.203: R334.1 76.45,42.59 76.43,42.61 ; C293.1 87.46,44.77 R345.2 87.46,45.55 v2(87.2,45.81) ; C293.1 86.61,43.1 86.12,42.61 76.43,42.61 ; C293.1 85.9,43.92 85.36,43.38 U30.8 ; R346.2 75.38,43.43 76.21,42.61 76.43,42.61 ; R658.1 91.67,45.48 v2(91.33,45.82)
VTT_PWRGD: length 1.3
  BOTTOM w0.102: R716.2 3.65,106.18 U79.1
WAKE_SCI_EC: length 9
  LAY4 w0.102: v2(113.15,32.82) 112.76,32.43 110.27,32.43 v2(109.88,32.82)
  BOTTOM w0.102: U27.9 v2(109.88,32.82) 108.92,33.78 R324.1 ; v2(113.15,32.82) 113.31,32.67 R651.2
WIFI_3P3_RST#: length 3.2
  BOTTOM w0.102: Q67.3 R637.2 U58.1
WIFI_PCIE_RST: length 211.7
  TOP w0.102: U1.J20 v2(94.14,88.48) ; v2(108.59,94.66) 108.98,95.05 108.98,97.15 109.19,97.35 R62.1
  LAY3 w0.102: v2(32.16,35.74) 32.16,33.86 40.26,25.75 58.55,25.75 64.8,32 82.46,32 83.17,31.29 97.05,31.29 97.43,31.66 103.13,31.66 103.77,31.02 115.63,31.02 116.4,30.25 121.7,30.25 129.12,37.67 129.12,48.36 131.42,50.66 131.42,52.3 130.94,52.78 130.94,61.25 131.88,62.19 131.88,63.15 130.1,64.94 130.1,68.29 127.71,70.68 127.71,72.88 123.21,77.39 123.21,88.33 116.87,94.66 v2(108.59,94.66) 107.15,94.66 106.8,94.31 103.06,94.31 102.83,94.54 101.99,94.54 99.99,92.54 98.68,92.54 95.5,89.36 95.01,89.36 v2(94.14,88.48)
  BOTTOM w0.102: Q68.1 v2(32.16,35.74)
WIFI_PERST#: length 3.8
  TOP w0.102: CN12.22 v2(41.39,43.13)
  BOTTOM w0.102: v2(41.39,43.13) R589.1 U58.4
WIFI_PWRON: length 74.4
  LAY4 w0.102: v2(47.7,62.83) 47.48,62.6 47.48,57.6 49.46,55.62 49.46,47.11 54.72,41.85 65.27,41.85 65.83,41.29 85.19,41.29 88.01,38.47 94.69,38.47 v2(95.15,38.02)
  BOTTOM w0.102: R599.2 43.96,63.03 44.21,63.27 47.27,63.27 v2(47.7,62.83) ; v2(95.15,38.02) 95.88,38.76 U28.112
WIFI_VDDEN_SOC: length 269.4
  TOP w0.089: 102.1,101.23 101.73,101.59 ; v2(101.57,99.06) 102.1,99.59
  TOP w0.114: 102.1,101.23 102.18,101.15 102.18,99.67 102.1,99.59 ; 101.73,101.59 99.86,103.47 93.88,103.47 92.02,101.61 92.02,100.24 91.17,99.39 90.89,99.11 90.89,98.2 90.79,98.1 90.79,97.86 91.09,97.56 U1.P3
  LAY3 w0.127: v2(27.62,60.6) 28.38,60.6 30.1,62.31 39.02,62.31 v2(40.68,63.98) ; v2(28.11,31.63) 31.82,31.63 39.26,24.19 59.35,24.19 65.35,30.19 80.3,30.19 82.76,27.73 102.62,27.73 103.73,28.84 108.68,28.84 110.44,27.08 113.97,27.08 115.81,28.92 122.9,28.92 130.46,36.48 130.46,38.99 132.26,40.8 132.26,49.14 135.31,52.19 135.31,64.64 134.23,65.73 134.23,67.91 130.38,71.75 130.38,72.55 126.9,76.03 126.9,89.57 122.52,93.96 120.74,93.96 117.64,97.06 111.63,97.06 108.45,100.23 107.03,100.23 106.1,99.3 101.82,99.3 v2(101.57,99.06)
  LAY4 w0.127: v2(27.62,60.6) 27.37,60.34 27.37,49.4 25.61,47.64 25.61,41.85 28.12,39.34 28.12,31.65 v2(28.11,31.63)
  BOTTOM w0.114: R598.1 v2(40.68,63.98)
WIRELESS_ON: length 83.4
  LAY4 w0.102: v2(102.76,24.94) 102.76,25.98 97.26,31.48 85.22,31.48 82.08,34.62 67.88,34.62 66.64,33.38 62.47,33.38 61.62,32.52 55.34,32.52 54.91,32.09 52.15,32.09 49.5,29.44 44.71,29.44 v2(39.74,34.41)
  BOTTOM w0.102: v2(102.76,24.94) 102.28,25.41 U28.33 ; R279.2 42.5,35.72 41.18,34.41 v2(39.74,34.41)
WP2: length 2.7
  TOP w0.102: 123.2,116.61 R804.2 ; 123.2,116.61 R805.2 ; 123.2,116.61 123.2,116.61 CN30.WP2
WP#: length 2.1
  TOP w0.102: U3.3 R71.1
WRST#: length 115
  TOP w0.102: SW1.3 17.82,54.5 SW2.1 SW2.3 17.82,48.91 SW1.4 v2(18.03,42.83)
  LAY3 w0.102: v2(41.7,49.31) 39.13,49.31 31.3,41.48 25.6,41.48 24.25,42.83 v2(18.03,42.83)
  LAY4 w0.102: v2(105.05,35.5) 104.1,34.55 100.12,34.55 98.64,36.03 87.39,36.03 86.4,37.01 84.51,37.01 84.31,37.21 84.31,37.64 83.5,38.45 67.72,38.45 66.69,39.48 48.07,39.48 43.92,43.62 43.92,47.08 v2(41.7,49.31)
  BOTTOM w0.102: v2(105.05,35.5) R333.1 C288.2 105.05,34.73 104.77,35.01 U28.14
X1: length 7.2
  BOTTOM w0.102: U83.6 143.17,127.08 C616.2 143.45,127.66 143.45,131.35 142.6,132.2 X8.1
X2: length 5.6
  BOTTOM w0.102: X8.3 144.47,130.5 143.66,129.69 143.66,127.65 C615.2 143.82,126.98 U83.7
XTAL1: length 6.7
  BOTTOM w0.114: U17.43 58.26,44.81 C187.1 58.37,45.52 58.37,48.49 X4.1
XTAL2: length 5.1
  BOTTOM w0.114: X4.3 59.45,47.8 58.59,46.93 58.59,45.53 C186.1 58.66,44.76 U17.44
XTAL25M_IN: length 16
  TOP w0.102: U1.AH12 v2(84.79,92.81)
  TOP w0.114: X1.1 90.32,103.65 90.32,101.82 C8.2 90.58,101.56 R59.1 90.58,100.61 v2(89.63,99.66)
  LAY3 w0.127: v2(89.63,99.66) 87.11,97.14 87.11,96.38 87.3,96.19 87.3,94.34 85.97,93.01 84.99,93.01 v2(84.79,92.81)
XTAL25M_OUT: length 15.2
  TOP w0.102: U1.AH10 v2(84.79,93.52)
  TOP w0.114: X1.3 89.82,102.09 89.82,101.8 C7.2 89.63,101.61 R59.2 v2(89.63,100.37)
  LAY3 w0.127: v2(89.63,100.37) 89.63,100.19 89.52,100.08 89.32,100.08 89.15,99.92 89.15,99.57 86.9,97.31 86.9,96.29 87.09,96.1 87.09,94.43 86.82,94.17 86.64,94.17 86.37,94.44 86.19,94.44 86.01,94.26 86.01,94.08 86.28,93.81 86.28,93.63 86.01,93.36 85.82,93.36 85.65,93.52 85.65,93.7 85.53,93.83 85.34,93.83 85.23,93.72 85.23,93.46 85.13,93.36 84.95,93.36 v2(84.79,93.52)
N320321985: length 5.3
  TOP w0.102: CN12.7 48.48,33.93 v2(47.88,33.33)
  BOTTOM w0.102: v2(47.88,33.33) 47.88,34.05 Q66.3 R635.2
N320322150: length 2.1
  TOP w0.102: v2(44.3,42.33) 43.2,42.33 CN12.20
  BOTTOM w0.102: R279.1 v2(44.3,42.33)
N320322222: length 2.2
  TOP w0.114: CN12.30 v2(41.79,46.33)
  BOTTOM w0.114: v2(41.79,46.33) 41.8,46.34 R280.1
N320322224: length 2.2
  TOP w0.114: CN12.32 v2(41.78,47.13)
  BOTTOM w0.114: v2(41.78,47.13) 41.79,47.14 R281.1
N322237366: length 3.7
  TOP w0.102: v2(53.26,54.48) 53.02,54.73 CN12.51
  BOTTOM w0.102: v2(53.26,54.48) 53.03,54.72 R282.2
N332287606: length 12
  TOP w0.102: v2(59.06,36.82) 57.06,36.82 v2(54.03,33.79)
  BOTTOM w0.102: U17.16 59.06,36.82 v2(59.06,36.82) ; Q64.3 51.97,31.93 R634.2 53.74,31.74 54.45,32.44 54.45,33.37 v2(54.03,33.79)
N332918772: length 2.4
  TOP w0.102: v2(49.55,33.4) 49.82,33.13 CN12.5
  BOTTOM w0.102: v2(49.55,33.4) 49.46,33.48 R278.2
N333289105: length 2.5
  TOP w0.635: v1(130.76,62.78) 130.47,63.07 Q40.8
  BOTTOM w0.635: v1(130.76,62.78) 131.05,63.07 R463.2
N333289487: length 2.5
  BOTTOM w0.305: D26.N R459.2 129.56,66.34 C404.2
N333289642: length 2.4
  TOP w0.635: Q40.3 137.16,66.3 v1(137.17,66.3)
  BOTTOM w0.635: v1(137.17,66.3) R467.2
N333289792: length 6.6
  BOTTOM w0.102: Q49.3 128.1,68.72 127.04,69.77 R733.2
  BOTTOM w0.254: Q49.3 130.95,68.72 R457.2 131.82,67.84 U47.1
N333289805: length 8.3
  TOP w0.305: v2(130.73,70.16) 130.73,67.83
  TOP w0.635: 131.23,65.59 132.46,65.59 v1(133.62,64.43)
  BOTTOM w0.305: v2(128.94,64.72) 129.3,64.36 C404.1 ; U47.12 133.62,64.9 ; v2(130.73,70.16) 130.73,70.78 131.05,71.1 R460.2
  BOTTOM w0.508: 133.62,64.9 v1(133.62,64.43)
N333289822: length 2.6
  BOTTOM w0.305: U47.9 135.25,65.32 135.48,65.09
  BOTTOM w0.635: R467.1 136.57,64 135.48,65.09
N333289926: length 2.7
  BOTTOM w0.203: R468.1 R470.2 134.62,70.39 U47.5
N333289950: length 2.6
  BOTTOM w0.203: U47.2 132.09,68.87 131.45,69.5 R460.1
N333290075: length 1.5
  BOTTOM w0.305: U47.13 133.12,65.06 132.8,64.74
  BOTTOM w0.635: R463.1 132.55,64.5 132.8,64.74
N333290111: length 4.6
  BOTTOM w0.203: U47.11 134.12,64.93 134.4,64.65 134.4,64.23 133.42,63.26 133.42,62.75 133.71,62.46 R464.1
N333290147: length 3.4
  BOTTOM w0.102: R462.1 R466.2 136.43,69.73 135.44,69.73 135.12,69.42 U47.6
N339398220: length 3
  BOTTOM w0.102: U28.22 104.27,31.81 105.12,30.97 105.12,30.25 105.26,30.11 R312.1
N339398632: length 6
  BOTTOM w0.102: R319.2 D10.N 107.08,28.71 106.83,28.96 105.83,28.96 104.89,29.91 104.89,30.8 104.27,31.41 U28.23
N339398739: length 5.2
  BOTTOM w0.102: D11.N R321.2
  BOTTOM w0.114: U28.4 104.74,39.01 104.88,38.87 106.84,38.87 107.47,39.51 D11.N
N339399039: length 2.2
  BOTTOM w0.102: R337.2 87.05,27.94 87.72,28.61 U28.67
N339399233: length 8.9
  BOTTOM w0.102: U28.11 104.7,36.21 105.42,36.94 106.84,36.94 107.24,36.53 D7.N R304.1 108.68,36.53 109.69,35.52 R700.1
N339399553: length 8.7
  BOTTOM w0.152: X6.4 X5.2 108.02,42.69 C291.1 R344.1 104.89,42.69 102.71,40.51 102.71,39.99 102.89,39.81 U28.2
N339399628: length 3.1
  BOTTOM w0.102: U28.122 99.88,42.23 100.19,42.54 100.64,42.54 R292.1
N339399677: length 1.6
  BOTTOM w0.102: U28.48 96.28,25.64 95.91,25.27 R325.1
N339399812: length 1.7
  BOTTOM w0.203: R346.1 U30.3
N339399833: length 2.5
  BOTTOM w0.203: R345.1 85.84,45.19 85.3,44.65 U30.7
N339399994: length 1.4
  BOTTOM w0.203: R323.2 U28.47
N339400152: length 2.1
  BOTTOM w0.102: R324.2 105.06,33.78 104.63,34.21 U28.16
N339400173: length 5.1
  BOTTOM w0.102: U28.15 104.56,34.61 104.9,34.28 D9.N R318.2
N339400590: length 2.1
  BOTTOM w0.102: U28.82 87.19,34.61 86.77,35.03 R301.1
N339579908: length 2.8
  BOTTOM w0.305: Q8.1 R201.2 141.86,111.69 R501.1 141.86,112.47 R502.1
N342323491: length 1.4
  BOTTOM w0.102: C314.1 132.15,79.11 132.49,79.11 FIL7.4 133,78.59 R367.1
N342323527: length 8
  BOTTOM w0.101: R364.2 134.61,74.66 FIL6.2 134.89,74.39 U32.2 135.53,74.45 136.47,74.45 136.81,74.12 137.13,74.12 137.68,73.57 137.68,72.97 138.42,72.23 138.87,72.23 139.6,71.49 140.08,71.49 140.22,71.63 J2.6
N342323548: length 9.3
  BOTTOM w0.101: R368.2 134.5,79.84 FIL7.2 135.02,79.32 135.14,79.32 U33.2 135.44,79.62 136.34,79.62 136.69,79.28 137.19,79.28 137.59,78.87 137.59,77.31 138.2,76.7 139.04,76.7 139.7,77.36 140.12,77.36 140.22,77.46 J2.9
N342323565: length 6.9
  BOTTOM w0.101: R360.2 134.68,77.28 FIL5.2 135.2,76.76 135.46,76.76 D12.N 136.2,76.75 136.62,76.75 137.37,76 137.37,75.17 138.18,74.36 138.62,74.36 138.72,74.46 J2.2
N342323571: length 8.3
  BOTTOM w0.101: R362.2 134.61,73.41 FIL6.3 134.89,73.69 U32.1 135.54,73.62 136.49,73.62 136.77,73.91 137.04,73.91 137.47,73.48 137.47,72.88 138.33,72.01 138.78,72.01 139.51,71.28 140.11,71.28 140.22,71.17 J2.5
N342323607: length 1.3
  BOTTOM w0.102: R368.1 133,79.84 FIL7.1 132.64,79.48 132.1,79.48 C315.1
N342323609: length 6.8
  BOTTOM w0.101: J2.3 138.72,74.04 138.62,74.14 138.09,74.14 137.15,75.08 137.15,75.91 136.53,76.53 136.15,76.53 D13.N 135.48,76.54 135.2,76.54 FIL5.3 134.68,76.03 R361.2
N342323907: length 9.2
  BOTTOM w0.101: R367.2 134.5,78.59 FIL7.3 134.93,79.02 135.18,79.02 U33.1 135.42,78.77 136.41,78.77 136.7,79.06 137.1,79.06 137.38,78.78 137.38,77.23 138.12,76.49 139.13,76.49 139.79,77.14 140.12,77.14 140.22,77.04 J2.8
N344053358: length 1.4
  BOTTOM w0.114: U28.93 87.01,39.01 R307.1
N347061519: length 9.1
  BOTTOM w0.152: X6.1 X5.1 107.98,43.64 C289.1 R344.2 R343.2 104.49,42.67 102.64,40.82 102.41,40.82 102.28,40.95 U28.128
N350298939: length 23.5
  BOTTOM w0.203: U43.14 52.04,65.34 52.43,65.73
  BOTTOM w0.635: 52.43,65.73 52.85,66.15 52.85,72.89 46.13,79.61 R441.1
N350298979: length 13.8
  BOTTOM w0.203: 50.19,65.76 50.84,65.11 U43.11
  BOTTOM w0.635: 50.19,65.76 48.21,65.76 46.6,67.37 46.6,69.22 R443.1
N350299117: length 1.7
  BOTTOM w0.102: U43.19 53.81,63.13 54.01,62.94 R436.1
N350299126: length 2.5
  BOTTOM w0.203: C393.1 50.57,61.29 50.37,61.48 50.37,61.91 50.59,62.13 U43.5
  BOTTOM w0.305: C393.1 R444.1
N350299527: length 2.8
  BOTTOM w0.203: U43.15 52.91,64.93 53.29,65.32
  BOTTOM w0.406: 53.29,65.32 54.09,66.12 R442.2
N350299529: length 3.9
  BOTTOM w0.203: C394.2 49.28,63.77 49.51,63.53 U43.8
  BOTTOM w0.305: R445.1 48.77,62.95 C394.2 48.01,63.77 R446.2 R447.2
N350299649: length 2
  BOTTOM w0.102: U43.16 53.39,64.33 54.11,65.06 54.31,65.06 R440.2
N350299667: length 3.8
  TOP w0.406: v2(54.09,69) 54.09,69 v2(51.64,69)
  BOTTOM w0.406: R442.1 v2(54.09,69) ; v2(51.64,69) 51.64,69 C386.2
N350299694: length 13.4
  BOTTOM w0.203: U43.13 51.64,65.81
  BOTTOM w0.635: v1(46.85,76.39) 50.65,72.59 50.65,67.81 C386.1 51.64,65.81
N350299721: length 2.8
  BOTTOM w0.203: U43.6 50.05,62.73 49.76,62.45
  BOTTOM w0.305: 49.76,62.45 49.32,62 R445.2 C392.2
N350299729: length 1.7
  BOTTOM w0.102: U43.18 53.93,63.53 54.1,63.7 R438.2
N350299756: length 1.3
  BOTTOM w0.102: Q36.3 56.38,71.69 R434.2
N350945194: length 9.6
  BOTTOM w0.305: R192.1 R193.1 R194.1 R195.1 R196.1 R197.1 R198.1 R200.1 145.14,105.52 144.24,106.41 143.18,106.41 142.81,106.79 Q8.3
N369066236: length 20.4
  LAY4 w0.102: v2(98.26,24.48) 93.88,28.86 v2(93.88,29.69)
  BOTTOM w0.102: R702.1 R701.1 98.38,24.36 v2(98.26,24.48) ; U28.107 93.88,41.66 v2(93.88,29.69)
N369071729: length 2.1
  BOTTOM w0.102: R322.1 89.83,42.99 90.28,42.54 U28.98
N370323697: length 1.8
  TOP w0.102: U1.AH42 v2(84.79,78.29)
  BOTTOM w0.102: R1.2 84.13,77.63 v2(84.79,78.29)
N370323746: length 1.8
  TOP w0.102: U1.AF42 v2(84.79,77.58)
  BOTTOM w0.102: R2.2 84.05,76.84 v2(84.79,77.58)
N370323875: length 1.2
  TOP w0.203: U1.AD44 v2(86.69,76.86)
  BOTTOM w0.203: v2(86.69,76.86) 87.07,77.24 R4.1
N370323891: length 1.4
  TOP w0.203: U1.AF45 v2(84.79,76.15)
  BOTTOM w0.203: v2(84.79,76.15) 84.29,75.66 R3.1
N370323945: length 3.4
  TOP w0.203: U1.AD45 v2(86.69,76.15)
  BOTTOM w0.203: v2(86.69,76.15) 87.2,75.65 R5.1
N370344518: length 3.7
  TOP w0.089: 84.21,98.94 84.21,98.79 84.1,98.69 84.1,98.68 84.1,98.22 83.98,98.1 83.98,97.86 84.28,97.56 U1.AH3
  TOP w0.102: 84.21,98.94 84.21,99.19 v2(83.8,99.6)
  BOTTOM w0.102: v2(83.8,99.6) 83.85,99.55 R23.1
N370344521: length 4.7
  TOP w0.089: 84.46,98.85 84.46,98.78 84.29,98.61 84.29,98.6 84.28,98.59 U1.AH2
  TOP w0.102: v2(83.8,100.27) 84.46,99.6 84.46,98.85
  BOTTOM w0.102: v2(83.8,100.27) 83.42,99.89 83.42,98.87 R25.1
N370344943: length 1.2
  TOP w0.203: U1.AW1 v2(78.94,98.88)
  BOTTOM w0.203: v2(78.94,98.88) 79.42,98.4 R26.1
N370350025: length 1.2
  TOP w0.101: U1.AK12 v2(82.81,93.52)
  BOTTOM w0.101: R19.2 82.93,93.65 v2(82.81,93.52)
N370350028: length 1.1
  TOP w0.101: U1.AK13 v2(82.81,92.81)
  BOTTOM w0.101: v2(82.81,92.81) 82.92,92.7 R19.1
N370350254: length 5.6
  TOP w0.102: R22.2 82.42,102.51 82.42,101.53 82.23,101.34 82.23,98.28 82.05,98.1 82.05,97.86 82.34,97.57 U1.AM3
N370350257: length 4.9
  TOP w0.102: U1.AM2 82.45,98.09 82.45,101.23 82.63,101.41 82.63,102.03 83.14,102.55 R24.2
N370394982: length 1.3
  TOP w0.102: v2(77.93,94.24) U1.BB10
  BOTTOM w0.102: R33.2 77.99,94.29 v2(77.93,94.24)
N370394985: length 2.2
  TOP w0.102: U1.BC10 v2(77.34,93.36)
  BOTTOM w0.102: R35.2 78.44,93.77 77.76,93.77 v2(77.34,93.36)
N370395195: length 1
  TOP w0.101: U1.AT18 v2(80.9,90.39)
  BOTTOM w0.101: R37.2 81.05,90.54 v2(80.9,90.39)
N370395197: length 1
  TOP w0.101: U1.AU18 v2(80.19,90.39)
  BOTTOM w0.101: R37.1 80.1,90.48 v2(80.19,90.39)
N370395763: length 1.2
  TOP w0.203: U1.AY18 v2(78.06,90.39)
  BOTTOM w0.203: R45.1 77.5,90.39 v2(78.06,90.39)
N370395851: length 1.3
  TOP w0.203: U1.BF26 v2(75.21,86.5)
  BOTTOM w0.203: R55.1 v2(75.21,86.5)
N370396853: length 1.1
  TOP w0.203: U1.BF20 v2(75.21,88.48)
  BOTTOM w0.203: R46.2 v2(75.21,88.48)
N370397174: length 7.8
  TOP w0.114: R47.1 70.62,85.24 70.06,85.79 70.06,87.24 70.77,87.95 73.86,87.95 74.19,88.28 74.43,88.28 74.73,87.98 U1.BG22
N370397581: length 5.8
  BOTTOM w0.102: R272.2 115.48,18.53 Q13.3 ; Q13.3 U24.2 ; Q13.3 119.58,18.53 R270.2
N370397628: length 1.3
  BOTTOM w0.102: R275.1 119.56,24.12 Q14.1
N370397693: length 7.1
  BOTTOM w0.102: R271.2 119.14,21.29 118.91,21.51 116.88,21.51 116.57,21.2 Q13.1 116.12,20.53 115.76,20.88 Q14.3
N370398430: length 9
  TOP w0.114: U1.BH20 74.23,88.87 73.76,88.87 73.69,88.8 73,88.8 72.86,88.94 72.79,89.01 70.02,89.01 68.67,87.66 68.67,85.64 69.06,85.25 R48.1
N370398495: length 7.6
  TOP w0.114: R49.1 69.84,85.26 69.21,85.9 69.21,87.31 70.36,88.47 U1.BJ21
N370398555: length 10.4
  TOP w0.114: R50.1 68.29,87.79 69.87,89.38 72.75,89.38 73.09,89.04 73.51,89.04 73.61,89.13 73.61,89.13 73.62,89.14 74.08,89.14 74.19,89.25 74.44,89.25 74.73,88.95 U1.BG20
N370398936: length 1.3
  TOP w0.101: U1.AP14 v2(80.9,91.39)
  BOTTOM w0.101: v2(80.9,91.39) 81.09,91.58 R44.2
N370398938: length 1.4
  TOP w0.101: U1.AP13 v2(80.9,92.1)
  BOTTOM w0.101: v2(80.9,92.1) 81.33,92.53 R44.1
N370399144: length 7.4
  TOP w0.101: v2(78.92,94.95) U1.AY7
  BOTTOM w0.101: v2(78.92,94.95) 78.75,95.12 78.58,95.12 78.33,95.36 78.33,95.37 78.32,95.38 78.32,97.36 77.65,98.04 77.65,99.33 76.8,100.18 76.8,100.51 C4.2
N370399202: length 5.9
  TOP w0.101: v2(78.92,96.37) 79.18,96.18 U1.AV6
  BOTTOM w0.101: C6.2 78.96,100.45 78.82,100.31 78.82,99.78 78.5,99.45 78.5,98.49 79.53,97.46 79.53,96.83 79.29,96.59 79.14,96.59 v2(78.92,96.37)
N370399343: length 7.5
  TOP w0.101: U1.AY6 v2(78.92,95.66)
  BOTTOM w0.101: C5.2 77.09,100.72 77.01,100.64 77.01,100.26 77.85,99.41 77.85,98.12 78.54,97.44 78.54,95.44 78.66,95.32 78.84,95.32 78.92,95.41 v2(78.92,95.66)
N370399448: length 5.9
  TOP w0.101: U1.AV4 v2(78.92,97.08)
  BOTTOM w0.101: C3.2 78.19,100.33 78.32,100.2 78.51,100.2 78.62,100.08 78.62,99.87 78.29,99.54 78.29,98.39 79.32,97.37 79.32,96.92 79.21,96.82 79.03,96.82 78.92,96.93 v2(78.92,97.08)
N370401528: length 1.3
  TOP w0.102: v2(77.93,95.66) U1.BB7
  BOTTOM w0.203: R38.1 77.67,95.39 v2(77.93,95.66)
N370401530: length 1.1
  TOP w0.102: v2(77.93,96.37) U1.BB5
  BOTTOM w0.203: R40.1 v2(77.93,96.37)
N370482122: length 1.7
  TOP w0.102: U1.BE3 v2(76.12,96.67)
  BOTTOM w0.102: v2(76.12,96.67) 76.25,96.8 R43.1
N370482125: length 1.8
  TOP w0.102: U1.BG5 v2(75.06,96.65)
  BOTTOM w0.102: R42.1 74.72,96.99 v2(75.06,96.65)
N370489010: length 1.6
  TOP w0.203: Q5.1 D3.N
N370489012: length 0.8
  TOP w0.203: C132.1 R135.1
N370495932: length 1.2
  TOP w0.102: U1.M12 v2(92.56,93.52)
  BOTTOM w0.102: R86.1 92.56,94.13 92.56,93.53 v2(92.56,93.52)
N370496363: length 12.3
  TOP w0.102: U1.BC12 v2(76.63,93.36)
  TOP w0.114: v2(67.8,94.3) R94.2 R91.1
  LAY3 w0.127: v2(67.8,94.3) 68.54,95.04 69.18,95.04 71.45,92.77 75.24,92.77 76.04,92.77 v2(76.63,93.36)
N370535741: length 1.4
  TOP w0.102: v2(96.22,94.29) U1.D10
  BOTTOM w0.102: R87.1 96.75,94.29 v2(96.22,94.29)
N370535744: length 16.3
  TOP w0.102: U1.F10 v2(95.55,94.35)
  TOP w0.114: v2(108.15,99.54) 108.15,100.02 R88.1
  BOTTOM w0.114: v2(95.55,94.35) 95.9,94.71 96.31,94.71 97.95,96.34 100.56,96.34 104.26,100.04 107.63,100.04 108.15,99.52 v2(108.15,99.54)
N370535989: length 2.5
  TOP w0.203: U1.D6 v2(96.5,95.62) ; U1.C7 v2(95.93,95.14)
  BOTTOM w0.508: R92.2 96.96,96.09 v2(96.5,95.62) 96.02,95.14 v2(95.93,95.14)
N370536167: length 4.6
  TOP w0.089: U1.B4 97.08,97.08 97.74,97.08
  TOP w0.102: R95.2 97.98,100.7 97.98,98.29 97.85,98.15 97.85,97.84 97.98,97.71 97.98,97.33 97.74,97.08
N370536170: length 6.1
  TOP w0.089: 98.51,96.36 97.19,96.36 U1.B5
  TOP w0.102: 98.51,96.36 98.69,96.54 98.69,100.61 R96.2
N370536206: length 3.4
  TOP w0.089: 95.55,98.63 95.55,98.1 95.55,98 U1.E2
  TOP w0.102: 95.55,98.63 95.91,98.99 95.91,99.34 96.43,99.87 R97.2
N370536208: length 3.5
  TOP w0.089: 96.27,98.56 96.27,98.16 96.27,97.89 U1.D2
  TOP w0.102: 96.27,98.56 96.5,98.79 96.74,98.79 97.2,99.25 R98.2
N370536412: length 5
  TOP w0.254: R99.2 99,98.36 99,96.07 98.34,95.41 97.67,95.41 97.56,95.3 U1.A7
N370536484: length 1.1
  TOP w0.203: U1.BF18 v2(75.21,90.39)
  BOTTOM w0.203: v2(75.21,90.39) 75.2,90.39 74.84,90.75
N370539794: length 0.5
  TOP w0.152: v2(85.74,83.65) 85.36,84.03 U1.AF30
N370539817: length 0.5
  TOP w0.152: v2(87.31,88.2) 87.69,87.82 U1.AA22
N370571694: length 1.9
  TOP w0.203: U1.Y32 v2(88.09,83.65) ; U1.AC32 v2(87.31,82.9)
  BOTTOM w0.254: R118.2 88.42,83.98 v2(88.09,83.65)
N370574162: length 7.8
  TOP w0.203: U1.AM32 v2(82.6,83.65)
  BOTTOM w0.203: 68.83,84.96 68.26,84.39 68.26,83.77 67.66,83.16 66.71,83.16 65.11,81.56 R112.2 R111.2
N370574202: length 0.5
  TOP w0.203: U1.AM27 v2(82.59,85.17)
N370574265: length 5
  TOP w0.203: v2(90.58,86.5) 90.58,86.54 U1.U24 ; U1.U24 90.08,87.09 90.02,87.09 v2(89.66,87.45) 89.66,86.7 U1.U25 ; U1.U24 89.3,86.31 U1.V25 ; v2(92,88.48) U1.N20
  TOP w0.229: v2(90.58,86.5) 90.39,86.31 U1.U25
N370574283: length 1.1
  TOP w0.254: U1.AD18 86.29,90.26 86.52,90.48 v2(86.53,90.48) 86.31,90.69 86.14,90.86 U1.AD16
N370574303: length 0.5
  TOP w0.203: U1.V18 89.26,90.1 v2(88.88,89.72)
N370668728: length 3.2
  BOTTOM w0.102: U28.124 100.68,42.22 101.49,43.03 102.05,43.03 R329.2
N370706058: length 2.1
  BOTTOM w0.102: C290.1 105.05,36.28 104.59,35.81 U28.12
N370732942: length 10.4
  TOP w0.089: U1.BG15 74.48,91.57 74.19,91.57 74.08,91.68 73.62,91.68 73.61,91.69 73.61,91.69 73.51,91.78 73.09,91.78 73,91.69
  TOP w0.102: 73,91.69 v2(72.69,91.38)
  BOTTOM w0.114: v2(72.69,91.38) 68.98,95.09 67.5,95.09 R101.2
N370732965: length 8.2
  TOP w0.089: 72.88,91.9 72.97,91.98 73.58,91.98 73.68,91.88 73.69,91.88 73.7,91.87 U1.BH14
  TOP w0.102: v2(72.03,91.38) 72.54,91.9 72.88,91.9
  BOTTOM w0.114: v2(72.03,91.38) 71.43,91.38 69.26,93.56 67.86,93.56 R102.2
N370733760: length 1.1
  BOTTOM w0.102: U26.12 107.91,22.94 108.13,23.16 R298.2
N370758959: length 0.8
  BOTTOM w0.203: U27.12 111.33,31.36 R313.2
N370761700: length 5.2
  TOP w0.102: R127.2 53.37,61.45 53.37,62.65 54.1,63.38 Q4.3 54.1,64.04 55.05,64.99 Q4.1
N370761781: length 2.4
  TOP w0.102: R128.1 55.21,60.52 C129.2 55.45,60.71 U7.3
N370761791: length 5.9
  TOP w0.102: Q4.2 53.15,63.48 52.84,63.17 52.84,60.72 53.04,60.52 R128.2
N370761793: length 2.3
  TOP w0.102: U7.2 55.32,61.36 C129.1 54.5,61.45 R127.1
N370766504: length 5.5
  TOP w0.102: U1.BG11 74.67,93.87 74.43,94.1 74.19,94.1 74.03,93.94 72.82,93.94 71.24,95.53 R109.2
N370820727: length 19
  TOP w0.203: v1(115.85,112.83) 115.21,113.47 U56.47
  TOP w0.635: R520.1 v1(120.38,102.25)
  BOTTOM w0.635: v1(120.38,102.25) 122.14,102.25 123.17,103.27 123.17,105.95 119.88,109.24 117.76,109.24 115.85,111.15 v1(115.85,112.83)
N370827950: length 27.3
  TOP w0.203: U56.45 114.41,112.91 v1(114.55,112.76) 114.71,112.61 C468.1 R524.2
  TOP w0.305: L14.1 v2(130.89,101.45)
  TOP w0.635: v1(120.43,103.38) 120.63,103.59 122.93,103.59 Q41.7
  BOTTOM w0.305: v2(130.89,101.45) 130.63,101.19 R511.1
  BOTTOM w0.635: v1(114.55,112.76) 114.55,110.69 117.5,107.74 119.5,107.74 121.81,105.43 121.81,103.99 121.21,103.38 v1(120.43,103.38)
N370828403: length 2.5
  TOP w0.203: R521.2 115.23,112.45 115.23,112.98 114.81,113.4 U56.46
N370828574: length 1.2
  TOP w0.203: C468.2 R521.1
N370828861: length 2.5
  TOP w0.635: R520.2 121.32,99.97 121.94,100.59 Q41.1
N370828884: length 1.5
  TOP w0.635: Q41.6 R526.2
N370829798: length 14.9
  TOP w0.203: v1(113.7,112.77) 114.01,113.08 U56.44
  TOP w0.635: R526.1 v1(120.42,104.54)
  BOTTOM w0.635: v1(120.42,104.54) 119.85,105.11 116.95,105.11 113.44,108.61 113.44,112.51 v1(113.7,112.77)
N370832810: length 1
  TOP w0.203: C473.2 R524.1
N370840080: length 0.8
  BOTTOM w0.305: R519.2 R512.1
N370843819: length 1.9
  TOP w0.203: 111.21,113.22 U56.37
  TOP w0.305: R527.2 111.21,113.22
N370879306: length 1.5
  TOP w0.114: R522.2 113.56,120.58 113.56,119.65 U56.18
N370879343: length 1.4
  TOP w0.114: R523.2 113.21,120.83 U56.19
N370879346: length 1.6
  TOP w0.114: R525.2 112.82,120.39 112.82,119.61 U56.20
N370880811: length 3
  TOP w0.102: R513.2 C465.2 116.25,120.88 115.85,120.48 115.41,120.48 114.81,119.88 U56.15
N370904548: length 2.6
  TOP w0.635: Q37.3 v1(40.42,74.76)
  BOTTOM w0.635: R443.2 v1(40.42,74.76)
N370904936: length 2.5
  TOP w0.635: Q37.8 v1(37.88,79.61)
  BOTTOM w0.635: R441.2 v1(37.88,79.61)
N370908739: length 1
  TOP w0.203: C428.2 58.23,84.33 U51.6
N370911201: length 0.9
  TOP w0.203: C440.2 91.57,109.44 U54.6
N370914127: length 6.2
  BOTTOM w0.102: Q74.3 132.78,51.43 R476.1 R474.2 130.91,54.12 129.97,54.12 129.8,54.29 U49.6
N370985600: length 4.9
  TOP w0.102: R54.1 65.82,79.29 64.42,80.69 Q100.3
N371005282: length 1.9
  TOP w0.089: U1.B30 97.77,84.09 97.87,84.2 98.21,84.2 v2(98.8,83.61)
N371025596: length 1.8
  BOTTOM w0.114: R262.1 124.89,19.11 U23.8
N371025625: length 3.9
  BOTTOM w0.203: U23.1 126.04,16.31 125.8,16.07 C255.2
  BOTTOM w0.305: FB10.2 C254.1 124.68,15.72 125.03,16.07 C255.2
N371025642: length 1.2
  BOTTOM w0.305: R245.1 C237.1
N371025675: length 3.5
  BOTTOM w0.203: 130.09,21.86 U23.20
  BOTTOM w0.305: C236.2 131.7,22.78 131.02,22.78 130.09,21.86
N371025681: length 2.4
  BOTTOM w0.102: U23.7 125.36,18.71 124.73,18.07 C253.2
N371025772: length 2.7
  BOTTOM w0.203: 129.78,22.14 129.69,22.05 U23.19
  BOTTOM w0.305: C237.2 129.78,22.14
N371025837: length 2.9
  BOTTOM w0.102: R251.2 R256.2 126.85,22.8 127.29,22.36 127.29,21.41 U23.13
N371025969: length 2
  BOTTOM w0.305: R243.1 110.01,12.33 C242.2 110.01,13.32 U22.4
N371026280: length 0.9
  BOTTOM w0.254: U20.6 110.97,18.56 111.84,18.56 C225.2
N371026303: length 2.1
  BOTTOM w0.203: R252.1 127.64,22.41 128.09,21.96 U23.15
N371026305: length 3.3
  BOTTOM w0.102: U23.37 132.78,15.61 134.12,14.27 C245.1
N371026324: length 3.6
  BOTTOM w0.203: C231.1 135.61,17.11 U23.34
N371026326: length 5.8
  BOTTOM w0.102: U23.35 132.11,16.71 131.87,16.46 131.87,16.16 132.06,15.97 132.71,15.97 133.77,14.91 134.88,14.91 135.52,14.27 C245.2
N371026438: length 2.4
  BOTTOM w0.102: R236.1 118.42,9.61 118.6,9.61 C227.2 118.97,9.99 U19.4
N371026457: length 3.2
  BOTTOM w0.203: C235.1 134.14,21.56 133.77,21.19 133.77,20.81 132.87,19.91 U23.27
N371026615: length 2.7
  BOTTOM w0.203: 133.26,17.51 U23.33
  BOTTOM w0.305: 133.26,17.51 134.62,17.51 R238.2
N371026619: length 2.7
  BOTTOM w0.203: 134.27,18.1 134.06,17.89 132.41,17.89 U23.32
  BOTTOM w0.305: R241.2 134.27,18.1
N371026698: length 2.1
  BOTTOM w0.305: U21.4 R235.1 138.52,27.63 C228.2
N371027408: length 1.2
  BOTTOM w0.305: R242.1 C236.1
N371074716: length 1.3
  BOTTOM w0.102: Q62.1 R579.2
N371076465: length 5.5
  TOP w0.102: CN3.198 62.98,46.69 v2(64.64,45.03)
  BOTTOM w0.102: R581.2 64.83,44.84 v2(64.64,45.03)
N371123920: length 0.9
  BOTTOM w0.203: U16.6 67,44.9 C511.2
N371123996: length 2.5
  BOTTOM w0.114: R593.2 R208.2 R212.1 70.63,44.9 U16.3
N371156292: length 0.8
  BOTTOM w0.203: U60.6 C514.2
N371156339: length 1.8
  BOTTOM w0.114: R598.2 R595.1 42.95,61.94 42.95,61.31 U60.3
N371163469: length 3.2
  BOTTOM w0.114: U23.12 126.59,21.82 125.3,23.11 C517.2
N371163479: length 1.6
  BOTTOM w0.114: R600.1 124.51,24.27 R601.2 125.3,24.27 C517.1
N371165243: length 3.7
  TOP w0.102: R105.2 72.02,87.11 73.99,87.11 74.17,87.3 74.44,87.3 74.73,87.01 U1.BG24
N371165245: length 3.1
  TOP w0.102: U1.BH24 74.21,86.9 72.57,86.9 R107.2
N371165394: length 14.6
  TOP w0.089: 73,84.96 73.59,84.96 73.7,85.06 U1.BH28
  TOP w0.102: v2(71.37,83.61) 71.37,84.01 72.32,84.96 73,84.96
  BOTTOM w0.102: v2(71.37,83.61) 70.27,82.51 67.2,82.51 63.37,78.67 U74.2
N371165399: length 15
  TOP w0.089: U1.BG28 74.83,84.88 74.55,84.88 74.44,84.77 74.19,84.77 74.09,84.86 73.76,84.86 73.66,84.76 72.88,84.76
  TOP w0.102: 72.88,84.76 72.75,84.76 72.03,84.03 v2(72.03,83.61)
  BOTTOM w0.102: v2(72.03,83.61) 70.54,82.12 67.16,82.12 63.72,78.68 U74.3
N371340666: length 1.4
  TOP w0.102: U65.5 67.43,99.35 R17.1
N371377879: length 2.2
  TOP w0.114: CN12.1 49.9,31.53 v2(49.84,31.47)
  BOTTOM w0.114: v2(49.84,31.47) 49.65,31.67 R636.2
N371395696: length 3.2
  BOTTOM w0.102: Q68.3 33.28,46.42 R590.2 Q67.1
N371414444: length 117.8
  LAY4 w0.102: v2(94.9,116.83) 94.27,116.2 87.88,116.2 85.59,118.5 62.69,118.5 62.03,117.84 54.42,117.84 54.08,118.19 51.09,118.19 50.75,117.84 49.26,117.84 48.97,118.13 47.07,118.13 39.57,110.62 36.45,110.62 32.42,106.59 32.42,80.66 31.67,79.9 31.67,73.69 30.97,72.99 30.97,65.45 31.96,64.45 v2(31.96,62.74)
  BOTTOM w0.102: U53.6 96.99,116.03 96.19,116.83 Q52.3 94.9,116.83 v2(94.9,116.83) ; R479.1 v2(31.96,62.74)
N371416452: length 1.9
  BOTTOM w0.102: U53.4 93.81,114.67 R494.2 R496.1
N371417145: length 2.1
  BOTTOM w0.102: U53.5 94.11,115.17 R484.1 R495.2
N371418676: length 2.3
  BOTTOM w0.203: R489.1 R487.1 35.54,50.45 U52.4
N371418689: length 2.3
  BOTTOM w0.203: U52.5 35.53,49.52 R490.1 34.8,48.79 R488.2
N371440242: length 2.2
  BOTTOM w0.102: U39.4 R387.1 R713.2
N371449799: length 1
  BOTTOM w0.203: C409.2 118.48,68.15 U46.6
N371449990: length 1.8
  BOTTOM w0.152: C416.2 113.39,77.06 114.11,76.34 U48.6
N371450050: length 14.6
  BOTTOM w0.152: Q79.3 111.56,72.21 R471.2 112.23,71.67 R645.1 114.11,73.54 U48.3 ; Q79.3 108.76,73.8 108.54,74.02 106.58,74.02 R561.2 ; Q79.3 Q80.3
N371541226: length 1.8
  BOTTOM w0.254: U42.22 25.03,90.43 C369.1
N371541419: length 3.9
  BOTTOM w0.254: 23.23,88.73 U42.19
  BOTTOM w0.406: 22.73,88.73 23.23,88.73
  BOTTOM w0.635: 22.73,88.73 22.69,88.73 21.62,89.8 R432.2
N371543859: length 7.3
  LAY4 w0.635: v1(24.4,89.7) 24.4,91.63 v1(21.88,94.15)
  BOTTOM w0.254: U42.21 24.53,89.25
  BOTTOM w0.406: 24.53,89.25 24.53,89.57 v1(24.4,89.7)
  BOTTOM w0.635: R429.2 v1(21.88,94.15)
N371546994: length 1.8
  TOP w0.635: R430.1 v1(24.4,83.78)
  BOTTOM w0.254: v1(24.4,83.78) 24.53,83.91 U42.10
N371547056: length 3.1
  BOTTOM w0.254: U42.12 23.01,84.68
  BOTTOM w0.635: R431.1 22.61,84.28 23.01,84.68
N371548461: length 1.9
  BOTTOM w0.254: U42.9 25.03,83.39 C370.2
N371555765: length 1.4
  TOP w0.102: D25.3 C378.2
N371555769: length 8.6
  TOP w0.102: D25.1 24.68,87.37 27.43,84.61 29.49,84.61 C381.1 30.21,83.9 D24.2
N371555881: length 1.4
  TOP w0.102: C377.2 35.35,84.85 D24.3
N371592399: length 2.7
  BOTTOM w0.203: U47.4 134.12,69.66 133.61,70.17 C413.1 R461.1
N371594383: length 1.3
  BOTTOM w0.254: U47.14 R459.1
N371598766: length 0.9
  BOTTOM w0.203: U45.6 C400.2
N371598824: length 3.1
  BOTTOM w0.203: U45.3 R472.2 75.5,114.27 75.05,114.72 Q75.3
N371600351: length 3.1
  BOTTOM w0.203: Q70.3 28.67,46.76 28.13,47.3 R376.1 28.13,48.13 28.67,48.67 Q71.1
N371600404: length 1.8
  BOTTOM w0.102: R247.2 R378.1 Q70.1
N371602762: length 3.4
  BOTTOM w0.102: Q72.3 135.05,55.08 R500.1 135.05,54.38 135.44,53.99 Q73.1
N371602779: length 1.1
  BOTTOM w0.102: Q72.1 R377.1
N371622208: length 3.3
  BOTTOM w0.152: R469.1 109.56,71.89 Q79.1 108.18,72.85 Q25.3
N371622225: length 1.6
  BOTTOM w0.152: R644.1 R561.1 Q25.1
N371631055: length 0.9
  BOTTOM w0.203: U44.6 88.05,118.5 88.05,117.75 C398.2
N371631113: length 4.7
  BOTTOM w0.102: Q76.3 89.65,123.81 R510.1 88.29,122.44 R454.2 88.05,121.41 U44.3
N371631654: length 1.2
  TOP w0.254: C447.2 18.99,65.29 18.55,65.29 U68.6
N371634130: length 2.7
  TOP w0.102: Q45.1 25.54,61.86 R558.1 25.63,61.96 Q44.3
N371634202: length 1
  TOP w0.102: R557.1 27.34,64.35 Q44.1
N371637080: length 1.1
  TOP w0.305: U69.6 37.72,103.18 C535.2
N371637134: length 9.1
  TOP w0.203: v2(37.98,100.04) 37.73,100.29 U69.3 ; v2(41.46,104.15) 41.46,104.4 41.46,104.4 R559.1 42.27,104.82 R383.1 42.27,104.82 Q54.3
  BOTTOM w0.203: v2(41.46,104.15) 41.46,103.46 38.04,100.04 v2(37.98,100.04)
N371697900: length 2.3
  BOTTOM w0.114: R328.1 105.25,31.66 104.3,32.61 U28.20
N371698348: length 2.5
  BOTTOM w0.114: U28.21 104.3,32.21 R335.2
N371705444: length 1.3
  BOTTOM w0.102: R657.1 81.03,38.42 U70.3
N371706163: length 77.9
  TOP w0.102: v2(65.78,80.04) 65.35,80.48 R712.1
  LAY4 w0.102: v2(65.78,80.04) 65.78,76.35 65.31,75.88 65.31,70.82 62.68,68.19 62.68,64.69 55.75,57.76 55.75,49.27 57.74,47.27 69.02,47.27 70.68,45.61 86.02,45.61 88.62,43.01 v2(91.91,43.01)
  BOTTOM w0.102: 91.91,43 92.84,43 93.48,42.36 U28.106 ; 91.91,43 91.67,43.25 R658.2 ; 91.91,43 91.91,43 v2(91.91,43.01)
N371707559: length 4
  BOTTOM w0.102: U28.113 96.28,45.21 R659.1
N371729099: length 3.3
  BOTTOM w0.102: U28.109 94.68,41.66 94.68,42.21 93.78,43.11 93.14,43.11 R717.1
N371748554: length 1.3
  TOP w0.102: Q53.3 R567.1
N371748828: length 2.1
  BOTTOM w0.305: R565.1 22.96,44.19 Q51.3
N371749875: length 1.9
  TOP w0.508: R571.1 123.34,76.63 Q57.3
N371749956: length 1.4
  TOP w0.305: Q56.3 R570.1
N371750028: length 1.4
  BOTTOM w0.406: Q58.3 R572.1
N371750040: length 1.3
  TOP w0.508: Q55.3 32.11,100.09 R569.1
N371750942: length 2.3
  BOTTOM w0.203: Q59.3 R573.1
N371751422: length 1.6
  BOTTOM w0.102: R664.2 U71.1
N371776174: length 2.8
  BOTTOM w0.102: Q61.3 60.19,61 R576.1
N371829347: length 4.8
  TOP w0.305: v2(95.76,128.87) 95.76,128.87 L15.1
  BOTTOM w0.305: v2(95.76,128.87) 96.25,128.87 96.76,128.36 R532.1
N371829553: length 0.8
  BOTTOM w0.305: R539.2 94.97,127.4 R535.1
N371829623: length 2.3
  TOP w0.254: 100.82,113.03 U57.1
  TOP w0.406: 100.82,113.03 100.31,112.53 R540.2
N371829625: length 1.2
  TOP w0.406: R540.1 99.29,115.23 C480.2
N371829670: length 1.5
  TOP w0.635: Q87.1 103.25,118.41 v1(103.25,117.78)
  BOTTOM w0.635: R667.2 v1(103.25,117.78)
N371829672: length 2.6
  TOP w0.254: 100.69,115.97 100.82,115.84 U57.8
  TOP w0.406: 100.69,115.97 v1(100.34,116.31)
  BOTTOM w0.635: v1(100.34,116.31) 100.34,117.25 R667.1
N371829674: length 5.8
  TOP w0.635: Q87.6 97.66,118.4 v1(97.66,117.78)
  BOTTOM w0.635: v1(97.66,117.78) 99.13,116.32 99.13,115.79 99.82,115.09 R666.2
N371829676: length 1.8
  TOP w0.254: 102.61,115.76 102.42,115.57 U57.5
  TOP w0.406: v1(102.92,116.07) 102.61,115.76
  BOTTOM w0.635: R666.1 v1(102.92,116.07)
N371898761: length 2.2
  BOTTOM w0.102: U28.84 87.21,35.41 86.58,36.04 R248.1
N371988566: length 17.9
  TOP w0.102: v2(109.49,100.44) 110,99.94 R129.2 ; U1.D14 v2(96.27,92.37)
  LAY4 w0.102: v2(96.27,92.37) 97.48,93.58 97.48,93.6 97.97,94.09 98.49,94.09 101.87,97.47 102.69,97.47 102.7,97.48 103.38,97.48 106.34,100.44 v2(109.49,100.44)
N371988594: length 0.8
  TOP w0.102: U6.12 R82.2
N371988759: length 3.5
  TOP w0.102: U1.G12 v2(94.85,93.36)
  BOTTOM w0.102: R131.2 97.34,93.8 95.29,93.8 v2(94.85,93.36)
N371988761: length 20.3
  TOP w0.102: U1.F14 v2(95.56,92.37) ; R582.2 v2(110.79,100.49)
  LAY4 w0.102: v2(95.56,92.37) 96.06,92.87 96.39,92.87 96.7,93.18 96.7,93.47 98.11,94.88 98.56,94.88 101.42,97.75 103.25,97.75 106.48,100.97 110.31,100.97 v2(110.79,100.49)
N371988880: length 9
  TOP w0.089: 98.9,90.53 98.78,90.41 U1.A17
  TOP w0.102: 98.9,90.53 99.65,91.28 99.65,92.65 101.66,94.66
  TOP w0.114: R602.2 103.48,94.81 103.48,94.8 103.37,94.69 101.69,94.69 101.66,94.66
N371988894: length 20.9
  TOP w0.102: U1.F12 v2(95.56,93.36) ; R583.2 v2(111.61,100.49)
  LAY4 w0.089: v2(95.56,93.36) 95.96,93.76 96.59,93.76
  LAY4 w0.102: 96.59,93.76 96.67,93.76 98.02,95.11 98.46,95.11 101.4,98.05 103.23,98.05 106.57,101.38 110.71,101.38 v2(111.61,100.49)
N371988916: length 19.4
  TOP w0.102: v2(109.49,98.39) 109.75,98.13 R584.2 ; U1.G16 v2(94.85,91.38)
  LAY4 w0.102: v2(109.49,98.39) 108.58,98.39 108.3,98.67 105.47,98.67 103.82,97.02 101.84,97.02 98.74,93.92 98.74,93.26 97.26,91.78 95.25,91.78 v2(94.85,91.38)
N371989057: length 18.6
  TOP w0.102: R64.1 107.58,94.68 105.8,92.9 v2(104.73,92.9) ; U1.J24 v2(93.43,87.49)
  LAY3 w0.089: v2(93.43,87.49) 94.02,88.08 96.48,88.08 96.63,88.24
  LAY3 w0.102: 96.63,88.24 96.82,88.43 96.82,89.12 98.19,90.49 100.71,90.49 103.11,92.9 v2(104.73,92.9)
N371989083: length 9.2
  TOP w0.101: U1.B24 97.8,87.01 97.91,86.9 99.09,86.9 99.64,87.45
  TOP w0.102: 100.57,87.45 99.64,87.45
  TOP w0.114: 100.57,87.45 104.24,91.12 R586.1
N371989085: length 8.3
  TOP w0.101: 98.88,86.45 98.81,86.52 97.56,86.52 U1.A25
  TOP w0.102: 101.74,86.81 99.8,86.81 99.44,86.45 98.88,86.45
  TOP w0.114: R587.1 101.74,86.81
N371989087: length 9.4
  TOP w0.101: U1.C25 97,86.71 97.29,86.71 97.4,86.82 97.72,86.82 97.83,86.71 99.28,86.71 99.62,87.05
  TOP w0.102: 100.6,87.05 99.62,87.05
  TOP w0.114: R588.1 103.91,90.36 100.6,87.05
N371989209: length 1.4
  BOTTOM w0.254: CN2.1 41.73,125.16 R66.2
N371989219: length 1.3
  BOTTOM w0.254: D2.P 42.68,127.76 R66.1
N371989286: length 1.2
  TOP w0.203: U1.N26 v2(91.29,86.5)
  BOTTOM w0.254: R78.1 91.55,86.76 v2(91.29,86.5)
N371989315: length 22.5
  TOP w0.089: U1.C23 97,87.68 97.29,87.68 97.4,87.79 97.86,87.79 97.87,87.8 97.88,87.8 97.97,87.89 99.24,87.89 99.25,87.9
  TOP w0.102: 100.57,87.9 99.25,87.9
  TOP w0.114: 100.57,87.9 102.69,90.02 102.69,90.53 103.74,91.57 107.79,91.57 109.47,89.89 110.47,89.89 111.28,89.09 111.77,89.09 112.05,88.8 112.05,85.31 R70.1
N371989320: length 22.5
  TOP w0.089: 99.1,88.13 99.05,88.08 97.86,88.08 97.76,87.98 U1.B22
  TOP w0.102: 100.25,88.13 99.1,88.13
  TOP w0.114: R73.2 112.29,85.37 112.29,88.9 111.87,89.33 111.38,89.33 110.57,90.13 109.57,90.13 107.87,91.83 103.49,91.83 102.23,90.57 102.23,90.1 100.25,88.13
N371989334: length 19.7
  TOP w0.089: U1.A21 98.81,88.47 98.93,88.59
  TOP w0.102: 99.59,88.59 98.93,88.59
  TOP w0.114: 99.59,88.59 101.29,90.29 101.29,90.77 103.01,92.49 108.14,92.49 109.42,93.77 109.42,95.7 110.04,96.32 111.86,96.32 R74.1
N371989349: length 17.8
  TOP w0.089: 99.01,88.36 98.93,88.27 97.8,88.27 97.69,88.17 97.4,88.17 97.29,88.28 97.05,88.28 96.75,87.98 U1.C22
  TOP w0.102: 99.96,88.36 99.01,88.36
  TOP w0.114: R75.2 110.21,92.81 109.55,92.16 103.23,92.16 101.76,90.69 101.76,90.15 99.96,88.36
N371989367: length 15.1
  TOP w0.102: 101.57,98.19 100.31,96.93 100.31,96.05 98.73,94.47 97.64,94.47 U1.A9
  TOP w0.114: 101.57,98.19 102.61,99.24 102.61,100.19 103.26,100.83 103.26,102.46 103.77,102.97 R69.1 104.21,102.91 C14.2 106.77,102.91 X3.4
N371989481: length 15.2
  TOP w0.089: U1.C9 97.15,94.25 97.4,94 97.65,94 97.75,94.09
  TOP w0.102: 101.87,97.79 100.76,96.68 100.76,96.18 98.82,94.24 97.9,94.24 97.75,94.09
  TOP w0.114: X3.1 106.77,102.09 C11.2 104.21,102.09 R69.2 103.78,101.66 103.78,100.62 103.18,100.02 103.18,99.1 101.87,97.79
N371989608: length 7
  TOP w0.102: 99.53,97.8 99.53,97.38 99.94,96.98 99.94,96.15 98.52,94.73 97.05,94.73 U1.B8
  TOP w0.508: 99.53,97.8 100.41,98.68 C13.2
N371989658: length 14.8
  TOP w0.089: U1.C11 97,93.51 97.29,93.51 97.4,93.62 97.87,93.62 97.87,93.63 97.88,93.63 98,93.76
  TOP w0.102: 98,93.76 99.12,93.76 104,98.63 104,99.3 104.14,99.44 105.11,99.44 105.12,99.44 106.74,99.44 C10.1 107.2,98.68 R65.1
N371989798: length 2.1
  TOP w0.102: v2(87.68,92.1) 86.69,92.1 U1.AD14
  BOTTOM w0.254: R61.2 v2(87.68,92.1)
N371989857: length 1.1
  TOP w0.203: U1.AD13 v2(86.69,92.81)
  BOTTOM w0.254: R60.2 v2(86.69,92.81)
N371989882: length 11.7
  TOP w0.089: 97.51,92.92 97.29,93.14 97.05,93.14 96.75,92.84 U1.C12
  TOP w0.102: 97.51,92.92 98.34,92.92 98.95,93.53 99.22,93.53 101.91,96.22 102.1,96.41
  TOP w0.114: 102.1,96.41 102.26,96.56 102.46,96.56 C12.2 R68.2
N371989956: length 1.3
  TOP w0.102: v2(115.16,85.09) 115.73,85.09 U5.6
  BOTTOM w0.102: C18.2 v2(115.16,85.09)
N371989976: length 12.2
  TOP w0.089: 98.95,90.3 98.86,90.22 97.83,90.22 97.74,90.12 97.39,90.12 97.29,90.22 97.05,90.22 96.75,89.92 96.47,89.92 U1.C18
  TOP w0.102: 98.95,90.3 100.12,91.47 100.12,92.79 101.56,94.23 102.08,94.23
  TOP w0.114: 102.08,94.23 104.96,94.23 105.25,94.52 R110.2
N372041038: length 4.9
  TOP w0.102: R34.1 67.32,75.8 Q46.3 67.32,77.49 67.83,78 Q47.1
N372057452: length 10.4
  BOTTOM w0.102: U28.77 89.55,32.61 91,31.16 91,28.92 88.5,26.42 R674.2
N372200006: length 1.9
  TOP w0.203: R358.2 C549.2 U73.4
N372204615: length 1.8
  BOTTOM w0.102: R675.1 25.01,93.09 Q43.3
N372317662: length 0.7
  BOTTOM w0.102: U74.5 R682.1
N372349941: length 6.2
  BOTTOM w0.102: Q88.3 108.21,46.69 108.62,47.11 Q63.1 112.08,47.08 R327.2
N372453757: length 2.2
  BOTTOM w0.203: 128.66,22.09 128.89,21.85 U23.17
  BOTTOM w0.305: C249.2 128.66,22.09
N372453760: length 2.3
  BOTTOM w0.203: 129.29,22.07 129.29,21.41 U23.18
  BOTTOM w0.305: C250.2 129.86,22.98 129.29,22.41 129.29,22.07
N372521203: length 3.7
  BOTTOM w0.305: R686.2 C568.1
  BOTTOM w0.508: U76.5 C568.1 129.32,43.82 R708.2
N372521362: length 2.5
  BOTTOM w0.305: U76.4 R687.1 R686.1
N372521718: length 6.3
  BOTTOM w0.508: L16.1 L17.1 125.46,43.64 C569.1 U76.6
N372521761: length 2.1
  BOTTOM w0.508: C569.2 127.98,46.66 128.38,47.06 U76.1
N372522371: length 4.1
  BOTTOM w0.305: R689.1 C570.2 129.31,49.67 R688.1 U76.3
N372575543: length 1.5
  TOP w0.102: v2(28.84,118.44) 28.84,118.26 U77.4
  BOTTOM w0.102: v2(28.84,118.44) 28.84,118.43 R690.2
N372575558: length 1.5
  TOP w0.305: R691.2 36.8,117.45 U77.14
N372575569: length 2
  TOP w0.305: U77.23 30.14,125.01
  TOP w0.508: 30.14,125.01 R693.1
N372575577: length 1.5
  TOP w0.305: 33.28,125.14 33.39,125.03 U77.18
  TOP w0.508: R694.1 33.18,125.24 33.28,125.14
N372575582: length 4.1
  TOP w0.305: FB14.2 37.06,124.74 36.55,125.25 34.99,125.25 34.69,124.94 U77.16
N372638863: length 21.2
  LAY4 w0.102: v2(101.61,24.91) 101.61,25.18 97.1,29.7 v2(96.83,29.7)
  BOTTOM w0.102: v2(96.83,29.7) 96.83,30.27 101.08,34.52 U28.125 ; R704.1 v2(101.61,24.91)
N373120965: length 6.2
  TOP w0.102: v2(75.92,87.49) 75.92,87.67 U1.BF22
  BOTTOM w0.102: TP7.1 71.63,88.44 74.26,88.44 74.82,87.87 75.54,87.87 v2(75.92,87.49)
N373120968: length 5.3
  TOP w0.102: v2(76.63,87.49) 76.28,87.85 U1.BD22
  BOTTOM w0.102: v2(76.63,87.49) 76.05,88.08 74.96,88.08 74.36,88.68 72.95,88.68 TP8.1
N373145543: length 6.1
  TOP w0.102: U1.G24 94.49,87.14 v2(94.14,87.49)
  LAY4 w0.102: v2(98.77,85.55) 97.32,87 94.63,87 v2(94.14,87.49)
N373255127: length 4.4
  BOTTOM w0.102: R725.1 7.46,99.69 R726.2 6.78,101.46 C765.2 6.39,102.3 U79.5
N373255137: length 6.3
  BOTTOM w0.102: U79.3 4.95,105.9 6.1,107.05 6.1,108.09 C764.2 R722.2 R723.1
N373255139: length 1.2
  BOTTOM w0.102: U79.7 R724.1
N373290376: length 6.3
  TOP w0.114: TP5.1 67.81,93.56 65.32,93.56 R729.1 64.28,92.52 Q102.3
N373290440: length 5.7
  BOTTOM w0.114: R730.1 61.61,96.81 61.01,96.21 TP6.1 Q103.3
N373510936: length 3.7
  BOTTOM w0.102: U83.4 141.87,126.39 142.14,126.66 142.14,127.19 141.9,127.43 140.85,127.43 140.56,127.72 R737.2
N373510985: length 1.5
  BOTTOM w0.305: R736.2 149.85,125.69 U83.14
N373510994: length 1.8
  BOTTOM w0.305: U83.23 143.17,118.38 143.61,117.94 R742.1
N373510998: length 2
  BOTTOM w0.305: R741.1 145.71,117.57 146.42,118.29 U83.18
N373511003: length 2.2
  BOTTOM w0.305: U83.16 147.72,118.07
  BOTTOM w0.508: FB17.2 148.52,117.27 147.72,118.07
N373511700: length 1.6
  BOTTOM w0.102: R959.1 R960.2 R664.1
N373512216: length 2.1
  BOTTOM w0.102: R743.1 C620.2 U84.4
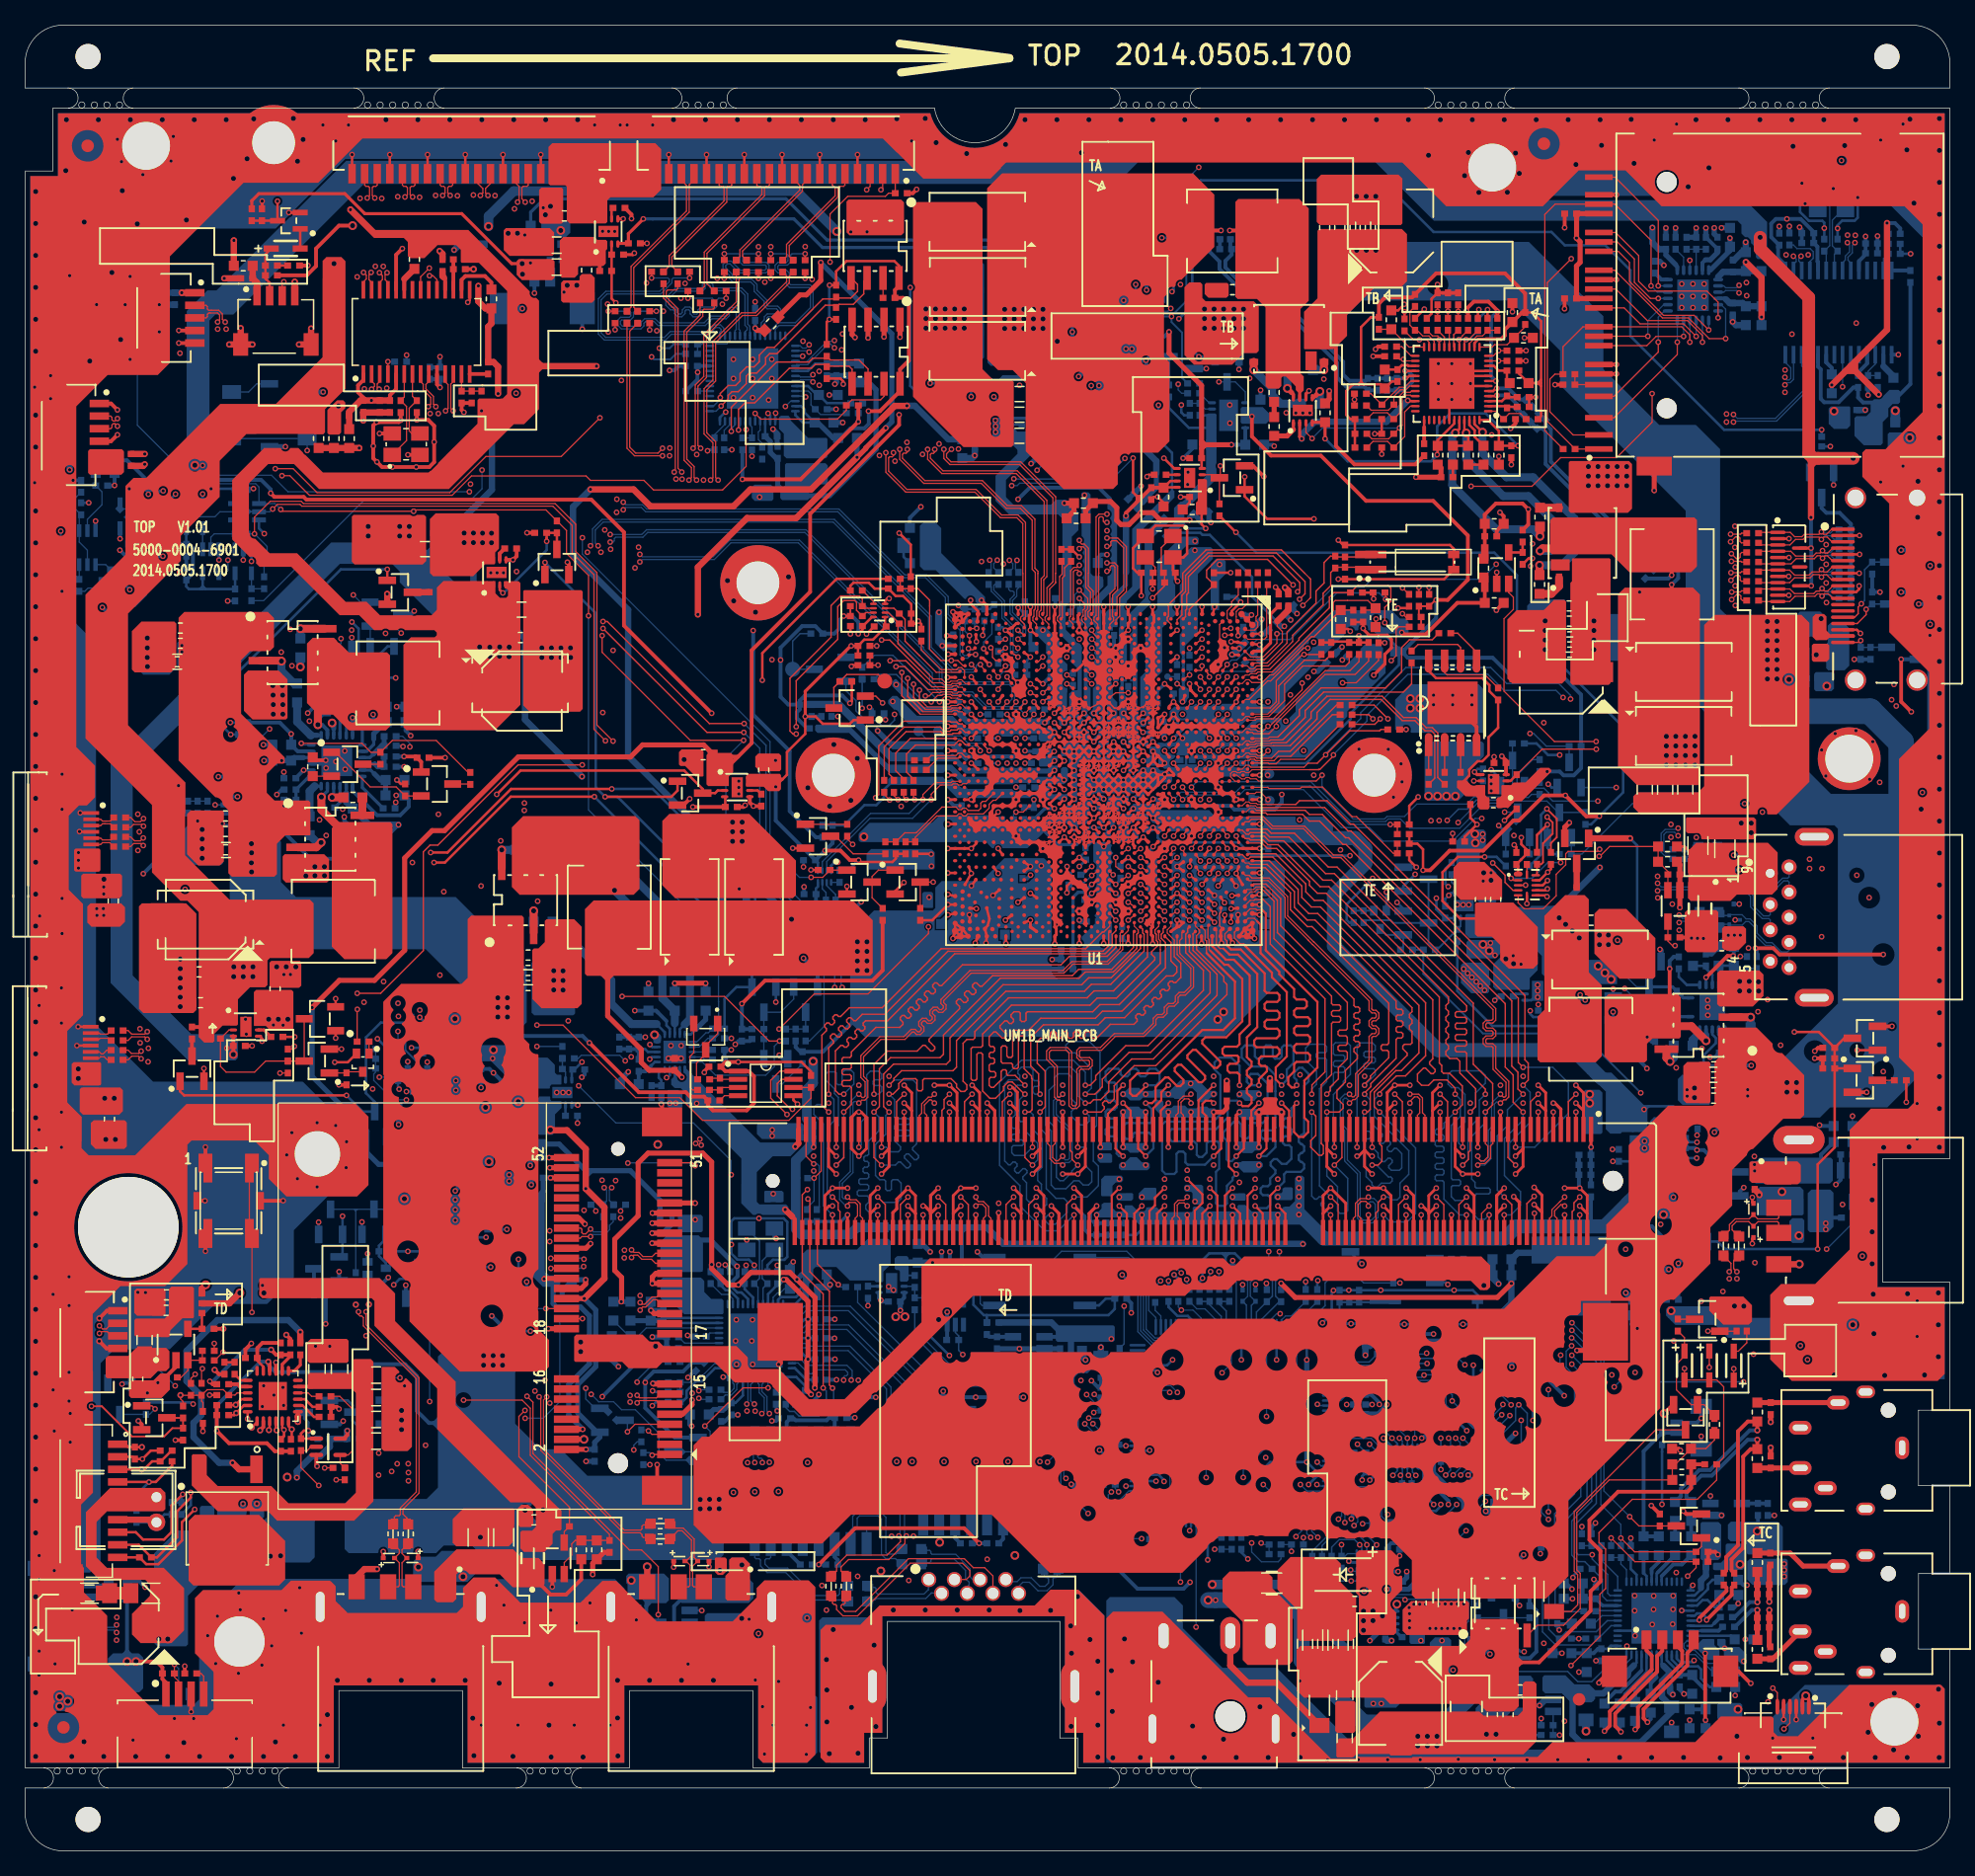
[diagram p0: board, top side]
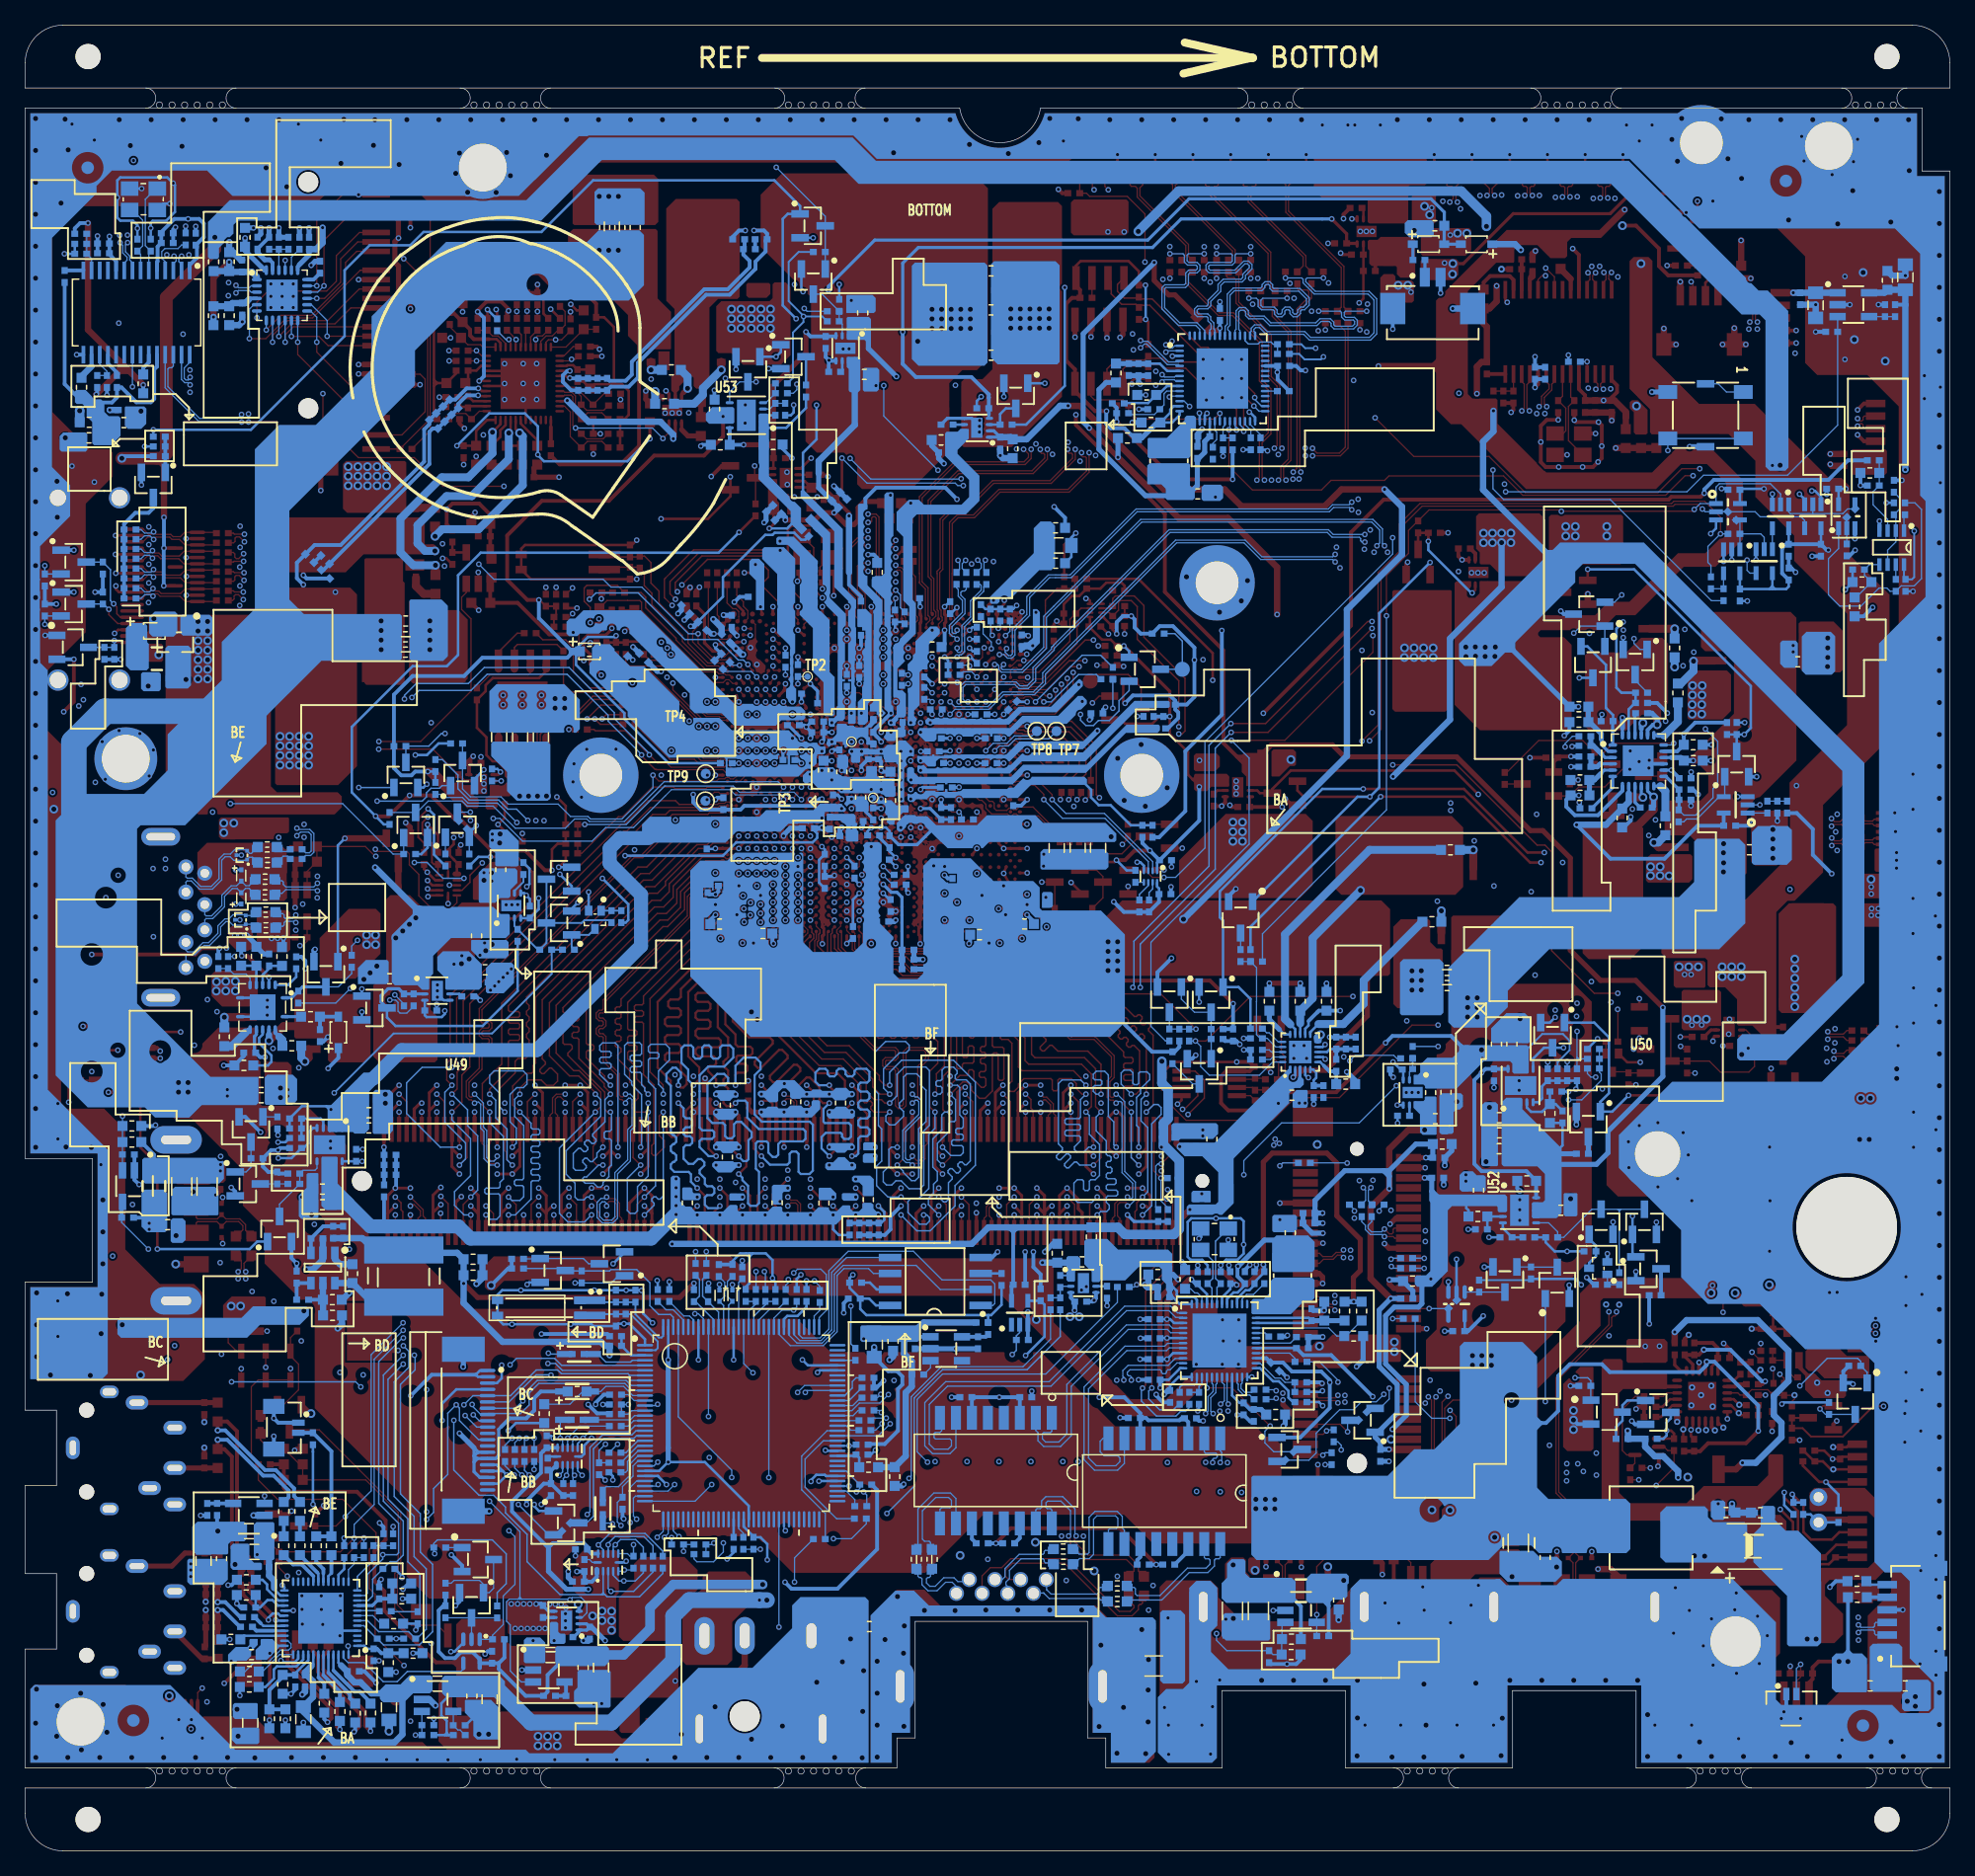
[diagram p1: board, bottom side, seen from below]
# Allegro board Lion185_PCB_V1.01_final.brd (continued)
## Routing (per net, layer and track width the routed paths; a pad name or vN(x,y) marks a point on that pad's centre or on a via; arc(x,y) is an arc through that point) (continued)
N373528412: length 3.4
  TOP w0.406: R668.1 C390.1 J7.6
N373528416: length 6.4
  TOP w0.406: J7.5 C389.1 R669.1
N373529044: length 6.8
  TOP w0.406: R680.1 137.7,23.68 C509.1 140.31,23.68 141.34,22.65 J4.5
N373529046: length 4.3
  TOP w0.406: J4.6 138.93,15.27 C508.1 137.7,15.27 R699.1
N373530772: length 1.9
  TOP w0.101: C159.2 6.8,80.4 6.15,80.4 6,80.54 CN24.5
N373530781: length 2
  TOP w0.101: CN24.2 6,82.04 6.15,81.9 6.27,81.9 6.46,81.9 6.46,81.9 6.76,81.9 C273.2
N373530783: length 2
  TOP w0.101: CN24.3 6,81.54 6.15,81.68 6.27,81.68 6.37,81.68 6.77,81.68 C274.2
N373530802: length 2
  TOP w0.101: CN24.6 6,80.04 6.15,80.18 6.73,80.18 C163.2
N373530908: length 1.8
  TOP w0.101: CN26.5 5.9,63.54 6.06,63.38 6.19,63.38 6.49,63.68 R160.2
N373530914: length 1.8
  TOP w0.101: CN26.2 5.88,65.04 5.96,64.96 6.56,64.96 C156.2
N373530916: length 1.7
  TOP w0.101: C165.2 6.67,64.62 5.94,64.62 5.86,64.54 CN26.3
N373530977: length 1.8
  TOP w0.101: CN26.6 5.88,63.04 5.99,63.15 6.28,63.15 6.53,62.91 R168.2
N373531475: length 3.3
  BOTTOM w0.102: SW4.1 17.76,116.02 18.41,116.67 SW4.5
N373533145: length 1.3
  TOP w0.102: Q89.3 131.39,42.28 R898.2
N373533207: length 21.2
  TOP w0.102: Q78.3 129.62,33.48 123.14,27 123.14,22.23 123.41,21.96 123.41,19.56 122.89,19.04 R902.1
N373533422: length 2.2
  TOP w0.102: D15.N 136.19,39.74 136.86,40.41 R904.2
N373549786: length 1.7
  TOP w0.305: R646.2 22.79,36.92 U25.11
N373549823:
  vias: v1(19.49,23.44) v1(20.31,23.47)
N373549839: length 1.6
  TOP w0.305: U25.20 17.09,36.92 16.9,37.11 R616.1
N373549953: length 1.8
  TOP w0.102: U25.10 22.5,36.42 22.77,36.15 R308.2
N373550017: length 25
  TOP w0.508: v2(16.49,30.86) 17,30.35 Q95.1 ; R605.2 v2(21.87,41.26)
  BOTTOM w0.508: v2(21.87,41.26) 20.93,42.21 15.28,42.21 12.83,39.76 12.83,37.36 13.99,36.2 13.99,34.65 13.39,34.05 13.39,32.9 15.43,30.86 v2(16.49,30.86)
N373550037: length 1.2
  TOP w0.203: R455.1 17.14,37.42 U25.19
N373550058: length 1.9
  TOP w0.254: R605.1 21.87,38.65 21.4,38.17 U25.13
N373550150: length 2.3
  TOP w1.016: C297.2 C296.1 R621.2
N373550502: length 0.8
  TOP w0.203: C727.2 15.85,38.86 R455.2
N373557456: length 7.4
  TOP w0.101: R564.2 51.26,26.02 FIL14.3 51.61,25.67 52.31,25.67 53.18,24.8 53.18,23.33 D49.N 53.06,22.64 53.06,21.1 53.16,21 CN27.2
N373557462: length 7.3
  TOP w0.101: R566.2 51.23,24.8 FIL14.2 51.89,25.45 52.22,25.45 52.97,24.71 52.97,23.47 52.54,23.05 52.54,23.05 ; 52.54,23.05 D48.N ; 52.54,23.05 52.84,22.74 52.84,21.1 52.74,21 CN27.3
N373557631: length 6.4
  TOP w0.101: R381.2 135.01,48.88 FIL12.3 135.48,49.35 135.48,49.8 135.94,50.27 137.05,50.27 D44.N 137.73,50.26 139.3,50.26 139.4,50.36 CN15.2
N373557637: length 6.1
  TOP w0.101: R568.2 136.23,48.85 FIL12.2 135.7,49.39 135.7,49.71 136.03,50.05 137.01,50.05 D45.N 137.76,50.04 139.3,50.04 139.4,49.94 CN15.3
N373557823: length 4.8
  TOP w0.101: CN28.3 29.64,21 29.74,21.1 29.74,22.91 D46.N 29.74,23.67 29.74,23.94 FIL13.4 29.25,24.43 R575.2
N373557825: length 4.8
  TOP w0.101: CN28.2 30.06,21 29.96,21.1 29.96,22.91 D47.N 30.32,23.29 29.96,23.65 29.96,23.94 FIL13.1 30.45,24.43 R382.2
N373561034: length 1.6
  TOP w0.102: U12.7 68.19,123.51 R169.1
N373561252: length 4
  BOTTOM w0.114: U10.45 56.03,120.11 55.76,119.84 55,119.84 54.84,120 53.96,120 53.79,119.82 R153.2 R152.2
N373561265: length 2.3
  BOTTOM w0.102: U10.20 58.43,112.99 58.28,112.84 58.28,112.24 58.59,111.93 R166.1
N373564935: length 1.7
  BOTTOM w0.102: U28.81 86.74,34.21 R591.1
N373564955: length 11.1
  BOTTOM w0.102: U28.79 89.25,33.41 91.27,31.4 91.27,28.71 89.39,26.83 R592.1
N373564977: length 1.9
  BOTTOM w0.102: R606.1 87.37,33.45 87.73,33.81 U28.80
N373748142: length 6.2
  BOTTOM w0.101: R623.1 66.94,19.83 FIL4.3 67.54,19.95 67.66,20.07 71.59,20.07 72.03,20.5 72.03,20.5 72.04,20.51 CN9.2
N373748155: length 6.2
  BOTTOM w0.101: R622.1 71.25,22.79 FIL3.3 71.89,22.9 72,23.01 72,23.13 72.1,23.23 73.83,23.23 74.76,22.3 74.76,21.65 75.04,21.37 75.04,21.17 74.89,21.02 CN9.4
N373748171: length 15.9
  TOP w0.101: R618.1 64.05,20.3 FIL2.2 64.18,19.7 64.28,19.6 64.4,19.6 64.5,19.5 64.5,19.19 65.01,18.69 66.17,18.69 70.36,22.88 74.51,22.88 75.1,22.29 75.1,21.87 74.81,21.58 CN9.3
N373748197: length 5.4
  BOTTOM w0.101: R603.1 82.15,22.43 FIL1.2 82.03,21.84 81.93,21.74 81.81,21.74 81.71,21.64 81.71,21.17 81.23,20.69 80.51,20.69 79.83,21.36 79.3,21.36 78.97,21.03 CN9.8
N373748211: length 5.4
  BOTTOM w0.101: R604.1 80.91,22.44 FIL1.3 81.03,21.84 81.13,21.74 81.25,21.74 81.35,21.64 81.35,21.31 81.08,21.04 80.66,21.04 79.98,21.72 79.16,21.72 78.86,21.41 78.12,21.41 CN9.7
N373748290: length 17.1
  TOP w0.101: R617.1 65.28,20.27 FIL2.3 65.18,19.7 65.08,19.6 64.96,19.6 64.86,19.5 64.86,19.34 65.16,19.04 66.02,19.04 70.22,23.23 74.66,23.23 75.37,22.52 76.28,22.52 76.93,21.87 CN9.6
N373748367: length 6.1
  BOTTOM w0.101: CN9.5 75.33,21.58 75.11,21.8 75.11,22.45 73.98,23.58 72.1,23.58 72,23.68 72,23.8 71.9,23.9 FIL3.2 71.25,24 R620.1
N373748377: length 6.3
  BOTTOM w0.101: R624.1 66.94,21.08 FIL4.2 67.54,20.95 67.64,20.85 67.64,20.55 67.77,20.42 71.45,20.42 71.76,20.73 71.8,20.78 CN9.1
N373783506: length 3.8
  TOP w0.102: R149.2 14.08,39.01 ; 14.08,39.01 14.08,39.02 U9.3 12.94,38.21 12.39,37.65 R1114.2 ; 14.08,39.01 R629.1
N373783519: length 2.4
  TOP w0.203: R389.1 14.05,41.54 C305.2 14.06,41.52 U9.4
N373937554: length 0.6
  TOP w0.305: R136.2 45.67,126.21
N373937575: length 0.9
  TOP w0.203: C135.2 46.62,130.55 U8.6
N374034613: length 4.9
  BOTTOM w0.203: R703.2 26.53,33.7 26.03,34.21 26.03,34.89 Q16.3 26.03,35.44 25.65,35.82 Q17.1
N374035248: length 4.1
  TOP w0.102: v2(10.32,35.15) 10.08,35.39 Q90.1
  BOTTOM w0.102: Q7.3 7.52,34.71 R750.2 9.89,34.71 v2(10.32,35.15)

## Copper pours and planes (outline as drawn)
3.3V_IN_1 on BOTTOM (solid shape): 149.05,116.07 149.05,115.22 148.89,115.07 148.45,115.07 148.11,114.73 148.11,114.08 147.67,113.64 147.67,111.94 147.52,111.79 146.16,111.79 145.42,112.53 145.42,113.96 145.57,114.1 146.36,114.1 146.7,114.44 146.7,115.18 146.97,115.45 147.3,115.45 147.54,115.5 147.7,115.69 147.71,115.7 148.2,116.19 148.92,116.19
+V1.0A on TOP (solid shape): outline of 83 points within 120.22,62.71 125.33,76.01
+V1.0A on BOTTOM (solid shape): 123.86,72.83 123.86,69.08 123.61,68.84 121.8,68.84 121.45,68.48 120.95,68.48 120.88,68.56 120.88,69.44 120.57,69.76 120.57,71.18 119.15,72.59 114.79,72.59 114.48,72.91 114.48,73.08 114.48,73.08 114.48,74.42 114.57,74.51 115.22,74.51 115.78,75.08 119.1,75.08 119.43,74.96 119.71,75.16 121.53,75.16
+V1.0A on LAY5 (solid shape): outline of 1948 points within 88.56,88.02 103.17,98.11
+V1.0S on TOP (solid shape): 120.25,73.47 120.25,70.52 119.88,70.16 117.93,70.16 117.25,70.84 117.25,72.03 116.58,72.7 115.44,72.7 115.25,72.9 115.25,75.32 115.35,75.42 118.3,75.42
+V1.0S on BOTTOM (solid shape): 95.43,102.57 95.43,101.56 94.91,101.04 94.91,98.68 94.24,98.68 94.24,102.35 94.66,102.76 95.24,102.76
+V1.0S on BOTTOM (solid shape): 120.24,71.1 120.24,70.04 119.61,69.42 119.61,68.57 119.52,68.48 116.91,68.48 116.91,68.49 116.7,68.7 116.7,70.51 117.73,71.54 119.8,71.54
+V1.0S on BOTTOM (solid shape): 72.9,98.71 72.9,96.47 72.94,96.43 73.03,96.34 73.14,96.28 73.15,96.27 73.29,96.13 73.63,96.13 73.63,96.05 73.98,96.05 73.98,95.3 73.74,95.3 73.73,95.33 73.5,95.53 73.19,95.5 73,95.39 72.33,96.06 72.33,98.52 72.57,98.76 72.84,98.76 72.85,98.76
+V1.0S on BOTTOM (solid shape): 93.29,104.39 93.29,103.97 93.18,103.86 92.37,103.86 91.43,102.92 91.43,101.25 91.28,100.98 91.43,100.71 91.43,99.3 91.4,99.28 91.19,98.94 91.4,98.6 91.43,98.59 91.43,98.29 90.39,97.25 90.39,93.78 89.54,92.94 89.54,91.02 89.54,90.42 89.36,90.24 88.78,90.24 88.64,90.38 88.64,93.35 89.05,93.76 89.05,97.89 89.73,98.58 89.75,98.58 89.97,98.77 89.99,99.07 89.99,99.48 89.99,99.49 90.01,99.6 89.99,99.72 89.99,99.73 89.99,100.14 89.99,100.15 90.01,100.27 89.99,100.38 89.99,100.39 89.99,100.8 89.99,100.81 90.01,100.93 89.99,101.04 89.99,101.05 89.99,101.46 89.99,101.47 90.01,101.59 89.99,101.7 89.99,101.71 89.99,102.12 89.99,102.13 90.01,102.25 89.99,102.36 89.99,102.37 89.99,102.6 91.92,104.52 93.16,104.52
+V1.0S on BOTTOM (solid shape): 71.45,90.99 74.03,90.99 74.96,90.06 75.02,90.06 75.03,90.05 75.26,90.01 75.48,90.12 75.49,90.13 75.64,90.13 75.83,90.02 76.05,90.03 76.06,90.03 76.5,90.03 76.51,90.03 76.63,90.01 76.76,90.03 76.77,90.03 76.92,90.03 76.92,90.13 77.07,90.13 77.12,90.08 77.12,90.03 77.21,90.03 77.22,90.03 77.34,90.01 77.47,90.03 77.48,90.03 77.92,90.03 77.93,90.03 78.14,90.02 78.32,90.12 78.34,90.13 78.57,90.13 78.77,90.06 78.97,90.13 79.28,90.13 79.48,90.06 79.68,90.13 79.99,90.13 80.18,90.06 80.38,90.12 80.39,90.13 80.44,90.13 80.45,90.12 80.47,90.13 80.62,90.13 80.64,90.12 80.9,90.01 81.17,90.12 81.18,90.13 81.23,90.13 81.47,89.9 81.47,89.87 81.44,89.78 81.44,89.71 81.44,89.69 81.32,89.57 74.79,89.57 73.82,90.54 71.01,90.54 68.92,92.63 68.92,92.98 69.14,93.19 69.24,93.19
+V1.0S on BOTTOM (solid shape): 82.23,96.2 82.23,95.28 82.44,95.06 82.44,95.04 82.44,94.84 82.55,94.67 82.85,94.37 82.85,93.9 82.83,93.87 82.8,93.85 82.49,93.62 82.62,93.25 82.67,93.17 82.62,93.08 82.49,92.72 82.8,92.49 82.83,92.47 82.85,92.43 82.85,92.11 82.83,92.09 82.83,90.22 82.85,90.2 82.85,89.77 82.85,89.77 82.85,89.56 82.76,89.47 82.33,89.47 82.19,89.61 82.19,89.64 82.19,89.8 82.12,89.95 82.11,89.96 82.11,90.04 82.33,90.26 82.33,90.69 81.9,91.12 81.9,93.73 81.67,93.96 81.3,93.96 81.26,94.01 81.26,94.1 81.26,94.11 81.27,94.33 81.16,94.52 81.13,94.59 81.28,94.95 81.13,95.3 81.16,95.38 81.16,95.93 80.29,96.8 80.29,97.13 80.54,97.38 81.05,97.38
+V1.0S on BOTTOM (solid shape): 70.89,90.27 73.72,90.27 74.68,89.32 74.7,89.3 81.88,89.3 81.99,89.2 81.98,89.19 81.98,89.15 82.03,89.11 82.03,89.04 82.04,89.02 82.05,88.96 82.04,88.91 82.03,88.88 82.03,88.81 81.45,88.22 80.72,88.22 80.55,88.4 80.55,88.84 79.79,88.84 79.79,88.76 79.65,88.76 79.64,88.77 79.39,88.8 79.19,88.65 79.18,88.62 79.07,88.62 79.05,88.65 78.77,88.81 78.48,88.65 78.47,88.62 77.64,88.62 77.63,88.65 77.41,88.8 77.15,88.75 77.14,88.74 77.05,88.74 77.05,88.84 76.29,88.84 76.29,88.62 76.1,88.62 76.1,88.84 75.34,88.84 75.34,88.8 75.28,88.8 75.08,88.78 74.93,88.65 74.91,88.62 74.73,88.62 74.67,88.68 74.17,89.19 74.13,89.19 73.69,89.63 73.61,89.63 73.6,89.65 73.33,89.76 73.08,89.63 70.21,89.63 69.48,90.35 69.48,90.37 69.37,90.65 69.09,90.76 69.07,90.76 69.02,90.82 68.6,91.23 68.6,91.51 68.95,91.85 69.31,91.85
+V1.0S on BOTTOM (solid shape): 94.41,103.52 94.41,102.75 93.22,101.55 93.22,99.14 93.21,99.11 93.18,98.94 93.22,98.77 93.22,98.76 93.22,96.86 92.3,95.94 92.19,95.75 92.2,95.53 92.21,95.52 92.21,95.08 92.2,95.07 92.18,94.95 92.2,94.82 92.21,94.81 92.21,94.37 92.2,94.36 92.18,94.24 92.2,94.11 92.21,94.1 92.21,93.76 92.21,93.66 92.2,93.65 92.19,93.43 92.3,93.24 92.34,93.17 92.3,93.09 92.19,92.72 92.47,92.44 92.5,92.43 92.5,91.7 92.39,91.58 92.34,91.42 92.33,91.41 92.17,91.24 91.87,91.24 91.7,91.41 91.7,92.41 91.78,92.5 91.8,92.51 91.94,92.71 91.93,92.95 91.92,92.96 91.92,93.38 91.93,93.39 91.95,93.52 91.93,93.66 91.92,93.67 91.92,94.09 91.93,94.1 91.95,94.24 91.93,94.37 91.92,94.38 91.92,94.8 91.93,94.81 91.94,95.05 91.8,95.25 91.78,95.26 91.78,96.76 91.8,96.78 91.95,97.09 91.78,97.4 91.78,98.63 91.8,98.64 91.95,98.96 91.78,99.26 91.78,100.7 91.94,100.98 91.78,101.25 91.78,102.78 92.69,103.69 94.25,103.69
+V1.0S on BOTTOM (solid shape): outline of 97 points within 67.52,86.24 82.1,89.34
+V1.0S on BOTTOM (solid shape): 86.8,107.04 86.8,100.61 85.6,99.4 85.6,99.24 85.41,98.94 85.6,98.65 85.6,98.42 85.56,98.38 85.56,91.46 85.6,91.42 85.6,91.37 85.85,91.12 85.85,90.62 85.74,90.62 85.73,90.61 85.32,90.61 85.32,90.38 85.3,90.35 85.2,90.35 85.2,90.25 85.15,90.2 84.86,90.2 84.61,90.45 84.61,90.52 84.85,90.77 84.85,90.8 84.88,90.83 84.88,92.5 84.91,92.51 85.11,92.77 84.98,93.08 84.98,93.26 85.12,93.52 84.98,93.79 84.98,94.68 85.12,94.95 84.98,95.21 84.98,95.39 85.12,95.66 84.98,95.92 84.98,96.1 85.12,96.37 84.98,96.64 84.98,96.81 85.12,97.08 84.98,97.35 84.98,97.45 84.85,97.57 84.85,99.47 86.04,100.66 86.04,101.39 86.08,101.4 86.36,101.66 86.27,102.03 86.24,102.1 86.37,102.43 86.24,102.76 86.37,103.09 86.24,103.42 86.37,103.75 86.24,104.08 86.37,104.41 86.26,104.7 86.37,104.99 86.24,105.32 86.37,105.65 86.24,105.98 86.27,106.05 86.36,106.42 86.08,106.68 86.04,106.69 86.04,107.05 86.14,107.14 86.7,107.14
+V1.0S on LAY4 (solid shape): outline of 397 points within 92.61,70.18 119.48,104.78
+V1.0S on LAY5 (solid shape): outline of 229 points within 90.36,88.92 100.5,91.44
+V1.0S on LAY5 (solid shape): outline of 2043 points within 66.45,88.57 98.74,126.43
+V1.0SX on TOP (solid shape): 117.41,77.25 117.41,75.71 117.32,75.63 114.12,75.63 114.04,75.7 114.04,75.7 113.54,76.2 113.54,78.2 113.99,78.65 116,78.65
+V1.0SX on BOTTOM (solid shape): 116.95,77.8 116.95,77.25 116.94,77.25 116.94,75.48 116.87,75.4 115.62,75.4 115.25,75.77 115.25,75.78 114.55,75.78 114.42,75.91 114.42,76.44 113.88,76.99 113.88,77.65 113.87,77.66 113.87,77.97 114.05,78.14 116.61,78.14
+V1.0SX on BOTTOM (solid shape): outline of 165 points within 66.26,79.74 83.71,82.39
+V1.0SX on BOTTOM (solid shape): outline of 91 points within 83.98,90.24 85.71,108.05
+V1.0SX on LAY3 (solid shape): 83.8,90.65 83.8,90.57 83.79,90.48 83.8,90.39 83.8,89.81 83.79,89.72 83.8,89.63 83.8,89.05 83.79,88.96 83.8,88.87 83.8,88.32 83.35,87.87 80.77,87.87 79.79,88.85 75,88.85 74.01,87.87 73.43,87.87 73.35,87.88 73.27,87.87 72.34,87.87 72.26,87.88 72.18,87.87 70.21,87.87 70.13,87.88 70.05,87.87 69.56,87.87 67.75,89.68 67.75,89.92 68.06,90.23 68.49,90.23 69.89,88.83 71.01,88.83 71.04,88.85 73.38,88.85 74.37,89.84 80.57,89.84 80.64,89.81 80.67,89.74 80.92,89.36 81.35,89.49 81.44,89.53 81.52,89.49 81.55,89.45 81.58,89.42 81.62,89.34 81.58,89.26 81.56,88.69 82.13,88.74 82.21,88.78 82.29,88.74 82.87,88.69 82.84,89.26 82.8,89.34 82.84,89.42 82.87,90 82.29,89.94 82.21,89.9 82.13,89.94 81.9,90.09 81.62,90.05 81.52,90.04 81.47,90.13 81.47,90.83 81.56,90.92 83.53,90.92
+V1.0SX on LAY4 (solid shape): outline of 3772 points within 66.15,75.76 117.21,110.16
+V1.2A on TOP (solid shape): 93.95,109.01 93.95,106.29 93.91,106.25 93.12,106.25 93.06,106.31 93.06,107.22 93.21,107.37 93.21,109.07 93.25,109.1 93.86,109.1
+V1.2A on BOTTOM (solid shape): 94.7,114.22 94.7,110.37 94.63,110.15 94.7,109.92 94.7,109.1 92.15,106.55 92.15,105.57 91.29,104.7 91.25,104.7 90.85,105.11 90.85,105.15 91.32,105.62 91.32,106.79 91.83,107.3 91.85,107.3 92.12,107.41 92.23,107.68 92.23,107.7 93.87,109.34 93.87,114.15 94.03,114.32 94.61,114.32
+V1.05S on BOTTOM (solid shape): 128.96,59.04 128.96,57.53 128.96,57.52 128.96,57.28 128.84,57.16 126.94,57.16 126.82,57.04 126.82,57.04 126,57.04 125.65,57.39 125.65,60.38 124.63,61.4 124.63,61.9 126.1,61.9
+V1.5S on BOTTOM (solid shape): 41.3,51.78 41.3,46.11 41.65,45.77 42.39,45.77 42.54,45.62 42.54,45.07 42.33,44.86 41.15,44.86 39.91,46.1 39.91,50.94 39.58,51.27 36.02,51.27 35.95,51.19 35.95,50.89 35.85,50.79 35.29,50.79 35.19,50.89 35.19,52.04 35.36,52.2 40.88,52.2
+V1.05S on BOTTOM (solid shape): outline of 175 points within 87.75,80.18 103.97,83.29
+V1.05S on LAY4 (solid shape): 87.97,83.29 88.09,83.27 88.22,83.29 88.23,83.3 89.35,83.3 89.63,83.02 89.64,83.02 89.91,82.75 89.91,82.05 89.62,81.76 88.83,81.76 88.77,81.83 87.98,81.83 87.92,81.76 85.04,81.76 85,81.77 84.96,81.77 84.7,82.03 84.7,82.21 85.01,82.52 85.08,82.53 85.15,82.57 87.11,82.57 87.13,82.56 87.55,82.6 87.67,83.01 87.67,83.04 87.92,83.3 87.96,83.3
+V1.5S_AUDIO on BOTTOM (solid shape): 111.28,18.12 111.28,16.54 111.19,16.45 110.16,16.45 110.04,16.57 110.04,17.21 110.11,17.27 110.47,17.27 110.62,17.42 110.62,18.08 110.75,18.21 111.18,18.21
+V1.8A on TOP (solid shape): 56.29,87.14 56.29,85.8 55.94,85.45 55.94,84.71 55.91,84.68 54.3,84.68 54.16,84.82 54.16,87.14 54.34,87.32 56.11,87.32
+V1.8A on TOP (solid shape): 121.32,85.96 121.32,85.82 118.96,83.46 118.41,83.46 118.24,83.29 118.16,83.29 118.16,83.21 117.87,82.92 117.82,82.92 117.81,82.93 117.6,82.99 117.39,82.92 117.06,82.92 116.95,83.03 116.95,83.67 117.09,83.8 117.23,83.8 117.32,83.89 117.33,83.89 117.33,83.9 117.35,83.92 117.35,84.71 117.41,84.76 118.12,84.76 118.32,84.97 119.26,84.97 120.43,86.14 121.15,86.14
+V1.8A on BOTTOM (solid shape): 98.89,114.31 98.89,113.75 98.63,113.5 96.73,113.5 96.63,113.6 96.63,114.71 96.74,114.83 98.38,114.83
+V1.8A on BOTTOM (solid shape): 35.63,59.54 35.63,58.42 35.64,58.41 35.64,56.96 35.63,56.95 35.63,54.6 35.47,54.43 32.79,54.43 32.19,53.84 32.19,51.76 32.36,51.59 33.14,51.59 33.23,51.49 33.23,50.41 33.13,50.31 31.27,50.31 30.86,50.72 30.86,55.87 33.98,58.98 33.98,59.8 34.07,59.9 35.27,59.9
+V1.8A on BOTTOM (solid shape): outline of 94 points within 86.94,89.64 91.36,108.2
+V1.8A_SPI on TOP (solid shape): 114.94,84.77 114.97,84.77 114.98,84.76 115.16,84.72 115.34,84.76 115.35,84.77 116.04,84.77 116.07,84.74 116.07,83.96 116.13,83.9 116.13,83.89 116.14,83.89 116.23,83.8 116.34,83.8 116.41,83.73 116.41,82.94 116.29,82.82 115.66,82.82 115.44,83.03 115.44,83.74 115.31,83.86 114.51,83.86 113.83,84.55 113.83,85.09 113.86,85.13 114.58,85.13
+V1.8S on TOP (solid shape): 60.08,85.56 60.08,84.43 59.93,84.27 59.06,84.27 58.7,84.63 57.34,84.63 57.29,84.68 57.29,85.46 57.48,85.66 59.98,85.66
+V1.35_CRT on BOTTOM (solid shape): 72.82,105.19 72.82,103.21 76.3,99.73 76.3,99.28 76.2,99.18 75.7,99.18 75.53,99.35 75.29,99.82 74.81,99.62 74.74,99.56 74.65,99.59 72.39,101.85 71.43,101.85 71.12,102.16 71.12,105.39 71.46,105.72 72.29,105.72
+V1.35S on BOTTOM (solid shape): outline of 89 points within 77.14,89.47 84.43,113.09
+V3.3A on TOP (solid shape): outline of 547 points within 4.79,64.28 25.46,126.76
+V3.3A on TOP (solid shape): outline of 721 points within 43.64,34.56 116.46,47.28
+V3.3A on BOTTOM (solid shape): 150.27,112.51 150.27,111.45 150.1,111.28 148.19,111.28 148.06,111.41 148.06,112.67 148.2,112.81 149.97,112.81
+V3.3A on BOTTOM (solid shape): 70.23,47.18 70.23,45.41 70.08,45.27 69.61,45.27 69.53,45.34 69.53,46.09 69.43,46.19 69.24,46.19 69.12,46.32 69.12,47.11 69.31,47.3 70.1,47.3
+V3.3A on BOTTOM (solid shape): 135.8,42.39 145.46,42.39 145.67,42.18 145.67,41.09 145.38,40.81 135.36,40.81 134.33,41.83 131.17,41.83 130.44,42.56 130.44,43.1 130.66,43.31 134.88,43.31
+V3.3A on BOTTOM (solid shape): 39.54,63.08 41.54,63.08 42.11,62.51 42.11,61.9 42.28,61.72 42.58,61.72 42.63,61.67 42.63,60.97 42.6,60.95 41.85,60.95 41.71,60.81 41.71,60.67 41.67,60.62 39.21,60.62 37.44,62.39 34.96,62.8 34.78,62.62 34.78,61.94 34.65,61.81 33.56,61.81 33.47,61.9 33.47,63.92 33.63,64.08 38.54,64.08
+V3.3A on LAY3 (solid shape): outline of 254 points within 49.72,39.75 72.98,42.62
+V3.3A on LAY4 (solid shape): 116.77,44.95 116.86,44.82 116.99,44.74 117.44,44.29 126.85,44.29 126.88,44.25 127.08,44.04 127.37,44.03 130.67,44.03 131.21,43.49 131.21,42.67 131.05,42.52 130.71,42.52 130.69,42.54 123.93,42.54 123.59,42.88 117.07,42.88 115.46,44.49 115.46,45.12 115.76,45.42 116.31,45.42
+V3.3A on LAY5 (solid shape): outline of 2066 points within 16.17,39.07 44.55,71.3
+V3.3A_KBC on BOTTOM (solid shape): 86.61,41.69 86.61,40.61 86.48,40.48 82.05,40.48 82.01,40.52 82.01,40.52 81.92,40.62 81.92,41.63 82.08,41.79 86.51,41.79
+V3.3A_SOC on BOTTOM (solid shape): outline of 558 points within 90.99,89.48 109.97,98.66
+V3.3A_SOC on LAY3 (solid shape): outline of 321 points within 89.82,87.06 92.06,91.01
+V3.3A_WIFI on BOTTOM (solid shape): 41.74,59.96 41.74,59.74 41.85,59.63 42.6,59.63 42.64,59.59 42.64,59.09 42.12,58.58 42.12,57.15 41.92,56.95 40.86,56.95 40.8,57 40.8,59.92 40.88,60 41.7,60
+V3.3S on TOP (solid shape): 42.09,126.42 42.09,125.11 41.89,124.92 39.49,124.92 39.07,125.34 39.07,126.43 39.25,126.61 41.9,126.61
+V3.3S on TOP (solid shape): 21.32,68.33 21.32,65.42 21.16,65.26 19.48,65.26 19.13,65.6 18.21,65.6 18.18,65.64 18.18,68.3 18.35,68.47 21.18,68.47
+V3.3S on BOTTOM (solid shape): 9.38,15.38 9.38,12.92 9.07,12.61 6.66,12.61 6.58,12.68 6.58,15.3 6.98,15.71 9.05,15.71
+V3.3S on BOTTOM (solid shape): 110.87,16.14 110.87,14.96 110.59,14.69 106.9,14.69 106.59,15 106.59,16.11 106.76,16.28 110.73,16.28
+V3.3S on BOTTOM (solid shape): 113.16,131.28 116.03,131.28 116.62,131.22 117.21,131.28 136.73,131.28 138.47,129.55 138.47,126.75 138.32,126.59 137.72,126.59 137.6,126.71 137.6,126.99 137.6,126.99 137.6,127.47 137.19,127.88 137.19,128.09 136.94,128.34 136.73,128.34 136.44,128.63 136.44,129.32 136.11,129.64 111.99,129.64 107.16,134.47 88.64,134.47 86.74,132.57 26.94,132.57 16.55,122.18 15.12,122.18 14.66,121.72 14.66,110.08 14.33,109.76 13.07,109.76 12.83,110.01 12.83,121.72 12.85,121.74 12.85,122.47 14.48,124.1 15.21,124.1 15.79,124.68 15.81,124.68 16.09,124.79 16.2,125.07 16.2,125.09 21.03,129.93 21.05,129.93 21.23,130.03 21.33,130.21 21.33,130.22 25.52,134.41 85.37,134.41 87.23,136.27 108.17,136.27
+V3.3S on LAY5 (solid shape): outline of 6369 points within 7.24,14.66 67.61,126.66
+V3.3S_AUDIO on BOTTOM (solid shape): 113.36,16.76 113.36,15.04 113.24,14.93 111.74,14.93 111.65,15.01 111.65,16.57 112.07,16.98 113.14,16.98
+V3.3S_AUDIO on BOTTOM (solid shape): 134.28,16.8 134.28,16.38 134.68,15.98 134.68,15.24 134.63,15.18 133.79,15.18 132.82,16.15 132.82,16.35 132.84,16.35 133.34,16.84 134.24,16.84
+V5_AVDD on BOTTOM (solid shape): 134.83,25.93 134.83,23.36 134.59,23.12 133.28,23.12 133.19,23.22 133.19,23.71 133.19,26.05 133.29,26.15 134.61,26.15
+V5_PVDD on BOTTOM (solid shape): 123.16,13.24 124.34,13.24 124.8,12.78 124.8,12.08 124.53,11.81 122.87,11.81 122.17,12.51 122.17,12.53 120.83,12.53 120.61,12.74 120.61,13.8 120.61,13.8 120.77,13.96 122.44,13.96
+V5A on TOP (solid shape): 134.6,74.66 134.6,71.7 134.36,71.47 132.13,71.47 131.93,71.67 131.93,74.63 132.12,74.82 134.44,74.82
+V5A on TOP (solid shape): 29.41,44.33 29.41,42.13 34.23,37.31 34.23,35.44 42.63,27.04 42.63,25.57 42.53,25.47 42.18,25.47 42.18,25.46 41.93,25.21 41.93,24.42 41.28,23.78 39.65,23.78 39.36,24.06 39.36,25.33 39.48,25.46 40.29,25.46 40.59,25.76 40.59,27.25 40.59,27.3 40.18,27.71 38.57,27.71 32.75,33.54 32.75,36.77 28.87,40.65 28.55,40.97 27.76,41.76 27.76,43.73 27.54,43.95 18.85,43.95 18.6,44.2 18.6,45.46 18.7,45.56 28.18,45.56
+V5A on TOP (solid shape): outline of 300 points within 16.45,89.11 40.85,130.79
+V5A on BOTTOM (solid shape): 143.75,52.33 143.75,49.64 143.31,49.2 141.88,49.2 141.71,49.37 141.71,52.31 141.99,52.59 143.49,52.59
+V5A on BOTTOM (solid shape): 51.18,21.65 51.18,19.94 50.94,19.7 49.33,19.7 49.05,19.98 48.16,19.98 47.89,20.25 47.89,21.18 47.79,21.28 47.78,21.28 47.78,21.86 47.95,22.03 47.95,22.05 50.78,22.05
+V5A on BOTTOM (solid shape): 39.02,96.02 39.02,94.67 38.58,94.23 36.42,94.23 29.78,100.88 29.78,101.75 29.17,102.36 25.02,102.36 8.55,85.89 8.55,69.62 13.21,64.95 16.5,64.95 16.91,64.55 16.91,63.06 16.71,62.86 12.96,62.86 6.79,69.03 6.79,86.53 24.33,104.06 30.98,104.06
+V5A on LAY4 (solid shape): 19.5,61.49 19.5,44.23 19.25,43.98 18.55,43.98 18.15,44.38 18.15,60.34 15.34,63.14 15.34,64.18 15.43,64.27 16.72,64.27
+V5A on LAY4 (solid shape): outline of 492 points within 49.93,41.72 70.57,57.61
+V5A on LAY5 (solid shape): outline of 1274 points within 33.79,55.82 61.5,96.14
+V5A on LAY5 (solid shape): outline of 2904 points within 68.57,19.98 143.4,72.97
+V5S on TOP (solid shape): 7.7,77.55 7.7,75.96 7.49,75.75 4.62,75.75 4.45,75.92 4.45,77.56 4.6,77.71 7.54,77.71
+V5S on TOP (solid shape): 7.77,60.5 7.77,58.83 7.49,58.55 4.58,58.55 4.34,58.8 4.34,60.57 4.48,60.72 7.55,60.72
+V5S on TOP (solid shape): 42.05,128.71 42.05,126.99 41.9,126.84 38.51,126.84 38.04,127.31 38.04,128.89 38.21,129.06 41.7,129.06
+V5S on TOP (solid shape): 37.67,106.13 37.67,103.57 37.37,103.27 37.37,102.39 37.29,102.31 36.55,102.31 35.61,101.38 32.43,101.38 32.18,101.63 32.18,101.99 32.17,101.99 32.17,105.92 32.63,106.38 37.42,106.38
+V5S on BOTTOM (solid shape): 141.86,95.64 141.86,92.56 141.74,92.44 140.07,92.44 139.81,92.7 139.81,95.64 140.02,95.85 141.65,95.85
+V5S on BOTTOM (solid shape): 3.53,13.48 3.53,12.71 3.8,12.44 3.8,11.31 3.61,11.11 1.71,11.11 1.51,11.31 1.51,13.38 1.74,13.61 3.4,13.61
+V5S on BOTTOM (solid shape): 119.87,13.71 119.87,12.55 119.53,12.21 115.19,12.21 114.86,12.54 114.86,12.97 114.86,12.97 114.86,13.48 115.31,13.93 119.65,13.93
+V5S on BOTTOM (solid shape): 139.72,25.77 139.72,23.91 139.39,23.58 136.94,23.58 136.86,23.66 136.86,24.39 136.64,24.61 135.58,24.61 135.36,24.83 135.36,25.95 135.59,26.18 139.31,26.18
+V5S on LAY3 (solid shape): 82.51,24.46 86.24,24.46 90.07,20.63 94.19,20.63 94.2,20.63 94.43,20.63 94.94,20.12 94.94,19.42 94.66,19.14 89.48,19.14 85.43,23.19 81.75,23.19 78.26,26.68 66.56,26.68 63.01,23.14 62.82,23.04 62.72,22.85 61.66,21.79 61.66,17.04 59.59,14.96 56.32,14.96 56.05,15.23 52.76,15.23 52.69,15.23 52.63,15.23 23.76,15.23 19.97,11.44 5.36,11.44 4.83,10.9 2.45,10.9 2.34,11.01 2.34,11.23 2.34,11.24 2.34,12.65 2.53,12.85 18.71,12.85 22.81,16.94 56.79,16.94 57.1,16.63 58.98,16.63 60.21,17.86 60.21,22.26 60.21,22.26 60.21,22.37 66.04,28.2 78.76,28.2
+V5S on LAY5 (solid shape): outline of 4817 points within 1.61,10.96 40,129.67
+V5S_HDMI on TOP (solid shape): 143.2,98.17 143.2,97.05 143.47,96.77 145.36,96.77 145.45,96.68 145.45,96.55 145.37,96.47 143.4,96.47 143.22,96.29 142.57,96.29 142.56,96.28 142.35,96.28 142.09,96.54 142.09,98.13 142.33,98.37 142.99,98.37
+V5S_HDMI on BOTTOM (solid shape): 143.14,98.12 143.14,96.84 142.88,96.57 141.19,96.57 140.9,96.86 140.9,98.38 141.09,98.56 142.7,98.56
AGND on BOTTOM (solid shape): 136.5,11.61 136.5,10.65 136.33,10.48 134.57,10.48 134.57,10.49 134.51,10.54 134.51,11.67 134.6,11.76 136.35,11.76
AGND on BOTTOM (solid shape): 136.68,24.23 136.68,22.53 136.49,22.34 134.25,22.34 134.18,22.41 134.18,22.83 134.26,22.92 134.8,22.92 135.18,23.29 135.18,24.33 135.28,24.44 136.47,24.44
AGND on LAY2 (solid shape): outline of 1834 points within 125.33,13.58 152.59,37.22
AGND on LAY5 (solid shape): outline of 1515 points within 125.75,9.33 152.59,37.22
GND on TOP (solid shape): 5.98,79.6 5.98,77.99 5.88,77.88 4,77.88 3.89,77.99 3.89,79.61 3.99,79.71 5.88,79.71
GND on TOP (solid shape): 7.94,75.05 7.94,73.9 7.53,73.49 5.27,73.49 4.93,73.83 4.93,75.1 5.2,75.37 7.62,75.37
GND on TOP (solid shape): 21.95,70.67 21.95,68.81 21.77,68.64 19.52,68.64 19.42,68.73 19.42,70.64 19.57,70.78 21.84,70.78
GND on TOP (solid shape): 40.39,27.13 40.39,25.94 40.21,25.76 39.33,25.76 39.14,25.95 39.14,27.22 39.44,27.52 40,27.52
GND on TOP (solid shape): 44.32,100.16 44.32,90.81 44.11,90.6 40.1,90.6 39.59,91.11 39.59,100.19 39.67,100.27 44.22,100.27
GND on TOP (solid shape): 60.1,87.1 60.1,86 59.97,85.86 58.39,85.86 58.04,86.22 58.04,87.03 58.28,87.28 59.93,87.28
GND on TOP (solid shape): 69.87,131.1 69.87,128.71 69.65,128.48 65.53,128.48 65.29,128.72 65.29,131.17 65.45,131.33 69.63,131.33
GND on TOP (solid shape): 143.41,95.88 143.41,94.78 143.2,94.57 142.15,94.57 142.03,94.69 142.03,95.87 142.17,96.01 143.28,96.01
GND on TOP (solid shape): 25.71,40.58 25.71,38.93 25.6,38.82 22.58,38.82 22.44,38.95 22.44,40.46 22.7,40.72 25.56,40.72
GND on TOP (solid shape): 38.88,27.15 38.88,24.66 38.44,24.22 34.26,24.22 33.98,24.5 33.98,26.39 34.84,27.24 38.79,27.24
GND on TOP (solid shape): 109.48,133 109.48,129.43 109.36,129.3 102.92,129.3 102.67,129.55 102.67,132.96 103.02,133.31 109.17,133.31
GND on TOP (solid shape): 8.09,57.93 8.09,56.02 7.89,55.83 5.58,55.83 5.22,56.19 5.22,57.88 5.44,58.1 7.91,58.1
GND on TOP (solid shape): 12.01,97.61 12.01,94.15 11.59,93.72 8.71,93.72 8.48,93.95 8.48,97 9.25,97.77 11.85,97.77
GND on TOP (solid shape): 13.61,74.54 13.61,66.87 13.37,66.63 9.39,66.63 9.04,66.98 9.04,75.12 9.28,75.36 12.79,75.36
GND on TOP (solid shape): 42.77,132.15 42.77,129.54 42.64,129.41 41,129.41 40.85,129.56 40.85,132.09 41.04,132.28 42.65,132.28
GND on TOP (solid shape): 55.1,23.33 55.65,23.33 55.78,23.2 55.78,22.26 55.46,21.94 55.07,21.94 54.83,22.18 54.83,23.25 54.91,23.33 55.1,23.33
GND on TOP (solid shape): 133.97,62.67 133.97,59.57 133.87,59.46 132.05,59.46 131.81,59.7 131.81,62.43 132.12,62.74 133.9,62.74
GND on TOP (solid shape): 136.8,73.33 136.8,72.22 136.23,71.65 135.07,71.65 134.9,71.82 134.9,73.36 135.07,73.53 136.6,73.53
GND on TOP (solid shape): 6.04,62.64 6.04,60.95 5.96,60.88 3.92,60.88 3.7,61.09 3.7,62.58 3.85,62.72 5.95,62.72
GND on TOP (solid shape): 25.45,115.19 25.45,114.74 25.12,114.41 25.12,112.8 24.96,112.63 24.14,112.63 24.02,112.75 24.02,114.59 24.8,115.37 25.28,115.37
GND on TOP (solid shape): 137.27,43.4 137.27,42.1 137.02,41.85 134.98,41.85 133.87,42.95 133.87,43.99 133.97,44.09 136.58,44.09
GND on TOP (solid shape): 44.24,73.49 44.24,67.36 43.9,67.02 41.04,67.02 40.32,67.74 40.32,71.65 40.44,71.77 40.8,71.77 41.3,72.28 41.3,73.95 41.44,74.09 43.65,74.09
GND on TOP (solid shape): 61.27,78.76 61.27,76 61.03,75.76 51.67,75.76 50.65,76.78 50.65,81.91 51.21,82.47 57.56,82.47
GND on TOP (solid shape): 122.5,99.36 122.5,93.16 122.17,92.83 118.21,92.83 117.82,93.23 117.82,97.93 118.57,98.68 120.72,98.68 121.53,99.49 122.36,99.49
GND on TOP (solid shape): 127.74,110.29 127.74,106.74 127.41,106.41 122.85,106.41 122.7,106.56 122.7,110.2 122.7,110.2 122.7,110.42 122.82,110.54 127.49,110.54
GND on TOP (solid shape): 15.8,82.62 15.8,78.69 15.47,78.36 13.76,78.36 12.86,79.26 12.86,82.46 13.16,82.75 15.67,82.75
GND on TOP (solid shape): 20.86,93.16 20.86,90.1 20.73,89.97 18.08,89.97 17.39,90.66 17.39,93.55 17.72,93.87 20.14,93.87
GND on TOP (solid shape): 24.16,78.88 24.16,77.18 23.99,77.01 20.73,77.01 20.47,77.27 20.47,79.11 20.63,79.27 23.77,79.27
GND on TOP (solid shape): 53.93,87.44 53.93,85.49 53.88,85.44 53.3,85.44 52.46,86.28 52.09,86.28 52.09,86.28 51.97,86.4 51.97,87.39 52.18,87.6 53.77,87.6
GND on TOP (solid shape): 114.78,19.72 114.78,18.47 114.62,18.31 114.62,17.32 114.46,17.16 109.83,17.16 109.5,17.5 109.5,19.19 110.18,19.87 114.63,19.87
GND on TOP (solid shape): 138.19,69.69 138.19,67.99 137.35,67.15 134.69,67.15 134.5,67.34 134.5,69.81 134.71,70.02 137.86,70.02
GND on TOP (solid shape): 11.5,37.86 11.5,36.67 10.84,36.01 8.42,36.01 8.25,36.19 8.25,37.26 8.42,37.42 10.2,37.42 10.74,37.96 11.4,37.96
GND on TOP (solid shape): 45.28,125.12 45.28,123.35 45.06,123.13 42.76,123.13 42.61,123.28 42.61,124.72 42.79,124.9 44.03,124.9 44.07,124.95 44.07,125.23 44.25,125.41 44.99,125.41
GND on TOP (solid shape): 11.16,44.62 11.16,43.66 11.15,43.66 11.15,42.69 11.02,42.55 8.91,42.55 8.67,42.79 8.67,44.54 8.85,44.72 11.06,44.72
GND on TOP (solid shape): 30.63,106.26 30.88,106.16 31.14,106.26 31.71,106.26 31.88,106.09 31.88,102.57 31.87,102.57 31.61,102.31 26.19,102.31 25.97,102.52 25.97,106.12 26.11,106.26
GND on TOP (solid shape): 120.14,13.29 120.14,8.71 119.1,7.67 110.27,7.67 110.19,7.6 108.54,7.6 108.45,7.69 108.45,7.7 105.83,7.7 105.56,7.44 104.32,7.44 104.23,7.53 104.23,8.71 104.46,8.95 105.57,8.95 107.7,11.08 115.6,11.08 115.93,10.75 118.65,10.75 119.05,11.15 119.05,13.29 119.24,13.48 119.95,13.48
GND on TOP (solid shape): 137.6,82.01 137.6,80.65 137.39,80.45 133.32,80.45 133.25,80.48 133.22,80.56 133.06,80.91 132.68,80.94 132.15,80.94 132.02,81.06 132.02,82.12 132.1,82.2 137.42,82.2
GND on TOP (solid shape): 29.72,38.15 29.75,38.06 29.68,37.98 29.53,37.36 30.16,37.51 30.23,37.58 30.33,37.55 30.75,37.13 30.75,32.13 30.41,31.79 28.52,31.79 28.33,31.98 28.33,38.44 28.38,38.49 29.38,38.49
GND on TOP (solid shape): 127.76,74.44 127.76,74.43 129.6,72.59 129.6,69.53 129.42,69.36 126.74,69.36 124.75,71.35 124.75,72.4 126.21,72.4 126.21,72.35 126.23,72.3 126.25,72.24 126.28,72.2 126.31,72.16 126.35,72.12 126.4,72.09 126.45,72.06 126.5,72.05 126.56,72.04 126.61,72.04 126.67,72.05 126.72,72.06 126.77,72.09 126.82,72.12 126.86,72.16 126.89,72.2 126.92,72.24 126.94,72.3 126.96,72.35 126.96,72.4 126.96,72.46 126.95,72.51 126.93,72.57 126.91,72.62 126.88,72.66 126.84,72.7 126.79,72.73 126.75,72.76 126.69,72.78 126.64,72.79 126.59,72.8 126.53,72.79 126.48,72.78 126.42,72.76 126.38,72.73 126.33,72.7 126.29,72.66 126.26,72.62 126.24,72.57 126.22,72.51 126.21,72.46 126.21,72.4 124.75,72.4 124.75,74.55 125.12,74.92 127.28,74.92
GND on TOP (solid shape): 93.58,124.59 93.58,123.5 93.84,123.24 97.67,123.24 98.06,122.85 98.06,119.29 97.89,119.11 96.86,119.11 95.94,118.19 92.91,118.19 92.29,118.81 92.93,118.81 92.93,118.76 92.95,118.71 92.97,118.66 93,118.61 93.03,118.57 93.08,118.53 93.12,118.5 93.17,118.48 93.23,118.46 93.28,118.45 93.34,118.45 93.39,118.46 93.44,118.48 93.49,118.5 93.54,118.53 93.58,118.57 93.62,118.61 93.64,118.66 93.67,118.71 93.68,118.76 93.69,118.81 93.68,118.87 93.67,118.92 93.66,118.98 93.63,119.03 93.6,119.07 93.56,119.11 93.52,119.14 93.47,119.17 93.42,119.19 93.36,119.2 93.31,119.21 93.25,119.2 93.2,119.19 93.15,119.17 93.1,119.14 93.05,119.11 93.02,119.07 92.98,119.03 92.96,118.98 92.94,118.92 92.93,118.87 92.93,118.81 92.29,118.81 92.15,118.95 92.15,124.35 92.54,124.74 93.43,124.74
GND on TOP (solid shape): outline of 114 points within 85.95,7.01 152.59,19.02
GND on TOP (solid shape): outline of 149 points within 127.83,82.42 141.83,98.3
GND on TOP (solid shape): outline of 162 points within 105.8,17.16 109.47,23.9
GND on TOP (solid shape): outline of 252 points within 70.58,111.64 78.59,131.13
GND on TOP (solid shape): outline of 134 points within 91.59,83.3 96.53,87.8
GND on TOP (solid shape): outline of 1184 points within 74.95,86.73 84.59,92.16
GND on TOP (solid shape): outline of 1537 points within 0.41,7.01 152.59,138.19
GND on TOP (solid shape): outline of 7952 points within 74.88,73.46 96.83,97.37
GND on BOTTOM (solid shape): 19,27.73 19,26.57 18.75,26.32 18.01,26.32 17.85,26.48 17.85,27.71 18,27.87 18.86,27.87
GND on BOTTOM (solid shape): 43.34,129.45 43.34,128.69 42.98,128.33 41.22,128.33 41.03,128.52 41.03,129.5 41.22,129.69 43.1,129.69
GND on BOTTOM (solid shape): 52.25,60.19 52.25,59.16 52.18,59.09 51.18,59.09 51.04,59.22 51.04,60.44 51.12,60.52 51.92,60.52
GND on BOTTOM (solid shape): 72.3,79.42 72.3,78.15 72.19,78.04 67.08,78.04 66.88,78.24 66.88,79.32 67.24,79.68 72.05,79.68
GND on BOTTOM (solid shape): 87.73,123.67 87.73,122.34 87.69,122.3 85.54,122.3 85.39,122.45 85.39,123.49 85.64,123.74 87.66,123.74
GND on BOTTOM (solid shape): 89.91,52.69 89.91,51.82 89.84,51.75 88.65,51.75 88.52,51.88 88.52,52.29 88.97,52.74 89.86,52.74
GND on BOTTOM (solid shape): 126.55,70.22 126.55,68.93 126.54,68.93 124.26,68.93 124.1,69.09 124.1,70.73 124.23,70.86 125.91,70.86
GND on BOTTOM (solid shape): 140.67,98.16 140.67,96.86 140.46,96.64 138.32,96.64 138.02,96.95 138.02,97.99 138.34,98.31 140.52,98.31
GND on BOTTOM (solid shape): 141.43,50.15 141.43,48.49 141.3,48.35 140.48,48.35 140.25,48.59 140.25,50.08 140.48,50.31 141.27,50.31
GND on BOTTOM (solid shape): 53.87,50.45 53.87,49.3 53.76,49.2 52.11,49.2 51.89,49.42 51.89,50.45 52.03,50.58 53.73,50.58
GND on BOTTOM (solid shape): 57.89,18.65 57.89,17.07 57.54,16.72 54.15,16.72 54.03,16.85 54.03,18.71 54.22,18.9 54.22,18.9 57.63,18.9
GND on BOTTOM (solid shape): 60.29,52.36 60.29,51.64 60.24,51.59 58.79,51.59 58.76,51.62 58.76,52.44 58.81,52.49 60.16,52.49
GND on BOTTOM (solid shape): 125.38,60.31 125.38,57.12 125.28,57.02 124.03,57.02 123.75,57.29 123.75,60.26 124.02,60.53 125.16,60.53
GND on BOTTOM (solid shape): 30.7,52.23 30.7,50.6 30.57,50.46 29.71,50.46 29.6,50.57 29.6,52.24 29.67,52.32 30.62,52.32
GND on BOTTOM (solid shape): 59.49,108.46 59.49,107.5 59.35,107.36 58,107.36 57.76,107.6 57.76,108.46 57.96,108.65 59.29,108.65
GND on BOTTOM (solid shape): 72.17,76.15 72.17,75.04 72.14,75 71.44,75 71.31,75.13 71.31,76.14 71.43,76.26 72.07,76.26
GND on BOTTOM (solid shape): 76.23,126.17 76.23,118.76 75.69,118.22 70.96,118.22 70.77,118.41 70.77,126.1 71.09,126.42 75.98,126.42
GND on BOTTOM (solid shape): 86.41,117.81 86.41,116.17 86.3,116.06 85.29,116.06 85.13,116.22 85.13,116.67 85.11,116.69 85.11,117.79 85.27,117.95 86.26,117.95
GND on BOTTOM (solid shape): 116.38,70.21 116.38,68.33 116.25,68.2 114.96,68.2 114.13,69.03 114.13,70.43 114.35,70.65 115.94,70.65
GND on BOTTOM (solid shape): 133.95,61.52 133.95,59.43 133.86,59.33 131.75,59.33 131.38,59.7 131.38,61.39 131.72,61.73 133.74,61.73
GND on BOTTOM (solid shape): 143.79,93.61 143.79,92.43 143.59,92.23 142.35,92.23 142.22,92.37 142.22,93.61 142.35,93.74 143.65,93.74
GND on BOTTOM (solid shape): 36.47,65.42 36.47,64.39 36.31,64.24 33.5,64.24 33.38,64.35 33.38,66.23 33.78,66.62 35.26,66.62
GND on BOTTOM (solid shape): 37.25,59.27 37.25,54.56 37.14,54.45 35.99,54.45 35.92,54.52 35.92,59.36 36.11,59.55 36.97,59.55
GND on BOTTOM (solid shape): 109.1,14.23 109.1,12.98 109.37,12.71 109.37,11.78 108.97,11.39 106.56,11.39 106.46,11.49 106.46,14.24 106.61,14.39 108.94,14.39
GND on BOTTOM (solid shape): 117.53,71.61 116.9,70.98 114.8,70.98 114.78,71 114.57,71.21 114.57,72.27 114.73,72.43 114.73,72.44 117.53,72.44
GND on BOTTOM (solid shape): 141.38,52.54 141.38,50.64 141.28,50.55 137.71,50.55 137.63,50.62 137.63,52.53 137.92,52.81 141.1,52.81
GND on BOTTOM (solid shape): 15.75,81.01 15.75,78.58 15.59,78.42 12.95,78.42 12.56,78.82 12.56,81.19 12.87,81.5 15.26,81.5
GND on BOTTOM (solid shape): 87.27,53.56 87.27,53.31 87.12,53.16 86.7,53.16 86.43,52.9 86.43,52.18 86.33,52.07 85.59,52.07 85.54,52.12 85.54,53.42 85.82,53.7 87.13,53.7
GND on BOTTOM (solid shape): 88.77,54.76 89.25,54.76 89.4,54.62 89.4,54.31 89.22,54.13 87.1,54.13 86.94,54.3 86.94,54.59 87.14,54.78 87.45,54.78 87.85,55.17 88.36,55.17
GND on BOTTOM (solid shape): 98.32,60.27 98.32,60.06 98.2,59.94 97.98,59.94 97.69,59.65 96.97,59.65 96.73,59.9 96.4,59.9 96.29,60 96.29,60.21 96.57,60.49 98.1,60.49
GND on BOTTOM (solid shape): 107.74,131.94 107.74,129.49 107.57,129.31 103.82,129.31 103.75,129.38 103.75,131.88 104.1,132.23 107.45,132.23
GND on BOTTOM (solid shape): 122.45,99.43 122.45,94.8 122.28,94.63 119.77,94.63 119.4,95 119.4,99.02 119.9,99.52 122.36,99.52
GND on BOTTOM (solid shape): 130.64,53.8 130.64,52.73 131.25,52.12 131.25,50.47 131.05,50.27 129.84,50.27 129.69,50.42 129.69,53.85 129.74,53.9 130.53,53.9
GND on BOTTOM (solid shape): 136.64,9.64 136.64,8.87 136.25,8.48 134.53,8.48 134.39,8.62 134.39,9.71 134.48,9.8 136.47,9.8
GND on BOTTOM (solid shape): 140.11,23.11 140.11,21.39 139.87,21.15 137.31,21.15 136.89,21.57 136.89,23.01 137.1,23.23 139.99,23.23
GND on BOTTOM (solid shape): 11.77,96.58 11.77,95.88 11.77,95.88 11.77,93.85 11.46,93.54 9.39,93.54 9.12,93.82 9.12,96.6 9.47,96.96 11.39,96.96
GND on BOTTOM (solid shape): 35.8,23.77 35.8,22.04 35.15,21.39 31.36,21.39 30.84,21.9 30.84,23.01 31.23,23.4 32.64,23.4 33.11,23.86 35.72,23.86
GND on BOTTOM (solid shape): 38.98,53.75 38.98,52.61 38.8,52.44 36.98,52.44 36.98,52.44 36.88,52.54 36.88,53.59 37.02,53.72 37.6,53.72 37.93,54.05 38.68,54.05
GND on BOTTOM (solid shape): 43.72,70.65 43.72,66.6 43.57,66.45 40.46,66.45 40.25,66.66 40.25,70.62 40.56,70.93 43.44,70.93
GND on BOTTOM (solid shape): 98.39,54.66 98.39,54.43 97.91,53.95 96.86,53.95 96.49,54.32 96.19,54.32 96.05,54.45 96.05,54.65 96.17,54.77 96.65,54.77 96.73,54.85 98.2,54.85
GND on BOTTOM (solid shape): 100.77,52.68 100.77,51.86 100.66,51.75 99.44,51.75 99.29,51.9 99.29,52.2 99.4,52.31 99.85,52.31 99.96,52.42 99.96,52.62 100.1,52.77 100.69,52.77
GND on BOTTOM (solid shape): 115.95,88.08 115.95,87.06 114.69,85.8 114.69,84.28 113.92,83.51 111.49,83.51 111.25,83.75 111.25,87.99 111.47,88.22 115.81,88.22
GND on BOTTOM (solid shape): 116.11,81.05 116.11,79.85 115.64,79.37 115.64,78.4 115.54,78.3 113.86,78.3 113.76,78.4 113.76,80.32 114.67,81.23 115.93,81.23
GND on BOTTOM (solid shape): 40.58,60.07 40.58,57.13 40.47,57.02 39.57,57.02 39.45,57.14 39.45,58.75 39.24,58.96 38.95,58.96 38.7,59.2 38.7,60.09 38.87,60.25 40.39,60.25
GND on BOTTOM (solid shape): 118.05,11.95 118.05,10.99 117.38,10.31 117.38,9.15 117.07,8.85 115.4,8.85 115.3,8.95 115.3,11.35 115.96,12.01 117.99,12.01
GND on BOTTOM (solid shape): 61.88,57.72 61.88,56.49 61.86,56.48 61.3,56.48 61.17,56.61 58.57,56.61 58.17,57.02 58.17,57.72 58.33,57.88 61.72,57.88
GND on BOTTOM (solid shape): 93.65,52.84 93.65,51.56 93.48,51.4 92.94,51.4 92.8,51.54 92.8,52.3 92.69,52.41 92.27,52.41 92.13,52.55 92.13,52.86 92.25,52.98 93.51,52.98
GND on BOTTOM (solid shape): 135.19,16.77 135.19,16.37 135.34,16.22 136.26,16.22 136.87,15.61 136.87,14.96 136.75,14.84 136.43,14.84 136.15,15.12 135.41,15.12 135.04,15.49 135.04,15.86 134.52,16.38 134.52,16.83 134.53,16.85 135.11,16.85
GND on BOTTOM (solid shape): 94.1,60.46 94.62,60.46 94.77,60.31 94.77,60.11 94.58,59.92 94.25,59.92 93.87,59.54 93.25,59.54 93.14,59.65 93.14,60.3 92.8,60.64 92.52,60.64 92.19,60.32 92.19,59.95 92.05,59.81 91.37,59.81 91.27,59.91 88.85,59.91 88.63,59.69 87.83,59.69 87.58,59.93 87.2,59.93 87.05,60.08 87.05,60.3 87.19,60.43 87.48,60.43 87.73,60.69 88.55,60.69 88.79,60.45 89.65,60.45 89.76,60.56 90.39,60.56 90.53,60.42 90.96,60.42 91.84,61.3 93.26,61.3
GND on BOTTOM (solid shape): 83.24,89.48 83.28,89.46 83.3,89.43 83.3,89.35 83.59,89.35 83.63,89.33 83.66,89.3 83.68,89.26 83.68,89.21 84.25,89.21 84.29,89.22 84.44,89.22 84.59,89.07 84.59,88.85 84.71,88.67 84.72,88.64 84.72,88.53 84.71,88.49 84.69,88.48 84.47,88.25 83.89,88.25 83.81,88.33 83.81,88.45 83.71,88.56 83.17,88.56 83.11,88.62 83.11,89.15 83.1,89.24 83.07,89.31 83.06,89.34 83.07,89.37 83.09,89.4 83.1,89.44 83.15,89.48
GND on BOTTOM (solid shape): 89.19,81.98 88.79,81.98 88.79,81.94 88.2,81.94 88.02,81.75 87.93,81.73 87.82,81.65 87.75,81.54 87.74,81.51 87.71,81.38 87.74,81.25 87.78,81.16 87.78,80.4 87.65,80.26 86.83,80.26 86.76,80.32 86.76,81.08 86.9,81.31 86.85,81.58 86.84,81.59 86.84,81.76 86.98,81.76 86.98,82.33 87.12,82.48 89.19,82.48
GND on BOTTOM (solid shape): 87.69,83.91 87.74,83.89 87.75,83.84 87.75,83.82 87.72,83.58 87.84,83.37 87.88,83.3 87.85,83.22 87.78,83.16 87.69,83.06 87.65,83.07 87.64,83.09 87.19,83.26 86.93,82.85 86.93,82.84 86.91,82.8 86.87,82.78 86.34,82.78 86.34,82.71 86.32,82.67 86.28,82.65 85.99,82.65 85.95,82.67 85.94,82.7 85.94,83.37 85.94,83.39 85.96,83.41 86.05,83.56 86.05,83.75 86.07,83.84 86.15,83.88 87.2,83.88 87.23,83.91
GND on BOTTOM (solid shape): 85.19,83.88 85.23,83.86 85.24,83.82 85.25,83.64 85.33,83.5 85.35,83.39 85.26,83.32 85.23,83.32 85.23,83.3 85.22,83.27 85.18,83.25 85.1,83.25 85.09,83.25 84.64,83.12 84.67,82.65 84.68,82.6 84.54,82.44 84.47,82.34 84.45,82.22 84.45,82.06 84.47,81.96 84.52,81.86 84.52,81.8 84.47,81.76 84.45,81.76 84.31,81.62 84.29,81.61 84.26,81.6 84.06,81.6 84.06,81.6 83.95,81.6 83.91,81.61 83.9,81.65 83.9,81.77 83.87,81.89 83.8,81.99 83.24,82.56 83.22,82.58 82.81,82.58 82.77,82.62 82.77,83.1 82.78,83.13 82.82,83.15 83.73,83.15 84.15,83.56 84.8,83.56 84.83,83.61 84.83,83.67 84.86,83.74 84.94,83.78 85.04,83.81 85.13,83.86 85.14,83.88
GND on BOTTOM (solid shape): outline of 95 points within 85.27,87.72 89.32,90.23
GND on BOTTOM (solid shape): outline of 287 points within 85.95,7.01 152.59,20.19
GND on BOTTOM (solid shape): outline of 1119 points within 0.41,7.01 152.59,138.19
GND on LAY2 (solid shape): outline of 67563 points within 0.41,7.01 152.59,138.19
GND on LAY3 (solid shape): outline of 97 points within 85.95,7.01 152.59,13.2
GND on LAY3 (solid shape): outline of 478 points within 0.41,7.01 152.59,138.19
GND on LAY4 (solid shape): outline of 103 points within 85.95,7.01 152.59,18.36
GND on LAY4 (solid shape): outline of 1913 points within 0.41,7.01 152.59,138.19
GND on LAY5 (solid shape): 131.26,19.75 129.22,19.75 129.22,21.63 131.26,21.63
GND on LAY5 (solid shape): outline of 2777 points within 16.06,61.8 62.05,97.98
GND on LAY5 (solid shape): outline of 35079 points within 0.41,7.01 152.59,138.19
GND_EARTH on TOP (solid shape): 85.8,18.7 85.8,7.01 84.11,7.01 84.11,9.39 82.66,9.39 82.66,18.66 68.14,18.66 68.14,9.39 66.69,9.39 66.69,7.01 63.63,7.01 63.22,7.41 63.22,17.56 63.64,17.98 66.38,17.98 67.91,19.51 80.25,19.51 81.51,20.77 83.72,20.77
GND_EARTH on BOTTOM (solid shape): 85.8,18.73 85.8,7.01 84.11,7.01 84.11,9.39 82.66,9.39 82.66,18.66 68.14,18.66 68.14,9.39 66.69,9.39 66.69,7.01 63.99,7.01 63.99,7.01 63.11,7.88 63.11,18.32 63.37,18.58 67.09,18.58 68.03,19.52 81.16,19.52 82.34,20.69 83.83,20.69
GND_EARTH on LAY2 (solid shape): outline of 611 points within 63.12,7.01 85.8,25.62
GND_EARTH on LAY3 (solid shape): outline of 609 points within 63.12,7.01 85.8,25.55
GND_EARTH on LAY4 (solid shape): outline of 609 points within 63.12,7.01 85.8,25.6
GND_EARTH on LAY5 (solid shape): outline of 717 points within 57.2,7.01 85.75,28.79
VCC1_USB3.0 on TOP (solid shape): outline of 103 points within 132.21,75.54 139.31,80.17
VCC_USB1 on TOP (solid shape): 141.16,54.55 141.16,53.25 140.91,53.01 138.31,53.01 138.19,53.13 137.26,53.13 137.06,53.32 137.06,54.72 137.17,54.83 140.88,54.83
VCC_USB1 on BOTTOM (solid shape): 143.69,54.97 143.69,53.3 143.47,53.07 137.57,53.07 137.2,53.44 137.2,54.78 137.24,54.86 137.33,54.87 137.62,54.88 137.81,55.09 137.83,55.12 143.55,55.12
VCC_USB2 on TOP (solid shape): 39.47,23.3 40.8,23.3 41.29,22.81 41.29,21.2 41.06,20.97 38.75,20.97 37.73,21.99 35.33,21.99 35.16,22.16 34.76,22.31 34.4,22.1 34.28,21.98 34.28,20.04 34.01,19.77 32.74,19.77 32.51,19.99 32.51,22.21 34.29,23.98 38.79,23.98
VCC_USB3 on TOP (solid shape): 57.62,22.84 57.62,20 57.51,19.89 55.82,19.89 55.66,20.05 55.66,21.87 55.97,22.18 55.97,23.15 56.16,23.34 57.12,23.34
VCC_USB3 on BOTTOM (solid shape): 57.46,22.83 57.46,21.72 57.89,21.29 57.89,20.08 57.52,19.71 52.18,19.71 52.01,19.89 52.01,21.42 52.3,21.72 55.65,21.72 55.99,22.06 55.99,23.06 56.13,23.2 57.1,23.2
VDD10 on BOTTOM (solid shape): 53.88,48.6 53.88,46.2 53.7,46.03 50.71,46.03 50.49,46.24 50.49,48.44 50.83,48.77 50.84,48.77 51.02,48.95 53.53,48.95
VDD12 on BOTTOM (solid shape): 63.8,110.18 63.8,108.74 63.74,108.68 62.99,108.68 62.98,108.67 62.68,108.67 62.33,108.33 62.33,107.55 62.21,107.43 60.18,107.43 60.02,107.59 60.02,108.2 60.4,108.58 60.4,110.25 60.51,110.36 63.62,110.36
VDD33 on BOTTOM (solid shape): 68.81,48.5 68.81,46.65 68.22,46.07 68.22,45.31 68.14,45.23 67.64,45.23 67.5,45.37 65.55,45.37 64.48,46.43 62.83,46.43 62.64,46.24 62.64,45.41 62.31,45.08 62.31,44.58 62.23,44.5 61.81,44.5 61.74,44.57 61.74,45.13 61.81,45.2 61.81,46.49 61.81,46.5 61.83,46.62 61.81,46.74 61.81,46.74 61.81,47.48 62.15,47.82 66.12,47.82 66.97,48.67 68.63,48.67
+V_ADP_IN on TOP (solid shape): outline of 109 points within 101.07,11.08 118.74,18.44
+V_DC on TOP (solid shape): 126.03,102.71 126.03,92.87 125.89,92.73 123,92.73 122.83,92.9 122.83,100.84 122.96,100.97 122.96,102.74 123.02,102.8 125.94,102.8
+V_DC on TOP (solid shape): 109.85,128.58 109.85,124.82 109.39,124.37 107.3,124.37 105.08,122.14 105.08,120.49 104.02,119.43 101.7,119.43 101.66,119.47 101.66,122.4 102.73,123.47 102.73,128.84 102.88,128.99 109.44,128.99
+V_DC on TOP (solid shape): outline of 319 points within 12.2,77.48 22.68,98.53
+V_DC on TOP (solid shape): outline of 1880 points within 28.47,38.11 41.65,74.38
+V_DC on TOP (solid shape): outline of 6227 points within 53.13,20.06 141.42,65.48
+V_DC on BOTTOM (solid shape): 13.49,96.09 13.49,94.41 13.17,94.09 12.3,94.09 12.08,94.3 12.08,96.07 12.26,96.25 13.33,96.25
+V_DC on BOTTOM (solid shape): 20.33,80.26 20.33,77.05 20.76,76.63 21.53,75.86 34.23,75.86 39.88,70.21 39.88,65.9 39.44,65.47 36.77,65.47 35.14,67.1 35.14,68.41 31.84,71.7 18.33,71.7 16.26,73.77 16.26,80.01 16.75,80.5 20.09,80.5
+V_DC on BOTTOM (solid shape): outline of 314 points within 25.39,23.13 55.53,40.47
+V_DC on BOTTOM (solid shape): outline of 662 points within 103.81,58.32 150.58,128.89
+V_LED on TOP (solid shape): 11.15,28.48 11.15,27.18 10.97,27 6.52,27 5.68,26.17 5.68,23.33 6.4,22.61 6.41,22.61 6.51,22.51 11.02,22.51 12.63,20.9 12.63,17.53 11.63,16.53 11.63,16.52 9.17,16.52 8.49,17.21 8.49,18.85 9.92,20.28 9.92,21.18 9.55,21.54 5.91,21.54 4.82,22.63 4.82,26.94 6.75,28.87 10.77,28.87
+V_LED on BOTTOM (solid shape): 15.04,27.33 15.04,25.79 15.62,25.2 15.62,22.96 12.94,20.28 12.94,16.43 12.78,16.27 10.51,16.27 10.23,16.55 10.23,21.43 10.24,21.45 10.24,23.65 12.06,25.47 13.05,25.47 13.9,26.31 13.9,27.32 14.01,27.44 14.93,27.44
+VCORE on TOP (solid shape): 133.13,99.92 133.13,84.9 132.98,84.75 128.13,84.75 126.62,86.27 126.62,99.93 127.16,100.47 132.59,100.47
+VCORE on BOTTOM (solid shape): 86.14,86.23 86.14,85.54 86.25,85.42 88.01,85.42 88.13,85.54 88.16,85.55 88.37,85.66 88.47,85.86 88.49,85.9 88.75,86.16 88.77,86.18 88.8,86.18 89.22,86.18 89.22,86.18 90,86.18 90.25,85.93 90.47,85.93 90.49,85.9 90.78,85.9 90.82,85.86 90.85,85.86 91.18,85.53 91.18,85.07 90.99,84.87 90.92,84.84 90.85,84.87 90.53,84.98 90.26,84.8 89.89,84.43 88.56,84.43 88.45,84.35 88.43,84.35 88.43,84.34 88.32,84.26 88.16,84.1 85.01,84.1 84.96,84.05 84.91,84.03 84.75,83.97 84.63,83.85 84.61,83.83 83.9,83.83 83.9,85.32 84.72,85.32 84.72,85.42 85.2,85.42 85.29,85.51 85.29,86.23 85.34,86.28 86.09,86.28
+VCORE on BOTTOM (solid shape): outline of 286 points within 108.9,88.92 116.1,92.78
+VCORE on LAY4 (solid shape): 90.93,86.22 90.99,86.13 90.99,85.64 89.26,83.92 88.37,83.92 88.36,83.93 88.09,84.04 87.83,83.93 87.82,83.92 87.59,83.92 87.57,83.93 87.31,84.04 87.05,83.93 87.03,83.92 86.02,83.92 86,83.93 85.74,84.04 85.48,83.93 85.46,83.92 85.24,83.92 85.22,83.93 85.14,83.99 85.04,84.03 84.79,84.27 84.79,85.53 84.83,85.57 84.85,85.56 85.08,85.57 85.26,85.69 85.27,85.71 86.21,85.71 86.23,85.69 86.53,85.55 86.82,85.69 86.84,85.71 87,85.71 87.01,85.69 87.31,85.55 87.61,85.69 87.62,85.71 87.78,85.71 87.79,85.69 88.24,85.58 88.47,85.98 88.66,86.17 90.4,86.17 90.62,86.12 90.82,86.21
+VCORE on LAY5 (solid shape): outline of 5868 points within 84.7,73.84 133.14,94.3
+VGFX on TOP (solid shape): outline of 583 points within 76.47,108.31 94.53,133.41
+VGFX on BOTTOM (solid shape): 82.52,126.06 82.52,118.65 81.98,118.11 76.75,118.11 76.5,118.36 76.5,126.08 76.73,126.32 82.27,126.32
